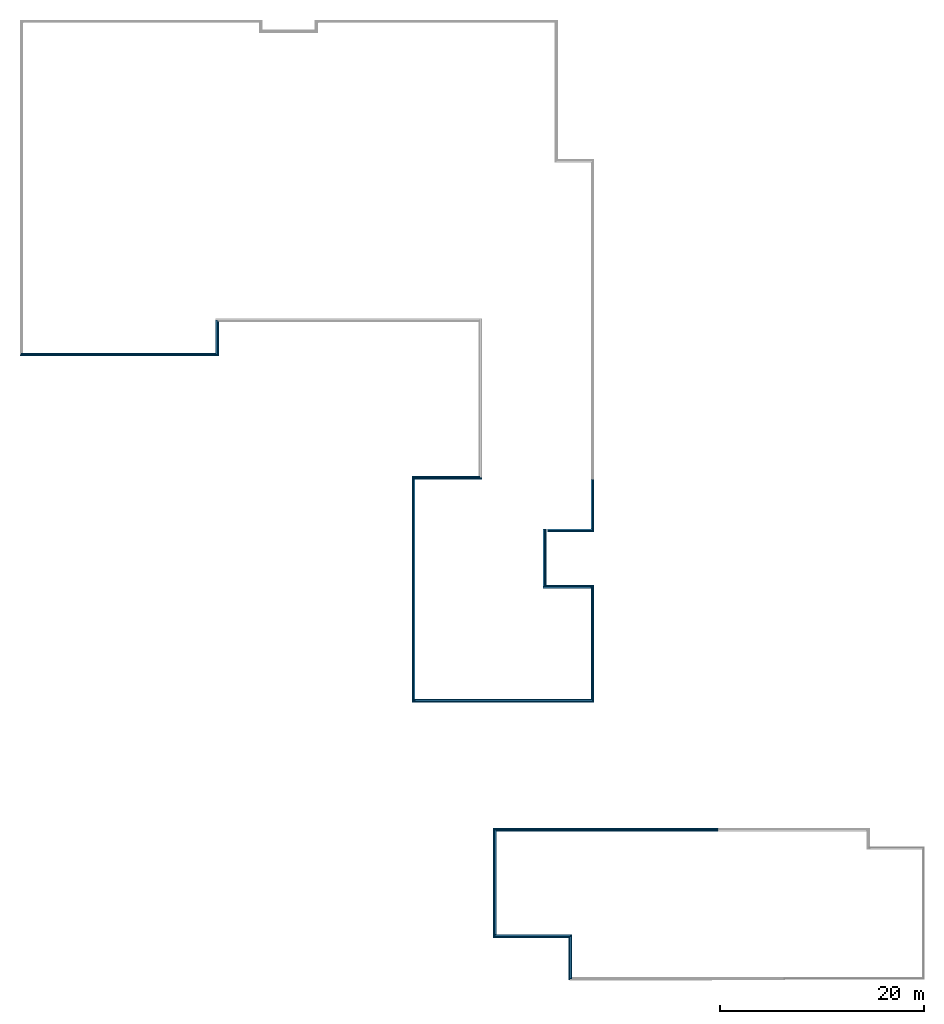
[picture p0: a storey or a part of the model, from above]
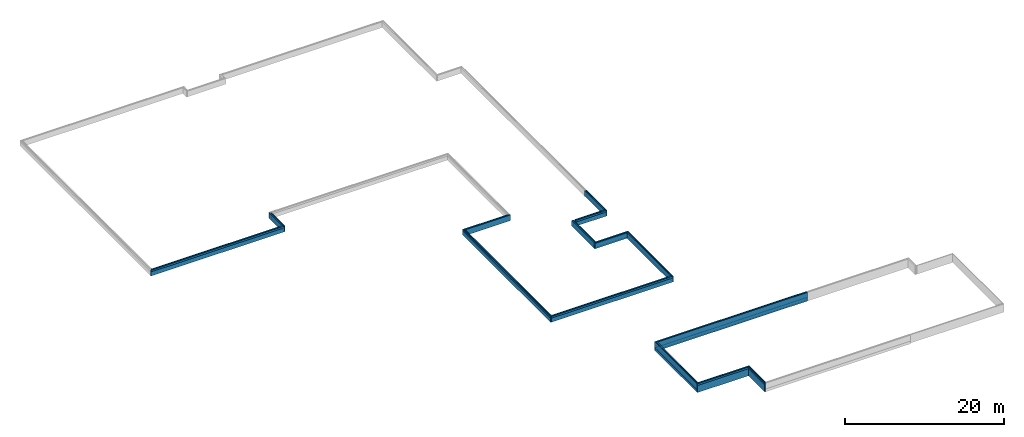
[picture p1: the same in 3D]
Properties of the parts of a building model (IFC2X3), part 1 of 19

# File
Description: ViewDefinition [1, SurfaceGeometryAddOnView, QuantityTakeOffAddOnView, SpaceBoundary2ndLevelAddOnView], Option [Elements to export: Visible elements (on all stories)], Option [Partial Structure Display: Entire Model], Option [IFC Domain: All], Option [Structural Function: All Elements], Option [Convert Grid elements: On], Option [Convert IFC Annotations and ARCHICAD 2D elements: Off], Option [Convert 2D symbols of Doors and Windows: Off], Option [Export geometries that Participates in Collision Detection only: On], Option [Split complex elements: Off], Option [Material Preservation: Explode all], Option [IFC Model position: Survey Point and Project Origin], Option [Curtain Wall export mode: Container Element], Option [Railing export mode: Container Element], Option [Stair export mode: Container Element], Option [Properties To Export: All properties], Option [Space containment: On], Option [IFC Domain For Space Containment: Custom], Option [Bounding Box: On], Option [Geometry to type objects: On], Option [Element Properties: Off], Option [Building Material Properties: On], Option [Element Parameters: Off], Option [Component Parameters: IFC Component Quantities Only], Option [IFC Base Quantities: On], Option [Door Window Parameters: On], Option [IFC Space boundaries: On], Option [ARCHICAD Zone Categories as IFC Space classification data: Off], Option [Element Classifications: On]
File name: N:\1569 unilocatie Grevenbicht Obbicht\Fases\06 Technisch Ontwerp\TO 240202\1569_IFC Bouwkunde coordinatiemodel.ifc
Time: 2024-02-02T13:21:15
Author: Architect
Organization: Naam bureau
Written by: The EXPRESS Data Manager Version 5.02.0100.09 : 26 Sep 2013
Made in: IFC file generated by GRAPHISOFT ARCHICAD 25.0.0 NED FULL Windows version (IFC add-on version: 7000 NED FULL).
Authorization: The authorising person

# IfcProject, Unilocatie Grevenbicht Obbicht
Phase: Technisch Ontwerp

# IfcSite, Site
RefLatitude: 51, 27, 0, 0; RefLongitude: 5, 29, 0, 0; RefElevation: 0 mm
BaseQuantities - GrossPerimeter: 0 mm; GrossArea: 0 m2

# IfcBuilding, Naam gebouw
BaseQuantities - GrossFloorArea: 2364.04 m2

# IfcBuildingStorey (4)
In: Naam gebouw
Name | Elevation (mm) | NetHeight (mm) = GrossHeight (mm) = Height (mm) | GrossFloorArea (m2)
Fundering | -1540 | 1540 | 0
Begane grond | 0 | 3950 | 2364.04 | LongName: Level 1
1e verdieping | 3950 | 1450 | 0
Dak | 5400 | 3750 | 0

# IfcSpace: FSA kleur 216 copy, GYM
In: Begane grond
LongName: gymzaal/ sportzaal (21x12m); InteriorOrExteriorSpace: INTERNAL
Pset_SpaceOccupancyRequirements - OccupancyNumber: 0
AC_Pset_RenovationAndPhasing - Renovation Status: Existing
BaseQuantities - Height: 10 mm; FinishCeilingHeight: 10 mm; FinishFloorHeight: 0 mm; ClearHeight: 10 mm; GrossFloorArea: 253.322 m2; NetFloorArea: 0 m2; SpaceNetFloorAreaBOMA: 0 m2; SpaceUsableFloorAreaBOMA: 0 m2; GrossCeilingArea: 253.322 m2; NetCeilingArea: 0 m2; GrossWallArea: 0.0938901 m2; NetWallArea: 0.0938901 m2; GrossPerimeter: 66160 mm; NetPerimeter: 66160 mm; GrossVolume: 2.53322 m3; NetVolume: 2.53322 m3

# IfcSpace: FSA kleur 216 copy 1 (4)
In: Begane grond
InteriorOrExteriorSpace: INTERNAL
Pset_SpaceOccupancyRequirements - OccupancyNumber: 0
AC_Pset_RenovationAndPhasing - Renovation Status: Existing
BaseQuantities - Height: 10 mm; FinishCeilingHeight: 10 mm; FinishFloorHeight: 0 mm; ClearHeight: 10 mm
Name | LongName | GrossFloorArea (m2) = GrossCeilingArea (m2) | NetFloorArea (m2) = SpaceNetFloorAreaBOMA (m2) = SpaceUsableFloorAreaBOMA (m2) = NetCeilingArea (m2) | GrossWallArea (m2) | NetWallArea (m2) | GrossPerimeter (mm) = NetPerimeter (mm) | GrossVolume (m3) | NetVolume (m3)
GYM | Opslag | 47.7841 | 0.00532919 | 50.2079 | 0.300813 | 30078 | 0.477841 | 0.477788
GYM | docentenruimte | 7.64856 | 0 | 2.5628 | 0.10498 | 11532 | 0.0764856 | 0.0764856
GYM | werkkast | 4.57527 | 0 | 2.5404 | 0.0825796 | 9291.96 | 0.0457527 | 0.0457527
GYM | mk | 1.1448 | 0 | 0.029 | 0.029 | 4872 | 0.011448 | 0.011448

# IfcSpace: FSA kleur 216 copy 2 (4)
In: Begane grond
InteriorOrExteriorSpace: INTERNAL
Pset_SpaceOccupancyRequirements - OccupancyNumber: 0
AC_Pset_RenovationAndPhasing - Renovation Status: Existing
BaseQuantities - Height: 10 mm; FinishCeilingHeight: 10 mm; FinishFloorHeight: 0 mm; ClearHeight: 10 mm
Name | LongName | GrossFloorArea (m2) = GrossCeilingArea (m2) | NetFloorArea (m2) = SpaceNetFloorAreaBOMA (m2) = SpaceUsableFloorAreaBOMA (m2) = NetCeilingArea (m2) | GrossWallArea (m2) | NetWallArea (m2) | GrossPerimeter (mm) = NetPerimeter (mm) | GrossVolume (m3) = NetVolume (m3)
GYM | wasruimte2 | 9.98851 | -1.06581e-14 | 3.3672 | 0.1203 | 14840 | 0.0998851
GYM | wasruimte1 | 9.98849 | -1.42109e-14 | 3.3672 | 0.1203 | 14840 | 0.0998849
GYM | kleedruimte1 | 27.94 | 3.55271e-15 | 7.1211 | 0.21078 | 24892 | 0.2794
GYM | kleedruimte2 | 27.9399 | 3.55271e-15 | 7.20206 | 0.291739 | 24892 | 0.279399

# IfcSpace: FSA kleur 240 copy (6)
In: Begane grond
InteriorOrExteriorSpace: INTERNAL
Pset_SpaceOccupancyRequirements - OccupancyNumber: 0
AC_Pset_RenovationAndPhasing - Renovation Status: Existing
BaseQuantities - Height: 10 mm; FinishCeilingHeight: 10 mm; FinishFloorHeight: 0 mm; ClearHeight: 10 mm
Name | LongName | GrossFloorArea (m2) = GrossCeilingArea (m2) | NetFloorArea (m2) = SpaceNetFloorAreaBOMA (m2) = SpaceUsableFloorAreaBOMA (m2) = NetCeilingArea (m2) | GrossWallArea (m2) | NetWallArea (m2) | GrossPerimeter (mm) = NetPerimeter (mm) | GrossVolume (m3) | NetVolume (m3)
BS | leerplein BB | 66.1092 | 1.37257e-07 | 25.3214 | 0.0347693 | 32793.9 | 0.661092 | 0.660986
BS | gr BB | 53.5495 | 7.10543e-15 | 46.1286 | 0.19932 | 29292 | 0.535495 | 0.535495
BS | gr BB / muzieklokaal | 52.1743 | 7.10543e-15 | 28.741 | 0.347427 | 28899.8 | 0.521743 | 0.521743
BS | berg. BB | 6.2334 | -2.66454e-15 | 2.55044 | 0.0926188 | 10295.9 | 0.062334 | 0.062334
BS | leerplein MB | 76.22 | 0 | 25.321 | 0.0344 | 34980 | 0.7622 | 0.762094
BS | gr BB | 54.112 | 0 | 51.0256 | 0.263 | 29440 | 0.54112 | 0.540933

# IfcSpace: FSA kleur 240 copy 3 (10)
In: Begane grond
InteriorOrExteriorSpace: INTERNAL
Pset_SpaceOccupancyRequirements - OccupancyNumber: 0
AC_Pset_RenovationAndPhasing - Renovation Status: Existing
BaseQuantities - Height: 10 mm; FinishCeilingHeight: 10 mm; FinishFloorHeight: 0 mm; ClearHeight: 10 mm
Name | LongName | GrossFloorArea (m2) = GrossCeilingArea (m2) | NetFloorArea (m2) = SpaceNetFloorAreaBOMA (m2) = SpaceUsableFloorAreaBOMA (m2) = NetCeilingArea (m2) | GrossWallArea (m2) | NetWallArea (m2) | GrossPerimeter (mm) = NetPerimeter (mm) | GrossVolume (m3) = NetVolume (m3)
KDV | KDV 0-4 j. | 62.8232 | -2.13163e-14 | 56.2146 | 0.312392 | 36013.9 | 0.628232
KDV | slpk. | 7.27601 | 7.27601 | 4.92543 | 0.106758 | 11659.8 | 0.0727601
KDV | slpk. | 7.26189 | 7.26189 | 2.46367 | 0.124702 | 11644.2 | 0.0726189
 | HOOFDENTREE | 9.46504 | 9.46504 | 11.4443 | 0.0218597 | 12572 | 0.0946504
GYM | entree sport | 23.552 | 0 | 27.3994 | 0.16091 | 27552 | 0.23552
BS | entree MB/BB | 8.88207 | 8.88207 | 5.89024 | 0.1195 | 12264.1 | 0.0888207
POV | gr. POV | 56.192 | 56.192 | 37.1537 | 0.321879 | 30084 | 0.56192
 | gard. KDV POV | 12.2037 | 12.2037 | 20.0998 | 0.105275 | 16203.7 | 0.122037
BS | entree natuurtuin | 5.90002 | 5.90002 | 11.5719 | 0.0611998 | 9720.01 | 0.0590002
KDV/POV | entree KDV/POV | 7.81956 | 7.81956 | 11.2726 | 0.0781996 | 11819.8 | 0.0781956

# IfcSpace: FSA kleur 240 copy 4 (2)
In: Begane grond
InteriorOrExteriorSpace: INTERNAL
Pset_SpaceOccupancyRequirements - OccupancyNumber: 0
AC_Pset_RenovationAndPhasing - Renovation Status: Existing
BaseQuantities - Height: 10 mm; FinishCeilingHeight: 10 mm; FinishFloorHeight: 0 mm; ClearHeight: 10 mm; NetFloorArea: 0 m2; SpaceNetFloorAreaBOMA: 0 m2; SpaceUsableFloorAreaBOMA: 0 m2; NetCeilingArea: 0 m2
Name | LongName | GrossFloorArea (m2) = GrossCeilingArea (m2) | GrossWallArea (m2) | NetWallArea (m2) | GrossPerimeter (mm) = NetPerimeter (mm) | GrossVolume (m3) = NetVolume (m3)
KDV/ POV | san. 0-4 j. POV | 9.64662 | 5.15866 | 0.24302 | 14240 | 0.0964662
KDV/ POV | Keuken | 6.68697 | 3.17908 | 0.0468596 | 11343.5 | 0.0668697

# IfcSpace: FSA kleur 240 copy copy 1 (8)
In: Begane grond
InteriorOrExteriorSpace: INTERNAL
Pset_SpaceOccupancyRequirements - OccupancyNumber: 0
AC_Pset_RenovationAndPhasing - Renovation Status: Existing
BaseQuantities - Height: 10 mm; FinishCeilingHeight: 10 mm; FinishFloorHeight: 0 mm; ClearHeight: 10 mm
Name | LongName | GrossFloorArea (m2) = GrossCeilingArea (m2) | NetFloorArea (m2) = SpaceNetFloorAreaBOMA (m2) = SpaceUsableFloorAreaBOMA (m2) = NetCeilingArea (m2) | GrossWallArea (m2) | NetWallArea (m2) | GrossPerimeter (mm) = NetPerimeter (mm) | GrossVolume (m3) | NetVolume (m3)
BS | gr MB | 54.3399 | 0 | 34.529 | 0.326739 | 29500 | 0.543399 | 0.543211
BS | gr MB | 53.8677 | 0 | 39.7121 | 0.24157 | 29374 | 0.538677 | 0.538677
BS | gr MB | 53.676 | 0 | 46.8443 | 0.21076 | 29320 | 0.53676 | 0.53676
BS | berg MB | 6.02453 | 3.55271e-15 | 2.54652 | 0.0917529 | 10208 | 0.0602453 | 0.0602453
BS | san .MB | 4.8796 | 1.77636e-15 | 9.84183 | 0.07236 | 11072 | 0.048796 | 0.048796
BS | san .OB | 9.40794 | 0 | 2.61349 | 0.15567 | 12320 | 0.0940794 | 0.0940794
BS | gr MB | 52.9304 | 0 | 50.7949 | 0.25835 | 29110 | 0.529304 | 0.529117
BS | san .BB | 3.64595 | 1.77636e-15 | 7.46385 | 0.090395 | 8829 | 0.0364595 | 0.0364595

# IfcSpace: FSA kleur 240 copy copy copy 1 (5)
In: Begane grond
InteriorOrExteriorSpace: INTERNAL
Pset_SpaceOccupancyRequirements - OccupancyNumber: 0
AC_Pset_RenovationAndPhasing - Renovation Status: Existing
BaseQuantities - Height: 10 mm; FinishCeilingHeight: 10 mm; FinishFloorHeight: 0 mm; ClearHeight: 10 mm
Name | LongName | GrossFloorArea (m2) = GrossCeilingArea (m2) | NetFloorArea (m2) = SpaceNetFloorAreaBOMA (m2) = SpaceUsableFloorAreaBOMA (m2) = NetCeilingArea (m2) | GrossWallArea (m2) | NetWallArea (m2) | GrossPerimeter (mm) = NetPerimeter (mm) | GrossVolume (m3) | NetVolume (m3)
BS | gr. OB | 53.676 | 1.42109e-14 | 46.8443 | 0.21076 | 29320 | 0.53676 | 0.53676
BS | leerplein OB | 59.6838 | 0 | 20.4697 | 0.14421 | 35657.7 | 0.596838 | 0.596838
KC | speellokaal | 82.4028 | 82.4028 | 46.829 | 0.23935 | 36352.7 | 0.824028 | 0.824028
BS | gr. OB | 53.7255 | 0.015 | 39.6021 | 0.159009 | 29333.9 | 0.537255 | 0.537105
BS | gr. OB | 54.0099 | 0.0213435 | 17.4038 | 0.16267 | 29414.1 | 0.540099 | 0.539912

# IfcSpace: FSA kleur 240 copy copy copy 2 (2)
In: Begane grond
InteriorOrExteriorSpace: INTERNAL
Pset_SpaceOccupancyRequirements - OccupancyNumber: 0
AC_Pset_RenovationAndPhasing - Renovation Status: Existing
BaseQuantities - Height: 10 mm; FinishCeilingHeight: 10 mm; FinishFloorHeight: 0 mm; ClearHeight: 10 mm
Name | LongName | GrossFloorArea (m2) = GrossCeilingArea (m2) | NetFloorArea (m2) = SpaceNetFloorAreaBOMA (m2) = SpaceUsableFloorAreaBOMA (m2) = NetCeilingArea (m2) | GrossWallArea (m2) | NetWallArea (m2) | GrossPerimeter (mm) = NetPerimeter (mm) | GrossVolume (m3) = NetVolume (m3)
BS | berg OB | 7.08185 | -8.88178e-16 | 0.0754999 | 0.0754999 | 11030 | 0.0708185
KC | berg. speellokaal | 6.44126 | 0 | 4.36741 | 0.0888086 | 10680.9 | 0.0644126

# IfcSpace: FSA kleur 241 1 (9)
In: Begane grond
InteriorOrExteriorSpace: INTERNAL
Pset_SpaceOccupancyRequirements - OccupancyNumber: 0
AC_Pset_RenovationAndPhasing - Renovation Status: Existing
BaseQuantities - Height: 10 mm; FinishCeilingHeight: 10 mm; FinishFloorHeight: 0 mm; ClearHeight: 10 mm
Name | LongName | GrossFloorArea (m2) = GrossCeilingArea (m2) | NetFloorArea (m2) = SpaceNetFloorAreaBOMA (m2) = SpaceUsableFloorAreaBOMA (m2) = NetCeilingArea (m2) | GrossWallArea (m2) | NetWallArea (m2) | GrossPerimeter (mm) = NetPerimeter (mm) | GrossVolume (m3) | NetVolume (m3)
BSO | bu. berg. BSO | 6.00501 | 6.00501 | 1.40073 | 0.0599914 | 10744.3 | 0.0600501 | 0.0599566
KC | gard. BB | 16.7919 | 0.019375 | 18.7048 | 0.0857401 | 18208.1 | 0.167919 | 0.167775
KC | werkkast | 5.99267 | -8.88178e-16 | 4.36168 | 0.0830807 | 10108.1 | 0.0599267 | 0.0599267
BS | berg alg./ kluis | 12.6841 | 1.35146e-08 | 2.55033 | 0.0925132 | 14389.4 | 0.126841 | 0.126841
BSO | berg. BSO | 12.7812 | 3.55271e-15 | 4.36393 | 0.0853263 | 14436.7 | 0.127812 | 0.127812
BS | bu. berg. OW | 11.352 | 11.352 | 4.91699 | 0.0647348 | 14308 | 0.11352 | 0.11352
KC | gard. OB | 11.266 | -1.77636e-15 | 19.9232 | 0.0700697 | 13840 | 0.11266 | 0.11266
POV | berg. POV KDV | 13.6076 | 13.6076 | 2.64332 | 0.185498 | 16083.7 | 0.136076 | 0.136076
KC | gard. MB | 16.6869 | 0 | 9.31184 | 0.124681 | 17978.1 | 0.166869 | 0.166869

# IfcSpace: FSA kleur 241 2 (7)
In: Begane grond
InteriorOrExteriorSpace: INTERNAL
Pset_SpaceOccupancyRequirements - OccupancyNumber: 0
AC_Pset_RenovationAndPhasing - Renovation Status: Existing
BaseQuantities - Height: 10 mm; FinishCeilingHeight: 10 mm; FinishFloorHeight: 0 mm; ClearHeight: 10 mm
Name | LongName | GrossFloorArea (m2) = GrossCeilingArea (m2) | NetFloorArea (m2) = SpaceNetFloorAreaBOMA (m2) = SpaceUsableFloorAreaBOMA (m2) = NetCeilingArea (m2) | GrossWallArea (m2) | NetWallArea (m2) | GrossPerimeter (mm) = NetPerimeter (mm) | GrossVolume (m3) = NetVolume (m3)
KC | keuken | 26.1607 | 26.1607 | 9.40792 | 0.0479151 | 20940.7 | 0.261607
KC | toilet pers. | 13.3664 | 0 | 7.49121 | 0.117761 | 14678.1 | 0.133664
KC | wasruimte | 5.41291 | 0 | 2.56182 | 0.104001 | 9680.03 | 0.0541291
KC | MIVA /douche | 4.9952 | -3.40931e-08 | 2.53688 | 0.07906 | 8940 | 0.049952
KC | techniek | 19.7063 | 0.251596 | 11.8197 | 0.271949 | 17760 | 0.197063
KC | techniek | 3.49895 | 4.44089e-16 | 2.52346 | 0.0656407 | 7598.07 | 0.0349895
KC | toilet pers.KDV | 9.04179 | 0 | 5.04732 | 0.131688 | 12031.9 | 0.0904179

# IfcSpace: FSA kleur 241 4 (8)
In: Begane grond
InteriorOrExteriorSpace: INTERNAL
Pset_SpaceOccupancyRequirements - OccupancyNumber: 0
AC_Pset_RenovationAndPhasing - Renovation Status: Existing
BaseQuantities - Height: 10 mm; FinishCeilingHeight: 10 mm; FinishFloorHeight: 0 mm; ClearHeight: 10 mm
Name | LongName | GrossFloorArea (m2) = GrossCeilingArea (m2) | NetFloorArea (m2) = SpaceNetFloorAreaBOMA (m2) = SpaceUsableFloorAreaBOMA (m2) = NetCeilingArea (m2) | GrossWallArea (m2) | NetWallArea (m2) | GrossPerimeter (mm) = NetPerimeter (mm) | GrossVolume (m3) | NetVolume (m3)
BS | admin. /conc. | 17.326 | 17.381 | 4.28157 | 0.13092 | 18140.7 | 0.17326 | 0.173041
KC | teamkamer flex / BSO-ruimte | 34.7074 | 34.7074 | 14.817 | 0 | 24381.7 | 0.347074 | 0.347074
BS | Cova ruimte | 13.1208 | 13.1208 | 6.77545 | 0.166981 | 14628.1 | 0.131208 | 0.131208
BS | flexwp/ spreekr. | 12.76 | 12.76 | 14.544 | 0.1588 | 14600 | 0.1276 | 0.1276
BS | flexwp/ spreekr. | 12.4705 | 3.55271e-15 | 14.7753 | 0.113263 | 14244.2 | 0.124705 | 0.124705
BS | flexwp/ spreekr. | 14.3519 | 0 | 10.5277 | 0.11558 | 15568 | 0.143519 | 0.143519
BS | Directie IB | 17.4156 | 0 | 9.42975 | 0.19232 | 16772 | 0.174156 | 0.174156
KC | teamkamer vast | 31.2026 | -3.55271e-15 | 9.50511 | 0.26768 | 24072.4 | 0.312026 | 0.312026

# IfcSpace: FSA kleur 246 copy (10)
In: Begane grond
InteriorOrExteriorSpace: INTERNAL
Pset_SpaceOccupancyRequirements - OccupancyNumber: 0
AC_Pset_RenovationAndPhasing - Renovation Status: Existing
BaseQuantities - Height: 10 mm; FinishCeilingHeight: 10 mm; FinishFloorHeight: 0 mm; ClearHeight: 10 mm
Name | LongName | GrossFloorArea (m2) = GrossCeilingArea (m2) | NetFloorArea (m2) = SpaceNetFloorAreaBOMA (m2) = SpaceUsableFloorAreaBOMA (m2) = NetCeilingArea (m2) | GrossWallArea (m2) | NetWallArea (m2) | GrossPerimeter (mm) = NetPerimeter (mm) | GrossVolume (m3) | NetVolume (m3)
SPORT | d. 4x. | 4.64063 | 0 | 0.09675 | 0.09675 | 8700 | 0.0464063 | 0.0464063
SPORT | kleedr. groot 1 | 27.6754 | -3.55271e-15 | 12.713 | 0.207997 | 21700.2 | 0.276754 | 0.276754
SPORT | d. 5x. | 8.21264 | 0 | 7.66509 | 0.131598 | 11589.9 | 0.0821264 | 0.0821264
SPORT | d. 5x. | 8.21274 | 0 | 0.0821996 | 0.0821996 | 11590 | 0.0821274 | 0.0821274
SPORT | opslag voetbal+ballenhok | 32.385 | 0 | 1.58579 | 0.0509817 | 22900 | 0.32385 | 0.32385
SPORT | kleedr. klein 1 | 19.695 | 0.0074095 | 2.69714 | 0.23932 | 17900 | 0.19695 | 0.196856
SPORT | d. 4x. | 4.64063 | 0 | 0.078 | 0.078 | 8700 | 0.0464063 | 0.0464063
SPORT | kleedr. klein 2 | 19.695 | 0 | 2.70698 | 0.24916 | 17900 | 0.19695 | 0.19695
SPORT | kleedr. groot 2 | 27.675 | -3.55271e-15 | 15.2321 | 0.26932 | 21700 | 0.27675 | 0.27675
SPORT | gangzone | 51.1795 | 0 | 18.4763 | 0.129363 | 57490 | 0.511795 | 0.511795

# IfcSpace: FSA kleur 246 copy 1 (3)
In: Begane grond
InteriorOrExteriorSpace: INTERNAL
Pset_SpaceOccupancyRequirements - OccupancyNumber: 0
AC_Pset_RenovationAndPhasing - Renovation Status: Existing
BaseQuantities - Height: 10 mm; FinishCeilingHeight: 10 mm; FinishFloorHeight: 0 mm; ClearHeight: 10 mm; NetFloorArea: 0 m2; SpaceNetFloorAreaBOMA: 0 m2; SpaceUsableFloorAreaBOMA: 0 m2; NetCeilingArea: 0 m2
Name | LongName | GrossFloorArea (m2) = GrossCeilingArea (m2) | GrossWallArea (m2) = NetWallArea (m2) | GrossPerimeter (mm) = NetPerimeter (mm) | GrossVolume (m3) = NetVolume (m3)
SPORT | kleedr. Tennis | 12.9677 | 0.078 | 14450.1 | 0.129677
SPORT | opslag tennis- | 17.63 | 0.0839985 | 16800 | 0.1763
SPORT | kleedr. Tennis | 12.9675 | 0.001 | 14450 | 0.129675

# IfcSpace: FSA kleur 246 copy 2 (8)
In: Begane grond
InteriorOrExteriorSpace: INTERNAL
Pset_SpaceOccupancyRequirements - OccupancyNumber: 0
AC_Pset_RenovationAndPhasing - Renovation Status: Existing
BaseQuantities - Height: 10 mm; FinishCeilingHeight: 10 mm; FinishFloorHeight: 0 mm; ClearHeight: 10 mm
Name | LongName | GrossFloorArea (m2) = GrossCeilingArea (m2) | NetFloorArea (m2) = SpaceNetFloorAreaBOMA (m2) = SpaceUsableFloorAreaBOMA (m2) = NetCeilingArea (m2) | GrossWallArea (m2) | NetWallArea (m2) | GrossPerimeter (mm) = NetPerimeter (mm) | GrossVolume (m3) | NetVolume (m3)
SPORT | t. | 1.99675 | 0 | 2.38698 | 0.0480099 | 5709.99 | 0.0199675 | 0.0199675
SPORT | t. | 1.99675 | 0.00851728 | 2.37068 | 0.03171 | 5709.99 | 0.0199675 | 0.019874
SPORT | massage /EHBO ruimte | 16.2684 | 0 | 2.48038 | 0.0225594 | 16579.7 | 0.162684 | 0.162684
KANT | san. heren | 4.845 | -4.44089e-15 | 0.071 | 0.071 | 8900.01 | 0.04845 | 0.04845
SPORT | wasruimte | 8.15977 | 0 | 4.97886 | 0.0989986 | 13399.9 | 0.0815977 | 0.0815977
SPORT | klr. scheids | 11.0672 | -2.66454e-14 | 0.0519995 | 0.0519995 | 14540.1 | 0.110672 | 0.110672
KANT | san. Dames | 4.845 | -1.42109e-14 | 0.071 | 0.071 | 8900 | 0.04845 | 0.04845
SPORT | klr. scheids | 11.067 | -1.95399e-14 | 0.101999 | 0.101999 | 14540 | 0.11067 | 0.11067

# IfcSpace: FSA kleur 248 copy (2)
In: Begane grond
InteriorOrExteriorSpace: INTERNAL
Pset_SpaceOccupancyRequirements - OccupancyNumber: 0
AC_Pset_RenovationAndPhasing - Renovation Status: Existing
BaseQuantities - Height: 10 mm; FinishCeilingHeight: 10 mm; FinishFloorHeight: 0 mm; ClearHeight: 10 mm
Name | LongName | GrossFloorArea (m2) = GrossCeilingArea (m2) | NetFloorArea (m2) = SpaceNetFloorAreaBOMA (m2) = SpaceUsableFloorAreaBOMA (m2) = NetCeilingArea (m2) | GrossWallArea (m2) | NetWallArea (m2) | GrossPerimeter (mm) = NetPerimeter (mm) | GrossVolume (m3) | NetVolume (m3)
KANT | kantine + bar 10m | 124.373 | 0.01434 | 6.23838 | 0.0534995 | 54300 | 1.24373 | 1.24357
SPORT | entree tennis | 11.8125 | 0 | 12.3806 | 0.0154795 | 17000 | 0.118125 | 0.118125

# IfcSpace: FSA kleur 248 copy 1 (4)
In: Begane grond
InteriorOrExteriorSpace: INTERNAL
Pset_SpaceOccupancyRequirements - OccupancyNumber: 0
AC_Pset_RenovationAndPhasing - Renovation Status: Existing
BaseQuantities - Height: 10 mm; FinishCeilingHeight: 10 mm; FinishFloorHeight: 0 mm; ClearHeight: 10 mm
Name | LongName | GrossFloorArea (m2) = GrossCeilingArea (m2) | NetFloorArea (m2) = SpaceNetFloorAreaBOMA (m2) = SpaceUsableFloorAreaBOMA (m2) = NetCeilingArea (m2) | GrossWallArea (m2) | NetWallArea (m2) | GrossPerimeter (mm) = NetPerimeter (mm) | GrossVolume (m3) = NetVolume (m3)
KANT | mag./ k + v | 9.49004 | 0 | 8.37748 | 0.10066 | 12500 | 0.0949004
KANT | werkkast | 4.68307 | -5.32907e-15 | 2.51308 | 0.0552589 | 8660.07 | 0.0468307
KANT | techniek | 13.5028 | 1.59872e-14 | 2.63501 | 0.177188 | 15459.9 | 0.135028
KANT | keuken | 14.7823 | 0 | 2.52448 | 0.0666593 | 15399.9 | 0.147823

# IfcSpace: FSA kleur 248 copy 2 (3)
In: Begane grond
InteriorOrExteriorSpace: INTERNAL
Pset_SpaceOccupancyRequirements - OccupancyNumber: 0
AC_Pset_RenovationAndPhasing - Renovation Status: Existing
BaseQuantities - Height: 10 mm; FinishCeilingHeight: 10 mm; FinishFloorHeight: 0 mm; ClearHeight: 10 mm
Name | LongName | GrossFloorArea (m2) = GrossCeilingArea (m2) | NetFloorArea (m2) = SpaceNetFloorAreaBOMA (m2) = SpaceUsableFloorAreaBOMA (m2) = NetCeilingArea (m2) | GrossWallArea (m2) | NetWallArea (m2) | GrossPerimeter (mm) = NetPerimeter (mm) | GrossVolume (m3) = NetVolume (m3)
KANT | MIVA | 5.35914 | 0 | 2.55274 | 0.094921 | 9260.12 | 0.0535914
SPORT | san.alg. | 12.24 | 0 | 7.473 | 0.153 | 15000 | 0.1224
SPORT | san.alg. | 11.0571 | 1.95399e-14 | 6.70885 | 0.0963606 | 14536.2 | 0.110571

# IfcBeam: 1000*250 (3)
In: Begane grond
Description: 1000*250; Classification: Balk (ARCHICAD Classification); Material: CONCRETE/C30/37
Default - Stortmethode: Insitu; NL-SfB_DESCRIPTION: Balkenfundering insitu; NL-SfB_NUMBERCODE: 16.12.41; IS_EXTERNAL: Nee; LOAD_BEARING: Ondersteuning; FIRE_RATING: R0; IFC_CLASS_REF_CODE: 16.12.41 ; Balkenfundering insitu; IFC_BUILDING_STOREY: Undefined; IFC_BUILDING: Undefined; MATERIAL: C30/37; NAME: FUNDERINGSBALK
Tekla Common - Phase: 1; Class: 3
Tekla Quantity - Weight: 600 kg; Volume: 0.25 m3; Gross footprint area: 1 m2; Area per tons: 5 m2; Net surface area: 3 m2; Height: 250 mm; Width: 1000 mm; Length: 1000 mm
Pset_BeamCommon - FireRating: R0; Reference: B0(?); Slope: 0 deg; LoadBearing: yes; IsExternal: no
CPset_Phasing - Renovation Phase: Bestaand
AC_Pset_RenovationAndPhasing - Renovation Status: Existing
Material Properties - CONCRETE/C30/37, ThermalConductivity: 2.3; CONCRETE/C30/37, SpecificHeatCapacity: 1000 J/kg/K; CONCRETE/C30/37, MassDensity: 2300 kg/m3; CONCRETE/C30/37, Embodied Energy: 1.92 (MJ/kg); CONCRETE/C30/37, Embodied Carbon: 0.198 (kgCO₂/kg); CONCRETE/C30/37, Name: CONCRETE/C30/37; CONCRETE/C30/37, Participates in Collision Detection: yes
BaseQuantities - NetSurfaceAreaExtrudedSides: 2.5 m2; Length: 1000 mm; Width: 1000 mm; Depth: 250 mm; CrossSectionArea: 0.25 m2; OuterSurfaceArea: 2.5 m2; TotalSurfaceArea: 3 m2; GrossSurfaceArea: 3 m2; GrossVolume: 0.25 m3; NetSurfaceArea: 3 m2; NetVolume: 0.25 m3
Component Quantities - CONCRETE/C30/37, Mass: 575 kg; CONCRETE/C30/37, Projected Component Area (Net): 0.25 m2; CONCRETE/C30/37, Projected Component Area (Gross): 0.25 m2; CONCRETE/C30/37, Component Thickness: 1000 mm; CONCRETE/C30/37, Rectangular Component Height: 250 mm; CONCRETE/C30/37, Rectangular Component Width: 1000 mm; CONCRETE/C30/37, Component Cross Section Area: 0.25 m2; CONCRETE/C30/37, Component Volume (Net): 0.25 m3; CONCRETE/C30/37, Component Volume (Gross): 0.25 m3
Name | Bottom elevation | Top elevation
2 x FUNDERINGSBALK | -0.900 | -0.650
FUNDERINGSBALK | -0.990 | -0.740

# IfcBeam: 1000*500 (3)
In: Begane grond
Description: 1000*500; Classification: Balk (ARCHICAD Classification); Material: CONCRETE/C30/37
Default - Stortmethode: Insitu; NL-SfB_DESCRIPTION: Balkenfundering insitu; NL-SfB_NUMBERCODE: 16.12.41; IS_EXTERNAL: Nee; LOAD_BEARING: Ondersteuning; FIRE_RATING: R0; IFC_CLASS_REF_CODE: 16.12.41 ; Balkenfundering insitu; IFC_BUILDING_STOREY: Undefined; IFC_BUILDING: Undefined; MATERIAL: C30/37; NAME: FUNDERINGSBALK
Pset_BeamCommon - FireRating: R0; Reference: B0(?); Slope: 0 deg; LoadBearing: yes; IsExternal: no
Tekla Common - Bottom elevation: -0.900; Top elevation: -0.400; Phase: 1; Class: 3
Tekla Quantity - Weight: 2400 kg; Volume: 1 m3; Gross footprint area: 2 m2; Area per tons: 2.917 m2; Net surface area: 7 m2; Height: 500 mm; Width: 1000 mm; Length: 2000 mm
CPset_Phasing - Renovation Phase: Bestaand
AC_Pset_RenovationAndPhasing - Renovation Status: Existing
Material Properties - CONCRETE/C30/37, ThermalConductivity: 2.3; CONCRETE/C30/37, SpecificHeatCapacity: 1000 J/kg/K; CONCRETE/C30/37, MassDensity: 2300 kg/m3; CONCRETE/C30/37, Embodied Energy: 1.92 (MJ/kg); CONCRETE/C30/37, Embodied Carbon: 0.198 (kgCO₂/kg); CONCRETE/C30/37, Name: CONCRETE/C30/37; CONCRETE/C30/37, Participates in Collision Detection: yes
BaseQuantities - NetSurfaceAreaExtrudedSides: 6 m2; Length: 2000 mm; Width: 1000 mm; Depth: 500 mm; CrossSectionArea: 0.5 m2; OuterSurfaceArea: 6 m2; TotalSurfaceArea: 7 m2; GrossSurfaceArea: 7 m2; GrossVolume: 1 m3; NetSurfaceArea: 7 m2; NetVolume: 1 m3
Component Quantities - CONCRETE/C30/37, Mass: 2300 kg; CONCRETE/C30/37, Projected Component Area (Net): 1 m2; CONCRETE/C30/37, Projected Component Area (Gross): 1 m2; CONCRETE/C30/37, Component Thickness: 1000 mm; CONCRETE/C30/37, Rectangular Component Height: 500 mm; CONCRETE/C30/37, Rectangular Component Width: 1000 mm; CONCRETE/C30/37, Component Cross Section Area: 0.5 m2; CONCRETE/C30/37, Component Volume (Net): 1 m3; CONCRETE/C30/37, Component Volume (Gross): 1 m3

# IfcBeam: 1200*160 (3)
In: Begane grond
Description: 1200*160; Classification: Balk (ARCHICAD Classification); Material: TIMBER/C24
Pset_BeamCommon - FireRating: R30; Reference: LIH0(?); Slope: 0 deg; LoadBearing: yes; IsExternal: no
Default - NL-SfB_DESCRIPTION: Kolom-/Liggerconstructie hout; NL-SfB_NUMBERCODE: 28.11.11; IS_EXTERNAL: Nee; LOAD_BEARING: Ondersteuning; FIRE_RATING: R30; IFC_CLASS_REF_CODE: 28.11.11 ; Kolom-/Liggerconstructie hout; IFC_BUILDING_STOREY: Undefined; IFC_BUILDING: Undefined; MATERIAL: C24; NAME: LIGGER
Tekla Common - Bottom elevation: +5.500; Top elevation: +6.700; Phase: 1; Class: 13
Tekla Quantity - Height: 160 mm; Width: 1200 mm
CPset_Phasing - Renovation Phase: Bestaand
AC_Pset_RenovationAndPhasing - Renovation Status: Existing
Material Properties - TIMBER/C24, ThermalConductivity: 2.3; TIMBER/C24, SpecificHeatCapacity: 1000 J/kg/K; TIMBER/C24, MassDensity: 2300 kg/m3; TIMBER/C24, Embodied Energy: 1.92 (MJ/kg); TIMBER/C24, Embodied Carbon: 0.198 (kgCO₂/kg); TIMBER/C24, Name: TIMBER/C24; TIMBER/C24, Participates in Collision Detection: yes
BaseQuantities - Width: 160 mm; Depth: 1200 mm; CrossSectionArea: 0.192 m2
Component Quantities - TIMBER/C24, Component Thickness: 160 mm; TIMBER/C24, Rectangular Component Height: 1200 mm; TIMBER/C24, Rectangular Component Width: 160 mm; TIMBER/C24, Component Cross Section Area: 0.192 m2
Name | Weight (kg) | Volume (m3) | Gross footprint area (m2) | Area per tons (m2) | Net surface area (m2) | Tekla Quantity, Length (mm) = BaseQuantities, Length (mm) | NetSurfaceAreaExtrudedSides (m2) = OuterSurfaceArea (m2) | TotalSurfaceArea (m2) = GrossSurfaceArea (m2) = NetSurfaceArea (m2) | GrossVolume (m3) | NetVolume (m3) = TIMBER/C24, Component Volume (Net) (m3) | TIMBER/C24, Mass (kg) | TIMBER/C24, Projected Component Area (Net) (m2) = TIMBER/C24, Projected Component Area (Gross) (m2) | TIMBER/C24, Component Volume (Gross) (m3)
LIGGER | 1039.61 | 2.31 | 1.925 | 32.63 | 33.922 | 12070 | 32.8184 | 33.2024 | 2.31744 | 2.31024 | 5313.56 | 14.484 | 2.31744
LIGGER | 1044.58 | 2.321 | 1.934 | 31.849 | 33.269 | 12090 | 32.8846 | 33.2686 | 2.32128 | 2.32128 | 5338.95 | 14.508 | 2.32128
LIGGER | 1044.58 | 2.321 | 1.934 | 31.849 | 33.269 | 12090 | 32.884 | 33.268 | 2.32128 | 2.32127 | 5338.92 | 14.508 | 2.32127

# IfcBeam: 1200*300 (33)
In: Begane grond
Description: 1200*300; Classification: Balk (ARCHICAD Classification); Material: CONCRETE/C30/37
Default - Stortmethode: Insitu; NL-SfB_DESCRIPTION: Balkenfundering insitu; NL-SfB_NUMBERCODE: 16.12.41; IS_EXTERNAL: Nee; LOAD_BEARING: Nee; FIRE_RATING: R0; IFC_CLASS_REF_CODE: 16.12.41 ; Balkenfundering insitu; IFC_BUILDING_STOREY: Undefined; IFC_BUILDING: Undefined; MATERIAL: C30/37; NAME: FUNDERINGSBALK
Tekla Common - Phase: 1; Class: 3
Pset_BeamCommon - FireRating: R0; Reference: B0(?); Slope: 0 deg; LoadBearing: no; IsExternal: no
Tekla Quantity - Height: 300 mm; Width: 1200 mm
CPset_Phasing - Renovation Phase: Bestaand
AC_Pset_RenovationAndPhasing - Renovation Status: Existing
Material Properties - CONCRETE/C30/37, ThermalConductivity: 2.3; CONCRETE/C30/37, SpecificHeatCapacity: 1000 J/kg/K; CONCRETE/C30/37, MassDensity: 2300 kg/m3; CONCRETE/C30/37, Embodied Energy: 1.92 (MJ/kg); CONCRETE/C30/37, Embodied Carbon: 0.198 (kgCO₂/kg); CONCRETE/C30/37, Name: CONCRETE/C30/37; CONCRETE/C30/37, Participates in Collision Detection: yes
BaseQuantities - Width: 1200 mm; Depth: 300 mm; CrossSectionArea: 0.36 m2
Component Quantities - CONCRETE/C30/37, Component Thickness: 1200 mm; CONCRETE/C30/37, Rectangular Component Height: 300 mm; CONCRETE/C30/37, Rectangular Component Width: 1200 mm; CONCRETE/C30/37, Component Cross Section Area: 0.36 m2
Name | Bottom elevation | Top elevation | Weight (kg) | Volume (m3) | Gross footprint area (m2) | Area per tons (m2) | Net surface area (m2) | Tekla Quantity, Length (mm) | NetSurfaceAreaExtrudedSides (m2) = OuterSurfaceArea (m2) | BaseQuantities, Length (mm) | TotalSurfaceArea (m2) = GrossSurfaceArea (m2) = NetSurfaceArea (m2) | GrossVolume (m3) | NetVolume (m3) = CONCRETE/C30/37, Component Volume (Net) (m3) = CONCRETE/C30/37, Component Volume (Gross) (m3) | CONCRETE/C30/37, Mass (kg) | CONCRETE/C30/37, Projected Component Area (Net) (m2) = CONCRETE/C30/37, Projected Component Area (Gross) (m2)
FUNDERINGSBALK | -1.240 | -0.940 | 6831.64 | 2.847 | 9.488 | 3.578 | 24.441 | 7907 | 23.721 | 7906.99 | 24.441 | 2.84652 | 2.84652 | 6546.99 | 2.3721
FUNDERINGSBALK | -0.800 | -0.500 | 29548.8 | 12.312 | 41.04 | 3.497 | 103.32 | 34200 | 102.6 | 34200 | 103.32 | 12.312 | 12.312 | 28317.6 | 10.26
FUNDERINGSBALK | -0.800 | -0.500 | 31147.2 | 12.978 | 43.26 | 3.495 | 108.87 | 36050 | 108.15 | 36050 | 108.87 | 12.978 | 12.978 | 29849.4 | 10.815
FUNDERINGSBALK | -0.800 | -0.500 | 4795.22 | 1.998 | 6.66 | 3.622 | 17.37 | 5550 | 16.65 | 5550 | 17.37 | 1.998 | 1.998 | 4595.4 | 1.665
FUNDERINGSBALK | -0.800 | -0.500 | 8661.6 | 3.609 | 12.03 | 3.555 | 30.795 | 10025 | 30.075 | 10025 | 30.795 | 3.609 | 3.609 | 8300.7 | 3.0075
FUNDERINGSBALK | -1.240 | -0.940 | 8255.52 | 3.44 | 11.466 | 3.559 | 29.385 | 9555 | 27.1218 | 9555 | 27.8418 | 3.4398 | 3.26232 | 7503.34 | 2.8665
FUNDERINGSBALK | -0.800 | -0.500 | 11707.2 | 4.878 | 16.26 | 3.534 | 41.37 | 13550 | 40.65 | 13550 | 41.37 | 4.878 | 4.878 | 11219.4 | 4.065
FUNDERINGSBALK | -0.800 | -0.500 | 6393.6 | 2.664 | 8.88 | 3.585 | 22.92 | 7400 | 22.2 | 7400 | 22.92 | 2.664 | 2.664 | 6127.2 | 2.22
FUNDERINGSBALK | -1.240 | -0.940 | 20997.8 | 8.749 | 29.164 | 3.507 | 73.629 | 24303 | 72.909 | 24303 | 73.629 | 8.74908 | 8.74908 | 20122.9 | 7.2909
FUNDERINGSBALK | -1.240 | -0.940 | 10601.3 | 4.417 | 14.724 | 3.54 | 37.53 | 12270 | 36.81 | 12270 | 37.53 | 4.4172 | 4.4172 | 10159.6 | 3.681
FUNDERINGSBALK | -1.240 | -0.940 | 4104 | 1.71 | 5.7 | 3.648 | 14.97 | 4750 | 14.25 | 4750 | 14.97 | 1.71 | 1.71 | 3933 | 1.425
2 x FUNDERINGSBALK | -1.240 | -0.940 | 18377.3 | 7.657 | 25.524 | 3.511 | 64.53 | 21270 | 63.81 | 21270 | 64.53 | 7.6572 | 7.6572 | 17611.6 | 6.381
FUNDERINGSBALK | -1.240 | -0.940 | 13668.5 | 5.695 | 18.984 | 3.525 | 48.18 | 15820 | 47.46 | 15820 | 48.18 | 5.6952 | 5.6952 | 13099 | 4.746
FUNDERINGSBALK | -1.240 | -0.940 | 1848.96 | 0.77 | 2.568 | 3.862 | 7.14 | 2140 | 6.42 | 2140 | 7.14 | 0.7704 | 0.7704 | 1771.92 | 0.642
FUNDERINGSBALK | -1.240 | -0.940 | 4048.72 | 1.687 | 5.623 | 3.65 | 14.778 | 4686 | 14.058 | 4686.02 | 14.778 | 1.68697 | 1.68697 | 3880.02 | 1.4058
FUNDERINGSBALK | -1.240 | -0.940 | 5698.09 | 2.374 | 7.914 | 3.599 | 20.505 | 6595 | 17.925 | 5975 | 18.645 | 2.3742 | 2.151 | 4947.3 | 1.7925
FUNDERINGSBALK | -1.240 | -0.940 | 18821.4 | 7.842 | 26.141 | 3.511 | 66.072 | 21784 | 65.3521 | 21784 | 66.0721 | 7.84223 | 7.84225 | 18037.2 | 6.5352
FUNDERINGSBALK | -1.240 | -0.940 | 28840.3 | 12.017 | 40.056 | 3.497 | 100.86 | 33380 | 97.0208 | 33380 | 97.7408 | 12.0168 | 11.6749 | 26852.3 | 10.014
FUNDERINGSBALK | -1.240 | -0.940 | 15082 | 6.284 | 20.947 | 3.519 | 53.088 | 17456 | 52.368 | 17456 | 53.088 | 6.28416 | 6.28416 | 14453.6 | 5.2368
2 x FUNDERINGSBALK | -1.240 | -0.940 | 3067.2 | 1.278 | 4.26 | 3.707 | 11.37 | 3550 | 10.65 | 3550 | 11.37 | 1.278 | 1.278 | 2939.4 | 1.065
FUNDERINGSBALK | -0.800 | -0.500 | 2527.2 | 1.053 | 3.51 | 3.758 | 9.495 | 2925 | 8.775 | 2925 | 9.495 | 1.053 | 1.053 | 2421.9 | 0.8775
FUNDERINGSBALK | -1.240 | -0.940 | 22081.2 | 9.201 | 30.668 | 3.505 | 77.391 | 25557 | 76.671 | 25557 | 77.391 | 9.20052 | 9.20052 | 21161.2 | 7.6671
FUNDERINGSBALK | -1.240 | -0.940 | 18079.2 | 7.533 | 25.11 | 3.511 | 63.495 | 20925 | 62.775 | 20925 | 63.495 | 7.533 | 7.533 | 17325.9 | 6.2775
FUNDERINGSBALK | -1.240 | -0.940 | 25898.4 | 10.791 | 35.97 | 3.5 | 90.645 | 29975 | 89.925 | 29975 | 90.645 | 10.791 | 10.791 | 24819.3 | 8.9925
FUNDERINGSBALK | -1.240 | -0.940 | 15526 | 6.469 | 21.564 | 3.519 | 54.63 | 17970 | 53.9099 | 17970 | 54.6299 | 6.46919 | 6.46919 | 14879.1 | 5.39099
FUNDERINGSBALK | -1.240 | -0.940 | 7195.36 | 2.998 | 9.994 | 3.572 | 25.704 | 8328 | 24.9839 | 8327.96 | 25.7039 | 2.99807 | 2.99807 | 6895.55 | 2.49839
FUNDERINGSBALK | -1.240 | -0.940 | 9249.15 | 3.854 | 12.846 | 3.55 | 32.835 | 10705 | 32.1151 | 10705 | 32.8351 | 3.85381 | 3.85381 | 8863.77 | 3.21151
FUNDERINGSBALK | -1.240 | -0.940 | 10798.3 | 4.499 | 14.998 | 3.54 | 38.214 | 12498.1 | 37.4941 | 12498 | 38.2141 | 4.4993 | 4.49929 | 10348.4 | 3.74941
FUNDERINGSBALK | -1.240 | -0.940 | 17087.3 | 7.12 | 23.732 | 3.514 | 60.051 | 19777 | 59.3309 | 19777 | 60.0509 | 7.11971 | 7.11971 | 16375.3 | 5.93309
FUNDERINGSBALK | -1.240 | -0.940 | 10778.4 | 4.491 | 14.97 | 3.54 | 38.145 | 12475 | 37.425 | 12475 | 38.145 | 4.491 | 4.491 | 10329.3 | 3.7425
FUNDERINGSBALK | -1.240 | -0.940 | 17340.5 | 7.225 | 24.084 | 3.514 | 60.93 | 20070 | 60.21 | 20070 | 60.93 | 7.2252 | 7.2252 | 16618 | 6.021

# IfcBeam: 1400*300 (9)
In: Begane grond
Description: 1400*300; Classification: Balk (ARCHICAD Classification); Material: CONCRETE/C30/37
Default - Stortmethode: Insitu; NL-SfB_DESCRIPTION: Balkenfundering insitu; NL-SfB_NUMBERCODE: 16.12.41; IS_EXTERNAL: Nee; LOAD_BEARING: Nee; FIRE_RATING: R0; IFC_CLASS_REF_CODE: 16.12.41 ; Balkenfundering insitu; IFC_BUILDING_STOREY: Undefined; IFC_BUILDING: Undefined; MATERIAL: C30/37; NAME: FUNDERINGSBALK
Pset_BeamCommon - FireRating: R0; Reference: B0(?); Slope: 0 deg; LoadBearing: no; IsExternal: no
Tekla Common - Phase: 1; Class: 3
Tekla Quantity - Height: 300 mm; Width: 1400 mm
CPset_Phasing - Renovation Phase: Bestaand
AC_Pset_RenovationAndPhasing - Renovation Status: Existing
Material Properties - CONCRETE/C30/37, ThermalConductivity: 2.3; CONCRETE/C30/37, SpecificHeatCapacity: 1000 J/kg/K; CONCRETE/C30/37, MassDensity: 2300 kg/m3; CONCRETE/C30/37, Embodied Energy: 1.92 (MJ/kg); CONCRETE/C30/37, Embodied Carbon: 0.198 (kgCO₂/kg); CONCRETE/C30/37, Name: CONCRETE/C30/37; CONCRETE/C30/37, Participates in Collision Detection: yes
BaseQuantities - Width: 1400 mm; Depth: 300 mm; CrossSectionArea: 0.42 m2
Component Quantities - CONCRETE/C30/37, Component Thickness: 1400 mm; CONCRETE/C30/37, Rectangular Component Height: 300 mm; CONCRETE/C30/37, Rectangular Component Width: 1400 mm; CONCRETE/C30/37, Component Cross Section Area: 0.42 m2
Name | Bottom elevation | Top elevation | Weight (kg) | Volume (m3) | Gross footprint area (m2) | Area per tons (m2) | Net surface area (m2) | Tekla Quantity, Length (mm) | NetSurfaceAreaExtrudedSides (m2) = OuterSurfaceArea (m2) | BaseQuantities, Length (mm) | TotalSurfaceArea (m2) = GrossSurfaceArea (m2) = NetSurfaceArea (m2) | GrossVolume (m3) = NetVolume (m3) = CONCRETE/C30/37, Component Volume (Net) (m3) = CONCRETE/C30/37, Component Volume (Gross) (m3) | CONCRETE/C30/37, Mass (kg) | CONCRETE/C30/37, Projected Component Area (Net) (m2) = CONCRETE/C30/37, Projected Component Area (Gross) (m2)
FUNDERINGSBALK | -0.800 | -0.500 | 8895.6 | 3.706 | 12.355 | 3.467 | 30.845 | 8825 | 30.005 | 8825.01 | 30.845 | 3.7065 | 8524.95 | 2.6475
FUNDERINGSBALK | -0.800 | -0.500 | 35380.8 | 14.742 | 49.14 | 3.397 | 120.18 | 35100 | 119.34 | 35100 | 120.18 | 14.742 | 33906.6 | 10.53
FUNDERINGSBALK | -0.800 | -0.500 | 3855.6 | 1.607 | 5.355 | 3.591 | 13.845 | 3825 | 13.005 | 3825 | 13.845 | 1.6065 | 3694.95 | 1.1475
FUNDERINGSBALK | -0.800 | -0.500 | 1814.4 | 0.756 | 2.52 | 3.836 | 6.96 | 1800 | 6.12001 | 1800 | 6.96001 | 0.756001 | 1738.8 | 0.540001
FUNDERINGSBALK | -0.800 | -0.500 | 5972.4 | 2.489 | 8.295 | 3.514 | 20.985 | 5925 | 20.145 | 5925 | 20.985 | 2.4885 | 5723.55 | 1.7775
FUNDERINGSBALK | -1.240 | -0.940 | 51179.2 | 21.325 | 71.082 | 3.389 | 173.468 | 50773 | 172.628 | 50773 | 173.468 | 21.3247 | 49046.7 | 15.2319
FUNDERINGSBALK | -1.240 | -0.940 | 26288.7 | 10.954 | 36.512 | 3.405 | 89.512 | 26080 | 88.672 | 26080 | 89.512 | 10.9536 | 25193.3 | 7.824
FUNDERINGSBALK | -1.240 | -0.940 | 18005.9 | 7.502 | 25.008 | 3.42 | 61.574 | 17863 | 60.7342 | 17863 | 61.5742 | 7.50246 | 17255.7 | 5.3589
FUNDERINGSBALK | -1.240 | -0.940 | 29404.4 | 12.252 | 40.839 | 3.402 | 100.022 | 29171 | 99.1815 | 29171 | 100.022 | 12.2518 | 28179.2 | 8.75131

# IfcBeam: 150*150 (2)
In: Begane grond
Description: 150*150; Classification: Balk (ARCHICAD Classification); Material: CONCRETE/C35/45
Pset_BeamCommon - FireRating: R30; Reference: B0(?); Slope: 0 deg; LoadBearing: yes; IsExternal: no
Default - Stortmethode: Prefab; NL-SfB_DESCRIPTION: Kolom-/Liggerconstructie insitu; NL-SfB_NUMBERCODE: 28.11.42; IS_EXTERNAL: Nee; LOAD_BEARING: Ondersteuning; FIRE_RATING: R30; IFC_CLASS_REF_CODE: 28.11.42 ; Kolom-/Liggerconstructie insitu; IFC_BUILDING_STOREY: Undefined; IFC_BUILDING: Undefined; MATERIAL: C35/45; NAME: PB
Tekla Common - Bottom elevation: +3.277; Top elevation: +3.427; Phase: 1; Class: 4
Tekla Quantity - Weight: 77.44 kg; Volume: 0.032 m3; Gross footprint area: 0.215 m2; Area per tons: 11.692 m2; Net surface area: 0.905 m2; Height: 150 mm; Width: 150 mm; Length: 1434 mm
CPset_Phasing - Renovation Phase: Bestaand
AC_Pset_RenovationAndPhasing - Renovation Status: Existing
Material Properties - CONCRETE/C35/45, ThermalConductivity: 2.3; CONCRETE/C35/45, SpecificHeatCapacity: 1000 J/kg/K; CONCRETE/C35/45, MassDensity: 2300 kg/m3; CONCRETE/C35/45, Embodied Energy: 1.92 (MJ/kg); CONCRETE/C35/45, Embodied Carbon: 0.198 (kgCO₂/kg); CONCRETE/C35/45, Name: CONCRETE/C35/45; CONCRETE/C35/45, Participates in Collision Detection: yes
BaseQuantities - NetSurfaceAreaExtrudedSides: 0.8604 m2; Length: 1434 mm; Width: 150 mm; Depth: 150 mm; CrossSectionArea: 0.0225 m2; OuterSurfaceArea: 0.8604 m2; TotalSurfaceArea: 0.9054 m2; GrossSurfaceArea: 0.9054 m2; GrossVolume: 0.032265 m3; NetSurfaceArea: 0.9054 m2; NetVolume: 0.032265 m3
Component Quantities - CONCRETE/C35/45, Mass: 74.2095 kg; CONCRETE/C35/45, Projected Component Area (Net): 0.2151 m2; CONCRETE/C35/45, Projected Component Area (Gross): 0.2151 m2; CONCRETE/C35/45, Component Thickness: 150 mm; CONCRETE/C35/45, Rectangular Component Height: 150 mm; CONCRETE/C35/45, Rectangular Component Width: 150 mm; CONCRETE/C35/45, Component Cross Section Area: 0.0225 m2; CONCRETE/C35/45, Component Volume (Net): 0.032265 m3; CONCRETE/C35/45, Component Volume (Gross): 0.032265 m3

# IfcBeam: 150*200 (30)
In: Begane grond
Description: 150*200; Classification: Balk (ARCHICAD Classification); Material: CONCRETE/C35/45
Pset_BeamCommon - Reference: B0(?); LoadBearing: yes; IsExternal: no
Default - Stortmethode: Prefab; NL-SfB_DESCRIPTION: Kolom-/Liggerconstructie insitu; NL-SfB_NUMBERCODE: 28.11.42; IS_EXTERNAL: Nee; LOAD_BEARING: Ondersteuning; IFC_CLASS_REF_CODE: 28.11.42 ; Kolom-/Liggerconstructie insitu; IFC_BUILDING_STOREY: Undefined; IFC_BUILDING: Undefined; MATERIAL: C35/45; NAME: PB
Tekla Common - Phase: 1; Class: 4
Tekla Quantity - Height: 200 mm; Width: 150 mm
CPset_Phasing - Renovation Phase: Bestaand
AC_Pset_RenovationAndPhasing - Renovation Status: Existing
Material Properties - CONCRETE/C35/45, ThermalConductivity: 2.3; CONCRETE/C35/45, SpecificHeatCapacity: 1000 J/kg/K; CONCRETE/C35/45, MassDensity: 2300 kg/m3; CONCRETE/C35/45, Embodied Energy: 1.92 (MJ/kg); CONCRETE/C35/45, Embodied Carbon: 0.198 (kgCO₂/kg); CONCRETE/C35/45, Name: CONCRETE/C35/45; CONCRETE/C35/45, Participates in Collision Detection: yes
BaseQuantities - Width: 150 mm; Depth: 200 mm; CrossSectionArea: 0.03 m2
Component Quantities - CONCRETE/C35/45, Component Thickness: 150 mm; CONCRETE/C35/45, Rectangular Component Height: 200 mm; CONCRETE/C35/45, Rectangular Component Width: 150 mm; CONCRETE/C35/45, Component Cross Section Area: 0.03 m2
Name | FireRating = FIRE_RATING | Slope (deg) | Bottom elevation | Top elevation | Weight (kg) | Volume (m3) | Gross footprint area (m2) | Area per tons (m2) | Net surface area (m2) | Tekla Quantity, Length (mm) | NetSurfaceAreaExtrudedSides (m2) = OuterSurfaceArea (m2) | BaseQuantities, Length (mm) | TotalSurfaceArea (m2) = GrossSurfaceArea (m2) = NetSurfaceArea (m2) | GrossVolume (m3) = NetVolume (m3) = CONCRETE/C35/45, Component Volume (Net) (m3) = CONCRETE/C35/45, Component Volume (Gross) (m3) | CONCRETE/C35/45, Mass (kg) | CONCRETE/C35/45, Projected Component Area (Net) (m2) = CONCRETE/C35/45, Projected Component Area (Gross) (m2)
22 x PB | R30 | 0 | +2.800 | +3.000 | 173.52 | 0.072 | 0.361 | 10.068 | 1.747 | 2410 | 1.687 | 2410 | 1.747 | 0.0723 | 166.29 | 0.482
PB | R30 | -0.00291171 | +2.600 | +2.800 | 158.4 | 0.066 | 0.33 | 10.101 | 1.6 | 2200 | 1.54001 | 2200.01 | 1.60001 | 0.0660003 | 151.801 | 0.440002
PB | R30 | 0 | +2.800 | +3.000 | 172.8 | 0.072 | 0.36 | 10.069 | 1.74 | 2400 | 1.68 | 2400 | 1.74 | 0.072 | 165.6 | 0.48
PB | R30 | 0 | +2.800 | +3.000 | 173.52 | 0.072 | 0.362 | 10.068 | 1.747 | 2410 | 1.68701 | 2410.01 | 1.74701 | 0.0723003 | 166.291 | 0.482002
PB | R60 | 0 | +3.300 | +3.500 | 100.8 | 0.042 | 0.21 | 10.317 | 1.04 | 1400 | 0.98 | 1400 | 1.04 | 0.042 | 96.6 | 0.28
PB | R30 | 0 | +3.520 | +3.720 | 154.8 | 0.064 | 0.322 | 10.11 | 1.565 | 2150 | 1.505 | 2150 | 1.565 | 0.0645 | 148.35 | 0.43
2 x PB | R30 | 0 | +3.530 | +3.730 | 187.2 | 0.078 | 0.39 | 10.043 | 1.88 | 2600 | 1.82 | 2600 | 1.88 | 0.078 | 179.4 | 0.52
PB | R30 | 0 | +3.530 | +3.730 | 154.8 | 0.064 | 0.322 | 10.11 | 1.565 | 2150 | 1.50499 | 2149.98 | 1.56499 | 0.0644994 | 148.349 | 0.429996

# IfcBeam: 200*200 (7)
In: Begane grond
Description: 200*200; Classification: Balk (ARCHICAD Classification); Material: CONCRETE/C35/45
Pset_BeamCommon - FireRating: R30; Reference: B0(?); Slope: 0 deg; LoadBearing: yes; IsExternal: no
Default - Stortmethode: Prefab; NL-SfB_DESCRIPTION: Kolom-/Liggerconstructie insitu; NL-SfB_NUMBERCODE: 28.11.42; IS_EXTERNAL: Nee; LOAD_BEARING: Ondersteuning; FIRE_RATING: R30; IFC_CLASS_REF_CODE: 28.11.42 ; Kolom-/Liggerconstructie insitu; IFC_BUILDING_STOREY: Undefined; IFC_BUILDING: Undefined; MATERIAL: C35/45; NAME: PB
Tekla Common - Phase: 1; Class: 4
Tekla Quantity - Weight: 137.66 kg; Volume: 0.057 m3; Gross footprint area: 0.287 m2; Area per tons: 8.914 m2; Net surface area: 1.227 m2; Height: 200 mm; Width: 200 mm; Length: 1434 mm
CPset_Phasing - Renovation Phase: Bestaand
AC_Pset_RenovationAndPhasing - Renovation Status: Existing
Material Properties - CONCRETE/C35/45, ThermalConductivity: 2.3; CONCRETE/C35/45, SpecificHeatCapacity: 1000 J/kg/K; CONCRETE/C35/45, MassDensity: 2300 kg/m3; CONCRETE/C35/45, Embodied Energy: 1.92 (MJ/kg); CONCRETE/C35/45, Embodied Carbon: 0.198 (kgCO₂/kg); CONCRETE/C35/45, Name: CONCRETE/C35/45; CONCRETE/C35/45, Participates in Collision Detection: yes
BaseQuantities - NetSurfaceAreaExtrudedSides: 1.1472 m2; Length: 1434 mm; Width: 200 mm; Depth: 200 mm; CrossSectionArea: 0.04 m2; OuterSurfaceArea: 1.1472 m2; TotalSurfaceArea: 1.2272 m2; GrossSurfaceArea: 1.2272 m2; GrossVolume: 0.05736 m3; NetSurfaceArea: 1.2272 m2; NetVolume: 0.05736 m3
Component Quantities - CONCRETE/C35/45, Mass: 131.928 kg; CONCRETE/C35/45, Projected Component Area (Net): 0.2868 m2; CONCRETE/C35/45, Projected Component Area (Gross): 0.2868 m2; CONCRETE/C35/45, Component Thickness: 200 mm; CONCRETE/C35/45, Rectangular Component Height: 200 mm; CONCRETE/C35/45, Rectangular Component Width: 200 mm; CONCRETE/C35/45, Component Cross Section Area: 0.04 m2; CONCRETE/C35/45, Component Volume (Net): 0.05736 m3; CONCRETE/C35/45, Component Volume (Gross): 0.05736 m3
Name | Bottom elevation | Top elevation
2 x PB | +2.377 | +2.577
5 x PB | +3.277 | +3.477

# IfcBeam: 200*300, PB
In: Begane grond
Description: 200*300; Classification: Balk (ARCHICAD Classification); Material: CONCRETE/C35/45
Pset_BeamCommon - FireRating: R30; Reference: B0(?); Slope: 0 deg; LoadBearing: yes; IsExternal: no
Default - Stortmethode: Prefab; NL-SfB_DESCRIPTION: Kolom-/Liggerconstructie insitu; NL-SfB_NUMBERCODE: 28.11.42; IS_EXTERNAL: Nee; LOAD_BEARING: Ondersteuning; FIRE_RATING: R30; IFC_CLASS_REF_CODE: 28.11.42 ; Kolom-/Liggerconstructie insitu; IFC_BUILDING_STOREY: Undefined; IFC_BUILDING: Undefined; MATERIAL: C35/45; NAME: PB
Tekla Common - Bottom elevation: +3.277; Top elevation: +3.577; Phase: 1; Class: 4
Tekla Quantity - Weight: 369.22 kg; Volume: 0.154 m3; Gross footprint area: 0.513 m2; Area per tons: 7.269 m2; Net surface area: 2.684 m2; Height: 300 mm; Width: 200 mm; Length: 2564 mm
CPset_Phasing - Renovation Phase: Bestaand
AC_Pset_RenovationAndPhasing - Renovation Status: Existing
Material Properties - CONCRETE/C35/45, ThermalConductivity: 2.3; CONCRETE/C35/45, SpecificHeatCapacity: 1000 J/kg/K; CONCRETE/C35/45, MassDensity: 2300 kg/m3; CONCRETE/C35/45, Embodied Energy: 1.92 (MJ/kg); CONCRETE/C35/45, Embodied Carbon: 0.198 (kgCO₂/kg); CONCRETE/C35/45, Name: CONCRETE/C35/45; CONCRETE/C35/45, Participates in Collision Detection: yes
BaseQuantities - NetSurfaceAreaExtrudedSides: 2.564 m2; Length: 2564 mm; Width: 200 mm; Depth: 300 mm; CrossSectionArea: 0.06 m2; OuterSurfaceArea: 2.564 m2; TotalSurfaceArea: 2.684 m2; GrossSurfaceArea: 2.684 m2; GrossVolume: 0.15384 m3; NetSurfaceArea: 2.684 m2; NetVolume: 0.15384 m3
Component Quantities - CONCRETE/C35/45, Mass: 353.832 kg; CONCRETE/C35/45, Projected Component Area (Net): 0.7692 m2; CONCRETE/C35/45, Projected Component Area (Gross): 0.7692 m2; CONCRETE/C35/45, Component Thickness: 200 mm; CONCRETE/C35/45, Rectangular Component Height: 300 mm; CONCRETE/C35/45, Rectangular Component Width: 200 mm; CONCRETE/C35/45, Component Cross Section Area: 0.06 m2; CONCRETE/C35/45, Component Volume (Net): 0.15384 m3; CONCRETE/C35/45, Component Volume (Gross): 0.15384 m3

# IfcBeam: 214*200 (20)
In: Begane grond
Description: 214*200; Classification: Balk (ARCHICAD Classification); Material: CONCRETE/C35/45
Pset_BeamCommon - FireRating: R30; Reference: B0(?); LoadBearing: yes; IsExternal: no
Default - Stortmethode: Prefab; NL-SfB_DESCRIPTION: Kolom-/Liggerconstructie insitu; NL-SfB_NUMBERCODE: 28.11.42; IS_EXTERNAL: Nee; LOAD_BEARING: Ondersteuning; FIRE_RATING: R30; IFC_CLASS_REF_CODE: 28.11.42 ; Kolom-/Liggerconstructie insitu; IFC_BUILDING_STOREY: Undefined; IFC_BUILDING: Undefined; MATERIAL: C35/45; NAME: PB
Tekla Common - Phase: 1; Class: 4
Tekla Quantity - Height: 200 mm; Width: 214 mm
CPset_Phasing - Renovation Phase: Bestaand
AC_Pset_RenovationAndPhasing - Renovation Status: Existing
Material Properties - CONCRETE/C35/45, ThermalConductivity: 2.3; CONCRETE/C35/45, SpecificHeatCapacity: 1000 J/kg/K; CONCRETE/C35/45, MassDensity: 2300 kg/m3; CONCRETE/C35/45, Embodied Energy: 1.92 (MJ/kg); CONCRETE/C35/45, Embodied Carbon: 0.198 (kgCO₂/kg); CONCRETE/C35/45, Name: CONCRETE/C35/45; CONCRETE/C35/45, Participates in Collision Detection: yes
BaseQuantities - Width: 214 mm; Depth: 200 mm; CrossSectionArea: 0.0428 m2
Component Quantities - CONCRETE/C35/45, Component Thickness: 214 mm; CONCRETE/C35/45, Rectangular Component Height: 200 mm; CONCRETE/C35/45, Rectangular Component Width: 214 mm; CONCRETE/C35/45, Component Cross Section Area: 0.0428 m2
Name | Slope (deg) | Bottom elevation | Top elevation | Weight (kg) | Volume (m3) | Gross footprint area (m2) | Area per tons (m2) | Net surface area (m2) | Tekla Quantity, Length (mm) | NetSurfaceAreaExtrudedSides (m2) = OuterSurfaceArea (m2) | BaseQuantities, Length (mm) | TotalSurfaceArea (m2) = GrossSurfaceArea (m2) = NetSurfaceArea (m2) | GrossVolume (m3) = NetVolume (m3) = CONCRETE/C35/45, Component Volume (Net) (m3) = CONCRETE/C35/45, Component Volume (Gross) (m3) | CONCRETE/C35/45, Mass (kg) | CONCRETE/C35/45, Projected Component Area (Net) (m2) = CONCRETE/C35/45, Projected Component Area (Gross) (m2)
7 x PB | 0 | +2.800 | +3.000 | 247.56 | 0.103 | 0.516 | 8.407 | 2.081 | 2410 | 1.99548 | 2410 | 2.08108 | 0.103148 | 237.24 | 0.482
2 x PB | 0 | +2.800 | +3.000 | 247.56 | 0.103 | 0.516 | 8.407 | 2.081 | 2410 | 1.99549 | 2410.01 | 2.08109 | 0.103148 | 237.241 | 0.482002
PB | -0.00318696 | +2.800 | +3.000 | 247.56 | 0.103 | 0.516 | 8.407 | 2.081 | 2410 | 1.99547 | 2409.99 | 2.08107 | 0.103148 | 237.239 | 0.481998
2 x PB | -0.00291171 | +2.800 | +3.000 | 267.07 | 0.111 | 0.556 | 8.38 | 2.238 | 2600 | 2.1528 | 2600 | 2.2384 | 0.11128 | 255.944 | 0.52
PB | -0.0031248 | +2.800 | +3.000 | 251.66 | 0.105 | 0.524 | 8.401 | 2.114 | 2450 | 2.0286 | 2450 | 2.1142 | 0.10486 | 241.178 | 0.49
PB | 0 | +2.800 | +3.000 | 164.35 | 0.068 | 0.342 | 8.582 | 1.41 | 1600 | 1.3248 | 1600 | 1.4104 | 0.06848 | 157.504 | 0.32
PB | 0 | +2.800 | +3.000 | 268.1 | 0.112 | 0.559 | 8.38 | 2.247 | 2610 | 2.16108 | 2610 | 2.24668 | 0.111708 | 256.928 | 0.522
PB | 0 | +1.665 | +1.865 | 121.21 | 0.051 | 0.253 | 8.767 | 1.063 | 1180 | 0.97704 | 1180 | 1.06264 | 0.050504 | 116.159 | 0.236
2 x PB | 0 | +2.377 | +2.577 | 297.89 | 0.124 | 0.621 | 8.348 | 2.487 | 2900 | 2.4012 | 2900 | 2.4868 | 0.12412 | 285.476 | 0.58
2 x PB | 0 | +2.377 | +2.577 | 215.71 | 0.09 | 0.449 | 8.458 | 1.824 | 2100 | 1.7388 | 2100 | 1.8244 | 0.08988 | 206.724 | 0.42

# IfcBeam: 214*350, PB
In: Begane grond
Description: 214*350; Classification: Balk (ARCHICAD Classification); Material: CONCRETE/C35/45
Pset_BeamCommon - FireRating: R30; Reference: B0(?); Slope: 0 deg; LoadBearing: yes; IsExternal: no
Default - Stortmethode: Prefab; NL-SfB_DESCRIPTION: Kolom-/Liggerconstructie insitu; NL-SfB_NUMBERCODE: 28.11.42; IS_EXTERNAL: Nee; LOAD_BEARING: Ondersteuning; FIRE_RATING: R30; IFC_CLASS_REF_CODE: 28.11.42 ; Kolom-/Liggerconstructie insitu; IFC_BUILDING_STOREY: Undefined; IFC_BUILDING: Undefined; MATERIAL: C35/45; NAME: PB
Tekla Common - Bottom elevation: +2.377; Top elevation: +2.727; Phase: 1; Class: 4
Tekla Quantity - Weight: 595.72 kg; Volume: 0.248 m3; Gross footprint area: 0.709 m2; Area per tons: 6.526 m2; Net surface area: 3.888 m2; Height: 350 mm; Width: 214 mm; Length: 3314 mm
CPset_Phasing - Renovation Phase: Bestaand
AC_Pset_RenovationAndPhasing - Renovation Status: Existing
Material Properties - CONCRETE/C35/45, ThermalConductivity: 2.3; CONCRETE/C35/45, SpecificHeatCapacity: 1000 J/kg/K; CONCRETE/C35/45, MassDensity: 2300 kg/m3; CONCRETE/C35/45, Embodied Energy: 1.92 (MJ/kg); CONCRETE/C35/45, Embodied Carbon: 0.198 (kgCO₂/kg); CONCRETE/C35/45, Name: CONCRETE/C35/45; CONCRETE/C35/45, Participates in Collision Detection: yes
BaseQuantities - NetSurfaceAreaExtrudedSides: 3.73819 m2; Length: 3314 mm; Width: 214 mm; Depth: 350 mm; CrossSectionArea: 0.0749 m2; OuterSurfaceArea: 3.73819 m2; TotalSurfaceArea: 3.88799 m2; GrossSurfaceArea: 3.88799 m2; GrossVolume: 0.248219 m3; NetSurfaceArea: 3.88799 m2; NetVolume: 0.248219 m3
Component Quantities - CONCRETE/C35/45, Mass: 570.903 kg; CONCRETE/C35/45, Projected Component Area (Net): 1.1599 m2; CONCRETE/C35/45, Projected Component Area (Gross): 1.1599 m2; CONCRETE/C35/45, Component Thickness: 214 mm; CONCRETE/C35/45, Rectangular Component Height: 350 mm; CONCRETE/C35/45, Rectangular Component Width: 214 mm; CONCRETE/C35/45, Component Cross Section Area: 0.0749 m2; CONCRETE/C35/45, Component Volume (Net): 0.248219 m3; CONCRETE/C35/45, Component Volume (Gross): 0.248219 m3

# IfcBeam: 214*495, PB (ZELFDRAGEND)
In: Begane grond
Description: 214*495; Classification: Balk (ARCHICAD Classification); Material: CONCRETE/C35/45
Pset_BeamCommon - FireRating: R30; Reference: B0(?); Slope: 0 deg; LoadBearing: yes; IsExternal: no
Default - Stortmethode: Prefab; NL-SfB_DESCRIPTION: Kolom-/Liggerconstructie insitu; NL-SfB_NUMBERCODE: 28.11.42; IS_EXTERNAL: Nee; LOAD_BEARING: Ondersteuning; FIRE_RATING: R30; IFC_CLASS_REF_CODE: 28.11.42 ; Kolom-/Liggerconstructie insitu; IFC_BUILDING_STOREY: Undefined; IFC_BUILDING: Undefined; MATERIAL: C35/45; NAME: PB (ZELFDRAGEND)
Tekla Common - Bottom elevation: +2.800; Top elevation: +3.295; Phase: 1; Class: 4
Tekla Quantity - Weight: 663.55 kg; Volume: 0.276 m3; Gross footprint area: 0.559 m2; Area per tons: 5.897 m2; Net surface area: 3.913 m2; Height: 495 mm; Width: 214 mm; Length: 2610 mm
CPset_Phasing - Renovation Phase: Bestaand
AC_Pset_RenovationAndPhasing - Renovation Status: Existing
Material Properties - CONCRETE/C35/45, ThermalConductivity: 2.3; CONCRETE/C35/45, SpecificHeatCapacity: 1000 J/kg/K; CONCRETE/C35/45, MassDensity: 2300 kg/m3; CONCRETE/C35/45, Embodied Energy: 1.92 (MJ/kg); CONCRETE/C35/45, Embodied Carbon: 0.198 (kgCO₂/kg); CONCRETE/C35/45, Name: CONCRETE/C35/45; CONCRETE/C35/45, Participates in Collision Detection: yes
BaseQuantities - NetSurfaceAreaExtrudedSides: 3.70098 m2; Length: 2610 mm; Width: 214 mm; Depth: 495 mm; CrossSectionArea: 0.10593 m2; OuterSurfaceArea: 3.70098 m2; TotalSurfaceArea: 3.91284 m2; GrossSurfaceArea: 3.91284 m2; GrossVolume: 0.276477 m3; NetSurfaceArea: 3.91284 m2; NetVolume: 0.276477 m3
Component Quantities - CONCRETE/C35/45, Mass: 635.898 kg; CONCRETE/C35/45, Projected Component Area (Net): 1.29195 m2; CONCRETE/C35/45, Projected Component Area (Gross): 1.29195 m2; CONCRETE/C35/45, Component Thickness: 214 mm; CONCRETE/C35/45, Rectangular Component Height: 495 mm; CONCRETE/C35/45, Rectangular Component Width: 214 mm; CONCRETE/C35/45, Component Cross Section Area: 0.10593 m2; CONCRETE/C35/45, Component Volume (Net): 0.276477 m3; CONCRETE/C35/45, Component Volume (Gross): 0.276477 m3

# IfcBeam: 450*1200, BETONOPSTORT
In: Begane grond
Description: 450*1200; Classification: Balk (ARCHICAD Classification); Material: CONCRETE/C20/25
Pset_BeamCommon - FireRating: R30; Reference: W0(?); LoadBearing: yes; IsExternal: no
Default - Stortmethode: Insitu; NL-SfB_DESCRIPTION: Funderingsmuur insitu; NL-SfB_NUMBERCODE: 16.14.41; IS_EXTERNAL: Nee; LOAD_BEARING: Ondersteuning; FIRE_RATING: R30; IFC_CLASS_REF_CODE: 16.14.41 ; Funderingsmuur insitu; IFC_BUILDING_STOREY: Undefined; IFC_BUILDING: XXXX Gebouw; MATERIAL: C20/25; NAME: BETONOPSTORT
Tekla Common - Bottom elevation: -0.740; Top elevation: +0.460; Phase: 1; Class: 3
Tekla Quantity - Weight: 583.2 kg; Volume: 0.243 m3; Gross footprint area: 0.203 m2; Area per tons: 4.398 m2; Net surface area: 2.565 m2; Height: 1200 mm; Width: 450 mm; Length: 450 mm
CPset_Phasing - Renovation Phase: Bestaand
AC_Pset_RenovationAndPhasing - Renovation Status: Existing
Material Properties - CONCRETE/C20/25, ThermalConductivity: 2.3; CONCRETE/C20/25, SpecificHeatCapacity: 1000 J/kg/K; CONCRETE/C20/25, MassDensity: 2300 kg/m3; CONCRETE/C20/25, Embodied Energy: 1.92 (MJ/kg); CONCRETE/C20/25, Embodied Carbon: 0.198 (kgCO₂/kg); CONCRETE/C20/25, Name: CONCRETE/C20/25; CONCRETE/C20/25, Participates in Collision Detection: yes
BaseQuantities - NetSurfaceAreaExtrudedSides: 2.16 m2; Length: 1200 mm; Width: 450 mm; Depth: 450 mm; CrossSectionArea: 0.2025 m2; OuterSurfaceArea: 2.16 m2; TotalSurfaceArea: 2.565 m2; GrossSurfaceArea: 2.565 m2; GrossVolume: 0.243 m3; NetSurfaceArea: 0 m2; NetVolume: 0.243 m3
Component Quantities - CONCRETE/C20/25, Mass: 558.9 kg; CONCRETE/C20/25, Component Thickness: 450 mm; CONCRETE/C20/25, Rectangular Component Height: 450 mm; CONCRETE/C20/25, Rectangular Component Width: 450 mm; CONCRETE/C20/25, Component Cross Section Area: 0.2025 m2; CONCRETE/C20/25, Component Volume (Net): 0.243 m3; CONCRETE/C20/25, Component Volume (Gross): 0.243 m3

# IfcBeam: 450*300 (3)
In: Begane grond
Description: 450*300; Classification: Balk (ARCHICAD Classification); Material: CONCRETE/C30/37
Default - Stortmethode: Insitu; NL-SfB_DESCRIPTION: Binnenwand insitu; NL-SfB_NUMBERCODE: 22.11.41; IS_EXTERNAL: Nee; LOAD_BEARING: Ondersteuning; FIRE_RATING: R30; IFC_CLASS_REF_CODE: 22.11.41 ; Binnenwand insitu; IFC_BUILDING_STOREY: Undefined; IFC_BUILDING: XXXX Gebouw; MATERIAL: C30/37; NAME: BETONOPSTORT
Pset_BeamCommon - FireRating: R30; Reference: W0(?); LoadBearing: yes; IsExternal: no
Tekla Common - Bottom elevation: -0.400; Top elevation: -0.100; Phase: 1; Class: 3
Tekla Quantity - Weight: 145.8 kg; Volume: 0.061 m3; Gross footprint area: 0.203 m2; Area per tons: 6.481 m2; Net surface area: 0.945 m2; Height: 300 mm; Width: 450 mm; Length: 450 mm
CPset_Phasing - Renovation Phase: Bestaand
AC_Pset_RenovationAndPhasing - Renovation Status: Existing
Material Properties - CONCRETE/C30/37, ThermalConductivity: 2.3; CONCRETE/C30/37, SpecificHeatCapacity: 1000 J/kg/K; CONCRETE/C30/37, MassDensity: 2300 kg/m3; CONCRETE/C30/37, Embodied Energy: 1.92 (MJ/kg); CONCRETE/C30/37, Embodied Carbon: 0.198 (kgCO₂/kg); CONCRETE/C30/37, Name: CONCRETE/C30/37; CONCRETE/C30/37, Participates in Collision Detection: yes
BaseQuantities - NetSurfaceAreaExtrudedSides: 0.54 m2; Length: 300 mm; Width: 450 mm; Depth: 450 mm; CrossSectionArea: 0.2025 m2; OuterSurfaceArea: 0.54 m2; TotalSurfaceArea: 0.945 m2; GrossSurfaceArea: 0.945 m2; GrossVolume: 0.06075 m3; NetSurfaceArea: 0 m2; NetVolume: 0.06075 m3
Component Quantities - CONCRETE/C30/37, Mass: 139.725 kg; CONCRETE/C30/37, Component Thickness: 450 mm; CONCRETE/C30/37, Rectangular Component Height: 450 mm; CONCRETE/C30/37, Rectangular Component Width: 450 mm; CONCRETE/C30/37, Component Cross Section Area: 0.2025 m2; CONCRETE/C30/37, Component Volume (Net): 0.06075 m3; CONCRETE/C30/37, Component Volume (Gross): 0.06075 m3

# IfcBeam: 450*550 (2)
In: Begane grond
Description: 450*550; Classification: Balk (ARCHICAD Classification); Material: CONCRETE/C30/37
Default - Stortmethode: Insitu; NL-SfB_DESCRIPTION: Binnenwand insitu; NL-SfB_NUMBERCODE: 22.11.41; IS_EXTERNAL: Nee; LOAD_BEARING: Ondersteuning; FIRE_RATING: R30; IFC_CLASS_REF_CODE: 22.11.41 ; Binnenwand insitu; IFC_BUILDING_STOREY: Undefined; IFC_BUILDING: XXXX Gebouw; MATERIAL: C30/37; NAME: BETONOPSTORT
Tekla Common - Bottom elevation: -0.650; Top elevation: -0.100; Phase: 1; Class: 3
Tekla Quantity - Weight: 267.3 kg; Volume: 0.111 m3; Gross footprint area: 0.203 m2; Area per tons: 5.219 m2; Net surface area: 1.395 m2; Height: 550 mm; Width: 450 mm; Length: 450 mm
Pset_BeamCommon - FireRating: R30; Reference: W0(?); LoadBearing: yes; IsExternal: no
CPset_Phasing - Renovation Phase: Bestaand
AC_Pset_RenovationAndPhasing - Renovation Status: Existing
Material Properties - CONCRETE/C30/37, ThermalConductivity: 2.3; CONCRETE/C30/37, SpecificHeatCapacity: 1000 J/kg/K; CONCRETE/C30/37, MassDensity: 2300 kg/m3; CONCRETE/C30/37, Embodied Energy: 1.92 (MJ/kg); CONCRETE/C30/37, Embodied Carbon: 0.198 (kgCO₂/kg); CONCRETE/C30/37, Name: CONCRETE/C30/37; CONCRETE/C30/37, Participates in Collision Detection: yes
BaseQuantities - NetSurfaceAreaExtrudedSides: 0.99 m2; Length: 550 mm; Width: 450 mm; Depth: 450 mm; CrossSectionArea: 0.2025 m2; OuterSurfaceArea: 0.99 m2; TotalSurfaceArea: 1.395 m2; GrossSurfaceArea: 1.395 m2; GrossVolume: 0.111375 m3; NetSurfaceArea: 0 m2; NetVolume: 0.111375 m3
Component Quantities - CONCRETE/C30/37, Mass: 256.163 kg; CONCRETE/C30/37, Component Thickness: 450 mm; CONCRETE/C30/37, Rectangular Component Height: 450 mm; CONCRETE/C30/37, Rectangular Component Width: 450 mm; CONCRETE/C30/37, Component Cross Section Area: 0.2025 m2; CONCRETE/C30/37, Component Volume (Net): 0.111375 m3; CONCRETE/C30/37, Component Volume (Gross): 0.111375 m3

# IfcBeam: 600*110 (2)
In: Begane grond
Description: 600*110; Classification: Balk (ARCHICAD Classification); Material: TIMBER/C24
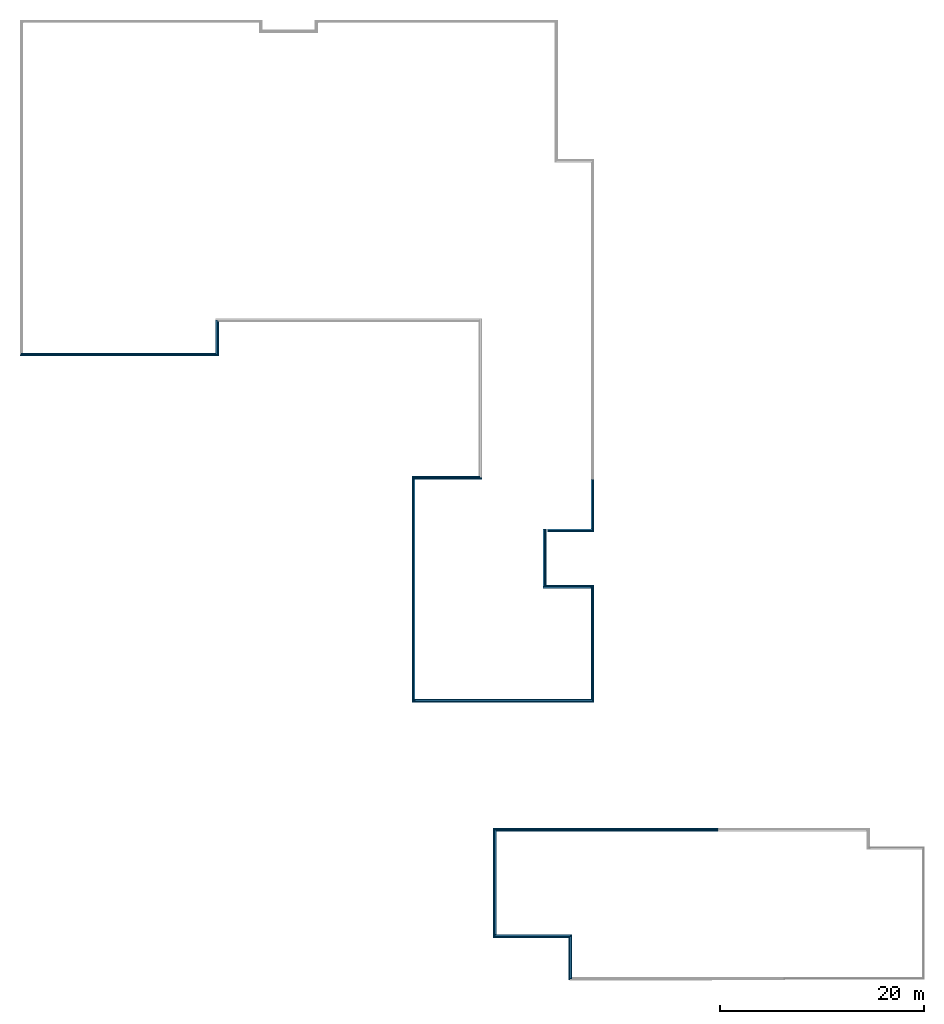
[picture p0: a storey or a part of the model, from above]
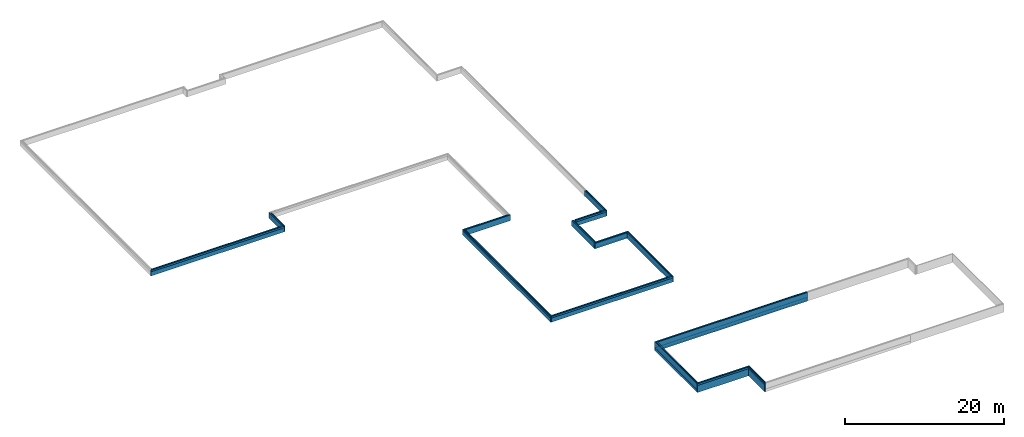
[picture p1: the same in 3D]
Properties of the parts of a building model (IFC2X3), part 2 of 19

# IfcBeam: 600*110 (2)
Pset_BeamCommon - FireRating: R30; Reference: LIH0(?); Slope: 0 deg; LoadBearing: yes; IsExternal: no
Default - NL-SfB_DESCRIPTION: Kolom-/Liggerconstructie hout; NL-SfB_NUMBERCODE: 28.11.11; IS_EXTERNAL: Nee; LOAD_BEARING: Ondersteuning; FIRE_RATING: R30; IFC_CLASS_REF_CODE: 28.11.11 ; Kolom-/Liggerconstructie hout; IFC_BUILDING_STOREY: Undefined; IFC_BUILDING: Undefined; MATERIAL: C24; NAME: LIGGER
Tekla Common - Bottom elevation: +4.100; Top elevation: +4.700; Phase: 1; Class: 13
Tekla Quantity - Weight: 297.75 kg; Volume: 0.662 m3; Gross footprint area: 1.111 m2; Area per tons: 48.31 m2; Net surface area: 14.384 m2; Height: 110 mm; Width: 600 mm; Length: 10099.9 mm
CPset_Phasing - Renovation Phase: Bestaand
AC_Pset_RenovationAndPhasing - Renovation Status: Existing
Material Properties - TIMBER/C24, ThermalConductivity: 2.3; TIMBER/C24, SpecificHeatCapacity: 1000 J/kg/K; TIMBER/C24, MassDensity: 2300 kg/m3; TIMBER/C24, Embodied Energy: 1.92 (MJ/kg); TIMBER/C24, Embodied Carbon: 0.198 (kgCO₂/kg); TIMBER/C24, Name: TIMBER/C24; TIMBER/C24, Participates in Collision Detection: yes
BaseQuantities - NetSurfaceAreaExtrudedSides: 14.2171 m2; Length: 10099.9 mm; Width: 110 mm; Depth: 600 mm; CrossSectionArea: 0.066 m2; OuterSurfaceArea: 14.2171 m2; TotalSurfaceArea: 14.3491 m2; GrossSurfaceArea: 14.3491 m2; GrossVolume: 0.666595 m3; NetSurfaceArea: 14.3491 m2; NetVolume: 0.661667 m3
Component Quantities - TIMBER/C24, Mass: 1521.83 kg; TIMBER/C24, Projected Component Area (Net): 6.01515 m2; TIMBER/C24, Projected Component Area (Gross): 6.05995 m2; TIMBER/C24, Component Thickness: 110 mm; TIMBER/C24, Rectangular Component Height: 600 mm; TIMBER/C24, Rectangular Component Width: 110 mm; TIMBER/C24, Component Cross Section Area: 0.066 m2; TIMBER/C24, Component Volume (Net): 0.661667 m3; TIMBER/C24, Component Volume (Gross): 0.666595 m3

# IfcBeam: 75*200 (72)
In: Begane grond
Description: 75*200; Classification: Balk (ARCHICAD Classification); Material: TIMBER/C18
Pset_BeamCommon - FireRating: R30; Reference: 0(?); Slope: 0 deg; LoadBearing: yes; IsExternal: no
Default - NL-SfB_DESCRIPTION: Vloer balklaag; NL-SfB_NUMBERCODE: 23.21.10; IS_EXTERNAL: Nee; LOAD_BEARING: Ondersteuning; FIRE_RATING: R30; IFC_CLASS_REF_CODE: 23.21.10 ; Vloer balklaag; IFC_BUILDING_STOREY: Undefined; IFC_BUILDING: Undefined; MATERIAL: C18; NAME: BALKLAAG
Tekla Common - Phase: 1; Class: 13
Tekla Quantity - Height: 200 mm; Width: 75 mm
CPset_Phasing - Renovation Phase: Bestaand
AC_Pset_RenovationAndPhasing - Renovation Status: Existing
Material Properties - TIMBER/C18, ThermalConductivity: 2.3; TIMBER/C18, SpecificHeatCapacity: 1000 J/kg/K; TIMBER/C18, MassDensity: 2300 kg/m3; TIMBER/C18, Embodied Energy: 1.92 (MJ/kg); TIMBER/C18, Embodied Carbon: 0.198 (kgCO₂/kg); TIMBER/C18, Name: TIMBER/C18; TIMBER/C18, Participates in Collision Detection: yes
BaseQuantities - Width: 75 mm; Depth: 200 mm; CrossSectionArea: 0.015 m2
Component Quantities - TIMBER/C18, Component Thickness: 75 mm; TIMBER/C18, Rectangular Component Height: 200 mm; TIMBER/C18, Rectangular Component Width: 75 mm; TIMBER/C18, Component Cross Section Area: 0.015 m2
Name | comment | Bottom elevation | Top elevation | Weight (kg) | Volume (m3) | Gross footprint area (m2) | Area per tons (m2) | Net surface area (m2) | Tekla Quantity, Length (mm) | NetSurfaceAreaExtrudedSides (m2) = OuterSurfaceArea (m2) | BaseQuantities, Length (mm) | TotalSurfaceArea (m2) = GrossSurfaceArea (m2) = NetSurfaceArea (m2) | GrossVolume (m3) | NetVolume (m3) = TIMBER/C18, Component Volume (Net) (m3) = TIMBER/C18, Component Volume (Gross) (m3) | TIMBER/C18, Mass (kg) | TIMBER/C18, Projected Component Area (Net) (m2) = TIMBER/C18, Projected Component Area (Gross) (m2)
8 x BALKLAAG | 610 | +3.591 | +3.791 | 31.82 | 0.071 | 0.354 | 82.424 | 2.623 | 4714 | 2.55753 | 4714 | 2.58753 | 0.07071 | 0.0704549 | 162.046 | 0.939399
4 x BALKLAAG | 400 | +4.480 | +4.680 | 18.54 | 0.041 | 0.206 | 83.099 | 1.541 | 2746.9 | 1.48122 | 2693.12 | 1.51122 | 0.0412038 | 0.0403968 | 92.9126 | 0.538624
4 x BALKLAAG | 400 | +4.480 | +4.680 | 18.52 | 0.041 | 0.206 | 83.101 | 1.539 | 2743.8 | 1.5091 | 2743.82 | 1.5391 | 0.0411573 | 0.0411573 | 94.6618 | 0.548764
8 x BALKLAAG | 400 | +4.480 | +4.680 | 18.12 | 0.04 | 0.201 | 83.137 | 1.506 | 2683.8 | 1.4761 | 2683.82 | 1.5061 | 0.0402573 | 0.0402573 | 92.5918 | 0.536764
10 x BALKLAAG | 400 | +4.480 | +4.680 | 26.73 | 0.059 | 0.297 | 82.604 | 2.208 | 3960 | 2.178 | 3960 | 2.208 | 0.0594 | 0.0594 | 136.62 | 0.792
4 x BALKLAAG | 400 | +4.480 | +4.680 | 18.48 | 0.041 | 0.205 | 83.105 | 1.535 | 2737.2 | 1.49692 | 2727.76 | 1.52692 | 0.0410574 | 0.040901 | 94.0724 | 0.545347
7 x BALKLAAG | 400 | +4.480 | +4.680 | 36.45 | 0.081 | 0.405 | 82.304 | 3 | 5400.6 | 2.97033 | 5400.6 | 3.00033 | 0.081009 | 0.081009 | 186.321 | 1.08012
5 x BALKLAAG | 400 | +4.480 | +4.680 | 30.31 | 0.067 | 0.337 | 82.471 | 2.5 | 4490.1 | 2.46953 | 4490.06 | 2.49953 | 0.0673509 | 0.0673509 | 154.907 | 0.898012
5 x BALKLAAG | 400 | +4.480 | +4.680 | 29.7 | 0.066 | 0.33 | 82.492 | 2.45 | 4400 | 2.42 | 4400 | 2.45 | 0.066 | 0.066 | 151.8 | 0.88
5 x BALKLAAG | 400 | +4.480 | +4.680 | 18.16 | 0.04 | 0.202 | 83.134 | 1.509 | 2689.9 | 1.47946 | 2689.92 | 1.50946 | 0.0403488 | 0.0403488 | 92.8022 | 0.537984
4 x BALKLAAG | 400 | +4.480 | +4.680 | 36.72 | 0.082 | 0.408 | 82.298 | 3.022 | 5440.6 | 2.94266 | 5350.3 | 2.97266 | 0.081609 | 0.0802544 | 184.585 | 1.07006
4 x BALKLAAG | 400 | +4.480 | +4.680 | 17.86 | 0.04 | 0.198 | 83.161 | 1.485 | 2645.6 | 1.35575 | 2465 | 1.38575 | 0.039684 | 0.036975 | 85.0425 | 0.493
4 x BALKLAAG | 400 | +4.480 | +4.680 | 37.3 | 0.083 | 0.414 | 82.286 | 3.068 | 5525.6 | 2.98943 | 5435.32 | 3.01943 | 0.0828843 | 0.0815298 | 187.519 | 1.08706

# IfcBeam: BENDED_L250*200*10 (48)
In: Begane grond
Description: BENDED_L250*200*10; Classification: Balk (ARCHICAD Classification); Material: STEEL/S275
Pset_BeamCommon - FireRating: R30; Reference: LIL0(?); Slope: 0 deg; LoadBearing: yes; IsExternal: no
Default - NL-SfB_DESCRIPTION: Kolom-/Liggerconstructie staal; NL-SfB_NUMBERCODE: 28.11.21; IS_EXTERNAL: Nee; LOAD_BEARING: Ondersteuning; FIRE_RATING: R30; IFC_CLASS_REF_CODE: 28.11.21 ; Kolom-/Liggerconstructie staal; IFC_BUILDING_STOREY: Undefined; IFC_BUILDING: Undefined; MATERIAL: S275; NAME: LIGGER
Tekla Common - Bottom elevation: +3.390; Top elevation: +3.640; Phase: 1; Class: 5
Tekla Quantity - Weight: 8.8 kg; Volume: 0.001 m3; Gross footprint area: 0.05 m2; Area per tons: 26.568 m2; Net surface area: 0.234 m2; Height: 250 mm; Width: 200 mm; Length: 250 mm
CPset_Phasing - Renovation Phase: Bestaand
AC_Pset_RenovationAndPhasing - Renovation Status: Existing
Material Properties - STEEL/S275, ThermalConductivity: 2.3; STEEL/S275, SpecificHeatCapacity: 1000 J/kg/K; STEEL/S275, MassDensity: 2300 kg/m3; STEEL/S275, Embodied Energy: 1.92 (MJ/kg); STEEL/S275, Embodied Carbon: 0.198 (kgCO₂/kg); STEEL/S275, Name: STEEL/S275; STEEL/S275, Participates in Collision Detection: yes
BaseQuantities - NetSurfaceAreaExtrudedSides: 0.223323 m2; Length: 250 mm; CrossSectionArea: 0.00444829 m2; OuterSurfaceArea: 0.223323 m2; TotalSurfaceArea: 0.23222 m2; GrossSurfaceArea: 0.23222 m2; GrossVolume: 0.00111406 m3; NetSurfaceArea: 0.23222 m2; NetVolume: 0.00111406 m3
Component Quantities - STEEL/S275, Mass: 2.56234 kg; STEEL/S275, Component Cross Section Area: 0.00444829 m2; STEEL/S275, Component Volume (Net): 0.00111406 m3; STEEL/S275, Component Volume (Gross): 0.00111406 m3

# IfcBeam: BENDED_L350*250*16 (2)
In: Begane grond
Description: BENDED_L350*250*16; Classification: Balk (ARCHICAD Classification); Material: STEEL/S275
Default - NL-SfB_DESCRIPTION: Kolom-/Liggerconstructie staal; NL-SfB_NUMBERCODE: 28.11.21; IS_EXTERNAL: Nee; LOAD_BEARING: Ondersteuning; FIRE_RATING: R0; IFC_CLASS_REF_CODE: 28.11.21 ; Kolom-/Liggerconstructie staal; IFC_BUILDING_STOREY: Undefined; IFC_BUILDING: Undefined; MATERIAL: S275; NAME: LIGGER
Tekla Common - Phase: 1; Class: 5
Tekla Quantity - Weight: 22.43 kg; Volume: 0.003 m3; Area per tons: 16.886 m2; Net surface area: 0.379 m2; Height: 350 mm; Width: 250 mm; Length: 300 mm
Pset_BeamCommon - FireRating: R0; Reference: LIL0(?); Slope: 0 deg; LoadBearing: yes; IsExternal: no
CPset_Phasing - Renovation Phase: Bestaand
AC_Pset_RenovationAndPhasing - Renovation Status: Existing
Material Properties - STEEL/S275, ThermalConductivity: 2.3; STEEL/S275, SpecificHeatCapacity: 1000 J/kg/K; STEEL/S275, MassDensity: 2300 kg/m3; STEEL/S275, Embodied Energy: 1.92 (MJ/kg); STEEL/S275, Embodied Carbon: 0.198 (kgCO₂/kg); STEEL/S275, Name: STEEL/S275; STEEL/S275, Participates in Collision Detection: yes
BaseQuantities - NetSurfaceAreaExtrudedSides: 0.356769 m2; Length: 299.99 mm; CrossSectionArea: 0.00946761 m2; OuterSurfaceArea: 0.356769 m2; TotalSurfaceArea: 0.375704 m2; GrossSurfaceArea: 0.375704 m2; GrossVolume: 0.00284631 m3; NetSurfaceArea: 0.375704 m2; NetVolume: 0.00284631 m3
Component Quantities - STEEL/S275, Mass: 6.5465 kg; STEEL/S275, Component Cross Section Area: 0.00946761 m2; STEEL/S275, Component Volume (Net): 0.00284631 m3; STEEL/S275, Component Volume (Gross): 0.00284631 m3
Name | Bottom elevation | Top elevation | Gross footprint area (m2)
LIGGER | +3.260 | +3.610 | 0.005
LIGGER | +3.320 | +3.670 | 0.075

# IfcBeam: HEA160 (12)
In: Begane grond
Description: HEA160; Classification: Balk (ARCHICAD Classification); Material: STEEL/S235
Default - NL-SfB_DESCRIPTION: Kolom-/Liggerconstructie staal; NL-SfB_NUMBERCODE: 28.11.21; IS_EXTERNAL: Nee; LOAD_BEARING: Ondersteuning; FIRE_RATING: R30; IFC_CLASS_REF_CODE: 28.11.21 ; Kolom-/Liggerconstructie staal; IFC_BUILDING_STOREY: Undefined; IFC_BUILDING: Undefined; MATERIAL: S235; NAME: LIGGER
Pset_BeamCommon - FireRating: R30; Slope: 0 deg; LoadBearing: yes; IsExternal: no
Tekla Common - Bottom elevation: +6.548; Top elevation: +6.700; Phase: 1; Class: 5
Tekla Quantity - Area per tons: 29.212 m2; Height: 152 mm; Width: 160 mm
CPset_Phasing - Renovation Phase: Bestaand
AC_Pset_RenovationAndPhasing - Renovation Status: Existing
Material Properties - STEEL/S235, ThermalConductivity: 2.3; STEEL/S235, SpecificHeatCapacity: 1000 J/kg/K; STEEL/S235, MassDensity: 2300 kg/m3; STEEL/S235, Embodied Energy: 1.92 (MJ/kg); STEEL/S235, Embodied Carbon: 0.198 (kgCO₂/kg); STEEL/S235, Name: STEEL/S235; STEEL/S235, Participates in Collision Detection: yes
BaseQuantities - CrossSectionArea: 0.00387714 m2
Component Quantities - STEEL/S235, Component Cross Section Area: 0.00387714 m2
Name | Reference | Weight (kg) | Volume (m3) | Gross footprint area (m2) | Net surface area (m2) | Tekla Quantity, Length (mm) | NetSurfaceAreaExtrudedSides (m2) = OuterSurfaceArea (m2) | BaseQuantities, Length (mm) | TotalSurfaceArea (m2) = GrossSurfaceArea (m2) = NetSurfaceArea (m2) | GrossVolume (m3) | NetVolume (m3) = STEEL/S235, Component Volume (Net) (m3) = STEEL/S235, Component Volume (Gross) (m3) | STEEL/S235, Mass (kg)
LIGGER | LIH0(?) | 165.47 | 0.021 | 0.854 | 4.98 | 5335 | 4.82911 | 5415 | 4.83686 | 0.0208545 | 0.0208545 | 47.9654
LIGGER | LIH0(?) | 87.78 | 0.011 | 0.453 | 2.645 | 2830 | 2.5612 | 2830 | 2.56895 | 0.0110625 | 0.0110611 | 25.4406
LIGGER | liH0(?) | 77.85 | 0.009 | 0.402 | 2.347 | 2510 | 2.27051 | 2510 | 2.27827 | 0.00981159 | 0.00980683 | 22.5557
LIGGER | liH0(?) | 164.38 | 0.021 | 0.848 | 4.947 | 5300 | 4.79539 | 5300 | 4.80314 | 0.0207177 | 0.0207112 | 47.6359
LIGGER | liH0(?) | 164.39 | 0.021 | 0.848 | 4.947 | 5300 | 4.79541 | 5300.03 | 4.80317 | 0.0207178 | 0.0207114 | 47.6361
LIGGER | LIH0(?) | 77.85 | 0.009 | 0.402 | 2.347 | 2510 | 2.27144 | 2510 | 2.27919 | 0.00981159 | 0.00980994 | 22.5629
LIGGER | LIH0(?) | 87.62 | 0.011 | 0.452 | 2.64 | 2825 | 2.55571 | 2904.97 | 2.56346 | 0.0110428 | 0.0110383 | 25.3881
LIGGER | LIH0(?) | 380.57 | 0.048 | 1.963 | 11.443 | 12270 | 11.1065 | 12430 | 11.1143 | 0.0479635 | 0.0479635 | 110.316
LIGGER | liH0(?) | 164.38 | 0.021 | 0.848 | 4.947 | 5300 | 4.79537 | 5299.99 | 4.80312 | 0.0207177 | 0.0207112 | 47.6357
LIGGER | LIH0(?) | 164.39 | 0.021 | 0.848 | 4.947 | 5300 | 4.79744 | 5300.01 | 4.80519 | 0.0207177 | 0.0207177 | 47.6508
LIGGER | LIH0(?) | 165.63 | 0.021 | 0.854 | 4.984 | 5340 | 4.83363 | 5340 | 4.84139 | 0.0208741 | 0.0208741 | 48.0103
LIGGER | LIH0(?) | 380.57 | 0.048 | 1.963 | 11.443 | 12270 | 11.1019 | 12430 | 11.1097 | 0.0484351 | 0.0479254 | 110.228

# IfcBeam: IPE240 (27)
In: Begane grond
Description: IPE240; Classification: Balk (ARCHICAD Classification); Material: STEEL/S235
Default - NL-SfB_DESCRIPTION: Kolom-/Liggerconstructie staal; NL-SfB_NUMBERCODE: 28.11.21; IS_EXTERNAL: Nee; LOAD_BEARING: Ondersteuning; FIRE_RATING: R0; IFC_CLASS_REF_CODE: 28.11.21 ; Kolom-/Liggerconstructie staal; IFC_BUILDING_STOREY: Undefined; IFC_BUILDING: Undefined; MATERIAL: S235; NAME: LIGGER
Pset_BeamCommon - FireRating: R0; Slope: 0 deg; LoadBearing: yes; IsExternal: no
Tekla Common - Phase: 1; Class: 5
Tekla Quantity - Area per tons: 29.404 m2; Height: 240 mm; Width: 120 mm
CPset_Phasing - Renovation Phase: Bestaand
AC_Pset_RenovationAndPhasing - Renovation Status: Existing
Material Properties - STEEL/S235, ThermalConductivity: 2.3; STEEL/S235, SpecificHeatCapacity: 1000 J/kg/K; STEEL/S235, MassDensity: 2300 kg/m3; STEEL/S235, Embodied Energy: 1.92 (MJ/kg); STEEL/S235, Embodied Carbon: 0.198 (kgCO₂/kg); STEEL/S235, Name: STEEL/S235; STEEL/S235, Participates in Collision Detection: yes
BaseQuantities - CrossSectionArea: 0.00391162 m2
Component Quantities - STEEL/S235, Component Cross Section Area: 0.00391162 m2
Name | Reference | Bottom elevation | Top elevation | Weight (kg) | Volume (m3) | Gross footprint area (m2) | Net surface area (m2) | Tekla Quantity, Length (mm) | NetSurfaceAreaExtrudedSides (m2) = OuterSurfaceArea (m2) | BaseQuantities, Length (mm) | TotalSurfaceArea (m2) = GrossSurfaceArea (m2) = NetSurfaceArea (m2) | GrossVolume (m3) | NetVolume (m3) = STEEL/S235, Component Volume (Net) (m3) = STEEL/S235, Component Volume (Gross) (m3) | STEEL/S235, Mass (kg)
LIGGER | liH0(?) | +4.215 | +4.455 | 610.11 | 0.076 | 2.34 | 18.486 | 19499.9 | 17.8882 | 19499.9 | 17.896 | 0.0768975 | 0.0766309 | 176.251
5 x LIGGER | LII0(?) | +4.240 | +4.480 | 164.26 | 0.021 | 0.63 | 4.982 | 5250.1 | 4.83411 | 5250.05 | 4.84194 | 0.0207035 | 0.0207035 | 47.618
LIGGER | liH0(?) | +3.680 | +3.920 | 32.3 | 0.004 | 0.124 | 0.986 | 1032.5 | 0.879949 | 1032.5 | 0.887773 | 0.00407164 | 0.00369869 | 8.50699
LIGGER | liH0(?) | +3.680 | +3.920 | 32.6 | 0.004 | 0.125 | 0.995 | 1042 | 0.879948 | 1032.5 | 0.887771 | 0.00410911 | 0.00369869 | 8.50698
LIGGER | liH0(?) | +3.680 | +3.920 | 138.06 | 0.017 | 0.53 | 4.189 | 4412.7 | 4.0631 | 4412.7 | 4.07093 | 0.0174014 | 0.0174014 | 40.0232
LIGGER | LIH0(?) | +3.680 | +3.920 | 93.61 | 0.012 | 0.359 | 2.843 | 2992 | 2.75496 | 2992 | 2.76278 | 0.0117989 | 0.0117989 | 27.1375
7 x LIGGER | liH0(?) | +3.680 | +3.920 | 116.89 | 0.015 | 0.448 | 3.548 | 3736 | 3.44003 | 3736.02 | 3.44786 | 0.0147329 | 0.0147329 | 33.8857
LIGGER | LII0(?) | +3.660 | +3.900 | 132.97 | 0.017 | 0.51 | 4.035 | 4250 | 3.91329 | 4250 | 3.92112 | 0.0167598 | 0.0167598 | 38.5475
2 x LIGGER | LIH0(?) | +3.680 | +3.920 | 55.71 | 0.007 | 0.214 | 1.695 | 1780.5 | 1.6394 | 1780.46 | 1.64723 | 0.00702121 | 0.00702121 | 16.1488
LIGGER | liH0(?) | +3.680 | +3.920 | 115.33 | 0.013 | 0.442 | 3.5 | 3686 | 3.39399 | 3728.52 | 3.40182 | 0.0145357 | 0.0145357 | 33.4322
LIGGER | liH0(?) | +3.680 | +3.920 | 62.58 | 0.008 | 0.24 | 1.903 | 2000 | 1.79745 | 1990.5 | 1.80527 | 0.00788696 | 0.00766314 | 17.6252
LIGGER | liH0(?) | +3.680 | +3.920 | 32.84 | 0.004 | 0.126 | 1.002 | 1049.5 | 0.966353 | 1049.5 | 0.974176 | 0.00413868 | 0.00413868 | 9.51897
4 x LIGGER | liI0(?) | +4.215 | +4.455 | 73.59 | 0.009 | 0.282 | 2.236 | 2352 | 2.16564 | 2351.98 | 2.17347 | 0.00927499 | 0.00927499 | 21.3325

# IfcBeam: IPE450 (3)
In: Begane grond
Description: IPE450; Classification: Balk (ARCHICAD Classification); Material: STEEL/S235
Default - NL-SfB_DESCRIPTION: Kolom-/Liggerconstructie staal; NL-SfB_NUMBERCODE: 28.11.21; IS_EXTERNAL: Nee; LOAD_BEARING: Ondersteuning; FIRE_RATING: R30; IFC_CLASS_REF_CODE: 28.11.21 ; Kolom-/Liggerconstructie staal; IFC_BUILDING_STOREY: Undefined; IFC_BUILDING: Undefined; MATERIAL: S235; NAME: LIGGER
Tekla Common - Bottom elevation: +4.245; Top elevation: +4.695; Phase: 1; Class: 5
Tekla Quantity - Area per tons: 20.302 m2; Height: 450 mm; Width: 190 mm
Pset_BeamCommon - FireRating: R30; Slope: 0 deg; LoadBearing: yes; IsExternal: no
CPset_Phasing - Renovation Phase: Bestaand
AC_Pset_RenovationAndPhasing - Renovation Status: Existing
Material Properties - STEEL/S235, ThermalConductivity: 2.3; STEEL/S235, SpecificHeatCapacity: 1000 J/kg/K; STEEL/S235, MassDensity: 2300 kg/m3; STEEL/S235, Embodied Energy: 1.92 (MJ/kg); STEEL/S235, Embodied Carbon: 0.198 (kgCO₂/kg); STEEL/S235, Name: STEEL/S235; STEEL/S235, Participates in Collision Detection: yes
BaseQuantities - CrossSectionArea: 0.00988208 m2
Component Quantities - STEEL/S235, Component Cross Section Area: 0.00988208 m2
Name | Weight (kg) | Volume (m3) | Gross footprint area (m2) | Net surface area (m2) | Tekla Quantity, Length (mm) | Reference | NetSurfaceAreaExtrudedSides (m2) = OuterSurfaceArea (m2) | BaseQuantities, Length (mm) | TotalSurfaceArea (m2) = GrossSurfaceArea (m2) = NetSurfaceArea (m2) | GrossVolume (m3) | NetVolume (m3) = STEEL/S235, Component Volume (Net) (m3) = STEEL/S235, Component Volume (Gross) (m3) | STEEL/S235, Mass (kg)
LIGGER | 740.75 | 0.093 | 1.78 | 15.396 | 9370 | liI0(?) | 15.0029 | 9370 | 15.0226 | 0.0931802 | 0.0930286 | 213.966
LIGGER | 790.16 | 0.099 | 1.899 | 16.423 | 9994.9 | liI0(?) | 16.0283 | 9994.92 | 16.0481 | 0.0993947 | 0.0993947 | 228.608
LIGGER | 1541.59 | 0.193 | 3.705 | 32.022 | 19499.9 | liH0(?) | 31.2616 | 19499.9 | 31.2814 | 0.193917 | 0.193862 | 445.883

# IfcBeam: KW140/6.3 (4)
In: Begane grond
Description: KW140/6.3; Classification: Balk (ARCHICAD Classification); Material: STEEL/S235
Default - NL-SfB_DESCRIPTION: Kolom-/Liggerconstructie staal; NL-SfB_NUMBERCODE: 28.11.21; IS_EXTERNAL: Nee; LOAD_BEARING: Ondersteuning; FIRE_RATING: R30; IFC_CLASS_REF_CODE: 28.11.21 ; Kolom-/Liggerconstructie staal; IFC_BUILDING_STOREY: Undefined; IFC_BUILDING: Undefined; MATERIAL: S235; NAME: LIGGER
Tekla Common - Bottom elevation: +4.555; Top elevation: +4.695; Phase: 1; Class: 5
Tekla Quantity - Area per tons: 20.42 m2; Height: 140 mm; Width: 140 mm
Pset_BeamCommon - FireRating: R30; Slope: 0 deg; LoadBearing: yes; IsExternal: no
CPset_Phasing - Renovation Phase: Bestaand
AC_Pset_RenovationAndPhasing - Renovation Status: Existing
Material Properties - STEEL/S235, ThermalConductivity: 2.3; STEEL/S235, SpecificHeatCapacity: 1000 J/kg/K; STEEL/S235, MassDensity: 2300 kg/m3; STEEL/S235, Embodied Energy: 1.92 (MJ/kg); STEEL/S235, Embodied Carbon: 0.198 (kgCO₂/kg); STEEL/S235, Name: STEEL/S235; STEEL/S235, Participates in Collision Detection: yes
BaseQuantities - CrossSectionArea: 0.0033011 m2
Component Quantities - STEEL/S235, Component Cross Section Area: 0.0033011 m2
Name | Weight (kg) | Volume (m3) | Gross footprint area (m2) | Net surface area (m2) | Tekla Quantity, Length (mm) | Reference | NetSurfaceAreaExtrudedSides (m2) = OuterSurfaceArea (m2) | BaseQuantities, Length (mm) | TotalSurfaceArea (m2) = GrossSurfaceArea (m2) = NetSurfaceArea (m2) | GrossVolume (m3) | NetVolume (m3) = STEEL/S235, Component Volume (Net) (m3) = STEEL/S235, Component Volume (Gross) (m3) | STEEL/S235, Mass (kg)
LIGGER | 139.54 | 0.017 | 0.733 | 2.937 | 5238 | liH0(?) | 5.47642 | 5238 | 5.48303 | 0.0171609 | 0.0171538 | 39.4538
LIGGER | 140.23 | 0.019 | 0.737 | 2.951 | 5264 | liH0(?) | 5.50312 | 5264 | 5.50972 | 0.0172461 | 0.0172375 | 39.6461
LIGGER | 65.67 | 0.008 | 0.345 | 1.384 | 2465 | LIH0(?) | 2.57633 | 2465 | 2.58293 | 0.00807593 | 0.00806984 | 18.5606
LIGGER | 142.9 | 0.019 | 0.751 | 3.007 | 5364 | liH0(?) | 5.6077 | 5364.02 | 5.61431 | 0.0175738 | 0.017565 | 40.3996

# IfcBeam: KW200*100*6.3, LIGGER
In: Begane grond
Description: KW200*100*6.3; Classification: Balk (ARCHICAD Classification); Material: STEEL/S275
Pset_BeamCommon - FireRating: R0; Reference: LIK0(?); Slope: 0 deg; LoadBearing: yes; IsExternal: no
Default - NL-SfB_DESCRIPTION: Kolom-/Liggerconstructie staal; NL-SfB_NUMBERCODE: 28.11.21; IS_EXTERNAL: Nee; LOAD_BEARING: Ondersteuning; FIRE_RATING: R0; IFC_CLASS_REF_CODE: 28.11.21 ; Kolom-/Liggerconstructie staal; IFC_BUILDING_STOREY: Undefined; IFC_BUILDING: Undefined; MATERIAL: S275; NAME: LIGGER
Tekla Common - Bottom elevation: +3.340; Top elevation: +3.540; Phase: 1; Class: 5
Tekla Quantity - Weight: 190.04 kg; Volume: 0.024 m3; Gross footprint area: 0.656 m2; Area per tons: 20.506 m2; Net surface area: 3.897 m2; Height: 200 mm; Width: 100 mm; Length: 6560 mm
CPset_Phasing - Renovation Phase: Bestaand
AC_Pset_RenovationAndPhasing - Renovation Status: Existing
Material Properties - STEEL/S275, ThermalConductivity: 2.3; STEEL/S275, SpecificHeatCapacity: 1000 J/kg/K; STEEL/S275, MassDensity: 2300 kg/m3; STEEL/S275, Embodied Energy: 1.92 (MJ/kg); STEEL/S275, Embodied Carbon: 0.198 (kgCO₂/kg); STEEL/S275, Name: STEEL/S275; STEEL/S275, Participates in Collision Detection: yes
BaseQuantities - NetSurfaceAreaExtrudedSides: 7.30866 m2; Length: 6560.01 mm; CrossSectionArea: 0.00351903 m2; OuterSurfaceArea: 7.30866 m2; TotalSurfaceArea: 7.3157 m2; GrossSurfaceArea: 7.3157 m2; GrossVolume: 0.0228403 m3; NetSurfaceArea: 7.3157 m2; NetVolume: 0.0228403 m3
Component Quantities - STEEL/S275, Mass: 52.5326 kg; STEEL/S275, Component Cross Section Area: 0.00351903 m2; STEEL/S275, Component Volume (Net): 0.0228403 m3; STEEL/S275, Component Volume (Gross): 0.0228403 m3

# IfcBeam: KW80/6.3 (14)
In: Begane grond
Description: KW80/6.3; Classification: Balk (ARCHICAD Classification)
Default - IS_EXTERNAL: Nee; FIRE_RATING: R30; IFC_BUILDING_STOREY: Undefined; IFC_BUILDING: Undefined
Tekla Common - Phase: 1
Tekla Quantity - Area per tons: 20.994 m2; Height: 80 mm; Width: 80 mm
Pset_BeamCommon - FireRating: R30; Slope: 0 deg; IsExternal: no
CPset_Phasing - Renovation Phase: Bestaand
AC_Pset_RenovationAndPhasing - Renovation Status: Existing
BaseQuantities - CrossSectionArea: 0.0017891 m2
Name | Material | LOAD_BEARING | MATERIAL | NAME | Bottom elevation | Top elevation | Class | Weight (kg) | Volume (m3) | Gross footprint area (m2) | Net surface area (m2) | Tekla Quantity, Length (mm) | Reference | LoadBearing | NetSurfaceAreaExtrudedSides (m2) = OuterSurfaceArea (m2) | BaseQuantities, Length (mm) | TotalSurfaceArea (m2) = GrossSurfaceArea (m2) = NetSurfaceArea (m2) | GrossVolume (m3) | NetVolume (m3) | NL-SfB_DESCRIPTION | NL-SfB_NUMBERCODE | IFC_CLASS_REF_CODE | STEEL/S275, ThermalConductivity | STEEL/S275, SpecificHeatCapacity (J/kg/K) | STEEL/S275, MassDensity (kg/m3) | STEEL/S275, Embodied Energy | STEEL/S275, Embodied Carbon | STEEL/S275, Name | STEEL/S275, Participates in Collision Detection | STEEL/S275, Mass (kg) | STEEL/S275, Component Cross Section Area (m2) | STEEL/S275, Component Volume (Net) (m3) = STEEL/S275, Component Volume (Gross) (m3)
DRUKKER | STEEL/S235JR | Nee | S235JR | DRUKKER | +2.710 | +2.790 | 10 | 73.82 | 0.009 | 0.408 | 1.633 | 5098 | P0(?) | no | 2.8852 | 5097.99 | 2.88878 | 0.00899408 | 0.00899408 | Material Properties - STEEL/S235JR, ThermalConductivity: 2.3; STEEL/S235JR, SpecificHeatCapacity: 1000 J/kg/K; STEEL/S235JR, MassDensity: 2300 kg/m3; STEEL/S235JR, Embodied Energy: 1.92 (MJ/kg); STEEL/S235JR, Embodied Carbon: 0.198 (kgCO₂/kg); STEEL/S235JR, Name: STEEL/S235JR; STEEL/S235JR, Participates in Collision Detection: yes; Component Quantities - STEEL/S235JR, Mass: 20.6864 kg; STEEL/S235JR, Component Cross Section Area: 0.0017891 m2; STEEL/S235JR, Component Volume (Net): 0.00899408 m3; STEEL/S235JR, Component Volume (Gross): 0.00899408 m3
DRUKKER | STEEL/S235JR | Nee | S235JR | DRUKKER | +2.710 | +2.790 | 10 | 85.91 | 0.011 | 0.475 | 1.901 | 5933 | P0(?) | no | 3.35777 | 5932.98 | 3.36134 | 0.0104672 | 0.0104672 | Material Properties - STEEL/S235JR, ThermalConductivity: 2.3; STEEL/S235JR, SpecificHeatCapacity: 1000 J/kg/K; STEEL/S235JR, MassDensity: 2300 kg/m3; STEEL/S235JR, Embodied Energy: 1.92 (MJ/kg); STEEL/S235JR, Embodied Carbon: 0.198 (kgCO₂/kg); STEEL/S235JR, Name: STEEL/S235JR; STEEL/S235JR, Participates in Collision Detection: yes; Component Quantities - STEEL/S235JR, Mass: 24.0746 kg; STEEL/S235JR, Component Cross Section Area: 0.0017891 m2; STEEL/S235JR, Component Volume (Net): 0.0104672 m3; STEEL/S235JR, Component Volume (Gross): 0.0104672 m3
DRUKKER | STEEL/S235JR | Nee | S235JR | DRUKKER | +2.710 | +2.790 | 10 | 73.82 | 0.009 | 0.408 | 1.633 | 5098 | P0(?) | no | 2.88522 | 5098.03 | 2.8888 | 0.00899415 | 0.00899415 | Material Properties - STEEL/S235JR, ThermalConductivity: 2.3; STEEL/S235JR, SpecificHeatCapacity: 1000 J/kg/K; STEEL/S235JR, MassDensity: 2300 kg/m3; STEEL/S235JR, Embodied Energy: 1.92 (MJ/kg); STEEL/S235JR, Embodied Carbon: 0.198 (kgCO₂/kg); STEEL/S235JR, Name: STEEL/S235JR; STEEL/S235JR, Participates in Collision Detection: yes; Component Quantities - STEEL/S235JR, Mass: 20.6865 kg; STEEL/S235JR, Component Cross Section Area: 0.0017891 m2; STEEL/S235JR, Component Volume (Net): 0.00899415 m3; STEEL/S235JR, Component Volume (Gross): 0.00899415 m3
DRUKKER | STEEL/S235JR | Nee | S235JR | DRUKKER | +2.710 | +2.790 | 10 | 85.94 | 0.011 | 0.475 | 1.901 | 5935 | P0(?) | no | 3.35891 | 5935.01 | 3.36249 | 0.0104708 | 0.0104708 | Material Properties - STEEL/S235JR, ThermalConductivity: 2.3; STEEL/S235JR, SpecificHeatCapacity: 1000 J/kg/K; STEEL/S235JR, MassDensity: 2300 kg/m3; STEEL/S235JR, Embodied Energy: 1.92 (MJ/kg); STEEL/S235JR, Embodied Carbon: 0.198 (kgCO₂/kg); STEEL/S235JR, Name: STEEL/S235JR; STEEL/S235JR, Participates in Collision Detection: yes; Component Quantities - STEEL/S235JR, Mass: 24.0828 kg; STEEL/S235JR, Component Cross Section Area: 0.0017891 m2; STEEL/S235JR, Component Volume (Net): 0.0104708 m3; STEEL/S235JR, Component Volume (Gross): 0.0104708 m3
LIGGER | STEEL/S275 | Ondersteuning | S235 | LIGGER | +4.615 | +4.695 | 5 | 76.22 | 0.009 | 0.421 | 1.686 | 5264 | liH0(?) | yes | 2.9714 | 5264 | 2.97498 | 0.00928696 | 0.00926254 | Kolom-/Liggerconstructie staal | 28.11.21 | 28.11.21 ; Kolom-/Liggerconstructie staal | 2.3 | 1000 | 2300 | 1.92 (MJ/kg) | 0.198 (kgCO₂/kg) | STEEL/S275 | yes | 21.3038 | 0.0017891 | 0.00926254
LIGGER | STEEL/S275 | Ondersteuning | S235 | LIGGER | +4.615 | +4.695 | 5 | 76.22 | 0.009 | 0.421 | 1.686 | 5264 | liH0(?) | yes | 2.97091 | 5264 | 2.97449 | 0.00928696 | 0.00926098 | Kolom-/Liggerconstructie staal | 28.11.21 | 28.11.21 ; Kolom-/Liggerconstructie staal | 2.3 | 1000 | 2300 | 1.92 (MJ/kg) | 0.198 (kgCO₂/kg) | STEEL/S275 | yes | 21.3003 | 0.0017891 | 0.00926098
LIGGER | STEEL/S275 | Ondersteuning | S235 | LIGGER | +4.615 | +4.695 | 5 | 35.69 | 0.004 | 0.197 | 0.791 | 2465 | LIH0(?) | yes | 1.39313 | 2465 | 1.39671 | 0.00434885 | 0.00434276 | Kolom-/Liggerconstructie staal | 28.11.21 | 28.11.21 ; Kolom-/Liggerconstructie staal | 2.3 | 1000 | 2300 | 1.92 (MJ/kg) | 0.198 (kgCO₂/kg) | STEEL/S275 | yes | 9.98835 | 0.0017891 | 0.00434276
LIGGER | STEEL/S275 | Ondersteuning | S235 | LIGGER | +4.615 | +4.695 | 5 | 77.67 | 0.009 | 0.429 | 1.719 | 5364 | liH0(?) | yes | 3.03297 | 5364.02 | 3.03655 | 0.00946342 | 0.00945464 | Kolom-/Liggerconstructie staal | 28.11.21 | 28.11.21 ; Kolom-/Liggerconstructie staal | 2.3 | 1000 | 2300 | 1.92 (MJ/kg) | 0.198 (kgCO₂/kg) | STEEL/S275 | yes | 21.7457 | 0.0017891 | 0.00945464
LIGGER | STEEL/S275 | Ondersteuning | S235 | LIGGER | +4.620 | +4.700 | 5 | 77.67 | 0.009 | 0.429 | 1.719 | 5364 | liI0(?) | yes | 3.03576 | 5364.02 | 3.03934 | 0.00946342 | 0.00946342 | Kolom-/Liggerconstructie staal | 28.11.21 | 28.11.21 ; Kolom-/Liggerconstructie staal | 2.3 | 1000 | 2300 | 1.92 (MJ/kg) | 0.198 (kgCO₂/kg) | STEEL/S275 | yes | 21.7659 | 0.0017891 | 0.00946342
LIGGER | STEEL/S275 | Ondersteuning | S235 | LIGGER | +4.620 | +4.700 | 5 | 35.69 | 0.004 | 0.197 | 0.791 | 2465 | LII0(?) | yes | 1.39506 | 2465 | 1.39864 | 0.00434885 | 0.00434885 | Kolom-/Liggerconstructie staal | 28.11.21 | 28.11.21 ; Kolom-/Liggerconstructie staal | 2.3 | 1000 | 2300 | 1.92 (MJ/kg) | 0.198 (kgCO₂/kg) | STEEL/S275 | yes | 10.0024 | 0.0017891 | 0.00434885
LIGGER | STEEL/S275 | Ondersteuning | S275 | LIGGER | +6.620 | +6.700 | 5 | 74.79 | 0.009 | 0.413 | 1.655 | 5165 | LIK0(?) | yes | 2.92014 | 5164.99 | 2.92372 | 0.00911232 | 0.00910297 | Kolom-/Liggerconstructie staal | 28.11.21 | 28.11.21 ; Kolom-/Liggerconstructie staal | 2.3 | 1000 | 2300 | 1.92 (MJ/kg) | 0.198 (kgCO₂/kg) | STEEL/S275 | yes | 20.9368 | 0.0017891 | 0.00910297
LIGGER | STEEL/S275 | Ondersteuning | S275 | LIGGER | +6.620 | +6.700 | 5 | 74.43 | 0.009 | 0.411 | 1.646 | 5140 | liK0(?) | yes | 2.9015 | 5140 | 2.90508 | 0.0090682 | 0.00904479 | Kolom-/Liggerconstructie staal | 28.11.21 | 28.11.21 ; Kolom-/Liggerconstructie staal | 2.3 | 1000 | 2300 | 1.92 (MJ/kg) | 0.198 (kgCO₂/kg) | STEEL/S275 | yes | 20.803 | 0.0017891 | 0.00904479
LIGGER | STEEL/S275 | Ondersteuning | S275 | LIGGER | +6.620 | +6.700 | 5 | 74.43 | 0.009 | 0.411 | 1.646 | 5140 | liK0(?) | yes | 2.90522 | 5139.99 | 2.9088 | 0.0090682 | 0.00905642 | Kolom-/Liggerconstructie staal | 28.11.21 | 28.11.21 ; Kolom-/Liggerconstructie staal | 2.3 | 1000 | 2300 | 1.92 (MJ/kg) | 0.198 (kgCO₂/kg) | STEEL/S275 | yes | 20.8298 | 0.0017891 | 0.00905642
LIGGER | STEEL/S275 | Ondersteuning | S275 | LIGGER | +6.620 | +6.700 | 5 | 74.86 | 0.009 | 0.414 | 1.656 | 5170 | liK0(?) | yes | 2.92221 | 5170 | 2.92578 | 0.00912112 | 0.00910938 | Kolom-/Liggerconstructie staal | 28.11.21 | 28.11.21 ; Kolom-/Liggerconstructie staal | 2.3 | 1000 | 2300 | 1.92 (MJ/kg) | 0.198 (kgCO₂/kg) | STEEL/S275 | yes | 20.9516 | 0.0017891 | 0.00910938

# IfcBeam: L100/65/10 (10)
In: Begane grond
Description: L100/65/10; Classification: Balk (ARCHICAD Classification); Material: STEEL/S275
Pset_BeamCommon - FireRating: R30; Reference: LIL0(?); Slope: 0 deg; LoadBearing: yes; IsExternal: no
Default - NL-SfB_DESCRIPTION: Kolom-/Liggerconstructie staal; NL-SfB_NUMBERCODE: 28.11.21; IS_EXTERNAL: Nee; LOAD_BEARING: Ondersteuning; FIRE_RATING: R30; IFC_CLASS_REF_CODE: 28.11.21 ; Kolom-/Liggerconstructie staal; IFC_BUILDING_STOREY: Undefined; IFC_BUILDING: Undefined; MATERIAL: S275; NAME: LIGGER
Tekla Common - Bottom elevation: +3.335; Top elevation: +3.400; Phase: 1; Class: 5
Tekla Quantity - Area per tons: 26.613 m2; Height: 100 mm; Width: 65 mm
CPset_Phasing - Renovation Phase: Bestaand
AC_Pset_RenovationAndPhasing - Renovation Status: Existing
Material Properties - STEEL/S275, ThermalConductivity: 2.3; STEEL/S275, SpecificHeatCapacity: 1000 J/kg/K; STEEL/S275, MassDensity: 2300 kg/m3; STEEL/S275, Embodied Energy: 1.92 (MJ/kg); STEEL/S275, Embodied Carbon: 0.198 (kgCO₂/kg); STEEL/S275, Name: STEEL/S275; STEEL/S275, Participates in Collision Detection: yes
BaseQuantities - CrossSectionArea: 0.00156073 m2
Component Quantities - STEEL/S275, Component Cross Section Area: 0.00156073 m2
Name | Weight (kg) | Volume (m3) | Gross footprint area (m2) | Net surface area (m2) | Tekla Quantity, Length (mm) = BaseQuantities, Length (mm) | NetSurfaceAreaExtrudedSides (m2) = OuterSurfaceArea (m2) | TotalSurfaceArea (m2) = GrossSurfaceArea (m2) = NetSurfaceArea (m2) | GrossVolume (m3) = NetVolume (m3) = STEEL/S275, Component Volume (Net) (m3) = STEEL/S275, Component Volume (Gross) (m3) | STEEL/S275, Mass (kg)
2 x LIGGER | 645.67 | 0.081 | 5.207 | 17.186 | 52070 | 16.6944 | 16.6975 | 0.0814711 | 187.383
2 x LIGGER | 321.16 | 0.04 | 2.59 | 8.55 | 25900 | 8.30392 | 8.30704 | 0.0405243 | 93.2059
2 x LIGGER | 271.24 | 0.034 | 2.187 | 7.222 | 21874 | 7.01314 | 7.01626 | 0.0342251 | 78.7177
2 x LIGGER | 364.54 | 0.046 | 2.94 | 9.704 | 29398 | 9.42544 | 9.42856 | 0.0459975 | 105.794
2 x LIGGER | 233.99 | 0.03 | 1.887 | 6.23 | 18870 | 6.05 | 6.05312 | 0.0295248 | 67.9071

# IfcBeam: L150/100/10 (7)
In: Begane grond
Description: L150/100/10; Classification: Balk (ARCHICAD Classification); Material: STEEL/S275
Default - IS_EXTERNAL: Nee; LOAD_BEARING: Ondersteuning; FIRE_RATING: R30; IFC_BUILDING_STOREY: Undefined; IFC_BUILDING: Undefined; MATERIAL: S275; NAME: LIGGER
Pset_BeamCommon - FireRating: R30; Reference: LIL0(?); LoadBearing: yes; IsExternal: no
Tekla Common - Bottom elevation: +0.460; Phase: 1; Class: 5
Tekla Quantity - Weight: 24.96 kg; Volume: 0.003 m3; Area per tons: 26.042 m2; Net surface area: 0.655 m2; Height: 150 mm; Width: 100 mm; Length: 1300 mm
CPset_Phasing - Renovation Phase: Bestaand
AC_Pset_RenovationAndPhasing - Renovation Status: Existing
Material Properties - STEEL/S275, ThermalConductivity: 2.3; STEEL/S275, SpecificHeatCapacity: 1000 J/kg/K; STEEL/S275, MassDensity: 2300 kg/m3; STEEL/S275, Embodied Energy: 1.92 (MJ/kg); STEEL/S275, Embodied Carbon: 0.198 (kgCO₂/kg); STEEL/S275, Name: STEEL/S275; STEEL/S275, Participates in Collision Detection: yes
BaseQuantities - CrossSectionArea: 0.00241813 m2
Component Quantities - STEEL/S275, Component Cross Section Area: 0.00241813 m2
Name | Slope (deg) | Top elevation | Gross footprint area (m2) | NetSurfaceAreaExtrudedSides (m2) = OuterSurfaceArea (m2) | Length (mm) | TotalSurfaceArea (m2) = GrossSurfaceArea (m2) = NetSurfaceArea (m2) | GrossVolume (m3) = NetVolume (m3) = STEEL/S275, Component Volume (Net) (m3) = STEEL/S275, Component Volume (Gross) (m3) | STEEL/S275, Mass (kg)
3 x LIGGER | 0.143239 | +0.613 | 0 | 0.634519 | 1300.01 | 0.639355 | 0.00314277 | 7.22838
3 x LIGGER | -0.143239 | +0.613 | 0 | 0.634519 | 1300.01 | 0.639355 | 0.00314277 | 7.22838
LIGGER | 0 | +0.610 | 0.013 | 0.634514 | 1300 | 0.63935 | 0.00314275 | 7.22833

# IfcBeam: L200/100/10 (24)
In: Begane grond
Description: L200/100/10; Classification: Balk (ARCHICAD Classification); Material: STEEL/S275
Pset_BeamCommon - FireRating: R30; Reference: LIL0(?); Slope: 0 deg; LoadBearing: yes; IsExternal: no
Default - NL-SfB_DESCRIPTION: Kolom-/Liggerconstructie staal; NL-SfB_NUMBERCODE: 28.11.21; IS_EXTERNAL: Nee; LOAD_BEARING: Ondersteuning; FIRE_RATING: R30; IFC_CLASS_REF_CODE: 28.11.21 ; Kolom-/Liggerconstructie staal; IFC_BUILDING_STOREY: Undefined; IFC_BUILDING: Undefined; MATERIAL: S275; NAME: LIGGER
Tekla Common - Bottom elevation: +3.390; Top elevation: +3.590; Phase: 1; Class: 5
Tekla Quantity - Weight: 26.45 kg; Volume: 0.003 m3; Gross footprint area: 0.011 m2; Area per tons: 25.862 m2; Net surface area: 0.69 m2; Height: 200 mm; Width: 100 mm; Length: 1140 mm
CPset_Phasing - Renovation Phase: Bestaand
AC_Pset_RenovationAndPhasing - Renovation Status: Existing
Material Properties - STEEL/S275, ThermalConductivity: 2.3; STEEL/S275, SpecificHeatCapacity: 1000 J/kg/K; STEEL/S275, MassDensity: 2300 kg/m3; STEEL/S275, Embodied Energy: 1.92 (MJ/kg); STEEL/S275, Embodied Carbon: 0.198 (kgCO₂/kg); STEEL/S275, Name: STEEL/S275; STEEL/S275, Participates in Collision Detection: yes
BaseQuantities - NetSurfaceAreaExtrudedSides: 0.66833 m2; Length: 1140 mm; CrossSectionArea: 0.00292414 m2; OuterSurfaceArea: 0.66833 m2; TotalSurfaceArea: 0.674179 m2; GrossSurfaceArea: 0.674179 m2; GrossVolume: 0.00333256 m3; NetSurfaceArea: 0.674179 m2; NetVolume: 0.00333256 m3
Component Quantities - STEEL/S275, Mass: 7.66489 kg; STEEL/S275, Component Cross Section Area: 0.00292414 m2; STEEL/S275, Component Volume (Net): 0.00333256 m3; STEEL/S275, Component Volume (Gross): 0.00333256 m3

# IfcBeam: L60/6 (10)
In: Begane grond
Description: L60/6; Classification: Balk (ARCHICAD Classification); Material: STEEL/S235
Default - NL-SfB_DESCRIPTION: Kolom-/Liggerconstructie staal; NL-SfB_NUMBERCODE: 28.11.21; IS_EXTERNAL: Nee; LOAD_BEARING: Ondersteuning; FIRE_RATING: R30; IFC_CLASS_REF_CODE: 28.11.21 ; Kolom-/Liggerconstructie staal; IFC_BUILDING_STOREY: Undefined; IFC_BUILDING: Undefined; MATERIAL: S235; NAME: WINDVERBAND
Pset_BeamCommon - FireRating: R30; LoadBearing: yes; IsExternal: no
Tekla Common - Phase: 1; Class: 13
Tekla Quantity - Volume: 0.005 m3; Gross footprint area: 0 m2; Area per tons: 43.428 m2; Height: 60 mm; Width: 60 mm
CPset_Phasing - Renovation Phase: Bestaand
AC_Pset_RenovationAndPhasing - Renovation Status: Existing
Material Properties - STEEL/S235, ThermalConductivity: 2.3; STEEL/S235, SpecificHeatCapacity: 1000 J/kg/K; STEEL/S235, MassDensity: 2300 kg/m3; STEEL/S235, Embodied Energy: 1.92 (MJ/kg); STEEL/S235, Embodied Carbon: 0.198 (kgCO₂/kg); STEEL/S235, Name: STEEL/S235; STEEL/S235, Participates in Collision Detection: yes
BaseQuantities - CrossSectionArea: 0.000690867 m2
Component Quantities - STEEL/S235, Component Cross Section Area: 0.000690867 m2
Name | Reference | Slope (deg) | Bottom elevation | Top elevation | Weight (kg) | Net surface area (m2) | Tekla Quantity, Length (mm) | NetSurfaceAreaExtrudedSides (m2) = OuterSurfaceArea (m2) | BaseQuantities, Length (mm) | TotalSurfaceArea (m2) = GrossSurfaceArea (m2) = NetSurfaceArea (m2) | GrossVolume (m3) = NetVolume (m3) = STEEL/S235, Component Volume (Net) (m3) = STEEL/S235, Component Volume (Gross) (m3) | STEEL/S235, Mass (kg)
WINDVERBAND | MLO0(?) | -0.262701 | +6.559 | +6.655 | 42.54 | 1.849 | 7697.6 | 1.78962 | 7697.56 | 1.791 | 0.00533728 | 12.2757
WINDVERBAND | MLO0(?) | 0.258542 | +6.629 | +6.725 | 43.79 | 1.903 | 7923.2 | 1.84209 | 7923.24 | 1.84347 | 0.00549376 | 12.6356
WINDVERBAND | MLO0(?) | -0.2627 | +6.629 | +6.724 | 42.54 | 1.849 | 7697.6 | 1.78963 | 7697.6 | 1.79101 | 0.0053373 | 12.2758
WINDVERBAND | MLO0(?) | 0.2627 | +6.559 | +6.655 | 42.54 | 1.849 | 7697.6 | 1.78963 | 7697.6 | 1.79101 | 0.0053373 | 12.2758
WINDVERBAND | MLO0(?) | -0.258541 | +6.559 | +6.655 | 43.52 | 1.891 | 7875.1 | 1.8309 | 7875.12 | 1.83228 | 0.0054604 | 12.5589
WINDVERBAND | MLO0(?) | 0.262701 | +6.629 | +6.725 | 42.54 | 1.849 | 7697.6 | 1.78962 | 7697.56 | 1.791 | 0.00533728 | 12.2757
WINDVERBAND | 7(?) | 0.262701 | +6.629 | +6.725 | 42.54 | 1.849 | 7697.6 | 1.78962 | 7697.56 | 1.791 | 0.00533728 | 12.2757
2 x WINDVERBAND | 7(?) | -0.262701 | +6.559 | +6.655 | 42.54 | 1.849 | 7697.6 | 1.78962 | 7697.56 | 1.791 | 0.00533728 | 12.2757
WINDVERBAND | 7(?) | 0.262701 | +6.629 | +6.725 | 42.41 | 1.843 | 7673.6 | 1.78405 | 7673.6 | 1.78543 | 0.00532066 | 12.2375

# IfcBeam: ROND24 (10)
In: Begane grond
Description: ROND24; Classification: Balk (ARCHICAD Classification); Material: STEEL/S235
Default - NL-SfB_DESCRIPTION: Kolom-/Liggerconstructie staal; NL-SfB_NUMBERCODE: 28.11.21; IS_EXTERNAL: Nee; LOAD_BEARING: Ondersteuning; FIRE_RATING: R30; IFC_CLASS_REF_CODE: 28.11.21 ; Kolom-/Liggerconstructie staal; IFC_BUILDING_STOREY: Undefined; IFC_BUILDING: Undefined; MATERIAL: S235; NAME: WINDVERBAND
Pset_BeamCommon - FireRating: R30; Reference: MLO0(?); LoadBearing: yes; IsExternal: no
Tekla Common - Phase: 1; Class: 13
Tekla Quantity - Gross footprint area: 0 m2; Height: 24 mm; Width: 24 mm
CPset_Phasing - Renovation Phase: Bestaand
AC_Pset_RenovationAndPhasing - Renovation Status: Existing
Material Properties - STEEL/S235, ThermalConductivity: 2.3; STEEL/S235, SpecificHeatCapacity: 1000 J/kg/K; STEEL/S235, MassDensity: 2300 kg/m3; STEEL/S235, Embodied Energy: 1.92 (MJ/kg); STEEL/S235, Embodied Carbon: 0.198 (kgCO₂/kg); STEEL/S235, Name: STEEL/S235; STEEL/S235, Participates in Collision Detection: yes
BaseQuantities - CrossSectionArea: 0.000452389 m2
Component Quantities - STEEL/S235, Component Cross Section Area: 0.000452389 m2
Name | Slope (deg) | Bottom elevation | Top elevation | Weight (kg) | Volume (m3) | Area per tons (m2) | Net surface area (m2) | Tekla Quantity, Length (mm) | NetSurfaceAreaExtrudedSides (m2) = OuterSurfaceArea (m2) | BaseQuantities, Length (mm) | TotalSurfaceArea (m2) = GrossSurfaceArea (m2) = NetSurfaceArea (m2) | GrossVolume (m3) = NetVolume (m3) = STEEL/S235, Component Volume (Net) (m3) = STEEL/S235, Component Volume (Gross) (m3) | STEEL/S235, Mass (kg)
WINDVERBAND | -0.402352 | +4.596 | +4.650 | 14.76 | 0.002 | 21.627 | 0.319 | 4272.1 | 0.313894 | 4272.11 | 0.314799 | 0.00174 | 4.00201
WINDVERBAND | 0 | +4.626 | +4.650 | 21.03 | 0.003 | 21.609 | 0.455 | 6086.2 | 0.457096 | 6253.67 | 0.458001 | 0.00253381 | 5.82777
WINDVERBAND | 0.402351 | +4.630 | +4.684 | 14.76 | 0.002 | 21.627 | 0.319 | 4272.1 | 0.313894 | 4272.11 | 0.314799 | 0.00174 | 4.00201
WINDVERBAND | -0.282693 | +4.596 | +4.650 | 21.01 | 0.003 | 21.609 | 0.454 | 6080.4 | 0.446757 | 6080.37 | 0.447661 | 0.0024765 | 5.69594
WINDVERBAND | 0.282693 | +4.630 | +4.684 | 21.01 | 0.003 | 21.609 | 0.454 | 6080.4 | 0.446757 | 6080.37 | 0.447661 | 0.0024765 | 5.69594
WINDVERBAND | 0.242788 | +4.596 | +4.650 | 24.47 | 0.003 | 21.604 | 0.529 | 7079.8 | 0.520187 | 7079.76 | 0.521092 | 0.00288354 | 6.63214
WINDVERBAND | -0.242788 | +4.630 | +4.684 | 24.47 | 0.003 | 21.604 | 0.529 | 7079.8 | 0.520187 | 7079.76 | 0.521092 | 0.00288354 | 6.63214
WINDVERBAND | 0 | +4.660 | +4.684 | 21.03 | 0.003 | 21.609 | 0.455 | 6086.2 | 0.457096 | 6253.67 | 0.458001 | 0.00253381 | 5.82777
WINDVERBAND | -0.278983 | +4.596 | +4.650 | 21.29 | 0.003 | 21.609 | 0.46 | 6161.2 | 0.452698 | 6161.24 | 0.453603 | 0.00250943 | 5.7717
WINDVERBAND | 0.278982 | +4.630 | +4.684 | 21.29 | 0.003 | 21.609 | 0.46 | 6161.2 | 0.452698 | 6161.24 | 0.453603 | 0.00250943 | 5.7717

# IfcBeam: STRIP50*150 (109)
In: Begane grond
Description: STRIP50*150; Classification: Balk (ARCHICAD Classification); Material: TIMBER/C18
Default - IS_EXTERNAL: Nee; LOAD_BEARING: Nee; FIRE_RATING: R30; IFC_BUILDING_STOREY: Undefined; IFC_BUILDING: Undefined; MATERIAL: C18; comment: 400; NAME: BALKLAAG
Pset_BeamCommon - FireRating: R30; Reference: 0(?); Slope: 0 deg; LoadBearing: no; IsExternal: no
Tekla Common - Phase: 1; Class: 13
Tekla Quantity - Height: 150 mm; Width: 50 mm
CPset_Phasing - Renovation Phase: Bestaand
AC_Pset_RenovationAndPhasing - Renovation Status: Existing
Material Properties - TIMBER/C18, ThermalConductivity: 2.3; TIMBER/C18, SpecificHeatCapacity: 1000 J/kg/K; TIMBER/C18, MassDensity: 2300 kg/m3; TIMBER/C18, Embodied Energy: 1.92 (MJ/kg); TIMBER/C18, Embodied Carbon: 0.198 (kgCO₂/kg); TIMBER/C18, Name: TIMBER/C18; TIMBER/C18, Participates in Collision Detection: yes
BaseQuantities - Width: 50 mm; Depth: 150 mm; CrossSectionArea: 0.0075 m2
Component Quantities - TIMBER/C18, Component Thickness: 50 mm; TIMBER/C18, Rectangular Component Height: 150 mm; TIMBER/C18, Rectangular Component Width: 50 mm; TIMBER/C18, Component Cross Section Area: 0.0075 m2
Name | Bottom elevation | Top elevation | Weight (kg) | Volume (m3) | Gross footprint area (m2) | Area per tons (m2) | Net surface area (m2) | Tekla Quantity, Length (mm) | NetSurfaceAreaExtrudedSides (m2) = OuterSurfaceArea (m2) | BaseQuantities, Length (mm) | TotalSurfaceArea (m2) = GrossSurfaceArea (m2) = NetSurfaceArea (m2) | GrossVolume (m3) | NetVolume (m3) = TIMBER/C18, Component Volume (Net) (m3) = TIMBER/C18, Component Volume (Gross) (m3) | TIMBER/C18, Mass (kg) | TIMBER/C18, Projected Component Area (Net) (m2) = TIMBER/C18, Projected Component Area (Gross) (m2)
12 x BALKLAAG | +3.752 | +3.902 | 3.55 | 0.008 | 0.053 | 122.745 | 0.436 | 1051.5 | 0.412387 | 1032.58 | 0.427387 | 0.00788625 | 0.00774237 | 17.8074 | 0.154847
10 x BALKLAAG | +3.752 | +3.902 | 3.55 | 0.008 | 0.053 | 122.745 | 0.436 | 1051.5 | 0.412354 | 1032.5 | 0.427354 | 0.00788625 | 0.00774173 | 17.806 | 0.154835
24 x BALKLAAG | +3.770 | +3.920 | 9.08 | 0.02 | 0.135 | 120.17 | 1.092 | 2691.3 | 1.0659 | 2685.11 | 1.0809 | 0.0202927 | 0.0200769 | 46.1769 | 0.401539
3 x BALKLAAG | +3.770 | +3.920 | 9.46 | 0.021 | 0.14 | 120.105 | 1.136 | 2802.1 | 1.11023 | 2795.95 | 1.12523 | 0.021124 | 0.0209082 | 48.0889 | 0.418164
14 x BALKLAAG | +3.752 | +3.902 | 3.55 | 0.008 | 0.053 | 122.745 | 0.436 | 1051.5 | 0.412353 | 1032.5 | 0.427353 | 0.00788625 | 0.00774173 | 17.806 | 0.154835
BALKLAAG | +3.770 | +3.920 | 9.46 | 0.021 | 0.14 | 120.105 | 1.136 | 2802.1 | 1.11069 | 2813.59 | 1.12569 | 0.021124 | 0.0209088 | 48.0903 | 0.418636
12 x BALKLAAG | +3.770 | +3.920 | 6.58 | 0.015 | 0.098 | 120.797 | 0.795 | 1950.5 | 0.761097 | 1931.46 | 0.776097 | 0.0146284 | 0.0143875 | 33.0913 | 0.287751
14 x BALKLAAG | +3.740 | +3.890 | 6.58 | 0.015 | 0.098 | 120.797 | 0.795 | 1950.5 | 0.772583 | 1931.46 | 0.787583 | 0.0146284 | 0.0144859 | 33.3176 | 0.289719
6 x BALKLAAG | +3.740 | +3.890 | 9.63 | 0.021 | 0.143 | 120.077 | 1.156 | 2852 | 1.13874 | 2848.9 | 1.15374 | 0.0214159 | 0.0213641 | 49.1374 | 0.427282
8 x BALKLAAG | +3.752 | +3.902 | 3.55 | 0.008 | 0.053 | 122.745 | 0.436 | 1051.5 | 0.412369 | 1032.54 | 0.427369 | 0.00788625 | 0.00774201 | 17.8066 | 0.15484
5 x BALKLAAG | +3.752 | +3.902 | 3.55 | 0.008 | 0.053 | 122.745 | 0.436 | 1051.5 | 0.412369 | 1032.54 | 0.427369 | 0.00788625 | 0.00774202 | 17.8066 | 0.15484

# IfcBeam: STRIP6*60 (4)
In: Begane grond
Description: STRIP6*60; Classification: Balk (ARCHICAD Classification); Material: STEEL/S235
Default - NL-SfB_DESCRIPTION: Kolom-/Liggerconstructie staal; NL-SfB_NUMBERCODE: 28.11.21; IS_EXTERNAL: Nee; LOAD_BEARING: Ondersteuning; FIRE_RATING: R30; IFC_CLASS_REF_CODE: 28.11.21 ; Kolom-/Liggerconstructie staal; IFC_BUILDING_STOREY: Undefined; IFC_BUILDING: Undefined; MATERIAL: S235; NAME: LIGGER
Pset_BeamCommon - FireRating: R30; Reference: M0(?); LoadBearing: yes; IsExternal: no
Tekla Common - Top elevation: +4.851; Phase: 1; Class: 5
Tekla Quantity - Volume: 0.001 m3; Gross footprint area: 0 m2; Height: 60 mm; Width: 6 mm
CPset_Phasing - Renovation Phase: Bestaand
AC_Pset_RenovationAndPhasing - Renovation Status: Existing
Material Properties - STEEL/S235, ThermalConductivity: 2.3; STEEL/S235, SpecificHeatCapacity: 1000 J/kg/K; STEEL/S235, MassDensity: 2300 kg/m3; STEEL/S235, Embodied Energy: 1.92 (MJ/kg); STEEL/S235, Embodied Carbon: 0.198 (kgCO₂/kg); STEEL/S235, Name: STEEL/S235; STEEL/S235, Participates in Collision Detection: yes
BaseQuantities - Width: 6 mm; Depth: 60 mm; CrossSectionArea: 0.00036 m2
Component Quantities - STEEL/S235, Component Thickness: 6 mm; STEEL/S235, Rectangular Component Height: 60 mm; STEEL/S235, Rectangular Component Width: 6 mm; STEEL/S235, Component Cross Section Area: 0.00036 m2
Name | Slope (deg) | Bottom elevation | Weight (kg) | Area per tons (m2) | Net surface area (m2) | Tekla Quantity, Length (mm) | NetSurfaceAreaExtrudedSides (m2) = OuterSurfaceArea (m2) | BaseQuantities, Length (mm) | TotalSurfaceArea (m2) = GrossSurfaceArea (m2) = NetSurfaceArea (m2) | GrossVolume (m3) | NetVolume (m3) = STEEL/S235, Component Volume (Net) (m3) = STEEL/S235, Component Volume (Gross) (m3) | STEEL/S235, Mass (kg) | STEEL/S235, Projected Component Area (Net) (m2) = STEEL/S235, Projected Component Area (Gross) (m2)
LIGGER | 27.7052 | +3.527 | 7.87 | 45.925 | 0.362 | 2733.4 | 0.35606 | 2736.84 | 0.35678 | 0.000978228 | 0.000971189 | 2.23373 | 0.162054
LIGGER | -27.3203 | +3.527 | 7.97 | 45.924 | 0.366 | 2768.9 | 0.362839 | 2768.85 | 0.363559 | 0.000996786 | 0.000989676 | 2.27626 | 0.164946
LIGGER | -33.8113 | +3.530 | 6.58 | 45.943 | 0.302 | 2283.7 | 0.301626 | 2321.37 | 0.302346 | 0.00082892 | 0.000822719 | 1.89225 | 0.13712
LIGGER | 30.3831 | +3.528 | 7.24 | 45.933 | 0.332 | 2512.6 | 0.329652 | 2553.6 | 0.330372 | 0.000905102 | 0.000899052 | 2.06782 | 0.150066

# IfcBeam: THQ_150*5-190*25-400*15, LIGGER
In: Begane grond
Description: THQ_150*5-190*25-400*15; Classification: Balk (ARCHICAD Classification); Material: STEEL/S355
Pset_BeamCommon - FireRating: R30; Reference: LIH0(?); Slope: 0 deg; LoadBearing: yes; IsExternal: no
Default - NL-SfB_DESCRIPTION: Kolom-/Liggerconstructie staal; NL-SfB_NUMBERCODE: 28.11.21; IS_EXTERNAL: Nee; LOAD_BEARING: Ondersteuning; FIRE_RATING: R30; IFC_CLASS_REF_CODE: 28.11.21 ; Kolom-/Liggerconstructie staal; IFC_BUILDING_STOREY: Undefined; IFC_BUILDING: Undefined; MATERIAL: S355; NAME: LIGGER
Tekla Common - Bottom elevation: +4.005; Top elevation: +4.170; Phase: 1; Class: 5
Tekla Quantity - Weight: 240.1 kg; Volume: 0.03 m3; Gross footprint area: 0.49 m2; Area per tons: 11.531 m2; Net surface area: 4.336 m2; Height: 165 mm; Width: 400 mm; Length: 2450 mm
CPset_Phasing - Renovation Phase: Bestaand
AC_Pset_RenovationAndPhasing - Renovation Status: Existing
Material Properties - STEEL/S355, ThermalConductivity: 2.3; STEEL/S355, SpecificHeatCapacity: 1000 J/kg/K; STEEL/S355, MassDensity: 2300 kg/m3; STEEL/S355, Embodied Energy: 1.92 (MJ/kg); STEEL/S355, Embodied Carbon: 0.198 (kgCO₂/kg); STEEL/S355, Name: STEEL/S355; STEEL/S355, Participates in Collision Detection: yes
BaseQuantities - NetSurfaceAreaExtrudedSides: 4.312 m2; Length: 2450 mm; CrossSectionArea: 0.01225 m2; OuterSurfaceArea: 4.312 m2; TotalSurfaceArea: 4.3365 m2; GrossSurfaceArea: 4.3365 m2; GrossVolume: 0.0300125 m3; NetSurfaceArea: 4.3365 m2; NetVolume: 0.0300125 m3
Component Quantities - STEEL/S355, Mass: 69.0288 kg; STEEL/S355, Component Cross Section Area: 0.01225 m2; STEEL/S355, Component Volume (Net): 0.0300125 m3; STEEL/S355, Component Volume (Gross): 0.0300125 m3

# IfcBeam: THQ_150*5-190*35-400*15, LIGGER
In: Begane grond
Description: THQ_150*5-190*35-400*15; Classification: Balk (ARCHICAD Classification); Material: STEEL/S355
Default - NL-SfB_DESCRIPTION: Kolom-/Liggerconstructie staal; NL-SfB_NUMBERCODE: 28.11.21; IS_EXTERNAL: Nee; LOAD_BEARING: Ondersteuning; FIRE_RATING: R0; IFC_CLASS_REF_CODE: 28.11.21 ; Kolom-/Liggerconstructie staal; IFC_BUILDING_STOREY: Undefined; IFC_BUILDING: Undefined; MATERIAL: S355; NAME: LIGGER
Tekla Common - Bottom elevation: +3.025; Top elevation: +3.190; Phase: 1; Class: 5
Tekla Quantity - Weight: 536 kg; Volume: 0.067 m3; Gross footprint area: 0.947 m2; Area per tons: 9.982 m2; Net surface area: 8.267 m2; Height: 165 mm; Width: 400 mm; Length: 4735 mm
Pset_BeamCommon - FireRating: R0; Reference: LIH0(?); Slope: 0 deg; LoadBearing: yes; IsExternal: no
CPset_Phasing - Renovation Phase: Bestaand
AC_Pset_RenovationAndPhasing - Renovation Status: Existing
Material Properties - STEEL/S355, ThermalConductivity: 2.3; STEEL/S355, SpecificHeatCapacity: 1000 J/kg/K; STEEL/S355, MassDensity: 2300 kg/m3; STEEL/S355, Embodied Energy: 1.92 (MJ/kg); STEEL/S355, Embodied Carbon: 0.198 (kgCO₂/kg); STEEL/S355, Name: STEEL/S355; STEEL/S355, Participates in Collision Detection: yes
BaseQuantities - NetSurfaceAreaExtrudedSides: 8.23885 m2; Length: 4734.97 mm; CrossSectionArea: 0.01415 m2; OuterSurfaceArea: 8.23885 m2; TotalSurfaceArea: 8.26715 m2; GrossSurfaceArea: 8.26715 m2; GrossVolume: 0.0669998 m3; NetSurfaceArea: 8.26715 m2; NetVolume: 0.0669998 m3
Component Quantities - STEEL/S355, Mass: 154.1 kg; STEEL/S355, Component Cross Section Area: 0.01415 m2; STEEL/S355, Component Volume (Net): 0.0669998 m3; STEEL/S355, Component Volume (Gross): 0.0669998 m3

# IfcBeam: THQ_265*6-190*25-400*15, LIGGER
In: Begane grond
Description: THQ_265*6-190*25-400*15; Classification: Balk (ARCHICAD Classification); Material: STEEL/S355
Pset_BeamCommon - FireRating: R30; Reference: LIH0(?); Slope: 0 deg; LoadBearing: yes; IsExternal: no
Default - NL-SfB_DESCRIPTION: Kolom-/Liggerconstructie staal; NL-SfB_NUMBERCODE: 28.11.21; IS_EXTERNAL: Nee; LOAD_BEARING: Ondersteuning; FIRE_RATING: R30; IFC_CLASS_REF_CODE: 28.11.21 ; Kolom-/Liggerconstructie staal; IFC_BUILDING_STOREY: Undefined; IFC_BUILDING: Undefined; MATERIAL: S355; NAME: LIGGER
Tekla Common - Bottom elevation: +3.320; Top elevation: +3.600; Phase: 1; Class: 5
Tekla Quantity - Weight: 2437.64 kg; Volume: 0.305 m3; Gross footprint area: 4.419 m2; Area per tons: 12.204 m2; Net surface area: 48.588 m2; Height: 280 mm; Width: 400 mm; Length: 21874 mm
CPset_Phasing - Renovation Phase: Bestaand
AC_Pset_RenovationAndPhasing - Renovation Status: Existing
Material Properties - STEEL/S355, ThermalConductivity: 2.3; STEEL/S355, SpecificHeatCapacity: 1000 J/kg/K; STEEL/S355, MassDensity: 2300 kg/m3; STEEL/S355, Embodied Energy: 1.92 (MJ/kg); STEEL/S355, Embodied Carbon: 0.198 (kgCO₂/kg); STEEL/S355, Name: STEEL/S355; STEEL/S355, Participates in Collision Detection: yes
BaseQuantities - NetSurfaceAreaExtrudedSides: 48.5203 m2; Length: 21874 mm; CrossSectionArea: 0.01393 m2; OuterSurfaceArea: 48.5203 m2; TotalSurfaceArea: 48.5482 m2; GrossSurfaceArea: 48.5482 m2; GrossVolume: 0.304705 m3; NetSurfaceArea: 48.5482 m2; NetVolume: 0.304405 m3
Component Quantities - STEEL/S355, Mass: 700.131 kg; STEEL/S355, Component Cross Section Area: 0.01393 m2; STEEL/S355, Component Volume (Net): 0.304405 m3; STEEL/S355, Component Volume (Gross): 0.304405 m3

# IfcBeam: THQ_265*6-190*30-400*20 (3)
In: Begane grond
Description: THQ_265*6-190*30-400*20; Classification: Balk (ARCHICAD Classification); Material: STEEL/S355
Pset_BeamCommon - FireRating: R30; Reference: LIH0(?); Slope: 0 deg; LoadBearing: yes; IsExternal: no
Default - NL-SfB_DESCRIPTION: Kolom-/Liggerconstructie staal; NL-SfB_NUMBERCODE: 28.11.21; IS_EXTERNAL: Nee; LOAD_BEARING: Ondersteuning; FIRE_RATING: R30; IFC_CLASS_REF_CODE: 28.11.21 ; Kolom-/Liggerconstructie staal; IFC_BUILDING_STOREY: Undefined; IFC_BUILDING: Undefined; MATERIAL: S355; NAME: LIGGER
Tekla Common - Bottom elevation: +3.315; Top elevation: +3.600; Phase: 1; Class: 5
Tekla Quantity - Area per tons: 10.145 m2; Height: 285 mm; Width: 400 mm
CPset_Phasing - Renovation Phase: Bestaand
AC_Pset_RenovationAndPhasing - Renovation Status: Existing
Material Properties - STEEL/S355, ThermalConductivity: 2.3; STEEL/S355, SpecificHeatCapacity: 1000 J/kg/K; STEEL/S355, MassDensity: 2300 kg/m3; STEEL/S355, Embodied Energy: 1.92 (MJ/kg); STEEL/S355, Embodied Carbon: 0.198 (kgCO₂/kg); STEEL/S355, Name: STEEL/S355; STEEL/S355, Participates in Collision Detection: yes
BaseQuantities - CrossSectionArea: 0.01688 m2
Component Quantities - STEEL/S355, Component Cross Section Area: 0.01688 m2
Name | Weight (kg) | Volume (m3) | Gross footprint area (m2) | Net surface area (m2) | Tekla Quantity, Length (mm) = BaseQuantities, Length (mm) | NetSurfaceAreaExtrudedSides (m2) = OuterSurfaceArea (m2) | TotalSurfaceArea (m2) = GrossSurfaceArea (m2) = NetSurfaceArea (m2) | GrossVolume (m3) | NetVolume (m3) = STEEL/S355, Component Volume (Net) (m3) = STEEL/S355, Component Volume (Gross) (m3) | STEEL/S355, Mass (kg)
LIGGER | 7031.53 | 0.879 | 10.518 | 115.629 | 52070 | 115.525 | 115.559 | 0.878942 | 0.878241 | 2019.95
LIGGER | 3969.91 | 0.496 | 5.938 | 65.297 | 29398 | 65.2084 | 65.2422 | 0.496239 | 0.495687 | 1140.08
LIGGER | 2548.2 | 0.319 | 3.812 | 41.925 | 18870 | 41.8714 | 41.9051 | 0.318526 | 0.318325 | 732.148

# IfcBeam: THQ_265*6-190*40-400*20, LIGGER
In: Begane grond
Description: THQ_265*6-190*40-400*20; Classification: Balk (ARCHICAD Classification); Material: STEEL/S355
Pset_BeamCommon - FireRating: R30; Reference: LIH0(?); Slope: 0 deg; LoadBearing: yes; IsExternal: no
Default - NL-SfB_DESCRIPTION: Kolom-/Liggerconstructie staal; NL-SfB_NUMBERCODE: 28.11.21; IS_EXTERNAL: Nee; LOAD_BEARING: Ondersteuning; FIRE_RATING: R30; IFC_CLASS_REF_CODE: 28.11.21 ; Kolom-/Liggerconstructie staal; IFC_BUILDING_STOREY: Undefined; IFC_BUILDING: Undefined; MATERIAL: S355; NAME: LIGGER
Tekla Common - Bottom elevation: +3.315; Top elevation: +3.600; Phase: 1; Class: 5
Tekla Quantity - Weight: 3891.22 kg; Volume: 0.486 m3; Gross footprint area: 5.232 m2; Area per tons: 9.119 m2; Net surface area: 57.018 m2; Height: 285 mm; Width: 400 mm; Length: 25900 mm
CPset_Phasing - Renovation Phase: Bestaand
AC_Pset_RenovationAndPhasing - Renovation Status: Existing
Material Properties - STEEL/S355, ThermalConductivity: 2.3; STEEL/S355, SpecificHeatCapacity: 1000 J/kg/K; STEEL/S355, MassDensity: 2300 kg/m3; STEEL/S355, Embodied Energy: 1.92 (MJ/kg); STEEL/S355, Embodied Carbon: 0.198 (kgCO₂/kg); STEEL/S355, Name: STEEL/S355; STEEL/S355, Participates in Collision Detection: yes
BaseQuantities - NetSurfaceAreaExtrudedSides: 56.95 m2; Length: 25900 mm; CrossSectionArea: 0.01878 m2; OuterSurfaceArea: 56.95 m2; TotalSurfaceArea: 56.9876 m2; GrossSurfaceArea: 56.9876 m2; GrossVolume: 0.486402 m3; NetSurfaceArea: 56.9876 m2; NetVolume: 0.486102 m3
Component Quantities - STEEL/S355, Mass: 1118.03 kg; STEEL/S355, Component Cross Section Area: 0.01878 m2; STEEL/S355, Component Volume (Net): 0.486102 m3; STEEL/S355, Component Volume (Gross): 0.486102 m3

# IfcBeam: UNP200 (4)
In: Begane grond
Description: UNP200; Classification: Balk (ARCHICAD Classification); Material: STEEL/S235
Default - NL-SfB_DESCRIPTION: Kolom-/Liggerconstructie staal; NL-SfB_NUMBERCODE: 28.11.21; IS_EXTERNAL: Nee; LOAD_BEARING: Ondersteuning; FIRE_RATING: R0; IFC_CLASS_REF_CODE: 28.11.21 ; Kolom-/Liggerconstructie staal; IFC_BUILDING_STOREY: Undefined; IFC_BUILDING: Undefined; MATERIAL: S235; NAME: LIGGER
Pset_BeamCommon - FireRating: R0; Reference: LIK0(?); Slope: 0 deg; LoadBearing: yes; IsExternal: no
Tekla Common - Phase: 1; Class: 5
Tekla Quantity - Area per tons: 25.637 m2; Height: 200 mm; Width: 75 mm
CPset_Phasing - Renovation Phase: Bestaand
AC_Pset_RenovationAndPhasing - Renovation Status: Existing
Material Properties - STEEL/S235, ThermalConductivity: 2.3; STEEL/S235, SpecificHeatCapacity: 1000 J/kg/K; STEEL/S235, MassDensity: 2300 kg/m3; STEEL/S235, Embodied Energy: 1.92 (MJ/kg); STEEL/S235, Embodied Carbon: 0.198 (kgCO₂/kg); STEEL/S235, Name: STEEL/S235; STEEL/S235, Participates in Collision Detection: yes
BaseQuantities - CrossSectionArea: 0.00321849 m2
Component Quantities - STEEL/S235, Component Cross Section Area: 0.00321849 m2
Name | Bottom elevation | Top elevation | Weight (kg) | Volume (m3) | Gross footprint area (m2) | Net surface area (m2) | Tekla Quantity, Length (mm) = BaseQuantities, Length (mm) | NetSurfaceAreaExtrudedSides (m2) = OuterSurfaceArea (m2) | TotalSurfaceArea (m2) = GrossSurfaceArea (m2) = NetSurfaceArea (m2) | GrossVolume (m3) | NetVolume (m3) = STEEL/S235, Component Volume (Net) (m3) = STEEL/S235, Component Volume (Gross) (m3) | STEEL/S235, Mass (kg)
LIGGER | +4.776 | +4.851 | 185.87 | 0.023 | 1.444 | 4.864 | 7220 | 4.7294 | 4.73584 | 0.0233308 | 0.023219 | 53.4036
LIGGER | +3.580 | +3.655 | 101.56 | 0.013 | 0.067 | 2.661 | 3945 | 2.58373 | 2.59017 | 0.0127479 | 0.0126809 | 29.1662
LIGGER | +4.776 | +4.851 | 101.56 | 0.013 | 0.789 | 2.661 | 3945 | 2.58762 | 2.59405 | 0.0127479 | 0.0127031 | 29.217
LIGGER | +3.580 | +3.655 | 185.87 | 0.023 | 0.123 | 4.864 | 7220 | 4.7336 | 4.74004 | 0.0233308 | 0.0232411 | 53.4545

# IfcBeam: UNP240 (13)
In: Begane grond
Description: UNP240; Classification: Balk (ARCHICAD Classification); Material: STEEL/S235
Default - NL-SfB_DESCRIPTION: Kolom-/Liggerconstructie staal; NL-SfB_NUMBERCODE: 28.11.21; IS_EXTERNAL: Nee; LOAD_BEARING: Ondersteuning; FIRE_RATING: R0; IFC_CLASS_REF_CODE: 28.11.21 ; Kolom-/Liggerconstructie staal; IFC_BUILDING_STOREY: Undefined; IFC_BUILDING: Undefined; MATERIAL: S235; NAME: LIGGER
Tekla Common - Phase: 1; Class: 5
Pset_BeamCommon - FireRating: R0; Slope: 0 deg; LoadBearing: yes; IsExternal: no
Tekla Quantity - Area per tons: 22.754 m2; Height: 240 mm; Width: 85 mm
CPset_Phasing - Renovation Phase: Bestaand
AC_Pset_RenovationAndPhasing - Renovation Status: Existing
Material Properties - STEEL/S235, ThermalConductivity: 2.3; STEEL/S235, SpecificHeatCapacity: 1000 J/kg/K; STEEL/S235, MassDensity: 2300 kg/m3; STEEL/S235, Embodied Energy: 1.92 (MJ/kg); STEEL/S235, Embodied Carbon: 0.198 (kgCO₂/kg); STEEL/S235, Name: STEEL/S235; STEEL/S235, Participates in Collision Detection: yes
BaseQuantities - CrossSectionArea: 0.00423067 m2
Component Quantities - STEEL/S235, Component Cross Section Area: 0.00423067 m2
Name | Bottom elevation | Top elevation | Reference | Weight (kg) | Volume (m3) | Gross footprint area (m2) | Net surface area (m2) | Tekla Quantity, Length (mm) | NetSurfaceAreaExtrudedSides (m2) = OuterSurfaceArea (m2) | BaseQuantities, Length (mm) | TotalSurfaceArea (m2) = GrossSurfaceArea (m2) = NetSurfaceArea (m2) | GrossVolume (m3) | NetVolume (m3) = STEEL/S235, Component Volume (Net) (m3) = STEEL/S235, Component Volume (Gross) (m3) | STEEL/S235, Mass (kg)
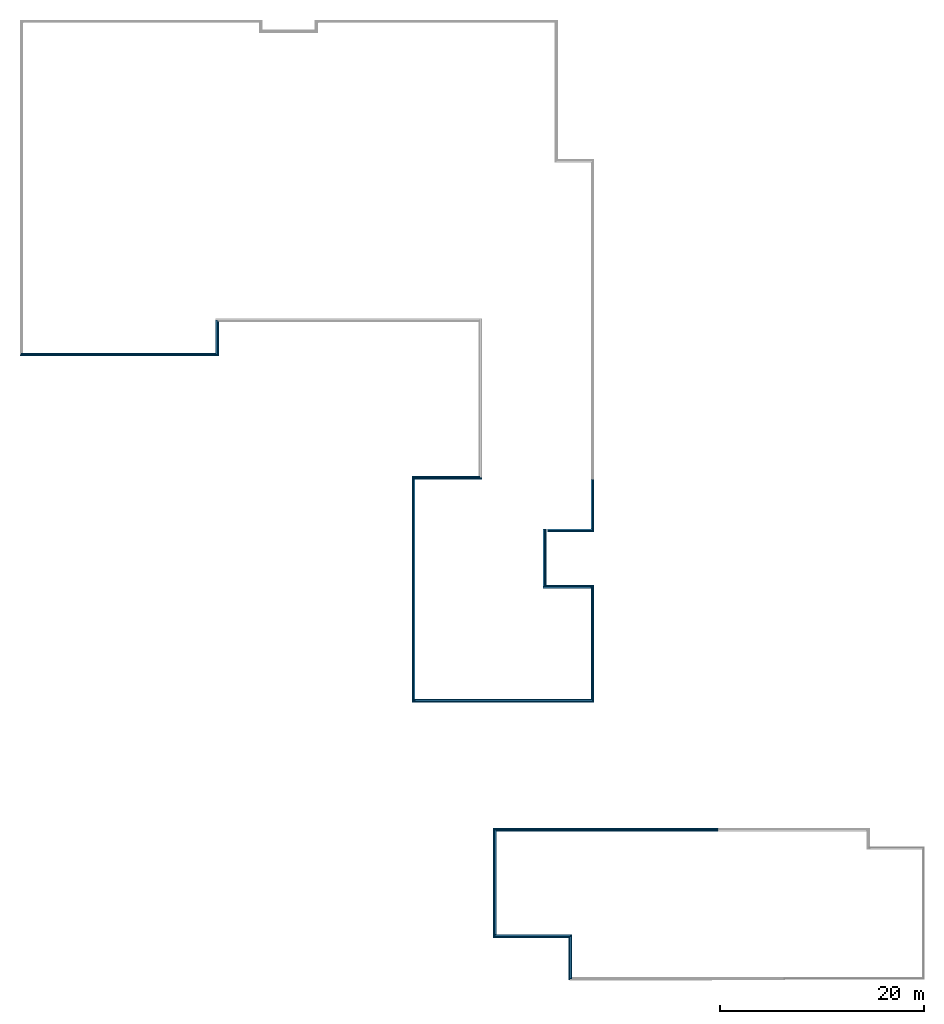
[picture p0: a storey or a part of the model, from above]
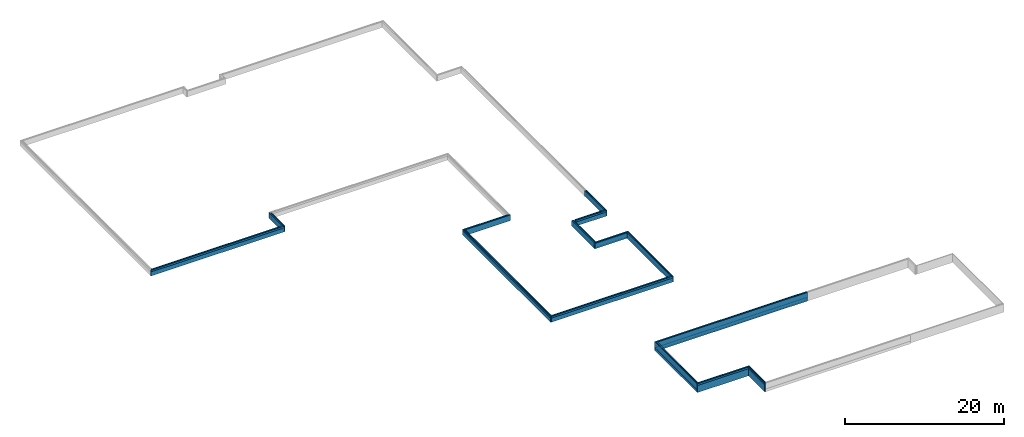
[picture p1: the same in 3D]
Properties of the parts of a building model (IFC2X3), part 3 of 19

# IfcBeam: UNP240 (13)
Name | Bottom elevation | Top elevation | Reference | Weight (kg) | Volume (m3) | Gross footprint area (m2) | Net surface area (m2) | Tekla Quantity, Length (mm) | NetSurfaceAreaExtrudedSides (m2) = OuterSurfaceArea (m2) | BaseQuantities, Length (mm) | TotalSurfaceArea (m2) = GrossSurfaceArea (m2) = NetSurfaceArea (m2) | GrossVolume (m3) | NetVolume (m3) = STEEL/S235, Component Volume (Net) (m3) = STEEL/S235, Component Volume (Gross) (m3) | STEEL/S235, Mass (kg)
LIGGER | +3.680 | +3.920 | liH0(?) | 219.19 | 0.027 | 0.551 | 5.122 | 6477.3 | 4.98333 | 6471.07 | 4.99179 | 0.0275135 | 0.0272896 | 62.766
LIGGER | +3.680 | +3.920 | liH0(?) | 232.25 | 0.03 | 0.583 | 5.426 | 6863.1 | 5.0713 | 6550.35 | 5.07977 | 0.0291524 | 0.0278239 | 63.9949
LIGGER | +3.680 | +3.920 | liH0(?) | 232.25 | 0.03 | 0.583 | 5.426 | 6862.7 | 4.7974 | 6196.56 | 4.80586 | 0.0291508 | 0.0263211 | 60.5385
LIGGER | +3.680 | +3.920 | liH0(?) | 201.15 | 0.025 | 0.505 | 4.7 | 5943.9 | 4.60177 | 5943.9 | 4.61023 | 0.0252478 | 0.0252478 | 58.0699
LIGGER | +3.680 | +3.920 | LIH0(?) | 186.24 | 0.023 | 0.468 | 4.353 | 5503.4 | 4.24506 | 5503.42 | 4.25352 | 0.0233768 | 0.0232843 | 53.5539
LIGGER | +3.680 | +3.920 | LIH0(?) | 475.32 | 0.059 | 1.194 | 11.096 | 14046.2 | 10.8589 | 14043.1 | 10.8673 | 0.0597757 | 0.0595518 | 136.969
LIGGER | +3.680 | +3.920 | LIH0(?) | 473.63 | 0.059 | 1.19 | 11.057 | 13996.2 | 10.8576 | 14056.2 | 10.8661 | 0.0595729 | 0.0595729 | 137.018
LIGGER | +3.680 | +3.920 | liH0(?) | 219.19 | 0.027 | 0.551 | 5.122 | 6477.3 | 5.01473 | 6477.28 | 5.0232 | 0.0275135 | 0.0275135 | 63.2811
LIGGER | +3.680 | +3.920 | liH0(?) | 232.25 | 0.03 | 0.583 | 5.426 | 6863.1 | 5.0713 | 6550.34 | 5.07977 | 0.0291524 | 0.0278224 | 63.9914
LIGGER | +3.680 | +3.920 | liH0(?) | 232.25 | 0.03 | 0.583 | 5.426 | 6862.7 | 4.79739 | 6196.55 | 4.80586 | 0.0291508 | 0.0263211 | 60.5384
LIGGER | +3.680 | +3.920 | liH0(?) | 201.15 | 0.025 | 0.505 | 4.701 | 5944.2 | 4.60199 | 5944.16 | 4.61045 | 0.0252489 | 0.0252489 | 58.0726
LIGGER | +4.215 | +4.455 | liI0(?) | 79.59 | 0.009 | 0.2 | 1.865 | 2352 | 1.82091 | 2351.98 | 1.82937 | 0.00999049 | 0.00999049 | 22.9781
LIGGER | +4.215 | +4.455 | liI0(?) | 87.58 | 0.011 | 0.22 | 2.051 | 2588 | 2.00362 | 2587.98 | 2.01209 | 0.0109929 | 0.0109929 | 25.2838

# IfcBuildingElementPart (2070)
Name | In | Material | Mass (kg) | Rectangular Component Height (mm) | Rectangular Component Width (mm) | Component Cross Section Area (m2) | Component Volume (Net) (m3) | Component Volume (Gross) (m3)
Isolatie - Kunststof hard | Fundering | Isolatie - Kunststof hard | 230.276 | 1320 | 140 | 0.1848 | 2.30276 | 2.33587 | Component Quantities - Projected Component Area (Net): 16.6821 m2; Projected Component Area (Gross): 16.6848 m2; Component Thickness: 140 mm; Material Properties - Isolatie - Kunststof hard, ThermalConductivity: 0.029; Isolatie - Kunststof hard, SpecificHeatCapacity: 1470 J/kg/K; Isolatie - Kunststof hard, MassDensity: 100 kg/m3; Isolatie - Kunststof hard, Embodied Energy: 101.5 (MJ/kg); Isolatie - Kunststof hard, Embodied Carbon: 3.48 (kgCO₂/kg); Isolatie - Kunststof hard, Name: Isolatie - Kunststof hard; Isolatie - Kunststof hard, Participates in Collision Detection: yes
Membraan - waterdicht | Fundering | Membraan - waterdicht | 85.244 | 1320 | 5 | 0.0066 | 0.0811848 | 0.084381 | Component Quantities - Projected Component Area (Net): 16.237 m2; Projected Component Area (Gross): 16.8762 m2; Component Thickness: 5 mm; Material Properties - Membraan - waterdicht, ThermalConductivity: 0.2; Membraan - waterdicht, SpecificHeatCapacity: 1840 J/kg/K; Membraan - waterdicht, MassDensity: 1050 kg/m3; Membraan - waterdicht, Embodied Energy: 51 (MJ/kg); Membraan - waterdicht, Embodied Carbon: 0.38 (kgCO₂/kg); Membraan - waterdicht, Name: Membraan - waterdicht; Membraan - waterdicht, Participates in Collision Detection: yes
Membraan - waterdicht | Fundering | Membraan - waterdicht | 36.7567 | 1320 | 5 | 0.0066 | 0.0350064 | 0.0350064 | Component Quantities - Projected Component Area (Net): 7.00128 m2; Projected Component Area (Gross): 7.00128 m2; Component Thickness: 5 mm; Material Properties - Membraan - waterdicht, ThermalConductivity: 0.2; Membraan - waterdicht, SpecificHeatCapacity: 1840 J/kg/K; Membraan - waterdicht, MassDensity: 1050 kg/m3; Membraan - waterdicht, Embodied Energy: 51 (MJ/kg); Membraan - waterdicht, Embodied Carbon: 0.38 (kgCO₂/kg); Membraan - waterdicht, Name: Membraan - waterdicht; Membraan - waterdicht, Participates in Collision Detection: yes
Isolatie - Kunststof hard | Fundering | Isolatie - Kunststof hard | 95.4307 | 1320 | 140 | 0.1848 | 0.954307 | 0.954307 | Component Quantities - Projected Component Area (Net): 6.81648 m2; Projected Component Area (Gross): 6.81648 m2; Component Thickness: 140 mm; Material Properties - Isolatie - Kunststof hard, ThermalConductivity: 0.029; Isolatie - Kunststof hard, SpecificHeatCapacity: 1470 J/kg/K; Isolatie - Kunststof hard, MassDensity: 100 kg/m3; Isolatie - Kunststof hard, Embodied Energy: 101.5 (MJ/kg); Isolatie - Kunststof hard, Embodied Carbon: 3.48 (kgCO₂/kg); Isolatie - Kunststof hard, Name: Isolatie - Kunststof hard; Isolatie - Kunststof hard, Participates in Collision Detection: yes
Steen - Betonblok vuilwerk | Fundering | Steen - Betonblok vuilwerk | 1756.93 | 620 | 100 | 0.062 | 1.09808 | 1.09808 | Material Properties - Steen - Betonblok vuilwerk, ThermalConductivity: 0.75; Steen - Betonblok vuilwerk, SpecificHeatCapacity: 840 J/kg/K; Steen - Betonblok vuilwerk, MassDensity: 1600 kg/m3; Steen - Betonblok vuilwerk, Embodied Energy: 0.83 (MJ/kg); Steen - Betonblok vuilwerk, Embodied Carbon: 0.1 (kgCO₂/kg); Steen - Betonblok vuilwerk, Name: Steen - Betonblok vuilwerk; Steen - Betonblok vuilwerk, Participates in Collision Detection: yes
Steen - Baksteen AFW | Fundering | Steen - Baksteen AFW | 708.44 | 250 | 100 | 0.025 | 0.442775 | 0.442775 | Material Properties - Steen - Baksteen AFW, ThermalConductivity: 0.9; Steen - Baksteen AFW, SpecificHeatCapacity: 840 J/kg/K; Steen - Baksteen AFW, MassDensity: 1600 kg/m3; Steen - Baksteen AFW, Embodied Energy: 3 (MJ/kg); Steen - Baksteen AFW, Embodied Carbon: 0.23 (kgCO₂/kg); Steen - Baksteen AFW, Name: Steen - Baksteen AFW; Steen - Baksteen AFW, Participates in Collision Detection: yes
Isolatie - Kunststof hard | Fundering | Isolatie - Kunststof hard | 211.676 | 870 | 140 | 0.1218 | 2.11676 | 2.11676 | Material Properties - Isolatie - Kunststof hard, ThermalConductivity: 0.029; Isolatie - Kunststof hard, SpecificHeatCapacity: 1470 J/kg/K; Isolatie - Kunststof hard, MassDensity: 100 kg/m3; Isolatie - Kunststof hard, Embodied Energy: 101.5 (MJ/kg); Isolatie - Kunststof hard, Embodied Carbon: 3.48 (kgCO₂/kg); Isolatie - Kunststof hard, Name: Isolatie - Kunststof hard; Isolatie - Kunststof hard, Participates in Collision Detection: yes
Steen - Betonblok vuilwerk | Fundering | Steen - Betonblok vuilwerk | 732.514 | 430 | 100 | 0.043 | 0.457821 | 0.457821 | Material Properties - Steen - Betonblok vuilwerk, ThermalConductivity: 0.75; Steen - Betonblok vuilwerk, SpecificHeatCapacity: 840 J/kg/K; Steen - Betonblok vuilwerk, MassDensity: 1600 kg/m3; Steen - Betonblok vuilwerk, Embodied Energy: 0.83 (MJ/kg); Steen - Betonblok vuilwerk, Embodied Carbon: 0.1 (kgCO₂/kg); Steen - Betonblok vuilwerk, Name: Steen - Betonblok vuilwerk; Steen - Betonblok vuilwerk, Participates in Collision Detection: yes
Steen - Baksteen AFW | Fundering | Steen - Baksteen AFW | 1533.17 | 900 | 100 | 0.09 | 0.95823 | 0.95823 | Material Properties - Steen - Baksteen AFW, ThermalConductivity: 0.9; Steen - Baksteen AFW, SpecificHeatCapacity: 840 J/kg/K; Steen - Baksteen AFW, MassDensity: 1600 kg/m3; Steen - Baksteen AFW, Embodied Energy: 3 (MJ/kg); Steen - Baksteen AFW, Embodied Carbon: 0.23 (kgCO₂/kg); Steen - Baksteen AFW, Name: Steen - Baksteen AFW; Steen - Baksteen AFW, Participates in Collision Detection: yes
Isolatie - Kunststof hard | Fundering | Isolatie - Kunststof hard | 192.065 | 1330 | 140 | 0.1862 | 1.92065 | 1.92065 | Material Properties - Isolatie - Kunststof hard, ThermalConductivity: 0.029; Isolatie - Kunststof hard, SpecificHeatCapacity: 1470 J/kg/K; Isolatie - Kunststof hard, MassDensity: 100 kg/m3; Isolatie - Kunststof hard, Embodied Energy: 101.5 (MJ/kg); Isolatie - Kunststof hard, Embodied Carbon: 3.48 (kgCO₂/kg); Isolatie - Kunststof hard, Name: Isolatie - Kunststof hard; Isolatie - Kunststof hard, Participates in Collision Detection: yes
Steen - Baksteen AFW | Fundering | Steen - Baksteen AFW | 3161.66 | 900 | 100 | 0.09 | 1.97604 | 1.97604 | Material Properties - Steen - Baksteen AFW, ThermalConductivity: 0.9; Steen - Baksteen AFW, SpecificHeatCapacity: 840 J/kg/K; Steen - Baksteen AFW, MassDensity: 1600 kg/m3; Steen - Baksteen AFW, Embodied Energy: 3 (MJ/kg); Steen - Baksteen AFW, Embodied Carbon: 0.23 (kgCO₂/kg); Steen - Baksteen AFW, Name: Steen - Baksteen AFW; Steen - Baksteen AFW, Participates in Collision Detection: yes
Steen - Betonblok vuilwerk | Fundering | Steen - Betonblok vuilwerk | 1510.57 | 430 | 100 | 0.043 | 0.944108 | 0.944108 | Material Properties - Steen - Betonblok vuilwerk, ThermalConductivity: 0.75; Steen - Betonblok vuilwerk, SpecificHeatCapacity: 840 J/kg/K; Steen - Betonblok vuilwerk, MassDensity: 1600 kg/m3; Steen - Betonblok vuilwerk, Embodied Energy: 0.83 (MJ/kg); Steen - Betonblok vuilwerk, Embodied Carbon: 0.1 (kgCO₂/kg); Steen - Betonblok vuilwerk, Name: Steen - Betonblok vuilwerk; Steen - Betonblok vuilwerk, Participates in Collision Detection: yes
Isolatie - Kunststof hard | Fundering | Isolatie - Kunststof hard | 405.357 | 1330 | 140 | 0.1862 | 4.05357 | 4.05357 | Material Properties - Isolatie - Kunststof hard, ThermalConductivity: 0.029; Isolatie - Kunststof hard, SpecificHeatCapacity: 1470 J/kg/K; Isolatie - Kunststof hard, MassDensity: 100 kg/m3; Isolatie - Kunststof hard, Embodied Energy: 101.5 (MJ/kg); Isolatie - Kunststof hard, Embodied Carbon: 3.48 (kgCO₂/kg); Isolatie - Kunststof hard, Name: Isolatie - Kunststof hard; Isolatie - Kunststof hard, Participates in Collision Detection: yes
Steen - Betonblok vuilwerk | Fundering | Steen - Betonblok vuilwerk | 712.8 | 1080 | 100 | 0.108 | 0.4455 | 0.4455 | Material Properties - Steen - Betonblok vuilwerk, ThermalConductivity: 0.75; Steen - Betonblok vuilwerk, SpecificHeatCapacity: 840 J/kg/K; Steen - Betonblok vuilwerk, MassDensity: 1600 kg/m3; Steen - Betonblok vuilwerk, Embodied Energy: 0.83 (MJ/kg); Steen - Betonblok vuilwerk, Embodied Carbon: 0.1 (kgCO₂/kg); Steen - Betonblok vuilwerk, Name: Steen - Betonblok vuilwerk; Steen - Betonblok vuilwerk, Participates in Collision Detection: yes
Steen - Baksteen AFW | Fundering | Steen - Baksteen AFW | 165 | 250 | 100 | 0.025 | 0.103125 | 0.103125 | Material Properties - Steen - Baksteen AFW, ThermalConductivity: 0.9; Steen - Baksteen AFW, SpecificHeatCapacity: 840 J/kg/K; Steen - Baksteen AFW, MassDensity: 1600 kg/m3; Steen - Baksteen AFW, Embodied Energy: 3 (MJ/kg); Steen - Baksteen AFW, Embodied Carbon: 0.23 (kgCO₂/kg); Steen - Baksteen AFW, Name: Steen - Baksteen AFW; Steen - Baksteen AFW, Participates in Collision Detection: yes
Isolatie - Kunststof hard | Fundering | Isolatie - Kunststof hard | 76.8075 | 1330 | 140 | 0.1862 | 0.768075 | 0.768075 | Material Properties - Isolatie - Kunststof hard, ThermalConductivity: 0.029; Isolatie - Kunststof hard, SpecificHeatCapacity: 1470 J/kg/K; Isolatie - Kunststof hard, MassDensity: 100 kg/m3; Isolatie - Kunststof hard, Embodied Energy: 101.5 (MJ/kg); Isolatie - Kunststof hard, Embodied Carbon: 3.48 (kgCO₂/kg); Isolatie - Kunststof hard, Name: Isolatie - Kunststof hard; Isolatie - Kunststof hard, Participates in Collision Detection: yes
Steen - Betonblok vuilwerk | Fundering | Steen - Betonblok vuilwerk | 1296 | 1080 | 100 | 0.108 | 0.81 | 0.81 | Material Properties - Steen - Betonblok vuilwerk, ThermalConductivity: 0.75; Steen - Betonblok vuilwerk, SpecificHeatCapacity: 840 J/kg/K; Steen - Betonblok vuilwerk, MassDensity: 1600 kg/m3; Steen - Betonblok vuilwerk, Embodied Energy: 0.83 (MJ/kg); Steen - Betonblok vuilwerk, Embodied Carbon: 0.1 (kgCO₂/kg); Steen - Betonblok vuilwerk, Name: Steen - Betonblok vuilwerk; Steen - Betonblok vuilwerk, Participates in Collision Detection: yes
Steen - Baksteen AFW | Fundering | Steen - Baksteen AFW | 300 | 250 | 100 | 0.025 | 0.1875 | 0.1875 | Material Properties - Steen - Baksteen AFW, ThermalConductivity: 0.9; Steen - Baksteen AFW, SpecificHeatCapacity: 840 J/kg/K; Steen - Baksteen AFW, MassDensity: 1600 kg/m3; Steen - Baksteen AFW, Embodied Energy: 3 (MJ/kg); Steen - Baksteen AFW, Embodied Carbon: 0.23 (kgCO₂/kg); Steen - Baksteen AFW, Name: Steen - Baksteen AFW; Steen - Baksteen AFW, Participates in Collision Detection: yes
Isolatie - Kunststof hard | Fundering | Isolatie - Kunststof hard | 140.395 | 1330 | 140 | 0.1862 | 1.40395 | 1.40395 | Material Properties - Isolatie - Kunststof hard, ThermalConductivity: 0.029; Isolatie - Kunststof hard, SpecificHeatCapacity: 1470 J/kg/K; Isolatie - Kunststof hard, MassDensity: 100 kg/m3; Isolatie - Kunststof hard, Embodied Energy: 101.5 (MJ/kg); Isolatie - Kunststof hard, Embodied Carbon: 3.48 (kgCO₂/kg); Isolatie - Kunststof hard, Name: Isolatie - Kunststof hard; Isolatie - Kunststof hard, Participates in Collision Detection: yes
Isolatie - Kunststof hard | Fundering | Isolatie - Kunststof hard | 134.212 | 870 | 140 | 0.1218 | 1.34212 | 1.34212 | Material Properties - Isolatie - Kunststof hard, ThermalConductivity: 0.029; Isolatie - Kunststof hard, SpecificHeatCapacity: 1470 J/kg/K; Isolatie - Kunststof hard, MassDensity: 100 kg/m3; Isolatie - Kunststof hard, Embodied Energy: 101.5 (MJ/kg); Isolatie - Kunststof hard, Embodied Carbon: 3.48 (kgCO₂/kg); Isolatie - Kunststof hard, Name: Isolatie - Kunststof hard; Isolatie - Kunststof hard, Participates in Collision Detection: yes
Steen - Baksteen AFW | Fundering | Steen - Baksteen AFW | 454.04 | 250 | 100 | 0.025 | 0.283775 | 0.283775 | Material Properties - Steen - Baksteen AFW, ThermalConductivity: 0.9; Steen - Baksteen AFW, SpecificHeatCapacity: 840 J/kg/K; Steen - Baksteen AFW, MassDensity: 1600 kg/m3; Steen - Baksteen AFW, Embodied Energy: 3 (MJ/kg); Steen - Baksteen AFW, Embodied Carbon: 0.23 (kgCO₂/kg); Steen - Baksteen AFW, Name: Steen - Baksteen AFW; Steen - Baksteen AFW, Participates in Collision Detection: yes
Steen - Betonblok vuilwerk | Fundering | Steen - Betonblok vuilwerk | 1126.02 | 620 | 100 | 0.062 | 0.703763 | 0.703763 | Material Properties - Steen - Betonblok vuilwerk, ThermalConductivity: 0.75; Steen - Betonblok vuilwerk, SpecificHeatCapacity: 840 J/kg/K; Steen - Betonblok vuilwerk, MassDensity: 1600 kg/m3; Steen - Betonblok vuilwerk, Embodied Energy: 0.83 (MJ/kg); Steen - Betonblok vuilwerk, Embodied Carbon: 0.1 (kgCO₂/kg); Steen - Betonblok vuilwerk, Name: Steen - Betonblok vuilwerk; Steen - Betonblok vuilwerk, Participates in Collision Detection: yes
Isolatie - Kunststof hard | Fundering | Isolatie - Kunststof hard | 36.1228 | 1330 | 140 | 0.1862 | 0.361228 | 0.361228 | Material Properties - Isolatie - Kunststof hard, ThermalConductivity: 0.029; Isolatie - Kunststof hard, SpecificHeatCapacity: 1470 J/kg/K; Isolatie - Kunststof hard, MassDensity: 100 kg/m3; Isolatie - Kunststof hard, Embodied Energy: 101.5 (MJ/kg); Isolatie - Kunststof hard, Embodied Carbon: 3.48 (kgCO₂/kg); Isolatie - Kunststof hard, Name: Isolatie - Kunststof hard; Isolatie - Kunststof hard, Participates in Collision Detection: yes
Steen - Baksteen AFW | Fundering | Steen - Baksteen AFW | 83.4402 | 250 | 100 | 0.025 | 0.0521501 | 0.05215 | Material Properties - Steen - Baksteen AFW, ThermalConductivity: 0.9; Steen - Baksteen AFW, SpecificHeatCapacity: 840 J/kg/K; Steen - Baksteen AFW, MassDensity: 1600 kg/m3; Steen - Baksteen AFW, Embodied Energy: 3 (MJ/kg); Steen - Baksteen AFW, Embodied Carbon: 0.23 (kgCO₂/kg); Steen - Baksteen AFW, Name: Steen - Baksteen AFW; Steen - Baksteen AFW, Participates in Collision Detection: yes
Steen - Betonblok vuilwerk | Fundering | Steen - Betonblok vuilwerk | 360.461 | 1080 | 100 | 0.108 | 0.225288 | 0.225288 | Material Properties - Steen - Betonblok vuilwerk, ThermalConductivity: 0.75; Steen - Betonblok vuilwerk, SpecificHeatCapacity: 840 J/kg/K; Steen - Betonblok vuilwerk, MassDensity: 1600 kg/m3; Steen - Betonblok vuilwerk, Embodied Energy: 0.83 (MJ/kg); Steen - Betonblok vuilwerk, Embodied Carbon: 0.1 (kgCO₂/kg); Steen - Betonblok vuilwerk, Name: Steen - Betonblok vuilwerk; Steen - Betonblok vuilwerk, Participates in Collision Detection: yes
Isolatie - Kunststof hard | Fundering | Isolatie - Kunststof hard | 57.0146 | 870 | 140 | 0.1218 | 0.570146 | 0.570146 | Material Properties - Isolatie - Kunststof hard, ThermalConductivity: 0.029; Isolatie - Kunststof hard, SpecificHeatCapacity: 1470 J/kg/K; Isolatie - Kunststof hard, MassDensity: 100 kg/m3; Isolatie - Kunststof hard, Embodied Energy: 101.5 (MJ/kg); Isolatie - Kunststof hard, Embodied Carbon: 3.48 (kgCO₂/kg); Isolatie - Kunststof hard, Name: Isolatie - Kunststof hard; Isolatie - Kunststof hard, Participates in Collision Detection: yes
Steen - Baksteen AFW | Fundering | Steen - Baksteen AFW | 187.24 | 250 | 100 | 0.025 | 0.117025 | 0.117025 | Material Properties - Steen - Baksteen AFW, ThermalConductivity: 0.9; Steen - Baksteen AFW, SpecificHeatCapacity: 840 J/kg/K; Steen - Baksteen AFW, MassDensity: 1600 kg/m3; Steen - Baksteen AFW, Embodied Energy: 3 (MJ/kg); Steen - Baksteen AFW, Embodied Carbon: 0.23 (kgCO₂/kg); Steen - Baksteen AFW, Name: Steen - Baksteen AFW; Steen - Baksteen AFW, Participates in Collision Detection: yes
Steen - Betonblok vuilwerk | Fundering | Steen - Betonblok vuilwerk | 464.355 | 620 | 100 | 0.062 | 0.290222 | 0.290222 | Material Properties - Steen - Betonblok vuilwerk, ThermalConductivity: 0.75; Steen - Betonblok vuilwerk, SpecificHeatCapacity: 840 J/kg/K; Steen - Betonblok vuilwerk, MassDensity: 1600 kg/m3; Steen - Betonblok vuilwerk, Embodied Energy: 0.83 (MJ/kg); Steen - Betonblok vuilwerk, Embodied Carbon: 0.1 (kgCO₂/kg); Steen - Betonblok vuilwerk, Name: Steen - Betonblok vuilwerk; Steen - Betonblok vuilwerk, Participates in Collision Detection: yes
Steen - Baksteen AFW | Fundering | Steen - Baksteen AFW | 3029.18 | 900 | 100 | 0.09 | 1.89324 | 1.89324 | Material Properties - Steen - Baksteen AFW, ThermalConductivity: 0.9; Steen - Baksteen AFW, SpecificHeatCapacity: 840 J/kg/K; Steen - Baksteen AFW, MassDensity: 1600 kg/m3; Steen - Baksteen AFW, Embodied Energy: 3 (MJ/kg); Steen - Baksteen AFW, Embodied Carbon: 0.23 (kgCO₂/kg); Steen - Baksteen AFW, Name: Steen - Baksteen AFW; Steen - Baksteen AFW, Participates in Collision Detection: yes
Steen - Betonblok vuilwerk | Fundering | Steen - Betonblok vuilwerk | 1447.28 | 430 | 100 | 0.043 | 0.904548 | 0.904548 | Material Properties - Steen - Betonblok vuilwerk, ThermalConductivity: 0.75; Steen - Betonblok vuilwerk, SpecificHeatCapacity: 840 J/kg/K; Steen - Betonblok vuilwerk, MassDensity: 1600 kg/m3; Steen - Betonblok vuilwerk, Embodied Energy: 0.83 (MJ/kg); Steen - Betonblok vuilwerk, Embodied Carbon: 0.1 (kgCO₂/kg); Steen - Betonblok vuilwerk, Name: Steen - Betonblok vuilwerk; Steen - Betonblok vuilwerk, Participates in Collision Detection: yes
Isolatie - Kunststof hard | Fundering | Isolatie - Kunststof hard | 388.227 | 1330 | 140 | 0.1862 | 3.88227 | 3.88227 | Material Properties - Isolatie - Kunststof hard, ThermalConductivity: 0.029; Isolatie - Kunststof hard, SpecificHeatCapacity: 1470 J/kg/K; Isolatie - Kunststof hard, MassDensity: 100 kg/m3; Isolatie - Kunststof hard, Embodied Energy: 101.5 (MJ/kg); Isolatie - Kunststof hard, Embodied Carbon: 3.48 (kgCO₂/kg); Isolatie - Kunststof hard, Name: Isolatie - Kunststof hard; Isolatie - Kunststof hard, Participates in Collision Detection: yes
Membraan - waterdicht | Fundering | Membraan - waterdicht | 90.978 | 1320 | 5 | 0.0066 | 0.0866458 | 0.090057 | Component Quantities - Projected Component Area (Net): 17.3292 m2; Projected Component Area (Gross): 18.0114 m2; Component Thickness: 5 mm; Material Properties - Membraan - waterdicht, ThermalConductivity: 0.2; Membraan - waterdicht, SpecificHeatCapacity: 1840 J/kg/K; Membraan - waterdicht, MassDensity: 1050 kg/m3; Membraan - waterdicht, Embodied Energy: 51 (MJ/kg); Membraan - waterdicht, Embodied Carbon: 0.38 (kgCO₂/kg); Membraan - waterdicht, Name: Membraan - waterdicht; Membraan - waterdicht, Participates in Collision Detection: yes
Isolatie - Kunststof hard | Fundering | Isolatie - Kunststof hard | 248.362 | 1320 | 140 | 0.1848 | 2.48362 | 2.52067 | Component Quantities - Projected Component Area (Net): 18.0022 m2; Projected Component Area (Gross): 18.0048 m2; Component Thickness: 140 mm; Material Properties - Isolatie - Kunststof hard, ThermalConductivity: 0.029; Isolatie - Kunststof hard, SpecificHeatCapacity: 1470 J/kg/K; Isolatie - Kunststof hard, MassDensity: 100 kg/m3; Isolatie - Kunststof hard, Embodied Energy: 101.5 (MJ/kg); Isolatie - Kunststof hard, Embodied Carbon: 3.48 (kgCO₂/kg); Isolatie - Kunststof hard, Name: Isolatie - Kunststof hard; Isolatie - Kunststof hard, Participates in Collision Detection: yes
Steen - Betonblok vuilwerk | Fundering | Steen - Betonblok vuilwerk | 2195.3 | 620 | 100 | 0.062 | 1.37206 | 1.37206 | Material Properties - Steen - Betonblok vuilwerk, ThermalConductivity: 0.75; Steen - Betonblok vuilwerk, SpecificHeatCapacity: 840 J/kg/K; Steen - Betonblok vuilwerk, MassDensity: 1600 kg/m3; Steen - Betonblok vuilwerk, Embodied Energy: 0.83 (MJ/kg); Steen - Betonblok vuilwerk, Embodied Carbon: 0.1 (kgCO₂/kg); Steen - Betonblok vuilwerk, Name: Steen - Betonblok vuilwerk; Steen - Betonblok vuilwerk, Participates in Collision Detection: yes
Steen - Baksteen AFW | Fundering | Steen - Baksteen AFW | 885.201 | 250 | 100 | 0.025 | 0.553251 | 0.553251 | Material Properties - Steen - Baksteen AFW, ThermalConductivity: 0.9; Steen - Baksteen AFW, SpecificHeatCapacity: 840 J/kg/K; Steen - Baksteen AFW, MassDensity: 1600 kg/m3; Steen - Baksteen AFW, Embodied Energy: 3 (MJ/kg); Steen - Baksteen AFW, Embodied Carbon: 0.23 (kgCO₂/kg); Steen - Baksteen AFW, Name: Steen - Baksteen AFW; Steen - Baksteen AFW, Participates in Collision Detection: yes
Isolatie - Kunststof hard | Fundering | Isolatie - Kunststof hard | 265.987 | 870 | 140 | 0.1218 | 2.65987 | 2.65987 | Material Properties - Isolatie - Kunststof hard, ThermalConductivity: 0.029; Isolatie - Kunststof hard, SpecificHeatCapacity: 1470 J/kg/K; Isolatie - Kunststof hard, MassDensity: 100 kg/m3; Isolatie - Kunststof hard, Embodied Energy: 101.5 (MJ/kg); Isolatie - Kunststof hard, Embodied Carbon: 3.48 (kgCO₂/kg); Isolatie - Kunststof hard, Name: Isolatie - Kunststof hard; Isolatie - Kunststof hard, Participates in Collision Detection: yes
Isolatie - Kunststof hard | Fundering | Isolatie - Kunststof hard | 79.5235 | 870 | 140 | 0.1218 | 0.795235 | 0.795235 | Material Properties - Isolatie - Kunststof hard, ThermalConductivity: 0.029; Isolatie - Kunststof hard, SpecificHeatCapacity: 1470 J/kg/K; Isolatie - Kunststof hard, MassDensity: 100 kg/m3; Isolatie - Kunststof hard, Embodied Energy: 101.5 (MJ/kg); Isolatie - Kunststof hard, Embodied Carbon: 3.48 (kgCO₂/kg); Isolatie - Kunststof hard, Name: Isolatie - Kunststof hard; Isolatie - Kunststof hard, Participates in Collision Detection: yes
Steen - Baksteen AFW | Fundering | Steen - Baksteen AFW | 261.161 | 250 | 100 | 0.025 | 0.163226 | 0.163226 | Material Properties - Steen - Baksteen AFW, ThermalConductivity: 0.9; Steen - Baksteen AFW, SpecificHeatCapacity: 840 J/kg/K; Steen - Baksteen AFW, MassDensity: 1600 kg/m3; Steen - Baksteen AFW, Embodied Energy: 3 (MJ/kg); Steen - Baksteen AFW, Embodied Carbon: 0.23 (kgCO₂/kg); Steen - Baksteen AFW, Name: Steen - Baksteen AFW; Steen - Baksteen AFW, Participates in Collision Detection: yes
Steen - Betonblok vuilwerk | Fundering | Steen - Betonblok vuilwerk | 647.679 | 620 | 100 | 0.062 | 0.404799 | 0.404799 | Material Properties - Steen - Betonblok vuilwerk, ThermalConductivity: 0.75; Steen - Betonblok vuilwerk, SpecificHeatCapacity: 840 J/kg/K; Steen - Betonblok vuilwerk, MassDensity: 1600 kg/m3; Steen - Betonblok vuilwerk, Embodied Energy: 0.83 (MJ/kg); Steen - Betonblok vuilwerk, Embodied Carbon: 0.1 (kgCO₂/kg); Steen - Betonblok vuilwerk, Name: Steen - Betonblok vuilwerk; Steen - Betonblok vuilwerk, Participates in Collision Detection: yes
Isolatie - Kunststof hard | Fundering | Isolatie - Kunststof hard | 68.9389 | 870 | 140 | 0.1218 | 0.689389 | 0.689389 | Material Properties - Isolatie - Kunststof hard, ThermalConductivity: 0.029; Isolatie - Kunststof hard, SpecificHeatCapacity: 1470 J/kg/K; Isolatie - Kunststof hard, MassDensity: 100 kg/m3; Isolatie - Kunststof hard, Embodied Energy: 101.5 (MJ/kg); Isolatie - Kunststof hard, Embodied Carbon: 3.48 (kgCO₂/kg); Isolatie - Kunststof hard, Name: Isolatie - Kunststof hard; Isolatie - Kunststof hard, Participates in Collision Detection: yes
Steen - Baksteen AFW | Fundering | Steen - Baksteen AFW | 220.56 | 250 | 100 | 0.025 | 0.13785 | 0.13785 | Material Properties - Steen - Baksteen AFW, ThermalConductivity: 0.9; Steen - Baksteen AFW, SpecificHeatCapacity: 840 J/kg/K; Steen - Baksteen AFW, MassDensity: 1600 kg/m3; Steen - Baksteen AFW, Embodied Energy: 3 (MJ/kg); Steen - Baksteen AFW, Embodied Carbon: 0.23 (kgCO₂/kg); Steen - Baksteen AFW, Name: Steen - Baksteen AFW; Steen - Baksteen AFW, Participates in Collision Detection: yes
Steen - Betonblok vuilwerk | Fundering | Steen - Betonblok vuilwerk | 546.99 | 620 | 100 | 0.062 | 0.341869 | 0.341869 | Material Properties - Steen - Betonblok vuilwerk, ThermalConductivity: 0.75; Steen - Betonblok vuilwerk, SpecificHeatCapacity: 840 J/kg/K; Steen - Betonblok vuilwerk, MassDensity: 1600 kg/m3; Steen - Betonblok vuilwerk, Embodied Energy: 0.83 (MJ/kg); Steen - Betonblok vuilwerk, Embodied Carbon: 0.1 (kgCO₂/kg); Steen - Betonblok vuilwerk, Name: Steen - Betonblok vuilwerk; Steen - Betonblok vuilwerk, Participates in Collision Detection: yes
Steen - Betonblok vuilwerk | Fundering | Steen - Betonblok vuilwerk | 1512.7 | 620 | 100 | 0.062 | 0.945438 | 0.945438 | Material Properties - Steen - Betonblok vuilwerk, ThermalConductivity: 0.75; Steen - Betonblok vuilwerk, SpecificHeatCapacity: 840 J/kg/K; Steen - Betonblok vuilwerk, MassDensity: 1600 kg/m3; Steen - Betonblok vuilwerk, Embodied Energy: 0.83 (MJ/kg); Steen - Betonblok vuilwerk, Embodied Carbon: 0.1 (kgCO₂/kg); Steen - Betonblok vuilwerk, Name: Steen - Betonblok vuilwerk; Steen - Betonblok vuilwerk, Participates in Collision Detection: yes
Steen - Baksteen AFW | Fundering | Steen - Baksteen AFW | 609.96 | 250 | 100 | 0.025 | 0.381225 | 0.381225 | Material Properties - Steen - Baksteen AFW, ThermalConductivity: 0.9; Steen - Baksteen AFW, SpecificHeatCapacity: 840 J/kg/K; Steen - Baksteen AFW, MassDensity: 1600 kg/m3; Steen - Baksteen AFW, Embodied Energy: 3 (MJ/kg); Steen - Baksteen AFW, Embodied Carbon: 0.23 (kgCO₂/kg); Steen - Baksteen AFW, Name: Steen - Baksteen AFW; Steen - Baksteen AFW, Participates in Collision Detection: yes
Isolatie - Kunststof hard | Fundering | Isolatie - Kunststof hard | 189.777 | 870 | 140 | 0.1218 | 1.89777 | 1.89777 | Material Properties - Isolatie - Kunststof hard, ThermalConductivity: 0.029; Isolatie - Kunststof hard, SpecificHeatCapacity: 1470 J/kg/K; Isolatie - Kunststof hard, MassDensity: 100 kg/m3; Isolatie - Kunststof hard, Embodied Energy: 101.5 (MJ/kg); Isolatie - Kunststof hard, Embodied Carbon: 3.48 (kgCO₂/kg); Isolatie - Kunststof hard, Name: Isolatie - Kunststof hard; Isolatie - Kunststof hard, Participates in Collision Detection: yes
Steen - Betonblok vuilwerk | Fundering | Steen - Betonblok vuilwerk | 2537.34 | 620 | 100 | 0.062 | 1.58584 | 1.58584 | Material Properties - Steen - Betonblok vuilwerk, ThermalConductivity: 0.75; Steen - Betonblok vuilwerk, SpecificHeatCapacity: 840 J/kg/K; Steen - Betonblok vuilwerk, MassDensity: 1600 kg/m3; Steen - Betonblok vuilwerk, Embodied Energy: 0.83 (MJ/kg); Steen - Betonblok vuilwerk, Embodied Carbon: 0.1 (kgCO₂/kg); Steen - Betonblok vuilwerk, Name: Steen - Betonblok vuilwerk; Steen - Betonblok vuilwerk, Participates in Collision Detection: yes
Steen - Baksteen AFW | Fundering | Steen - Baksteen AFW | 1023.12 | 250 | 100 | 0.025 | 0.639451 | 0.639451 | Material Properties - Steen - Baksteen AFW, ThermalConductivity: 0.9; Steen - Baksteen AFW, SpecificHeatCapacity: 840 J/kg/K; Steen - Baksteen AFW, MassDensity: 1600 kg/m3; Steen - Baksteen AFW, Embodied Energy: 3 (MJ/kg); Steen - Baksteen AFW, Embodied Carbon: 0.23 (kgCO₂/kg); Steen - Baksteen AFW, Name: Steen - Baksteen AFW; Steen - Baksteen AFW, Participates in Collision Detection: yes
Isolatie - Kunststof hard | Fundering | Isolatie - Kunststof hard | 315.584 | 870 | 140 | 0.1218 | 3.15584 | 3.15584 | Material Properties - Isolatie - Kunststof hard, ThermalConductivity: 0.029; Isolatie - Kunststof hard, SpecificHeatCapacity: 1470 J/kg/K; Isolatie - Kunststof hard, MassDensity: 100 kg/m3; Isolatie - Kunststof hard, Embodied Energy: 101.5 (MJ/kg); Isolatie - Kunststof hard, Embodied Carbon: 3.48 (kgCO₂/kg); Isolatie - Kunststof hard, Name: Isolatie - Kunststof hard; Isolatie - Kunststof hard, Participates in Collision Detection: yes
Steen - Betonblok vuilwerk | Fundering | Steen - Betonblok vuilwerk | 334.304 | 620 | 100 | 0.062 | 0.20894 | 0.20894 | Material Properties - Steen - Betonblok vuilwerk, ThermalConductivity: 0.75; Steen - Betonblok vuilwerk, SpecificHeatCapacity: 840 J/kg/K; Steen - Betonblok vuilwerk, MassDensity: 1600 kg/m3; Steen - Betonblok vuilwerk, Embodied Energy: 0.83 (MJ/kg); Steen - Betonblok vuilwerk, Embodied Carbon: 0.1 (kgCO₂/kg); Steen - Betonblok vuilwerk, Name: Steen - Betonblok vuilwerk; Steen - Betonblok vuilwerk, Participates in Collision Detection: yes
Steen - Baksteen AFW | Fundering | Steen - Baksteen AFW | 134.8 | 250 | 100 | 0.025 | 0.0842499 | 0.0842499 | Material Properties - Steen - Baksteen AFW, ThermalConductivity: 0.9; Steen - Baksteen AFW, SpecificHeatCapacity: 840 J/kg/K; Steen - Baksteen AFW, MassDensity: 1600 kg/m3; Steen - Baksteen AFW, Embodied Energy: 3 (MJ/kg); Steen - Baksteen AFW, Embodied Carbon: 0.23 (kgCO₂/kg); Steen - Baksteen AFW, Name: Steen - Baksteen AFW; Steen - Baksteen AFW, Participates in Collision Detection: yes
Isolatie - Kunststof hard | Fundering | Isolatie - Kunststof hard | 41.0466 | 870 | 140 | 0.1218 | 0.410466 | 0.410466 | Material Properties - Isolatie - Kunststof hard, ThermalConductivity: 0.029; Isolatie - Kunststof hard, SpecificHeatCapacity: 1470 J/kg/K; Isolatie - Kunststof hard, MassDensity: 100 kg/m3; Isolatie - Kunststof hard, Embodied Energy: 101.5 (MJ/kg); Isolatie - Kunststof hard, Embodied Carbon: 3.48 (kgCO₂/kg); Isolatie - Kunststof hard, Name: Isolatie - Kunststof hard; Isolatie - Kunststof hard, Participates in Collision Detection: yes
Steen - Betonblok vuilwerk | Fundering | Steen - Betonblok vuilwerk | 1918.73 | 620 | 100 | 0.062 | 1.1992 | 1.1992 | Material Properties - Steen - Betonblok vuilwerk, ThermalConductivity: 0.75; Steen - Betonblok vuilwerk, SpecificHeatCapacity: 840 J/kg/K; Steen - Betonblok vuilwerk, MassDensity: 1600 kg/m3; Steen - Betonblok vuilwerk, Embodied Energy: 0.83 (MJ/kg); Steen - Betonblok vuilwerk, Embodied Carbon: 0.1 (kgCO₂/kg); Steen - Betonblok vuilwerk, Name: Steen - Betonblok vuilwerk; Steen - Betonblok vuilwerk, Participates in Collision Detection: yes
Steen - Baksteen AFW | Fundering | Steen - Baksteen AFW | 773.68 | 250 | 100 | 0.025 | 0.48355 | 0.48355 | Material Properties - Steen - Baksteen AFW, ThermalConductivity: 0.9; Steen - Baksteen AFW, SpecificHeatCapacity: 840 J/kg/K; Steen - Baksteen AFW, MassDensity: 1600 kg/m3; Steen - Baksteen AFW, Embodied Energy: 3 (MJ/kg); Steen - Baksteen AFW, Embodied Carbon: 0.23 (kgCO₂/kg); Steen - Baksteen AFW, Name: Steen - Baksteen AFW; Steen - Baksteen AFW, Participates in Collision Detection: yes
Isolatie - Kunststof hard | Fundering | Isolatie - Kunststof hard | 231.542 | 870 | 140 | 0.1218 | 2.31542 | 2.31542 | Material Properties - Isolatie - Kunststof hard, ThermalConductivity: 0.029; Isolatie - Kunststof hard, SpecificHeatCapacity: 1470 J/kg/K; Isolatie - Kunststof hard, MassDensity: 100 kg/m3; Isolatie - Kunststof hard, Embodied Energy: 101.5 (MJ/kg); Isolatie - Kunststof hard, Embodied Carbon: 3.48 (kgCO₂/kg); Isolatie - Kunststof hard, Name: Isolatie - Kunststof hard; Isolatie - Kunststof hard, Participates in Collision Detection: yes
Steen - Betonblok vuilwerk | Fundering | Steen - Betonblok vuilwerk | 3253.96 | 620 | 100 | 0.062 | 2.03372 | 2.03372 | Material Properties - Steen - Betonblok vuilwerk, ThermalConductivity: 0.75; Steen - Betonblok vuilwerk, SpecificHeatCapacity: 840 J/kg/K; Steen - Betonblok vuilwerk, MassDensity: 1600 kg/m3; Steen - Betonblok vuilwerk, Embodied Energy: 0.83 (MJ/kg); Steen - Betonblok vuilwerk, Embodied Carbon: 0.1 (kgCO₂/kg); Steen - Betonblok vuilwerk, Name: Steen - Betonblok vuilwerk; Steen - Betonblok vuilwerk, Participates in Collision Detection: yes
Steen - Baksteen AFW | Fundering | Steen - Baksteen AFW | 1312.08 | 250 | 100 | 0.025 | 0.82005 | 0.82005 | Material Properties - Steen - Baksteen AFW, ThermalConductivity: 0.9; Steen - Baksteen AFW, SpecificHeatCapacity: 840 J/kg/K; Steen - Baksteen AFW, MassDensity: 1600 kg/m3; Steen - Baksteen AFW, Embodied Energy: 3 (MJ/kg); Steen - Baksteen AFW, Embodied Carbon: 0.23 (kgCO₂/kg); Steen - Baksteen AFW, Name: Steen - Baksteen AFW; Steen - Baksteen AFW, Participates in Collision Detection: yes
Isolatie - Kunststof hard | Fundering | Isolatie - Kunststof hard | 395.485 | 870 | 140 | 0.1218 | 3.95485 | 3.95485 | Material Properties - Isolatie - Kunststof hard, ThermalConductivity: 0.029; Isolatie - Kunststof hard, SpecificHeatCapacity: 1470 J/kg/K; Isolatie - Kunststof hard, MassDensity: 100 kg/m3; Isolatie - Kunststof hard, Embodied Energy: 101.5 (MJ/kg); Isolatie - Kunststof hard, Embodied Carbon: 3.48 (kgCO₂/kg); Isolatie - Kunststof hard, Name: Isolatie - Kunststof hard; Isolatie - Kunststof hard, Participates in Collision Detection: yes
Steen - Betonblok vuilwerk | Fundering | Steen - Betonblok vuilwerk | 2344.89 | 620 | 100 | 0.062 | 1.46555 | 1.46555 | Material Properties - Steen - Betonblok vuilwerk, ThermalConductivity: 0.75; Steen - Betonblok vuilwerk, SpecificHeatCapacity: 840 J/kg/K; Steen - Betonblok vuilwerk, MassDensity: 1600 kg/m3; Steen - Betonblok vuilwerk, Embodied Energy: 0.83 (MJ/kg); Steen - Betonblok vuilwerk, Embodied Carbon: 0.1 (kgCO₂/kg); Steen - Betonblok vuilwerk, Name: Steen - Betonblok vuilwerk; Steen - Betonblok vuilwerk, Participates in Collision Detection: yes
Steen - Baksteen AFW | Fundering | Steen - Baksteen AFW | 945.519 | 250 | 100 | 0.025 | 0.59095 | 0.59095 | Material Properties - Steen - Baksteen AFW, ThermalConductivity: 0.9; Steen - Baksteen AFW, SpecificHeatCapacity: 840 J/kg/K; Steen - Baksteen AFW, MassDensity: 1600 kg/m3; Steen - Baksteen AFW, Embodied Energy: 3 (MJ/kg); Steen - Baksteen AFW, Embodied Carbon: 0.23 (kgCO₂/kg); Steen - Baksteen AFW, Name: Steen - Baksteen AFW; Steen - Baksteen AFW, Participates in Collision Detection: yes
Isolatie - Kunststof hard | Fundering | Isolatie - Kunststof hard | 283.867 | 870 | 140 | 0.1218 | 2.83867 | 2.83867 | Material Properties - Isolatie - Kunststof hard, ThermalConductivity: 0.029; Isolatie - Kunststof hard, SpecificHeatCapacity: 1470 J/kg/K; Isolatie - Kunststof hard, MassDensity: 100 kg/m3; Isolatie - Kunststof hard, Embodied Energy: 101.5 (MJ/kg); Isolatie - Kunststof hard, Embodied Carbon: 3.48 (kgCO₂/kg); Isolatie - Kunststof hard, Name: Isolatie - Kunststof hard; Isolatie - Kunststof hard, Participates in Collision Detection: yes
Steen - Betonblok vuilwerk | Fundering | Steen - Betonblok vuilwerk | 93.2479 | 620 | 100 | 0.062 | 0.0582799 | 0.0582799 | Material Properties - Steen - Betonblok vuilwerk, ThermalConductivity: 0.75; Steen - Betonblok vuilwerk, SpecificHeatCapacity: 840 J/kg/K; Steen - Betonblok vuilwerk, MassDensity: 1600 kg/m3; Steen - Betonblok vuilwerk, Embodied Energy: 0.83 (MJ/kg); Steen - Betonblok vuilwerk, Embodied Carbon: 0.1 (kgCO₂/kg); Steen - Betonblok vuilwerk, Name: Steen - Betonblok vuilwerk; Steen - Betonblok vuilwerk, Participates in Collision Detection: yes
Steen - Baksteen AFW | Fundering | Steen - Baksteen AFW | 37.5999 | 250 | 100 | 0.025 | 0.0235 | 0.0235 | Material Properties - Steen - Baksteen AFW, ThermalConductivity: 0.9; Steen - Baksteen AFW, SpecificHeatCapacity: 840 J/kg/K; Steen - Baksteen AFW, MassDensity: 1600 kg/m3; Steen - Baksteen AFW, Embodied Energy: 3 (MJ/kg); Steen - Baksteen AFW, Embodied Carbon: 0.23 (kgCO₂/kg); Steen - Baksteen AFW, Name: Steen - Baksteen AFW; Steen - Baksteen AFW, Participates in Collision Detection: yes
2 x Isolatie - Kunststof hard | Fundering | Isolatie - Kunststof hard | 11.4492 | 870 | 140 | 0.1218 | 0.114492 | 0.114492 | Material Properties - Isolatie - Kunststof hard, ThermalConductivity: 0.029; Isolatie - Kunststof hard, SpecificHeatCapacity: 1470 J/kg/K; Isolatie - Kunststof hard, MassDensity: 100 kg/m3; Isolatie - Kunststof hard, Embodied Energy: 101.5 (MJ/kg); Isolatie - Kunststof hard, Embodied Carbon: 3.48 (kgCO₂/kg); Isolatie - Kunststof hard, Name: Isolatie - Kunststof hard; Isolatie - Kunststof hard, Participates in Collision Detection: yes
Steen - Betonblok vuilwerk | Fundering | Steen - Betonblok vuilwerk | 519.018 | 620 | 100 | 0.062 | 0.324386 | 0.324386 | Material Properties - Steen - Betonblok vuilwerk, ThermalConductivity: 0.75; Steen - Betonblok vuilwerk, SpecificHeatCapacity: 840 J/kg/K; Steen - Betonblok vuilwerk, MassDensity: 1600 kg/m3; Steen - Betonblok vuilwerk, Embodied Energy: 0.83 (MJ/kg); Steen - Betonblok vuilwerk, Embodied Carbon: 0.1 (kgCO₂/kg); Steen - Betonblok vuilwerk, Name: Steen - Betonblok vuilwerk; Steen - Betonblok vuilwerk, Participates in Collision Detection: yes
Steen - Baksteen AFW | Fundering | Steen - Baksteen AFW | 209.281 | 250 | 100 | 0.025 | 0.130801 | 0.130801 | Material Properties - Steen - Baksteen AFW, ThermalConductivity: 0.9; Steen - Baksteen AFW, SpecificHeatCapacity: 840 J/kg/K; Steen - Baksteen AFW, MassDensity: 1600 kg/m3; Steen - Baksteen AFW, Embodied Energy: 3 (MJ/kg); Steen - Baksteen AFW, Embodied Carbon: 0.23 (kgCO₂/kg); Steen - Baksteen AFW, Name: Steen - Baksteen AFW; Steen - Baksteen AFW, Participates in Collision Detection: yes
Isolatie - Kunststof hard | Fundering | Isolatie - Kunststof hard | 67.7699 | 870 | 140 | 0.1218 | 0.677699 | 0.677699 | Material Properties - Isolatie - Kunststof hard, ThermalConductivity: 0.029; Isolatie - Kunststof hard, SpecificHeatCapacity: 1470 J/kg/K; Isolatie - Kunststof hard, MassDensity: 100 kg/m3; Isolatie - Kunststof hard, Embodied Energy: 101.5 (MJ/kg); Isolatie - Kunststof hard, Embodied Carbon: 3.48 (kgCO₂/kg); Isolatie - Kunststof hard, Name: Isolatie - Kunststof hard; Isolatie - Kunststof hard, Participates in Collision Detection: yes
Steen - Betonblok vuilwerk | Fundering | Steen - Betonblok vuilwerk | 93.248 | 620 | 100 | 0.062 | 0.05828 | 0.05828 | Material Properties - Steen - Betonblok vuilwerk, ThermalConductivity: 0.75; Steen - Betonblok vuilwerk, SpecificHeatCapacity: 840 J/kg/K; Steen - Betonblok vuilwerk, MassDensity: 1600 kg/m3; Steen - Betonblok vuilwerk, Embodied Energy: 0.83 (MJ/kg); Steen - Betonblok vuilwerk, Embodied Carbon: 0.1 (kgCO₂/kg); Steen - Betonblok vuilwerk, Name: Steen - Betonblok vuilwerk; Steen - Betonblok vuilwerk, Participates in Collision Detection: yes
Steen - Baksteen AFW | Fundering | Steen - Baksteen AFW | 37.6 | 250 | 100 | 0.025 | 0.0235 | 0.0235 | Material Properties - Steen - Baksteen AFW, ThermalConductivity: 0.9; Steen - Baksteen AFW, SpecificHeatCapacity: 840 J/kg/K; Steen - Baksteen AFW, MassDensity: 1600 kg/m3; Steen - Baksteen AFW, Embodied Energy: 3 (MJ/kg); Steen - Baksteen AFW, Embodied Carbon: 0.23 (kgCO₂/kg); Steen - Baksteen AFW, Name: Steen - Baksteen AFW; Steen - Baksteen AFW, Participates in Collision Detection: yes
Steen - Betonblok vuilwerk | Fundering | Steen - Betonblok vuilwerk | 2349.25 | 620 | 100 | 0.062 | 1.46828 | 1.46828 | Material Properties - Steen - Betonblok vuilwerk, ThermalConductivity: 0.75; Steen - Betonblok vuilwerk, SpecificHeatCapacity: 840 J/kg/K; Steen - Betonblok vuilwerk, MassDensity: 1600 kg/m3; Steen - Betonblok vuilwerk, Embodied Energy: 0.83 (MJ/kg); Steen - Betonblok vuilwerk, Embodied Carbon: 0.1 (kgCO₂/kg); Steen - Betonblok vuilwerk, Name: Steen - Betonblok vuilwerk; Steen - Betonblok vuilwerk, Participates in Collision Detection: yes
Steen - Baksteen AFW | Fundering | Steen - Baksteen AFW | 947.28 | 250 | 100 | 0.025 | 0.59205 | 0.59205 | Material Properties - Steen - Baksteen AFW, ThermalConductivity: 0.9; Steen - Baksteen AFW, SpecificHeatCapacity: 840 J/kg/K; Steen - Baksteen AFW, MassDensity: 1600 kg/m3; Steen - Baksteen AFW, Embodied Energy: 3 (MJ/kg); Steen - Baksteen AFW, Embodied Carbon: 0.23 (kgCO₂/kg); Steen - Baksteen AFW, Name: Steen - Baksteen AFW; Steen - Baksteen AFW, Participates in Collision Detection: yes
Isolatie - Kunststof hard | Fundering | Isolatie - Kunststof hard | 284.403 | 870 | 140 | 0.1218 | 2.84403 | 2.84403 | Material Properties - Isolatie - Kunststof hard, ThermalConductivity: 0.029; Isolatie - Kunststof hard, SpecificHeatCapacity: 1470 J/kg/K; Isolatie - Kunststof hard, MassDensity: 100 kg/m3; Isolatie - Kunststof hard, Embodied Energy: 101.5 (MJ/kg); Isolatie - Kunststof hard, Embodied Carbon: 3.48 (kgCO₂/kg); Isolatie - Kunststof hard, Name: Isolatie - Kunststof hard; Isolatie - Kunststof hard, Participates in Collision Detection: yes
Steen - Betonblok vuilwerk | Fundering | Steen - Betonblok vuilwerk | 1352.69 | 620 | 100 | 0.062 | 0.845431 | 0.845431 | Material Properties - Steen - Betonblok vuilwerk, ThermalConductivity: 0.75; Steen - Betonblok vuilwerk, SpecificHeatCapacity: 840 J/kg/K; Steen - Betonblok vuilwerk, MassDensity: 1600 kg/m3; Steen - Betonblok vuilwerk, Embodied Energy: 0.83 (MJ/kg); Steen - Betonblok vuilwerk, Embodied Carbon: 0.1 (kgCO₂/kg); Steen - Betonblok vuilwerk, Name: Steen - Betonblok vuilwerk; Steen - Betonblok vuilwerk, Participates in Collision Detection: yes
Steen - Baksteen AFW | Fundering | Steen - Baksteen AFW | 545.44 | 250 | 100 | 0.025 | 0.3409 | 0.3409 | Material Properties - Steen - Baksteen AFW, ThermalConductivity: 0.9; Steen - Baksteen AFW, SpecificHeatCapacity: 840 J/kg/K; Steen - Baksteen AFW, MassDensity: 1600 kg/m3; Steen - Baksteen AFW, Embodied Energy: 3 (MJ/kg); Steen - Baksteen AFW, Embodied Carbon: 0.23 (kgCO₂/kg); Steen - Baksteen AFW, Name: Steen - Baksteen AFW; Steen - Baksteen AFW, Participates in Collision Detection: yes
Isolatie - Kunststof hard | Fundering | Isolatie - Kunststof hard | 166.086 | 870 | 140 | 0.1218 | 1.66086 | 1.66086 | Material Properties - Isolatie - Kunststof hard, ThermalConductivity: 0.029; Isolatie - Kunststof hard, SpecificHeatCapacity: 1470 J/kg/K; Isolatie - Kunststof hard, MassDensity: 100 kg/m3; Isolatie - Kunststof hard, Embodied Energy: 101.5 (MJ/kg); Isolatie - Kunststof hard, Embodied Carbon: 3.48 (kgCO₂/kg); Isolatie - Kunststof hard, Name: Isolatie - Kunststof hard; Isolatie - Kunststof hard, Participates in Collision Detection: yes
Steen - Betonblok vuilwerk | Fundering | Steen - Betonblok vuilwerk | 352.16 | 620 | 100 | 0.062 | 0.2201 | 0.2201 | Material Properties - Steen - Betonblok vuilwerk, ThermalConductivity: 0.75; Steen - Betonblok vuilwerk, SpecificHeatCapacity: 840 J/kg/K; Steen - Betonblok vuilwerk, MassDensity: 1600 kg/m3; Steen - Betonblok vuilwerk, Embodied Energy: 0.83 (MJ/kg); Steen - Betonblok vuilwerk, Embodied Carbon: 0.1 (kgCO₂/kg); Steen - Betonblok vuilwerk, Name: Steen - Betonblok vuilwerk; Steen - Betonblok vuilwerk, Participates in Collision Detection: yes
Steen - Baksteen AFW | Fundering | Steen - Baksteen AFW | 142 | 250 | 100 | 0.025 | 0.08875 | 0.08875 | Material Properties - Steen - Baksteen AFW, ThermalConductivity: 0.9; Steen - Baksteen AFW, SpecificHeatCapacity: 840 J/kg/K; Steen - Baksteen AFW, MassDensity: 1600 kg/m3; Steen - Baksteen AFW, Embodied Energy: 3 (MJ/kg); Steen - Baksteen AFW, Embodied Carbon: 0.23 (kgCO₂/kg); Steen - Baksteen AFW, Name: Steen - Baksteen AFW; Steen - Baksteen AFW, Participates in Collision Detection: yes
Isolatie - Kunststof hard | Fundering | Isolatie - Kunststof hard | 43.239 | 870 | 140 | 0.1218 | 0.43239 | 0.43239 | Material Properties - Isolatie - Kunststof hard, ThermalConductivity: 0.029; Isolatie - Kunststof hard, SpecificHeatCapacity: 1470 J/kg/K; Isolatie - Kunststof hard, MassDensity: 100 kg/m3; Isolatie - Kunststof hard, Embodied Energy: 101.5 (MJ/kg); Isolatie - Kunststof hard, Embodied Carbon: 3.48 (kgCO₂/kg); Isolatie - Kunststof hard, Name: Isolatie - Kunststof hard; Isolatie - Kunststof hard, Participates in Collision Detection: yes
Steen - Betonblok vuilwerk | Fundering | Steen - Betonblok vuilwerk | 2542.93 | 1080 | 100 | 0.108 | 1.58933 | 1.58933 | Material Properties - Steen - Betonblok vuilwerk, ThermalConductivity: 0.75; Steen - Betonblok vuilwerk, SpecificHeatCapacity: 840 J/kg/K; Steen - Betonblok vuilwerk, MassDensity: 1600 kg/m3; Steen - Betonblok vuilwerk, Embodied Energy: 0.83 (MJ/kg); Steen - Betonblok vuilwerk, Embodied Carbon: 0.1 (kgCO₂/kg); Steen - Betonblok vuilwerk, Name: Steen - Betonblok vuilwerk; Steen - Betonblok vuilwerk, Participates in Collision Detection: yes
Steen - Baksteen AFW | Fundering | Steen - Baksteen AFW | 588.641 | 250 | 100 | 0.025 | 0.3679 | 0.3679 | Material Properties - Steen - Baksteen AFW, ThermalConductivity: 0.9; Steen - Baksteen AFW, SpecificHeatCapacity: 840 J/kg/K; Steen - Baksteen AFW, MassDensity: 1600 kg/m3; Steen - Baksteen AFW, Embodied Energy: 3 (MJ/kg); Steen - Baksteen AFW, Embodied Carbon: 0.23 (kgCO₂/kg); Steen - Baksteen AFW, Name: Steen - Baksteen AFW; Steen - Baksteen AFW, Participates in Collision Detection: yes
Isolatie - Kunststof hard | Fundering | Isolatie - Kunststof hard | 270.549 | 1330 | 140 | 0.1862 | 2.70549 | 2.70549 | Material Properties - Isolatie - Kunststof hard, ThermalConductivity: 0.029; Isolatie - Kunststof hard, SpecificHeatCapacity: 1470 J/kg/K; Isolatie - Kunststof hard, MassDensity: 100 kg/m3; Isolatie - Kunststof hard, Embodied Energy: 101.5 (MJ/kg); Isolatie - Kunststof hard, Embodied Carbon: 3.48 (kgCO₂/kg); Isolatie - Kunststof hard, Name: Isolatie - Kunststof hard; Isolatie - Kunststof hard, Participates in Collision Detection: yes
Isolatie - Kunststof hard | Fundering | Isolatie - Kunststof hard | 378.481 | 870 | 140 | 0.1218 | 3.78481 | 3.78481 | Material Properties - Isolatie - Kunststof hard, ThermalConductivity: 0.029; Isolatie - Kunststof hard, SpecificHeatCapacity: 1470 J/kg/K; Isolatie - Kunststof hard, MassDensity: 100 kg/m3; Isolatie - Kunststof hard, Embodied Energy: 101.5 (MJ/kg); Isolatie - Kunststof hard, Embodied Carbon: 3.48 (kgCO₂/kg); Isolatie - Kunststof hard, Name: Isolatie - Kunststof hard; Isolatie - Kunststof hard, Participates in Collision Detection: yes
Steen - Baksteen AFW | Fundering | Steen - Baksteen AFW | 1250.4 | 250 | 100 | 0.025 | 0.7815 | 0.7815 | Material Properties - Steen - Baksteen AFW, ThermalConductivity: 0.9; Steen - Baksteen AFW, SpecificHeatCapacity: 840 J/kg/K; Steen - Baksteen AFW, MassDensity: 1600 kg/m3; Steen - Baksteen AFW, Embodied Energy: 3 (MJ/kg); Steen - Baksteen AFW, Embodied Carbon: 0.23 (kgCO₂/kg); Steen - Baksteen AFW, Name: Steen - Baksteen AFW; Steen - Baksteen AFW, Participates in Collision Detection: yes
Steen - Betonblok vuilwerk | Fundering | Steen - Betonblok vuilwerk | 3100.99 | 620 | 100 | 0.062 | 1.93812 | 1.93812 | Material Properties - Steen - Betonblok vuilwerk, ThermalConductivity: 0.75; Steen - Betonblok vuilwerk, SpecificHeatCapacity: 840 J/kg/K; Steen - Betonblok vuilwerk, MassDensity: 1600 kg/m3; Steen - Betonblok vuilwerk, Embodied Energy: 0.83 (MJ/kg); Steen - Betonblok vuilwerk, Embodied Carbon: 0.1 (kgCO₂/kg); Steen - Betonblok vuilwerk, Name: Steen - Betonblok vuilwerk; Steen - Betonblok vuilwerk, Participates in Collision Detection: yes
Isolatie - Kunststof hard | Fundering | Isolatie - Kunststof hard | 53.5304 | 870 | 140 | 0.1218 | 0.535304 | 0.535304 | Material Properties - Isolatie - Kunststof hard, ThermalConductivity: 0.029; Isolatie - Kunststof hard, SpecificHeatCapacity: 1470 J/kg/K; Isolatie - Kunststof hard, MassDensity: 100 kg/m3; Isolatie - Kunststof hard, Embodied Energy: 101.5 (MJ/kg); Isolatie - Kunststof hard, Embodied Carbon: 3.48 (kgCO₂/kg); Isolatie - Kunststof hard, Name: Isolatie - Kunststof hard; Isolatie - Kunststof hard, Participates in Collision Detection: yes
Steen - Baksteen AFW | Fundering | Steen - Baksteen AFW | 181.638 | 250 | 100 | 0.025 | 0.113524 | 0.113524 | Material Properties - Steen - Baksteen AFW, ThermalConductivity: 0.9; Steen - Baksteen AFW, SpecificHeatCapacity: 840 J/kg/K; Steen - Baksteen AFW, MassDensity: 1600 kg/m3; Steen - Baksteen AFW, Embodied Energy: 3 (MJ/kg); Steen - Baksteen AFW, Embodied Carbon: 0.23 (kgCO₂/kg); Steen - Baksteen AFW, Name: Steen - Baksteen AFW; Steen - Baksteen AFW, Participates in Collision Detection: yes
Steen - Betonblok vuilwerk | Fundering | Steen - Betonblok vuilwerk | 450.462 | 620 | 100 | 0.062 | 0.281539 | 0.281539 | Material Properties - Steen - Betonblok vuilwerk, ThermalConductivity: 0.75; Steen - Betonblok vuilwerk, SpecificHeatCapacity: 840 J/kg/K; Steen - Betonblok vuilwerk, MassDensity: 1600 kg/m3; Steen - Betonblok vuilwerk, Embodied Energy: 0.83 (MJ/kg); Steen - Betonblok vuilwerk, Embodied Carbon: 0.1 (kgCO₂/kg); Steen - Betonblok vuilwerk, Name: Steen - Betonblok vuilwerk; Steen - Betonblok vuilwerk, Participates in Collision Detection: yes
Isolatie - Kunststof hard | Fundering | Isolatie - Kunststof hard | 59.0731 | 870 | 140 | 0.1218 | 0.590731 | 0.590731 | Material Properties - Isolatie - Kunststof hard, ThermalConductivity: 0.029; Isolatie - Kunststof hard, SpecificHeatCapacity: 1470 J/kg/K; Isolatie - Kunststof hard, MassDensity: 100 kg/m3; Isolatie - Kunststof hard, Embodied Energy: 101.5 (MJ/kg); Isolatie - Kunststof hard, Embodied Carbon: 3.48 (kgCO₂/kg); Isolatie - Kunststof hard, Name: Isolatie - Kunststof hard; Isolatie - Kunststof hard, Participates in Collision Detection: yes
Steen - Baksteen AFW | Fundering | Steen - Baksteen AFW | 201.44 | 250 | 100 | 0.025 | 0.1259 | 0.1259 | Material Properties - Steen - Baksteen AFW, ThermalConductivity: 0.9; Steen - Baksteen AFW, SpecificHeatCapacity: 840 J/kg/K; Steen - Baksteen AFW, MassDensity: 1600 kg/m3; Steen - Baksteen AFW, Embodied Energy: 3 (MJ/kg); Steen - Baksteen AFW, Embodied Carbon: 0.23 (kgCO₂/kg); Steen - Baksteen AFW, Name: Steen - Baksteen AFW; Steen - Baksteen AFW, Participates in Collision Detection: yes
Steen - Betonblok vuilwerk | Fundering | Steen - Betonblok vuilwerk | 499.572 | 620 | 100 | 0.062 | 0.312233 | 0.312233 | Material Properties - Steen - Betonblok vuilwerk, ThermalConductivity: 0.75; Steen - Betonblok vuilwerk, SpecificHeatCapacity: 840 J/kg/K; Steen - Betonblok vuilwerk, MassDensity: 1600 kg/m3; Steen - Betonblok vuilwerk, Embodied Energy: 0.83 (MJ/kg); Steen - Betonblok vuilwerk, Embodied Carbon: 0.1 (kgCO₂/kg); Steen - Betonblok vuilwerk, Name: Steen - Betonblok vuilwerk; Steen - Betonblok vuilwerk, Participates in Collision Detection: yes
2 x Gipsplaat | Begane grond | Gipsplaat | 11.2919 | 3400 | 12.5 | 0.0425 | 0.0141148 | 0.0448376 | Component Quantities - Projected Component Area (Net): 1.12919 m2; Projected Component Area (Gross): 3.587 m2; Component Thickness: 12.5 mm; Material Properties - Gipsplaat, ThermalConductivity: 0.23; Gipsplaat, SpecificHeatCapacity: 840 J/kg/K; Gipsplaat, MassDensity: 800 kg/m3; Gipsplaat, Embodied Energy: 6.75 (MJ/kg); Gipsplaat, Embodied Carbon: 0.38 (kgCO₂/kg); Gipsplaat, Name: Gipsplaat; Gipsplaat, Participates in Collision Detection: yes
2 x Gipsplaat | Begane grond | Gipsplaat | 12.1419 | 3400 | 12.5 | 0.0425 | 0.0151773 | 0.0459001 | Component Quantities - Projected Component Area (Net): 1.21419 m2; Projected Component Area (Gross): 3.672 m2; Component Thickness: 12.5 mm; Material Properties - Gipsplaat, ThermalConductivity: 0.23; Gipsplaat, SpecificHeatCapacity: 840 J/kg/K; Gipsplaat, MassDensity: 800 kg/m3; Gipsplaat, Embodied Energy: 6.75 (MJ/kg); Gipsplaat, Embodied Carbon: 0.38 (kgCO₂/kg); Gipsplaat, Name: Gipsplaat; Gipsplaat, Participates in Collision Detection: yes
Isolatie - Steenwol LSW | Begane grond | Isolatie - Steenwol LSW | 3.57276 | 3400 | 50 | 0.17 | 0.0649593 | 0.18785 | Component Quantities - Projected Component Area (Net): 1.29919 m2; Projected Component Area (Gross): 3.757 m2; Component Thickness: 50 mm; Material Properties - Isolatie - Steenwol LSW, ThermalConductivity: 0.039; Isolatie - Steenwol LSW, SpecificHeatCapacity: 840 J/kg/K; Isolatie - Steenwol LSW, MassDensity: 55 kg/m3; Isolatie - Steenwol LSW, Embodied Energy: 16.8 (MJ/kg); Isolatie - Steenwol LSW, Embodied Carbon: 1.05 (kgCO₂/kg); Isolatie - Steenwol LSW, Name: Isolatie - Steenwol LSW; Isolatie - Steenwol LSW, Participates in Collision Detection: yes
Gipsplaat | Begane grond | Gipsplaat | 231.42 | 3470 | 12.5 | 0.043375 | 0.289275 | 0.349472 | Component Quantities - Projected Component Area (Net): 23.142 m2; Projected Component Area (Gross): 27.9577 m2; Component Thickness: 12.5 mm; Material Properties - Gipsplaat, ThermalConductivity: 0.23; Gipsplaat, SpecificHeatCapacity: 840 J/kg/K; Gipsplaat, MassDensity: 800 kg/m3; Gipsplaat, Embodied Energy: 6.75 (MJ/kg); Gipsplaat, Embodied Carbon: 0.38 (kgCO₂/kg); Gipsplaat, Name: Gipsplaat; Gipsplaat, Participates in Collision Detection: yes
Gipsplaat | Begane grond | Gipsplaat | 232.288 | 3470 | 12.5 | 0.043375 | 0.29036 | 0.350556 | Component Quantities - Projected Component Area (Net): 23.2288 m2; Projected Component Area (Gross): 28.0445 m2; Component Thickness: 12.5 mm; Material Properties - Gipsplaat, ThermalConductivity: 0.23; Gipsplaat, SpecificHeatCapacity: 840 J/kg/K; Gipsplaat, MassDensity: 800 kg/m3; Gipsplaat, Embodied Energy: 6.75 (MJ/kg); Gipsplaat, Embodied Carbon: 0.38 (kgCO₂/kg); Gipsplaat, Name: Gipsplaat; Gipsplaat, Participates in Collision Detection: yes
Isolatie - Steenwol LSW | Begane grond | Isolatie - Steenwol LSW | 64.3563 | 3470 | 50 | 0.1735 | 1.17011 | 1.4109 | Component Quantities - Projected Component Area (Net): 23.4023 m2; Projected Component Area (Gross): 28.218 m2; Component Thickness: 50 mm; Material Properties - Isolatie - Steenwol LSW, ThermalConductivity: 0.039; Isolatie - Steenwol LSW, SpecificHeatCapacity: 840 J/kg/K; Isolatie - Steenwol LSW, MassDensity: 55 kg/m3; Isolatie - Steenwol LSW, Embodied Energy: 16.8 (MJ/kg); Isolatie - Steenwol LSW, Embodied Carbon: 1.05 (kgCO₂/kg); Isolatie - Steenwol LSW, Name: Isolatie - Steenwol LSW; Isolatie - Steenwol LSW, Participates in Collision Detection: yes
2 x Gipsplaat | Begane grond | Gipsplaat | 234.023 | 3470 | 12.5 | 0.043375 | 0.292528 | 0.352725 | Component Quantities - Projected Component Area (Net): 23.4023 m2; Projected Component Area (Gross): 28.218 m2; Component Thickness: 12.5 mm; Material Properties - Gipsplaat, ThermalConductivity: 0.23; Gipsplaat, SpecificHeatCapacity: 840 J/kg/K; Gipsplaat, MassDensity: 800 kg/m3; Gipsplaat, Embodied Energy: 6.75 (MJ/kg); Gipsplaat, Embodied Carbon: 0.38 (kgCO₂/kg); Gipsplaat, Name: Gipsplaat; Gipsplaat, Participates in Collision Detection: yes
2 x Gipsplaat | Begane grond | Gipsplaat | 189.62 | 3470 | 12.5 | 0.043375 | 0.237025 | 0.32965 | Component Quantities - Projected Component Area (Net): 18.962 m2; Projected Component Area (Gross): 26.372 m2; Component Thickness: 12.5 mm; Material Properties - Gipsplaat, ThermalConductivity: 0.23; Gipsplaat, SpecificHeatCapacity: 840 J/kg/K; Gipsplaat, MassDensity: 800 kg/m3; Gipsplaat, Embodied Energy: 6.75 (MJ/kg); Gipsplaat, Embodied Carbon: 0.38 (kgCO₂/kg); Gipsplaat, Name: Gipsplaat; Gipsplaat, Participates in Collision Detection: yes
2 x Gipsplaat | Begane grond | Gipsplaat | 190.053 | 3470 | 12.5 | 0.043375 | 0.237567 | 0.330192 | Component Quantities - Projected Component Area (Net): 19.0053 m2; Projected Component Area (Gross): 26.4153 m2; Component Thickness: 12.5 mm; Material Properties - Gipsplaat, ThermalConductivity: 0.23; Gipsplaat, SpecificHeatCapacity: 840 J/kg/K; Gipsplaat, MassDensity: 800 kg/m3; Gipsplaat, Embodied Energy: 6.75 (MJ/kg); Gipsplaat, Embodied Carbon: 0.38 (kgCO₂/kg); Gipsplaat, Name: Gipsplaat; Gipsplaat, Participates in Collision Detection: yes
Isolatie - Steenwol LSW | Begane grond | Isolatie - Steenwol LSW | 52.384 | 3470 | 50 | 0.1735 | 0.952436 | 1.32294 | Component Quantities - Projected Component Area (Net): 19.0487 m2; Projected Component Area (Gross): 26.4587 m2; Component Thickness: 50 mm; Material Properties - Isolatie - Steenwol LSW, ThermalConductivity: 0.039; Isolatie - Steenwol LSW, SpecificHeatCapacity: 840 J/kg/K; Isolatie - Steenwol LSW, MassDensity: 55 kg/m3; Isolatie - Steenwol LSW, Embodied Energy: 16.8 (MJ/kg); Isolatie - Steenwol LSW, Embodied Carbon: 1.05 (kgCO₂/kg); Isolatie - Steenwol LSW, Name: Isolatie - Steenwol LSW; Isolatie - Steenwol LSW, Participates in Collision Detection: yes
3 x Gipsplaat | Begane grond | Gipsplaat | 35.7 | 3400 | 12.5 | 0.0425 | 0.044625 | 0.044625 | Component Quantities - Projected Component Area (Net): 3.57 m2; Projected Component Area (Gross): 3.57 m2; Component Thickness: 12.5 mm; Material Properties - Gipsplaat, ThermalConductivity: 0.23; Gipsplaat, SpecificHeatCapacity: 840 J/kg/K; Gipsplaat, MassDensity: 800 kg/m3; Gipsplaat, Embodied Energy: 6.75 (MJ/kg); Gipsplaat, Embodied Carbon: 0.38 (kgCO₂/kg); Gipsplaat, Name: Gipsplaat; Gipsplaat, Participates in Collision Detection: yes
3 x Gipsplaat | Begane grond | Gipsplaat | 36.55 | 3400 | 12.5 | 0.0425 | 0.0456875 | 0.0456875 | Component Quantities - Projected Component Area (Net): 3.655 m2; Projected Component Area (Gross): 3.655 m2; Component Thickness: 12.5 mm; Material Properties - Gipsplaat, ThermalConductivity: 0.23; Gipsplaat, SpecificHeatCapacity: 840 J/kg/K; Gipsplaat, MassDensity: 800 kg/m3; Gipsplaat, Embodied Energy: 6.75 (MJ/kg); Gipsplaat, Embodied Carbon: 0.38 (kgCO₂/kg); Gipsplaat, Name: Gipsplaat; Gipsplaat, Participates in Collision Detection: yes
3 x Isolatie - Steenwol LSW | Begane grond | Isolatie - Steenwol LSW | 10.285 | 3400 | 50 | 0.17 | 0.187 | 0.187 | Component Quantities - Projected Component Area (Net): 3.74 m2; Projected Component Area (Gross): 3.74 m2; Component Thickness: 50 mm; Material Properties - Isolatie - Steenwol LSW, ThermalConductivity: 0.039; Isolatie - Steenwol LSW, SpecificHeatCapacity: 840 J/kg/K; Isolatie - Steenwol LSW, MassDensity: 55 kg/m3; Isolatie - Steenwol LSW, Embodied Energy: 16.8 (MJ/kg); Isolatie - Steenwol LSW, Embodied Carbon: 1.05 (kgCO₂/kg); Isolatie - Steenwol LSW, Name: Isolatie - Steenwol LSW; Isolatie - Steenwol LSW, Participates in Collision Detection: yes
4 x Gipsplaat | Begane grond | Gipsplaat | 11.1218 | 3400 | 12.5 | 0.0425 | 0.0139023 | 0.044625 | Component Quantities - Projected Component Area (Net): 1.11218 m2; Projected Component Area (Gross): 3.57 m2; Component Thickness: 12.5 mm; Material Properties - Gipsplaat, ThermalConductivity: 0.23; Gipsplaat, SpecificHeatCapacity: 840 J/kg/K; Gipsplaat, MassDensity: 800 kg/m3; Gipsplaat, Embodied Energy: 6.75 (MJ/kg); Gipsplaat, Embodied Carbon: 0.38 (kgCO₂/kg); Gipsplaat, Name: Gipsplaat; Gipsplaat, Participates in Collision Detection: yes
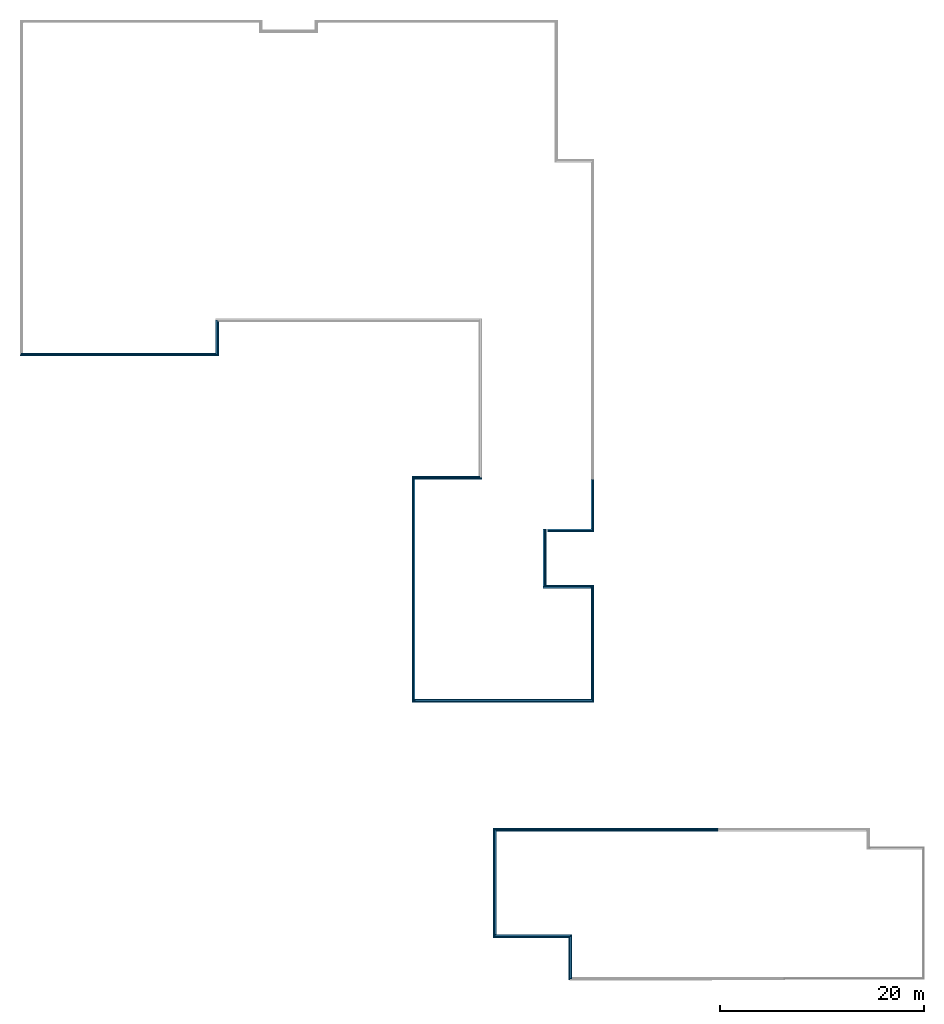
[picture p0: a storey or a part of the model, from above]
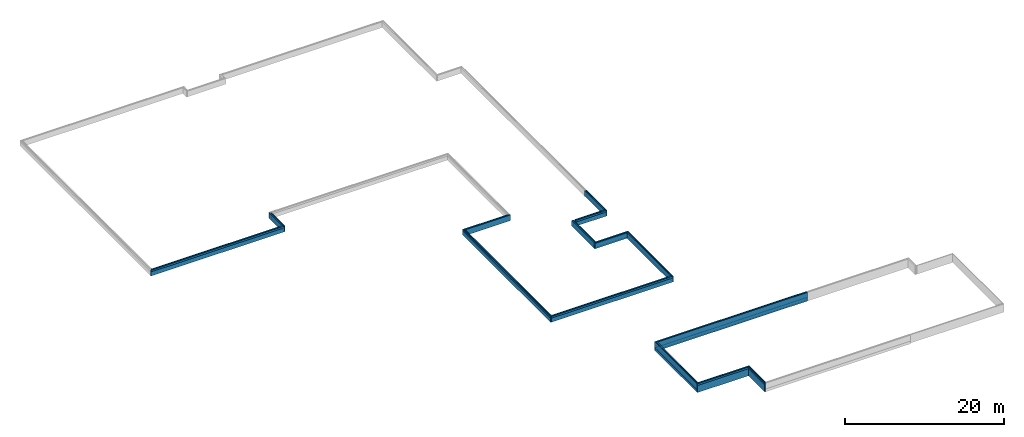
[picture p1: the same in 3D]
Properties of the parts of a building model (IFC2X3), part 4 of 19

# IfcBuildingElementPart (2070)
Name | In | Material | Mass (kg) | Rectangular Component Height (mm) | Rectangular Component Width (mm) | Component Cross Section Area (m2) | Component Volume (Net) (m3) | Component Volume (Gross) (m3)
4 x Gipsplaat | Begane grond | Gipsplaat | 11.9718 | 3400 | 12.5 | 0.0425 | 0.0149648 | 0.0456875 | Component Quantities - Projected Component Area (Net): 1.19718 m2; Projected Component Area (Gross): 3.655 m2; Component Thickness: 12.5 mm; Material Properties - Gipsplaat, ThermalConductivity: 0.23; Gipsplaat, SpecificHeatCapacity: 840 J/kg/K; Gipsplaat, MassDensity: 800 kg/m3; Gipsplaat, Embodied Energy: 6.75 (MJ/kg); Gipsplaat, Embodied Carbon: 0.38 (kgCO₂/kg); Gipsplaat, Name: Gipsplaat; Gipsplaat, Participates in Collision Detection: yes
2 x Isolatie - Steenwol LSW | Begane grond | Isolatie - Steenwol LSW | 3.526 | 3400 | 50 | 0.17 | 0.0641091 | 0.187 | Component Quantities - Projected Component Area (Net): 1.28218 m2; Projected Component Area (Gross): 3.74 m2; Component Thickness: 50 mm; Material Properties - Isolatie - Steenwol LSW, ThermalConductivity: 0.039; Isolatie - Steenwol LSW, SpecificHeatCapacity: 840 J/kg/K; Isolatie - Steenwol LSW, MassDensity: 55 kg/m3; Isolatie - Steenwol LSW, Embodied Energy: 16.8 (MJ/kg); Isolatie - Steenwol LSW, Embodied Carbon: 1.05 (kgCO₂/kg); Isolatie - Steenwol LSW, Name: Isolatie - Steenwol LSW; Isolatie - Steenwol LSW, Participates in Collision Detection: yes
Membraan - waterdicht | Begane grond | Membraan - waterdicht | 65.5108 | 1385 | 5 | 0.006925 | 0.0623913 | 0.0729196 | Component Quantities - Projected Component Area (Net): 12.4789 m2; Projected Component Area (Gross): 14.5847 m2; Component Thickness: 5 mm; Material Properties - Membraan - waterdicht, ThermalConductivity: 0.2; Membraan - waterdicht, SpecificHeatCapacity: 1840 J/kg/K; Membraan - waterdicht, MassDensity: 1050 kg/m3; Membraan - waterdicht, Embodied Energy: 51 (MJ/kg); Membraan - waterdicht, Embodied Carbon: 0.38 (kgCO₂/kg); Membraan - waterdicht, Name: Membraan - waterdicht; Membraan - waterdicht, Participates in Collision Detection: yes
Isolatie - Steenwol hard | Begane grond | Isolatie - Steenwol hard | 437.163 | 1385 | 196 | 0.27146 | 2.73227 | 2.8586 | Component Quantities - Projected Component Area (Net): 14.5847 m2; Projected Component Area (Gross): 14.5847 m2; Component Thickness: 196 mm; Material Properties - Isolatie - Steenwol hard, ThermalConductivity: 0.043; Isolatie - Steenwol hard, SpecificHeatCapacity: 840 J/kg/K; Isolatie - Steenwol hard, MassDensity: 160 kg/m3; Isolatie - Steenwol hard, Embodied Energy: 16.8 (MJ/kg); Isolatie - Steenwol hard, Embodied Carbon: 1.05 (kgCO₂/kg); Isolatie - Steenwol hard, Name: Isolatie - Steenwol hard; Isolatie - Steenwol hard, Participates in Collision Detection: yes
Metaal - Staal AFW | Begane grond | Metaal - Staal AFW | 463.768 | 1385 | 4 | 0.00554 | 0.0583356 | 0.0583356 | Component Quantities - Projected Component Area (Net): 14.5847 m2; Projected Component Area (Gross): 14.5847 m2; Component Thickness: 4 mm; Material Properties - Metaal - Staal AFW, ThermalConductivity: 52; Metaal - Staal AFW, SpecificHeatCapacity: 530 J/kg/K; Metaal - Staal AFW, MassDensity: 7950 kg/m3; Metaal - Staal AFW, Embodied Energy: 25 (MJ/kg); Metaal - Staal AFW, Embodied Carbon: 1.91 (kgCO₂/kg); Metaal - Staal AFW, Name: Metaal - Staal AFW; Metaal - Staal AFW, Participates in Collision Detection: yes
Cement | Begane grond | Cement | 71015.9 |  |  |  | 37.3768 | 37.1198 | Component Quantities - Projected Component Area (Net): 533.954 m2; Projected Component Area (Gross): 530.283 m2; Component Thickness: 70 mm; Material Properties - Cement, ThermalConductivity: 0.93; Cement, SpecificHeatCapacity: 840 J/kg/K; Cement, MassDensity: 1900 kg/m3; Cement, Embodied Energy: 0.97 (MJ/kg); Cement, Embodied Carbon: 0.146 (kgCO₂/kg); Cement, Name: Cement; Cement, Participates in Collision Detection: yes
Beton gewapend C vloer | Begane grond | Beton gewapend C vloer | 66687.6 |  |  |  | 27.7865 | 27.8345 | Component Quantities - Projected Component Area (Net): 555.73 m2; Projected Component Area (Gross): 556.69 m2; Component Thickness: 50 mm; Material Properties - Beton gewapend C vloer, ThermalConductivity: 2.5; Beton gewapend C vloer, SpecificHeatCapacity: 1000 J/kg/K; Beton gewapend C vloer, MassDensity: 2400 kg/m3; Beton gewapend C vloer, Embodied Energy: 2.33 (MJ/kg); Beton gewapend C vloer, Embodied Carbon: 0.242 (kgCO₂/kg); Beton gewapend C vloer, Name: Beton gewapend C vloer; Beton gewapend C vloer, Participates in Collision Detection: yes
Beton gewapend prefab vloer | Begane grond | Beton gewapend prefab vloer | 266750 |  |  |  | 111.146 | 111.338 | Component Quantities - Projected Component Area (Net): 555.73 m2; Projected Component Area (Gross): 556.69 m2; Component Thickness: 200 mm; Material Properties - Beton gewapend prefab vloer, ThermalConductivity: 2.5; Beton gewapend prefab vloer, SpecificHeatCapacity: 1000 J/kg/K; Beton gewapend prefab vloer, MassDensity: 2400 kg/m3; Beton gewapend prefab vloer, Embodied Energy: 2.33 (MJ/kg); Beton gewapend prefab vloer, Embodied Carbon: 0.242 (kgCO₂/kg); Beton gewapend prefab vloer, Name: Beton gewapend prefab vloer; Beton gewapend prefab vloer, Participates in Collision Detection: yes
ALG - ISOLATIE | Begane grond | ALG - ISOLATIE | 3301.04 |  |  |  | 73.3564 | 73.4831 | Component Quantities - Projected Component Area (Net): 555.73 m2; Projected Component Area (Gross): 556.69 m2; Component Thickness: 132 mm; Material Properties - ALG - ISOLATIE, ThermalConductivity: 0.035; ALG - ISOLATIE, SpecificHeatCapacity: 840 J/kg/K; ALG - ISOLATIE, MassDensity: 45 kg/m3; ALG - ISOLATIE, Embodied Energy: 16.8 (MJ/kg); ALG - ISOLATIE, Embodied Carbon: 1.05 (kgCO₂/kg); ALG - ISOLATIE, Name: ALG - ISOLATIE; ALG - ISOLATIE, Participates in Collision Detection: yes
Gipsplaat | Begane grond | Gipsplaat | 252.162 | 3400 | 12.5 | 0.0425 | 0.315203 | 0.315203 | Component Quantities - Projected Component Area (Net): 25.2162 m2; Projected Component Area (Gross): 25.2162 m2; Component Thickness: 12.5 mm; Material Properties - Gipsplaat, ThermalConductivity: 0.23; Gipsplaat, SpecificHeatCapacity: 840 J/kg/K; Gipsplaat, MassDensity: 800 kg/m3; Gipsplaat, Embodied Energy: 6.75 (MJ/kg); Gipsplaat, Embodied Carbon: 0.38 (kgCO₂/kg); Gipsplaat, Name: Gipsplaat; Gipsplaat, Participates in Collision Detection: yes
Gipsplaat | Begane grond | Gipsplaat | 253.012 | 3400 | 12.5 | 0.0425 | 0.316265 | 0.316265 | Component Quantities - Projected Component Area (Net): 25.3012 m2; Projected Component Area (Gross): 25.3012 m2; Component Thickness: 12.5 mm; Material Properties - Gipsplaat, ThermalConductivity: 0.23; Gipsplaat, SpecificHeatCapacity: 840 J/kg/K; Gipsplaat, MassDensity: 800 kg/m3; Gipsplaat, Embodied Energy: 6.75 (MJ/kg); Gipsplaat, Embodied Carbon: 0.38 (kgCO₂/kg); Gipsplaat, Name: Gipsplaat; Gipsplaat, Participates in Collision Detection: yes
2 x Isolatie - Steenwol LSW | Begane grond | Isolatie - Steenwol LSW | 71.0977 | 3400 | 50 | 0.17 | 1.29269 | 1.29269 | Component Quantities - Projected Component Area (Net): 25.8537 m2; Projected Component Area (Gross): 25.8537 m2; Component Thickness: 50 mm; Material Properties - Isolatie - Steenwol LSW, ThermalConductivity: 0.039; Isolatie - Steenwol LSW, SpecificHeatCapacity: 840 J/kg/K; Isolatie - Steenwol LSW, MassDensity: 55 kg/m3; Isolatie - Steenwol LSW, Embodied Energy: 16.8 (MJ/kg); Isolatie - Steenwol LSW, Embodied Carbon: 1.05 (kgCO₂/kg); Isolatie - Steenwol LSW, Name: Isolatie - Steenwol LSW; Isolatie - Steenwol LSW, Participates in Collision Detection: yes
Gipsplaat | Begane grond | Gipsplaat | 253.437 | 3400 | 12.5 | 0.0425 | 0.316797 | 0.316797 | Component Quantities - Projected Component Area (Net): 25.3437 m2; Projected Component Area (Gross): 25.3437 m2; Component Thickness: 12.5 mm; Material Properties - Gipsplaat, ThermalConductivity: 0.23; Gipsplaat, SpecificHeatCapacity: 840 J/kg/K; Gipsplaat, MassDensity: 800 kg/m3; Gipsplaat, Embodied Energy: 6.75 (MJ/kg); Gipsplaat, Embodied Carbon: 0.38 (kgCO₂/kg); Gipsplaat, Name: Gipsplaat; Gipsplaat, Participates in Collision Detection: yes
Gipsplaat | Begane grond | Gipsplaat | 252.587 | 3400 | 12.5 | 0.0425 | 0.315734 | 0.315734 | Component Quantities - Projected Component Area (Net): 25.2587 m2; Projected Component Area (Gross): 25.2587 m2; Component Thickness: 12.5 mm; Material Properties - Gipsplaat, ThermalConductivity: 0.23; Gipsplaat, SpecificHeatCapacity: 840 J/kg/K; Gipsplaat, MassDensity: 800 kg/m3; Gipsplaat, Embodied Energy: 6.75 (MJ/kg); Gipsplaat, Embodied Carbon: 0.38 (kgCO₂/kg); Gipsplaat, Name: Gipsplaat; Gipsplaat, Participates in Collision Detection: yes
Gipsplaat | Begane grond | Gipsplaat | 131.566 | 3470 | 12.5 | 0.043375 | 0.164458 | 0.510463 | Component Quantities - Projected Component Area (Net): 13.1566 m2; Projected Component Area (Gross): 40.837 m2; Component Thickness: 12.5 mm; Material Properties - Gipsplaat, ThermalConductivity: 0.23; Gipsplaat, SpecificHeatCapacity: 840 J/kg/K; Gipsplaat, MassDensity: 800 kg/m3; Gipsplaat, Embodied Energy: 6.75 (MJ/kg); Gipsplaat, Embodied Carbon: 0.38 (kgCO₂/kg); Gipsplaat, Name: Gipsplaat; Gipsplaat, Participates in Collision Detection: yes
Gipsplaat | Begane grond | Gipsplaat | 132.405 | 3470 | 12.5 | 0.043375 | 0.165506 | 0.511511 | Component Quantities - Projected Component Area (Net): 13.2405 m2; Projected Component Area (Gross): 40.9209 m2; Component Thickness: 12.5 mm; Material Properties - Gipsplaat, ThermalConductivity: 0.23; Gipsplaat, SpecificHeatCapacity: 840 J/kg/K; Gipsplaat, MassDensity: 800 kg/m3; Gipsplaat, Embodied Energy: 6.75 (MJ/kg); Gipsplaat, Embodied Carbon: 0.38 (kgCO₂/kg); Gipsplaat, Name: Gipsplaat; Gipsplaat, Participates in Collision Detection: yes
Isolatie - Steenwol LSW | Begane grond | Isolatie - Steenwol LSW | 36.5278 | 3470 | 50 | 0.1735 | 0.664143 | 2.04816 | Component Quantities - Projected Component Area (Net): 13.2829 m2; Projected Component Area (Gross): 40.9633 m2; Component Thickness: 50 mm; Material Properties - Isolatie - Steenwol LSW, ThermalConductivity: 0.039; Isolatie - Steenwol LSW, SpecificHeatCapacity: 840 J/kg/K; Isolatie - Steenwol LSW, MassDensity: 55 kg/m3; Isolatie - Steenwol LSW, Embodied Energy: 16.8 (MJ/kg); Isolatie - Steenwol LSW, Embodied Carbon: 1.05 (kgCO₂/kg); Isolatie - Steenwol LSW, Name: Isolatie - Steenwol LSW; Isolatie - Steenwol LSW, Participates in Collision Detection: yes
Gipsplaat | Begane grond | Gipsplaat | 131.99 | 3470 | 12.5 | 0.043375 | 0.164987 | 0.510992 | Component Quantities - Projected Component Area (Net): 13.199 m2; Projected Component Area (Gross): 40.8794 m2; Component Thickness: 12.5 mm; Material Properties - Gipsplaat, ThermalConductivity: 0.23; Gipsplaat, SpecificHeatCapacity: 840 J/kg/K; Gipsplaat, MassDensity: 800 kg/m3; Gipsplaat, Embodied Energy: 6.75 (MJ/kg); Gipsplaat, Embodied Carbon: 0.38 (kgCO₂/kg); Gipsplaat, Name: Gipsplaat; Gipsplaat, Participates in Collision Detection: yes
Gipsplaat | Begane grond | Gipsplaat | 131.151 | 3470 | 12.5 | 0.043375 | 0.163939 | 0.509944 | Component Quantities - Projected Component Area (Net): 13.1151 m2; Projected Component Area (Gross): 40.7955 m2; Component Thickness: 12.5 mm; Material Properties - Gipsplaat, ThermalConductivity: 0.23; Gipsplaat, SpecificHeatCapacity: 840 J/kg/K; Gipsplaat, MassDensity: 800 kg/m3; Gipsplaat, Embodied Energy: 6.75 (MJ/kg); Gipsplaat, Embodied Carbon: 0.38 (kgCO₂/kg); Gipsplaat, Name: Gipsplaat; Gipsplaat, Participates in Collision Detection: yes
4 x Gipsplaat | Begane grond | Gipsplaat | 138.262 | 3400 | 12.5 | 0.0425 | 0.172828 | 0.172828 | Component Quantities - Projected Component Area (Net): 13.8262 m2; Projected Component Area (Gross): 13.8262 m2; Component Thickness: 12.5 mm; Material Properties - Gipsplaat, ThermalConductivity: 0.23; Gipsplaat, SpecificHeatCapacity: 840 J/kg/K; Gipsplaat, MassDensity: 800 kg/m3; Gipsplaat, Embodied Energy: 6.75 (MJ/kg); Gipsplaat, Embodied Carbon: 0.38 (kgCO₂/kg); Gipsplaat, Name: Gipsplaat; Gipsplaat, Participates in Collision Detection: yes
4 x Gipsplaat | Begane grond | Gipsplaat | 139.962 | 3400 | 12.5 | 0.0425 | 0.174953 | 0.174953 | Component Quantities - Projected Component Area (Net): 13.9962 m2; Projected Component Area (Gross): 13.9962 m2; Component Thickness: 12.5 mm; Material Properties - Gipsplaat, ThermalConductivity: 0.23; Gipsplaat, SpecificHeatCapacity: 840 J/kg/K; Gipsplaat, MassDensity: 800 kg/m3; Gipsplaat, Embodied Energy: 6.75 (MJ/kg); Gipsplaat, Embodied Carbon: 0.38 (kgCO₂/kg); Gipsplaat, Name: Gipsplaat; Gipsplaat, Participates in Collision Detection: yes
2 x Isolatie - Steenwol LSW | Begane grond | Isolatie - Steenwol LSW | 39.5415 | 3400 | 50 | 0.17 | 0.718936 | 0.718936 | Component Quantities - Projected Component Area (Net): 14.3787 m2; Projected Component Area (Gross): 14.3787 m2; Component Thickness: 50 mm; Material Properties - Isolatie - Steenwol LSW, ThermalConductivity: 0.039; Isolatie - Steenwol LSW, SpecificHeatCapacity: 840 J/kg/K; Isolatie - Steenwol LSW, MassDensity: 55 kg/m3; Isolatie - Steenwol LSW, Embodied Energy: 16.8 (MJ/kg); Isolatie - Steenwol LSW, Embodied Carbon: 1.05 (kgCO₂/kg); Isolatie - Steenwol LSW, Name: Isolatie - Steenwol LSW; Isolatie - Steenwol LSW, Participates in Collision Detection: yes
6 x Gipsplaat | Begane grond | Gipsplaat | 172.2 | 3470 | 12.5 | 0.043375 | 0.215251 | 0.307876 | Component Quantities - Projected Component Area (Net): 17.22 m2; Projected Component Area (Gross): 24.63 m2; Component Thickness: 12.5 mm; Material Properties - Gipsplaat, ThermalConductivity: 0.23; Gipsplaat, SpecificHeatCapacity: 840 J/kg/K; Gipsplaat, MassDensity: 800 kg/m3; Gipsplaat, Embodied Energy: 6.75 (MJ/kg); Gipsplaat, Embodied Carbon: 0.38 (kgCO₂/kg); Gipsplaat, Name: Gipsplaat; Gipsplaat, Participates in Collision Detection: yes
6 x Gipsplaat | Begane grond | Gipsplaat | 172.624 | 3470 | 12.5 | 0.043375 | 0.21578 | 0.308405 | Component Quantities - Projected Component Area (Net): 17.2624 m2; Projected Component Area (Gross): 24.6724 m2; Component Thickness: 12.5 mm; Material Properties - Gipsplaat, ThermalConductivity: 0.23; Gipsplaat, SpecificHeatCapacity: 840 J/kg/K; Gipsplaat, MassDensity: 800 kg/m3; Gipsplaat, Embodied Energy: 6.75 (MJ/kg); Gipsplaat, Embodied Carbon: 0.38 (kgCO₂/kg); Gipsplaat, Name: Gipsplaat; Gipsplaat, Participates in Collision Detection: yes
3 x Isolatie - Steenwol LSW | Begane grond | Isolatie - Steenwol LSW | 47.5882 | 3470 | 50 | 0.1735 | 0.86524 | 1.23574 | Component Quantities - Projected Component Area (Net): 17.3048 m2; Projected Component Area (Gross): 24.7148 m2; Component Thickness: 50 mm; Material Properties - Isolatie - Steenwol LSW, ThermalConductivity: 0.039; Isolatie - Steenwol LSW, SpecificHeatCapacity: 840 J/kg/K; Isolatie - Steenwol LSW, MassDensity: 55 kg/m3; Isolatie - Steenwol LSW, Embodied Energy: 16.8 (MJ/kg); Isolatie - Steenwol LSW, Embodied Carbon: 1.05 (kgCO₂/kg); Isolatie - Steenwol LSW, Name: Isolatie - Steenwol LSW; Isolatie - Steenwol LSW, Participates in Collision Detection: yes
Gipsplaat | Begane grond | Gipsplaat | 139.472 | 3400 | 12.5 | 0.0425 | 0.17434 | 0.205062 | Component Quantities - Projected Component Area (Net): 13.9472 m2; Projected Component Area (Gross): 16.405 m2; Component Thickness: 12.5 mm; Material Properties - Gipsplaat, ThermalConductivity: 0.23; Gipsplaat, SpecificHeatCapacity: 840 J/kg/K; Gipsplaat, MassDensity: 800 kg/m3; Gipsplaat, Embodied Energy: 6.75 (MJ/kg); Gipsplaat, Embodied Carbon: 0.38 (kgCO₂/kg); Gipsplaat, Name: Gipsplaat; Gipsplaat, Participates in Collision Detection: yes
Gipsplaat | Begane grond | Gipsplaat | 140.322 | 3400 | 12.5 | 0.0425 | 0.175402 | 0.206125 | Component Quantities - Projected Component Area (Net): 14.0322 m2; Projected Component Area (Gross): 16.49 m2; Component Thickness: 12.5 mm; Material Properties - Gipsplaat, ThermalConductivity: 0.23; Gipsplaat, SpecificHeatCapacity: 840 J/kg/K; Gipsplaat, MassDensity: 800 kg/m3; Gipsplaat, Embodied Energy: 6.75 (MJ/kg); Gipsplaat, Embodied Carbon: 0.38 (kgCO₂/kg); Gipsplaat, Name: Gipsplaat; Gipsplaat, Participates in Collision Detection: yes
Isolatie - Steenwol LSW | Begane grond | Isolatie - Steenwol LSW | 39.056 | 3400 | 50 | 0.17 | 0.710109 | 0.833 | Component Quantities - Projected Component Area (Net): 14.2022 m2; Projected Component Area (Gross): 16.66 m2; Component Thickness: 50 mm; Material Properties - Isolatie - Steenwol LSW, ThermalConductivity: 0.039; Isolatie - Steenwol LSW, SpecificHeatCapacity: 840 J/kg/K; Isolatie - Steenwol LSW, MassDensity: 55 kg/m3; Isolatie - Steenwol LSW, Embodied Energy: 16.8 (MJ/kg); Isolatie - Steenwol LSW, Embodied Carbon: 1.05 (kgCO₂/kg); Isolatie - Steenwol LSW, Name: Isolatie - Steenwol LSW; Isolatie - Steenwol LSW, Participates in Collision Detection: yes
Gipsplaat | Begane grond | Gipsplaat | 138.197 | 3400 | 12.5 | 0.0425 | 0.172746 | 0.203469 | Component Quantities - Projected Component Area (Net): 13.8197 m2; Projected Component Area (Gross): 16.2775 m2; Component Thickness: 12.5 mm; Material Properties - Gipsplaat, ThermalConductivity: 0.23; Gipsplaat, SpecificHeatCapacity: 840 J/kg/K; Gipsplaat, MassDensity: 800 kg/m3; Gipsplaat, Embodied Energy: 6.75 (MJ/kg); Gipsplaat, Embodied Carbon: 0.38 (kgCO₂/kg); Gipsplaat, Name: Gipsplaat; Gipsplaat, Participates in Collision Detection: yes
Gipsplaat | Begane grond | Gipsplaat | 136.497 | 3400 | 12.5 | 0.0425 | 0.170621 | 0.201344 | Component Quantities - Projected Component Area (Net): 13.6497 m2; Projected Component Area (Gross): 16.1075 m2; Component Thickness: 12.5 mm; Material Properties - Gipsplaat, ThermalConductivity: 0.23; Gipsplaat, SpecificHeatCapacity: 840 J/kg/K; Gipsplaat, MassDensity: 800 kg/m3; Gipsplaat, Embodied Energy: 6.75 (MJ/kg); Gipsplaat, Embodied Carbon: 0.38 (kgCO₂/kg); Gipsplaat, Name: Gipsplaat; Gipsplaat, Participates in Collision Detection: yes
Steen - Baksteen AFW | Begane grond | Steen - Baksteen AFW | 3212.69 | 4235 | 100 | 0.4235 | 2.00793 | 2.02475 | Component Quantities - Projected Component Area (Net): 20.2475 m2; Projected Component Area (Gross): 20.2475 m2; Component Thickness: 100 mm; Material Properties - Steen - Baksteen AFW, ThermalConductivity: 0.9; Steen - Baksteen AFW, SpecificHeatCapacity: 840 J/kg/K; Steen - Baksteen AFW, MassDensity: 1600 kg/m3; Steen - Baksteen AFW, Embodied Energy: 3 (MJ/kg); Steen - Baksteen AFW, Embodied Carbon: 0.23 (kgCO₂/kg); Steen - Baksteen AFW, Name: Steen - Baksteen AFW; Steen - Baksteen AFW, Participates in Collision Detection: yes
ALG - ISOLATIE | Begane grond | ALG - ISOLATIE | 139.644 | 4235 | 150 | 0.63525 | 3.1032 | 3.1032 | Component Quantities - Projected Component Area (Net): 20.688 m2; Projected Component Area (Gross): 20.688 m2; Component Thickness: 150 mm; Material Properties - ALG - ISOLATIE, ThermalConductivity: 0.035; ALG - ISOLATIE, SpecificHeatCapacity: 840 J/kg/K; ALG - ISOLATIE, MassDensity: 45 kg/m3; ALG - ISOLATIE, Embodied Energy: 16.8 (MJ/kg); ALG - ISOLATIE, Embodied Carbon: 1.05 (kgCO₂/kg); ALG - ISOLATIE, Name: ALG - ISOLATIE; ALG - ISOLATIE, Participates in Collision Detection: yes
Steen - Betonblok C | Begane grond | Steen - Betonblok C | 4762.66 | 4235 | 200 | 0.847 | 2.97666 | 4.01054 | Component Quantities - Projected Component Area (Net): 14.8834 m2; Projected Component Area (Gross): 20.0527 m2; Component Thickness: 200 mm; Material Properties - Steen - Betonblok C, ThermalConductivity: 0.75; Steen - Betonblok C, SpecificHeatCapacity: 840 J/kg/K; Steen - Betonblok C, MassDensity: 1600 kg/m3; Steen - Betonblok C, Embodied Energy: 0.83 (MJ/kg); Steen - Betonblok C, Embodied Carbon: 0.1 (kgCO₂/kg); Steen - Betonblok C, Name: Steen - Betonblok C; Steen - Betonblok C, Participates in Collision Detection: yes
Gipsplaat | Begane grond | Gipsplaat | 85.5612 | 3400 | 12.5 | 0.0425 | 0.106952 | 0.106952 | Component Quantities - Projected Component Area (Net): 8.55612 m2; Projected Component Area (Gross): 8.55612 m2; Component Thickness: 12.5 mm; Material Properties - Gipsplaat, ThermalConductivity: 0.23; Gipsplaat, SpecificHeatCapacity: 840 J/kg/K; Gipsplaat, MassDensity: 800 kg/m3; Gipsplaat, Embodied Energy: 6.75 (MJ/kg); Gipsplaat, Embodied Carbon: 0.38 (kgCO₂/kg); Gipsplaat, Name: Gipsplaat; Gipsplaat, Participates in Collision Detection: yes
Gipsplaat | Begane grond | Gipsplaat | 87.2612 | 3400 | 12.5 | 0.0425 | 0.109077 | 0.109077 | Component Quantities - Projected Component Area (Net): 8.72612 m2; Projected Component Area (Gross): 8.72612 m2; Component Thickness: 12.5 mm; Material Properties - Gipsplaat, ThermalConductivity: 0.23; Gipsplaat, SpecificHeatCapacity: 840 J/kg/K; Gipsplaat, MassDensity: 800 kg/m3; Gipsplaat, Embodied Energy: 6.75 (MJ/kg); Gipsplaat, Embodied Carbon: 0.38 (kgCO₂/kg); Gipsplaat, Name: Gipsplaat; Gipsplaat, Participates in Collision Detection: yes
Isolatie - Steenwol LSW | Begane grond | Isolatie - Steenwol LSW | 24.5812 | 3400 | 50 | 0.17 | 0.446931 | 0.446931 | Component Quantities - Projected Component Area (Net): 8.93862 m2; Projected Component Area (Gross): 8.93862 m2; Component Thickness: 50 mm; Material Properties - Isolatie - Steenwol LSW, ThermalConductivity: 0.039; Isolatie - Steenwol LSW, SpecificHeatCapacity: 840 J/kg/K; Isolatie - Steenwol LSW, MassDensity: 55 kg/m3; Isolatie - Steenwol LSW, Embodied Energy: 16.8 (MJ/kg); Isolatie - Steenwol LSW, Embodied Carbon: 1.05 (kgCO₂/kg); Isolatie - Steenwol LSW, Name: Isolatie - Steenwol LSW; Isolatie - Steenwol LSW, Participates in Collision Detection: yes
Gipsplaat | Begane grond | Gipsplaat | 91.0862 | 3400 | 12.5 | 0.0425 | 0.113858 | 0.113858 | Component Quantities - Projected Component Area (Net): 9.10862 m2; Projected Component Area (Gross): 9.10862 m2; Component Thickness: 12.5 mm; Material Properties - Gipsplaat, ThermalConductivity: 0.23; Gipsplaat, SpecificHeatCapacity: 840 J/kg/K; Gipsplaat, MassDensity: 800 kg/m3; Gipsplaat, Embodied Energy: 6.75 (MJ/kg); Gipsplaat, Embodied Carbon: 0.38 (kgCO₂/kg); Gipsplaat, Name: Gipsplaat; Gipsplaat, Participates in Collision Detection: yes
Gipsplaat | Begane grond | Gipsplaat | 91.5112 | 3400 | 12.5 | 0.0425 | 0.114389 | 0.114389 | Component Quantities - Projected Component Area (Net): 9.15112 m2; Projected Component Area (Gross): 9.15112 m2; Component Thickness: 12.5 mm; Material Properties - Gipsplaat, ThermalConductivity: 0.23; Gipsplaat, SpecificHeatCapacity: 840 J/kg/K; Gipsplaat, MassDensity: 800 kg/m3; Gipsplaat, Embodied Energy: 6.75 (MJ/kg); Gipsplaat, Embodied Carbon: 0.38 (kgCO₂/kg); Gipsplaat, Name: Gipsplaat; Gipsplaat, Participates in Collision Detection: yes
4 x Gipsplaat | Begane grond | Gipsplaat | 84.0491 | 3470 | 12.5 | 0.043375 | 0.105061 | 0.163178 | Component Quantities - Projected Component Area (Net): 8.40491 m2; Projected Component Area (Gross): 13.0542 m2; Component Thickness: 12.5 mm; Material Properties - Gipsplaat, ThermalConductivity: 0.23; Gipsplaat, SpecificHeatCapacity: 840 J/kg/K; Gipsplaat, MassDensity: 800 kg/m3; Gipsplaat, Embodied Energy: 6.75 (MJ/kg); Gipsplaat, Embodied Carbon: 0.38 (kgCO₂/kg); Gipsplaat, Name: Gipsplaat; Gipsplaat, Participates in Collision Detection: yes
Isolatie - Steenwol LSW | Begane grond | Isolatie - Steenwol LSW | 23.0374 | 3470 | 50 | 0.1735 | 0.418863 | 0.651328 | Component Quantities - Projected Component Area (Net): 8.40491 m2; Projected Component Area (Gross): 13.0542 m2; Component Thickness: 50 mm; Material Properties - Isolatie - Steenwol LSW, ThermalConductivity: 0.039; Isolatie - Steenwol LSW, SpecificHeatCapacity: 840 J/kg/K; Isolatie - Steenwol LSW, MassDensity: 55 kg/m3; Isolatie - Steenwol LSW, Embodied Energy: 16.8 (MJ/kg); Isolatie - Steenwol LSW, Embodied Carbon: 1.05 (kgCO₂/kg); Isolatie - Steenwol LSW, Name: Isolatie - Steenwol LSW; Isolatie - Steenwol LSW, Participates in Collision Detection: yes
Metaal - Staal AFW | Begane grond | Metaal - Staal AFW | 835.061 | 4630 | 4 | 0.01852 | 0.105039 | 0.231574 | Component Quantities - Projected Component Area (Net): 26.2598 m2; Projected Component Area (Gross): 57.8935 m2; Component Thickness: 4 mm; Material Properties - Metaal - Staal AFW, ThermalConductivity: 52; Metaal - Staal AFW, SpecificHeatCapacity: 530 J/kg/K; Metaal - Staal AFW, MassDensity: 7950 kg/m3; Metaal - Staal AFW, Embodied Energy: 25 (MJ/kg); Metaal - Staal AFW, Embodied Carbon: 1.91 (kgCO₂/kg); Metaal - Staal AFW, Name: Metaal - Staal AFW; Metaal - Staal AFW, Participates in Collision Detection: yes
Isolatie - Steenwol hard | Begane grond | Isolatie - Steenwol hard | 789.437 | 4630 | 196 | 0.90748 | 4.93398 | 11.5286 | Component Quantities - Projected Component Area (Net): 26.8751 m2; Projected Component Area (Gross): 58.8195 m2; Component Thickness: 196 mm; Material Properties - Isolatie - Steenwol hard, ThermalConductivity: 0.043; Isolatie - Steenwol hard, SpecificHeatCapacity: 840 J/kg/K; Isolatie - Steenwol hard, MassDensity: 160 kg/m3; Isolatie - Steenwol hard, Embodied Energy: 16.8 (MJ/kg); Isolatie - Steenwol hard, Embodied Carbon: 1.05 (kgCO₂/kg); Isolatie - Steenwol hard, Name: Isolatie - Steenwol hard; Isolatie - Steenwol hard, Participates in Collision Detection: yes
Membraan - waterdicht | Begane grond | Membraan - waterdicht | 127.724 | 4630 | 5 | 0.02315 | 0.121642 | 0.298751 | Component Quantities - Projected Component Area (Net): 24.3283 m2; Projected Component Area (Gross): 59.7502 m2; Component Thickness: 5 mm; Material Properties - Membraan - waterdicht, ThermalConductivity: 0.2; Membraan - waterdicht, SpecificHeatCapacity: 1840 J/kg/K; Membraan - waterdicht, MassDensity: 1050 kg/m3; Membraan - waterdicht, Embodied Energy: 51 (MJ/kg); Membraan - waterdicht, Embodied Carbon: 0.38 (kgCO₂/kg); Membraan - waterdicht, Name: Membraan - waterdicht; Membraan - waterdicht, Participates in Collision Detection: yes
2 x Gipsplaat | Begane grond | Gipsplaat | 51.5996 | 3470 | 12.5 | 0.043375 | 0.0644995 | 0.125674 | Component Quantities - Projected Component Area (Net): 5.15996 m2; Projected Component Area (Gross): 10.054 m2; Component Thickness: 12.5 mm; Material Properties - Gipsplaat, ThermalConductivity: 0.23; Gipsplaat, SpecificHeatCapacity: 840 J/kg/K; Gipsplaat, MassDensity: 800 kg/m3; Gipsplaat, Embodied Energy: 6.75 (MJ/kg); Gipsplaat, Embodied Carbon: 0.38 (kgCO₂/kg); Gipsplaat, Name: Gipsplaat; Gipsplaat, Participates in Collision Detection: yes
2 x Gipsplaat | Begane grond | Gipsplaat | 52.0234 | 3470 | 12.5 | 0.043375 | 0.0650292 | 0.126204 | Component Quantities - Projected Component Area (Net): 5.20233 m2; Projected Component Area (Gross): 10.0963 m2; Component Thickness: 12.5 mm; Material Properties - Gipsplaat, ThermalConductivity: 0.23; Gipsplaat, SpecificHeatCapacity: 840 J/kg/K; Gipsplaat, MassDensity: 800 kg/m3; Gipsplaat, Embodied Energy: 6.75 (MJ/kg); Gipsplaat, Embodied Carbon: 0.38 (kgCO₂/kg); Gipsplaat, Name: Gipsplaat; Gipsplaat, Participates in Collision Detection: yes
Isolatie - Steenwol LSW | Begane grond | Isolatie - Steenwol LSW | 15.3552 | 3470 | 50 | 0.1735 | 0.279185 | 0.523886 | Component Quantities - Projected Component Area (Net): 5.58371 m2; Projected Component Area (Gross): 10.4777 m2; Component Thickness: 50 mm; Material Properties - Isolatie - Steenwol LSW, ThermalConductivity: 0.039; Isolatie - Steenwol LSW, SpecificHeatCapacity: 840 J/kg/K; Isolatie - Steenwol LSW, MassDensity: 55 kg/m3; Isolatie - Steenwol LSW, Embodied Energy: 16.8 (MJ/kg); Isolatie - Steenwol LSW, Embodied Carbon: 1.05 (kgCO₂/kg); Isolatie - Steenwol LSW, Name: Isolatie - Steenwol LSW; Isolatie - Steenwol LSW, Participates in Collision Detection: yes
4 x Gipsplaat | Begane grond | Gipsplaat | 12 | 3470 | 12.5 | 0.043375 | 0.015 | 0.08675 | Component Quantities - Projected Component Area (Net): 1.2 m2; Projected Component Area (Gross): 6.94 m2; Component Thickness: 12.5 mm; Material Properties - Gipsplaat, ThermalConductivity: 0.23; Gipsplaat, SpecificHeatCapacity: 840 J/kg/K; Gipsplaat, MassDensity: 800 kg/m3; Gipsplaat, Embodied Energy: 6.75 (MJ/kg); Gipsplaat, Embodied Carbon: 0.38 (kgCO₂/kg); Gipsplaat, Name: Gipsplaat; Gipsplaat, Participates in Collision Detection: yes
Isolatie - Steenwol LSW | Begane grond | Isolatie - Steenwol LSW | 3.3 | 3470 | 50 | 0.1735 | 0.06 | 0.347 | Component Quantities - Projected Component Area (Net): 1.2 m2; Projected Component Area (Gross): 6.94 m2; Component Thickness: 50 mm; Material Properties - Isolatie - Steenwol LSW, ThermalConductivity: 0.039; Isolatie - Steenwol LSW, SpecificHeatCapacity: 840 J/kg/K; Isolatie - Steenwol LSW, MassDensity: 55 kg/m3; Isolatie - Steenwol LSW, Embodied Energy: 16.8 (MJ/kg); Isolatie - Steenwol LSW, Embodied Carbon: 1.05 (kgCO₂/kg); Isolatie - Steenwol LSW, Name: Isolatie - Steenwol LSW; Isolatie - Steenwol LSW, Participates in Collision Detection: yes
2 x Gipsplaat | Begane grond | Gipsplaat | 55.3274 | 585 | 12.5 | 0.0073125 | 0.0691593 | 0.0691593 | Component Quantities - Projected Component Area (Net): 5.53274 m2; Projected Component Area (Gross): 5.53274 m2; Component Thickness: 12.5 mm; Material Properties - Gipsplaat, ThermalConductivity: 0.23; Gipsplaat, SpecificHeatCapacity: 840 J/kg/K; Gipsplaat, MassDensity: 800 kg/m3; Gipsplaat, Embodied Energy: 6.75 (MJ/kg); Gipsplaat, Embodied Carbon: 0.38 (kgCO₂/kg); Gipsplaat, Name: Gipsplaat; Gipsplaat, Participates in Collision Detection: yes
Gipsplaat | Begane grond | Gipsplaat | 148.088 | 3470 | 12.5 | 0.043375 | 0.18511 | 0.271795 | Component Quantities - Projected Component Area (Net): 14.8088 m2; Projected Component Area (Gross): 21.7436 m2; Component Thickness: 12.5 mm; Material Properties - Gipsplaat, ThermalConductivity: 0.23; Gipsplaat, SpecificHeatCapacity: 840 J/kg/K; Gipsplaat, MassDensity: 800 kg/m3; Gipsplaat, Embodied Energy: 6.75 (MJ/kg); Gipsplaat, Embodied Carbon: 0.38 (kgCO₂/kg); Gipsplaat, Name: Gipsplaat; Gipsplaat, Participates in Collision Detection: yes
Gipsplaat | Begane grond | Gipsplaat | 148.532 | 3470 | 12.5 | 0.043375 | 0.185665 | 0.27235 | Component Quantities - Projected Component Area (Net): 14.8532 m2; Projected Component Area (Gross): 21.788 m2; Component Thickness: 12.5 mm; Material Properties - Gipsplaat, ThermalConductivity: 0.23; Gipsplaat, SpecificHeatCapacity: 840 J/kg/K; Gipsplaat, MassDensity: 800 kg/m3; Gipsplaat, Embodied Energy: 6.75 (MJ/kg); Gipsplaat, Embodied Carbon: 0.38 (kgCO₂/kg); Gipsplaat, Name: Gipsplaat; Gipsplaat, Participates in Collision Detection: yes
Isolatie - Steenwol LSW | Begane grond | Isolatie - Steenwol LSW | 39.9251 | 3470 | 50 | 0.1735 | 0.72591 | 1.07265 | Component Quantities - Projected Component Area (Net): 14.5182 m2; Projected Component Area (Gross): 21.453 m2; Component Thickness: 50 mm; Material Properties - Isolatie - Steenwol LSW, ThermalConductivity: 0.039; Isolatie - Steenwol LSW, SpecificHeatCapacity: 840 J/kg/K; Isolatie - Steenwol LSW, MassDensity: 55 kg/m3; Isolatie - Steenwol LSW, Embodied Energy: 16.8 (MJ/kg); Isolatie - Steenwol LSW, Embodied Carbon: 1.05 (kgCO₂/kg); Isolatie - Steenwol LSW, Name: Isolatie - Steenwol LSW; Isolatie - Steenwol LSW, Participates in Collision Detection: yes
Gipsplaat | Begane grond | Gipsplaat | 143.023 | 3470 | 12.5 | 0.043375 | 0.178779 | 0.265464 | Component Quantities - Projected Component Area (Net): 14.3023 m2; Projected Component Area (Gross): 21.2371 m2; Component Thickness: 12.5 mm; Material Properties - Gipsplaat, ThermalConductivity: 0.23; Gipsplaat, SpecificHeatCapacity: 840 J/kg/K; Gipsplaat, MassDensity: 800 kg/m3; Gipsplaat, Embodied Energy: 6.75 (MJ/kg); Gipsplaat, Embodied Carbon: 0.38 (kgCO₂/kg); Gipsplaat, Name: Gipsplaat; Gipsplaat, Participates in Collision Detection: yes
Gipsplaat | Begane grond | Gipsplaat | 141.732 | 3470 | 12.5 | 0.043375 | 0.177165 | 0.26385 | Component Quantities - Projected Component Area (Net): 14.1732 m2; Projected Component Area (Gross): 21.108 m2; Component Thickness: 12.5 mm; Material Properties - Gipsplaat, ThermalConductivity: 0.23; Gipsplaat, SpecificHeatCapacity: 840 J/kg/K; Gipsplaat, MassDensity: 800 kg/m3; Gipsplaat, Embodied Energy: 6.75 (MJ/kg); Gipsplaat, Embodied Carbon: 0.38 (kgCO₂/kg); Gipsplaat, Name: Gipsplaat; Gipsplaat, Participates in Collision Detection: yes
3 x Gipsplaat | Begane grond | Gipsplaat | 4.165 | 3400 | 12.5 | 0.0425 | 0.00520625 | 0.00520625 | Component Quantities - Projected Component Area (Net): 0.4165 m2; Projected Component Area (Gross): 0.4165 m2; Component Thickness: 12.5 mm; Material Properties - Gipsplaat, ThermalConductivity: 0.23; Gipsplaat, SpecificHeatCapacity: 840 J/kg/K; Gipsplaat, MassDensity: 800 kg/m3; Gipsplaat, Embodied Energy: 6.75 (MJ/kg); Gipsplaat, Embodied Carbon: 0.38 (kgCO₂/kg); Gipsplaat, Name: Gipsplaat; Gipsplaat, Participates in Collision Detection: yes
3 x Gipsplaat | Begane grond | Gipsplaat | 4.59 | 3400 | 12.5 | 0.0425 | 0.0057375 | 0.0057375 | Component Quantities - Projected Component Area (Net): 0.459 m2; Projected Component Area (Gross): 0.459 m2; Component Thickness: 12.5 mm; Material Properties - Gipsplaat, ThermalConductivity: 0.23; Gipsplaat, SpecificHeatCapacity: 840 J/kg/K; Gipsplaat, MassDensity: 800 kg/m3; Gipsplaat, Embodied Energy: 6.75 (MJ/kg); Gipsplaat, Embodied Carbon: 0.38 (kgCO₂/kg); Gipsplaat, Name: Gipsplaat; Gipsplaat, Participates in Collision Detection: yes
Gipsplaat | Begane grond | Gipsplaat | 213.683 | 3470 | 12.5 | 0.043375 | 0.267103 | 0.267103 | Component Quantities - Projected Component Area (Net): 21.3683 m2; Projected Component Area (Gross): 21.3683 m2; Component Thickness: 12.5 mm; Material Properties - Gipsplaat, ThermalConductivity: 0.23; Gipsplaat, SpecificHeatCapacity: 840 J/kg/K; Gipsplaat, MassDensity: 800 kg/m3; Gipsplaat, Embodied Energy: 6.75 (MJ/kg); Gipsplaat, Embodied Carbon: 0.38 (kgCO₂/kg); Gipsplaat, Name: Gipsplaat; Gipsplaat, Participates in Collision Detection: yes
Gipsplaat | Begane grond | Gipsplaat | 214.106 | 3470 | 12.5 | 0.043375 | 0.267633 | 0.267633 | Component Quantities - Projected Component Area (Net): 21.4106 m2; Projected Component Area (Gross): 21.4106 m2; Component Thickness: 12.5 mm; Material Properties - Gipsplaat, ThermalConductivity: 0.23; Gipsplaat, SpecificHeatCapacity: 840 J/kg/K; Gipsplaat, MassDensity: 800 kg/m3; Gipsplaat, Embodied Energy: 6.75 (MJ/kg); Gipsplaat, Embodied Carbon: 0.38 (kgCO₂/kg); Gipsplaat, Name: Gipsplaat; Gipsplaat, Participates in Collision Detection: yes
Isolatie - Steenwol LSW | Begane grond | Isolatie - Steenwol LSW | 58.9958 | 3470 | 50 | 0.1735 | 1.07265 | 1.07265 | Component Quantities - Projected Component Area (Net): 21.453 m2; Projected Component Area (Gross): 21.453 m2; Component Thickness: 50 mm; Material Properties - Isolatie - Steenwol LSW, ThermalConductivity: 0.039; Isolatie - Steenwol LSW, SpecificHeatCapacity: 840 J/kg/K; Isolatie - Steenwol LSW, MassDensity: 55 kg/m3; Isolatie - Steenwol LSW, Embodied Energy: 16.8 (MJ/kg); Isolatie - Steenwol LSW, Embodied Carbon: 1.05 (kgCO₂/kg); Isolatie - Steenwol LSW, Name: Isolatie - Steenwol LSW; Isolatie - Steenwol LSW, Participates in Collision Detection: yes
Gipsplaat | Begane grond | Gipsplaat | 212.371 | 3470 | 12.5 | 0.043375 | 0.265464 | 0.265464 | Component Quantities - Projected Component Area (Net): 21.2371 m2; Projected Component Area (Gross): 21.2371 m2; Component Thickness: 12.5 mm; Material Properties - Gipsplaat, ThermalConductivity: 0.23; Gipsplaat, SpecificHeatCapacity: 840 J/kg/K; Gipsplaat, MassDensity: 800 kg/m3; Gipsplaat, Embodied Energy: 6.75 (MJ/kg); Gipsplaat, Embodied Carbon: 0.38 (kgCO₂/kg); Gipsplaat, Name: Gipsplaat; Gipsplaat, Participates in Collision Detection: yes
Gipsplaat | Begane grond | Gipsplaat | 211.08 | 3470 | 12.5 | 0.043375 | 0.26385 | 0.26385 | Component Quantities - Projected Component Area (Net): 21.108 m2; Projected Component Area (Gross): 21.108 m2; Component Thickness: 12.5 mm; Material Properties - Gipsplaat, ThermalConductivity: 0.23; Gipsplaat, SpecificHeatCapacity: 840 J/kg/K; Gipsplaat, MassDensity: 800 kg/m3; Gipsplaat, Embodied Energy: 6.75 (MJ/kg); Gipsplaat, Embodied Carbon: 0.38 (kgCO₂/kg); Gipsplaat, Name: Gipsplaat; Gipsplaat, Participates in Collision Detection: yes
Steen - Baksteen AFW | Begane grond | Steen - Baksteen AFW | 5459.89 | 4235 | 100 | 0.4235 | 3.41243 | 5.03542 | Component Quantities - Projected Component Area (Net): 34.1243 m2; Projected Component Area (Gross): 50.3542 m2; Component Thickness: 100 mm; Material Properties - Steen - Baksteen AFW, ThermalConductivity: 0.9; Steen - Baksteen AFW, SpecificHeatCapacity: 840 J/kg/K; Steen - Baksteen AFW, MassDensity: 1600 kg/m3; Steen - Baksteen AFW, Embodied Energy: 3 (MJ/kg); Steen - Baksteen AFW, Embodied Carbon: 0.23 (kgCO₂/kg); Steen - Baksteen AFW, Name: Steen - Baksteen AFW; Steen - Baksteen AFW, Participates in Collision Detection: yes
ALG - ISOLATIE | Begane grond | ALG - ISOLATIE | 339.891 | 4235 | 150 | 0.63525 | 7.55312 | 7.55312 | Component Quantities - Projected Component Area (Net): 50.3542 m2; Projected Component Area (Gross): 50.3542 m2; Component Thickness: 150 mm; Material Properties - ALG - ISOLATIE, ThermalConductivity: 0.035; ALG - ISOLATIE, SpecificHeatCapacity: 840 J/kg/K; ALG - ISOLATIE, MassDensity: 45 kg/m3; ALG - ISOLATIE, Embodied Energy: 16.8 (MJ/kg); ALG - ISOLATIE, Embodied Carbon: 1.05 (kgCO₂/kg); ALG - ISOLATIE, Name: ALG - ISOLATIE; ALG - ISOLATIE, Participates in Collision Detection: yes
Steen - Betonblok C | Begane grond | Steen - Betonblok C | 13202.4 | 4235 | 200 | 0.847 | 8.25151 | 10.0708 | Component Quantities - Projected Component Area (Net): 41.2583 m2; Projected Component Area (Gross): 50.3542 m2; Component Thickness: 200 mm; Material Properties - Steen - Betonblok C, ThermalConductivity: 0.75; Steen - Betonblok C, SpecificHeatCapacity: 840 J/kg/K; Steen - Betonblok C, MassDensity: 1600 kg/m3; Steen - Betonblok C, Embodied Energy: 0.83 (MJ/kg); Steen - Betonblok C, Embodied Carbon: 0.1 (kgCO₂/kg); Steen - Betonblok C, Name: Steen - Betonblok C; Steen - Betonblok C, Participates in Collision Detection: yes
Gipsplaat | Begane grond | Gipsplaat | 591.535 | 3470 | 12.5 | 0.043375 | 0.739419 | 1.09326 | Component Quantities - Projected Component Area (Net): 59.1535 m2; Projected Component Area (Gross): 87.4611 m2; Component Thickness: 12.5 mm; Material Properties - Gipsplaat, ThermalConductivity: 0.23; Gipsplaat, SpecificHeatCapacity: 840 J/kg/K; Gipsplaat, MassDensity: 800 kg/m3; Gipsplaat, Embodied Energy: 6.75 (MJ/kg); Gipsplaat, Embodied Carbon: 0.38 (kgCO₂/kg); Gipsplaat, Name: Gipsplaat; Gipsplaat, Participates in Collision Detection: yes
Gipsplaat | Begane grond | Gipsplaat | 594.502 | 3470 | 12.5 | 0.043375 | 0.743127 | 1.09697 | Component Quantities - Projected Component Area (Net): 59.4502 m2; Projected Component Area (Gross): 87.7578 m2; Component Thickness: 12.5 mm; Material Properties - Gipsplaat, ThermalConductivity: 0.23; Gipsplaat, SpecificHeatCapacity: 840 J/kg/K; Gipsplaat, MassDensity: 800 kg/m3; Gipsplaat, Embodied Energy: 6.75 (MJ/kg); Gipsplaat, Embodied Carbon: 0.38 (kgCO₂/kg); Gipsplaat, Name: Gipsplaat; Gipsplaat, Participates in Collision Detection: yes
Isolatie - Steenwol LSW | Begane grond | Isolatie - Steenwol LSW | 165.204 | 3470 | 50 | 0.1735 | 3.0037 | 4.41908 | Component Quantities - Projected Component Area (Net): 60.1282 m2; Projected Component Area (Gross): 88.4358 m2; Component Thickness: 50 mm; Material Properties - Isolatie - Steenwol LSW, ThermalConductivity: 0.039; Isolatie - Steenwol LSW, SpecificHeatCapacity: 840 J/kg/K; Isolatie - Steenwol LSW, MassDensity: 55 kg/m3; Isolatie - Steenwol LSW, Embodied Energy: 16.8 (MJ/kg); Isolatie - Steenwol LSW, Embodied Carbon: 1.05 (kgCO₂/kg); Isolatie - Steenwol LSW, Name: Isolatie - Steenwol LSW; Isolatie - Steenwol LSW, Participates in Collision Detection: yes
Gipsplaat | Begane grond | Gipsplaat | 598.35 | 3470 | 12.5 | 0.043375 | 0.747938 | 1.10178 | Component Quantities - Projected Component Area (Net): 59.835 m2; Projected Component Area (Gross): 88.1426 m2; Component Thickness: 12.5 mm; Material Properties - Gipsplaat, ThermalConductivity: 0.23; Gipsplaat, SpecificHeatCapacity: 840 J/kg/K; Gipsplaat, MassDensity: 800 kg/m3; Gipsplaat, Embodied Energy: 6.75 (MJ/kg); Gipsplaat, Embodied Carbon: 0.38 (kgCO₂/kg); Gipsplaat, Name: Gipsplaat; Gipsplaat, Participates in Collision Detection: yes
Gipsplaat | Begane grond | Gipsplaat | 597.097 | 3470 | 12.5 | 0.043375 | 0.746371 | 1.10022 | Component Quantities - Projected Component Area (Net): 59.7097 m2; Projected Component Area (Gross): 88.0173 m2; Component Thickness: 12.5 mm; Material Properties - Gipsplaat, ThermalConductivity: 0.23; Gipsplaat, SpecificHeatCapacity: 840 J/kg/K; Gipsplaat, MassDensity: 800 kg/m3; Gipsplaat, Embodied Energy: 6.75 (MJ/kg); Gipsplaat, Embodied Carbon: 0.38 (kgCO₂/kg); Gipsplaat, Name: Gipsplaat; Gipsplaat, Participates in Collision Detection: yes
Gipsplaat | Begane grond | Gipsplaat | 131.368 | 3470 | 12.5 | 0.043375 | 0.16421 | 0.16421 | Component Quantities - Projected Component Area (Net): 13.1374 m2; Projected Component Area (Gross): 13.1374 m2; Component Thickness: 12.5 mm; Material Properties - Gipsplaat, ThermalConductivity: 0.23; Gipsplaat, SpecificHeatCapacity: 840 J/kg/K; Gipsplaat, MassDensity: 800 kg/m3; Gipsplaat, Embodied Energy: 6.75 (MJ/kg); Gipsplaat, Embodied Carbon: 0.38 (kgCO₂/kg); Gipsplaat, Name: Gipsplaat; Gipsplaat, Participates in Collision Detection: yes
2 x Gipsplaat | Begane grond | Gipsplaat | 131.376 | 3470 | 12.5 | 0.043375 | 0.16422 | 0.16422 | Component Quantities - Projected Component Area (Net): 13.1376 m2; Projected Component Area (Gross): 13.1376 m2; Component Thickness: 12.5 mm; Material Properties - Gipsplaat, ThermalConductivity: 0.23; Gipsplaat, SpecificHeatCapacity: 840 J/kg/K; Gipsplaat, MassDensity: 800 kg/m3; Gipsplaat, Embodied Energy: 6.75 (MJ/kg); Gipsplaat, Embodied Carbon: 0.38 (kgCO₂/kg); Gipsplaat, Name: Gipsplaat; Gipsplaat, Participates in Collision Detection: yes
Isolatie - Steenwol LSW | Begane grond | Isolatie - Steenwol LSW | 36.1284 | 3470 | 50 | 0.1735 | 0.656881 | 0.656881 | Component Quantities - Projected Component Area (Net): 13.1376 m2; Projected Component Area (Gross): 13.1376 m2; Component Thickness: 50 mm; Material Properties - Isolatie - Steenwol LSW, ThermalConductivity: 0.039; Isolatie - Steenwol LSW, SpecificHeatCapacity: 840 J/kg/K; Isolatie - Steenwol LSW, MassDensity: 55 kg/m3; Isolatie - Steenwol LSW, Embodied Energy: 16.8 (MJ/kg); Isolatie - Steenwol LSW, Embodied Carbon: 1.05 (kgCO₂/kg); Isolatie - Steenwol LSW, Name: Isolatie - Steenwol LSW; Isolatie - Steenwol LSW, Participates in Collision Detection: yes
6 x Gipsplaat | Begane grond | Gipsplaat | 131.374 | 3470 | 12.5 | 0.043375 | 0.164218 | 0.164218 | Component Quantities - Projected Component Area (Net): 13.1374 m2; Projected Component Area (Gross): 13.1374 m2; Component Thickness: 12.5 mm; Material Properties - Gipsplaat, ThermalConductivity: 0.23; Gipsplaat, SpecificHeatCapacity: 840 J/kg/K; Gipsplaat, MassDensity: 800 kg/m3; Gipsplaat, Embodied Energy: 6.75 (MJ/kg); Gipsplaat, Embodied Carbon: 0.38 (kgCO₂/kg); Gipsplaat, Name: Gipsplaat; Gipsplaat, Participates in Collision Detection: yes
Cement | Begane grond | Cement | 42736 |  |  |  | 22.4926 | 22.4926 | Component Quantities - Projected Component Area (Net): 321.323 m2; Projected Component Area (Gross): 321.323 m2; Component Thickness: 70 mm; Material Properties - Cement, ThermalConductivity: 0.93; Cement, SpecificHeatCapacity: 840 J/kg/K; Cement, MassDensity: 1900 kg/m3; Cement, Embodied Energy: 0.97 (MJ/kg); Cement, Embodied Carbon: 0.146 (kgCO₂/kg); Cement, Name: Cement; Cement, Participates in Collision Detection: yes
Beton gewapend C vloer | Begane grond | Beton gewapend C vloer | 154235 |  |  |  | 64.2647 | 64.2647 | Component Quantities - Projected Component Area (Net): 321.323 m2; Projected Component Area (Gross): 321.323 m2; Component Thickness: 200 mm; Material Properties - Beton gewapend C vloer, ThermalConductivity: 2.5; Beton gewapend C vloer, SpecificHeatCapacity: 1000 J/kg/K; Beton gewapend C vloer, MassDensity: 2400 kg/m3; Beton gewapend C vloer, Embodied Energy: 2.33 (MJ/kg); Beton gewapend C vloer, Embodied Carbon: 0.242 (kgCO₂/kg); Beton gewapend C vloer, Name: Beton gewapend C vloer; Beton gewapend C vloer, Participates in Collision Detection: yes
ALG - ISOLATIE | Begane grond | ALG - ISOLATIE | 2313.53 |  |  |  | 51.4117 | 51.4117 | Component Quantities - Projected Component Area (Net): 321.323 m2; Projected Component Area (Gross): 321.323 m2; Component Thickness: 160 mm; Material Properties - ALG - ISOLATIE, ThermalConductivity: 0.035; ALG - ISOLATIE, SpecificHeatCapacity: 840 J/kg/K; ALG - ISOLATIE, MassDensity: 45 kg/m3; ALG - ISOLATIE, Embodied Energy: 16.8 (MJ/kg); ALG - ISOLATIE, Embodied Carbon: 1.05 (kgCO₂/kg); ALG - ISOLATIE, Name: ALG - ISOLATIE; ALG - ISOLATIE, Participates in Collision Detection: yes
Grondverbetering | Begane grond | Grondverbetering | 170676 |  |  |  | 94.8199 | 94.8199 | Component Quantities - Projected Component Area (Net): 316.066 m2; Projected Component Area (Gross): 316.066 m2; Component Thickness: 300 mm; Material Properties - Grondverbetering, ThermalConductivity: 1.4; Grondverbetering, SpecificHeatCapacity: 1000 J/kg/K; Grondverbetering, MassDensity: 1800 kg/m3; Grondverbetering, Embodied Energy: 0.083 (MJ/kg); Grondverbetering, Embodied Carbon: 0.0048 (kgCO₂/kg); Grondverbetering, Name: Grondverbetering; Grondverbetering, Participates in Collision Detection: yes
2 x Gipsplaat | Begane grond | Gipsplaat | 75.82 | 3400 | 12.5 | 0.0425 | 0.094775 | 0.094775 | Component Quantities - Projected Component Area (Net): 7.582 m2; Projected Component Area (Gross): 7.582 m2; Component Thickness: 12.5 mm; Material Properties - Gipsplaat, ThermalConductivity: 0.23; Gipsplaat, SpecificHeatCapacity: 840 J/kg/K; Gipsplaat, MassDensity: 800 kg/m3; Gipsplaat, Embodied Energy: 6.75 (MJ/kg); Gipsplaat, Embodied Carbon: 0.38 (kgCO₂/kg); Gipsplaat, Name: Gipsplaat; Gipsplaat, Participates in Collision Detection: yes
2 x Gipsplaat | Begane grond | Gipsplaat | 76.67 | 3400 | 12.5 | 0.0425 | 0.0958375 | 0.0958375 | Component Quantities - Projected Component Area (Net): 7.667 m2; Projected Component Area (Gross): 7.667 m2; Component Thickness: 12.5 mm; Material Properties - Gipsplaat, ThermalConductivity: 0.23; Gipsplaat, SpecificHeatCapacity: 840 J/kg/K; Gipsplaat, MassDensity: 800 kg/m3; Gipsplaat, Embodied Energy: 6.75 (MJ/kg); Gipsplaat, Embodied Carbon: 0.38 (kgCO₂/kg); Gipsplaat, Name: Gipsplaat; Gipsplaat, Participates in Collision Detection: yes
2 x Isolatie - Steenwol LSW | Begane grond | Isolatie - Steenwol LSW | 21.318 | 3400 | 50 | 0.17 | 0.3876 | 0.3876 | Component Quantities - Projected Component Area (Net): 7.752 m2; Projected Component Area (Gross): 7.752 m2; Component Thickness: 50 mm; Material Properties - Isolatie - Steenwol LSW, ThermalConductivity: 0.039; Isolatie - Steenwol LSW, SpecificHeatCapacity: 840 J/kg/K; Isolatie - Steenwol LSW, MassDensity: 55 kg/m3; Isolatie - Steenwol LSW, Embodied Energy: 16.8 (MJ/kg); Isolatie - Steenwol LSW, Embodied Carbon: 1.05 (kgCO₂/kg); Isolatie - Steenwol LSW, Name: Isolatie - Steenwol LSW; Isolatie - Steenwol LSW, Participates in Collision Detection: yes
10 x Gipsplaat | Begane grond | Gipsplaat | 42.755 | 3400 | 12.5 | 0.0425 | 0.0534438 | 0.0534438 | Component Quantities - Projected Component Area (Net): 4.2755 m2; Projected Component Area (Gross): 4.2755 m2; Component Thickness: 12.5 mm; Material Properties - Gipsplaat, ThermalConductivity: 0.23; Gipsplaat, SpecificHeatCapacity: 840 J/kg/K; Gipsplaat, MassDensity: 800 kg/m3; Gipsplaat, Embodied Energy: 6.75 (MJ/kg); Gipsplaat, Embodied Carbon: 0.38 (kgCO₂/kg); Gipsplaat, Name: Gipsplaat; Gipsplaat, Participates in Collision Detection: yes
10 x Gipsplaat | Begane grond | Gipsplaat | 44.03 | 3400 | 12.5 | 0.0425 | 0.0550375 | 0.0550375 | Component Quantities - Projected Component Area (Net): 4.403 m2; Projected Component Area (Gross): 4.403 m2; Component Thickness: 12.5 mm; Material Properties - Gipsplaat, ThermalConductivity: 0.23; Gipsplaat, SpecificHeatCapacity: 840 J/kg/K; Gipsplaat, MassDensity: 800 kg/m3; Gipsplaat, Embodied Energy: 6.75 (MJ/kg); Gipsplaat, Embodied Carbon: 0.38 (kgCO₂/kg); Gipsplaat, Name: Gipsplaat; Gipsplaat, Participates in Collision Detection: yes
5 x Isolatie - Steenwol LSW | Begane grond | Isolatie - Steenwol LSW | 12.8095 | 3400 | 50 | 0.17 | 0.2329 | 0.2329 | Component Quantities - Projected Component Area (Net): 4.658 m2; Projected Component Area (Gross): 4.658 m2; Component Thickness: 50 mm; Material Properties - Isolatie - Steenwol LSW, ThermalConductivity: 0.039; Isolatie - Steenwol LSW, SpecificHeatCapacity: 840 J/kg/K; Isolatie - Steenwol LSW, MassDensity: 55 kg/m3; Isolatie - Steenwol LSW, Embodied Energy: 16.8 (MJ/kg); Isolatie - Steenwol LSW, Embodied Carbon: 1.05 (kgCO₂/kg); Isolatie - Steenwol LSW, Name: Isolatie - Steenwol LSW; Isolatie - Steenwol LSW, Participates in Collision Detection: yes
Gipsplaat | Begane grond | Gipsplaat | 247.487 | 3400 | 12.5 | 0.0425 | 0.309359 | 0.309359 | Component Quantities - Projected Component Area (Net): 24.7487 m2; Projected Component Area (Gross): 24.7487 m2; Component Thickness: 12.5 mm; Material Properties - Gipsplaat, ThermalConductivity: 0.23; Gipsplaat, SpecificHeatCapacity: 840 J/kg/K; Gipsplaat, MassDensity: 800 kg/m3; Gipsplaat, Embodied Energy: 6.75 (MJ/kg); Gipsplaat, Embodied Carbon: 0.38 (kgCO₂/kg); Gipsplaat, Name: Gipsplaat; Gipsplaat, Participates in Collision Detection: yes
Gipsplaat | Begane grond | Gipsplaat | 251.312 | 3400 | 12.5 | 0.0425 | 0.31414 | 0.31414 | Component Quantities - Projected Component Area (Net): 25.1312 m2; Projected Component Area (Gross): 25.1312 m2; Component Thickness: 12.5 mm; Material Properties - Gipsplaat, ThermalConductivity: 0.23; Gipsplaat, SpecificHeatCapacity: 840 J/kg/K; Gipsplaat, MassDensity: 800 kg/m3; Gipsplaat, Embodied Energy: 6.75 (MJ/kg); Gipsplaat, Embodied Carbon: 0.38 (kgCO₂/kg); Gipsplaat, Name: Gipsplaat; Gipsplaat, Participates in Collision Detection: yes
Gipsplaat | Begane grond | Gipsplaat | 258.537 | 3400 | 12.5 | 0.0425 | 0.323172 | 0.323172 | Component Quantities - Projected Component Area (Net): 25.8537 m2; Projected Component Area (Gross): 25.8537 m2; Component Thickness: 12.5 mm; Material Properties - Gipsplaat, ThermalConductivity: 0.23; Gipsplaat, SpecificHeatCapacity: 840 J/kg/K; Gipsplaat, MassDensity: 800 kg/m3; Gipsplaat, Embodied Energy: 6.75 (MJ/kg); Gipsplaat, Embodied Carbon: 0.38 (kgCO₂/kg); Gipsplaat, Name: Gipsplaat; Gipsplaat, Participates in Collision Detection: yes
Gipsplaat | Begane grond | Gipsplaat | 257.687 | 3400 | 12.5 | 0.0425 | 0.322109 | 0.322109 | Component Quantities - Projected Component Area (Net): 25.7687 m2; Projected Component Area (Gross): 25.7687 m2; Component Thickness: 12.5 mm; Material Properties - Gipsplaat, ThermalConductivity: 0.23; Gipsplaat, SpecificHeatCapacity: 840 J/kg/K; Gipsplaat, MassDensity: 800 kg/m3; Gipsplaat, Embodied Energy: 6.75 (MJ/kg); Gipsplaat, Embodied Carbon: 0.38 (kgCO₂/kg); Gipsplaat, Name: Gipsplaat; Gipsplaat, Participates in Collision Detection: yes
2 x Isolatie - Steenwol LSW | Begane grond | Isolatie - Steenwol LSW | 10.4313 | 3480 | 50 | 0.174 | 0.18966 | 0.18966 | Component Quantities - Projected Component Area (Net): 3.7932 m2; Projected Component Area (Gross): 3.7932 m2; Component Thickness: 50 mm; Material Properties - Isolatie - Steenwol LSW, ThermalConductivity: 0.039; Isolatie - Steenwol LSW, SpecificHeatCapacity: 840 J/kg/K; Isolatie - Steenwol LSW, MassDensity: 55 kg/m3; Isolatie - Steenwol LSW, Embodied Energy: 16.8 (MJ/kg); Isolatie - Steenwol LSW, Embodied Carbon: 1.05 (kgCO₂/kg); Isolatie - Steenwol LSW, Name: Isolatie - Steenwol LSW; Isolatie - Steenwol LSW, Participates in Collision Detection: yes
4 x Gipsplaat | Begane grond | Gipsplaat | 37.932 | 3480 | 12.5 | 0.0435 | 0.047415 | 0.047415 | Component Quantities - Projected Component Area (Net): 3.7932 m2; Projected Component Area (Gross): 3.7932 m2; Component Thickness: 12.5 mm; Material Properties - Gipsplaat, ThermalConductivity: 0.23; Gipsplaat, SpecificHeatCapacity: 840 J/kg/K; Gipsplaat, MassDensity: 800 kg/m3; Gipsplaat, Embodied Energy: 6.75 (MJ/kg); Gipsplaat, Embodied Carbon: 0.38 (kgCO₂/kg); Gipsplaat, Name: Gipsplaat; Gipsplaat, Participates in Collision Detection: yes
2 x Gipsplaat | Begane grond | Gipsplaat | 15.1292 | 3470 | 12.5 | 0.043375 | 0.0189116 | 0.0189116 | Component Quantities - Projected Component Area (Net): 1.51292 m2; Projected Component Area (Gross): 1.51292 m2; Component Thickness: 12.5 mm; Material Properties - Gipsplaat, ThermalConductivity: 0.23; Gipsplaat, SpecificHeatCapacity: 840 J/kg/K; Gipsplaat, MassDensity: 800 kg/m3; Gipsplaat, Embodied Energy: 6.75 (MJ/kg); Gipsplaat, Embodied Carbon: 0.38 (kgCO₂/kg); Gipsplaat, Name: Gipsplaat; Gipsplaat, Participates in Collision Detection: yes
2 x Gipsplaat | Begane grond | Gipsplaat | 14.6955 | 3470 | 12.5 | 0.043375 | 0.0183694 | 0.0183694 | Component Quantities - Projected Component Area (Net): 1.46955 m2; Projected Component Area (Gross): 1.46955 m2; Component Thickness: 12.5 mm; Material Properties - Gipsplaat, ThermalConductivity: 0.23; Gipsplaat, SpecificHeatCapacity: 840 J/kg/K; Gipsplaat, MassDensity: 800 kg/m3; Gipsplaat, Embodied Energy: 6.75 (MJ/kg); Gipsplaat, Embodied Carbon: 0.38 (kgCO₂/kg); Gipsplaat, Name: Gipsplaat; Gipsplaat, Participates in Collision Detection: yes
2 x Isolatie - Steenwol LSW | Begane grond | Isolatie - Steenwol LSW | 3.92198 | 3470 | 50 | 0.1735 | 0.0713087 | 0.0713087 | Component Quantities - Projected Component Area (Net): 1.42617 m2; Projected Component Area (Gross): 1.42617 m2; Component Thickness: 50 mm; Material Properties - Isolatie - Steenwol LSW, ThermalConductivity: 0.039; Isolatie - Steenwol LSW, SpecificHeatCapacity: 840 J/kg/K; Isolatie - Steenwol LSW, MassDensity: 55 kg/m3; Isolatie - Steenwol LSW, Embodied Energy: 16.8 (MJ/kg); Isolatie - Steenwol LSW, Embodied Carbon: 1.05 (kgCO₂/kg); Isolatie - Steenwol LSW, Name: Isolatie - Steenwol LSW; Isolatie - Steenwol LSW, Participates in Collision Detection: yes
2 x Gipsplaat | Begane grond | Gipsplaat | 12.5267 | 3470 | 12.5 | 0.043375 | 0.0156584 | 0.0156584 | Component Quantities - Projected Component Area (Net): 1.25267 m2; Projected Component Area (Gross): 1.25267 m2; Component Thickness: 12.5 mm; Material Properties - Gipsplaat, ThermalConductivity: 0.23; Gipsplaat, SpecificHeatCapacity: 840 J/kg/K; Gipsplaat, MassDensity: 800 kg/m3; Gipsplaat, Embodied Energy: 6.75 (MJ/kg); Gipsplaat, Embodied Carbon: 0.38 (kgCO₂/kg); Gipsplaat, Name: Gipsplaat; Gipsplaat, Participates in Collision Detection: yes
2 x Gipsplaat | Begane grond | Gipsplaat | 12.093 | 3470 | 12.5 | 0.043375 | 0.0151162 | 0.0151162 | Component Quantities - Projected Component Area (Net): 1.2093 m2; Projected Component Area (Gross): 1.2093 m2; Component Thickness: 12.5 mm; Material Properties - Gipsplaat, ThermalConductivity: 0.23; Gipsplaat, SpecificHeatCapacity: 840 J/kg/K; Gipsplaat, MassDensity: 800 kg/m3; Gipsplaat, Embodied Energy: 6.75 (MJ/kg); Gipsplaat, Embodied Carbon: 0.38 (kgCO₂/kg); Gipsplaat, Name: Gipsplaat; Gipsplaat, Participates in Collision Detection: yes
Gipsplaat | Begane grond | Gipsplaat | 43.18 | 3400 | 12.5 | 0.0425 | 0.053975 | 0.053975 | Component Quantities - Projected Component Area (Net): 4.318 m2; Projected Component Area (Gross): 4.318 m2; Component Thickness: 12.5 mm; Material Properties - Gipsplaat, ThermalConductivity: 0.23; Gipsplaat, SpecificHeatCapacity: 840 J/kg/K; Gipsplaat, MassDensity: 800 kg/m3; Gipsplaat, Embodied Energy: 6.75 (MJ/kg); Gipsplaat, Embodied Carbon: 0.38 (kgCO₂/kg); Gipsplaat, Name: Gipsplaat; Gipsplaat, Participates in Collision Detection: yes
Gipsplaat | Begane grond | Gipsplaat | 44.455 | 3400 | 12.5 | 0.0425 | 0.0555688 | 0.0555688 | Component Quantities - Projected Component Area (Net): 4.4455 m2; Projected Component Area (Gross): 4.4455 m2; Component Thickness: 12.5 mm; Material Properties - Gipsplaat, ThermalConductivity: 0.23; Gipsplaat, SpecificHeatCapacity: 840 J/kg/K; Gipsplaat, MassDensity: 800 kg/m3; Gipsplaat, Embodied Energy: 6.75 (MJ/kg); Gipsplaat, Embodied Carbon: 0.38 (kgCO₂/kg); Gipsplaat, Name: Gipsplaat; Gipsplaat, Participates in Collision Detection: yes
Isolatie - Steenwol LSW | Begane grond | Isolatie - Steenwol LSW | 13.277 | 3400 | 50 | 0.17 | 0.2414 | 0.2414 | Component Quantities - Projected Component Area (Net): 4.828 m2; Projected Component Area (Gross): 4.828 m2; Component Thickness: 50 mm; Material Properties - Isolatie - Steenwol LSW, ThermalConductivity: 0.039; Isolatie - Steenwol LSW, SpecificHeatCapacity: 840 J/kg/K; Isolatie - Steenwol LSW, MassDensity: 55 kg/m3; Isolatie - Steenwol LSW, Embodied Energy: 16.8 (MJ/kg); Isolatie - Steenwol LSW, Embodied Carbon: 1.05 (kgCO₂/kg); Isolatie - Steenwol LSW, Name: Isolatie - Steenwol LSW; Isolatie - Steenwol LSW, Participates in Collision Detection: yes
2 x Gipsplaat | Begane grond | Gipsplaat | 48.28 | 3400 | 12.5 | 0.0425 | 0.06035 | 0.06035 | Component Quantities - Projected Component Area (Net): 4.828 m2; Projected Component Area (Gross): 4.828 m2; Component Thickness: 12.5 mm; Material Properties - Gipsplaat, ThermalConductivity: 0.23; Gipsplaat, SpecificHeatCapacity: 840 J/kg/K; Gipsplaat, MassDensity: 800 kg/m3; Gipsplaat, Embodied Energy: 6.75 (MJ/kg); Gipsplaat, Embodied Carbon: 0.38 (kgCO₂/kg); Gipsplaat, Name: Gipsplaat; Gipsplaat, Participates in Collision Detection: yes
Gipsplaat | Begane grond | Gipsplaat | 93.8909 | 3470 | 12.5 | 0.043375 | 0.117364 | 0.189005 | Component Quantities - Projected Component Area (Net): 9.38909 m2; Projected Component Area (Gross): 15.1204 m2; Component Thickness: 12.5 mm; Material Properties - Gipsplaat, ThermalConductivity: 0.23; Gipsplaat, SpecificHeatCapacity: 840 J/kg/K; Gipsplaat, MassDensity: 800 kg/m3; Gipsplaat, Embodied Energy: 6.75 (MJ/kg); Gipsplaat, Embodied Carbon: 0.38 (kgCO₂/kg); Gipsplaat, Name: Gipsplaat; Gipsplaat, Participates in Collision Detection: yes
Gipsplaat | Begane grond | Gipsplaat | 93.4571 | 3470 | 12.5 | 0.043375 | 0.116821 | 0.188463 | Component Quantities - Projected Component Area (Net): 9.34571 m2; Projected Component Area (Gross): 15.077 m2; Component Thickness: 12.5 mm; Material Properties - Gipsplaat, ThermalConductivity: 0.23; Gipsplaat, SpecificHeatCapacity: 840 J/kg/K; Gipsplaat, MassDensity: 800 kg/m3; Gipsplaat, Embodied Energy: 6.75 (MJ/kg); Gipsplaat, Embodied Carbon: 0.38 (kgCO₂/kg); Gipsplaat, Name: Gipsplaat; Gipsplaat, Participates in Collision Detection: yes
Isolatie - Steenwol LSW | Begane grond | Isolatie - Steenwol LSW | 25.2236 | 3470 | 50 | 0.1735 | 0.458611 | 0.745176 | Component Quantities - Projected Component Area (Net): 9.17221 m2; Projected Component Area (Gross): 14.9035 m2; Component Thickness: 50 mm; Material Properties - Isolatie - Steenwol LSW, ThermalConductivity: 0.039; Isolatie - Steenwol LSW, SpecificHeatCapacity: 840 J/kg/K; Isolatie - Steenwol LSW, MassDensity: 55 kg/m3; Isolatie - Steenwol LSW, Embodied Energy: 16.8 (MJ/kg); Isolatie - Steenwol LSW, Embodied Carbon: 1.05 (kgCO₂/kg); Isolatie - Steenwol LSW, Name: Isolatie - Steenwol LSW; Isolatie - Steenwol LSW, Participates in Collision Detection: yes
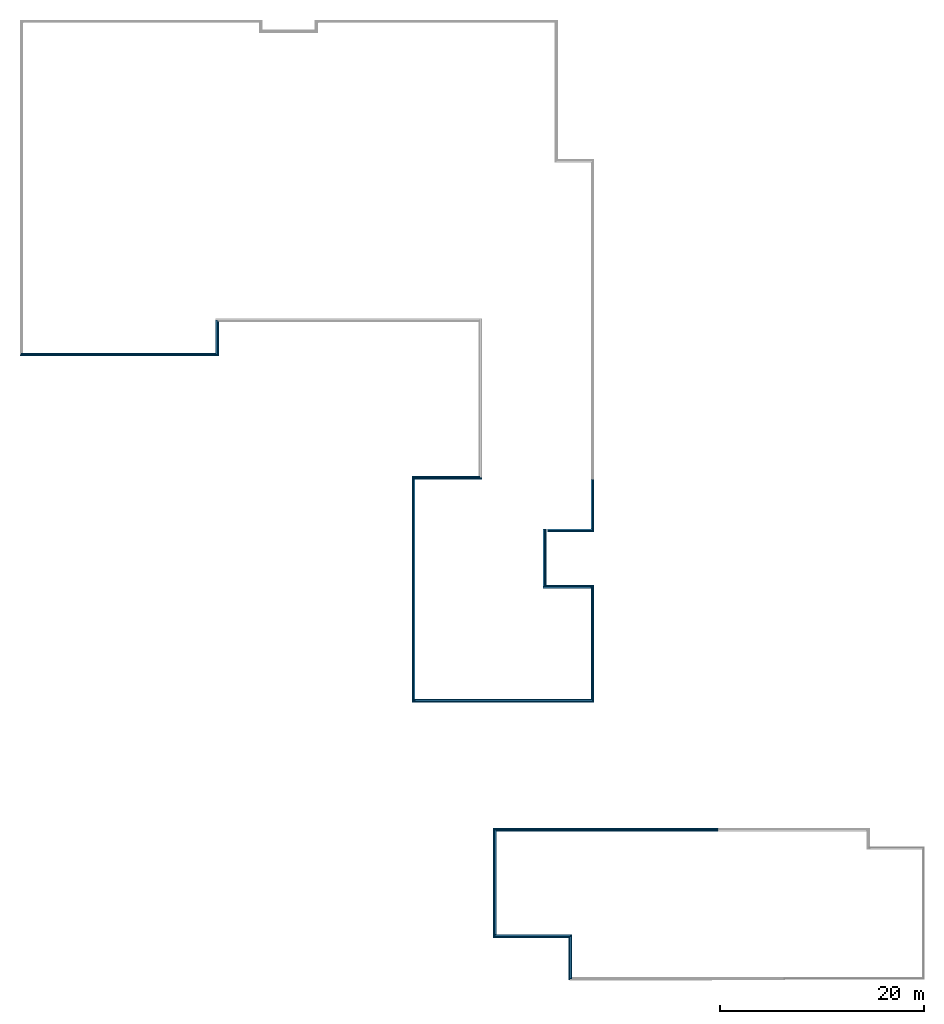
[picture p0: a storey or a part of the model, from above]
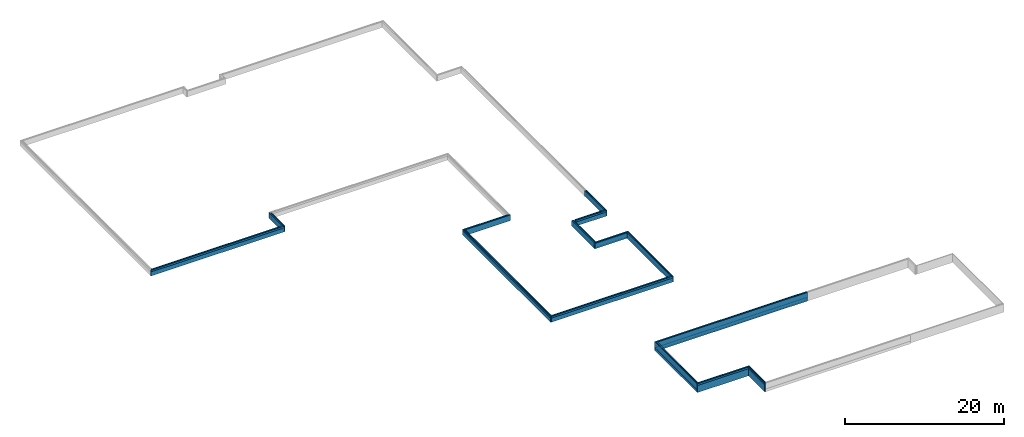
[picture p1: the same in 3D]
Properties of the parts of a building model (IFC2X3), part 5 of 19

# IfcBuildingElementPart (2070)
Name | In | Material | Mass (kg) | Rectangular Component Height (mm) | Rectangular Component Width (mm) | Component Cross Section Area (m2) | Component Volume (Net) (m3) | Component Volume (Gross) (m3)
Gipsplaat | Begane grond | Gipsplaat | 89.5534 | 3470 | 12.5 | 0.043375 | 0.111942 | 0.183583 | Component Quantities - Projected Component Area (Net): 8.95534 m2; Projected Component Area (Gross): 14.6866 m2; Component Thickness: 12.5 mm; Material Properties - Gipsplaat, ThermalConductivity: 0.23; Gipsplaat, SpecificHeatCapacity: 840 J/kg/K; Gipsplaat, MassDensity: 800 kg/m3; Gipsplaat, Embodied Energy: 6.75 (MJ/kg); Gipsplaat, Embodied Carbon: 0.38 (kgCO₂/kg); Gipsplaat, Name: Gipsplaat; Gipsplaat, Participates in Collision Detection: yes
Gipsplaat | Begane grond | Gipsplaat | 88.2521 | 3470 | 12.5 | 0.043375 | 0.110315 | 0.181956 | Component Quantities - Projected Component Area (Net): 8.82521 m2; Projected Component Area (Gross): 14.5565 m2; Component Thickness: 12.5 mm; Material Properties - Gipsplaat, ThermalConductivity: 0.23; Gipsplaat, SpecificHeatCapacity: 840 J/kg/K; Gipsplaat, MassDensity: 800 kg/m3; Gipsplaat, Embodied Energy: 6.75 (MJ/kg); Gipsplaat, Embodied Carbon: 0.38 (kgCO₂/kg); Gipsplaat, Name: Gipsplaat; Gipsplaat, Participates in Collision Detection: yes
Steen - Betonblok C | Begane grond | Steen - Betonblok C | 7317.62 | 4065 | 150 | 0.60975 | 4.57351 | 6.20421 | Component Quantities - Projected Component Area (Net): 32.4583 m2; Projected Component Area (Gross): 41.3614 m2; Component Thickness: 150 mm; Material Properties - Steen - Betonblok C, ThermalConductivity: 0.75; Steen - Betonblok C, SpecificHeatCapacity: 840 J/kg/K; Steen - Betonblok C, MassDensity: 1600 kg/m3; Steen - Betonblok C, Embodied Energy: 0.83 (MJ/kg); Steen - Betonblok C, Embodied Carbon: 0.1 (kgCO₂/kg); Steen - Betonblok C, Name: Steen - Betonblok C; Steen - Betonblok C, Participates in Collision Detection: yes
ALG - ISOLATIE | Begane grond | ALG - ISOLATIE | 287.166 | 4065 | 150 | 0.60975 | 6.38146 | 6.38713 | Component Quantities - Projected Component Area (Net): 42.5437 m2; Projected Component Area (Gross): 42.5809 m2; Component Thickness: 150 mm; Material Properties - ALG - ISOLATIE, ThermalConductivity: 0.035; ALG - ISOLATIE, SpecificHeatCapacity: 840 J/kg/K; ALG - ISOLATIE, MassDensity: 45 kg/m3; ALG - ISOLATIE, Embodied Energy: 16.8 (MJ/kg); ALG - ISOLATIE, Embodied Carbon: 1.05 (kgCO₂/kg); ALG - ISOLATIE, Name: ALG - ISOLATIE; ALG - ISOLATIE, Participates in Collision Detection: yes
Steen - Baksteen AFW | Begane grond | Steen - Baksteen AFW | 4599.51 | 4065 | 100 | 0.4065 | 2.87469 | 4.3524 | Component Quantities - Projected Component Area (Net): 28.7469 m2; Projected Component Area (Gross): 43.524 m2; Component Thickness: 100 mm; Material Properties - Steen - Baksteen AFW, ThermalConductivity: 0.9; Steen - Baksteen AFW, SpecificHeatCapacity: 840 J/kg/K; Steen - Baksteen AFW, MassDensity: 1600 kg/m3; Steen - Baksteen AFW, Embodied Energy: 3 (MJ/kg); Steen - Baksteen AFW, Embodied Carbon: 0.23 (kgCO₂/kg); Steen - Baksteen AFW, Name: Steen - Baksteen AFW; Steen - Baksteen AFW, Participates in Collision Detection: yes
Membraan - waterdicht | Begane grond | Membraan - waterdicht | 55.6513 | 4630 | 5 | 0.02315 | 0.0530012 | 0.126693 | Component Quantities - Projected Component Area (Net): 10.6002 m2; Projected Component Area (Gross): 25.3385 m2; Component Thickness: 5 mm; Material Properties - Membraan - waterdicht, ThermalConductivity: 0.2; Membraan - waterdicht, SpecificHeatCapacity: 1840 J/kg/K; Membraan - waterdicht, MassDensity: 1050 kg/m3; Membraan - waterdicht, Embodied Energy: 51 (MJ/kg); Membraan - waterdicht, Embodied Carbon: 0.38 (kgCO₂/kg); Membraan - waterdicht, Name: Membraan - waterdicht; Membraan - waterdicht, Participates in Collision Detection: yes
Isolatie - Steenwol hard | Begane grond | Isolatie - Steenwol hard | 357.791 | 4630 | 196 | 0.90748 | 2.23619 | 5.03293 | Component Quantities - Projected Component Area (Net): 12.0589 m2; Projected Component Area (Gross): 25.6945 m2; Component Thickness: 196 mm; Material Properties - Isolatie - Steenwol hard, ThermalConductivity: 0.043; Isolatie - Steenwol hard, SpecificHeatCapacity: 840 J/kg/K; Isolatie - Steenwol hard, MassDensity: 160 kg/m3; Isolatie - Steenwol hard, Embodied Energy: 16.8 (MJ/kg); Isolatie - Steenwol hard, Embodied Carbon: 1.05 (kgCO₂/kg); Isolatie - Steenwol hard, Name: Isolatie - Steenwol hard; Isolatie - Steenwol hard, Participates in Collision Detection: yes
Metaal - Staal AFW | Begane grond | Metaal - Staal AFW | 361.316 | 4630 | 4 | 0.01852 | 0.0454486 | 0.0987486 | Component Quantities - Projected Component Area (Net): 11.3621 m2; Projected Component Area (Gross): 24.6871 m2; Component Thickness: 4 mm; Material Properties - Metaal - Staal AFW, ThermalConductivity: 52; Metaal - Staal AFW, SpecificHeatCapacity: 530 J/kg/K; Metaal - Staal AFW, MassDensity: 7950 kg/m3; Metaal - Staal AFW, Embodied Energy: 25 (MJ/kg); Metaal - Staal AFW, Embodied Carbon: 1.91 (kgCO₂/kg); Metaal - Staal AFW, Name: Metaal - Staal AFW; Metaal - Staal AFW, Participates in Collision Detection: yes
Metaal - Staal AFW | Begane grond | Metaal - Staal AFW | 738.468 | 4255 | 4 | 0.01702 | 0.0928891 | 0.0928891 | Component Quantities - Projected Component Area (Net): 23.2249 m2; Projected Component Area (Gross): 23.2249 m2; Component Thickness: 4 mm; Material Properties - Metaal - Staal AFW, ThermalConductivity: 52; Metaal - Staal AFW, SpecificHeatCapacity: 530 J/kg/K; Metaal - Staal AFW, MassDensity: 7950 kg/m3; Metaal - Staal AFW, Embodied Energy: 25 (MJ/kg); Metaal - Staal AFW, Embodied Carbon: 1.91 (kgCO₂/kg); Metaal - Staal AFW, Name: Metaal - Staal AFW; Metaal - Staal AFW, Participates in Collision Detection: yes
Isolatie - Glaswol hard | Begane grond | Isolatie - Glaswol hard | 291.333 | 4255 | 196 | 0.83398 | 4.55208 | 4.55208 | Component Quantities - Projected Component Area (Net): 23.2249 m2; Projected Component Area (Gross): 23.2249 m2; Component Thickness: 196 mm; Material Properties - Isolatie - Glaswol hard, ThermalConductivity: 0.033; Isolatie - Glaswol hard, SpecificHeatCapacity: 1030 J/kg/K; Isolatie - Glaswol hard, MassDensity: 64 kg/m3; Isolatie - Glaswol hard, Embodied Energy: 37 (MJ/kg); Isolatie - Glaswol hard, Embodied Carbon: 1.48 (kgCO₂/kg); Isolatie - Glaswol hard, Name: Isolatie - Glaswol hard; Isolatie - Glaswol hard, Participates in Collision Detection: yes
Steen - Baksteen AFW | Begane grond | Steen - Baksteen AFW | 3561.38 | 4255 | 100 | 0.4255 | 2.22586 | 2.22586 | Component Quantities - Projected Component Area (Net): 22.2586 m2; Projected Component Area (Gross): 22.2586 m2; Component Thickness: 100 mm; Material Properties - Steen - Baksteen AFW, ThermalConductivity: 0.9; Steen - Baksteen AFW, SpecificHeatCapacity: 840 J/kg/K; Steen - Baksteen AFW, MassDensity: 1600 kg/m3; Steen - Baksteen AFW, Embodied Energy: 3 (MJ/kg); Steen - Baksteen AFW, Embodied Carbon: 0.23 (kgCO₂/kg); Steen - Baksteen AFW, Name: Steen - Baksteen AFW; Steen - Baksteen AFW, Participates in Collision Detection: yes
Steen - Betonblok C | Begane grond | Steen - Betonblok C | 4444.92 | 4065 | 150 | 0.60975 | 2.77808 | 4.51215 | Component Quantities - Projected Component Area (Net): 18.5205 m2; Projected Component Area (Gross): 30.081 m2; Component Thickness: 150 mm; Material Properties - Steen - Betonblok C, ThermalConductivity: 0.75; Steen - Betonblok C, SpecificHeatCapacity: 840 J/kg/K; Steen - Betonblok C, MassDensity: 1600 kg/m3; Steen - Betonblok C, Embodied Energy: 0.83 (MJ/kg); Steen - Betonblok C, Embodied Carbon: 0.1 (kgCO₂/kg); Steen - Betonblok C, Name: Steen - Betonblok C; Steen - Betonblok C, Participates in Collision Detection: yes
ALG - ISOLATIE | Begane grond | ALG - ISOLATIE | 169.135 | 4065 | 150 | 0.60975 | 3.75855 | 4.51215 | Component Quantities - Projected Component Area (Net): 25.5135 m2; Projected Component Area (Gross): 30.081 m2; Component Thickness: 150 mm; Material Properties - ALG - ISOLATIE, ThermalConductivity: 0.035; ALG - ISOLATIE, SpecificHeatCapacity: 840 J/kg/K; ALG - ISOLATIE, MassDensity: 45 kg/m3; ALG - ISOLATIE, Embodied Energy: 16.8 (MJ/kg); ALG - ISOLATIE, Embodied Carbon: 1.05 (kgCO₂/kg); ALG - ISOLATIE, Name: ALG - ISOLATIE; ALG - ISOLATIE, Participates in Collision Detection: yes
Isolatie - Steenwol hard | Begane grond | Isolatie - Steenwol hard | 113.086 | 4065 | 30 | 0.12195 | 0.706788 | 0.90682 | Component Quantities - Projected Component Area (Net): 23.5666 m2; Projected Component Area (Gross): 30.2273 m2; Component Thickness: 30 mm; Material Properties - Isolatie - Steenwol hard, ThermalConductivity: 0.043; Isolatie - Steenwol hard, SpecificHeatCapacity: 840 J/kg/K; Isolatie - Steenwol hard, MassDensity: 160 kg/m3; Isolatie - Steenwol hard, Embodied Energy: 16.8 (MJ/kg); Isolatie - Steenwol hard, Embodied Carbon: 1.05 (kgCO₂/kg); Isolatie - Steenwol hard, Name: Isolatie - Steenwol hard; Isolatie - Steenwol hard, Participates in Collision Detection: yes
Membraan - dampopen | Begane grond | Membraan - dampopen | 42.6553 | 4065 | 2 | 0.00813 | 0.046874 | 0.0602108 | Component Quantities - Projected Component Area (Net): 23.437 m2; Projected Component Area (Gross): 30.1054 m2; Component Thickness: 2 mm; Material Properties - Membraan - dampopen, ThermalConductivity: 0.22; Membraan - dampopen, SpecificHeatCapacity: 1800 J/kg/K; Membraan - dampopen, MassDensity: 910 kg/m3; Membraan - dampopen, Embodied Energy: 99.2 (MJ/kg); Membraan - dampopen, Embodied Carbon: 3.43 (kgCO₂/kg); Membraan - dampopen, Name: Membraan - dampopen; Membraan - dampopen, Participates in Collision Detection: yes
Gipsplaat | Begane grond | Gipsplaat | 278.771 | 3470 | 12.5 | 0.043375 | 0.348464 | 0.348464 | Component Quantities - Projected Component Area (Net): 27.8771 m2; Projected Component Area (Gross): 27.8771 m2; Component Thickness: 12.5 mm; Material Properties - Gipsplaat, ThermalConductivity: 0.23; Gipsplaat, SpecificHeatCapacity: 840 J/kg/K; Gipsplaat, MassDensity: 800 kg/m3; Gipsplaat, Embodied Energy: 6.75 (MJ/kg); Gipsplaat, Embodied Carbon: 0.38 (kgCO₂/kg); Gipsplaat, Name: Gipsplaat; Gipsplaat, Participates in Collision Detection: yes
Gipsplaat | Begane grond | Gipsplaat | 279.639 | 3470 | 12.5 | 0.043375 | 0.349549 | 0.349549 | Component Quantities - Projected Component Area (Net): 27.9639 m2; Projected Component Area (Gross): 27.9639 m2; Component Thickness: 12.5 mm; Material Properties - Gipsplaat, ThermalConductivity: 0.23; Gipsplaat, SpecificHeatCapacity: 840 J/kg/K; Gipsplaat, MassDensity: 800 kg/m3; Gipsplaat, Embodied Energy: 6.75 (MJ/kg); Gipsplaat, Embodied Carbon: 0.38 (kgCO₂/kg); Gipsplaat, Name: Gipsplaat; Gipsplaat, Participates in Collision Detection: yes
Isolatie - Steenwol LSW | Begane grond | Isolatie - Steenwol LSW | 77.1393 | 3470 | 50 | 0.1735 | 1.40253 | 1.40253 | Component Quantities - Projected Component Area (Net): 28.0506 m2; Projected Component Area (Gross): 28.0506 m2; Component Thickness: 50 mm; Material Properties - Isolatie - Steenwol LSW, ThermalConductivity: 0.039; Isolatie - Steenwol LSW, SpecificHeatCapacity: 840 J/kg/K; Isolatie - Steenwol LSW, MassDensity: 55 kg/m3; Isolatie - Steenwol LSW, Embodied Energy: 16.8 (MJ/kg); Isolatie - Steenwol LSW, Embodied Carbon: 1.05 (kgCO₂/kg); Isolatie - Steenwol LSW, Name: Isolatie - Steenwol LSW; Isolatie - Steenwol LSW, Participates in Collision Detection: yes
Gipsplaat | Begane grond | Gipsplaat | 503.366 | 3470 | 12.5 | 0.043375 | 0.629208 | 0.922511 | Component Quantities - Projected Component Area (Net): 50.3366 m2; Projected Component Area (Gross): 73.8008 m2; Component Thickness: 12.5 mm; Material Properties - Gipsplaat, ThermalConductivity: 0.23; Gipsplaat, SpecificHeatCapacity: 840 J/kg/K; Gipsplaat, MassDensity: 800 kg/m3; Gipsplaat, Embodied Energy: 6.75 (MJ/kg); Gipsplaat, Embodied Carbon: 0.38 (kgCO₂/kg); Gipsplaat, Name: Gipsplaat; Gipsplaat, Participates in Collision Detection: yes
2 x Gipsplaat | Begane grond | Gipsplaat | 505.081 | 3470 | 12.5 | 0.043375 | 0.631352 | 0.924654 | Component Quantities - Projected Component Area (Net): 50.5081 m2; Projected Component Area (Gross): 73.9723 m2; Component Thickness: 12.5 mm; Material Properties - Gipsplaat, ThermalConductivity: 0.23; Gipsplaat, SpecificHeatCapacity: 840 J/kg/K; Gipsplaat, MassDensity: 800 kg/m3; Gipsplaat, Embodied Energy: 6.75 (MJ/kg); Gipsplaat, Embodied Carbon: 0.38 (kgCO₂/kg); Gipsplaat, Name: Gipsplaat; Gipsplaat, Participates in Collision Detection: yes
Isolatie - Steenwol LSW | Begane grond | Isolatie - Steenwol LSW | 140.773 | 3470 | 50 | 0.1735 | 2.55951 | 3.73272 | Component Quantities - Projected Component Area (Net): 51.1901 m2; Projected Component Area (Gross): 74.6543 m2; Component Thickness: 50 mm; Material Properties - Isolatie - Steenwol LSW, ThermalConductivity: 0.039; Isolatie - Steenwol LSW, SpecificHeatCapacity: 840 J/kg/K; Isolatie - Steenwol LSW, MassDensity: 55 kg/m3; Isolatie - Steenwol LSW, Embodied Energy: 16.8 (MJ/kg); Isolatie - Steenwol LSW, Embodied Carbon: 1.05 (kgCO₂/kg); Isolatie - Steenwol LSW, Name: Isolatie - Steenwol LSW; Isolatie - Steenwol LSW, Participates in Collision Detection: yes
Gipsplaat | Begane grond | Gipsplaat | 503.199 | 3470 | 12.5 | 0.043375 | 0.628999 | 0.922301 | Component Quantities - Projected Component Area (Net): 50.3366 m2; Projected Component Area (Gross): 73.8008 m2; Component Thickness: 12.5 mm; Material Properties - Gipsplaat, ThermalConductivity: 0.23; Gipsplaat, SpecificHeatCapacity: 840 J/kg/K; Gipsplaat, MassDensity: 800 kg/m3; Gipsplaat, Embodied Energy: 6.75 (MJ/kg); Gipsplaat, Embodied Carbon: 0.38 (kgCO₂/kg); Gipsplaat, Name: Gipsplaat; Gipsplaat, Participates in Collision Detection: yes
2 x Gipsplaat | Begane grond | Gipsplaat | 63.2407 | 3470 | 12.5 | 0.043375 | 0.0790509 | 0.0790509 | Component Quantities - Projected Component Area (Net): 6.32407 m2; Projected Component Area (Gross): 6.32407 m2; Component Thickness: 12.5 mm; Material Properties - Gipsplaat, ThermalConductivity: 0.23; Gipsplaat, SpecificHeatCapacity: 840 J/kg/K; Gipsplaat, MassDensity: 800 kg/m3; Gipsplaat, Embodied Energy: 6.75 (MJ/kg); Gipsplaat, Embodied Carbon: 0.38 (kgCO₂/kg); Gipsplaat, Name: Gipsplaat; Gipsplaat, Participates in Collision Detection: yes
2 x Gipsplaat | Begane grond | Gipsplaat | 64.1082 | 3470 | 12.5 | 0.043375 | 0.0801353 | 0.0801353 | Component Quantities - Projected Component Area (Net): 6.41082 m2; Projected Component Area (Gross): 6.41082 m2; Component Thickness: 12.5 mm; Material Properties - Gipsplaat, ThermalConductivity: 0.23; Gipsplaat, SpecificHeatCapacity: 840 J/kg/K; Gipsplaat, MassDensity: 800 kg/m3; Gipsplaat, Embodied Energy: 6.75 (MJ/kg); Gipsplaat, Embodied Carbon: 0.38 (kgCO₂/kg); Gipsplaat, Name: Gipsplaat; Gipsplaat, Participates in Collision Detection: yes
Isolatie - Steenwol LSW | Begane grond | Isolatie - Steenwol LSW | 17.9401 | 3470 | 50 | 0.1735 | 0.326183 | 0.326183 | Component Quantities - Projected Component Area (Net): 6.52366 m2; Projected Component Area (Gross): 6.52366 m2; Component Thickness: 50 mm; Material Properties - Isolatie - Steenwol LSW, ThermalConductivity: 0.039; Isolatie - Steenwol LSW, SpecificHeatCapacity: 840 J/kg/K; Isolatie - Steenwol LSW, MassDensity: 55 kg/m3; Isolatie - Steenwol LSW, Embodied Energy: 16.8 (MJ/kg); Isolatie - Steenwol LSW, Embodied Carbon: 1.05 (kgCO₂/kg); Isolatie - Steenwol LSW, Name: Isolatie - Steenwol LSW; Isolatie - Steenwol LSW, Participates in Collision Detection: yes
Steen - Kalkzandsteen C | Begane grond | Steen - Kalkzandsteen C | 13157 | 4235 | 150 | 0.63525 | 6.92473 | 14.5892 | Component Quantities - Projected Component Area (Net): 46.1652 m2; Projected Component Area (Gross): 97.261 m2; Component Thickness: 150 mm; Material Properties - Steen - Kalkzandsteen C, ThermalConductivity: 0.9; Steen - Kalkzandsteen C, SpecificHeatCapacity: 840 J/kg/K; Steen - Kalkzandsteen C, MassDensity: 1900 kg/m3; Steen - Kalkzandsteen C, Embodied Energy: 0.75 (MJ/kg); Steen - Kalkzandsteen C, Embodied Carbon: 0.1 (kgCO₂/kg); Steen - Kalkzandsteen C, Name: Steen - Kalkzandsteen C; Steen - Kalkzandsteen C, Participates in Collision Detection: yes
ALG - ISOLATIE | Begane grond | ALG - ISOLATIE | 433.647 | 4235 | 150 | 0.63525 | 9.6366 | 14.8204 | Component Quantities - Projected Component Area (Net): 65.2757 m2; Projected Component Area (Gross): 98.8025 m2; Component Thickness: 150 mm; Material Properties - ALG - ISOLATIE, ThermalConductivity: 0.035; ALG - ISOLATIE, SpecificHeatCapacity: 840 J/kg/K; ALG - ISOLATIE, MassDensity: 45 kg/m3; ALG - ISOLATIE, Embodied Energy: 16.8 (MJ/kg); ALG - ISOLATIE, Embodied Carbon: 1.05 (kgCO₂/kg); ALG - ISOLATIE, Name: ALG - ISOLATIE; ALG - ISOLATIE, Participates in Collision Detection: yes
Steen - Baksteen AFW | Begane grond | Steen - Baksteen AFW | 5190.32 | 4235 | 100 | 0.4235 | 3.24395 | 10.0395 | Component Quantities - Projected Component Area (Net): 32.5116 m2; Projected Component Area (Gross): 100.395 m2; Component Thickness: 100 mm; Material Properties - Steen - Baksteen AFW, ThermalConductivity: 0.9; Steen - Baksteen AFW, SpecificHeatCapacity: 840 J/kg/K; Steen - Baksteen AFW, MassDensity: 1600 kg/m3; Steen - Baksteen AFW, Embodied Energy: 3 (MJ/kg); Steen - Baksteen AFW, Embodied Carbon: 0.23 (kgCO₂/kg); Steen - Baksteen AFW, Name: Steen - Baksteen AFW; Steen - Baksteen AFW, Participates in Collision Detection: yes
Gipsplaat | Begane grond | Gipsplaat | 45.0343 | 3400 | 12.5 | 0.0425 | 0.0562929 | 0.178411 | Component Quantities - Projected Component Area (Net): 4.50343 m2; Projected Component Area (Gross): 14.2729 m2; Component Thickness: 12.5 mm; Material Properties - Gipsplaat, ThermalConductivity: 0.23; Gipsplaat, SpecificHeatCapacity: 840 J/kg/K; Gipsplaat, MassDensity: 800 kg/m3; Gipsplaat, Embodied Energy: 6.75 (MJ/kg); Gipsplaat, Embodied Carbon: 0.38 (kgCO₂/kg); Gipsplaat, Name: Gipsplaat; Gipsplaat, Participates in Collision Detection: yes
Gipsplaat | Begane grond | Gipsplaat | 45.4493 | 3400 | 12.5 | 0.0425 | 0.0568116 | 0.17893 | Component Quantities - Projected Component Area (Net): 4.54493 m2; Projected Component Area (Gross): 14.3144 m2; Component Thickness: 12.5 mm; Material Properties - Gipsplaat, ThermalConductivity: 0.23; Gipsplaat, SpecificHeatCapacity: 840 J/kg/K; Gipsplaat, MassDensity: 800 kg/m3; Gipsplaat, Embodied Energy: 6.75 (MJ/kg); Gipsplaat, Embodied Carbon: 0.38 (kgCO₂/kg); Gipsplaat, Name: Gipsplaat; Gipsplaat, Participates in Collision Detection: yes
Isolatie - Steenwol LSW | Begane grond | Isolatie - Steenwol LSW | 17.0844 | 3400 | 50 | 0.17 | 0.310626 | 0.799099 | Component Quantities - Projected Component Area (Net): 6.21251 m2; Projected Component Area (Gross): 15.982 m2; Component Thickness: 50 mm; Material Properties - Isolatie - Steenwol LSW, ThermalConductivity: 0.039; Isolatie - Steenwol LSW, SpecificHeatCapacity: 840 J/kg/K; Isolatie - Steenwol LSW, MassDensity: 55 kg/m3; Isolatie - Steenwol LSW, Embodied Energy: 16.8 (MJ/kg); Isolatie - Steenwol LSW, Embodied Carbon: 1.05 (kgCO₂/kg); Isolatie - Steenwol LSW, Name: Isolatie - Steenwol LSW; Isolatie - Steenwol LSW, Participates in Collision Detection: yes
Gipsplaat | Begane grond | Gipsplaat | 55.3651 | 3400 | 12.5 | 0.0425 | 0.0692064 | 0.191325 | Component Quantities - Projected Component Area (Net): 5.53651 m2; Projected Component Area (Gross): 15.306 m2; Component Thickness: 12.5 mm; Material Properties - Gipsplaat, ThermalConductivity: 0.23; Gipsplaat, SpecificHeatCapacity: 840 J/kg/K; Gipsplaat, MassDensity: 800 kg/m3; Gipsplaat, Embodied Energy: 6.75 (MJ/kg); Gipsplaat, Embodied Carbon: 0.38 (kgCO₂/kg); Gipsplaat, Name: Gipsplaat; Gipsplaat, Participates in Collision Detection: yes
Gipsplaat | Begane grond | Gipsplaat | 52.4001 | 3400 | 12.5 | 0.0425 | 0.0655002 | 0.187619 | Component Quantities - Projected Component Area (Net): 5.24001 m2; Projected Component Area (Gross): 15.0095 m2; Component Thickness: 12.5 mm; Material Properties - Gipsplaat, ThermalConductivity: 0.23; Gipsplaat, SpecificHeatCapacity: 840 J/kg/K; Gipsplaat, MassDensity: 800 kg/m3; Gipsplaat, Embodied Energy: 6.75 (MJ/kg); Gipsplaat, Embodied Carbon: 0.38 (kgCO₂/kg); Gipsplaat, Name: Gipsplaat; Gipsplaat, Participates in Collision Detection: yes
Gipsplaat | Begane grond | Gipsplaat | 11.1218 | 3400 | 12.5 | 0.0425 | 0.0139022 | 0.044625 | Component Quantities - Projected Component Area (Net): 1.11218 m2; Projected Component Area (Gross): 3.57 m2; Component Thickness: 12.5 mm; Material Properties - Gipsplaat, ThermalConductivity: 0.23; Gipsplaat, SpecificHeatCapacity: 840 J/kg/K; Gipsplaat, MassDensity: 800 kg/m3; Gipsplaat, Embodied Energy: 6.75 (MJ/kg); Gipsplaat, Embodied Carbon: 0.38 (kgCO₂/kg); Gipsplaat, Name: Gipsplaat; Gipsplaat, Participates in Collision Detection: yes
Gipsplaat | Begane grond | Gipsplaat | 11.5468 | 3400 | 12.5 | 0.0425 | 0.0144335 | 0.0451562 | Component Quantities - Projected Component Area (Net): 1.15468 m2; Projected Component Area (Gross): 3.6125 m2; Component Thickness: 12.5 mm; Material Properties - Gipsplaat, ThermalConductivity: 0.23; Gipsplaat, SpecificHeatCapacity: 840 J/kg/K; Gipsplaat, MassDensity: 800 kg/m3; Gipsplaat, Embodied Energy: 6.75 (MJ/kg); Gipsplaat, Embodied Carbon: 0.38 (kgCO₂/kg); Gipsplaat, Name: Gipsplaat; Gipsplaat, Participates in Collision Detection: yes
Isolatie - Steenwol LSW | Begane grond | Isolatie - Steenwol LSW | 3.29224 | 3400 | 50 | 0.17 | 0.0598589 | 0.18275 | Component Quantities - Projected Component Area (Net): 1.19718 m2; Projected Component Area (Gross): 3.655 m2; Component Thickness: 50 mm; Material Properties - Isolatie - Steenwol LSW, ThermalConductivity: 0.039; Isolatie - Steenwol LSW, SpecificHeatCapacity: 840 J/kg/K; Isolatie - Steenwol LSW, MassDensity: 55 kg/m3; Isolatie - Steenwol LSW, Embodied Energy: 16.8 (MJ/kg); Isolatie - Steenwol LSW, Embodied Carbon: 1.05 (kgCO₂/kg); Isolatie - Steenwol LSW, Name: Isolatie - Steenwol LSW; Isolatie - Steenwol LSW, Participates in Collision Detection: yes
Gipsplaat | Begane grond | Gipsplaat | 13.6718 | 3400 | 12.5 | 0.0425 | 0.0170897 | 0.0478125 | Component Quantities - Projected Component Area (Net): 1.36718 m2; Projected Component Area (Gross): 3.825 m2; Component Thickness: 12.5 mm; Material Properties - Gipsplaat, ThermalConductivity: 0.23; Gipsplaat, SpecificHeatCapacity: 840 J/kg/K; Gipsplaat, MassDensity: 800 kg/m3; Gipsplaat, Embodied Energy: 6.75 (MJ/kg); Gipsplaat, Embodied Carbon: 0.38 (kgCO₂/kg); Gipsplaat, Name: Gipsplaat; Gipsplaat, Participates in Collision Detection: yes
Gipsplaat | Begane grond | Gipsplaat | 14.0968 | 3400 | 12.5 | 0.0425 | 0.017621 | 0.0483437 | Component Quantities - Projected Component Area (Net): 1.40968 m2; Projected Component Area (Gross): 3.8675 m2; Component Thickness: 12.5 mm; Material Properties - Gipsplaat, ThermalConductivity: 0.23; Gipsplaat, SpecificHeatCapacity: 840 J/kg/K; Gipsplaat, MassDensity: 800 kg/m3; Gipsplaat, Embodied Energy: 6.75 (MJ/kg); Gipsplaat, Embodied Carbon: 0.38 (kgCO₂/kg); Gipsplaat, Name: Gipsplaat; Gipsplaat, Participates in Collision Detection: yes
2 x Isolatie - Steenwol LSW | Begane grond | Isolatie - Steenwol LSW | 12.5081 | 3350 | 50 | 0.1675 | 0.22742 | 0.22742 | Component Quantities - Projected Component Area (Net): 4.5484 m2; Projected Component Area (Gross): 4.5484 m2; Component Thickness: 50 mm; Material Properties - Isolatie - Steenwol LSW, ThermalConductivity: 0.039; Isolatie - Steenwol LSW, SpecificHeatCapacity: 840 J/kg/K; Isolatie - Steenwol LSW, MassDensity: 55 kg/m3; Isolatie - Steenwol LSW, Embodied Energy: 16.8 (MJ/kg); Isolatie - Steenwol LSW, Embodied Carbon: 1.05 (kgCO₂/kg); Isolatie - Steenwol LSW, Name: Isolatie - Steenwol LSW; Isolatie - Steenwol LSW, Participates in Collision Detection: yes
2 x Gipsplaat | Begane grond | Gipsplaat | 42.994 | 3350 | 12.5 | 0.041875 | 0.0537425 | 0.0537425 | Component Quantities - Projected Component Area (Net): 4.2994 m2; Projected Component Area (Gross): 4.2994 m2; Component Thickness: 12.5 mm; Material Properties - Gipsplaat, ThermalConductivity: 0.23; Gipsplaat, SpecificHeatCapacity: 840 J/kg/K; Gipsplaat, MassDensity: 800 kg/m3; Gipsplaat, Embodied Energy: 6.75 (MJ/kg); Gipsplaat, Embodied Carbon: 0.38 (kgCO₂/kg); Gipsplaat, Name: Gipsplaat; Gipsplaat, Participates in Collision Detection: yes
2 x Gipsplaat | Begane grond | Gipsplaat | 41.749 | 3350 | 12.5 | 0.041875 | 0.0521863 | 0.0521863 | Component Quantities - Projected Component Area (Net): 4.1749 m2; Projected Component Area (Gross): 4.1749 m2; Component Thickness: 12.5 mm; Material Properties - Gipsplaat, ThermalConductivity: 0.23; Gipsplaat, SpecificHeatCapacity: 840 J/kg/K; Gipsplaat, MassDensity: 800 kg/m3; Gipsplaat, Embodied Energy: 6.75 (MJ/kg); Gipsplaat, Embodied Carbon: 0.38 (kgCO₂/kg); Gipsplaat, Name: Gipsplaat; Gipsplaat, Participates in Collision Detection: yes
Membraan - waterdicht | Begane grond | Membraan - waterdicht | 135.492 | 4630 | 5 | 0.02315 | 0.12904 | 0.316952 | Component Quantities - Projected Component Area (Net): 25.8079 m2; Projected Component Area (Gross): 63.3903 m2; Component Thickness: 5 mm; Material Properties - Membraan - waterdicht, ThermalConductivity: 0.2; Membraan - waterdicht, SpecificHeatCapacity: 1840 J/kg/K; Membraan - waterdicht, MassDensity: 1050 kg/m3; Membraan - waterdicht, Embodied Energy: 51 (MJ/kg); Membraan - waterdicht, Embodied Carbon: 0.38 (kgCO₂/kg); Membraan - waterdicht, Name: Membraan - waterdicht; Membraan - waterdicht, Participates in Collision Detection: yes
Isolatie - Steenwol hard | Begane grond | Isolatie - Steenwol hard | 828.315 | 4630 | 196 | 0.90748 | 5.17697 | 12.2466 | Component Quantities - Projected Component Area (Net): 27.7681 m2; Projected Component Area (Gross): 62.4829 m2; Component Thickness: 196 mm; Material Properties - Isolatie - Steenwol hard, ThermalConductivity: 0.043; Isolatie - Steenwol hard, SpecificHeatCapacity: 840 J/kg/K; Isolatie - Steenwol hard, MassDensity: 160 kg/m3; Isolatie - Steenwol hard, Embodied Energy: 16.8 (MJ/kg); Isolatie - Steenwol hard, Embodied Carbon: 1.05 (kgCO₂/kg); Isolatie - Steenwol hard, Name: Isolatie - Steenwol hard; Isolatie - Steenwol hard, Participates in Collision Detection: yes
Metaal - Staal AFW | Begane grond | Metaal - Staal AFW | 882.436 | 4630 | 4 | 0.01852 | 0.110998 | 0.249857 | Component Quantities - Projected Component Area (Net): 27.7495 m2; Projected Component Area (Gross): 62.4643 m2; Component Thickness: 4 mm; Material Properties - Metaal - Staal AFW, ThermalConductivity: 52; Metaal - Staal AFW, SpecificHeatCapacity: 530 J/kg/K; Metaal - Staal AFW, MassDensity: 7950 kg/m3; Metaal - Staal AFW, Embodied Energy: 25 (MJ/kg); Metaal - Staal AFW, Embodied Carbon: 1.91 (kgCO₂/kg); Metaal - Staal AFW, Name: Metaal - Staal AFW; Metaal - Staal AFW, Participates in Collision Detection: yes
Gipsplaat | Begane grond | Gipsplaat | 32.4105 | 3400 | 12.5 | 0.0425 | 0.0405131 | 0.12971 | Component Quantities - Projected Component Area (Net): 3.24105 m2; Projected Component Area (Gross): 10.3768 m2; Component Thickness: 12.5 mm; Material Properties - Gipsplaat, ThermalConductivity: 0.23; Gipsplaat, SpecificHeatCapacity: 840 J/kg/K; Gipsplaat, MassDensity: 800 kg/m3; Gipsplaat, Embodied Energy: 6.75 (MJ/kg); Gipsplaat, Embodied Carbon: 0.38 (kgCO₂/kg); Gipsplaat, Name: Gipsplaat; Gipsplaat, Participates in Collision Detection: yes
Gipsplaat | Begane grond | Gipsplaat | 34.5355 | 3400 | 12.5 | 0.0425 | 0.0431693 | 0.132366 | Component Quantities - Projected Component Area (Net): 3.45355 m2; Projected Component Area (Gross): 10.5893 m2; Component Thickness: 12.5 mm; Material Properties - Gipsplaat, ThermalConductivity: 0.23; Gipsplaat, SpecificHeatCapacity: 840 J/kg/K; Gipsplaat, MassDensity: 800 kg/m3; Gipsplaat, Embodied Energy: 6.75 (MJ/kg); Gipsplaat, Embodied Carbon: 0.38 (kgCO₂/kg); Gipsplaat, Name: Gipsplaat; Gipsplaat, Participates in Collision Detection: yes
Isolatie - Steenwol LSW | Begane grond | Isolatie - Steenwol LSW | 10.5398 | 3400 | 50 | 0.17 | 0.191633 | 0.54842 | Component Quantities - Projected Component Area (Net): 3.83266 m2; Projected Component Area (Gross): 10.9684 m2; Component Thickness: 50 mm; Material Properties - Isolatie - Steenwol LSW, ThermalConductivity: 0.039; Isolatie - Steenwol LSW, SpecificHeatCapacity: 840 J/kg/K; Isolatie - Steenwol LSW, MassDensity: 55 kg/m3; Isolatie - Steenwol LSW, Embodied Energy: 16.8 (MJ/kg); Isolatie - Steenwol LSW, Embodied Carbon: 1.05 (kgCO₂/kg); Isolatie - Steenwol LSW, Name: Isolatie - Steenwol LSW; Isolatie - Steenwol LSW, Participates in Collision Detection: yes
Gipsplaat | Begane grond | Gipsplaat | 34.9545 | 3400 | 12.5 | 0.0425 | 0.0436931 | 0.135861 | Component Quantities - Projected Component Area (Net): 3.49545 m2; Projected Component Area (Gross): 10.8689 m2; Component Thickness: 12.5 mm; Material Properties - Gipsplaat, ThermalConductivity: 0.23; Gipsplaat, SpecificHeatCapacity: 840 J/kg/K; Gipsplaat, MassDensity: 800 kg/m3; Gipsplaat, Embodied Energy: 6.75 (MJ/kg); Gipsplaat, Embodied Carbon: 0.38 (kgCO₂/kg); Gipsplaat, Name: Gipsplaat; Gipsplaat, Participates in Collision Detection: yes
Gipsplaat | Begane grond | Gipsplaat | 34.1145 | 3400 | 12.5 | 0.0425 | 0.0426431 | 0.134811 | Component Quantities - Projected Component Area (Net): 3.41145 m2; Projected Component Area (Gross): 10.7849 m2; Component Thickness: 12.5 mm; Material Properties - Gipsplaat, ThermalConductivity: 0.23; Gipsplaat, SpecificHeatCapacity: 840 J/kg/K; Gipsplaat, MassDensity: 800 kg/m3; Gipsplaat, Embodied Energy: 6.75 (MJ/kg); Gipsplaat, Embodied Carbon: 0.38 (kgCO₂/kg); Gipsplaat, Name: Gipsplaat; Gipsplaat, Participates in Collision Detection: yes
Gipsplaat | Begane grond | Gipsplaat | 37.682 | 3400 | 12.5 | 0.0425 | 0.0471025 | 0.110102 | Component Quantities - Projected Component Area (Net): 3.7682 m2; Projected Component Area (Gross): 8.80819 m2; Component Thickness: 12.5 mm; Material Properties - Gipsplaat, ThermalConductivity: 0.23; Gipsplaat, SpecificHeatCapacity: 840 J/kg/K; Gipsplaat, MassDensity: 800 kg/m3; Gipsplaat, Embodied Energy: 6.75 (MJ/kg); Gipsplaat, Embodied Carbon: 0.38 (kgCO₂/kg); Gipsplaat, Name: Gipsplaat; Gipsplaat, Participates in Collision Detection: yes
Gipsplaat | Begane grond | Gipsplaat | 38.532 | 3400 | 12.5 | 0.0425 | 0.048165 | 0.111165 | Component Quantities - Projected Component Area (Net): 3.8532 m2; Projected Component Area (Gross): 8.89319 m2; Component Thickness: 12.5 mm; Material Properties - Gipsplaat, ThermalConductivity: 0.23; Gipsplaat, SpecificHeatCapacity: 840 J/kg/K; Gipsplaat, MassDensity: 800 kg/m3; Gipsplaat, Embodied Energy: 6.75 (MJ/kg); Gipsplaat, Embodied Carbon: 0.38 (kgCO₂/kg); Gipsplaat, Name: Gipsplaat; Gipsplaat, Participates in Collision Detection: yes
Isolatie - Steenwol LSW | Begane grond | Isolatie - Steenwol LSW | 10.8301 | 3400 | 50 | 0.17 | 0.19691 | 0.44891 | Component Quantities - Projected Component Area (Net): 3.9382 m2; Projected Component Area (Gross): 8.97819 m2; Component Thickness: 50 mm; Material Properties - Isolatie - Steenwol LSW, ThermalConductivity: 0.039; Isolatie - Steenwol LSW, SpecificHeatCapacity: 840 J/kg/K; Isolatie - Steenwol LSW, MassDensity: 55 kg/m3; Isolatie - Steenwol LSW, Embodied Energy: 16.8 (MJ/kg); Isolatie - Steenwol LSW, Embodied Carbon: 1.05 (kgCO₂/kg); Isolatie - Steenwol LSW, Name: Isolatie - Steenwol LSW; Isolatie - Steenwol LSW, Participates in Collision Detection: yes
Gipsplaat | Begane grond | Gipsplaat | 36.872 | 3400 | 12.5 | 0.0425 | 0.04609 | 0.10909 | Component Quantities - Projected Component Area (Net): 3.6872 m2; Projected Component Area (Gross): 8.72719 m2; Component Thickness: 12.5 mm; Material Properties - Gipsplaat, ThermalConductivity: 0.23; Gipsplaat, SpecificHeatCapacity: 840 J/kg/K; Gipsplaat, MassDensity: 800 kg/m3; Gipsplaat, Embodied Energy: 6.75 (MJ/kg); Gipsplaat, Embodied Carbon: 0.38 (kgCO₂/kg); Gipsplaat, Name: Gipsplaat; Gipsplaat, Participates in Collision Detection: yes
Gipsplaat | Begane grond | Gipsplaat | 35.607 | 3400 | 12.5 | 0.0425 | 0.0445088 | 0.107509 | Component Quantities - Projected Component Area (Net): 3.5607 m2; Projected Component Area (Gross): 8.60069 m2; Component Thickness: 12.5 mm; Material Properties - Gipsplaat, ThermalConductivity: 0.23; Gipsplaat, SpecificHeatCapacity: 840 J/kg/K; Gipsplaat, MassDensity: 800 kg/m3; Gipsplaat, Embodied Energy: 6.75 (MJ/kg); Gipsplaat, Embodied Carbon: 0.38 (kgCO₂/kg); Gipsplaat, Name: Gipsplaat; Gipsplaat, Participates in Collision Detection: yes
Gipsplaat | Begane grond | Gipsplaat | 59.8575 | 3470 | 12.5 | 0.043375 | 0.0748219 | 0.0748219 | Component Quantities - Projected Component Area (Net): 5.98575 m2; Projected Component Area (Gross): 5.98575 m2; Component Thickness: 12.5 mm; Material Properties - Gipsplaat, ThermalConductivity: 0.23; Gipsplaat, SpecificHeatCapacity: 840 J/kg/K; Gipsplaat, MassDensity: 800 kg/m3; Gipsplaat, Embodied Energy: 6.75 (MJ/kg); Gipsplaat, Embodied Carbon: 0.38 (kgCO₂/kg); Gipsplaat, Name: Gipsplaat; Gipsplaat, Participates in Collision Detection: yes
Gipsplaat | Begane grond | Gipsplaat | 58.99 | 3470 | 12.5 | 0.043375 | 0.0737375 | 0.0737375 | Component Quantities - Projected Component Area (Net): 5.899 m2; Projected Component Area (Gross): 5.899 m2; Component Thickness: 12.5 mm; Material Properties - Gipsplaat, ThermalConductivity: 0.23; Gipsplaat, SpecificHeatCapacity: 840 J/kg/K; Gipsplaat, MassDensity: 800 kg/m3; Gipsplaat, Embodied Energy: 6.75 (MJ/kg); Gipsplaat, Embodied Carbon: 0.38 (kgCO₂/kg); Gipsplaat, Name: Gipsplaat; Gipsplaat, Participates in Collision Detection: yes
Isolatie - Steenwol LSW | Begane grond | Isolatie - Steenwol LSW | 15.268 | 3470 | 50 | 0.1735 | 0.2776 | 0.2776 | Component Quantities - Projected Component Area (Net): 5.552 m2; Projected Component Area (Gross): 5.552 m2; Component Thickness: 50 mm; Material Properties - Isolatie - Steenwol LSW, ThermalConductivity: 0.039; Isolatie - Steenwol LSW, SpecificHeatCapacity: 840 J/kg/K; Isolatie - Steenwol LSW, MassDensity: 55 kg/m3; Isolatie - Steenwol LSW, Embodied Energy: 16.8 (MJ/kg); Isolatie - Steenwol LSW, Embodied Carbon: 1.05 (kgCO₂/kg); Isolatie - Steenwol LSW, Name: Isolatie - Steenwol LSW; Isolatie - Steenwol LSW, Participates in Collision Detection: yes
Gipsplaat | Begane grond | Gipsplaat | 54.6525 | 3470 | 12.5 | 0.043375 | 0.0683156 | 0.0683156 | Component Quantities - Projected Component Area (Net): 5.46525 m2; Projected Component Area (Gross): 5.46525 m2; Component Thickness: 12.5 mm; Material Properties - Gipsplaat, ThermalConductivity: 0.23; Gipsplaat, SpecificHeatCapacity: 840 J/kg/K; Gipsplaat, MassDensity: 800 kg/m3; Gipsplaat, Embodied Energy: 6.75 (MJ/kg); Gipsplaat, Embodied Carbon: 0.38 (kgCO₂/kg); Gipsplaat, Name: Gipsplaat; Gipsplaat, Participates in Collision Detection: yes
Gipsplaat | Begane grond | Gipsplaat | 53.785 | 3470 | 12.5 | 0.043375 | 0.0672312 | 0.0672312 | Component Quantities - Projected Component Area (Net): 5.3785 m2; Projected Component Area (Gross): 5.3785 m2; Component Thickness: 12.5 mm; Material Properties - Gipsplaat, ThermalConductivity: 0.23; Gipsplaat, SpecificHeatCapacity: 840 J/kg/K; Gipsplaat, MassDensity: 800 kg/m3; Gipsplaat, Embodied Energy: 6.75 (MJ/kg); Gipsplaat, Embodied Carbon: 0.38 (kgCO₂/kg); Gipsplaat, Name: Gipsplaat; Gipsplaat, Participates in Collision Detection: yes
Gipsplaat | Begane grond | Gipsplaat | 85.0718 | 3400 | 12.5 | 0.0425 | 0.10634 | 0.137063 | Component Quantities - Projected Component Area (Net): 8.50718 m2; Projected Component Area (Gross): 10.965 m2; Component Thickness: 12.5 mm; Material Properties - Gipsplaat, ThermalConductivity: 0.23; Gipsplaat, SpecificHeatCapacity: 840 J/kg/K; Gipsplaat, MassDensity: 800 kg/m3; Gipsplaat, Embodied Energy: 6.75 (MJ/kg); Gipsplaat, Embodied Carbon: 0.38 (kgCO₂/kg); Gipsplaat, Name: Gipsplaat; Gipsplaat, Participates in Collision Detection: yes
2 x Gipsplaat | Begane grond | Gipsplaat | 85.9218 | 3400 | 12.5 | 0.0425 | 0.107402 | 0.138125 | Component Quantities - Projected Component Area (Net): 8.59218 m2; Projected Component Area (Gross): 11.05 m2; Component Thickness: 12.5 mm; Material Properties - Gipsplaat, ThermalConductivity: 0.23; Gipsplaat, SpecificHeatCapacity: 840 J/kg/K; Gipsplaat, MassDensity: 800 kg/m3; Gipsplaat, Embodied Energy: 6.75 (MJ/kg); Gipsplaat, Embodied Carbon: 0.38 (kgCO₂/kg); Gipsplaat, Name: Gipsplaat; Gipsplaat, Participates in Collision Detection: yes
2 x Isolatie - Steenwol LSW | Begane grond | Isolatie - Steenwol LSW | 24.096 | 3400 | 50 | 0.17 | 0.438109 | 0.561 | Component Quantities - Projected Component Area (Net): 8.76218 m2; Projected Component Area (Gross): 11.22 m2; Component Thickness: 50 mm; Material Properties - Isolatie - Steenwol LSW, ThermalConductivity: 0.039; Isolatie - Steenwol LSW, SpecificHeatCapacity: 840 J/kg/K; Isolatie - Steenwol LSW, MassDensity: 55 kg/m3; Isolatie - Steenwol LSW, Embodied Energy: 16.8 (MJ/kg); Isolatie - Steenwol LSW, Embodied Carbon: 1.05 (kgCO₂/kg); Isolatie - Steenwol LSW, Name: Isolatie - Steenwol LSW; Isolatie - Steenwol LSW, Participates in Collision Detection: yes
Gipsplaat | Begane grond | Gipsplaat | 83.7968 | 3400 | 12.5 | 0.0425 | 0.104746 | 0.135469 | Component Quantities - Projected Component Area (Net): 8.37968 m2; Projected Component Area (Gross): 10.8375 m2; Component Thickness: 12.5 mm; Material Properties - Gipsplaat, ThermalConductivity: 0.23; Gipsplaat, SpecificHeatCapacity: 840 J/kg/K; Gipsplaat, MassDensity: 800 kg/m3; Gipsplaat, Embodied Energy: 6.75 (MJ/kg); Gipsplaat, Embodied Carbon: 0.38 (kgCO₂/kg); Gipsplaat, Name: Gipsplaat; Gipsplaat, Participates in Collision Detection: yes
Gipsplaat | Begane grond | Gipsplaat | 82.0968 | 3400 | 12.5 | 0.0425 | 0.102621 | 0.133344 | Component Quantities - Projected Component Area (Net): 8.20968 m2; Projected Component Area (Gross): 10.6675 m2; Component Thickness: 12.5 mm; Material Properties - Gipsplaat, ThermalConductivity: 0.23; Gipsplaat, SpecificHeatCapacity: 840 J/kg/K; Gipsplaat, MassDensity: 800 kg/m3; Gipsplaat, Embodied Energy: 6.75 (MJ/kg); Gipsplaat, Embodied Carbon: 0.38 (kgCO₂/kg); Gipsplaat, Name: Gipsplaat; Gipsplaat, Participates in Collision Detection: yes
Steen - Kalkzandsteen C | Begane grond | Steen - Kalkzandsteen C | 4754.72 | 4235 | 214 | 0.90629 | 2.50248 | 3.0542 | Component Quantities - Projected Component Area (Net): 11.6939 m2; Projected Component Area (Gross): 14.2719 m2; Component Thickness: 214 mm; Material Properties - Steen - Kalkzandsteen C, ThermalConductivity: 0.9; Steen - Kalkzandsteen C, SpecificHeatCapacity: 840 J/kg/K; Steen - Kalkzandsteen C, MassDensity: 1900 kg/m3; Steen - Kalkzandsteen C, Embodied Energy: 0.75 (MJ/kg); Steen - Kalkzandsteen C, Embodied Carbon: 0.1 (kgCO₂/kg); Steen - Kalkzandsteen C, Name: Steen - Kalkzandsteen C; Steen - Kalkzandsteen C, Participates in Collision Detection: yes
ALG - ISOLATIE | Begane grond | ALG - ISOLATIE | 92.0477 | 4235 | 150 | 0.63525 | 2.0455 | 2.0455 | Component Quantities - Projected Component Area (Net): 13.6367 m2; Projected Component Area (Gross): 13.6367 m2; Component Thickness: 150 mm; Material Properties - ALG - ISOLATIE, ThermalConductivity: 0.035; ALG - ISOLATIE, SpecificHeatCapacity: 840 J/kg/K; ALG - ISOLATIE, MassDensity: 45 kg/m3; ALG - ISOLATIE, Embodied Energy: 16.8 (MJ/kg); ALG - ISOLATIE, Embodied Carbon: 1.05 (kgCO₂/kg); ALG - ISOLATIE, Name: ALG - ISOLATIE; ALG - ISOLATIE, Participates in Collision Detection: yes
Isolatie - Steenwol hard | Begane grond | Isolatie - Steenwol hard | 68.6273 | 4235 | 30 | 0.12705 | 0.428921 | 0.428921 | Component Quantities - Projected Component Area (Net): 14.2974 m2; Projected Component Area (Gross): 14.2974 m2; Component Thickness: 30 mm; Material Properties - Isolatie - Steenwol hard, ThermalConductivity: 0.043; Isolatie - Steenwol hard, SpecificHeatCapacity: 840 J/kg/K; Isolatie - Steenwol hard, MassDensity: 160 kg/m3; Isolatie - Steenwol hard, Embodied Energy: 16.8 (MJ/kg); Isolatie - Steenwol hard, Embodied Carbon: 1.05 (kgCO₂/kg); Isolatie - Steenwol hard, Name: Isolatie - Steenwol hard; Isolatie - Steenwol hard, Participates in Collision Detection: yes
Membraan - dampopen | Begane grond | Membraan - dampopen | 26.0058 | 4235 | 2 | 0.00847 | 0.0285778 | 0.0285778 | Component Quantities - Projected Component Area (Net): 14.2889 m2; Projected Component Area (Gross): 14.2889 m2; Component Thickness: 2 mm; Material Properties - Membraan - dampopen, ThermalConductivity: 0.22; Membraan - dampopen, SpecificHeatCapacity: 1800 J/kg/K; Membraan - dampopen, MassDensity: 910 kg/m3; Membraan - dampopen, Embodied Energy: 99.2 (MJ/kg); Membraan - dampopen, Embodied Carbon: 3.43 (kgCO₂/kg); Membraan - dampopen, Name: Membraan - dampopen; Membraan - dampopen, Participates in Collision Detection: yes
Gipsplaat | Begane grond | Gipsplaat | 256.173 | 3470 | 12.5 | 0.043375 | 0.320216 | 0.442957 | Component Quantities - Projected Component Area (Net): 25.6198 m2; Projected Component Area (Gross): 35.4391 m2; Component Thickness: 12.5 mm; Material Properties - Gipsplaat, ThermalConductivity: 0.23; Gipsplaat, SpecificHeatCapacity: 840 J/kg/K; Gipsplaat, MassDensity: 800 kg/m3; Gipsplaat, Embodied Energy: 6.75 (MJ/kg); Gipsplaat, Embodied Carbon: 0.38 (kgCO₂/kg); Gipsplaat, Name: Gipsplaat; Gipsplaat, Participates in Collision Detection: yes
Gipsplaat | Begane grond | Gipsplaat | 256.622 | 3470 | 12.5 | 0.043375 | 0.320777 | 0.443518 | Component Quantities - Projected Component Area (Net): 25.6622 m2; Projected Component Area (Gross): 35.4815 m2; Component Thickness: 12.5 mm; Material Properties - Gipsplaat, ThermalConductivity: 0.23; Gipsplaat, SpecificHeatCapacity: 840 J/kg/K; Gipsplaat, MassDensity: 800 kg/m3; Gipsplaat, Embodied Energy: 6.75 (MJ/kg); Gipsplaat, Embodied Carbon: 0.38 (kgCO₂/kg); Gipsplaat, Name: Gipsplaat; Gipsplaat, Participates in Collision Detection: yes
Isolatie - Steenwol LSW | Begane grond | Isolatie - Steenwol LSW | 70.9206 | 3470 | 50 | 0.1735 | 1.28947 | 1.78043 | Component Quantities - Projected Component Area (Net): 25.7893 m2; Projected Component Area (Gross): 35.6086 m2; Component Thickness: 50 mm; Material Properties - Isolatie - Steenwol LSW, ThermalConductivity: 0.039; Isolatie - Steenwol LSW, SpecificHeatCapacity: 840 J/kg/K; Isolatie - Steenwol LSW, MassDensity: 55 kg/m3; Isolatie - Steenwol LSW, Embodied Energy: 16.8 (MJ/kg); Isolatie - Steenwol LSW, Embodied Carbon: 1.05 (kgCO₂/kg); Isolatie - Steenwol LSW, Name: Isolatie - Steenwol LSW; Isolatie - Steenwol LSW, Participates in Collision Detection: yes
Gipsplaat | Begane grond | Gipsplaat | 256.198 | 3470 | 12.5 | 0.043375 | 0.320248 | 0.442989 | Component Quantities - Projected Component Area (Net): 25.6198 m2; Projected Component Area (Gross): 35.4391 m2; Component Thickness: 12.5 mm; Material Properties - Gipsplaat, ThermalConductivity: 0.23; Gipsplaat, SpecificHeatCapacity: 840 J/kg/K; Gipsplaat, MassDensity: 800 kg/m3; Gipsplaat, Embodied Energy: 6.75 (MJ/kg); Gipsplaat, Embodied Carbon: 0.38 (kgCO₂/kg); Gipsplaat, Name: Gipsplaat; Gipsplaat, Participates in Collision Detection: yes
Gipsplaat | Begane grond | Gipsplaat | 255.774 | 3470 | 12.5 | 0.043375 | 0.319718 | 0.442459 | Component Quantities - Projected Component Area (Net): 25.5774 m2; Projected Component Area (Gross): 35.3967 m2; Component Thickness: 12.5 mm; Material Properties - Gipsplaat, ThermalConductivity: 0.23; Gipsplaat, SpecificHeatCapacity: 840 J/kg/K; Gipsplaat, MassDensity: 800 kg/m3; Gipsplaat, Embodied Energy: 6.75 (MJ/kg); Gipsplaat, Embodied Carbon: 0.38 (kgCO₂/kg); Gipsplaat, Name: Gipsplaat; Gipsplaat, Participates in Collision Detection: yes
2 x Gipsplaat | Begane grond | Gipsplaat | 109.445 | 3470 | 12.5 | 0.043375 | 0.136806 | 0.136806 | Component Quantities - Projected Component Area (Net): 10.9445 m2; Projected Component Area (Gross): 10.9445 m2; Component Thickness: 12.5 mm; Material Properties - Gipsplaat, ThermalConductivity: 0.23; Gipsplaat, SpecificHeatCapacity: 840 J/kg/K; Gipsplaat, MassDensity: 800 kg/m3; Gipsplaat, Embodied Energy: 6.75 (MJ/kg); Gipsplaat, Embodied Carbon: 0.38 (kgCO₂/kg); Gipsplaat, Name: Gipsplaat; Gipsplaat, Participates in Collision Detection: yes
2 x Gipsplaat | Begane grond | Gipsplaat | 110.313 | 3470 | 12.5 | 0.043375 | 0.137891 | 0.137891 | Component Quantities - Projected Component Area (Net): 11.0313 m2; Projected Component Area (Gross): 11.0313 m2; Component Thickness: 12.5 mm; Material Properties - Gipsplaat, ThermalConductivity: 0.23; Gipsplaat, SpecificHeatCapacity: 840 J/kg/K; Gipsplaat, MassDensity: 800 kg/m3; Gipsplaat, Embodied Energy: 6.75 (MJ/kg); Gipsplaat, Embodied Carbon: 0.38 (kgCO₂/kg); Gipsplaat, Name: Gipsplaat; Gipsplaat, Participates in Collision Detection: yes
Isolatie - Steenwol LSW | Begane grond | Isolatie - Steenwol LSW | 30.5745 | 3470 | 50 | 0.1735 | 0.5559 | 0.5559 | Component Quantities - Projected Component Area (Net): 11.118 m2; Projected Component Area (Gross): 11.118 m2; Component Thickness: 50 mm; Material Properties - Isolatie - Steenwol LSW, ThermalConductivity: 0.039; Isolatie - Steenwol LSW, SpecificHeatCapacity: 840 J/kg/K; Isolatie - Steenwol LSW, MassDensity: 55 kg/m3; Isolatie - Steenwol LSW, Embodied Energy: 16.8 (MJ/kg); Isolatie - Steenwol LSW, Embodied Carbon: 1.05 (kgCO₂/kg); Isolatie - Steenwol LSW, Name: Isolatie - Steenwol LSW; Isolatie - Steenwol LSW, Participates in Collision Detection: yes
Gipsplaat | Begane grond | Gipsplaat | 387.854 | 3400 | 12.5 | 0.0425 | 0.484817 | 0.484817 | Component Quantities - Projected Component Area (Net): 38.7854 m2; Projected Component Area (Gross): 38.7854 m2; Component Thickness: 12.5 mm; Material Properties - Gipsplaat, ThermalConductivity: 0.23; Gipsplaat, SpecificHeatCapacity: 840 J/kg/K; Gipsplaat, MassDensity: 800 kg/m3; Gipsplaat, Embodied Energy: 6.75 (MJ/kg); Gipsplaat, Embodied Carbon: 0.38 (kgCO₂/kg); Gipsplaat, Name: Gipsplaat; Gipsplaat, Participates in Collision Detection: yes
Gipsplaat | Begane grond | Gipsplaat | 395.059 | 3400 | 12.5 | 0.0425 | 0.493824 | 0.493824 | Component Quantities - Projected Component Area (Net): 39.5059 m2; Projected Component Area (Gross): 39.5059 m2; Component Thickness: 12.5 mm; Material Properties - Gipsplaat, ThermalConductivity: 0.23; Gipsplaat, SpecificHeatCapacity: 840 J/kg/K; Gipsplaat, MassDensity: 800 kg/m3; Gipsplaat, Embodied Energy: 6.75 (MJ/kg); Gipsplaat, Embodied Carbon: 0.38 (kgCO₂/kg); Gipsplaat, Name: Gipsplaat; Gipsplaat, Participates in Collision Detection: yes
Isolatie - Steenwol LSW | Begane grond | Isolatie - Steenwol LSW | 112.944 | 3400 | 50 | 0.17 | 2.05352 | 2.05352 | Component Quantities - Projected Component Area (Net): 41.0704 m2; Projected Component Area (Gross): 41.0704 m2; Component Thickness: 50 mm; Material Properties - Isolatie - Steenwol LSW, ThermalConductivity: 0.039; Isolatie - Steenwol LSW, SpecificHeatCapacity: 840 J/kg/K; Isolatie - Steenwol LSW, MassDensity: 55 kg/m3; Isolatie - Steenwol LSW, Embodied Energy: 16.8 (MJ/kg); Isolatie - Steenwol LSW, Embodied Carbon: 1.05 (kgCO₂/kg); Isolatie - Steenwol LSW, Name: Isolatie - Steenwol LSW; Isolatie - Steenwol LSW, Participates in Collision Detection: yes
Gipsplaat | Begane grond | Gipsplaat | 410.279 | 3400 | 12.5 | 0.0425 | 0.512849 | 0.512849 | Component Quantities - Projected Component Area (Net): 41.0279 m2; Projected Component Area (Gross): 41.0279 m2; Component Thickness: 12.5 mm; Material Properties - Gipsplaat, ThermalConductivity: 0.23; Gipsplaat, SpecificHeatCapacity: 840 J/kg/K; Gipsplaat, MassDensity: 800 kg/m3; Gipsplaat, Embodied Energy: 6.75 (MJ/kg); Gipsplaat, Embodied Carbon: 0.38 (kgCO₂/kg); Gipsplaat, Name: Gipsplaat; Gipsplaat, Participates in Collision Detection: yes
Gipsplaat | Begane grond | Gipsplaat | 409.854 | 3400 | 12.5 | 0.0425 | 0.512317 | 0.512317 | Component Quantities - Projected Component Area (Net): 40.9854 m2; Projected Component Area (Gross): 40.9854 m2; Component Thickness: 12.5 mm; Material Properties - Gipsplaat, ThermalConductivity: 0.23; Gipsplaat, SpecificHeatCapacity: 840 J/kg/K; Gipsplaat, MassDensity: 800 kg/m3; Gipsplaat, Embodied Energy: 6.75 (MJ/kg); Gipsplaat, Embodied Carbon: 0.38 (kgCO₂/kg); Gipsplaat, Name: Gipsplaat; Gipsplaat, Participates in Collision Detection: yes
2 x Gipsplaat | Begane grond | Gipsplaat | 85.4968 | 3400 | 12.5 | 0.0425 | 0.106871 | 0.137594 | Component Quantities - Projected Component Area (Net): 8.54968 m2; Projected Component Area (Gross): 11.0075 m2; Component Thickness: 12.5 mm; Material Properties - Gipsplaat, ThermalConductivity: 0.23; Gipsplaat, SpecificHeatCapacity: 840 J/kg/K; Gipsplaat, MassDensity: 800 kg/m3; Gipsplaat, Embodied Energy: 6.75 (MJ/kg); Gipsplaat, Embodied Carbon: 0.38 (kgCO₂/kg); Gipsplaat, Name: Gipsplaat; Gipsplaat, Participates in Collision Detection: yes
Gipsplaat | Begane grond | Gipsplaat | 84.6484 | 3400 | 12.5 | 0.0425 | 0.10581 | 0.136531 | Component Quantities - Projected Component Area (Net): 8.46774 m2; Projected Component Area (Gross): 10.9225 m2; Component Thickness: 12.5 mm; Material Properties - Gipsplaat, ThermalConductivity: 0.23; Gipsplaat, SpecificHeatCapacity: 840 J/kg/K; Gipsplaat, MassDensity: 800 kg/m3; Gipsplaat, Embodied Energy: 6.75 (MJ/kg); Gipsplaat, Embodied Carbon: 0.38 (kgCO₂/kg); Gipsplaat, Name: Gipsplaat; Gipsplaat, Participates in Collision Detection: yes
Membraan - dampopen | Begane grond | Membraan - dampopen | 27.4086 | 4235 | 2 | 0.00847 | 0.0301193 | 0.0301193 | Component Quantities - Projected Component Area (Net): 15.0597 m2; Projected Component Area (Gross): 15.0597 m2; Component Thickness: 2 mm; Material Properties - Membraan - dampopen, ThermalConductivity: 0.22; Membraan - dampopen, SpecificHeatCapacity: 1800 J/kg/K; Membraan - dampopen, MassDensity: 910 kg/m3; Membraan - dampopen, Embodied Energy: 99.2 (MJ/kg); Membraan - dampopen, Embodied Carbon: 3.43 (kgCO₂/kg); Membraan - dampopen, Name: Membraan - dampopen; Membraan - dampopen, Participates in Collision Detection: yes
Isolatie - Steenwol hard | Begane grond | Isolatie - Steenwol hard | 72.2864 | 4235 | 30 | 0.12705 | 0.45179 | 0.45179 | Component Quantities - Projected Component Area (Net): 15.0597 m2; Projected Component Area (Gross): 15.0597 m2; Component Thickness: 30 mm; Material Properties - Isolatie - Steenwol hard, ThermalConductivity: 0.043; Isolatie - Steenwol hard, SpecificHeatCapacity: 840 J/kg/K; Isolatie - Steenwol hard, MassDensity: 160 kg/m3; Isolatie - Steenwol hard, Embodied Energy: 16.8 (MJ/kg); Isolatie - Steenwol hard, Embodied Carbon: 1.05 (kgCO₂/kg); Isolatie - Steenwol hard, Name: Isolatie - Steenwol hard; Isolatie - Steenwol hard, Participates in Collision Detection: yes
ALG - ISOLATIE | Begane grond | ALG - ISOLATIE | 97.1933 | 4235 | 150 | 0.63525 | 2.15985 | 2.15985 | Component Quantities - Projected Component Area (Net): 14.399 m2; Projected Component Area (Gross): 14.399 m2; Component Thickness: 150 mm; Material Properties - ALG - ISOLATIE, ThermalConductivity: 0.035; ALG - ISOLATIE, SpecificHeatCapacity: 840 J/kg/K; ALG - ISOLATIE, MassDensity: 45 kg/m3; ALG - ISOLATIE, Embodied Energy: 16.8 (MJ/kg); ALG - ISOLATIE, Embodied Carbon: 1.05 (kgCO₂/kg); ALG - ISOLATIE, Name: ALG - ISOLATIE; ALG - ISOLATIE, Participates in Collision Detection: yes
Steen - Kalkzandsteen C | Begane grond | Steen - Kalkzandsteen C | 5096.18 | 4235 | 214 | 0.90629 | 2.6822 | 3.27352 | Component Quantities - Projected Component Area (Net): 12.5336 m2; Projected Component Area (Gross): 15.2968 m2; Component Thickness: 214 mm; Material Properties - Steen - Kalkzandsteen C, ThermalConductivity: 0.9; Steen - Kalkzandsteen C, SpecificHeatCapacity: 840 J/kg/K; Steen - Kalkzandsteen C, MassDensity: 1900 kg/m3; Steen - Kalkzandsteen C, Embodied Energy: 0.75 (MJ/kg); Steen - Kalkzandsteen C, Embodied Carbon: 0.1 (kgCO₂/kg); Steen - Kalkzandsteen C, Name: Steen - Kalkzandsteen C; Steen - Kalkzandsteen C, Participates in Collision Detection: yes
Gipsplaat | Begane grond | Gipsplaat | 378.385 | 3470 | 12.5 | 0.043375 | 0.472981 | 0.748307 | Component Quantities - Projected Component Area (Net): 37.8392 m2; Projected Component Area (Gross): 59.8653 m2; Component Thickness: 12.5 mm; Material Properties - Gipsplaat, ThermalConductivity: 0.23; Gipsplaat, SpecificHeatCapacity: 840 J/kg/K; Gipsplaat, MassDensity: 800 kg/m3; Gipsplaat, Embodied Energy: 6.75 (MJ/kg); Gipsplaat, Embodied Carbon: 0.38 (kgCO₂/kg); Gipsplaat, Name: Gipsplaat; Gipsplaat, Participates in Collision Detection: yes
Gipsplaat | Begane grond | Gipsplaat | 382.083 | 3470 | 12.5 | 0.043375 | 0.477603 | 0.752929 | Component Quantities - Projected Component Area (Net): 38.2083 m2; Projected Component Area (Gross): 60.2343 m2; Component Thickness: 12.5 mm; Material Properties - Gipsplaat, ThermalConductivity: 0.23; Gipsplaat, SpecificHeatCapacity: 840 J/kg/K; Gipsplaat, MassDensity: 800 kg/m3; Gipsplaat, Embodied Energy: 6.75 (MJ/kg); Gipsplaat, Embodied Carbon: 0.38 (kgCO₂/kg); Gipsplaat, Name: Gipsplaat; Gipsplaat, Participates in Collision Detection: yes
Isolatie - Steenwol LSW | Begane grond | Isolatie - Steenwol LSW | 108.289 | 3470 | 50 | 0.1735 | 1.96889 | 3.07019 | Component Quantities - Projected Component Area (Net): 39.3778 m2; Projected Component Area (Gross): 61.4038 m2; Component Thickness: 50 mm; Material Properties - Isolatie - Steenwol LSW, ThermalConductivity: 0.039; Isolatie - Steenwol LSW, SpecificHeatCapacity: 840 J/kg/K; Isolatie - Steenwol LSW, MassDensity: 55 kg/m3; Isolatie - Steenwol LSW, Embodied Energy: 16.8 (MJ/kg); Isolatie - Steenwol LSW, Embodied Carbon: 1.05 (kgCO₂/kg); Isolatie - Steenwol LSW, Name: Isolatie - Steenwol LSW; Isolatie - Steenwol LSW, Participates in Collision Detection: yes
Gipsplaat | Begane grond | Gipsplaat | 385.641 | 3470 | 12.5 | 0.043375 | 0.482052 | 0.757378 | Component Quantities - Projected Component Area (Net): 38.5641 m2; Projected Component Area (Gross): 60.5902 m2; Component Thickness: 12.5 mm; Material Properties - Gipsplaat, ThermalConductivity: 0.23; Gipsplaat, SpecificHeatCapacity: 840 J/kg/K; Gipsplaat, MassDensity: 800 kg/m3; Gipsplaat, Embodied Energy: 6.75 (MJ/kg); Gipsplaat, Embodied Carbon: 0.38 (kgCO₂/kg); Gipsplaat, Name: Gipsplaat; Gipsplaat, Participates in Collision Detection: yes
Gipsplaat | Begane grond | Gipsplaat | 383.49 | 3470 | 12.5 | 0.043375 | 0.479363 | 0.754689 | Component Quantities - Projected Component Area (Net): 38.349 m2; Projected Component Area (Gross): 60.3751 m2; Component Thickness: 12.5 mm; Material Properties - Gipsplaat, ThermalConductivity: 0.23; Gipsplaat, SpecificHeatCapacity: 840 J/kg/K; Gipsplaat, MassDensity: 800 kg/m3; Gipsplaat, Embodied Energy: 6.75 (MJ/kg); Gipsplaat, Embodied Carbon: 0.38 (kgCO₂/kg); Gipsplaat, Name: Gipsplaat; Gipsplaat, Participates in Collision Detection: yes
Metaal - Staal AFW | Begane grond | Metaal - Staal AFW | 2514.48 | 4255 | 4 | 0.01702 | 0.316287 | 0.365215 | Component Quantities - Projected Component Area (Net): 79.0718 m2; Projected Component Area (Gross): 91.3038 m2; Component Thickness: 4 mm; Material Properties - Metaal - Staal AFW, ThermalConductivity: 52; Metaal - Staal AFW, SpecificHeatCapacity: 530 J/kg/K; Metaal - Staal AFW, MassDensity: 7950 kg/m3; Metaal - Staal AFW, Embodied Energy: 25 (MJ/kg); Metaal - Staal AFW, Embodied Carbon: 1.91 (kgCO₂/kg); Metaal - Staal AFW, Name: Metaal - Staal AFW; Metaal - Staal AFW, Participates in Collision Detection: yes
Isolatie - Glaswol hard | Begane grond | Isolatie - Glaswol hard | 1009.34 | 4255 | 196 | 0.83398 | 15.771 | 18.2225 | Component Quantities - Projected Component Area (Net): 80.7398 m2; Projected Component Area (Gross): 92.9718 m2; Component Thickness: 196 mm; Material Properties - Isolatie - Glaswol hard, ThermalConductivity: 0.033; Isolatie - Glaswol hard, SpecificHeatCapacity: 1030 J/kg/K; Isolatie - Glaswol hard, MassDensity: 64 kg/m3; Isolatie - Glaswol hard, Embodied Energy: 37 (MJ/kg); Isolatie - Glaswol hard, Embodied Carbon: 1.48 (kgCO₂/kg); Isolatie - Glaswol hard, Name: Isolatie - Glaswol hard; Isolatie - Glaswol hard, Participates in Collision Detection: yes
Steen - Baksteen AFW | Begane grond | Steen - Baksteen AFW | 8132.44 | 4255 | 100 | 0.4255 | 5.08277 | 9.41632 | Component Quantities - Projected Component Area (Net): 50.8277 m2; Projected Component Area (Gross): 94.1632 m2; Component Thickness: 100 mm; Material Properties - Steen - Baksteen AFW, ThermalConductivity: 0.9; Steen - Baksteen AFW, SpecificHeatCapacity: 840 J/kg/K; Steen - Baksteen AFW, MassDensity: 1600 kg/m3; Steen - Baksteen AFW, Embodied Energy: 3 (MJ/kg); Steen - Baksteen AFW, Embodied Carbon: 0.23 (kgCO₂/kg); Steen - Baksteen AFW, Name: Steen - Baksteen AFW; Steen - Baksteen AFW, Participates in Collision Detection: yes
Membraan - dampopen | Begane grond | Membraan - dampopen | 92.9905 | 4235 | 2 | 0.00847 | 0.102187 | 0.130379 | Component Quantities - Projected Component Area (Net): 51.0937 m2; Projected Component Area (Gross): 65.1894 m2; Component Thickness: 2 mm; Material Properties - Membraan - dampopen, ThermalConductivity: 0.22; Membraan - dampopen, SpecificHeatCapacity: 1800 J/kg/K; Membraan - dampopen, MassDensity: 910 kg/m3; Membraan - dampopen, Embodied Energy: 99.2 (MJ/kg); Membraan - dampopen, Embodied Carbon: 3.43 (kgCO₂/kg); Membraan - dampopen, Name: Membraan - dampopen; Membraan - dampopen, Participates in Collision Detection: yes
Isolatie - Steenwol hard | Begane grond | Isolatie - Steenwol hard | 245.29 | 4235 | 30 | 0.12705 | 1.53306 | 1.95594 | Component Quantities - Projected Component Area (Net): 51.1021 m2; Projected Component Area (Gross): 65.1979 m2; Component Thickness: 30 mm; Material Properties - Isolatie - Steenwol hard, ThermalConductivity: 0.043; Isolatie - Steenwol hard, SpecificHeatCapacity: 840 J/kg/K; Isolatie - Steenwol hard, MassDensity: 160 kg/m3; Isolatie - Steenwol hard, Embodied Energy: 16.8 (MJ/kg); Isolatie - Steenwol hard, Embodied Carbon: 1.05 (kgCO₂/kg); Isolatie - Steenwol hard, Name: Isolatie - Steenwol hard; Isolatie - Steenwol hard, Participates in Collision Detection: yes
ALG - ISOLATIE | Begane grond | ALG - ISOLATIE | 347.034 | 4235 | 150 | 0.63525 | 7.71187 | 9.79874 | Component Quantities - Projected Component Area (Net): 51.7926 m2; Projected Component Area (Gross): 65.3249 m2; Component Thickness: 150 mm; Material Properties - ALG - ISOLATIE, ThermalConductivity: 0.035; ALG - ISOLATIE, SpecificHeatCapacity: 840 J/kg/K; ALG - ISOLATIE, MassDensity: 45 kg/m3; ALG - ISOLATIE, Embodied Energy: 16.8 (MJ/kg); ALG - ISOLATIE, Embodied Carbon: 1.05 (kgCO₂/kg); ALG - ISOLATIE, Name: ALG - ISOLATIE; ALG - ISOLATIE, Participates in Collision Detection: yes
Steen - Kalkzandsteen C | Begane grond | Steen - Kalkzandsteen C | 16474.2 | 4235 | 214 | 0.90629 | 8.67065 | 14.1155 | Component Quantities - Projected Component Area (Net): 50.2721 m2; Projected Component Area (Gross): 65.9602 m2; Component Thickness: 214 mm; Material Properties - Steen - Kalkzandsteen C, ThermalConductivity: 0.9; Steen - Kalkzandsteen C, SpecificHeatCapacity: 840 J/kg/K; Steen - Kalkzandsteen C, MassDensity: 1900 kg/m3; Steen - Kalkzandsteen C, Embodied Energy: 0.75 (MJ/kg); Steen - Kalkzandsteen C, Embodied Carbon: 0.1 (kgCO₂/kg); Steen - Kalkzandsteen C, Name: Steen - Kalkzandsteen C; Steen - Kalkzandsteen C, Participates in Collision Detection: yes
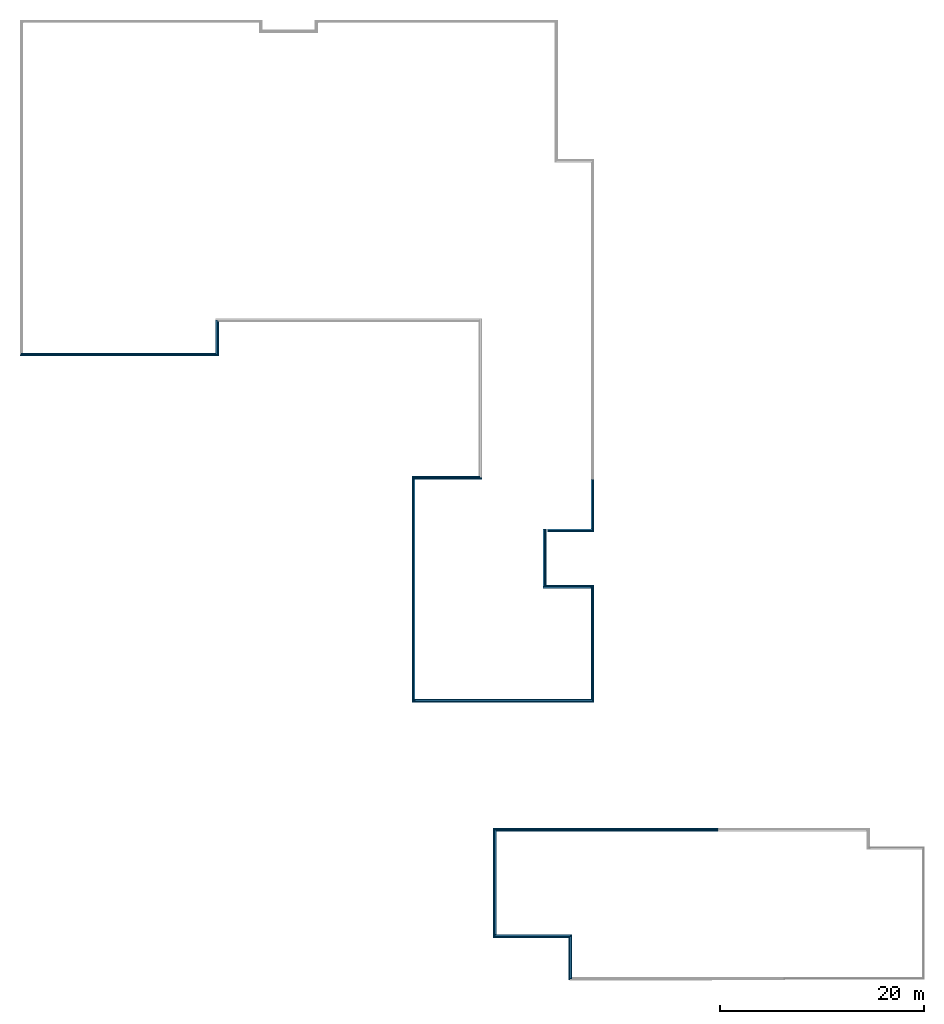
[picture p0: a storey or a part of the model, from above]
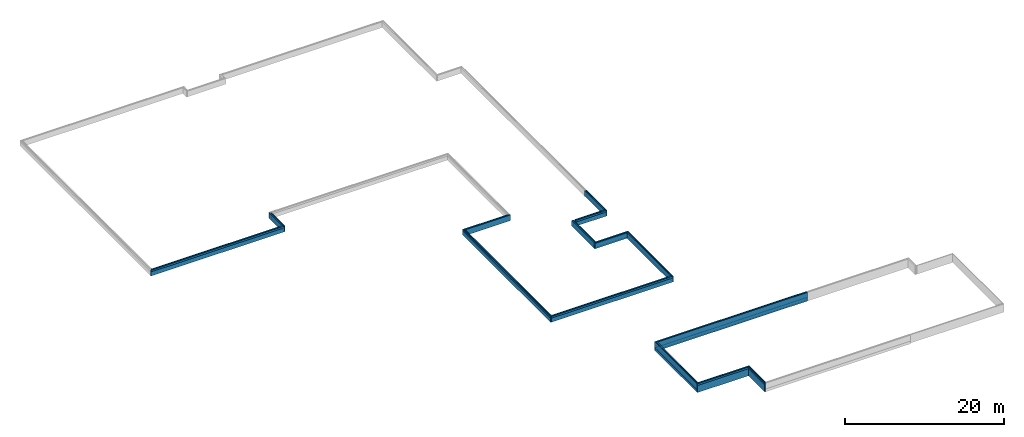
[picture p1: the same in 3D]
Properties of the parts of a building model (IFC2X3), part 6 of 19

# IfcBuildingElementPart (2070)
Name | In | Material | Mass (kg) | Rectangular Component Height (mm) | Rectangular Component Width (mm) | Component Cross Section Area (m2) | Component Volume (Net) (m3) | Component Volume (Gross) (m3)
2 x Gipsplaat | Begane grond | Gipsplaat | 172.201 | 3470 | 12.5 | 0.043375 | 0.215251 | 0.307876 | Component Quantities - Projected Component Area (Net): 17.2201 m2; Projected Component Area (Gross): 24.6301 m2; Component Thickness: 12.5 mm; Material Properties - Gipsplaat, ThermalConductivity: 0.23; Gipsplaat, SpecificHeatCapacity: 840 J/kg/K; Gipsplaat, MassDensity: 800 kg/m3; Gipsplaat, Embodied Energy: 6.75 (MJ/kg); Gipsplaat, Embodied Carbon: 0.38 (kgCO₂/kg); Gipsplaat, Name: Gipsplaat; Gipsplaat, Participates in Collision Detection: yes
2 x Gipsplaat | Begane grond | Gipsplaat | 172.624 | 3470 | 12.5 | 0.043375 | 0.215781 | 0.308406 | Component Quantities - Projected Component Area (Net): 17.2624 m2; Projected Component Area (Gross): 24.6724 m2; Component Thickness: 12.5 mm; Material Properties - Gipsplaat, ThermalConductivity: 0.23; Gipsplaat, SpecificHeatCapacity: 840 J/kg/K; Gipsplaat, MassDensity: 800 kg/m3; Gipsplaat, Embodied Energy: 6.75 (MJ/kg); Gipsplaat, Embodied Carbon: 0.38 (kgCO₂/kg); Gipsplaat, Name: Gipsplaat; Gipsplaat, Participates in Collision Detection: yes
Isolatie - Steenwol LSW | Begane grond | Isolatie - Steenwol LSW | 47.5882 | 3470 | 50 | 0.1735 | 0.865241 | 1.23574 | Component Quantities - Projected Component Area (Net): 17.3048 m2; Projected Component Area (Gross): 24.7148 m2; Component Thickness: 50 mm; Material Properties - Isolatie - Steenwol LSW, ThermalConductivity: 0.039; Isolatie - Steenwol LSW, SpecificHeatCapacity: 840 J/kg/K; Isolatie - Steenwol LSW, MassDensity: 55 kg/m3; Isolatie - Steenwol LSW, Embodied Energy: 16.8 (MJ/kg); Isolatie - Steenwol LSW, Embodied Carbon: 1.05 (kgCO₂/kg); Isolatie - Steenwol LSW, Name: Isolatie - Steenwol LSW; Isolatie - Steenwol LSW, Participates in Collision Detection: yes
Gipsplaat | Begane grond | Gipsplaat | 35.87 | 3400 | 12.5 | 0.0425 | 0.0448376 | 0.0448376 | Component Quantities - Projected Component Area (Net): 3.587 m2; Projected Component Area (Gross): 3.587 m2; Component Thickness: 12.5 mm; Material Properties - Gipsplaat, ThermalConductivity: 0.23; Gipsplaat, SpecificHeatCapacity: 840 J/kg/K; Gipsplaat, MassDensity: 800 kg/m3; Gipsplaat, Embodied Energy: 6.75 (MJ/kg); Gipsplaat, Embodied Carbon: 0.38 (kgCO₂/kg); Gipsplaat, Name: Gipsplaat; Gipsplaat, Participates in Collision Detection: yes
Gipsplaat | Begane grond | Gipsplaat | 36.72 | 3400 | 12.5 | 0.0425 | 0.0459001 | 0.0459001 | Component Quantities - Projected Component Area (Net): 3.672 m2; Projected Component Area (Gross): 3.672 m2; Component Thickness: 12.5 mm; Material Properties - Gipsplaat, ThermalConductivity: 0.23; Gipsplaat, SpecificHeatCapacity: 840 J/kg/K; Gipsplaat, MassDensity: 800 kg/m3; Gipsplaat, Embodied Energy: 6.75 (MJ/kg); Gipsplaat, Embodied Carbon: 0.38 (kgCO₂/kg); Gipsplaat, Name: Gipsplaat; Gipsplaat, Participates in Collision Detection: yes
Isolatie - Steenwol LSW | Begane grond | Isolatie - Steenwol LSW | 10.3318 | 3400 | 50 | 0.17 | 0.18785 | 0.18785 | Component Quantities - Projected Component Area (Net): 3.757 m2; Projected Component Area (Gross): 3.757 m2; Component Thickness: 50 mm; Material Properties - Isolatie - Steenwol LSW, ThermalConductivity: 0.039; Isolatie - Steenwol LSW, SpecificHeatCapacity: 840 J/kg/K; Isolatie - Steenwol LSW, MassDensity: 55 kg/m3; Isolatie - Steenwol LSW, Embodied Energy: 16.8 (MJ/kg); Isolatie - Steenwol LSW, Embodied Carbon: 1.05 (kgCO₂/kg); Isolatie - Steenwol LSW, Name: Isolatie - Steenwol LSW; Isolatie - Steenwol LSW, Participates in Collision Detection: yes
Steen - Baksteen AFW | Begane grond | Steen - Baksteen AFW | 4268.26 | 4235 | 100 | 0.4235 | 2.66767 | 8.22861 | Component Quantities - Projected Component Area (Net): 26.7487 m2; Projected Component Area (Gross): 82.2861 m2; Component Thickness: 100 mm; Material Properties - Steen - Baksteen AFW, ThermalConductivity: 0.9; Steen - Baksteen AFW, SpecificHeatCapacity: 840 J/kg/K; Steen - Baksteen AFW, MassDensity: 1600 kg/m3; Steen - Baksteen AFW, Embodied Energy: 3 (MJ/kg); Steen - Baksteen AFW, Embodied Carbon: 0.23 (kgCO₂/kg); Steen - Baksteen AFW, Name: Steen - Baksteen AFW; Steen - Baksteen AFW, Participates in Collision Detection: yes
ALG - ISOLATIE | Begane grond | ALG - ISOLATIE | 358.295 | 4235 | 150 | 0.63525 | 7.96211 | 12.2819 | Component Quantities - Projected Component Area (Net): 53.9405 m2; Projected Component Area (Gross): 81.8795 m2; Component Thickness: 150 mm; Material Properties - ALG - ISOLATIE, ThermalConductivity: 0.035; ALG - ISOLATIE, SpecificHeatCapacity: 840 J/kg/K; ALG - ISOLATIE, MassDensity: 45 kg/m3; ALG - ISOLATIE, Embodied Energy: 16.8 (MJ/kg); ALG - ISOLATIE, Embodied Carbon: 1.05 (kgCO₂/kg); ALG - ISOLATIE, Name: ALG - ISOLATIE; ALG - ISOLATIE, Participates in Collision Detection: yes
Steen - Kalkzandsteen C | Begane grond | Steen - Kalkzandsteen C | 10797.6 | 4235 | 150 | 0.63525 | 5.68297 | 12.0507 | Component Quantities - Projected Component Area (Net): 37.8869 m2; Projected Component Area (Gross): 80.338 m2; Component Thickness: 150 mm; Material Properties - Steen - Kalkzandsteen C, ThermalConductivity: 0.9; Steen - Kalkzandsteen C, SpecificHeatCapacity: 840 J/kg/K; Steen - Kalkzandsteen C, MassDensity: 1900 kg/m3; Steen - Kalkzandsteen C, Embodied Energy: 0.75 (MJ/kg); Steen - Kalkzandsteen C, Embodied Carbon: 0.1 (kgCO₂/kg); Steen - Kalkzandsteen C, Name: Steen - Kalkzandsteen C; Steen - Kalkzandsteen C, Participates in Collision Detection: yes
Gipsplaat | Begane grond | Gipsplaat | 12.4295 | 3470 | 12.5 | 0.043375 | 0.0155368 | 0.0872151 | Component Quantities - Projected Component Area (Net): 1.24295 m2; Projected Component Area (Gross): 6.97721 m2; Component Thickness: 12.5 mm; Material Properties - Gipsplaat, ThermalConductivity: 0.23; Gipsplaat, SpecificHeatCapacity: 840 J/kg/K; Gipsplaat, MassDensity: 800 kg/m3; Gipsplaat, Embodied Energy: 6.75 (MJ/kg); Gipsplaat, Embodied Carbon: 0.38 (kgCO₂/kg); Gipsplaat, Name: Gipsplaat; Gipsplaat, Participates in Collision Detection: yes
Gipsplaat | Begane grond | Gipsplaat | 12.8632 | 3470 | 12.5 | 0.043375 | 0.016079 | 0.0877573 | Component Quantities - Projected Component Area (Net): 1.28632 m2; Projected Component Area (Gross): 7.02058 m2; Component Thickness: 12.5 mm; Material Properties - Gipsplaat, ThermalConductivity: 0.23; Gipsplaat, SpecificHeatCapacity: 840 J/kg/K; Gipsplaat, MassDensity: 800 kg/m3; Gipsplaat, Embodied Energy: 6.75 (MJ/kg); Gipsplaat, Embodied Carbon: 0.38 (kgCO₂/kg); Gipsplaat, Name: Gipsplaat; Gipsplaat, Participates in Collision Detection: yes
Isolatie - Steenwol LSW | Begane grond | Isolatie - Steenwol LSW | 4.01451 | 3470 | 50 | 0.1735 | 0.0729911 | 0.359704 | Component Quantities - Projected Component Area (Net): 1.45982 m2; Projected Component Area (Gross): 7.19408 m2; Component Thickness: 50 mm; Material Properties - Isolatie - Steenwol LSW, ThermalConductivity: 0.039; Isolatie - Steenwol LSW, SpecificHeatCapacity: 840 J/kg/K; Isolatie - Steenwol LSW, MassDensity: 55 kg/m3; Isolatie - Steenwol LSW, Embodied Energy: 16.8 (MJ/kg); Isolatie - Steenwol LSW, Embodied Carbon: 1.05 (kgCO₂/kg); Isolatie - Steenwol LSW, Name: Isolatie - Steenwol LSW; Isolatie - Steenwol LSW, Participates in Collision Detection: yes
Gipsplaat | Begane grond | Gipsplaat | 15.032 | 3470 | 12.5 | 0.043375 | 0.01879 | 0.0904682 | Component Quantities - Projected Component Area (Net): 1.5032 m2; Projected Component Area (Gross): 7.23746 m2; Component Thickness: 12.5 mm; Material Properties - Gipsplaat, ThermalConductivity: 0.23; Gipsplaat, SpecificHeatCapacity: 840 J/kg/K; Gipsplaat, MassDensity: 800 kg/m3; Gipsplaat, Embodied Energy: 6.75 (MJ/kg); Gipsplaat, Embodied Carbon: 0.38 (kgCO₂/kg); Gipsplaat, Name: Gipsplaat; Gipsplaat, Participates in Collision Detection: yes
Gipsplaat | Begane grond | Gipsplaat | 15.4657 | 3470 | 12.5 | 0.043375 | 0.0193322 | 0.0910104 | Component Quantities - Projected Component Area (Net): 1.54657 m2; Projected Component Area (Gross): 7.28083 m2; Component Thickness: 12.5 mm; Material Properties - Gipsplaat, ThermalConductivity: 0.23; Gipsplaat, SpecificHeatCapacity: 840 J/kg/K; Gipsplaat, MassDensity: 800 kg/m3; Gipsplaat, Embodied Energy: 6.75 (MJ/kg); Gipsplaat, Embodied Carbon: 0.38 (kgCO₂/kg); Gipsplaat, Name: Gipsplaat; Gipsplaat, Participates in Collision Detection: yes
Gipsplaat | Begane grond | Gipsplaat | 135.712 | 3400 | 12.5 | 0.0425 | 0.16964 | 0.16964 | Component Quantities - Projected Component Area (Net): 13.5712 m2; Projected Component Area (Gross): 13.5712 m2; Component Thickness: 12.5 mm; Material Properties - Gipsplaat, ThermalConductivity: 0.23; Gipsplaat, SpecificHeatCapacity: 840 J/kg/K; Gipsplaat, MassDensity: 800 kg/m3; Gipsplaat, Embodied Energy: 6.75 (MJ/kg); Gipsplaat, Embodied Carbon: 0.38 (kgCO₂/kg); Gipsplaat, Name: Gipsplaat; Gipsplaat, Participates in Collision Detection: yes
Gipsplaat | Begane grond | Gipsplaat | 136.987 | 3400 | 12.5 | 0.0425 | 0.171234 | 0.171234 | Component Quantities - Projected Component Area (Net): 13.6987 m2; Projected Component Area (Gross): 13.6987 m2; Component Thickness: 12.5 mm; Material Properties - Gipsplaat, ThermalConductivity: 0.23; Gipsplaat, SpecificHeatCapacity: 840 J/kg/K; Gipsplaat, MassDensity: 800 kg/m3; Gipsplaat, Embodied Energy: 6.75 (MJ/kg); Gipsplaat, Embodied Carbon: 0.38 (kgCO₂/kg); Gipsplaat, Name: Gipsplaat; Gipsplaat, Participates in Collision Detection: yes
Isolatie - Steenwol LSW | Begane grond | Isolatie - Steenwol LSW | 39.9813 | 3400 | 50 | 0.17 | 0.726932 | 0.726932 | Component Quantities - Projected Component Area (Net): 14.5387 m2; Projected Component Area (Gross): 14.5387 m2; Component Thickness: 50 mm; Material Properties - Isolatie - Steenwol LSW, ThermalConductivity: 0.039; Isolatie - Steenwol LSW, SpecificHeatCapacity: 840 J/kg/K; Isolatie - Steenwol LSW, MassDensity: 55 kg/m3; Isolatie - Steenwol LSW, Embodied Energy: 16.8 (MJ/kg); Isolatie - Steenwol LSW, Embodied Carbon: 1.05 (kgCO₂/kg); Isolatie - Steenwol LSW, Name: Isolatie - Steenwol LSW; Isolatie - Steenwol LSW, Participates in Collision Detection: yes
Gipsplaat | Begane grond | Gipsplaat | 140.812 | 3400 | 12.5 | 0.0425 | 0.176015 | 0.176015 | Component Quantities - Projected Component Area (Net): 14.0812 m2; Projected Component Area (Gross): 14.0812 m2; Component Thickness: 12.5 mm; Material Properties - Gipsplaat, ThermalConductivity: 0.23; Gipsplaat, SpecificHeatCapacity: 840 J/kg/K; Gipsplaat, MassDensity: 800 kg/m3; Gipsplaat, Embodied Energy: 6.75 (MJ/kg); Gipsplaat, Embodied Carbon: 0.38 (kgCO₂/kg); Gipsplaat, Name: Gipsplaat; Gipsplaat, Participates in Collision Detection: yes
Gipsplaat | Begane grond | Gipsplaat | 139.112 | 3400 | 12.5 | 0.0425 | 0.17389 | 0.17389 | Component Quantities - Projected Component Area (Net): 13.9112 m2; Projected Component Area (Gross): 13.9112 m2; Component Thickness: 12.5 mm; Material Properties - Gipsplaat, ThermalConductivity: 0.23; Gipsplaat, SpecificHeatCapacity: 840 J/kg/K; Gipsplaat, MassDensity: 800 kg/m3; Gipsplaat, Embodied Energy: 6.75 (MJ/kg); Gipsplaat, Embodied Carbon: 0.38 (kgCO₂/kg); Gipsplaat, Name: Gipsplaat; Gipsplaat, Participates in Collision Detection: yes
Membraan - dampopen | Begane grond | Membraan - dampopen | 86.8289 | 4235 | 2 | 0.00847 | 0.0954164 | 0.115531 | Component Quantities - Projected Component Area (Net): 47.7082 m2; Projected Component Area (Gross): 57.7654 m2; Component Thickness: 2 mm; Material Properties - Membraan - dampopen, ThermalConductivity: 0.22; Membraan - dampopen, SpecificHeatCapacity: 1800 J/kg/K; Membraan - dampopen, MassDensity: 910 kg/m3; Membraan - dampopen, Embodied Energy: 99.2 (MJ/kg); Membraan - dampopen, Embodied Carbon: 3.43 (kgCO₂/kg); Membraan - dampopen, Name: Membraan - dampopen; Membraan - dampopen, Participates in Collision Detection: yes
Isolatie - Steenwol hard | Begane grond | Isolatie - Steenwol hard | 229.65 | 4235 | 30 | 0.12705 | 1.43531 | 1.73703 | Component Quantities - Projected Component Area (Net): 47.8437 m2; Projected Component Area (Gross): 57.9009 m2; Component Thickness: 30 mm; Material Properties - Isolatie - Steenwol hard, ThermalConductivity: 0.043; Isolatie - Steenwol hard, SpecificHeatCapacity: 840 J/kg/K; Isolatie - Steenwol hard, MassDensity: 160 kg/m3; Isolatie - Steenwol hard, Embodied Energy: 16.8 (MJ/kg); Isolatie - Steenwol hard, Embodied Carbon: 1.05 (kgCO₂/kg); Isolatie - Steenwol hard, Name: Isolatie - Steenwol hard; Isolatie - Steenwol hard, Participates in Collision Detection: yes
Isolatie - Steenwol zacht | Begane grond | Isolatie - Steenwol zacht | 378.718 | 4235 | 180 | 0.7623 | 8.41595 | 10.5091 | Component Quantities - Projected Component Area (Net): 48.7156 m2; Projected Component Area (Gross): 58.3837 m2; Component Thickness: 180 mm; Material Properties - Isolatie - Steenwol zacht, ThermalConductivity: 0.035; Isolatie - Steenwol zacht, SpecificHeatCapacity: 840 J/kg/K; Isolatie - Steenwol zacht, MassDensity: 45 kg/m3; Isolatie - Steenwol zacht, Embodied Energy: 16.8 (MJ/kg); Isolatie - Steenwol zacht, Embodied Carbon: 1.05 (kgCO₂/kg); Isolatie - Steenwol zacht, Name: Isolatie - Steenwol zacht; Isolatie - Steenwol zacht, Participates in Collision Detection: yes
Hout - Multiplex | Begane grond | Hout - Multiplex | 467.816 | 4235 | 18 | 0.07623 | 0.668309 | 1.02804 | Component Quantities - Projected Component Area (Net): 37.1283 m2; Projected Component Area (Gross): 57.1132 m2; Component Thickness: 18 mm; Material Properties - Hout - Multiplex, ThermalConductivity: 0.17; Hout - Multiplex, SpecificHeatCapacity: 1600 J/kg/K; Hout - Multiplex, MassDensity: 700 kg/m3; Hout - Multiplex, Embodied Energy: 15 (MJ/kg); Hout - Multiplex, Embodied Carbon: 0.77 (kgCO₂/kg); Hout - Multiplex, Name: Hout - Multiplex; Hout - Multiplex, Participates in Collision Detection: yes
Membraan - dampdicht | Begane grond | Membraan - dampdicht | 50.6801 | 4235 | 1.5 | 0.0063525 | 0.0556924 | 0.0856698 | Component Quantities - Projected Component Area (Net): 37.1283 m2; Projected Component Area (Gross): 57.1132 m2; Component Thickness: 1.5 mm; Material Properties - Membraan - dampdicht, ThermalConductivity: 0.22; Membraan - dampdicht, SpecificHeatCapacity: 1800 J/kg/K; Membraan - dampdicht, MassDensity: 910 kg/m3; Membraan - dampdicht, Embodied Energy: 99.2 (MJ/kg); Membraan - dampdicht, Embodied Carbon: 3.43 (kgCO₂/kg); Membraan - dampdicht, Name: Membraan - dampdicht; Membraan - dampdicht, Participates in Collision Detection: yes
ALG - BINNENAFWERKING | Begane grond | ALG - BINNENAFWERKING | 371.283 | 4235 | 12.5 | 0.0529375 | 0.464104 | 0.713915 | Component Quantities - Projected Component Area (Net): 37.1283 m2; Projected Component Area (Gross): 57.1132 m2; Component Thickness: 12.5 mm; Material Properties - ALG - BINNENAFWERKING, ThermalConductivity: 0.27; ALG - BINNENAFWERKING, SpecificHeatCapacity: 840 J/kg/K; ALG - BINNENAFWERKING, MassDensity: 800 kg/m3; ALG - BINNENAFWERKING, Embodied Energy: 2 (MJ/kg); ALG - BINNENAFWERKING, Embodied Carbon: 0.13 (kgCO₂/kg); ALG - BINNENAFWERKING, Name: ALG - BINNENAFWERKING; ALG - BINNENAFWERKING, Participates in Collision Detection: yes
Gipsplaat | Begane grond | Gipsplaat | 17.14 | 3470 | 12.5 | 0.043375 | 0.021425 | 0.374994 | Component Quantities - Projected Component Area (Net): 1.714 m2; Projected Component Area (Gross): 29.9995 m2; Component Thickness: 12.5 mm; Material Properties - Gipsplaat, ThermalConductivity: 0.23; Gipsplaat, SpecificHeatCapacity: 840 J/kg/K; Gipsplaat, MassDensity: 800 kg/m3; Gipsplaat, Embodied Energy: 6.75 (MJ/kg); Gipsplaat, Embodied Carbon: 0.38 (kgCO₂/kg); Gipsplaat, Name: Gipsplaat; Gipsplaat, Participates in Collision Detection: yes
Gipsplaat | Begane grond | Gipsplaat | 17.9875 | 3470 | 12.5 | 0.043375 | 0.0224844 | 0.376053 | Component Quantities - Projected Component Area (Net): 1.79875 m2; Projected Component Area (Gross): 30.0843 m2; Component Thickness: 12.5 mm; Material Properties - Gipsplaat, ThermalConductivity: 0.23; Gipsplaat, SpecificHeatCapacity: 840 J/kg/K; Gipsplaat, MassDensity: 800 kg/m3; Gipsplaat, Embodied Energy: 6.75 (MJ/kg); Gipsplaat, Embodied Carbon: 0.38 (kgCO₂/kg); Gipsplaat, Name: Gipsplaat; Gipsplaat, Participates in Collision Detection: yes
Isolatie - Steenwol LSW | Begane grond | Isolatie - Steenwol LSW | 6.11187 | 3470 | 50 | 0.1735 | 0.111125 | 1.5254 | Component Quantities - Projected Component Area (Net): 2.2225 m2; Projected Component Area (Gross): 30.508 m2; Component Thickness: 50 mm; Material Properties - Isolatie - Steenwol LSW, ThermalConductivity: 0.039; Isolatie - Steenwol LSW, SpecificHeatCapacity: 840 J/kg/K; Isolatie - Steenwol LSW, MassDensity: 55 kg/m3; Isolatie - Steenwol LSW, Embodied Energy: 16.8 (MJ/kg); Isolatie - Steenwol LSW, Embodied Carbon: 1.05 (kgCO₂/kg); Isolatie - Steenwol LSW, Name: Isolatie - Steenwol LSW; Isolatie - Steenwol LSW, Participates in Collision Detection: yes
Gipsplaat | Begane grond | Gipsplaat | 23.4962 | 3470 | 12.5 | 0.043375 | 0.0293703 | 0.382939 | Component Quantities - Projected Component Area (Net): 2.34962 m2; Projected Component Area (Gross): 30.6352 m2; Component Thickness: 12.5 mm; Material Properties - Gipsplaat, ThermalConductivity: 0.23; Gipsplaat, SpecificHeatCapacity: 840 J/kg/K; Gipsplaat, MassDensity: 800 kg/m3; Gipsplaat, Embodied Energy: 6.75 (MJ/kg); Gipsplaat, Embodied Carbon: 0.38 (kgCO₂/kg); Gipsplaat, Name: Gipsplaat; Gipsplaat, Participates in Collision Detection: yes
Gipsplaat | Begane grond | Gipsplaat | 23.4963 | 3470 | 12.5 | 0.043375 | 0.0293703 | 0.382939 | Component Quantities - Projected Component Area (Net): 2.34962 m2; Projected Component Area (Gross): 30.6352 m2; Component Thickness: 12.5 mm; Material Properties - Gipsplaat, ThermalConductivity: 0.23; Gipsplaat, SpecificHeatCapacity: 840 J/kg/K; Gipsplaat, MassDensity: 800 kg/m3; Gipsplaat, Embodied Energy: 6.75 (MJ/kg); Gipsplaat, Embodied Carbon: 0.38 (kgCO₂/kg); Gipsplaat, Name: Gipsplaat; Gipsplaat, Participates in Collision Detection: yes
Gipsplaat | Begane grond | Gipsplaat | 103.276 | 3400 | 12.5 | 0.0425 | 0.129096 | 0.159818 | Component Quantities - Projected Component Area (Net): 10.3276 m2; Projected Component Area (Gross): 12.7855 m2; Component Thickness: 12.5 mm; Material Properties - Gipsplaat, ThermalConductivity: 0.23; Gipsplaat, SpecificHeatCapacity: 840 J/kg/K; Gipsplaat, MassDensity: 800 kg/m3; Gipsplaat, Embodied Energy: 6.75 (MJ/kg); Gipsplaat, Embodied Carbon: 0.38 (kgCO₂/kg); Gipsplaat, Name: Gipsplaat; Gipsplaat, Participates in Collision Detection: yes
Gipsplaat | Begane grond | Gipsplaat | 102.436 | 3400 | 12.5 | 0.0425 | 0.128046 | 0.158768 | Component Quantities - Projected Component Area (Net): 10.2436 m2; Projected Component Area (Gross): 12.7015 m2; Component Thickness: 12.5 mm; Material Properties - Gipsplaat, ThermalConductivity: 0.23; Gipsplaat, SpecificHeatCapacity: 840 J/kg/K; Gipsplaat, MassDensity: 800 kg/m3; Gipsplaat, Embodied Energy: 6.75 (MJ/kg); Gipsplaat, Embodied Carbon: 0.38 (kgCO₂/kg); Gipsplaat, Name: Gipsplaat; Gipsplaat, Participates in Collision Detection: yes
Isolatie - Steenwol LSW | Begane grond | Isolatie - Steenwol LSW | 27.5884 | 3400 | 50 | 0.17 | 0.501607 | 0.624498 | Component Quantities - Projected Component Area (Net): 10.0321 m2; Projected Component Area (Gross): 12.49 m2; Component Thickness: 50 mm; Material Properties - Isolatie - Steenwol LSW, ThermalConductivity: 0.039; Isolatie - Steenwol LSW, SpecificHeatCapacity: 840 J/kg/K; Isolatie - Steenwol LSW, MassDensity: 55 kg/m3; Isolatie - Steenwol LSW, Embodied Energy: 16.8 (MJ/kg); Isolatie - Steenwol LSW, Embodied Carbon: 1.05 (kgCO₂/kg); Isolatie - Steenwol LSW, Name: Isolatie - Steenwol LSW; Isolatie - Steenwol LSW, Participates in Collision Detection: yes
Gipsplaat | Begane grond | Gipsplaat | 94.9165 | 3400 | 12.5 | 0.0425 | 0.118646 | 0.149368 | Component Quantities - Projected Component Area (Net): 9.49165 m2; Projected Component Area (Gross): 11.9495 m2; Component Thickness: 12.5 mm; Material Properties - Gipsplaat, ThermalConductivity: 0.23; Gipsplaat, SpecificHeatCapacity: 840 J/kg/K; Gipsplaat, MassDensity: 800 kg/m3; Gipsplaat, Embodied Energy: 6.75 (MJ/kg); Gipsplaat, Embodied Carbon: 0.38 (kgCO₂/kg); Gipsplaat, Name: Gipsplaat; Gipsplaat, Participates in Collision Detection: yes
Gipsplaat | Begane grond | Gipsplaat | 94.0765 | 3400 | 12.5 | 0.0425 | 0.117596 | 0.148318 | Component Quantities - Projected Component Area (Net): 9.40765 m2; Projected Component Area (Gross): 11.8655 m2; Component Thickness: 12.5 mm; Material Properties - Gipsplaat, ThermalConductivity: 0.23; Gipsplaat, SpecificHeatCapacity: 840 J/kg/K; Gipsplaat, MassDensity: 800 kg/m3; Gipsplaat, Embodied Energy: 6.75 (MJ/kg); Gipsplaat, Embodied Carbon: 0.38 (kgCO₂/kg); Gipsplaat, Name: Gipsplaat; Gipsplaat, Participates in Collision Detection: yes
Gipsplaat | Begane grond | Gipsplaat | 95.2 | 3400 | 12.5 | 0.0425 | 0.119 | 0.119 | Component Quantities - Projected Component Area (Net): 9.52 m2; Projected Component Area (Gross): 9.52 m2; Component Thickness: 12.5 mm; Material Properties - Gipsplaat, ThermalConductivity: 0.23; Gipsplaat, SpecificHeatCapacity: 840 J/kg/K; Gipsplaat, MassDensity: 800 kg/m3; Gipsplaat, Embodied Energy: 6.75 (MJ/kg); Gipsplaat, Embodied Carbon: 0.38 (kgCO₂/kg); Gipsplaat, Name: Gipsplaat; Gipsplaat, Participates in Collision Detection: yes
Gipsplaat | Begane grond | Gipsplaat | 94.7248 | 3400 | 12.5 | 0.0425 | 0.118406 | 0.118406 | Component Quantities - Projected Component Area (Net): 9.5625 m2; Projected Component Area (Gross): 9.5625 m2; Component Thickness: 12.5 mm; Material Properties - Gipsplaat, ThermalConductivity: 0.23; Gipsplaat, SpecificHeatCapacity: 840 J/kg/K; Gipsplaat, MassDensity: 800 kg/m3; Gipsplaat, Embodied Energy: 6.75 (MJ/kg); Gipsplaat, Embodied Carbon: 0.38 (kgCO₂/kg); Gipsplaat, Name: Gipsplaat; Gipsplaat, Participates in Collision Detection: yes
Isolatie - Steenwol LSW | Begane grond | Isolatie - Steenwol LSW | 25.7922 | 3400 | 50 | 0.17 | 0.46895 | 0.46895 | Component Quantities - Projected Component Area (Net): 9.379 m2; Projected Component Area (Gross): 9.379 m2; Component Thickness: 50 mm; Material Properties - Isolatie - Steenwol LSW, ThermalConductivity: 0.039; Isolatie - Steenwol LSW, SpecificHeatCapacity: 840 J/kg/K; Isolatie - Steenwol LSW, MassDensity: 55 kg/m3; Isolatie - Steenwol LSW, Embodied Energy: 16.8 (MJ/kg); Isolatie - Steenwol LSW, Embodied Carbon: 1.05 (kgCO₂/kg); Isolatie - Steenwol LSW, Name: Isolatie - Steenwol LSW; Isolatie - Steenwol LSW, Participates in Collision Detection: yes
Gipsplaat | Begane grond | Gipsplaat | 67.185 | 3400 | 12.5 | 0.0425 | 0.0839812 | 0.0839812 | Component Quantities - Projected Component Area (Net): 6.7185 m2; Projected Component Area (Gross): 6.7185 m2; Component Thickness: 12.5 mm; Material Properties - Gipsplaat, ThermalConductivity: 0.23; Gipsplaat, SpecificHeatCapacity: 840 J/kg/K; Gipsplaat, MassDensity: 800 kg/m3; Gipsplaat, Embodied Energy: 6.75 (MJ/kg); Gipsplaat, Embodied Carbon: 0.38 (kgCO₂/kg); Gipsplaat, Name: Gipsplaat; Gipsplaat, Participates in Collision Detection: yes
Gipsplaat | Begane grond | Gipsplaat | 68.46 | 3400 | 12.5 | 0.0425 | 0.0855749 | 0.0855749 | Component Quantities - Projected Component Area (Net): 6.846 m2; Projected Component Area (Gross): 6.846 m2; Component Thickness: 12.5 mm; Material Properties - Gipsplaat, ThermalConductivity: 0.23; Gipsplaat, SpecificHeatCapacity: 840 J/kg/K; Gipsplaat, MassDensity: 800 kg/m3; Gipsplaat, Embodied Energy: 6.75 (MJ/kg); Gipsplaat, Embodied Carbon: 0.38 (kgCO₂/kg); Gipsplaat, Name: Gipsplaat; Gipsplaat, Participates in Collision Detection: yes
Isolatie - Steenwol LSW | Begane grond | Isolatie - Steenwol LSW | 19.4109 | 3400 | 50 | 0.17 | 0.352925 | 0.352925 | Component Quantities - Projected Component Area (Net): 7.0585 m2; Projected Component Area (Gross): 7.0585 m2; Component Thickness: 50 mm; Material Properties - Isolatie - Steenwol LSW, ThermalConductivity: 0.039; Isolatie - Steenwol LSW, SpecificHeatCapacity: 840 J/kg/K; Isolatie - Steenwol LSW, MassDensity: 55 kg/m3; Isolatie - Steenwol LSW, Embodied Energy: 16.8 (MJ/kg); Isolatie - Steenwol LSW, Embodied Carbon: 1.05 (kgCO₂/kg); Isolatie - Steenwol LSW, Name: Isolatie - Steenwol LSW; Isolatie - Steenwol LSW, Participates in Collision Detection: yes
Gipsplaat | Begane grond | Gipsplaat | 72.285 | 3400 | 12.5 | 0.0425 | 0.0903562 | 0.0903562 | Component Quantities - Projected Component Area (Net): 7.2285 m2; Projected Component Area (Gross): 7.2285 m2; Component Thickness: 12.5 mm; Material Properties - Gipsplaat, ThermalConductivity: 0.23; Gipsplaat, SpecificHeatCapacity: 840 J/kg/K; Gipsplaat, MassDensity: 800 kg/m3; Gipsplaat, Embodied Energy: 6.75 (MJ/kg); Gipsplaat, Embodied Carbon: 0.38 (kgCO₂/kg); Gipsplaat, Name: Gipsplaat; Gipsplaat, Participates in Collision Detection: yes
Gipsplaat | Begane grond | Gipsplaat | 72.71 | 3400 | 12.5 | 0.0425 | 0.0908874 | 0.0908874 | Component Quantities - Projected Component Area (Net): 7.271 m2; Projected Component Area (Gross): 7.271 m2; Component Thickness: 12.5 mm; Material Properties - Gipsplaat, ThermalConductivity: 0.23; Gipsplaat, SpecificHeatCapacity: 840 J/kg/K; Gipsplaat, MassDensity: 800 kg/m3; Gipsplaat, Embodied Energy: 6.75 (MJ/kg); Gipsplaat, Embodied Carbon: 0.38 (kgCO₂/kg); Gipsplaat, Name: Gipsplaat; Gipsplaat, Participates in Collision Detection: yes
Steen - Baksteen AFW | Begane grond | Steen - Baksteen AFW | 1580.06 | 4235 | 100 | 0.4235 | 0.987538 | 4.80715 | Component Quantities - Projected Component Area (Net): 9.87538 m2; Projected Component Area (Gross): 48.0715 m2; Component Thickness: 100 mm; Material Properties - Steen - Baksteen AFW, ThermalConductivity: 0.9; Steen - Baksteen AFW, SpecificHeatCapacity: 840 J/kg/K; Steen - Baksteen AFW, MassDensity: 1600 kg/m3; Steen - Baksteen AFW, Embodied Energy: 3 (MJ/kg); Steen - Baksteen AFW, Embodied Carbon: 0.23 (kgCO₂/kg); Steen - Baksteen AFW, Name: Steen - Baksteen AFW; Steen - Baksteen AFW, Participates in Collision Detection: yes
ALG - ISOLATIE | Begane grond | ALG - ISOLATIE | 315.278 | 4235 | 150 | 0.63525 | 7.00618 | 7.00618 | Component Quantities - Projected Component Area (Net): 46.7079 m2; Projected Component Area (Gross): 46.7079 m2; Component Thickness: 150 mm; Material Properties - ALG - ISOLATIE, ThermalConductivity: 0.035; ALG - ISOLATIE, SpecificHeatCapacity: 840 J/kg/K; ALG - ISOLATIE, MassDensity: 45 kg/m3; ALG - ISOLATIE, Embodied Energy: 16.8 (MJ/kg); ALG - ISOLATIE, Embodied Carbon: 1.05 (kgCO₂/kg); ALG - ISOLATIE, Name: ALG - ISOLATIE; ALG - ISOLATIE, Participates in Collision Detection: yes
Steen - Betonblok C | Begane grond | Steen - Betonblok C | 10627.8 | 4235 | 200 | 0.847 | 6.64239 | 9.04512 | Component Quantities - Projected Component Area (Net): 33.2119 m2; Projected Component Area (Gross): 45.2256 m2; Component Thickness: 200 mm; Material Properties - Steen - Betonblok C, ThermalConductivity: 0.75; Steen - Betonblok C, SpecificHeatCapacity: 840 J/kg/K; Steen - Betonblok C, MassDensity: 1600 kg/m3; Steen - Betonblok C, Embodied Energy: 0.83 (MJ/kg); Steen - Betonblok C, Embodied Carbon: 0.1 (kgCO₂/kg); Steen - Betonblok C, Name: Steen - Betonblok C; Steen - Betonblok C, Participates in Collision Detection: yes
Gipsplaat | Begane grond | Gipsplaat | 148.356 | 3470 | 12.5 | 0.043375 | 0.185445 | 0.185445 | Component Quantities - Projected Component Area (Net): 14.8356 m2; Projected Component Area (Gross): 14.8356 m2; Component Thickness: 12.5 mm; Material Properties - Gipsplaat, ThermalConductivity: 0.23; Gipsplaat, SpecificHeatCapacity: 840 J/kg/K; Gipsplaat, MassDensity: 800 kg/m3; Gipsplaat, Embodied Energy: 6.75 (MJ/kg); Gipsplaat, Embodied Carbon: 0.38 (kgCO₂/kg); Gipsplaat, Name: Gipsplaat; Gipsplaat, Participates in Collision Detection: yes
2 x Gipsplaat | Begane grond | Gipsplaat | 148.779 | 3470 | 12.5 | 0.043375 | 0.185974 | 0.185974 | Component Quantities - Projected Component Area (Net): 14.8779 m2; Projected Component Area (Gross): 14.8779 m2; Component Thickness: 12.5 mm; Material Properties - Gipsplaat, ThermalConductivity: 0.23; Gipsplaat, SpecificHeatCapacity: 840 J/kg/K; Gipsplaat, MassDensity: 800 kg/m3; Gipsplaat, Embodied Energy: 6.75 (MJ/kg); Gipsplaat, Embodied Carbon: 0.38 (kgCO₂/kg); Gipsplaat, Name: Gipsplaat; Gipsplaat, Participates in Collision Detection: yes
Isolatie - Steenwol LSW | Begane grond | Isolatie - Steenwol LSW | 41.0309 | 3470 | 50 | 0.1735 | 0.746016 | 0.746016 | Component Quantities - Projected Component Area (Net): 14.9203 m2; Projected Component Area (Gross): 14.9203 m2; Component Thickness: 50 mm; Material Properties - Isolatie - Steenwol LSW, ThermalConductivity: 0.039; Isolatie - Steenwol LSW, SpecificHeatCapacity: 840 J/kg/K; Isolatie - Steenwol LSW, MassDensity: 55 kg/m3; Isolatie - Steenwol LSW, Embodied Energy: 16.8 (MJ/kg); Isolatie - Steenwol LSW, Embodied Carbon: 1.05 (kgCO₂/kg); Isolatie - Steenwol LSW, Name: Isolatie - Steenwol LSW; Isolatie - Steenwol LSW, Participates in Collision Detection: yes
Gipsplaat | Begane grond | Gipsplaat | 147.931 | 3470 | 12.5 | 0.043375 | 0.184913 | 0.184913 | Component Quantities - Projected Component Area (Net): 14.7931 m2; Projected Component Area (Gross): 14.7931 m2; Component Thickness: 12.5 mm; Material Properties - Gipsplaat, ThermalConductivity: 0.23; Gipsplaat, SpecificHeatCapacity: 840 J/kg/K; Gipsplaat, MassDensity: 800 kg/m3; Gipsplaat, Embodied Energy: 6.75 (MJ/kg); Gipsplaat, Embodied Carbon: 0.38 (kgCO₂/kg); Gipsplaat, Name: Gipsplaat; Gipsplaat, Participates in Collision Detection: yes
Steen - Kalkzandsteen C | Begane grond | Steen - Kalkzandsteen C | 10275.6 | 4235 | 150 | 0.63525 | 5.40821 | 11.7153 | Component Quantities - Projected Component Area (Net): 36.0547 m2; Projected Component Area (Gross): 78.1019 m2; Component Thickness: 150 mm; Material Properties - Steen - Kalkzandsteen C, ThermalConductivity: 0.9; Steen - Kalkzandsteen C, SpecificHeatCapacity: 840 J/kg/K; Steen - Kalkzandsteen C, MassDensity: 1900 kg/m3; Steen - Kalkzandsteen C, Embodied Energy: 0.75 (MJ/kg); Steen - Kalkzandsteen C, Embodied Carbon: 0.1 (kgCO₂/kg); Steen - Kalkzandsteen C, Name: Steen - Kalkzandsteen C; Steen - Kalkzandsteen C, Participates in Collision Detection: yes
ALG - ISOLATIE | Begane grond | ALG - ISOLATIE | 349.319 | 4235 | 150 | 0.63525 | 7.76264 | 12.0825 | Component Quantities - Projected Component Area (Net): 52.6107 m2; Projected Component Area (Gross): 80.5497 m2; Component Thickness: 150 mm; Material Properties - ALG - ISOLATIE, ThermalConductivity: 0.035; ALG - ISOLATIE, SpecificHeatCapacity: 840 J/kg/K; ALG - ISOLATIE, MassDensity: 45 kg/m3; ALG - ISOLATIE, Embodied Energy: 16.8 (MJ/kg); ALG - ISOLATIE, Embodied Carbon: 1.05 (kgCO₂/kg); ALG - ISOLATIE, Name: ALG - ISOLATIE; ALG - ISOLATIE, Participates in Collision Detection: yes
Steen - Baksteen AFW | Begane grond | Steen - Baksteen AFW | 4225.76 | 4235 | 100 | 0.4235 | 2.6411 | 8.1744 | Component Quantities - Projected Component Area (Net): 26.4298 m2; Projected Component Area (Gross): 81.744 m2; Component Thickness: 100 mm; Material Properties - Steen - Baksteen AFW, ThermalConductivity: 0.9; Steen - Baksteen AFW, SpecificHeatCapacity: 840 J/kg/K; Steen - Baksteen AFW, MassDensity: 1600 kg/m3; Steen - Baksteen AFW, Embodied Energy: 3 (MJ/kg); Steen - Baksteen AFW, Embodied Carbon: 0.23 (kgCO₂/kg); Steen - Baksteen AFW, Name: Steen - Baksteen AFW; Steen - Baksteen AFW, Participates in Collision Detection: yes
Steen - Kalkzandsteen C | Begane grond | Steen - Kalkzandsteen C | 3002.25 | 4235 | 150 | 0.63525 | 1.58013 | 3.71878 | Component Quantities - Projected Component Area (Net): 10.5342 m2; Projected Component Area (Gross): 24.7918 m2; Component Thickness: 150 mm; Material Properties - Steen - Kalkzandsteen C, ThermalConductivity: 0.9; Steen - Kalkzandsteen C, SpecificHeatCapacity: 840 J/kg/K; Steen - Kalkzandsteen C, MassDensity: 1900 kg/m3; Steen - Kalkzandsteen C, Embodied Energy: 0.75 (MJ/kg); Steen - Kalkzandsteen C, Embodied Carbon: 0.1 (kgCO₂/kg); Steen - Kalkzandsteen C, Name: Steen - Kalkzandsteen C; Steen - Kalkzandsteen C, Participates in Collision Detection: yes
ALG - ISOLATIE | Begane grond | ALG - ISOLATIE | 95.22 | 4235 | 150 | 0.63525 | 2.116 | 3.62349 | Component Quantities - Projected Component Area (Net): 14.3773 m2; Projected Component Area (Gross): 24.1566 m2; Component Thickness: 150 mm; Material Properties - ALG - ISOLATIE, ThermalConductivity: 0.035; ALG - ISOLATIE, SpecificHeatCapacity: 840 J/kg/K; ALG - ISOLATIE, MassDensity: 45 kg/m3; ALG - ISOLATIE, Embodied Energy: 16.8 (MJ/kg); ALG - ISOLATIE, Embodied Carbon: 1.05 (kgCO₂/kg); ALG - ISOLATIE, Name: ALG - ISOLATIE; ALG - ISOLATIE, Participates in Collision Detection: yes
Isolatie - Steenwol hard | Begane grond | Isolatie - Steenwol hard | 61.0255 | 4235 | 30 | 0.12705 | 0.381409 | 0.686583 | Component Quantities - Projected Component Area (Net): 12.7136 m2; Projected Component Area (Gross): 22.8861 m2; Component Thickness: 30 mm; Material Properties - Isolatie - Steenwol hard, ThermalConductivity: 0.043; Isolatie - Steenwol hard, SpecificHeatCapacity: 840 J/kg/K; Isolatie - Steenwol hard, MassDensity: 160 kg/m3; Isolatie - Steenwol hard, Embodied Energy: 16.8 (MJ/kg); Isolatie - Steenwol hard, Embodied Carbon: 1.05 (kgCO₂/kg); Isolatie - Steenwol hard, Name: Isolatie - Steenwol hard; Isolatie - Steenwol hard, Participates in Collision Detection: yes
Membraan - dampopen | Begane grond | Membraan - dampopen | 22.6764 | 4235 | 2 | 0.00847 | 0.0249191 | 0.045264 | Component Quantities - Projected Component Area (Net): 12.4595 m2; Projected Component Area (Gross): 22.632 m2; Component Thickness: 2 mm; Material Properties - Membraan - dampopen, ThermalConductivity: 0.22; Membraan - dampopen, SpecificHeatCapacity: 1800 J/kg/K; Membraan - dampopen, MassDensity: 910 kg/m3; Membraan - dampopen, Embodied Energy: 99.2 (MJ/kg); Membraan - dampopen, Embodied Carbon: 3.43 (kgCO₂/kg); Membraan - dampopen, Name: Membraan - dampopen; Membraan - dampopen, Participates in Collision Detection: yes
Steen - Betonblok C | Begane grond | Steen - Betonblok C | 3158.1 | 4065 | 150 | 0.60975 | 1.97381 | 2.51522 | Component Quantities - Projected Component Area (Net): 13.1588 m2; Projected Component Area (Gross): 16.7681 m2; Component Thickness: 150 mm; Material Properties - Steen - Betonblok C, ThermalConductivity: 0.75; Steen - Betonblok C, SpecificHeatCapacity: 840 J/kg/K; Steen - Betonblok C, MassDensity: 1600 kg/m3; Steen - Betonblok C, Embodied Energy: 0.83 (MJ/kg); Steen - Betonblok C, Embodied Carbon: 0.1 (kgCO₂/kg); Steen - Betonblok C, Name: Steen - Betonblok C; Steen - Betonblok C, Participates in Collision Detection: yes
ALG - ISOLATIE | Begane grond | ALG - ISOLATIE | 109.069 | 4065 | 150 | 0.60975 | 2.42376 | 2.42376 | Component Quantities - Projected Component Area (Net): 16.1584 m2; Projected Component Area (Gross): 16.1584 m2; Component Thickness: 150 mm; Material Properties - ALG - ISOLATIE, ThermalConductivity: 0.035; ALG - ISOLATIE, SpecificHeatCapacity: 840 J/kg/K; ALG - ISOLATIE, MassDensity: 45 kg/m3; ALG - ISOLATIE, Embodied Energy: 16.8 (MJ/kg); ALG - ISOLATIE, Embodied Carbon: 1.05 (kgCO₂/kg); ALG - ISOLATIE, Name: ALG - ISOLATIE; ALG - ISOLATIE, Participates in Collision Detection: yes
Isolatie - Steenwol hard | Begane grond | Isolatie - Steenwol hard | 80.604 | 4065 | 30 | 0.12195 | 0.503775 | 0.503775 | Component Quantities - Projected Component Area (Net): 16.7925 m2; Projected Component Area (Gross): 16.7925 m2; Component Thickness: 30 mm; Material Properties - Isolatie - Steenwol hard, ThermalConductivity: 0.043; Isolatie - Steenwol hard, SpecificHeatCapacity: 840 J/kg/K; Isolatie - Steenwol hard, MassDensity: 160 kg/m3; Isolatie - Steenwol hard, Embodied Energy: 16.8 (MJ/kg); Isolatie - Steenwol hard, Embodied Carbon: 1.05 (kgCO₂/kg); Isolatie - Steenwol hard, Name: Isolatie - Steenwol hard; Isolatie - Steenwol hard, Participates in Collision Detection: yes
Membraan - dampopen | Begane grond | Membraan - dampopen | 30.5476 | 4065 | 2 | 0.00813 | 0.0335688 | 0.0335688 | Component Quantities - Projected Component Area (Net): 16.7844 m2; Projected Component Area (Gross): 16.7844 m2; Component Thickness: 2 mm; Material Properties - Membraan - dampopen, ThermalConductivity: 0.22; Membraan - dampopen, SpecificHeatCapacity: 1800 J/kg/K; Membraan - dampopen, MassDensity: 910 kg/m3; Membraan - dampopen, Embodied Energy: 99.2 (MJ/kg); Membraan - dampopen, Embodied Carbon: 3.43 (kgCO₂/kg); Membraan - dampopen, Name: Membraan - dampopen; Membraan - dampopen, Participates in Collision Detection: yes
2 x Gipsplaat | Begane grond | Gipsplaat | 121.455 | 3470 | 12.5 | 0.043375 | 0.151819 | 0.151819 | Component Quantities - Projected Component Area (Net): 12.1455 m2; Projected Component Area (Gross): 12.1455 m2; Component Thickness: 12.5 mm; Material Properties - Gipsplaat, ThermalConductivity: 0.23; Gipsplaat, SpecificHeatCapacity: 840 J/kg/K; Gipsplaat, MassDensity: 800 kg/m3; Gipsplaat, Embodied Energy: 6.75 (MJ/kg); Gipsplaat, Embodied Carbon: 0.38 (kgCO₂/kg); Gipsplaat, Name: Gipsplaat; Gipsplaat, Participates in Collision Detection: yes
2 x Gipsplaat | Begane grond | Gipsplaat | 121.889 | 3470 | 12.5 | 0.043375 | 0.152361 | 0.152361 | Component Quantities - Projected Component Area (Net): 12.1889 m2; Projected Component Area (Gross): 12.1889 m2; Component Thickness: 12.5 mm; Material Properties - Gipsplaat, ThermalConductivity: 0.23; Gipsplaat, SpecificHeatCapacity: 840 J/kg/K; Gipsplaat, MassDensity: 800 kg/m3; Gipsplaat, Embodied Energy: 6.75 (MJ/kg); Gipsplaat, Embodied Carbon: 0.38 (kgCO₂/kg); Gipsplaat, Name: Gipsplaat; Gipsplaat, Participates in Collision Detection: yes
Isolatie - Steenwol LSW | Begane grond | Isolatie - Steenwol LSW | 33.6387 | 3470 | 50 | 0.1735 | 0.611613 | 0.611613 | Component Quantities - Projected Component Area (Net): 12.2323 m2; Projected Component Area (Gross): 12.2323 m2; Component Thickness: 50 mm; Material Properties - Isolatie - Steenwol LSW, ThermalConductivity: 0.039; Isolatie - Steenwol LSW, SpecificHeatCapacity: 840 J/kg/K; Isolatie - Steenwol LSW, MassDensity: 55 kg/m3; Isolatie - Steenwol LSW, Embodied Energy: 16.8 (MJ/kg); Isolatie - Steenwol LSW, Embodied Carbon: 1.05 (kgCO₂/kg); Isolatie - Steenwol LSW, Name: Isolatie - Steenwol LSW; Isolatie - Steenwol LSW, Participates in Collision Detection: yes
Gipsplaat | Begane grond | Gipsplaat | 120.309 | 3400 | 12.5 | 0.0425 | 0.150386 | 0.150386 | Component Quantities - Projected Component Area (Net): 12.0309 m2; Projected Component Area (Gross): 12.0309 m2; Component Thickness: 12.5 mm; Material Properties - Gipsplaat, ThermalConductivity: 0.23; Gipsplaat, SpecificHeatCapacity: 840 J/kg/K; Gipsplaat, MassDensity: 800 kg/m3; Gipsplaat, Embodied Energy: 6.75 (MJ/kg); Gipsplaat, Embodied Carbon: 0.38 (kgCO₂/kg); Gipsplaat, Name: Gipsplaat; Gipsplaat, Participates in Collision Detection: yes
Gipsplaat | Begane grond | Gipsplaat | 121.57 | 3400 | 12.5 | 0.0425 | 0.151962 | 0.151962 | Component Quantities - Projected Component Area (Net): 12.157 m2; Projected Component Area (Gross): 12.157 m2; Component Thickness: 12.5 mm; Material Properties - Gipsplaat, ThermalConductivity: 0.23; Gipsplaat, SpecificHeatCapacity: 840 J/kg/K; Gipsplaat, MassDensity: 800 kg/m3; Gipsplaat, Embodied Energy: 6.75 (MJ/kg); Gipsplaat, Embodied Carbon: 0.38 (kgCO₂/kg); Gipsplaat, Name: Gipsplaat; Gipsplaat, Participates in Collision Detection: yes
Isolatie - Steenwol LSW | Begane grond | Isolatie - Steenwol LSW | 34.3474 | 3400 | 50 | 0.17 | 0.624498 | 0.624498 | Component Quantities - Projected Component Area (Net): 12.49 m2; Projected Component Area (Gross): 12.49 m2; Component Thickness: 50 mm; Material Properties - Isolatie - Steenwol LSW, ThermalConductivity: 0.039; Isolatie - Steenwol LSW, SpecificHeatCapacity: 840 J/kg/K; Isolatie - Steenwol LSW, MassDensity: 55 kg/m3; Isolatie - Steenwol LSW, Embodied Energy: 16.8 (MJ/kg); Isolatie - Steenwol LSW, Embodied Carbon: 1.05 (kgCO₂/kg); Isolatie - Steenwol LSW, Name: Isolatie - Steenwol LSW; Isolatie - Steenwol LSW, Participates in Collision Detection: yes
Gipsplaat | Begane grond | Gipsplaat | 119.495 | 3400 | 12.5 | 0.0425 | 0.149368 | 0.149368 | Component Quantities - Projected Component Area (Net): 11.9495 m2; Projected Component Area (Gross): 11.9495 m2; Component Thickness: 12.5 mm; Material Properties - Gipsplaat, ThermalConductivity: 0.23; Gipsplaat, SpecificHeatCapacity: 840 J/kg/K; Gipsplaat, MassDensity: 800 kg/m3; Gipsplaat, Embodied Energy: 6.75 (MJ/kg); Gipsplaat, Embodied Carbon: 0.38 (kgCO₂/kg); Gipsplaat, Name: Gipsplaat; Gipsplaat, Participates in Collision Detection: yes
Gipsplaat | Begane grond | Gipsplaat | 118.655 | 3400 | 12.5 | 0.0425 | 0.148318 | 0.148318 | Component Quantities - Projected Component Area (Net): 11.8655 m2; Projected Component Area (Gross): 11.8655 m2; Component Thickness: 12.5 mm; Material Properties - Gipsplaat, ThermalConductivity: 0.23; Gipsplaat, SpecificHeatCapacity: 840 J/kg/K; Gipsplaat, MassDensity: 800 kg/m3; Gipsplaat, Embodied Energy: 6.75 (MJ/kg); Gipsplaat, Embodied Carbon: 0.38 (kgCO₂/kg); Gipsplaat, Name: Gipsplaat; Gipsplaat, Participates in Collision Detection: yes
2 x Gipsplaat | Begane grond | Gipsplaat | 22.5062 | 3470 | 12.5 | 0.043375 | 0.0281328 | 0.09359 | Component Quantities - Projected Component Area (Net): 2.25062 m2; Projected Component Area (Gross): 7.4872 m2; Component Thickness: 12.5 mm; Material Properties - Gipsplaat, ThermalConductivity: 0.23; Gipsplaat, SpecificHeatCapacity: 840 J/kg/K; Gipsplaat, MassDensity: 800 kg/m3; Gipsplaat, Embodied Energy: 6.75 (MJ/kg); Gipsplaat, Embodied Carbon: 0.38 (kgCO₂/kg); Gipsplaat, Name: Gipsplaat; Gipsplaat, Participates in Collision Detection: yes
2 x Gipsplaat | Begane grond | Gipsplaat | 23.3637 | 3470 | 12.5 | 0.043375 | 0.0292046 | 0.0946619 | Component Quantities - Projected Component Area (Net): 2.33637 m2; Projected Component Area (Gross): 7.57295 m2; Component Thickness: 12.5 mm; Material Properties - Gipsplaat, ThermalConductivity: 0.23; Gipsplaat, SpecificHeatCapacity: 840 J/kg/K; Gipsplaat, MassDensity: 800 kg/m3; Gipsplaat, Embodied Energy: 6.75 (MJ/kg); Gipsplaat, Embodied Carbon: 0.38 (kgCO₂/kg); Gipsplaat, Name: Gipsplaat; Gipsplaat, Participates in Collision Detection: yes
Isolatie - Steenwol LSW | Begane grond | Isolatie - Steenwol LSW | 6.66083 | 3470 | 50 | 0.1735 | 0.121106 | 0.382935 | Component Quantities - Projected Component Area (Net): 2.42212 m2; Projected Component Area (Gross): 7.6587 m2; Component Thickness: 50 mm; Material Properties - Isolatie - Steenwol LSW, ThermalConductivity: 0.039; Isolatie - Steenwol LSW, SpecificHeatCapacity: 840 J/kg/K; Isolatie - Steenwol LSW, MassDensity: 55 kg/m3; Isolatie - Steenwol LSW, Embodied Energy: 16.8 (MJ/kg); Isolatie - Steenwol LSW, Embodied Carbon: 1.05 (kgCO₂/kg); Isolatie - Steenwol LSW, Name: Isolatie - Steenwol LSW; Isolatie - Steenwol LSW, Participates in Collision Detection: yes
Steen - Kalkzandsteen C | Begane grond | Steen - Kalkzandsteen C | 28790.4 | 4235 | 214 | 0.90629 | 15.1529 | 29.3004 | Component Quantities - Projected Component Area (Net): 70.8074 m2; Projected Component Area (Gross): 136.918 m2; Component Thickness: 214 mm; Material Properties - Steen - Kalkzandsteen C, ThermalConductivity: 0.9; Steen - Kalkzandsteen C, SpecificHeatCapacity: 840 J/kg/K; Steen - Kalkzandsteen C, MassDensity: 1900 kg/m3; Steen - Kalkzandsteen C, Embodied Energy: 0.75 (MJ/kg); Steen - Kalkzandsteen C, Embodied Carbon: 0.1 (kgCO₂/kg); Steen - Kalkzandsteen C, Name: Steen - Kalkzandsteen C; Steen - Kalkzandsteen C, Participates in Collision Detection: yes
ALG - ISOLATIE | Begane grond | ALG - ISOLATIE | 660.621 | 4235 | 150 | 0.63525 | 14.6805 | 20.7282 | Component Quantities - Projected Component Area (Net): 99.0734 m2; Projected Component Area (Gross): 138.188 m2; Component Thickness: 150 mm; Material Properties - ALG - ISOLATIE, ThermalConductivity: 0.035; ALG - ISOLATIE, SpecificHeatCapacity: 840 J/kg/K; ALG - ISOLATIE, MassDensity: 45 kg/m3; ALG - ISOLATIE, Embodied Energy: 16.8 (MJ/kg); ALG - ISOLATIE, Embodied Carbon: 1.05 (kgCO₂/kg); ALG - ISOLATIE, Name: ALG - ISOLATIE; ALG - ISOLATIE, Participates in Collision Detection: yes
Steen - Baksteen AFW | Begane grond | Steen - Baksteen AFW | 8615.51 | 4235 | 100 | 0.4235 | 5.38469 | 13.934 | Component Quantities - Projected Component Area (Net): 53.8469 m2; Projected Component Area (Gross): 139.34 m2; Component Thickness: 100 mm; Material Properties - Steen - Baksteen AFW, ThermalConductivity: 0.9; Steen - Baksteen AFW, SpecificHeatCapacity: 840 J/kg/K; Steen - Baksteen AFW, MassDensity: 1600 kg/m3; Steen - Baksteen AFW, Embodied Energy: 3 (MJ/kg); Steen - Baksteen AFW, Embodied Carbon: 0.23 (kgCO₂/kg); Steen - Baksteen AFW, Name: Steen - Baksteen AFW; Steen - Baksteen AFW, Participates in Collision Detection: yes
Gipsplaat | Begane grond | Gipsplaat | 494.65 | 3470 | 12.5 | 0.043375 | 0.618313 | 0.965315 | Component Quantities - Projected Component Area (Net): 49.465 m2; Projected Component Area (Gross): 77.2252 m2; Component Thickness: 12.5 mm; Material Properties - Gipsplaat, ThermalConductivity: 0.23; Gipsplaat, SpecificHeatCapacity: 840 J/kg/K; Gipsplaat, MassDensity: 800 kg/m3; Gipsplaat, Embodied Energy: 6.75 (MJ/kg); Gipsplaat, Embodied Carbon: 0.38 (kgCO₂/kg); Gipsplaat, Name: Gipsplaat; Gipsplaat, Participates in Collision Detection: yes
Gipsplaat | Begane grond | Gipsplaat | 496.345 | 3470 | 12.5 | 0.043375 | 0.620431 | 0.967434 | Component Quantities - Projected Component Area (Net): 49.6345 m2; Projected Component Area (Gross): 77.3947 m2; Component Thickness: 12.5 mm; Material Properties - Gipsplaat, ThermalConductivity: 0.23; Gipsplaat, SpecificHeatCapacity: 840 J/kg/K; Gipsplaat, MassDensity: 800 kg/m3; Gipsplaat, Embodied Energy: 6.75 (MJ/kg); Gipsplaat, Embodied Carbon: 0.38 (kgCO₂/kg); Gipsplaat, Name: Gipsplaat; Gipsplaat, Participates in Collision Detection: yes
Isolatie - Steenwol LSW | Begane grond | Isolatie - Steenwol LSW | 137.353 | 3470 | 50 | 0.1735 | 2.49732 | 3.88533 | Component Quantities - Projected Component Area (Net): 49.9735 m2; Projected Component Area (Gross): 77.7337 m2; Component Thickness: 50 mm; Material Properties - Isolatie - Steenwol LSW, ThermalConductivity: 0.039; Isolatie - Steenwol LSW, SpecificHeatCapacity: 840 J/kg/K; Isolatie - Steenwol LSW, MassDensity: 55 kg/m3; Isolatie - Steenwol LSW, Embodied Energy: 16.8 (MJ/kg); Isolatie - Steenwol LSW, Embodied Carbon: 1.05 (kgCO₂/kg); Isolatie - Steenwol LSW, Name: Isolatie - Steenwol LSW; Isolatie - Steenwol LSW, Participates in Collision Detection: yes
Gipsplaat | Begane grond | Gipsplaat | 496.38 | 3470 | 12.5 | 0.043375 | 0.620475 | 0.967477 | Component Quantities - Projected Component Area (Net): 49.638 m2; Projected Component Area (Gross): 77.3982 m2; Component Thickness: 12.5 mm; Material Properties - Gipsplaat, ThermalConductivity: 0.23; Gipsplaat, SpecificHeatCapacity: 840 J/kg/K; Gipsplaat, MassDensity: 800 kg/m3; Gipsplaat, Embodied Energy: 6.75 (MJ/kg); Gipsplaat, Embodied Carbon: 0.38 (kgCO₂/kg); Gipsplaat, Name: Gipsplaat; Gipsplaat, Participates in Collision Detection: yes
Gipsplaat | Begane grond | Gipsplaat | 494.703 | 3470 | 12.5 | 0.043375 | 0.618378 | 0.965381 | Component Quantities - Projected Component Area (Net): 49.4702 m2; Projected Component Area (Gross): 77.2304 m2; Component Thickness: 12.5 mm; Material Properties - Gipsplaat, ThermalConductivity: 0.23; Gipsplaat, SpecificHeatCapacity: 840 J/kg/K; Gipsplaat, MassDensity: 800 kg/m3; Gipsplaat, Embodied Energy: 6.75 (MJ/kg); Gipsplaat, Embodied Carbon: 0.38 (kgCO₂/kg); Gipsplaat, Name: Gipsplaat; Gipsplaat, Participates in Collision Detection: yes
Gipsplaat | Begane grond | Gipsplaat | 160.574 | 3400 | 12.5 | 0.0425 | 0.200717 | 0.200717 | Component Quantities - Projected Component Area (Net): 16.0574 m2; Projected Component Area (Gross): 16.0574 m2; Component Thickness: 12.5 mm; Material Properties - Gipsplaat, ThermalConductivity: 0.23; Gipsplaat, SpecificHeatCapacity: 840 J/kg/K; Gipsplaat, MassDensity: 800 kg/m3; Gipsplaat, Embodied Energy: 6.75 (MJ/kg); Gipsplaat, Embodied Carbon: 0.38 (kgCO₂/kg); Gipsplaat, Name: Gipsplaat; Gipsplaat, Participates in Collision Detection: yes
Gipsplaat | Begane grond | Gipsplaat | 161.424 | 3400 | 12.5 | 0.0425 | 0.20178 | 0.20178 | Component Quantities - Projected Component Area (Net): 16.1424 m2; Projected Component Area (Gross): 16.1424 m2; Component Thickness: 12.5 mm; Material Properties - Gipsplaat, ThermalConductivity: 0.23; Gipsplaat, SpecificHeatCapacity: 840 J/kg/K; Gipsplaat, MassDensity: 800 kg/m3; Gipsplaat, Embodied Energy: 6.75 (MJ/kg); Gipsplaat, Embodied Carbon: 0.38 (kgCO₂/kg); Gipsplaat, Name: Gipsplaat; Gipsplaat, Participates in Collision Detection: yes
Isolatie - Steenwol LSW | Begane grond | Isolatie - Steenwol LSW | 44.859 | 3400 | 50 | 0.17 | 0.815619 | 0.815619 | Component Quantities - Projected Component Area (Net): 16.3124 m2; Projected Component Area (Gross): 16.3124 m2; Component Thickness: 50 mm; Material Properties - Isolatie - Steenwol LSW, ThermalConductivity: 0.039; Isolatie - Steenwol LSW, SpecificHeatCapacity: 840 J/kg/K; Isolatie - Steenwol LSW, MassDensity: 55 kg/m3; Isolatie - Steenwol LSW, Embodied Energy: 16.8 (MJ/kg); Isolatie - Steenwol LSW, Embodied Carbon: 1.05 (kgCO₂/kg); Isolatie - Steenwol LSW, Name: Isolatie - Steenwol LSW; Isolatie - Steenwol LSW, Participates in Collision Detection: yes
Gipsplaat | Begane grond | Gipsplaat | 159.724 | 3400 | 12.5 | 0.0425 | 0.199655 | 0.199655 | Component Quantities - Projected Component Area (Net): 15.9724 m2; Projected Component Area (Gross): 15.9724 m2; Component Thickness: 12.5 mm; Material Properties - Gipsplaat, ThermalConductivity: 0.23; Gipsplaat, SpecificHeatCapacity: 840 J/kg/K; Gipsplaat, MassDensity: 800 kg/m3; Gipsplaat, Embodied Energy: 6.75 (MJ/kg); Gipsplaat, Embodied Carbon: 0.38 (kgCO₂/kg); Gipsplaat, Name: Gipsplaat; Gipsplaat, Participates in Collision Detection: yes
Gipsplaat | Begane grond | Gipsplaat | 158.449 | 3400 | 12.5 | 0.0425 | 0.198061 | 0.198061 | Component Quantities - Projected Component Area (Net): 15.8449 m2; Projected Component Area (Gross): 15.8449 m2; Component Thickness: 12.5 mm; Material Properties - Gipsplaat, ThermalConductivity: 0.23; Gipsplaat, SpecificHeatCapacity: 840 J/kg/K; Gipsplaat, MassDensity: 800 kg/m3; Gipsplaat, Embodied Energy: 6.75 (MJ/kg); Gipsplaat, Embodied Carbon: 0.38 (kgCO₂/kg); Gipsplaat, Name: Gipsplaat; Gipsplaat, Participates in Collision Detection: yes
Gipsplaat | Begane grond | Gipsplaat | 251.161 | 3470 | 12.5 | 0.043375 | 0.313952 | 0.313952 | Component Quantities - Projected Component Area (Net): 25.1161 m2; Projected Component Area (Gross): 25.1161 m2; Component Thickness: 12.5 mm; Material Properties - Gipsplaat, ThermalConductivity: 0.23; Gipsplaat, SpecificHeatCapacity: 840 J/kg/K; Gipsplaat, MassDensity: 800 kg/m3; Gipsplaat, Embodied Energy: 6.75 (MJ/kg); Gipsplaat, Embodied Carbon: 0.38 (kgCO₂/kg); Gipsplaat, Name: Gipsplaat; Gipsplaat, Participates in Collision Detection: yes
Gipsplaat | Begane grond | Gipsplaat | 251.605 | 3470 | 12.5 | 0.043375 | 0.314507 | 0.314507 | Component Quantities - Projected Component Area (Net): 25.1605 m2; Projected Component Area (Gross): 25.1605 m2; Component Thickness: 12.5 mm; Material Properties - Gipsplaat, ThermalConductivity: 0.23; Gipsplaat, SpecificHeatCapacity: 840 J/kg/K; Gipsplaat, MassDensity: 800 kg/m3; Gipsplaat, Embodied Energy: 6.75 (MJ/kg); Gipsplaat, Embodied Carbon: 0.38 (kgCO₂/kg); Gipsplaat, Name: Gipsplaat; Gipsplaat, Participates in Collision Detection: yes
Isolatie - Steenwol LSW | Begane grond | Isolatie - Steenwol LSW | 139.104 | 3470 | 100 | 0.347 | 2.52916 | 2.52916 | Component Quantities - Projected Component Area (Net): 25.2916 m2; Projected Component Area (Gross): 25.2916 m2; Component Thickness: 100 mm; Material Properties - Isolatie - Steenwol LSW, ThermalConductivity: 0.039; Isolatie - Steenwol LSW, SpecificHeatCapacity: 840 J/kg/K; Isolatie - Steenwol LSW, MassDensity: 55 kg/m3; Isolatie - Steenwol LSW, Embodied Energy: 16.8 (MJ/kg); Isolatie - Steenwol LSW, Embodied Carbon: 1.05 (kgCO₂/kg); Isolatie - Steenwol LSW, Name: Isolatie - Steenwol LSW; Isolatie - Steenwol LSW, Participates in Collision Detection: yes
Isolatie - Steenwol LSW | Begane grond | Isolatie - Steenwol LSW | 137.146 | 3470 | 100 | 0.347 | 2.49357 | 2.49357 | Component Quantities - Projected Component Area (Net): 24.9357 m2; Projected Component Area (Gross): 24.9357 m2; Component Thickness: 100 mm; Material Properties - Isolatie - Steenwol LSW, ThermalConductivity: 0.039; Isolatie - Steenwol LSW, SpecificHeatCapacity: 840 J/kg/K; Isolatie - Steenwol LSW, MassDensity: 55 kg/m3; Isolatie - Steenwol LSW, Embodied Energy: 16.8 (MJ/kg); Isolatie - Steenwol LSW, Embodied Carbon: 1.05 (kgCO₂/kg); Isolatie - Steenwol LSW, Name: Isolatie - Steenwol LSW; Isolatie - Steenwol LSW, Participates in Collision Detection: yes
Gipsplaat | Begane grond | Gipsplaat | 245.967 | 3470 | 12.5 | 0.043375 | 0.307459 | 0.307459 | Component Quantities - Projected Component Area (Net): 24.5967 m2; Projected Component Area (Gross): 24.5967 m2; Component Thickness: 12.5 mm; Material Properties - Gipsplaat, ThermalConductivity: 0.23; Gipsplaat, SpecificHeatCapacity: 840 J/kg/K; Gipsplaat, MassDensity: 800 kg/m3; Gipsplaat, Embodied Energy: 6.75 (MJ/kg); Gipsplaat, Embodied Carbon: 0.38 (kgCO₂/kg); Gipsplaat, Name: Gipsplaat; Gipsplaat, Participates in Collision Detection: yes
Gipsplaat | Begane grond | Gipsplaat | 245.543 | 3470 | 12.5 | 0.043375 | 0.306929 | 0.306929 | Component Quantities - Projected Component Area (Net): 24.5543 m2; Projected Component Area (Gross): 24.5543 m2; Component Thickness: 12.5 mm; Material Properties - Gipsplaat, ThermalConductivity: 0.23; Gipsplaat, SpecificHeatCapacity: 840 J/kg/K; Gipsplaat, MassDensity: 800 kg/m3; Gipsplaat, Embodied Energy: 6.75 (MJ/kg); Gipsplaat, Embodied Carbon: 0.38 (kgCO₂/kg); Gipsplaat, Name: Gipsplaat; Gipsplaat, Participates in Collision Detection: yes
Gipsplaat | Begane grond | Gipsplaat | 113.846 | 3470 | 12.5 | 0.043375 | 0.142307 | 0.142307 | Component Quantities - Projected Component Area (Net): 11.3846 m2; Projected Component Area (Gross): 11.3846 m2; Component Thickness: 12.5 mm; Material Properties - Gipsplaat, ThermalConductivity: 0.23; Gipsplaat, SpecificHeatCapacity: 840 J/kg/K; Gipsplaat, MassDensity: 800 kg/m3; Gipsplaat, Embodied Energy: 6.75 (MJ/kg); Gipsplaat, Embodied Carbon: 0.38 (kgCO₂/kg); Gipsplaat, Name: Gipsplaat; Gipsplaat, Participates in Collision Detection: yes
Gipsplaat | Begane grond | Gipsplaat | 113.856 | 3470 | 12.5 | 0.043375 | 0.14232 | 0.14232 | Component Quantities - Projected Component Area (Net): 11.3856 m2; Projected Component Area (Gross): 11.3856 m2; Component Thickness: 12.5 mm; Material Properties - Gipsplaat, ThermalConductivity: 0.23; Gipsplaat, SpecificHeatCapacity: 840 J/kg/K; Gipsplaat, MassDensity: 800 kg/m3; Gipsplaat, Embodied Energy: 6.75 (MJ/kg); Gipsplaat, Embodied Carbon: 0.38 (kgCO₂/kg); Gipsplaat, Name: Gipsplaat; Gipsplaat, Participates in Collision Detection: yes
Isolatie - Steenwol LSW | Begane grond | Isolatie - Steenwol LSW | 30.9635 | 3470 | 50 | 0.1735 | 0.562973 | 0.562973 | Component Quantities - Projected Component Area (Net): 11.2595 m2; Projected Component Area (Gross): 11.2595 m2; Component Thickness: 50 mm; Material Properties - Isolatie - Steenwol LSW, ThermalConductivity: 0.039; Isolatie - Steenwol LSW, SpecificHeatCapacity: 840 J/kg/K; Isolatie - Steenwol LSW, MassDensity: 55 kg/m3; Isolatie - Steenwol LSW, Embodied Energy: 16.8 (MJ/kg); Isolatie - Steenwol LSW, Embodied Carbon: 1.05 (kgCO₂/kg); Isolatie - Steenwol LSW, Name: Isolatie - Steenwol LSW; Isolatie - Steenwol LSW, Participates in Collision Detection: yes
Gipsplaat | Begane grond | Gipsplaat | 110.516 | 3470 | 12.5 | 0.043375 | 0.138145 | 0.138145 | Component Quantities - Projected Component Area (Net): 11.0516 m2; Projected Component Area (Gross): 11.0516 m2; Component Thickness: 12.5 mm; Material Properties - Gipsplaat, ThermalConductivity: 0.23; Gipsplaat, SpecificHeatCapacity: 840 J/kg/K; Gipsplaat, MassDensity: 800 kg/m3; Gipsplaat, Embodied Energy: 6.75 (MJ/kg); Gipsplaat, Embodied Carbon: 0.38 (kgCO₂/kg); Gipsplaat, Name: Gipsplaat; Gipsplaat, Participates in Collision Detection: yes
Gipsplaat | Begane grond | Gipsplaat | 110.526 | 3470 | 12.5 | 0.043375 | 0.138157 | 0.138157 | Component Quantities - Projected Component Area (Net): 11.0526 m2; Projected Component Area (Gross): 11.0526 m2; Component Thickness: 12.5 mm; Material Properties - Gipsplaat, ThermalConductivity: 0.23; Gipsplaat, SpecificHeatCapacity: 840 J/kg/K; Gipsplaat, MassDensity: 800 kg/m3; Gipsplaat, Embodied Energy: 6.75 (MJ/kg); Gipsplaat, Embodied Carbon: 0.38 (kgCO₂/kg); Gipsplaat, Name: Gipsplaat; Gipsplaat, Participates in Collision Detection: yes
Gipsplaat | Begane grond | Gipsplaat | 140.172 | 3470 | 12.5 | 0.043375 | 0.175215 | 0.175215 | Component Quantities - Projected Component Area (Net): 14.0385 m2; Projected Component Area (Gross): 14.0385 m2; Component Thickness: 12.5 mm; Material Properties - Gipsplaat, ThermalConductivity: 0.23; Gipsplaat, SpecificHeatCapacity: 840 J/kg/K; Gipsplaat, MassDensity: 800 kg/m3; Gipsplaat, Embodied Energy: 6.75 (MJ/kg); Gipsplaat, Embodied Carbon: 0.38 (kgCO₂/kg); Gipsplaat, Name: Gipsplaat; Gipsplaat, Participates in Collision Detection: yes
Gipsplaat | Begane grond | Gipsplaat | 140.709 | 3470 | 12.5 | 0.043375 | 0.175886 | 0.175886 | Component Quantities - Projected Component Area (Net): 14.227 m2; Projected Component Area (Gross): 14.227 m2; Component Thickness: 12.5 mm; Material Properties - Gipsplaat, ThermalConductivity: 0.23; Gipsplaat, SpecificHeatCapacity: 840 J/kg/K; Gipsplaat, MassDensity: 800 kg/m3; Gipsplaat, Embodied Energy: 6.75 (MJ/kg); Gipsplaat, Embodied Carbon: 0.38 (kgCO₂/kg); Gipsplaat, Name: Gipsplaat; Gipsplaat, Participates in Collision Detection: yes
Isolatie - Steenwol LSW | Begane grond | Isolatie - Steenwol LSW | 39.1243 | 3470 | 50 | 0.1735 | 0.711351 | 0.711351 | Component Quantities - Projected Component Area (Net): 14.227 m2; Projected Component Area (Gross): 14.227 m2; Component Thickness: 50 mm; Material Properties - Isolatie - Steenwol LSW, ThermalConductivity: 0.039; Isolatie - Steenwol LSW, SpecificHeatCapacity: 840 J/kg/K; Isolatie - Steenwol LSW, MassDensity: 55 kg/m3; Isolatie - Steenwol LSW, Embodied Energy: 16.8 (MJ/kg); Isolatie - Steenwol LSW, Embodied Carbon: 1.05 (kgCO₂/kg); Isolatie - Steenwol LSW, Name: Isolatie - Steenwol LSW; Isolatie - Steenwol LSW, Participates in Collision Detection: yes
Gipsplaat | Begane grond | Gipsplaat | 140.101 | 3470 | 12.5 | 0.043375 | 0.175127 | 0.175127 | Component Quantities - Projected Component Area (Net): 14.0101 m2; Projected Component Area (Gross): 14.0101 m2; Component Thickness: 12.5 mm; Material Properties - Gipsplaat, ThermalConductivity: 0.23; Gipsplaat, SpecificHeatCapacity: 840 J/kg/K; Gipsplaat, MassDensity: 800 kg/m3; Gipsplaat, Embodied Energy: 6.75 (MJ/kg); Gipsplaat, Embodied Carbon: 0.38 (kgCO₂/kg); Gipsplaat, Name: Gipsplaat; Gipsplaat, Participates in Collision Detection: yes
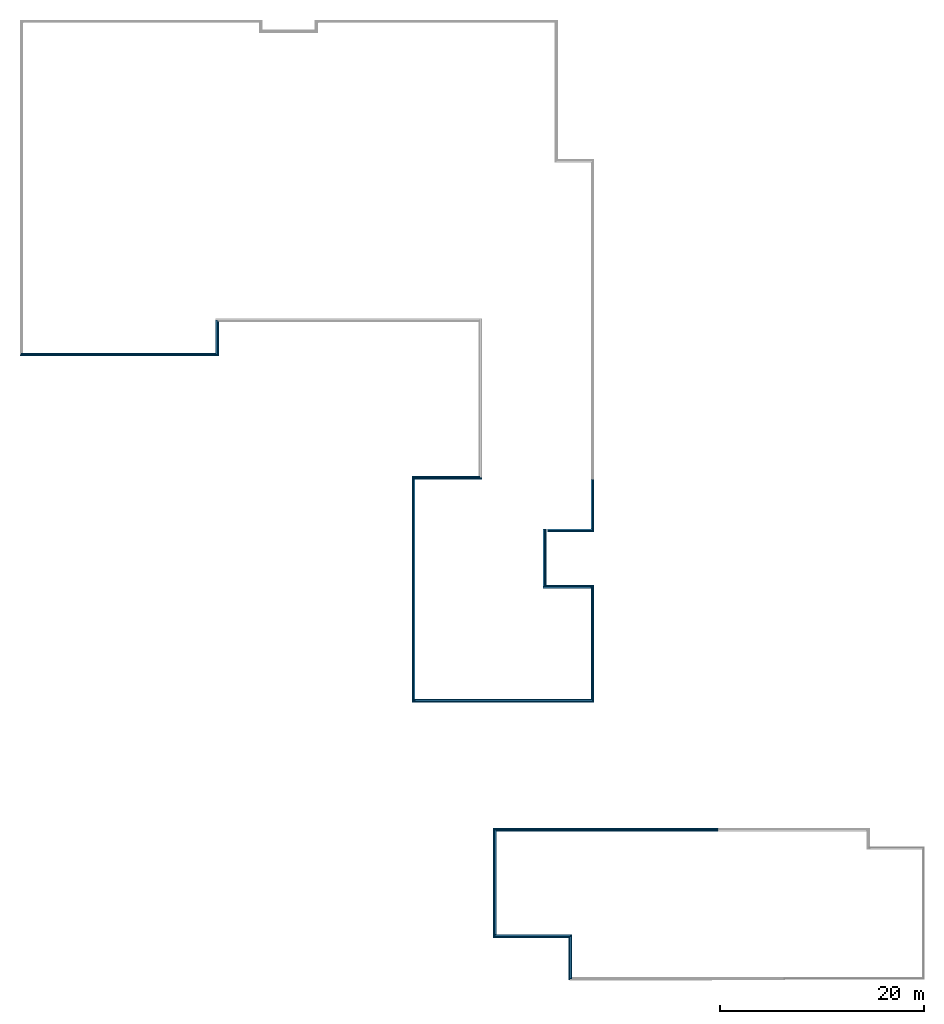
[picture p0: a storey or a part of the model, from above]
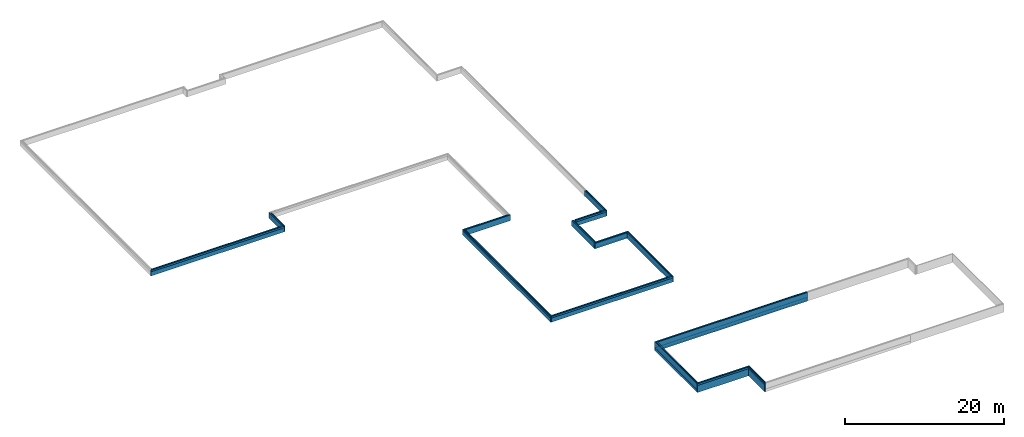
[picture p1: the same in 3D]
Properties of the parts of a building model (IFC2X3), part 7 of 19

# IfcBuildingElementPart (2070)
Name | In | Material | Mass (kg) | Rectangular Component Height (mm) | Rectangular Component Width (mm) | Component Cross Section Area (m2) | Component Volume (Net) (m3) | Component Volume (Gross) (m3)
Gipsplaat | Begane grond | Gipsplaat | 139.234 | 3470 | 12.5 | 0.043375 | 0.174042 | 0.174042 | Component Quantities - Projected Component Area (Net): 13.9234 m2; Projected Component Area (Gross): 13.9234 m2; Component Thickness: 12.5 mm; Material Properties - Gipsplaat, ThermalConductivity: 0.23; Gipsplaat, SpecificHeatCapacity: 840 J/kg/K; Gipsplaat, MassDensity: 800 kg/m3; Gipsplaat, Embodied Energy: 6.75 (MJ/kg); Gipsplaat, Embodied Carbon: 0.38 (kgCO₂/kg); Gipsplaat, Name: Gipsplaat; Gipsplaat, Participates in Collision Detection: yes
Gipsplaat | Begane grond | Gipsplaat | 132.294 | 3470 | 12.5 | 0.043375 | 0.165367 | 0.165367 | Component Quantities - Projected Component Area (Net): 13.2294 m2; Projected Component Area (Gross): 13.2294 m2; Component Thickness: 12.5 mm; Material Properties - Gipsplaat, ThermalConductivity: 0.23; Gipsplaat, SpecificHeatCapacity: 840 J/kg/K; Gipsplaat, MassDensity: 800 kg/m3; Gipsplaat, Embodied Energy: 6.75 (MJ/kg); Gipsplaat, Embodied Carbon: 0.38 (kgCO₂/kg); Gipsplaat, Name: Gipsplaat; Gipsplaat, Participates in Collision Detection: yes
Gipsplaat | Begane grond | Gipsplaat | 134.463 | 3470 | 12.5 | 0.043375 | 0.168078 | 0.168078 | Component Quantities - Projected Component Area (Net): 13.4463 m2; Projected Component Area (Gross): 13.4463 m2; Component Thickness: 12.5 mm; Material Properties - Gipsplaat, ThermalConductivity: 0.23; Gipsplaat, SpecificHeatCapacity: 840 J/kg/K; Gipsplaat, MassDensity: 800 kg/m3; Gipsplaat, Embodied Energy: 6.75 (MJ/kg); Gipsplaat, Embodied Carbon: 0.38 (kgCO₂/kg); Gipsplaat, Name: Gipsplaat; Gipsplaat, Participates in Collision Detection: yes
Isolatie - Steenwol LSW | Begane grond | Isolatie - Steenwol LSW | 38.6471 | 3470 | 50 | 0.1735 | 0.702675 | 0.702675 | Component Quantities - Projected Component Area (Net): 14.0535 m2; Projected Component Area (Gross): 14.0535 m2; Component Thickness: 50 mm; Material Properties - Isolatie - Steenwol LSW, ThermalConductivity: 0.039; Isolatie - Steenwol LSW, SpecificHeatCapacity: 840 J/kg/K; Isolatie - Steenwol LSW, MassDensity: 55 kg/m3; Isolatie - Steenwol LSW, Embodied Energy: 16.8 (MJ/kg); Isolatie - Steenwol LSW, Embodied Carbon: 1.05 (kgCO₂/kg); Isolatie - Steenwol LSW, Name: Isolatie - Steenwol LSW; Isolatie - Steenwol LSW, Participates in Collision Detection: yes
Gipsplaat | Begane grond | Gipsplaat | 139.668 | 3470 | 12.5 | 0.043375 | 0.174584 | 0.174584 | Component Quantities - Projected Component Area (Net): 13.9668 m2; Projected Component Area (Gross): 13.9668 m2; Component Thickness: 12.5 mm; Material Properties - Gipsplaat, ThermalConductivity: 0.23; Gipsplaat, SpecificHeatCapacity: 840 J/kg/K; Gipsplaat, MassDensity: 800 kg/m3; Gipsplaat, Embodied Energy: 6.75 (MJ/kg); Gipsplaat, Embodied Carbon: 0.38 (kgCO₂/kg); Gipsplaat, Name: Gipsplaat; Gipsplaat, Participates in Collision Detection: yes
Gipsplaat | Begane grond | Gipsplaat | 138.8 | 3470 | 12.5 | 0.043375 | 0.1735 | 0.1735 | Component Quantities - Projected Component Area (Net): 13.88 m2; Projected Component Area (Gross): 13.88 m2; Component Thickness: 12.5 mm; Material Properties - Gipsplaat, ThermalConductivity: 0.23; Gipsplaat, SpecificHeatCapacity: 840 J/kg/K; Gipsplaat, MassDensity: 800 kg/m3; Gipsplaat, Embodied Energy: 6.75 (MJ/kg); Gipsplaat, Embodied Carbon: 0.38 (kgCO₂/kg); Gipsplaat, Name: Gipsplaat; Gipsplaat, Participates in Collision Detection: yes
Gipsplaat | Begane grond | Gipsplaat | 110.709 | 3400 | 12.5 | 0.0425 | 0.138386 | 0.169109 | Component Quantities - Projected Component Area (Net): 11.0709 m2; Projected Component Area (Gross): 13.5287 m2; Component Thickness: 12.5 mm; Material Properties - Gipsplaat, ThermalConductivity: 0.23; Gipsplaat, SpecificHeatCapacity: 840 J/kg/K; Gipsplaat, MassDensity: 800 kg/m3; Gipsplaat, Embodied Energy: 6.75 (MJ/kg); Gipsplaat, Embodied Carbon: 0.38 (kgCO₂/kg); Gipsplaat, Name: Gipsplaat; Gipsplaat, Participates in Collision Detection: yes
Gipsplaat | Begane grond | Gipsplaat | 111.984 | 3400 | 12.5 | 0.0425 | 0.13998 | 0.170703 | Component Quantities - Projected Component Area (Net): 11.1984 m2; Projected Component Area (Gross): 13.6562 m2; Component Thickness: 12.5 mm; Material Properties - Gipsplaat, ThermalConductivity: 0.23; Gipsplaat, SpecificHeatCapacity: 840 J/kg/K; Gipsplaat, MassDensity: 800 kg/m3; Gipsplaat, Embodied Energy: 6.75 (MJ/kg); Gipsplaat, Embodied Carbon: 0.38 (kgCO₂/kg); Gipsplaat, Name: Gipsplaat; Gipsplaat, Participates in Collision Detection: yes
Isolatie - Steenwol LSW | Begane grond | Isolatie - Steenwol LSW | 32.7825 | 3400 | 50 | 0.17 | 0.596045 | 0.718936 | Component Quantities - Projected Component Area (Net): 11.9209 m2; Projected Component Area (Gross): 14.3787 m2; Component Thickness: 50 mm; Material Properties - Isolatie - Steenwol LSW, ThermalConductivity: 0.039; Isolatie - Steenwol LSW, SpecificHeatCapacity: 840 J/kg/K; Isolatie - Steenwol LSW, MassDensity: 55 kg/m3; Isolatie - Steenwol LSW, Embodied Energy: 16.8 (MJ/kg); Isolatie - Steenwol LSW, Embodied Carbon: 1.05 (kgCO₂/kg); Isolatie - Steenwol LSW, Name: Isolatie - Steenwol LSW; Isolatie - Steenwol LSW, Participates in Collision Detection: yes
Gipsplaat | Begane grond | Gipsplaat | 115.384 | 3400 | 12.5 | 0.0425 | 0.14423 | 0.174953 | Component Quantities - Projected Component Area (Net): 11.5384 m2; Projected Component Area (Gross): 13.9962 m2; Component Thickness: 12.5 mm; Material Properties - Gipsplaat, ThermalConductivity: 0.23; Gipsplaat, SpecificHeatCapacity: 840 J/kg/K; Gipsplaat, MassDensity: 800 kg/m3; Gipsplaat, Embodied Energy: 6.75 (MJ/kg); Gipsplaat, Embodied Carbon: 0.38 (kgCO₂/kg); Gipsplaat, Name: Gipsplaat; Gipsplaat, Participates in Collision Detection: yes
Gipsplaat | Begane grond | Gipsplaat | 114.959 | 3400 | 12.5 | 0.0425 | 0.143699 | 0.174422 | Component Quantities - Projected Component Area (Net): 11.4959 m2; Projected Component Area (Gross): 13.9537 m2; Component Thickness: 12.5 mm; Material Properties - Gipsplaat, ThermalConductivity: 0.23; Gipsplaat, SpecificHeatCapacity: 840 J/kg/K; Gipsplaat, MassDensity: 800 kg/m3; Gipsplaat, Embodied Energy: 6.75 (MJ/kg); Gipsplaat, Embodied Carbon: 0.38 (kgCO₂/kg); Gipsplaat, Name: Gipsplaat; Gipsplaat, Participates in Collision Detection: yes
Steen - Baksteen AFW | Begane grond | Steen - Baksteen AFW | 3138.05 | 4255 | 100 | 0.4255 | 1.96128 | 2.85724 | Component Quantities - Projected Component Area (Net): 19.6128 m2; Projected Component Area (Gross): 28.5724 m2; Component Thickness: 100 mm; Material Properties - Steen - Baksteen AFW, ThermalConductivity: 0.9; Steen - Baksteen AFW, SpecificHeatCapacity: 840 J/kg/K; Steen - Baksteen AFW, MassDensity: 1600 kg/m3; Steen - Baksteen AFW, Embodied Energy: 3 (MJ/kg); Steen - Baksteen AFW, Embodied Carbon: 0.23 (kgCO₂/kg); Steen - Baksteen AFW, Name: Steen - Baksteen AFW; Steen - Baksteen AFW, Participates in Collision Detection: yes
Isolatie - Glaswol hard | Begane grond | Isolatie - Glaswol hard | 345.816 | 4255 | 196 | 0.83398 | 5.40337 | 5.40337 | Component Quantities - Projected Component Area (Net): 27.5682 m2; Projected Component Area (Gross): 27.5682 m2; Component Thickness: 196 mm; Material Properties - Isolatie - Glaswol hard, ThermalConductivity: 0.033; Isolatie - Glaswol hard, SpecificHeatCapacity: 1030 J/kg/K; Isolatie - Glaswol hard, MassDensity: 64 kg/m3; Isolatie - Glaswol hard, Embodied Energy: 37 (MJ/kg); Isolatie - Glaswol hard, Embodied Carbon: 1.48 (kgCO₂/kg); Isolatie - Glaswol hard, Name: Isolatie - Glaswol hard; Isolatie - Glaswol hard, Participates in Collision Detection: yes
Metaal - Staal AFW | Begane grond | Metaal - Staal AFW | 876.129 | 4255 | 4 | 0.01702 | 0.110205 | 0.110205 | Component Quantities - Projected Component Area (Net): 27.5512 m2; Projected Component Area (Gross): 27.5512 m2; Component Thickness: 4 mm; Material Properties - Metaal - Staal AFW, ThermalConductivity: 52; Metaal - Staal AFW, SpecificHeatCapacity: 530 J/kg/K; Metaal - Staal AFW, MassDensity: 7950 kg/m3; Metaal - Staal AFW, Embodied Energy: 25 (MJ/kg); Metaal - Staal AFW, Embodied Carbon: 1.91 (kgCO₂/kg); Metaal - Staal AFW, Name: Metaal - Staal AFW; Metaal - Staal AFW, Participates in Collision Detection: yes
Gipsplaat | Begane grond | Gipsplaat | 77.7954 | 3400 | 12.5 | 0.0425 | 0.0972442 | 0.127967 | Component Quantities - Projected Component Area (Net): 7.77954 m2; Projected Component Area (Gross): 10.2374 m2; Component Thickness: 12.5 mm; Material Properties - Gipsplaat, ThermalConductivity: 0.23; Gipsplaat, SpecificHeatCapacity: 840 J/kg/K; Gipsplaat, MassDensity: 800 kg/m3; Gipsplaat, Embodied Energy: 6.75 (MJ/kg); Gipsplaat, Embodied Carbon: 0.38 (kgCO₂/kg); Gipsplaat, Name: Gipsplaat; Gipsplaat, Participates in Collision Detection: yes
Gipsplaat | Begane grond | Gipsplaat | 79.0704 | 3400 | 12.5 | 0.0425 | 0.098838 | 0.129561 | Component Quantities - Projected Component Area (Net): 7.90704 m2; Projected Component Area (Gross): 10.3649 m2; Component Thickness: 12.5 mm; Material Properties - Gipsplaat, ThermalConductivity: 0.23; Gipsplaat, SpecificHeatCapacity: 840 J/kg/K; Gipsplaat, MassDensity: 800 kg/m3; Gipsplaat, Embodied Energy: 6.75 (MJ/kg); Gipsplaat, Embodied Carbon: 0.38 (kgCO₂/kg); Gipsplaat, Name: Gipsplaat; Gipsplaat, Participates in Collision Detection: yes
Isolatie - Steenwol LSW | Begane grond | Isolatie - Steenwol LSW | 22.3287 | 3400 | 50 | 0.17 | 0.405977 | 0.528868 | Component Quantities - Projected Component Area (Net): 8.11954 m2; Projected Component Area (Gross): 10.5774 m2; Component Thickness: 50 mm; Material Properties - Isolatie - Steenwol LSW, ThermalConductivity: 0.039; Isolatie - Steenwol LSW, SpecificHeatCapacity: 840 J/kg/K; Isolatie - Steenwol LSW, MassDensity: 55 kg/m3; Isolatie - Steenwol LSW, Embodied Energy: 16.8 (MJ/kg); Isolatie - Steenwol LSW, Embodied Carbon: 1.05 (kgCO₂/kg); Isolatie - Steenwol LSW, Name: Isolatie - Steenwol LSW; Isolatie - Steenwol LSW, Participates in Collision Detection: yes
Gipsplaat | Begane grond | Gipsplaat | 80.7704 | 3400 | 12.5 | 0.0425 | 0.100963 | 0.131686 | Component Quantities - Projected Component Area (Net): 8.07704 m2; Projected Component Area (Gross): 10.5349 m2; Component Thickness: 12.5 mm; Material Properties - Gipsplaat, ThermalConductivity: 0.23; Gipsplaat, SpecificHeatCapacity: 840 J/kg/K; Gipsplaat, MassDensity: 800 kg/m3; Gipsplaat, Embodied Energy: 6.75 (MJ/kg); Gipsplaat, Embodied Carbon: 0.38 (kgCO₂/kg); Gipsplaat, Name: Gipsplaat; Gipsplaat, Participates in Collision Detection: yes
Gipsplaat | Begane grond | Gipsplaat | 80.3454 | 3400 | 12.5 | 0.0425 | 0.100432 | 0.131154 | Component Quantities - Projected Component Area (Net): 8.03454 m2; Projected Component Area (Gross): 10.4924 m2; Component Thickness: 12.5 mm; Material Properties - Gipsplaat, ThermalConductivity: 0.23; Gipsplaat, SpecificHeatCapacity: 840 J/kg/K; Gipsplaat, MassDensity: 800 kg/m3; Gipsplaat, Embodied Energy: 6.75 (MJ/kg); Gipsplaat, Embodied Carbon: 0.38 (kgCO₂/kg); Gipsplaat, Name: Gipsplaat; Gipsplaat, Participates in Collision Detection: yes
Cement | Begane grond | Cement | 231764 |  |  |  | 121.981 | 120.755 | Component Quantities - Projected Component Area (Net): 1742.61 m2; Projected Component Area (Gross): 1725.09 m2; Component Thickness: 70 mm; Material Properties - Cement, ThermalConductivity: 0.93; Cement, SpecificHeatCapacity: 840 J/kg/K; Cement, MassDensity: 1900 kg/m3; Cement, Embodied Energy: 0.97 (MJ/kg); Cement, Embodied Carbon: 0.146 (kgCO₂/kg); Cement, Name: Cement; Cement, Participates in Collision Detection: yes
Beton gewapend C vloer | Begane grond | Beton gewapend C vloer | 214573 |  |  |  | 89.4056 | 89.4776 | Component Quantities - Projected Component Area (Net): 1788.11 m2; Projected Component Area (Gross): 1789.55 m2; Component Thickness: 50 mm; Material Properties - Beton gewapend C vloer, ThermalConductivity: 2.5; Beton gewapend C vloer, SpecificHeatCapacity: 1000 J/kg/K; Beton gewapend C vloer, MassDensity: 2400 kg/m3; Beton gewapend C vloer, Embodied Energy: 2.33 (MJ/kg); Beton gewapend C vloer, Embodied Carbon: 0.242 (kgCO₂/kg); Beton gewapend C vloer, Name: Beton gewapend C vloer; Beton gewapend C vloer, Participates in Collision Detection: yes
Beton gewapend prefab vloer | Begane grond | Beton gewapend prefab vloer | 858294 |  |  |  | 357.622 | 357.91 | Component Quantities - Projected Component Area (Net): 1788.11 m2; Projected Component Area (Gross): 1789.55 m2; Component Thickness: 200 mm; Material Properties - Beton gewapend prefab vloer, ThermalConductivity: 2.5; Beton gewapend prefab vloer, SpecificHeatCapacity: 1000 J/kg/K; Beton gewapend prefab vloer, MassDensity: 2400 kg/m3; Beton gewapend prefab vloer, Embodied Energy: 2.33 (MJ/kg); Beton gewapend prefab vloer, Embodied Carbon: 0.242 (kgCO₂/kg); Beton gewapend prefab vloer, Name: Beton gewapend prefab vloer; Beton gewapend prefab vloer, Participates in Collision Detection: yes
ALG - ISOLATIE | Begane grond | ALG - ISOLATIE | 10621.4 |  |  |  | 236.031 | 236.221 | Component Quantities - Projected Component Area (Net): 1788.11 m2; Projected Component Area (Gross): 1789.55 m2; Component Thickness: 132 mm; Material Properties - ALG - ISOLATIE, ThermalConductivity: 0.035; ALG - ISOLATIE, SpecificHeatCapacity: 840 J/kg/K; ALG - ISOLATIE, MassDensity: 45 kg/m3; ALG - ISOLATIE, Embodied Energy: 16.8 (MJ/kg); ALG - ISOLATIE, Embodied Carbon: 1.05 (kgCO₂/kg); ALG - ISOLATIE, Name: ALG - ISOLATIE; ALG - ISOLATIE, Participates in Collision Detection: yes
5 x Gipsplaat | Begane grond | Gipsplaat | 131.808 | 3470 | 12.5 | 0.043375 | 0.16476 | 0.16476 | Component Quantities - Projected Component Area (Net): 13.1808 m2; Projected Component Area (Gross): 13.1808 m2; Component Thickness: 12.5 mm; Material Properties - Gipsplaat, ThermalConductivity: 0.23; Gipsplaat, SpecificHeatCapacity: 840 J/kg/K; Gipsplaat, MassDensity: 800 kg/m3; Gipsplaat, Embodied Energy: 6.75 (MJ/kg); Gipsplaat, Embodied Carbon: 0.38 (kgCO₂/kg); Gipsplaat, Name: Gipsplaat; Gipsplaat, Participates in Collision Detection: yes
2 x Isolatie - Steenwol LSW | Begane grond | Isolatie - Steenwol LSW | 36.3665 | 3470 | 50 | 0.1735 | 0.661208 | 0.661208 | Component Quantities - Projected Component Area (Net): 13.2242 m2; Projected Component Area (Gross): 13.2242 m2; Component Thickness: 50 mm; Material Properties - Isolatie - Steenwol LSW, ThermalConductivity: 0.039; Isolatie - Steenwol LSW, SpecificHeatCapacity: 840 J/kg/K; Isolatie - Steenwol LSW, MassDensity: 55 kg/m3; Isolatie - Steenwol LSW, Embodied Energy: 16.8 (MJ/kg); Isolatie - Steenwol LSW, Embodied Carbon: 1.05 (kgCO₂/kg); Isolatie - Steenwol LSW, Name: Isolatie - Steenwol LSW; Isolatie - Steenwol LSW, Participates in Collision Detection: yes
Gipsplaat | Begane grond | Gipsplaat | 247.524 | 3400 | 12.5 | 0.0425 | 0.309405 | 0.309405 | Component Quantities - Projected Component Area (Net): 24.7524 m2; Projected Component Area (Gross): 24.7524 m2; Component Thickness: 12.5 mm; Material Properties - Gipsplaat, ThermalConductivity: 0.23; Gipsplaat, SpecificHeatCapacity: 840 J/kg/K; Gipsplaat, MassDensity: 800 kg/m3; Gipsplaat, Embodied Energy: 6.75 (MJ/kg); Gipsplaat, Embodied Carbon: 0.38 (kgCO₂/kg); Gipsplaat, Name: Gipsplaat; Gipsplaat, Participates in Collision Detection: yes
Gipsplaat | Begane grond | Gipsplaat | 253.029 | 3400 | 12.5 | 0.0425 | 0.316286 | 0.316286 | Component Quantities - Projected Component Area (Net): 25.3029 m2; Projected Component Area (Gross): 25.3029 m2; Component Thickness: 12.5 mm; Material Properties - Gipsplaat, ThermalConductivity: 0.23; Gipsplaat, SpecificHeatCapacity: 840 J/kg/K; Gipsplaat, MassDensity: 800 kg/m3; Gipsplaat, Embodied Energy: 6.75 (MJ/kg); Gipsplaat, Embodied Carbon: 0.38 (kgCO₂/kg); Gipsplaat, Name: Gipsplaat; Gipsplaat, Participates in Collision Detection: yes
Isolatie - Steenwol LSW | Begane grond | Isolatie - Steenwol LSW | 71.0969 | 3400 | 50 | 0.17 | 1.29267 | 1.29267 | Component Quantities - Projected Component Area (Net): 25.8534 m2; Projected Component Area (Gross): 25.8534 m2; Component Thickness: 50 mm; Material Properties - Isolatie - Steenwol LSW, ThermalConductivity: 0.039; Isolatie - Steenwol LSW, SpecificHeatCapacity: 840 J/kg/K; Isolatie - Steenwol LSW, MassDensity: 55 kg/m3; Isolatie - Steenwol LSW, Embodied Energy: 16.8 (MJ/kg); Isolatie - Steenwol LSW, Embodied Carbon: 1.05 (kgCO₂/kg); Isolatie - Steenwol LSW, Name: Isolatie - Steenwol LSW; Isolatie - Steenwol LSW, Participates in Collision Detection: yes
2 x Gipsplaat | Begane grond | Gipsplaat | 27.9149 | 3470 | 12.5 | 0.043375 | 0.0348936 | 0.108437 | Component Quantities - Projected Component Area (Net): 2.79149 m2; Projected Component Area (Gross): 8.67499 m2; Component Thickness: 12.5 mm; Material Properties - Gipsplaat, ThermalConductivity: 0.23; Gipsplaat, SpecificHeatCapacity: 840 J/kg/K; Gipsplaat, MassDensity: 800 kg/m3; Gipsplaat, Embodied Energy: 6.75 (MJ/kg); Gipsplaat, Embodied Carbon: 0.38 (kgCO₂/kg); Gipsplaat, Name: Gipsplaat; Gipsplaat, Participates in Collision Detection: yes
2 x Gipsplaat | Begane grond | Gipsplaat | 28.3486 | 3470 | 12.5 | 0.043375 | 0.0354358 | 0.10898 | Component Quantities - Projected Component Area (Net): 2.83486 m2; Projected Component Area (Gross): 8.71836 m2; Component Thickness: 12.5 mm; Material Properties - Gipsplaat, ThermalConductivity: 0.23; Gipsplaat, SpecificHeatCapacity: 840 J/kg/K; Gipsplaat, MassDensity: 800 kg/m3; Gipsplaat, Embodied Energy: 6.75 (MJ/kg); Gipsplaat, Embodied Carbon: 0.38 (kgCO₂/kg); Gipsplaat, Name: Gipsplaat; Gipsplaat, Participates in Collision Detection: yes
Isolatie - Steenwol LSW | Begane grond | Isolatie - Steenwol LSW | 7.91516 | 3470 | 50 | 0.1735 | 0.143912 | 0.438087 | Component Quantities - Projected Component Area (Net): 2.87824 m2; Projected Component Area (Gross): 8.76174 m2; Component Thickness: 50 mm; Material Properties - Isolatie - Steenwol LSW, ThermalConductivity: 0.039; Isolatie - Steenwol LSW, SpecificHeatCapacity: 840 J/kg/K; Isolatie - Steenwol LSW, MassDensity: 55 kg/m3; Isolatie - Steenwol LSW, Embodied Energy: 16.8 (MJ/kg); Isolatie - Steenwol LSW, Embodied Carbon: 1.05 (kgCO₂/kg); Isolatie - Steenwol LSW, Name: Isolatie - Steenwol LSW; Isolatie - Steenwol LSW, Participates in Collision Detection: yes
2 x Gipsplaat | Begane grond | Gipsplaat | 58.7032 | 3470 | 12.5 | 0.043375 | 0.073379 | 0.134554 | Component Quantities - Projected Component Area (Net): 5.87032 m2; Projected Component Area (Gross): 10.7643 m2; Component Thickness: 12.5 mm; Material Properties - Gipsplaat, ThermalConductivity: 0.23; Gipsplaat, SpecificHeatCapacity: 840 J/kg/K; Gipsplaat, MassDensity: 800 kg/m3; Gipsplaat, Embodied Energy: 6.75 (MJ/kg); Gipsplaat, Embodied Carbon: 0.38 (kgCO₂/kg); Gipsplaat, Name: Gipsplaat; Gipsplaat, Participates in Collision Detection: yes
2 x Gipsplaat | Begane grond | Gipsplaat | 59.5707 | 3470 | 12.5 | 0.043375 | 0.0744634 | 0.135638 | Component Quantities - Projected Component Area (Net): 5.95707 m2; Projected Component Area (Gross): 10.8511 m2; Component Thickness: 12.5 mm; Material Properties - Gipsplaat, ThermalConductivity: 0.23; Gipsplaat, SpecificHeatCapacity: 840 J/kg/K; Gipsplaat, MassDensity: 800 kg/m3; Gipsplaat, Embodied Energy: 6.75 (MJ/kg); Gipsplaat, Embodied Carbon: 0.38 (kgCO₂/kg); Gipsplaat, Name: Gipsplaat; Gipsplaat, Participates in Collision Detection: yes
Isolatie - Steenwol LSW | Begane grond | Isolatie - Steenwol LSW | 16.6205 | 3470 | 50 | 0.1735 | 0.302191 | 0.546891 | Component Quantities - Projected Component Area (Net): 6.04382 m2; Projected Component Area (Gross): 10.9378 m2; Component Thickness: 50 mm; Material Properties - Isolatie - Steenwol LSW, ThermalConductivity: 0.039; Isolatie - Steenwol LSW, SpecificHeatCapacity: 840 J/kg/K; Isolatie - Steenwol LSW, MassDensity: 55 kg/m3; Isolatie - Steenwol LSW, Embodied Energy: 16.8 (MJ/kg); Isolatie - Steenwol LSW, Embodied Carbon: 1.05 (kgCO₂/kg); Isolatie - Steenwol LSW, Name: Isolatie - Steenwol LSW; Isolatie - Steenwol LSW, Participates in Collision Detection: yes
2 x Gipsplaat | Begane grond | Gipsplaat | 78.0633 | 3400 | 12.5 | 0.0425 | 0.0975791 | 0.0975791 | Component Quantities - Projected Component Area (Net): 7.80633 m2; Projected Component Area (Gross): 7.80633 m2; Component Thickness: 12.5 mm; Material Properties - Gipsplaat, ThermalConductivity: 0.23; Gipsplaat, SpecificHeatCapacity: 840 J/kg/K; Gipsplaat, MassDensity: 800 kg/m3; Gipsplaat, Embodied Energy: 6.75 (MJ/kg); Gipsplaat, Embodied Carbon: 0.38 (kgCO₂/kg); Gipsplaat, Name: Gipsplaat; Gipsplaat, Participates in Collision Detection: yes
Isolatie - Steenwol LSW | Begane grond | Isolatie - Steenwol LSW | 21.4674 | 3400 | 50 | 0.17 | 0.390317 | 0.390317 | Component Quantities - Projected Component Area (Net): 7.80633 m2; Projected Component Area (Gross): 7.80633 m2; Component Thickness: 50 mm; Material Properties - Isolatie - Steenwol LSW, ThermalConductivity: 0.039; Isolatie - Steenwol LSW, SpecificHeatCapacity: 840 J/kg/K; Isolatie - Steenwol LSW, MassDensity: 55 kg/m3; Isolatie - Steenwol LSW, Embodied Energy: 16.8 (MJ/kg); Isolatie - Steenwol LSW, Embodied Carbon: 1.05 (kgCO₂/kg); Isolatie - Steenwol LSW, Name: Isolatie - Steenwol LSW; Isolatie - Steenwol LSW, Participates in Collision Detection: yes
4 x Gipsplaat | Begane grond | Gipsplaat | 11.988 | 3470 | 12.5 | 0.043375 | 0.014985 | 0.0866632 | Component Quantities - Projected Component Area (Net): 1.1988 m2; Projected Component Area (Gross): 6.93306 m2; Component Thickness: 12.5 mm; Material Properties - Gipsplaat, ThermalConductivity: 0.23; Gipsplaat, SpecificHeatCapacity: 840 J/kg/K; Gipsplaat, MassDensity: 800 kg/m3; Gipsplaat, Embodied Energy: 6.75 (MJ/kg); Gipsplaat, Embodied Carbon: 0.38 (kgCO₂/kg); Gipsplaat, Name: Gipsplaat; Gipsplaat, Participates in Collision Detection: yes
Isolatie - Steenwol LSW | Begane grond | Isolatie - Steenwol LSW | 3.2967 | 3470 | 50 | 0.1735 | 0.05994 | 0.346653 | Component Quantities - Projected Component Area (Net): 1.1988 m2; Projected Component Area (Gross): 6.93306 m2; Component Thickness: 50 mm; Material Properties - Isolatie - Steenwol LSW, ThermalConductivity: 0.039; Isolatie - Steenwol LSW, SpecificHeatCapacity: 840 J/kg/K; Isolatie - Steenwol LSW, MassDensity: 55 kg/m3; Isolatie - Steenwol LSW, Embodied Energy: 16.8 (MJ/kg); Isolatie - Steenwol LSW, Embodied Carbon: 1.05 (kgCO₂/kg); Isolatie - Steenwol LSW, Name: Isolatie - Steenwol LSW; Isolatie - Steenwol LSW, Participates in Collision Detection: yes
2 x Gipsplaat | Begane grond | Gipsplaat | 51.9009 | 600 | 12.5 | 0.0075 | 0.0648761 | 0.0648761 | Component Quantities - Projected Component Area (Net): 5.19009 m2; Projected Component Area (Gross): 5.19009 m2; Component Thickness: 12.5 mm; Material Properties - Gipsplaat, ThermalConductivity: 0.23; Gipsplaat, SpecificHeatCapacity: 840 J/kg/K; Gipsplaat, MassDensity: 800 kg/m3; Gipsplaat, Embodied Energy: 6.75 (MJ/kg); Gipsplaat, Embodied Carbon: 0.38 (kgCO₂/kg); Gipsplaat, Name: Gipsplaat; Gipsplaat, Participates in Collision Detection: yes
Steen - Kalkzandsteen C | Begane grond | Steen - Kalkzandsteen C | 25089.9 | 4235 | 214 | 0.90629 | 13.2052 | 23.9968 | Component Quantities - Projected Component Area (Net): 61.7069 m2; Projected Component Area (Gross): 112.134 m2; Component Thickness: 214 mm; Material Properties - Steen - Kalkzandsteen C, ThermalConductivity: 0.9; Steen - Kalkzandsteen C, SpecificHeatCapacity: 840 J/kg/K; Steen - Kalkzandsteen C, MassDensity: 1900 kg/m3; Steen - Kalkzandsteen C, Embodied Energy: 0.75 (MJ/kg); Steen - Kalkzandsteen C, Embodied Carbon: 0.1 (kgCO₂/kg); Steen - Kalkzandsteen C, Name: Steen - Kalkzandsteen C; Steen - Kalkzandsteen C, Participates in Collision Detection: yes
ALG - ISOLATIE | Begane grond | ALG - ISOLATIE | 536.838 | 4235 | 150 | 0.63525 | 11.9297 | 16.5483 | Component Quantities - Projected Component Area (Net): 80.15 m2; Projected Component Area (Gross): 110.322 m2; Component Thickness: 150 mm; Material Properties - ALG - ISOLATIE, ThermalConductivity: 0.035; ALG - ISOLATIE, SpecificHeatCapacity: 840 J/kg/K; ALG - ISOLATIE, MassDensity: 45 kg/m3; ALG - ISOLATIE, Embodied Energy: 16.8 (MJ/kg); ALG - ISOLATIE, Embodied Carbon: 1.05 (kgCO₂/kg); ALG - ISOLATIE, Name: ALG - ISOLATIE; ALG - ISOLATIE, Participates in Collision Detection: yes
Isolatie - Steenwol hard | Begane grond | Isolatie - Steenwol hard | 374.061 | 4235 | 30 | 0.12705 | 2.33788 | 3.27154 | Component Quantities - Projected Component Area (Net): 77.9294 m2; Projected Component Area (Gross): 109.051 m2; Component Thickness: 30 mm; Material Properties - Isolatie - Steenwol hard, ThermalConductivity: 0.043; Isolatie - Steenwol hard, SpecificHeatCapacity: 840 J/kg/K; Isolatie - Steenwol hard, MassDensity: 160 kg/m3; Isolatie - Steenwol hard, Embodied Energy: 16.8 (MJ/kg); Isolatie - Steenwol hard, Embodied Carbon: 1.05 (kgCO₂/kg); Isolatie - Steenwol hard, Name: Isolatie - Steenwol hard; Isolatie - Steenwol hard, Participates in Collision Detection: yes
Membraan - dampopen | Begane grond | Membraan - dampopen | 141.369 | 4235 | 2 | 0.00847 | 0.155351 | 0.217595 | Component Quantities - Projected Component Area (Net): 77.6753 m2; Projected Component Area (Gross): 108.797 m2; Component Thickness: 2 mm; Material Properties - Membraan - dampopen, ThermalConductivity: 0.22; Membraan - dampopen, SpecificHeatCapacity: 1800 J/kg/K; Membraan - dampopen, MassDensity: 910 kg/m3; Membraan - dampopen, Embodied Energy: 99.2 (MJ/kg); Membraan - dampopen, Embodied Carbon: 3.43 (kgCO₂/kg); Membraan - dampopen, Name: Membraan - dampopen; Membraan - dampopen, Participates in Collision Detection: yes
Metaal - Staal AFW | Begane grond | Metaal - Staal AFW | 1684.6 | 4255 | 4 | 0.01702 | 0.211899 | 0.211899 | Component Quantities - Projected Component Area (Net): 52.9748 m2; Projected Component Area (Gross): 52.9748 m2; Component Thickness: 4 mm; Material Properties - Metaal - Staal AFW, ThermalConductivity: 52; Metaal - Staal AFW, SpecificHeatCapacity: 530 J/kg/K; Metaal - Staal AFW, MassDensity: 7950 kg/m3; Metaal - Staal AFW, Embodied Energy: 25 (MJ/kg); Metaal - Staal AFW, Embodied Carbon: 1.91 (kgCO₂/kg); Metaal - Staal AFW, Name: Metaal - Staal AFW; Metaal - Staal AFW, Participates in Collision Detection: yes
Isolatie - Glaswol hard | Begane grond | Isolatie - Glaswol hard | 664.729 | 4255 | 196 | 0.83398 | 10.3864 | 10.3864 | Component Quantities - Projected Component Area (Net): 52.9918 m2; Projected Component Area (Gross): 52.9918 m2; Component Thickness: 196 mm; Material Properties - Isolatie - Glaswol hard, ThermalConductivity: 0.033; Isolatie - Glaswol hard, SpecificHeatCapacity: 1030 J/kg/K; Isolatie - Glaswol hard, MassDensity: 64 kg/m3; Isolatie - Glaswol hard, Embodied Energy: 37 (MJ/kg); Isolatie - Glaswol hard, Embodied Carbon: 1.48 (kgCO₂/kg); Isolatie - Glaswol hard, Name: Isolatie - Glaswol hard; Isolatie - Glaswol hard, Participates in Collision Detection: yes
Steen - Baksteen AFW | Begane grond | Steen - Baksteen AFW | 5827.25 | 4255 | 100 | 0.4255 | 3.64203 | 5.3996 | Component Quantities - Projected Component Area (Net): 36.4203 m2; Projected Component Area (Gross): 53.996 m2; Component Thickness: 100 mm; Material Properties - Steen - Baksteen AFW, ThermalConductivity: 0.9; Steen - Baksteen AFW, SpecificHeatCapacity: 840 J/kg/K; Steen - Baksteen AFW, MassDensity: 1600 kg/m3; Steen - Baksteen AFW, Embodied Energy: 3 (MJ/kg); Steen - Baksteen AFW, Embodied Carbon: 0.23 (kgCO₂/kg); Steen - Baksteen AFW, Name: Steen - Baksteen AFW; Steen - Baksteen AFW, Participates in Collision Detection: yes
2 x Gipsplaat | Begane grond | Gipsplaat | 140.253 | 3470 | 12.5 | 0.043375 | 0.175316 | 0.268118 | Component Quantities - Projected Component Area (Net): 14.0253 m2; Projected Component Area (Gross): 21.4495 m2; Component Thickness: 12.5 mm; Material Properties - Gipsplaat, ThermalConductivity: 0.23; Gipsplaat, SpecificHeatCapacity: 840 J/kg/K; Gipsplaat, MassDensity: 800 kg/m3; Gipsplaat, Embodied Energy: 6.75 (MJ/kg); Gipsplaat, Embodied Carbon: 0.38 (kgCO₂/kg); Gipsplaat, Name: Gipsplaat; Gipsplaat, Participates in Collision Detection: yes
2 x Gipsplaat | Begane grond | Gipsplaat | 140.676 | 3470 | 12.5 | 0.043375 | 0.175845 | 0.268648 | Component Quantities - Projected Component Area (Net): 14.0676 m2; Projected Component Area (Gross): 21.4918 m2; Component Thickness: 12.5 mm; Material Properties - Gipsplaat, ThermalConductivity: 0.23; Gipsplaat, SpecificHeatCapacity: 840 J/kg/K; Gipsplaat, MassDensity: 800 kg/m3; Gipsplaat, Embodied Energy: 6.75 (MJ/kg); Gipsplaat, Embodied Carbon: 0.38 (kgCO₂/kg); Gipsplaat, Name: Gipsplaat; Gipsplaat, Participates in Collision Detection: yes
Isolatie - Steenwol LSW | Begane grond | Isolatie - Steenwol LSW | 39.7348 | 3470 | 50 | 0.1735 | 0.72245 | 1.09366 | Component Quantities - Projected Component Area (Net): 14.449 m2; Projected Component Area (Gross): 21.8732 m2; Component Thickness: 50 mm; Material Properties - Isolatie - Steenwol LSW, ThermalConductivity: 0.039; Isolatie - Steenwol LSW, SpecificHeatCapacity: 840 J/kg/K; Isolatie - Steenwol LSW, MassDensity: 55 kg/m3; Isolatie - Steenwol LSW, Embodied Energy: 16.8 (MJ/kg); Isolatie - Steenwol LSW, Embodied Carbon: 1.05 (kgCO₂/kg); Isolatie - Steenwol LSW, Name: Isolatie - Steenwol LSW; Isolatie - Steenwol LSW, Participates in Collision Detection: yes
Gipsplaat | Begane grond | Gipsplaat | 6.5933 | 3470 | 12.5 | 0.043375 | 0.00824162 | 0.00824162 | Component Quantities - Projected Component Area (Net): 0.65933 m2; Projected Component Area (Gross): 0.65933 m2; Component Thickness: 12.5 mm; Material Properties - Gipsplaat, ThermalConductivity: 0.23; Gipsplaat, SpecificHeatCapacity: 840 J/kg/K; Gipsplaat, MassDensity: 800 kg/m3; Gipsplaat, Embodied Energy: 6.75 (MJ/kg); Gipsplaat, Embodied Carbon: 0.38 (kgCO₂/kg); Gipsplaat, Name: Gipsplaat; Gipsplaat, Participates in Collision Detection: yes
Gipsplaat | Begane grond | Gipsplaat | 6.16955 | 3470 | 12.5 | 0.043375 | 0.00771193 | 0.00771193 | Component Quantities - Projected Component Area (Net): 0.616955 m2; Projected Component Area (Gross): 0.616955 m2; Component Thickness: 12.5 mm; Material Properties - Gipsplaat, ThermalConductivity: 0.23; Gipsplaat, SpecificHeatCapacity: 840 J/kg/K; Gipsplaat, MassDensity: 800 kg/m3; Gipsplaat, Embodied Energy: 6.75 (MJ/kg); Gipsplaat, Embodied Carbon: 0.38 (kgCO₂/kg); Gipsplaat, Name: Gipsplaat; Gipsplaat, Participates in Collision Detection: yes
2 x Gipsplaat | Begane grond | Gipsplaat | 183.54 | 3470 | 12.5 | 0.043375 | 0.229425 | 0.32205 | Component Quantities - Projected Component Area (Net): 18.354 m2; Projected Component Area (Gross): 25.764 m2; Component Thickness: 12.5 mm; Material Properties - Gipsplaat, ThermalConductivity: 0.23; Gipsplaat, SpecificHeatCapacity: 840 J/kg/K; Gipsplaat, MassDensity: 800 kg/m3; Gipsplaat, Embodied Energy: 6.75 (MJ/kg); Gipsplaat, Embodied Carbon: 0.38 (kgCO₂/kg); Gipsplaat, Name: Gipsplaat; Gipsplaat, Participates in Collision Detection: yes
2 x Gipsplaat | Begane grond | Gipsplaat | 183.963 | 3470 | 12.5 | 0.043375 | 0.229954 | 0.322579 | Component Quantities - Projected Component Area (Net): 18.3963 m2; Projected Component Area (Gross): 25.8063 m2; Component Thickness: 12.5 mm; Material Properties - Gipsplaat, ThermalConductivity: 0.23; Gipsplaat, SpecificHeatCapacity: 840 J/kg/K; Gipsplaat, MassDensity: 800 kg/m3; Gipsplaat, Embodied Energy: 6.75 (MJ/kg); Gipsplaat, Embodied Carbon: 0.38 (kgCO₂/kg); Gipsplaat, Name: Gipsplaat; Gipsplaat, Participates in Collision Detection: yes
Isolatie - Steenwol LSW | Begane grond | Isolatie - Steenwol LSW | 50.6013 | 3470 | 50 | 0.1735 | 0.920023 | 1.29052 | Component Quantities - Projected Component Area (Net): 18.4387 m2; Projected Component Area (Gross): 25.8487 m2; Component Thickness: 50 mm; Material Properties - Isolatie - Steenwol LSW, ThermalConductivity: 0.039; Isolatie - Steenwol LSW, SpecificHeatCapacity: 840 J/kg/K; Isolatie - Steenwol LSW, MassDensity: 55 kg/m3; Isolatie - Steenwol LSW, Embodied Energy: 16.8 (MJ/kg); Isolatie - Steenwol LSW, Embodied Carbon: 1.05 (kgCO₂/kg); Isolatie - Steenwol LSW, Name: Isolatie - Steenwol LSW; Isolatie - Steenwol LSW, Participates in Collision Detection: yes
2 x Gipsplaat | Begane grond | Gipsplaat | 19.24 | 520 | 12.5 | 0.0065 | 0.02405 | 0.02405 | Component Quantities - Projected Component Area (Net): 1.924 m2; Projected Component Area (Gross): 1.924 m2; Component Thickness: 12.5 mm; Material Properties - Gipsplaat, ThermalConductivity: 0.23; Gipsplaat, SpecificHeatCapacity: 840 J/kg/K; Gipsplaat, MassDensity: 800 kg/m3; Gipsplaat, Embodied Energy: 6.75 (MJ/kg); Gipsplaat, Embodied Carbon: 0.38 (kgCO₂/kg); Gipsplaat, Name: Gipsplaat; Gipsplaat, Participates in Collision Detection: yes
2 x Gipsplaat | Begane grond | Gipsplaat | 3.74 | 3400 | 12.5 | 0.0425 | 0.004675 | 0.004675 | Component Quantities - Projected Component Area (Net): 0.374 m2; Projected Component Area (Gross): 0.374 m2; Component Thickness: 12.5 mm; Material Properties - Gipsplaat, ThermalConductivity: 0.23; Gipsplaat, SpecificHeatCapacity: 840 J/kg/K; Gipsplaat, MassDensity: 800 kg/m3; Gipsplaat, Embodied Energy: 6.75 (MJ/kg); Gipsplaat, Embodied Carbon: 0.38 (kgCO₂/kg); Gipsplaat, Name: Gipsplaat; Gipsplaat, Participates in Collision Detection: yes
Gipsplaat | Begane grond | Gipsplaat | 37.1701 | 3400 | 12.5 | 0.0425 | 0.0464626 | 0.0464626 | Component Quantities - Projected Component Area (Net): 3.71701 m2; Projected Component Area (Gross): 3.71701 m2; Component Thickness: 12.5 mm; Material Properties - Gipsplaat, ThermalConductivity: 0.23; Gipsplaat, SpecificHeatCapacity: 840 J/kg/K; Gipsplaat, MassDensity: 800 kg/m3; Gipsplaat, Embodied Energy: 6.75 (MJ/kg); Gipsplaat, Embodied Carbon: 0.38 (kgCO₂/kg); Gipsplaat, Name: Gipsplaat; Gipsplaat, Participates in Collision Detection: yes
3 x Gipsplaat | Begane grond | Gipsplaat | 38.0201 | 3400 | 12.5 | 0.0425 | 0.0475251 | 0.0475251 | Component Quantities - Projected Component Area (Net): 3.80201 m2; Projected Component Area (Gross): 3.80201 m2; Component Thickness: 12.5 mm; Material Properties - Gipsplaat, ThermalConductivity: 0.23; Gipsplaat, SpecificHeatCapacity: 840 J/kg/K; Gipsplaat, MassDensity: 800 kg/m3; Gipsplaat, Embodied Energy: 6.75 (MJ/kg); Gipsplaat, Embodied Carbon: 0.38 (kgCO₂/kg); Gipsplaat, Name: Gipsplaat; Gipsplaat, Participates in Collision Detection: yes
Gipsplaat | Begane grond | Gipsplaat | 77.5402 | 3470 | 12.5 | 0.043375 | 0.0969253 | 0.164218 | Component Quantities - Projected Component Area (Net): 7.75402 m2; Projected Component Area (Gross): 13.1374 m2; Component Thickness: 12.5 mm; Material Properties - Gipsplaat, ThermalConductivity: 0.23; Gipsplaat, SpecificHeatCapacity: 840 J/kg/K; Gipsplaat, MassDensity: 800 kg/m3; Gipsplaat, Embodied Energy: 6.75 (MJ/kg); Gipsplaat, Embodied Carbon: 0.38 (kgCO₂/kg); Gipsplaat, Name: Gipsplaat; Gipsplaat, Participates in Collision Detection: yes
Gipsplaat | Begane grond | Gipsplaat | 77.974 | 3470 | 12.5 | 0.043375 | 0.0974675 | 0.16476 | Component Quantities - Projected Component Area (Net): 7.7974 m2; Projected Component Area (Gross): 13.1808 m2; Component Thickness: 12.5 mm; Material Properties - Gipsplaat, ThermalConductivity: 0.23; Gipsplaat, SpecificHeatCapacity: 840 J/kg/K; Gipsplaat, MassDensity: 800 kg/m3; Gipsplaat, Embodied Energy: 6.75 (MJ/kg); Gipsplaat, Embodied Carbon: 0.38 (kgCO₂/kg); Gipsplaat, Name: Gipsplaat; Gipsplaat, Participates in Collision Detection: yes
Isolatie - Steenwol LSW | Begane grond | Isolatie - Steenwol LSW | 21.5621 | 3470 | 50 | 0.1735 | 0.392039 | 0.661209 | Component Quantities - Projected Component Area (Net): 7.84077 m2; Projected Component Area (Gross): 13.2242 m2; Component Thickness: 50 mm; Material Properties - Isolatie - Steenwol LSW, ThermalConductivity: 0.039; Isolatie - Steenwol LSW, SpecificHeatCapacity: 840 J/kg/K; Isolatie - Steenwol LSW, MassDensity: 55 kg/m3; Isolatie - Steenwol LSW, Embodied Energy: 16.8 (MJ/kg); Isolatie - Steenwol LSW, Embodied Carbon: 1.05 (kgCO₂/kg); Isolatie - Steenwol LSW, Name: Isolatie - Steenwol LSW; Isolatie - Steenwol LSW, Participates in Collision Detection: yes
Gipsplaat | Begane grond | Gipsplaat | 76.239 | 3470 | 12.5 | 0.043375 | 0.0952987 | 0.162591 | Component Quantities - Projected Component Area (Net): 7.6239 m2; Projected Component Area (Gross): 13.0073 m2; Component Thickness: 12.5 mm; Material Properties - Gipsplaat, ThermalConductivity: 0.23; Gipsplaat, SpecificHeatCapacity: 840 J/kg/K; Gipsplaat, MassDensity: 800 kg/m3; Gipsplaat, Embodied Energy: 6.75 (MJ/kg); Gipsplaat, Embodied Carbon: 0.38 (kgCO₂/kg); Gipsplaat, Name: Gipsplaat; Gipsplaat, Participates in Collision Detection: yes
Gipsplaat | Begane grond | Gipsplaat | 74.9377 | 3470 | 12.5 | 0.043375 | 0.0936721 | 0.160965 | Component Quantities - Projected Component Area (Net): 7.49377 m2; Projected Component Area (Gross): 12.8772 m2; Component Thickness: 12.5 mm; Material Properties - Gipsplaat, ThermalConductivity: 0.23; Gipsplaat, SpecificHeatCapacity: 840 J/kg/K; Gipsplaat, MassDensity: 800 kg/m3; Gipsplaat, Embodied Energy: 6.75 (MJ/kg); Gipsplaat, Embodied Carbon: 0.38 (kgCO₂/kg); Gipsplaat, Name: Gipsplaat; Gipsplaat, Participates in Collision Detection: yes
Gipsplaat | Begane grond | Gipsplaat | 17.35 | 3470 | 12.5 | 0.043375 | 0.0216875 | 0.0216875 | Component Quantities - Projected Component Area (Net): 1.735 m2; Projected Component Area (Gross): 1.735 m2; Component Thickness: 12.5 mm; Material Properties - Gipsplaat, ThermalConductivity: 0.23; Gipsplaat, SpecificHeatCapacity: 840 J/kg/K; Gipsplaat, MassDensity: 800 kg/m3; Gipsplaat, Embodied Energy: 6.75 (MJ/kg); Gipsplaat, Embodied Carbon: 0.38 (kgCO₂/kg); Gipsplaat, Name: Gipsplaat; Gipsplaat, Participates in Collision Detection: yes
Gipsplaat | Begane grond | Gipsplaat | 18.2175 | 3470 | 12.5 | 0.043375 | 0.0227719 | 0.0227719 | Component Quantities - Projected Component Area (Net): 1.82175 m2; Projected Component Area (Gross): 1.82175 m2; Component Thickness: 12.5 mm; Material Properties - Gipsplaat, ThermalConductivity: 0.23; Gipsplaat, SpecificHeatCapacity: 840 J/kg/K; Gipsplaat, MassDensity: 800 kg/m3; Gipsplaat, Embodied Energy: 6.75 (MJ/kg); Gipsplaat, Embodied Carbon: 0.38 (kgCO₂/kg); Gipsplaat, Name: Gipsplaat; Gipsplaat, Participates in Collision Detection: yes
Isolatie - Steenwol LSW | Begane grond | Isolatie - Steenwol LSW | 5.24838 | 3470 | 50 | 0.1735 | 0.095425 | 0.095425 | Component Quantities - Projected Component Area (Net): 1.9085 m2; Projected Component Area (Gross): 1.9085 m2; Component Thickness: 50 mm; Material Properties - Isolatie - Steenwol LSW, ThermalConductivity: 0.039; Isolatie - Steenwol LSW, SpecificHeatCapacity: 840 J/kg/K; Isolatie - Steenwol LSW, MassDensity: 55 kg/m3; Isolatie - Steenwol LSW, Embodied Energy: 16.8 (MJ/kg); Isolatie - Steenwol LSW, Embodied Carbon: 1.05 (kgCO₂/kg); Isolatie - Steenwol LSW, Name: Isolatie - Steenwol LSW; Isolatie - Steenwol LSW, Participates in Collision Detection: yes
2 x Gipsplaat | Begane grond | Gipsplaat | 20.3863 | 3470 | 12.5 | 0.043375 | 0.0254828 | 0.0254828 | Component Quantities - Projected Component Area (Net): 2.03863 m2; Projected Component Area (Gross): 2.03863 m2; Component Thickness: 12.5 mm; Material Properties - Gipsplaat, ThermalConductivity: 0.23; Gipsplaat, SpecificHeatCapacity: 840 J/kg/K; Gipsplaat, MassDensity: 800 kg/m3; Gipsplaat, Embodied Energy: 6.75 (MJ/kg); Gipsplaat, Embodied Carbon: 0.38 (kgCO₂/kg); Gipsplaat, Name: Gipsplaat; Gipsplaat, Participates in Collision Detection: yes
Gipsplaat | Begane grond | Gipsplaat | 279.371 | 3470 | 12.5 | 0.043375 | 0.349214 | 0.404271 | Component Quantities - Projected Component Area (Net): 27.9371 m2; Projected Component Area (Gross): 32.3417 m2; Component Thickness: 12.5 mm; Material Properties - Gipsplaat, ThermalConductivity: 0.23; Gipsplaat, SpecificHeatCapacity: 840 J/kg/K; Gipsplaat, MassDensity: 800 kg/m3; Gipsplaat, Embodied Energy: 6.75 (MJ/kg); Gipsplaat, Embodied Carbon: 0.38 (kgCO₂/kg); Gipsplaat, Name: Gipsplaat; Gipsplaat, Participates in Collision Detection: yes
Gipsplaat | Begane grond | Gipsplaat | 280.642 | 3470 | 12.5 | 0.043375 | 0.350803 | 0.40586 | Component Quantities - Projected Component Area (Net): 28.0642 m2; Projected Component Area (Gross): 32.4688 m2; Component Thickness: 12.5 mm; Material Properties - Gipsplaat, ThermalConductivity: 0.23; Gipsplaat, SpecificHeatCapacity: 840 J/kg/K; Gipsplaat, MassDensity: 800 kg/m3; Gipsplaat, Embodied Energy: 6.75 (MJ/kg); Gipsplaat, Embodied Carbon: 0.38 (kgCO₂/kg); Gipsplaat, Name: Gipsplaat; Gipsplaat, Participates in Collision Detection: yes
Isolatie - Steenwol LSW | Begane grond | Isolatie - Steenwol LSW | 77.9924 | 3470 | 50 | 0.1735 | 1.41804 | 1.63827 | Component Quantities - Projected Component Area (Net): 28.3609 m2; Projected Component Area (Gross): 32.7655 m2; Component Thickness: 50 mm; Material Properties - Isolatie - Steenwol LSW, ThermalConductivity: 0.039; Isolatie - Steenwol LSW, SpecificHeatCapacity: 840 J/kg/K; Isolatie - Steenwol LSW, MassDensity: 55 kg/m3; Isolatie - Steenwol LSW, Embodied Energy: 16.8 (MJ/kg); Isolatie - Steenwol LSW, Embodied Carbon: 1.05 (kgCO₂/kg); Isolatie - Steenwol LSW, Name: Isolatie - Steenwol LSW; Isolatie - Steenwol LSW, Participates in Collision Detection: yes
Gipsplaat | Begane grond | Gipsplaat | 281.914 | 3470 | 12.5 | 0.043375 | 0.352392 | 0.40745 | Component Quantities - Projected Component Area (Net): 28.1914 m2; Projected Component Area (Gross): 32.596 m2; Component Thickness: 12.5 mm; Material Properties - Gipsplaat, ThermalConductivity: 0.23; Gipsplaat, SpecificHeatCapacity: 840 J/kg/K; Gipsplaat, MassDensity: 800 kg/m3; Gipsplaat, Embodied Energy: 6.75 (MJ/kg); Gipsplaat, Embodied Carbon: 0.38 (kgCO₂/kg); Gipsplaat, Name: Gipsplaat; Gipsplaat, Participates in Collision Detection: yes
Gipsplaat | Begane grond | Gipsplaat | 281.49 | 3470 | 12.5 | 0.043375 | 0.351862 | 0.40692 | Component Quantities - Projected Component Area (Net): 28.149 m2; Projected Component Area (Gross): 32.5536 m2; Component Thickness: 12.5 mm; Material Properties - Gipsplaat, ThermalConductivity: 0.23; Gipsplaat, SpecificHeatCapacity: 840 J/kg/K; Gipsplaat, MassDensity: 800 kg/m3; Gipsplaat, Embodied Energy: 6.75 (MJ/kg); Gipsplaat, Embodied Carbon: 0.38 (kgCO₂/kg); Gipsplaat, Name: Gipsplaat; Gipsplaat, Participates in Collision Detection: yes
Gipsplaat | Begane grond | Gipsplaat | 207.114 | 3470 | 12.5 | 0.043375 | 0.258892 | 0.258892 | Component Quantities - Projected Component Area (Net): 20.7114 m2; Projected Component Area (Gross): 20.7114 m2; Component Thickness: 12.5 mm; Material Properties - Gipsplaat, ThermalConductivity: 0.23; Gipsplaat, SpecificHeatCapacity: 840 J/kg/K; Gipsplaat, MassDensity: 800 kg/m3; Gipsplaat, Embodied Energy: 6.75 (MJ/kg); Gipsplaat, Embodied Carbon: 0.38 (kgCO₂/kg); Gipsplaat, Name: Gipsplaat; Gipsplaat, Participates in Collision Detection: yes
Gipsplaat | Begane grond | Gipsplaat | 208.405 | 3470 | 12.5 | 0.043375 | 0.260506 | 0.260506 | Component Quantities - Projected Component Area (Net): 20.8405 m2; Projected Component Area (Gross): 20.8405 m2; Component Thickness: 12.5 mm; Material Properties - Gipsplaat, ThermalConductivity: 0.23; Gipsplaat, SpecificHeatCapacity: 840 J/kg/K; Gipsplaat, MassDensity: 800 kg/m3; Gipsplaat, Embodied Energy: 6.75 (MJ/kg); Gipsplaat, Embodied Carbon: 0.38 (kgCO₂/kg); Gipsplaat, Name: Gipsplaat; Gipsplaat, Participates in Collision Detection: yes
Isolatie - Steenwol LSW | Begane grond | Isolatie - Steenwol LSW | 57.905 | 3470 | 50 | 0.1735 | 1.05282 | 1.05282 | Component Quantities - Projected Component Area (Net): 21.0564 m2; Projected Component Area (Gross): 21.0564 m2; Component Thickness: 50 mm; Material Properties - Isolatie - Steenwol LSW, ThermalConductivity: 0.039; Isolatie - Steenwol LSW, SpecificHeatCapacity: 840 J/kg/K; Isolatie - Steenwol LSW, MassDensity: 55 kg/m3; Isolatie - Steenwol LSW, Embodied Energy: 16.8 (MJ/kg); Isolatie - Steenwol LSW, Embodied Carbon: 1.05 (kgCO₂/kg); Isolatie - Steenwol LSW, Name: Isolatie - Steenwol LSW; Isolatie - Steenwol LSW, Participates in Collision Detection: yes
Gipsplaat | Begane grond | Gipsplaat | 210.14 | 3470 | 12.5 | 0.043375 | 0.262675 | 0.262675 | Component Quantities - Projected Component Area (Net): 21.014 m2; Projected Component Area (Gross): 21.014 m2; Component Thickness: 12.5 mm; Material Properties - Gipsplaat, ThermalConductivity: 0.23; Gipsplaat, SpecificHeatCapacity: 840 J/kg/K; Gipsplaat, MassDensity: 800 kg/m3; Gipsplaat, Embodied Energy: 6.75 (MJ/kg); Gipsplaat, Embodied Carbon: 0.38 (kgCO₂/kg); Gipsplaat, Name: Gipsplaat; Gipsplaat, Participates in Collision Detection: yes
Gipsplaat | Begane grond | Gipsplaat | 209.716 | 3470 | 12.5 | 0.043375 | 0.262145 | 0.262145 | Component Quantities - Projected Component Area (Net): 20.9716 m2; Projected Component Area (Gross): 20.9716 m2; Component Thickness: 12.5 mm; Material Properties - Gipsplaat, ThermalConductivity: 0.23; Gipsplaat, SpecificHeatCapacity: 840 J/kg/K; Gipsplaat, MassDensity: 800 kg/m3; Gipsplaat, Embodied Energy: 6.75 (MJ/kg); Gipsplaat, Embodied Carbon: 0.38 (kgCO₂/kg); Gipsplaat, Name: Gipsplaat; Gipsplaat, Participates in Collision Detection: yes
Gipsplaat | Begane grond | Gipsplaat | 134.41 | 3470 | 12.5 | 0.043375 | 0.168013 | 0.168013 | Component Quantities - Projected Component Area (Net): 13.441 m2; Projected Component Area (Gross): 13.441 m2; Component Thickness: 12.5 mm; Material Properties - Gipsplaat, ThermalConductivity: 0.23; Gipsplaat, SpecificHeatCapacity: 840 J/kg/K; Gipsplaat, MassDensity: 800 kg/m3; Gipsplaat, Embodied Energy: 6.75 (MJ/kg); Gipsplaat, Embodied Carbon: 0.38 (kgCO₂/kg); Gipsplaat, Name: Gipsplaat; Gipsplaat, Participates in Collision Detection: yes
Gipsplaat | Begane grond | Gipsplaat | 133.977 | 3470 | 12.5 | 0.043375 | 0.167471 | 0.167471 | Component Quantities - Projected Component Area (Net): 13.3977 m2; Projected Component Area (Gross): 13.3977 m2; Component Thickness: 12.5 mm; Material Properties - Gipsplaat, ThermalConductivity: 0.23; Gipsplaat, SpecificHeatCapacity: 840 J/kg/K; Gipsplaat, MassDensity: 800 kg/m3; Gipsplaat, Embodied Energy: 6.75 (MJ/kg); Gipsplaat, Embodied Carbon: 0.38 (kgCO₂/kg); Gipsplaat, Name: Gipsplaat; Gipsplaat, Participates in Collision Detection: yes
Isolatie - Steenwol LSW | Begane grond | Isolatie - Steenwol LSW | 36.2903 | 3470 | 50 | 0.1735 | 0.659824 | 0.659824 | Component Quantities - Projected Component Area (Net): 13.2242 m2; Projected Component Area (Gross): 13.2242 m2; Component Thickness: 50 mm; Material Properties - Isolatie - Steenwol LSW, ThermalConductivity: 0.039; Isolatie - Steenwol LSW, SpecificHeatCapacity: 840 J/kg/K; Isolatie - Steenwol LSW, MassDensity: 55 kg/m3; Isolatie - Steenwol LSW, Embodied Energy: 16.8 (MJ/kg); Isolatie - Steenwol LSW, Embodied Carbon: 1.05 (kgCO₂/kg); Isolatie - Steenwol LSW, Name: Isolatie - Steenwol LSW; Isolatie - Steenwol LSW, Participates in Collision Detection: yes
Hout - MDF binnenzijde | Begane grond | Hout - MDF binnenzijde | 35.428 | 729 | 20 | 0.01458 | 0.035428 | 0.035428 | Material Properties - Hout - MDF binnenzijde, ThermalConductivity: 0.24; Hout - MDF binnenzijde, SpecificHeatCapacity: 1600 J/kg/K; Hout - MDF binnenzijde, MassDensity: 1000 kg/m3; Hout - MDF binnenzijde, Embodied Energy: 16.8 (MJ/kg); Hout - MDF binnenzijde, Embodied Carbon: 0.87 (kgCO₂/kg); Hout - MDF binnenzijde, Name: Hout - MDF binnenzijde; Hout - MDF binnenzijde, Participates in Collision Detection: yes
2 x Hout - MDF binnenzijde | Begane grond | Hout - MDF binnenzijde | 7.2897 | 150 | 20 | 0.003 | 0.0072897 | 0.0072897 | Material Properties - Hout - MDF binnenzijde, ThermalConductivity: 0.24; Hout - MDF binnenzijde, SpecificHeatCapacity: 1600 J/kg/K; Hout - MDF binnenzijde, MassDensity: 1000 kg/m3; Hout - MDF binnenzijde, Embodied Energy: 16.8 (MJ/kg); Hout - MDF binnenzijde, Embodied Carbon: 0.87 (kgCO₂/kg); Hout - MDF binnenzijde, Name: Hout - MDF binnenzijde; Hout - MDF binnenzijde, Participates in Collision Detection: yes
2 x Hout - algemeen | Begane grond | Hout - algemeen | 3.11027 | 20 | 80 | 0.0016 | 0.00388784 | 0.00388784 | Material Properties - Hout - algemeen, ThermalConductivity: 0.17; Hout - algemeen, SpecificHeatCapacity: 1880 J/kg/K; Hout - algemeen, MassDensity: 800 kg/m3; Hout - algemeen, Embodied Energy: 10.4 (MJ/kg); Hout - algemeen, Embodied Carbon: 0.23 (kgCO₂/kg); Hout - algemeen, Name: Hout - algemeen; Hout - algemeen, Participates in Collision Detection: yes
Lucht_wit | Begane grond | Lucht_wit | 0.160957 | 690 | 80 | 0.0552 | 0.13413 | 0.13413 | Material Properties - Lucht_wit, ThermalConductivity: 0.15; Lucht_wit, SpecificHeatCapacity: 1008 J/kg/K; Lucht_wit, MassDensity: 1.2 kg/m3; Lucht_wit, Embodied Energy: 0 (MJ/kg); Lucht_wit, Embodied Carbon: 0 (kgCO₂/kg); Lucht_wit, Name: Lucht_wit; Lucht_wit, Participates in Collision Detection: yes
Hout - MDF binnenzijde | Begane grond | Hout - MDF binnenzijde | 5.83176 | 20 | 120 | 0.0024 | 0.00583176 | 0.00583176 | Material Properties - Hout - MDF binnenzijde, ThermalConductivity: 0.24; Hout - MDF binnenzijde, SpecificHeatCapacity: 1600 J/kg/K; Hout - MDF binnenzijde, MassDensity: 1000 kg/m3; Hout - MDF binnenzijde, Embodied Energy: 16.8 (MJ/kg); Hout - MDF binnenzijde, Embodied Carbon: 0.87 (kgCO₂/kg); Hout - MDF binnenzijde, Name: Hout - MDF binnenzijde; Hout - MDF binnenzijde, Participates in Collision Detection: yes
Hout - MDF binnenzijde | Begane grond | Hout - MDF binnenzijde | 35.4279 | 729 | 20 | 0.01458 | 0.0354279 | 0.0354279 | Material Properties - Hout - MDF binnenzijde, ThermalConductivity: 0.24; Hout - MDF binnenzijde, SpecificHeatCapacity: 1600 J/kg/K; Hout - MDF binnenzijde, MassDensity: 1000 kg/m3; Hout - MDF binnenzijde, Embodied Energy: 16.8 (MJ/kg); Hout - MDF binnenzijde, Embodied Carbon: 0.87 (kgCO₂/kg); Hout - MDF binnenzijde, Name: Hout - MDF binnenzijde; Hout - MDF binnenzijde, Participates in Collision Detection: yes
2 x Hout - MDF binnenzijde | Begane grond | Hout - MDF binnenzijde | 2.916 | 729 | 20 | 0.01458 | 0.002916 | 0.002916 | Material Properties - Hout - MDF binnenzijde, ThermalConductivity: 0.24; Hout - MDF binnenzijde, SpecificHeatCapacity: 1600 J/kg/K; Hout - MDF binnenzijde, MassDensity: 1000 kg/m3; Hout - MDF binnenzijde, Embodied Energy: 16.8 (MJ/kg); Hout - MDF binnenzijde, Embodied Carbon: 0.87 (kgCO₂/kg); Hout - MDF binnenzijde, Name: Hout - MDF binnenzijde; Hout - MDF binnenzijde, Participates in Collision Detection: yes
2 x Hout - MDF binnenzijde | Begane grond | Hout - MDF binnenzijde | 0.6 | 150 | 20 | 0.003 | 0.0006 | 0.0006 | Material Properties - Hout - MDF binnenzijde, ThermalConductivity: 0.24; Hout - MDF binnenzijde, SpecificHeatCapacity: 1600 J/kg/K; Hout - MDF binnenzijde, MassDensity: 1000 kg/m3; Hout - MDF binnenzijde, Embodied Energy: 16.8 (MJ/kg); Hout - MDF binnenzijde, Embodied Carbon: 0.87 (kgCO₂/kg); Hout - MDF binnenzijde, Name: Hout - MDF binnenzijde; Hout - MDF binnenzijde, Participates in Collision Detection: yes
Hout - MDF binnenzijde | Begane grond | Hout - MDF binnenzijde | 0.48 | 20 | 120 | 0.0024 | 0.00048 | 0.00048 | Material Properties - Hout - MDF binnenzijde, ThermalConductivity: 0.24; Hout - MDF binnenzijde, SpecificHeatCapacity: 1600 J/kg/K; Hout - MDF binnenzijde, MassDensity: 1000 kg/m3; Hout - MDF binnenzijde, Embodied Energy: 16.8 (MJ/kg); Hout - MDF binnenzijde, Embodied Carbon: 0.87 (kgCO₂/kg); Hout - MDF binnenzijde, Name: Hout - MDF binnenzijde; Hout - MDF binnenzijde, Participates in Collision Detection: yes
Lucht_wit | Begane grond | Lucht_wit | 0.013248 | 690 | 80 | 0.0552 | 0.01104 | 0.01104 | Material Properties - Lucht_wit, ThermalConductivity: 0.15; Lucht_wit, SpecificHeatCapacity: 1008 J/kg/K; Lucht_wit, MassDensity: 1.2 kg/m3; Lucht_wit, Embodied Energy: 0 (MJ/kg); Lucht_wit, Embodied Carbon: 0 (kgCO₂/kg); Lucht_wit, Name: Lucht_wit; Lucht_wit, Participates in Collision Detection: yes
2 x Hout - algemeen | Begane grond | Hout - algemeen | 0.256 | 20 | 80 | 0.0016 | 0.00032 | 0.00032 | Material Properties - Hout - algemeen, ThermalConductivity: 0.17; Hout - algemeen, SpecificHeatCapacity: 1880 J/kg/K; Hout - algemeen, MassDensity: 800 kg/m3; Hout - algemeen, Embodied Energy: 10.4 (MJ/kg); Hout - algemeen, Embodied Carbon: 0.23 (kgCO₂/kg); Hout - algemeen, Name: Hout - algemeen; Hout - algemeen, Participates in Collision Detection: yes
Gipsplaat | Begane grond | Gipsplaat | 77.8848 | 3470 | 12.5 | 0.043375 | 0.097356 | 0.097356 | Component Quantities - Projected Component Area (Net): 7.78848 m2; Projected Component Area (Gross): 7.78848 m2; Component Thickness: 12.5 mm; Material Properties - Gipsplaat, ThermalConductivity: 0.23; Gipsplaat, SpecificHeatCapacity: 840 J/kg/K; Gipsplaat, MassDensity: 800 kg/m3; Gipsplaat, Embodied Energy: 6.75 (MJ/kg); Gipsplaat, Embodied Carbon: 0.38 (kgCO₂/kg); Gipsplaat, Name: Gipsplaat; Gipsplaat, Participates in Collision Detection: yes
Gipsplaat | Begane grond | Gipsplaat | 78.3185 | 3470 | 12.5 | 0.043375 | 0.0978982 | 0.0978982 | Component Quantities - Projected Component Area (Net): 7.83185 m2; Projected Component Area (Gross): 7.83185 m2; Component Thickness: 12.5 mm; Material Properties - Gipsplaat, ThermalConductivity: 0.23; Gipsplaat, SpecificHeatCapacity: 840 J/kg/K; Gipsplaat, MassDensity: 800 kg/m3; Gipsplaat, Embodied Energy: 6.75 (MJ/kg); Gipsplaat, Embodied Carbon: 0.38 (kgCO₂/kg); Gipsplaat, Name: Gipsplaat; Gipsplaat, Participates in Collision Detection: yes
Isolatie - Steenwol LSW | Begane grond | Isolatie - Steenwol LSW | 22.0147 | 3470 | 50 | 0.1735 | 0.400268 | 0.400268 | Component Quantities - Projected Component Area (Net): 8.00535 m2; Projected Component Area (Gross): 8.00535 m2; Component Thickness: 50 mm; Material Properties - Isolatie - Steenwol LSW, ThermalConductivity: 0.039; Isolatie - Steenwol LSW, SpecificHeatCapacity: 840 J/kg/K; Isolatie - Steenwol LSW, MassDensity: 55 kg/m3; Isolatie - Steenwol LSW, Embodied Energy: 16.8 (MJ/kg); Isolatie - Steenwol LSW, Embodied Carbon: 1.05 (kgCO₂/kg); Isolatie - Steenwol LSW, Name: Isolatie - Steenwol LSW; Isolatie - Steenwol LSW, Participates in Collision Detection: yes
Gipsplaat | Begane grond | Gipsplaat | 80.4873 | 3470 | 12.5 | 0.043375 | 0.100609 | 0.100609 | Component Quantities - Projected Component Area (Net): 8.04873 m2; Projected Component Area (Gross): 8.04873 m2; Component Thickness: 12.5 mm; Material Properties - Gipsplaat, ThermalConductivity: 0.23; Gipsplaat, SpecificHeatCapacity: 840 J/kg/K; Gipsplaat, MassDensity: 800 kg/m3; Gipsplaat, Embodied Energy: 6.75 (MJ/kg); Gipsplaat, Embodied Carbon: 0.38 (kgCO₂/kg); Gipsplaat, Name: Gipsplaat; Gipsplaat, Participates in Collision Detection: yes
Gipsplaat | Begane grond | Gipsplaat | 80.921 | 3470 | 12.5 | 0.043375 | 0.101151 | 0.101151 | Component Quantities - Projected Component Area (Net): 8.0921 m2; Projected Component Area (Gross): 8.0921 m2; Component Thickness: 12.5 mm; Material Properties - Gipsplaat, ThermalConductivity: 0.23; Gipsplaat, SpecificHeatCapacity: 840 J/kg/K; Gipsplaat, MassDensity: 800 kg/m3; Gipsplaat, Embodied Energy: 6.75 (MJ/kg); Gipsplaat, Embodied Carbon: 0.38 (kgCO₂/kg); Gipsplaat, Name: Gipsplaat; Gipsplaat, Participates in Collision Detection: yes
Steen - Kalkzandsteen C | Begane grond | Steen - Kalkzandsteen C | 13143.2 | 4235 | 150 | 0.63525 | 6.91749 | 14.5802 | Component Quantities - Projected Component Area (Net): 46.1166 m2; Projected Component Area (Gross): 97.2017 m2; Component Thickness: 150 mm; Material Properties - Steen - Kalkzandsteen C, ThermalConductivity: 0.9; Steen - Kalkzandsteen C, SpecificHeatCapacity: 840 J/kg/K; Steen - Kalkzandsteen C, MassDensity: 1900 kg/m3; Steen - Kalkzandsteen C, Embodied Energy: 0.75 (MJ/kg); Steen - Kalkzandsteen C, Embodied Carbon: 0.1 (kgCO₂/kg); Steen - Kalkzandsteen C, Name: Steen - Kalkzandsteen C; Steen - Kalkzandsteen C, Participates in Collision Detection: yes
ALG - ISOLATIE | Begane grond | ALG - ISOLATIE | 433.246 | 4235 | 150 | 0.63525 | 9.6277 | 14.8115 | Component Quantities - Projected Component Area (Net): 65.2164 m2; Projected Component Area (Gross): 98.7432 m2; Component Thickness: 150 mm; Material Properties - ALG - ISOLATIE, ThermalConductivity: 0.035; ALG - ISOLATIE, SpecificHeatCapacity: 840 J/kg/K; ALG - ISOLATIE, MassDensity: 45 kg/m3; ALG - ISOLATIE, Embodied Energy: 16.8 (MJ/kg); ALG - ISOLATIE, Embodied Carbon: 1.05 (kgCO₂/kg); ALG - ISOLATIE, Name: ALG - ISOLATIE; ALG - ISOLATIE, Participates in Collision Detection: yes
Steen - Baksteen AFW | Begane grond | Steen - Baksteen AFW | 5253.06 | 4235 | 100 | 0.4235 | 3.28316 | 9.99375 | Component Quantities - Projected Component Area (Net): 32.8936 m2; Projected Component Area (Gross): 99.9375 m2; Component Thickness: 100 mm; Material Properties - Steen - Baksteen AFW, ThermalConductivity: 0.9; Steen - Baksteen AFW, SpecificHeatCapacity: 840 J/kg/K; Steen - Baksteen AFW, MassDensity: 1600 kg/m3; Steen - Baksteen AFW, Embodied Energy: 3 (MJ/kg); Steen - Baksteen AFW, Embodied Carbon: 0.23 (kgCO₂/kg); Steen - Baksteen AFW, Name: Steen - Baksteen AFW; Steen - Baksteen AFW, Participates in Collision Detection: yes
Steen - Kalkzandsteen C | Begane grond | Steen - Kalkzandsteen C | 781.269 | 4235 | 150 | 0.63525 | 0.411194 | 0.501847 | Component Quantities - Projected Component Area (Net): 2.7413 m2; Projected Component Area (Gross): 3.34564 m2; Component Thickness: 150 mm; Material Properties - Steen - Kalkzandsteen C, ThermalConductivity: 0.9; Steen - Kalkzandsteen C, SpecificHeatCapacity: 840 J/kg/K; Steen - Kalkzandsteen C, MassDensity: 1900 kg/m3; Steen - Kalkzandsteen C, Embodied Energy: 0.75 (MJ/kg); Steen - Kalkzandsteen C, Embodied Carbon: 0.1 (kgCO₂/kg); Steen - Kalkzandsteen C, Name: Steen - Kalkzandsteen C; Steen - Kalkzandsteen C, Participates in Collision Detection: yes
ALG - ISOLATIE | Begane grond | ALG - ISOLATIE | 22.5831 | 4235 | 150 | 0.63525 | 0.501847 | 0.501847 | Component Quantities - Projected Component Area (Net): 3.34564 m2; Projected Component Area (Gross): 3.34564 m2; Component Thickness: 150 mm; Material Properties - ALG - ISOLATIE, ThermalConductivity: 0.035; ALG - ISOLATIE, SpecificHeatCapacity: 840 J/kg/K; ALG - ISOLATIE, MassDensity: 45 kg/m3; ALG - ISOLATIE, Embodied Energy: 16.8 (MJ/kg); ALG - ISOLATIE, Embodied Carbon: 1.05 (kgCO₂/kg); ALG - ISOLATIE, Name: ALG - ISOLATIE; ALG - ISOLATIE, Participates in Collision Detection: yes
Isolatie - Steenwol hard | Begane grond | Isolatie - Steenwol hard | 19.2303 | 4235 | 30 | 0.12705 | 0.120189 | 0.120189 | Component Quantities - Projected Component Area (Net): 4.0063 m2; Projected Component Area (Gross): 4.0063 m2; Component Thickness: 30 mm; Material Properties - Isolatie - Steenwol hard, ThermalConductivity: 0.043; Isolatie - Steenwol hard, SpecificHeatCapacity: 840 J/kg/K; Isolatie - Steenwol hard, MassDensity: 160 kg/m3; Isolatie - Steenwol hard, Embodied Energy: 16.8 (MJ/kg); Isolatie - Steenwol hard, Embodied Carbon: 1.05 (kgCO₂/kg); Isolatie - Steenwol hard, Name: Isolatie - Steenwol hard; Isolatie - Steenwol hard, Participates in Collision Detection: yes
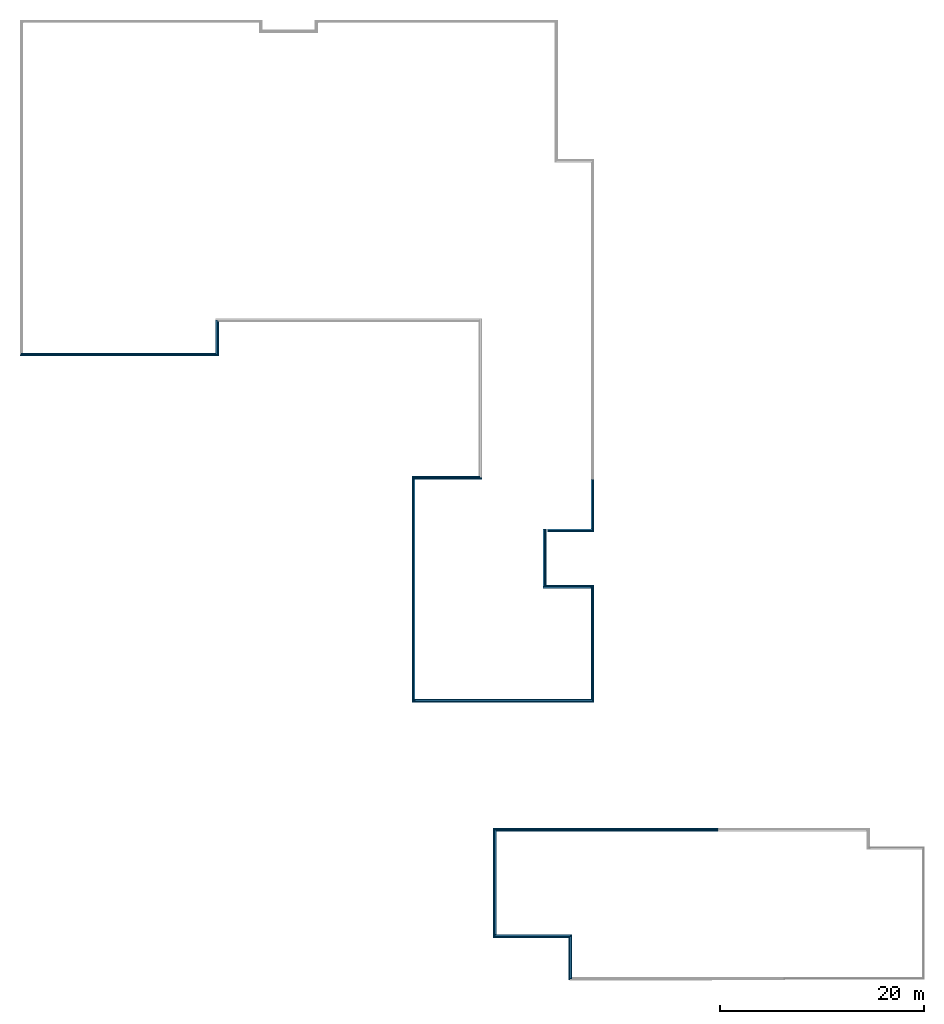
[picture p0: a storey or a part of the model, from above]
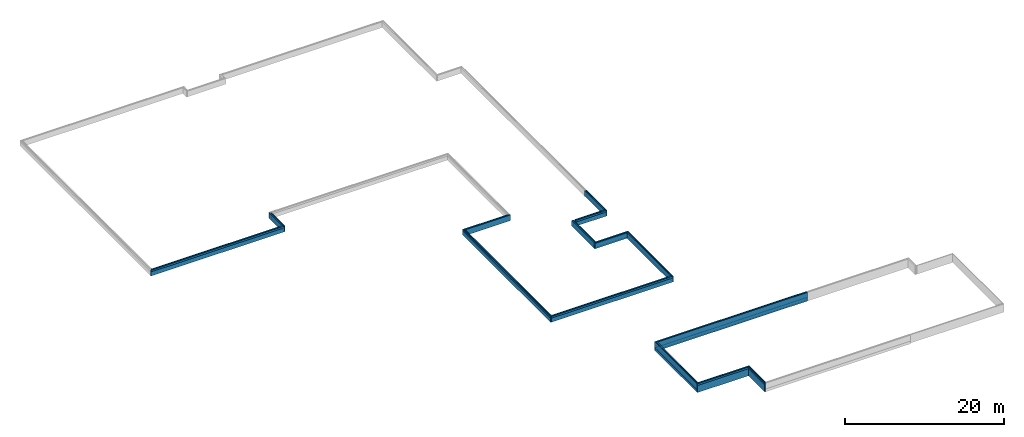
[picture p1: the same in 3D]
Properties of the parts of a building model (IFC2X3), part 8 of 19

# IfcBuildingElementPart (2070)
Name | In | Material | Mass (kg) | Rectangular Component Height (mm) | Rectangular Component Width (mm) | Component Cross Section Area (m2) | Component Volume (Net) (m3) | Component Volume (Gross) (m3)
Membraan - dampopen | Begane grond | Membraan - dampopen | 7.27606 | 4235 | 2 | 0.00847 | 0.00799567 | 0.00799567 | Component Quantities - Projected Component Area (Net): 3.99783 m2; Projected Component Area (Gross): 3.99783 m2; Component Thickness: 2 mm; Material Properties - Membraan - dampopen, ThermalConductivity: 0.22; Membraan - dampopen, SpecificHeatCapacity: 1800 J/kg/K; Membraan - dampopen, MassDensity: 910 kg/m3; Membraan - dampopen, Embodied Energy: 99.2 (MJ/kg); Membraan - dampopen, Embodied Carbon: 3.43 (kgCO₂/kg); Membraan - dampopen, Name: Membraan - dampopen; Membraan - dampopen, Participates in Collision Detection: yes
Membraan - dampopen | Begane grond | Membraan - dampopen | 7.27607 | 4235 | 2 | 0.00847 | 0.00799568 | 0.00799568 | Component Quantities - Projected Component Area (Net): 3.99784 m2; Projected Component Area (Gross): 3.99784 m2; Component Thickness: 2 mm; Material Properties - Membraan - dampopen, ThermalConductivity: 0.22; Membraan - dampopen, SpecificHeatCapacity: 1800 J/kg/K; Membraan - dampopen, MassDensity: 910 kg/m3; Membraan - dampopen, Embodied Energy: 99.2 (MJ/kg); Membraan - dampopen, Embodied Carbon: 3.43 (kgCO₂/kg); Membraan - dampopen, Name: Membraan - dampopen; Membraan - dampopen, Participates in Collision Detection: yes
Isolatie - Steenwol hard | Begane grond | Isolatie - Steenwol hard | 19.2303 | 4235 | 30 | 0.12705 | 0.120189 | 0.120189 | Component Quantities - Projected Component Area (Net): 4.00631 m2; Projected Component Area (Gross): 4.00631 m2; Component Thickness: 30 mm; Material Properties - Isolatie - Steenwol hard, ThermalConductivity: 0.043; Isolatie - Steenwol hard, SpecificHeatCapacity: 840 J/kg/K; Isolatie - Steenwol hard, MassDensity: 160 kg/m3; Isolatie - Steenwol hard, Embodied Energy: 16.8 (MJ/kg); Isolatie - Steenwol hard, Embodied Carbon: 1.05 (kgCO₂/kg); Isolatie - Steenwol hard, Name: Isolatie - Steenwol hard; Isolatie - Steenwol hard, Participates in Collision Detection: yes
ALG - ISOLATIE | Begane grond | ALG - ISOLATIE | 22.5831 | 4235 | 150 | 0.63525 | 0.501848 | 0.501848 | Component Quantities - Projected Component Area (Net): 3.34565 m2; Projected Component Area (Gross): 3.34565 m2; Component Thickness: 150 mm; Material Properties - ALG - ISOLATIE, ThermalConductivity: 0.035; ALG - ISOLATIE, SpecificHeatCapacity: 840 J/kg/K; ALG - ISOLATIE, MassDensity: 45 kg/m3; ALG - ISOLATIE, Embodied Energy: 16.8 (MJ/kg); ALG - ISOLATIE, Embodied Carbon: 1.05 (kgCO₂/kg); ALG - ISOLATIE, Name: ALG - ISOLATIE; ALG - ISOLATIE, Participates in Collision Detection: yes
Steen - Kalkzandsteen C | Begane grond | Steen - Kalkzandsteen C | 1537.88 | 4235 | 214 | 0.90629 | 0.809412 | 0.987856 | Component Quantities - Projected Component Area (Net): 3.7823 m2; Projected Component Area (Gross): 4.61615 m2; Component Thickness: 214 mm; Material Properties - Steen - Kalkzandsteen C, ThermalConductivity: 0.9; Steen - Kalkzandsteen C, SpecificHeatCapacity: 840 J/kg/K; Steen - Kalkzandsteen C, MassDensity: 1900 kg/m3; Steen - Kalkzandsteen C, Embodied Energy: 0.75 (MJ/kg); Steen - Kalkzandsteen C, Embodied Carbon: 0.1 (kgCO₂/kg); Steen - Kalkzandsteen C, Name: Steen - Kalkzandsteen C; Steen - Kalkzandsteen C, Participates in Collision Detection: yes
2 x Gipsplaat | Begane grond | Gipsplaat | 73.3706 | 3190 | 12.5 | 0.039875 | 0.0917132 | 0.0917132 | Component Quantities - Projected Component Area (Net): 7.33706 m2; Projected Component Area (Gross): 7.33706 m2; Component Thickness: 12.5 mm; Material Properties - Gipsplaat, ThermalConductivity: 0.23; Gipsplaat, SpecificHeatCapacity: 840 J/kg/K; Gipsplaat, MassDensity: 800 kg/m3; Gipsplaat, Embodied Energy: 6.75 (MJ/kg); Gipsplaat, Embodied Carbon: 0.38 (kgCO₂/kg); Gipsplaat, Name: Gipsplaat; Gipsplaat, Participates in Collision Detection: yes
Isolatie - Steenwol LSW | Begane grond | Isolatie - Steenwol LSW | 20.1769 | 3190 | 50 | 0.1595 | 0.366853 | 0.366853 | Component Quantities - Projected Component Area (Net): 7.33706 m2; Projected Component Area (Gross): 7.33706 m2; Component Thickness: 50 mm; Material Properties - Isolatie - Steenwol LSW, ThermalConductivity: 0.039; Isolatie - Steenwol LSW, SpecificHeatCapacity: 840 J/kg/K; Isolatie - Steenwol LSW, MassDensity: 55 kg/m3; Isolatie - Steenwol LSW, Embodied Energy: 16.8 (MJ/kg); Isolatie - Steenwol LSW, Embodied Carbon: 1.05 (kgCO₂/kg); Isolatie - Steenwol LSW, Name: Isolatie - Steenwol LSW; Isolatie - Steenwol LSW, Participates in Collision Detection: yes
Gipsplaat | Begane grond | Gipsplaat | 31.5013 | 3190 | 12.5 | 0.039875 | 0.0393766 | 0.0393766 | Component Quantities - Projected Component Area (Net): 3.15013 m2; Projected Component Area (Gross): 3.15013 m2; Component Thickness: 12.5 mm; Material Properties - Gipsplaat, ThermalConductivity: 0.23; Gipsplaat, SpecificHeatCapacity: 840 J/kg/K; Gipsplaat, MassDensity: 800 kg/m3; Gipsplaat, Embodied Energy: 6.75 (MJ/kg); Gipsplaat, Embodied Carbon: 0.38 (kgCO₂/kg); Gipsplaat, Name: Gipsplaat; Gipsplaat, Participates in Collision Detection: yes
Gipsplaat | Begane grond | Gipsplaat | 31.9 | 3190 | 12.5 | 0.039875 | 0.039875 | 0.039875 | Component Quantities - Projected Component Area (Net): 3.19 m2; Projected Component Area (Gross): 3.19 m2; Component Thickness: 12.5 mm; Material Properties - Gipsplaat, ThermalConductivity: 0.23; Gipsplaat, SpecificHeatCapacity: 840 J/kg/K; Gipsplaat, MassDensity: 800 kg/m3; Gipsplaat, Embodied Energy: 6.75 (MJ/kg); Gipsplaat, Embodied Carbon: 0.38 (kgCO₂/kg); Gipsplaat, Name: Gipsplaat; Gipsplaat, Participates in Collision Detection: yes
Gipsplaat | Begane grond | Gipsplaat | 5.104 | 3190 | 12.5 | 0.039875 | 0.00638 | 0.00638 | Component Quantities - Projected Component Area (Net): 0.5104 m2; Projected Component Area (Gross): 0.5104 m2; Component Thickness: 12.5 mm; Material Properties - Gipsplaat, ThermalConductivity: 0.23; Gipsplaat, SpecificHeatCapacity: 840 J/kg/K; Gipsplaat, MassDensity: 800 kg/m3; Gipsplaat, Embodied Energy: 6.75 (MJ/kg); Gipsplaat, Embodied Carbon: 0.38 (kgCO₂/kg); Gipsplaat, Name: Gipsplaat; Gipsplaat, Participates in Collision Detection: yes
Gipsplaat | Begane grond | Gipsplaat | 5.50275 | 3190 | 12.5 | 0.039875 | 0.00687844 | 0.00687844 | Component Quantities - Projected Component Area (Net): 0.550275 m2; Projected Component Area (Gross): 0.550275 m2; Component Thickness: 12.5 mm; Material Properties - Gipsplaat, ThermalConductivity: 0.23; Gipsplaat, SpecificHeatCapacity: 840 J/kg/K; Gipsplaat, MassDensity: 800 kg/m3; Gipsplaat, Embodied Energy: 6.75 (MJ/kg); Gipsplaat, Embodied Carbon: 0.38 (kgCO₂/kg); Gipsplaat, Name: Gipsplaat; Gipsplaat, Participates in Collision Detection: yes
Isolatie - Steenwol LSW | Begane grond | Isolatie - Steenwol LSW | 18.1415 | 3190 | 50 | 0.1595 | 0.329846 | 0.329846 | Component Quantities - Projected Component Area (Net): 6.59692 m2; Projected Component Area (Gross): 6.59692 m2; Component Thickness: 50 mm; Material Properties - Isolatie - Steenwol LSW, ThermalConductivity: 0.039; Isolatie - Steenwol LSW, SpecificHeatCapacity: 840 J/kg/K; Isolatie - Steenwol LSW, MassDensity: 55 kg/m3; Isolatie - Steenwol LSW, Embodied Energy: 16.8 (MJ/kg); Isolatie - Steenwol LSW, Embodied Carbon: 1.05 (kgCO₂/kg); Isolatie - Steenwol LSW, Name: Isolatie - Steenwol LSW; Isolatie - Steenwol LSW, Participates in Collision Detection: yes
2 x Gipsplaat | Begane grond | Gipsplaat | 65.9692 | 3190 | 12.5 | 0.039875 | 0.0824615 | 0.0824615 | Component Quantities - Projected Component Area (Net): 6.59692 m2; Projected Component Area (Gross): 6.59692 m2; Component Thickness: 12.5 mm; Material Properties - Gipsplaat, ThermalConductivity: 0.23; Gipsplaat, SpecificHeatCapacity: 840 J/kg/K; Gipsplaat, MassDensity: 800 kg/m3; Gipsplaat, Embodied Energy: 6.75 (MJ/kg); Gipsplaat, Embodied Carbon: 0.38 (kgCO₂/kg); Gipsplaat, Name: Gipsplaat; Gipsplaat, Participates in Collision Detection: yes
Isolatie - Steenwol LSW | Begane grond | Isolatie - Steenwol LSW | 9.21095 | 3190 | 50 | 0.1595 | 0.167472 | 0.167472 | Component Quantities - Projected Component Area (Net): 3.34944 m2; Projected Component Area (Gross): 3.34944 m2; Component Thickness: 50 mm; Material Properties - Isolatie - Steenwol LSW, ThermalConductivity: 0.039; Isolatie - Steenwol LSW, SpecificHeatCapacity: 840 J/kg/K; Isolatie - Steenwol LSW, MassDensity: 55 kg/m3; Isolatie - Steenwol LSW, Embodied Energy: 16.8 (MJ/kg); Isolatie - Steenwol LSW, Embodied Carbon: 1.05 (kgCO₂/kg); Isolatie - Steenwol LSW, Name: Isolatie - Steenwol LSW; Isolatie - Steenwol LSW, Participates in Collision Detection: yes
2 x Gipsplaat | Begane grond | Gipsplaat | 33.4944 | 3190 | 12.5 | 0.039875 | 0.041868 | 0.041868 | Component Quantities - Projected Component Area (Net): 3.34944 m2; Projected Component Area (Gross): 3.34944 m2; Component Thickness: 12.5 mm; Material Properties - Gipsplaat, ThermalConductivity: 0.23; Gipsplaat, SpecificHeatCapacity: 840 J/kg/K; Gipsplaat, MassDensity: 800 kg/m3; Gipsplaat, Embodied Energy: 6.75 (MJ/kg); Gipsplaat, Embodied Carbon: 0.38 (kgCO₂/kg); Gipsplaat, Name: Gipsplaat; Gipsplaat, Participates in Collision Detection: yes
2 x Gipsplaat | Begane grond | Gipsplaat | 33.4933 | 3190 | 12.5 | 0.039875 | 0.0418666 | 0.0418666 | Component Quantities - Projected Component Area (Net): 3.34933 m2; Projected Component Area (Gross): 3.34933 m2; Component Thickness: 12.5 mm; Material Properties - Gipsplaat, ThermalConductivity: 0.23; Gipsplaat, SpecificHeatCapacity: 840 J/kg/K; Gipsplaat, MassDensity: 800 kg/m3; Gipsplaat, Embodied Energy: 6.75 (MJ/kg); Gipsplaat, Embodied Carbon: 0.38 (kgCO₂/kg); Gipsplaat, Name: Gipsplaat; Gipsplaat, Participates in Collision Detection: yes
Isolatie - Steenwol LSW | Begane grond | Isolatie - Steenwol LSW | 9.21065 | 3190 | 50 | 0.1595 | 0.167466 | 0.167466 | Component Quantities - Projected Component Area (Net): 3.34933 m2; Projected Component Area (Gross): 3.34933 m2; Component Thickness: 50 mm; Material Properties - Isolatie - Steenwol LSW, ThermalConductivity: 0.039; Isolatie - Steenwol LSW, SpecificHeatCapacity: 840 J/kg/K; Isolatie - Steenwol LSW, MassDensity: 55 kg/m3; Isolatie - Steenwol LSW, Embodied Energy: 16.8 (MJ/kg); Isolatie - Steenwol LSW, Embodied Carbon: 1.05 (kgCO₂/kg); Isolatie - Steenwol LSW, Name: Isolatie - Steenwol LSW; Isolatie - Steenwol LSW, Participates in Collision Detection: yes
Isolatie - Steenwol LSW | Begane grond | Isolatie - Steenwol LSW | 21.4926 | 3190 | 50 | 0.1595 | 0.390775 | 0.390775 | Component Quantities - Projected Component Area (Net): 7.8155 m2; Projected Component Area (Gross): 7.8155 m2; Component Thickness: 50 mm; Material Properties - Isolatie - Steenwol LSW, ThermalConductivity: 0.039; Isolatie - Steenwol LSW, SpecificHeatCapacity: 840 J/kg/K; Isolatie - Steenwol LSW, MassDensity: 55 kg/m3; Isolatie - Steenwol LSW, Embodied Energy: 16.8 (MJ/kg); Isolatie - Steenwol LSW, Embodied Carbon: 1.05 (kgCO₂/kg); Isolatie - Steenwol LSW, Name: Isolatie - Steenwol LSW; Isolatie - Steenwol LSW, Participates in Collision Detection: yes
2 x Gipsplaat | Begane grond | Gipsplaat | 78.155 | 3190 | 12.5 | 0.039875 | 0.0976938 | 0.0976938 | Component Quantities - Projected Component Area (Net): 7.8155 m2; Projected Component Area (Gross): 7.8155 m2; Component Thickness: 12.5 mm; Material Properties - Gipsplaat, ThermalConductivity: 0.23; Gipsplaat, SpecificHeatCapacity: 840 J/kg/K; Gipsplaat, MassDensity: 800 kg/m3; Gipsplaat, Embodied Energy: 6.75 (MJ/kg); Gipsplaat, Embodied Carbon: 0.38 (kgCO₂/kg); Gipsplaat, Name: Gipsplaat; Gipsplaat, Participates in Collision Detection: yes
2 x Gipsplaat | Begane grond | Gipsplaat | 22.1853 | 1199.2 | 12.5 | 0.01499 | 0.0277316 | 0.0277316 | Component Quantities - Projected Component Area (Net): 2.21853 m2; Projected Component Area (Gross): 2.21853 m2; Component Thickness: 12.5 mm; Material Properties - Gipsplaat, ThermalConductivity: 0.23; Gipsplaat, SpecificHeatCapacity: 840 J/kg/K; Gipsplaat, MassDensity: 800 kg/m3; Gipsplaat, Embodied Energy: 6.75 (MJ/kg); Gipsplaat, Embodied Carbon: 0.38 (kgCO₂/kg); Gipsplaat, Name: Gipsplaat; Gipsplaat, Participates in Collision Detection: yes
Isolatie - Steenwol LSW | Begane grond | Isolatie - Steenwol LSW | 2.38563 | 3470 | 50 | 0.1735 | 0.043375 | 0.043375 | Component Quantities - Projected Component Area (Net): 0.8675 m2; Projected Component Area (Gross): 0.8675 m2; Component Thickness: 50 mm; Material Properties - Isolatie - Steenwol LSW, ThermalConductivity: 0.039; Isolatie - Steenwol LSW, SpecificHeatCapacity: 840 J/kg/K; Isolatie - Steenwol LSW, MassDensity: 55 kg/m3; Isolatie - Steenwol LSW, Embodied Energy: 16.8 (MJ/kg); Isolatie - Steenwol LSW, Embodied Carbon: 1.05 (kgCO₂/kg); Isolatie - Steenwol LSW, Name: Isolatie - Steenwol LSW; Isolatie - Steenwol LSW, Participates in Collision Detection: yes
Gipsplaat | Begane grond | Gipsplaat | 10.8438 | 3470 | 12.5 | 0.043375 | 0.0135547 | 0.0135547 | Component Quantities - Projected Component Area (Net): 1.08438 m2; Projected Component Area (Gross): 1.08438 m2; Component Thickness: 12.5 mm; Material Properties - Gipsplaat, ThermalConductivity: 0.23; Gipsplaat, SpecificHeatCapacity: 840 J/kg/K; Gipsplaat, MassDensity: 800 kg/m3; Gipsplaat, Embodied Energy: 6.75 (MJ/kg); Gipsplaat, Embodied Carbon: 0.38 (kgCO₂/kg); Gipsplaat, Name: Gipsplaat; Gipsplaat, Participates in Collision Detection: yes
Gipsplaat | Begane grond | Gipsplaat | 11.7112 | 3470 | 12.5 | 0.043375 | 0.0146391 | 0.0146391 | Component Quantities - Projected Component Area (Net): 1.17112 m2; Projected Component Area (Gross): 1.17112 m2; Component Thickness: 12.5 mm; Material Properties - Gipsplaat, ThermalConductivity: 0.23; Gipsplaat, SpecificHeatCapacity: 840 J/kg/K; Gipsplaat, MassDensity: 800 kg/m3; Gipsplaat, Embodied Energy: 6.75 (MJ/kg); Gipsplaat, Embodied Carbon: 0.38 (kgCO₂/kg); Gipsplaat, Name: Gipsplaat; Gipsplaat, Participates in Collision Detection: yes
2 x Isolatie - Steenwol LSW | Begane grond | Isolatie - Steenwol LSW | 5.91635 | 3470 | 50 | 0.1735 | 0.10757 | 0.10757 | Component Quantities - Projected Component Area (Net): 2.1514 m2; Projected Component Area (Gross): 2.1514 m2; Component Thickness: 50 mm; Material Properties - Isolatie - Steenwol LSW, ThermalConductivity: 0.039; Isolatie - Steenwol LSW, SpecificHeatCapacity: 840 J/kg/K; Isolatie - Steenwol LSW, MassDensity: 55 kg/m3; Isolatie - Steenwol LSW, Embodied Energy: 16.8 (MJ/kg); Isolatie - Steenwol LSW, Embodied Carbon: 1.05 (kgCO₂/kg); Isolatie - Steenwol LSW, Name: Isolatie - Steenwol LSW; Isolatie - Steenwol LSW, Participates in Collision Detection: yes
4 x Gipsplaat | Begane grond | Gipsplaat | 21.514 | 3470 | 12.5 | 0.043375 | 0.0268925 | 0.0268925 | Component Quantities - Projected Component Area (Net): 2.1514 m2; Projected Component Area (Gross): 2.1514 m2; Component Thickness: 12.5 mm; Material Properties - Gipsplaat, ThermalConductivity: 0.23; Gipsplaat, SpecificHeatCapacity: 840 J/kg/K; Gipsplaat, MassDensity: 800 kg/m3; Gipsplaat, Embodied Energy: 6.75 (MJ/kg); Gipsplaat, Embodied Carbon: 0.38 (kgCO₂/kg); Gipsplaat, Name: Gipsplaat; Gipsplaat, Participates in Collision Detection: yes
Isolatie - Steenwol LSW | Begane grond | Isolatie - Steenwol LSW | 1.62223 | 3470 | 50 | 0.1735 | 0.029495 | 0.029495 | Component Quantities - Projected Component Area (Net): 0.5899 m2; Projected Component Area (Gross): 0.5899 m2; Component Thickness: 50 mm; Material Properties - Isolatie - Steenwol LSW, ThermalConductivity: 0.039; Isolatie - Steenwol LSW, SpecificHeatCapacity: 840 J/kg/K; Isolatie - Steenwol LSW, MassDensity: 55 kg/m3; Isolatie - Steenwol LSW, Embodied Energy: 16.8 (MJ/kg); Isolatie - Steenwol LSW, Embodied Carbon: 1.05 (kgCO₂/kg); Isolatie - Steenwol LSW, Name: Isolatie - Steenwol LSW; Isolatie - Steenwol LSW, Participates in Collision Detection: yes
2 x Gipsplaat | Begane grond | Gipsplaat | 7.20025 | 3470 | 12.5 | 0.043375 | 0.00900031 | 0.00900031 | Component Quantities - Projected Component Area (Net): 0.720025 m2; Projected Component Area (Gross): 0.720025 m2; Component Thickness: 12.5 mm; Material Properties - Gipsplaat, ThermalConductivity: 0.23; Gipsplaat, SpecificHeatCapacity: 840 J/kg/K; Gipsplaat, MassDensity: 800 kg/m3; Gipsplaat, Embodied Energy: 6.75 (MJ/kg); Gipsplaat, Embodied Carbon: 0.38 (kgCO₂/kg); Gipsplaat, Name: Gipsplaat; Gipsplaat, Participates in Collision Detection: yes
2 x Gipsplaat | Begane grond | Gipsplaat | 21.0802 | 3470 | 12.5 | 0.043375 | 0.0263503 | 0.0263503 | Component Quantities - Projected Component Area (Net): 2.10803 m2; Projected Component Area (Gross): 2.10803 m2; Component Thickness: 12.5 mm; Material Properties - Gipsplaat, ThermalConductivity: 0.23; Gipsplaat, SpecificHeatCapacity: 840 J/kg/K; Gipsplaat, MassDensity: 800 kg/m3; Gipsplaat, Embodied Energy: 6.75 (MJ/kg); Gipsplaat, Embodied Carbon: 0.38 (kgCO₂/kg); Gipsplaat, Name: Gipsplaat; Gipsplaat, Participates in Collision Detection: yes
Isolatie - Steenwol LSW | Begane grond | Isolatie - Steenwol LSW | 5.43923 | 3470 | 50 | 0.1735 | 0.098895 | 0.098895 | Component Quantities - Projected Component Area (Net): 1.9779 m2; Projected Component Area (Gross): 1.9779 m2; Component Thickness: 50 mm; Material Properties - Isolatie - Steenwol LSW, ThermalConductivity: 0.039; Isolatie - Steenwol LSW, SpecificHeatCapacity: 840 J/kg/K; Isolatie - Steenwol LSW, MassDensity: 55 kg/m3; Isolatie - Steenwol LSW, Embodied Energy: 16.8 (MJ/kg); Isolatie - Steenwol LSW, Embodied Carbon: 1.05 (kgCO₂/kg); Isolatie - Steenwol LSW, Name: Isolatie - Steenwol LSW; Isolatie - Steenwol LSW, Participates in Collision Detection: yes
Metaal - Staal AFW | Begane grond | Metaal - Staal AFW | 206.267 | 1385 | 4 | 0.00554 | 0.0259455 | 0.0259455 | Component Quantities - Projected Component Area (Net): 6.4816 m2; Projected Component Area (Gross): 6.4816 m2; Component Thickness: 4 mm; Material Properties - Metaal - Staal AFW, ThermalConductivity: 52; Metaal - Staal AFW, SpecificHeatCapacity: 530 J/kg/K; Metaal - Staal AFW, MassDensity: 7950 kg/m3; Metaal - Staal AFW, Embodied Energy: 25 (MJ/kg); Metaal - Staal AFW, Embodied Carbon: 1.91 (kgCO₂/kg); Metaal - Staal AFW, Name: Metaal - Staal AFW; Metaal - Staal AFW, Participates in Collision Detection: yes
Isolatie - Steenwol hard | Begane grond | Isolatie - Steenwol hard | 117.339 | 1385 | 196 | 0.27146 | 0.733366 | 1.27148 | Component Quantities - Projected Component Area (Net): 6.48714 m2; Projected Component Area (Gross): 6.48714 m2; Component Thickness: 196 mm; Material Properties - Isolatie - Steenwol hard, ThermalConductivity: 0.043; Isolatie - Steenwol hard, SpecificHeatCapacity: 840 J/kg/K; Isolatie - Steenwol hard, MassDensity: 160 kg/m3; Isolatie - Steenwol hard, Embodied Energy: 16.8 (MJ/kg); Isolatie - Steenwol hard, Embodied Carbon: 1.05 (kgCO₂/kg); Isolatie - Steenwol hard, Name: Isolatie - Steenwol hard; Isolatie - Steenwol hard, Participates in Collision Detection: yes
Membraan - waterdicht | Begane grond | Membraan - waterdicht | 10.4859 | 1385 | 5 | 0.006925 | 0.00998661 | 0.032408 | Component Quantities - Projected Component Area (Net): 1.99732 m2; Projected Component Area (Gross): 6.4816 m2; Component Thickness: 5 mm; Material Properties - Membraan - waterdicht, ThermalConductivity: 0.2; Membraan - waterdicht, SpecificHeatCapacity: 1840 J/kg/K; Membraan - waterdicht, MassDensity: 1050 kg/m3; Membraan - waterdicht, Embodied Energy: 51 (MJ/kg); Membraan - waterdicht, Embodied Carbon: 0.38 (kgCO₂/kg); Membraan - waterdicht, Name: Membraan - waterdicht; Membraan - waterdicht, Participates in Collision Detection: yes
Steen - Betonblok C | Begane grond | Steen - Betonblok C | 4565.17 | 4235 | 200 | 0.847 | 2.85323 | 3.84114 | Component Quantities - Projected Component Area (Net): 19.2057 m2; Projected Component Area (Gross): 19.2057 m2; Component Thickness: 200 mm; Material Properties - Steen - Betonblok C, ThermalConductivity: 0.75; Steen - Betonblok C, SpecificHeatCapacity: 840 J/kg/K; Steen - Betonblok C, MassDensity: 1600 kg/m3; Steen - Betonblok C, Embodied Energy: 0.83 (MJ/kg); Steen - Betonblok C, Embodied Carbon: 0.1 (kgCO₂/kg); Steen - Betonblok C, Name: Steen - Betonblok C; Steen - Betonblok C, Participates in Collision Detection: yes
ALG - ISOLATIE | Begane grond | ALG - ISOLATIE | 135.356 | 4235 | 150 | 0.63525 | 3.0079 | 3.0079 | Component Quantities - Projected Component Area (Net): 20.0527 m2; Projected Component Area (Gross): 20.0527 m2; Component Thickness: 150 mm; Material Properties - ALG - ISOLATIE, ThermalConductivity: 0.035; ALG - ISOLATIE, SpecificHeatCapacity: 840 J/kg/K; ALG - ISOLATIE, MassDensity: 45 kg/m3; ALG - ISOLATIE, Embodied Energy: 16.8 (MJ/kg); ALG - ISOLATIE, Embodied Carbon: 1.05 (kgCO₂/kg); ALG - ISOLATIE, Name: ALG - ISOLATIE; ALG - ISOLATIE, Participates in Collision Detection: yes
Steen - Baksteen AFW | Begane grond | Steen - Baksteen AFW | 795.403 | 4235 | 100 | 0.4235 | 0.497127 | 2.08404 | Component Quantities - Projected Component Area (Net): 4.97127 m2; Projected Component Area (Gross): 20.8404 m2; Component Thickness: 100 mm; Material Properties - Steen - Baksteen AFW, ThermalConductivity: 0.9; Steen - Baksteen AFW, SpecificHeatCapacity: 840 J/kg/K; Steen - Baksteen AFW, MassDensity: 1600 kg/m3; Steen - Baksteen AFW, Embodied Energy: 3 (MJ/kg); Steen - Baksteen AFW, Embodied Carbon: 0.23 (kgCO₂/kg); Steen - Baksteen AFW, Name: Steen - Baksteen AFW; Steen - Baksteen AFW, Participates in Collision Detection: yes
Isolatie - Akkoestisch | Begane grond | Isolatie - Akkoestisch | 40.9954 | 2780 | 50 | 0.139 | 0.911009 | 0.911009 | Component Quantities - Projected Component Area (Net): 18.2202 m2; Projected Component Area (Gross): 18.2202 m2; Component Thickness: 50 mm; Material Properties - Isolatie - Akkoestisch, ThermalConductivity: 0.035; Isolatie - Akkoestisch, SpecificHeatCapacity: 840 J/kg/K; Isolatie - Akkoestisch, MassDensity: 45 kg/m3; Isolatie - Akkoestisch, Embodied Energy: 16.8 (MJ/kg); Isolatie - Akkoestisch, Embodied Carbon: 1.05 (kgCO₂/kg); Isolatie - Akkoestisch, Name: Isolatie - Akkoestisch; Isolatie - Akkoestisch, Participates in Collision Detection: yes
Hout geperforeerde plaat | Begane grond | Hout geperforeerde plaat | 199.505 | 2780 | 20 | 0.0556 | 0.362736 | 0.362736 | Component Quantities - Projected Component Area (Net): 18.1368 m2; Projected Component Area (Gross): 18.1368 m2; Component Thickness: 20 mm; Material Properties - Hout geperforeerde plaat, ThermalConductivity: 0.14; Hout geperforeerde plaat, SpecificHeatCapacity: 1880 J/kg/K; Hout geperforeerde plaat, MassDensity: 550 kg/m3; Hout geperforeerde plaat, Embodied Energy: 7.4 (MJ/kg); Hout geperforeerde plaat, Embodied Carbon: 0.19 (kgCO₂/kg); Hout geperforeerde plaat, Name: Hout geperforeerde plaat; Hout geperforeerde plaat, Participates in Collision Detection: yes
Steen - Baksteen AFW | Begane grond | Steen - Baksteen AFW | 2369.37 | 4235 | 100 | 0.4235 | 1.48086 | 2.1751 | Component Quantities - Projected Component Area (Net): 14.8768 m2; Projected Component Area (Gross): 21.751 m2; Component Thickness: 100 mm; Material Properties - Steen - Baksteen AFW, ThermalConductivity: 0.9; Steen - Baksteen AFW, SpecificHeatCapacity: 840 J/kg/K; Steen - Baksteen AFW, MassDensity: 1600 kg/m3; Steen - Baksteen AFW, Embodied Energy: 3 (MJ/kg); Steen - Baksteen AFW, Embodied Carbon: 0.23 (kgCO₂/kg); Steen - Baksteen AFW, Name: Steen - Baksteen AFW; Steen - Baksteen AFW, Participates in Collision Detection: yes
ALG - ISOLATIE | Begane grond | ALG - ISOLATIE | 142.931 | 4235 | 150 | 0.63525 | 3.17625 | 3.17625 | Component Quantities - Projected Component Area (Net): 21.175 m2; Projected Component Area (Gross): 21.175 m2; Component Thickness: 150 mm; Material Properties - ALG - ISOLATIE, ThermalConductivity: 0.035; ALG - ISOLATIE, SpecificHeatCapacity: 840 J/kg/K; ALG - ISOLATIE, MassDensity: 45 kg/m3; ALG - ISOLATIE, Embodied Energy: 16.8 (MJ/kg); ALG - ISOLATIE, Embodied Carbon: 1.05 (kgCO₂/kg); ALG - ISOLATIE, Name: ALG - ISOLATIE; ALG - ISOLATIE, Participates in Collision Detection: yes
Steen - Betonblok C | Begane grond | Steen - Betonblok C | 4929.54 | 4235 | 150 | 0.63525 | 3.08096 | 3.08096 | Component Quantities - Projected Component Area (Net): 20.5397 m2; Projected Component Area (Gross): 20.5397 m2; Component Thickness: 150 mm; Material Properties - Steen - Betonblok C, ThermalConductivity: 0.75; Steen - Betonblok C, SpecificHeatCapacity: 840 J/kg/K; Steen - Betonblok C, MassDensity: 1600 kg/m3; Steen - Betonblok C, Embodied Energy: 0.83 (MJ/kg); Steen - Betonblok C, Embodied Carbon: 0.1 (kgCO₂/kg); Steen - Betonblok C, Name: Steen - Betonblok C; Steen - Betonblok C, Participates in Collision Detection: yes
Membraan - waterdicht | Begane grond | Membraan - waterdicht | 17.7372 | 1385 | 5 | 0.006925 | 0.0168926 | 0.0437313 | Component Quantities - Projected Component Area (Net): 3.37852 m2; Projected Component Area (Gross): 8.74626 m2; Component Thickness: 5 mm; Material Properties - Membraan - waterdicht, ThermalConductivity: 0.2; Membraan - waterdicht, SpecificHeatCapacity: 1840 J/kg/K; Membraan - waterdicht, MassDensity: 1050 kg/m3; Membraan - waterdicht, Embodied Energy: 51 (MJ/kg); Membraan - waterdicht, Embodied Carbon: 0.38 (kgCO₂/kg); Membraan - waterdicht, Name: Membraan - waterdicht; Membraan - waterdicht, Participates in Collision Detection: yes
Isolatie - Steenwol hard | Begane grond | Isolatie - Steenwol hard | 123.985 | 1385 | 196 | 0.27146 | 0.774907 | 1.71427 | Component Quantities - Projected Component Area (Net): 8.74626 m2; Projected Component Area (Gross): 8.74626 m2; Component Thickness: 196 mm; Material Properties - Isolatie - Steenwol hard, ThermalConductivity: 0.043; Isolatie - Steenwol hard, SpecificHeatCapacity: 840 J/kg/K; Isolatie - Steenwol hard, MassDensity: 160 kg/m3; Isolatie - Steenwol hard, Embodied Energy: 16.8 (MJ/kg); Isolatie - Steenwol hard, Embodied Carbon: 1.05 (kgCO₂/kg); Isolatie - Steenwol hard, Name: Isolatie - Steenwol hard; Isolatie - Steenwol hard, Participates in Collision Detection: yes
Metaal - Staal AFW | Begane grond | Metaal - Staal AFW | 269.499 | 1385 | 4 | 0.00554 | 0.0338992 | 0.0338992 | Component Quantities - Projected Component Area (Net): 8.4748 m2; Projected Component Area (Gross): 8.4748 m2; Component Thickness: 4 mm; Material Properties - Metaal - Staal AFW, ThermalConductivity: 52; Metaal - Staal AFW, SpecificHeatCapacity: 530 J/kg/K; Metaal - Staal AFW, MassDensity: 7950 kg/m3; Metaal - Staal AFW, Embodied Energy: 25 (MJ/kg); Metaal - Staal AFW, Embodied Carbon: 1.91 (kgCO₂/kg); Metaal - Staal AFW, Name: Metaal - Staal AFW; Metaal - Staal AFW, Participates in Collision Detection: yes
2 x Gipsplaat | Begane grond | Gipsplaat | 38.5897 | 3400 | 12.5 | 0.0425 | 0.0482372 | 0.111237 | Component Quantities - Projected Component Area (Net): 3.85897 m2; Projected Component Area (Gross): 8.89896 m2; Component Thickness: 12.5 mm; Material Properties - Gipsplaat, ThermalConductivity: 0.23; Gipsplaat, SpecificHeatCapacity: 840 J/kg/K; Gipsplaat, MassDensity: 800 kg/m3; Gipsplaat, Embodied Energy: 6.75 (MJ/kg); Gipsplaat, Embodied Carbon: 0.38 (kgCO₂/kg); Gipsplaat, Name: Gipsplaat; Gipsplaat, Participates in Collision Detection: yes
2 x Gipsplaat | Begane grond | Gipsplaat | 39.0047 | 3400 | 12.5 | 0.0425 | 0.0487559 | 0.111756 | Component Quantities - Projected Component Area (Net): 3.90047 m2; Projected Component Area (Gross): 8.94046 m2; Component Thickness: 12.5 mm; Material Properties - Gipsplaat, ThermalConductivity: 0.23; Gipsplaat, SpecificHeatCapacity: 840 J/kg/K; Gipsplaat, MassDensity: 800 kg/m3; Gipsplaat, Embodied Energy: 6.75 (MJ/kg); Gipsplaat, Embodied Carbon: 0.38 (kgCO₂/kg); Gipsplaat, Name: Gipsplaat; Gipsplaat, Participates in Collision Detection: yes
Isolatie - Steenwol LSW | Begane grond | Isolatie - Steenwol LSW | 11.7534 | 3400 | 50 | 0.17 | 0.213699 | 0.465698 | Component Quantities - Projected Component Area (Net): 4.27397 m2; Projected Component Area (Gross): 9.31396 m2; Component Thickness: 50 mm; Material Properties - Isolatie - Steenwol LSW, ThermalConductivity: 0.039; Isolatie - Steenwol LSW, SpecificHeatCapacity: 840 J/kg/K; Isolatie - Steenwol LSW, MassDensity: 55 kg/m3; Isolatie - Steenwol LSW, Embodied Energy: 16.8 (MJ/kg); Isolatie - Steenwol LSW, Embodied Carbon: 1.05 (kgCO₂/kg); Isolatie - Steenwol LSW, Name: Isolatie - Steenwol LSW; Isolatie - Steenwol LSW, Participates in Collision Detection: yes
Steen - Baksteen AFW | Begane grond | Steen - Baksteen AFW | 4727.3 | 4065 | 100 | 0.4065 | 2.95456 | 8.57552 | Component Quantities - Projected Component Area (Net): 29.6212 m2; Projected Component Area (Gross): 85.7552 m2; Component Thickness: 100 mm; Material Properties - Steen - Baksteen AFW, ThermalConductivity: 0.9; Steen - Baksteen AFW, SpecificHeatCapacity: 840 J/kg/K; Steen - Baksteen AFW, MassDensity: 1600 kg/m3; Steen - Baksteen AFW, Embodied Energy: 3 (MJ/kg); Steen - Baksteen AFW, Embodied Carbon: 0.23 (kgCO₂/kg); Steen - Baksteen AFW, Name: Steen - Baksteen AFW; Steen - Baksteen AFW, Participates in Collision Detection: yes
ALG - ISOLATIE | Begane grond | ALG - ISOLATIE | 576.214 | 4065 | 150 | 0.60975 | 12.8048 | 12.8048 | Component Quantities - Projected Component Area (Net): 85.365 m2; Projected Component Area (Gross): 85.365 m2; Component Thickness: 150 mm; Material Properties - ALG - ISOLATIE, ThermalConductivity: 0.035; ALG - ISOLATIE, SpecificHeatCapacity: 840 J/kg/K; ALG - ISOLATIE, MassDensity: 45 kg/m3; ALG - ISOLATIE, Embodied Energy: 16.8 (MJ/kg); ALG - ISOLATIE, Embodied Carbon: 1.05 (kgCO₂/kg); ALG - ISOLATIE, Name: ALG - ISOLATIE; ALG - ISOLATIE, Participates in Collision Detection: yes
Steen - Betonblok C | Begane grond | Steen - Betonblok C | 15845.9 | 4065 | 150 | 0.60975 | 9.90366 | 12.6218 | Component Quantities - Projected Component Area (Net): 66.033 m2; Projected Component Area (Gross): 84.1455 m2; Component Thickness: 150 mm; Material Properties - Steen - Betonblok C, ThermalConductivity: 0.75; Steen - Betonblok C, SpecificHeatCapacity: 840 J/kg/K; Steen - Betonblok C, MassDensity: 1600 kg/m3; Steen - Betonblok C, Embodied Energy: 0.83 (MJ/kg); Steen - Betonblok C, Embodied Carbon: 0.1 (kgCO₂/kg); Steen - Betonblok C, Name: Steen - Betonblok C; Steen - Betonblok C, Participates in Collision Detection: yes
Membraan - dampopen | Begane grond | Membraan - dampopen | 8.83768 | 4065 | 2 | 0.00813 | 0.00971174 | 0.0145231 | Component Quantities - Projected Component Area (Net): 4.85587 m2; Projected Component Area (Gross): 7.26157 m2; Component Thickness: 2 mm; Material Properties - Membraan - dampopen, ThermalConductivity: 0.22; Membraan - dampopen, SpecificHeatCapacity: 1800 J/kg/K; Membraan - dampopen, MassDensity: 910 kg/m3; Membraan - dampopen, Embodied Energy: 99.2 (MJ/kg); Membraan - dampopen, Embodied Carbon: 3.43 (kgCO₂/kg); Membraan - dampopen, Name: Membraan - dampopen; Membraan - dampopen, Participates in Collision Detection: yes
Isolatie - Steenwol hard | Begane grond | Isolatie - Steenwol hard | 28.2752 | 4065 | 30 | 0.12195 | 0.17672 | 0.220023 | Component Quantities - Projected Component Area (Net): 7.33409 m2; Projected Component Area (Gross): 7.33409 m2; Component Thickness: 30 mm; Material Properties - Isolatie - Steenwol hard, ThermalConductivity: 0.043; Isolatie - Steenwol hard, SpecificHeatCapacity: 840 J/kg/K; Isolatie - Steenwol hard, MassDensity: 160 kg/m3; Isolatie - Steenwol hard, Embodied Energy: 16.8 (MJ/kg); Isolatie - Steenwol hard, Embodied Carbon: 1.05 (kgCO₂/kg); Isolatie - Steenwol hard, Name: Isolatie - Steenwol hard; Isolatie - Steenwol hard, Participates in Collision Detection: yes
ALG - ISOLATIE | Begane grond | ALG - ISOLATIE | 49.3897 | 4065 | 150 | 0.60975 | 1.09755 | 1.09755 | Component Quantities - Projected Component Area (Net): 7.317 m2; Projected Component Area (Gross): 7.317 m2; Component Thickness: 150 mm; Material Properties - ALG - ISOLATIE, ThermalConductivity: 0.035; ALG - ISOLATIE, SpecificHeatCapacity: 840 J/kg/K; ALG - ISOLATIE, MassDensity: 45 kg/m3; ALG - ISOLATIE, Embodied Energy: 16.8 (MJ/kg); ALG - ISOLATIE, Embodied Carbon: 1.05 (kgCO₂/kg); ALG - ISOLATIE, Name: ALG - ISOLATIE; ALG - ISOLATIE, Participates in Collision Detection: yes
Steen - Betonblok C | Begane grond | Steen - Betonblok C | 1378.08 | 4065 | 150 | 0.60975 | 0.861299 | 1.09755 | Component Quantities - Projected Component Area (Net): 5.74199 m2; Projected Component Area (Gross): 7.317 m2; Component Thickness: 150 mm; Material Properties - Steen - Betonblok C, ThermalConductivity: 0.75; Steen - Betonblok C, SpecificHeatCapacity: 840 J/kg/K; Steen - Betonblok C, MassDensity: 1600 kg/m3; Steen - Betonblok C, Embodied Energy: 0.83 (MJ/kg); Steen - Betonblok C, Embodied Carbon: 0.1 (kgCO₂/kg); Steen - Betonblok C, Name: Steen - Betonblok C; Steen - Betonblok C, Participates in Collision Detection: yes
Steen - Baksteen AFW | Begane grond | Steen - Baksteen AFW | 8698.43 | 4065 | 100 | 0.4065 | 5.43652 | 14.9316 | Component Quantities - Projected Component Area (Net): 54.3745 m2; Projected Component Area (Gross): 149.316 m2; Component Thickness: 100 mm; Material Properties - Steen - Baksteen AFW, ThermalConductivity: 0.9; Steen - Baksteen AFW, SpecificHeatCapacity: 840 J/kg/K; Steen - Baksteen AFW, MassDensity: 1600 kg/m3; Steen - Baksteen AFW, Embodied Energy: 3 (MJ/kg); Steen - Baksteen AFW, Embodied Carbon: 0.23 (kgCO₂/kg); Steen - Baksteen AFW, Name: Steen - Baksteen AFW; Steen - Baksteen AFW, Participates in Collision Detection: yes
ALG - ISOLATIE | Begane grond | ALG - ISOLATIE | 888.263 | 4065 | 150 | 0.60975 | 19.7392 | 22.2254 | Component Quantities - Projected Component Area (Net): 132.118 m2; Projected Component Area (Gross): 148.169 m2; Component Thickness: 150 mm; Material Properties - ALG - ISOLATIE, ThermalConductivity: 0.035; ALG - ISOLATIE, SpecificHeatCapacity: 840 J/kg/K; ALG - ISOLATIE, MassDensity: 45 kg/m3; ALG - ISOLATIE, Embodied Energy: 16.8 (MJ/kg); ALG - ISOLATIE, Embodied Carbon: 1.05 (kgCO₂/kg); ALG - ISOLATIE, Name: ALG - ISOLATIE; ALG - ISOLATIE, Participates in Collision Detection: yes
Steen - Betonblok C | Begane grond | Steen - Betonblok C | 23709.1 | 4065 | 150 | 0.60975 | 14.8182 | 21.951 | Component Quantities - Projected Component Area (Net): 98.7886 m2; Projected Component Area (Gross): 146.34 m2; Component Thickness: 150 mm; Material Properties - Steen - Betonblok C, ThermalConductivity: 0.75; Steen - Betonblok C, SpecificHeatCapacity: 840 J/kg/K; Steen - Betonblok C, MassDensity: 1600 kg/m3; Steen - Betonblok C, Embodied Energy: 0.83 (MJ/kg); Steen - Betonblok C, Embodied Carbon: 0.1 (kgCO₂/kg); Steen - Betonblok C, Name: Steen - Betonblok C; Steen - Betonblok C, Participates in Collision Detection: yes
Hout geperforeerde plaat | Begane grond | Hout geperforeerde plaat | 88.2228 | 2780 | 20 | 0.0556 | 0.160405 | 0.160405 | Component Quantities - Projected Component Area (Net): 8.02026 m2; Projected Component Area (Gross): 8.02026 m2; Component Thickness: 20 mm; Material Properties - Hout geperforeerde plaat, ThermalConductivity: 0.14; Hout geperforeerde plaat, SpecificHeatCapacity: 1880 J/kg/K; Hout geperforeerde plaat, MassDensity: 550 kg/m3; Hout geperforeerde plaat, Embodied Energy: 7.4 (MJ/kg); Hout geperforeerde plaat, Embodied Carbon: 0.19 (kgCO₂/kg); Hout geperforeerde plaat, Name: Hout geperforeerde plaat; Hout geperforeerde plaat, Participates in Collision Detection: yes
Isolatie - Akkoestisch | Begane grond | Isolatie - Akkoestisch | 18.0456 | 2780 | 50 | 0.139 | 0.401013 | 0.401013 | Component Quantities - Projected Component Area (Net): 8.02026 m2; Projected Component Area (Gross): 8.02026 m2; Component Thickness: 50 mm; Material Properties - Isolatie - Akkoestisch, ThermalConductivity: 0.035; Isolatie - Akkoestisch, SpecificHeatCapacity: 840 J/kg/K; Isolatie - Akkoestisch, MassDensity: 45 kg/m3; Isolatie - Akkoestisch, Embodied Energy: 16.8 (MJ/kg); Isolatie - Akkoestisch, Embodied Carbon: 1.05 (kgCO₂/kg); Isolatie - Akkoestisch, Name: Isolatie - Akkoestisch; Isolatie - Akkoestisch, Participates in Collision Detection: yes
Hout geperforeerde plaat | Begane grond | Hout geperforeerde plaat | 375.626 | 2780 | 20 | 0.0556 | 0.682956 | 0.682956 | Component Quantities - Projected Component Area (Net): 34.1756 m2; Projected Component Area (Gross): 34.1756 m2; Component Thickness: 20 mm; Material Properties - Hout geperforeerde plaat, ThermalConductivity: 0.14; Hout geperforeerde plaat, SpecificHeatCapacity: 1880 J/kg/K; Hout geperforeerde plaat, MassDensity: 550 kg/m3; Hout geperforeerde plaat, Embodied Energy: 7.4 (MJ/kg); Hout geperforeerde plaat, Embodied Carbon: 0.19 (kgCO₂/kg); Hout geperforeerde plaat, Name: Hout geperforeerde plaat; Hout geperforeerde plaat, Participates in Collision Detection: yes
Isolatie - Akkoestisch | Begane grond | Isolatie - Akkoestisch | 76.9264 | 2780 | 50 | 0.139 | 1.70947 | 1.70947 | Component Quantities - Projected Component Area (Net): 34.259 m2; Projected Component Area (Gross): 34.259 m2; Component Thickness: 50 mm; Material Properties - Isolatie - Akkoestisch, ThermalConductivity: 0.035; Isolatie - Akkoestisch, SpecificHeatCapacity: 840 J/kg/K; Isolatie - Akkoestisch, MassDensity: 45 kg/m3; Isolatie - Akkoestisch, Embodied Energy: 16.8 (MJ/kg); Isolatie - Akkoestisch, Embodied Carbon: 1.05 (kgCO₂/kg); Isolatie - Akkoestisch, Name: Isolatie - Akkoestisch; Isolatie - Akkoestisch, Participates in Collision Detection: yes
Hout geperforeerde plaat | Begane grond | Hout geperforeerde plaat | 1.49842 | 2780 | 20 | 0.0556 | 0.0027244 | 0.0027244 | Component Quantities - Projected Component Area (Net): 0.16402 m2; Projected Component Area (Gross): 0.16402 m2; Component Thickness: 20 mm; Material Properties - Hout geperforeerde plaat, ThermalConductivity: 0.14; Hout geperforeerde plaat, SpecificHeatCapacity: 1880 J/kg/K; Hout geperforeerde plaat, MassDensity: 550 kg/m3; Hout geperforeerde plaat, Embodied Energy: 7.4 (MJ/kg); Hout geperforeerde plaat, Embodied Carbon: 0.19 (kgCO₂/kg); Hout geperforeerde plaat, Name: Hout geperforeerde plaat; Hout geperforeerde plaat, Participates in Collision Detection: yes
Isolatie - Akkoestisch | Begane grond | Isolatie - Akkoestisch | 0.0951385 | 2780 | 50 | 0.139 | 0.00211419 | 0.00211419 | Component Quantities - Projected Component Area (Net): 0.10842 m2; Projected Component Area (Gross): 0.10842 m2; Component Thickness: 50 mm; Material Properties - Isolatie - Akkoestisch, ThermalConductivity: 0.035; Isolatie - Akkoestisch, SpecificHeatCapacity: 840 J/kg/K; Isolatie - Akkoestisch, MassDensity: 45 kg/m3; Isolatie - Akkoestisch, Embodied Energy: 16.8 (MJ/kg); Isolatie - Akkoestisch, Embodied Carbon: 1.05 (kgCO₂/kg); Isolatie - Akkoestisch, Name: Isolatie - Akkoestisch; Isolatie - Akkoestisch, Participates in Collision Detection: yes
3 x Hout geperforeerde plaat | Begane grond | Hout geperforeerde plaat | 8.16488 | 2780 | 20 | 0.0556 | 0.0148452 | 0.0148452 | Component Quantities - Projected Component Area (Net): 0.742262 m2; Projected Component Area (Gross): 0.742262 m2; Component Thickness: 20 mm; Material Properties - Hout geperforeerde plaat, ThermalConductivity: 0.14; Hout geperforeerde plaat, SpecificHeatCapacity: 1880 J/kg/K; Hout geperforeerde plaat, MassDensity: 550 kg/m3; Hout geperforeerde plaat, Embodied Energy: 7.4 (MJ/kg); Hout geperforeerde plaat, Embodied Carbon: 0.19 (kgCO₂/kg); Hout geperforeerde plaat, Name: Hout geperforeerde plaat; Hout geperforeerde plaat, Participates in Collision Detection: yes
3 x Isolatie - Akkoestisch | Begane grond | Isolatie - Akkoestisch | 1.35734 | 2780 | 50 | 0.139 | 0.0301631 | 0.0301631 | Component Quantities - Projected Component Area (Net): 0.603262 m2; Projected Component Area (Gross): 0.603262 m2; Component Thickness: 50 mm; Material Properties - Isolatie - Akkoestisch, ThermalConductivity: 0.035; Isolatie - Akkoestisch, SpecificHeatCapacity: 840 J/kg/K; Isolatie - Akkoestisch, MassDensity: 45 kg/m3; Isolatie - Akkoestisch, Embodied Energy: 16.8 (MJ/kg); Isolatie - Akkoestisch, Embodied Carbon: 1.05 (kgCO₂/kg); Isolatie - Akkoestisch, Name: Isolatie - Akkoestisch; Isolatie - Akkoestisch, Participates in Collision Detection: yes
Hout geperforeerde plaat | Begane grond | Hout geperforeerde plaat | 317.181 | 2780 | 20 | 0.0556 | 0.576694 | 0.608822 | Component Quantities - Projected Component Area (Net): 28.8347 m2; Projected Component Area (Gross): 30.4411 m2; Component Thickness: 20 mm; Material Properties - Hout geperforeerde plaat, ThermalConductivity: 0.14; Hout geperforeerde plaat, SpecificHeatCapacity: 1880 J/kg/K; Hout geperforeerde plaat, MassDensity: 550 kg/m3; Hout geperforeerde plaat, Embodied Energy: 7.4 (MJ/kg); Hout geperforeerde plaat, Embodied Carbon: 0.19 (kgCO₂/kg); Hout geperforeerde plaat, Name: Hout geperforeerde plaat; Hout geperforeerde plaat, Participates in Collision Detection: yes
Isolatie - Akkoestisch | Begane grond | Isolatie - Akkoestisch | 64.6278 | 2780 | 50 | 0.139 | 1.43617 | 1.51649 | Component Quantities - Projected Component Area (Net): 28.7235 m2; Projected Component Area (Gross): 30.3299 m2; Component Thickness: 50 mm; Material Properties - Isolatie - Akkoestisch, ThermalConductivity: 0.035; Isolatie - Akkoestisch, SpecificHeatCapacity: 840 J/kg/K; Isolatie - Akkoestisch, MassDensity: 45 kg/m3; Isolatie - Akkoestisch, Embodied Energy: 16.8 (MJ/kg); Isolatie - Akkoestisch, Embodied Carbon: 1.05 (kgCO₂/kg); Isolatie - Akkoestisch, Name: Isolatie - Akkoestisch; Isolatie - Akkoestisch, Participates in Collision Detection: yes
Isolatie - Akkoestisch | Begane grond | Isolatie - Akkoestisch | 1.67009 | 2780 | 50 | 0.139 | 0.0371131 | 0.0371131 | Component Quantities - Projected Component Area (Net): 0.742262 m2; Projected Component Area (Gross): 0.742262 m2; Component Thickness: 50 mm; Material Properties - Isolatie - Akkoestisch, ThermalConductivity: 0.035; Isolatie - Akkoestisch, SpecificHeatCapacity: 840 J/kg/K; Isolatie - Akkoestisch, MassDensity: 45 kg/m3; Isolatie - Akkoestisch, Embodied Energy: 16.8 (MJ/kg); Isolatie - Akkoestisch, Embodied Carbon: 1.05 (kgCO₂/kg); Isolatie - Akkoestisch, Name: Isolatie - Akkoestisch; Isolatie - Akkoestisch, Participates in Collision Detection: yes
Hout geperforeerde plaat | Begane grond | Hout geperforeerde plaat | 8.77648 | 2780 | 20 | 0.0556 | 0.0159572 | 0.0159572 | Component Quantities - Projected Component Area (Net): 0.797862 m2; Projected Component Area (Gross): 0.797862 m2; Component Thickness: 20 mm; Material Properties - Hout geperforeerde plaat, ThermalConductivity: 0.14; Hout geperforeerde plaat, SpecificHeatCapacity: 1880 J/kg/K; Hout geperforeerde plaat, MassDensity: 550 kg/m3; Hout geperforeerde plaat, Embodied Energy: 7.4 (MJ/kg); Hout geperforeerde plaat, Embodied Carbon: 0.19 (kgCO₂/kg); Hout geperforeerde plaat, Name: Hout geperforeerde plaat; Hout geperforeerde plaat, Participates in Collision Detection: yes
Hout geperforeerde plaat | Begane grond | Hout geperforeerde plaat | 87.6117 | 2780 | 20 | 0.0556 | 0.159294 | 0.159294 | Component Quantities - Projected Component Area (Net): 7.9647 m2; Projected Component Area (Gross): 7.9647 m2; Component Thickness: 20 mm; Material Properties - Hout geperforeerde plaat, ThermalConductivity: 0.14; Hout geperforeerde plaat, SpecificHeatCapacity: 1880 J/kg/K; Hout geperforeerde plaat, MassDensity: 550 kg/m3; Hout geperforeerde plaat, Embodied Energy: 7.4 (MJ/kg); Hout geperforeerde plaat, Embodied Carbon: 0.19 (kgCO₂/kg); Hout geperforeerde plaat, Name: Hout geperforeerde plaat; Hout geperforeerde plaat, Participates in Collision Detection: yes
Isolatie - Akkoestisch | Begane grond | Isolatie - Akkoestisch | 17.7329 | 2780 | 50 | 0.139 | 0.394065 | 0.394065 | Component Quantities - Projected Component Area (Net): 7.8813 m2; Projected Component Area (Gross): 7.8813 m2; Component Thickness: 50 mm; Material Properties - Isolatie - Akkoestisch, ThermalConductivity: 0.035; Isolatie - Akkoestisch, SpecificHeatCapacity: 840 J/kg/K; Isolatie - Akkoestisch, MassDensity: 45 kg/m3; Isolatie - Akkoestisch, Embodied Energy: 16.8 (MJ/kg); Isolatie - Akkoestisch, Embodied Carbon: 1.05 (kgCO₂/kg); Isolatie - Akkoestisch, Name: Isolatie - Akkoestisch; Isolatie - Akkoestisch, Participates in Collision Detection: yes
Isolatie - Akkoestisch | Begane grond | Isolatie - Akkoestisch | 1.31359 | 2780 | 50 | 0.139 | 0.0291909 | 0.0291909 | Component Quantities - Projected Component Area (Net): 0.583819 m2; Projected Component Area (Gross): 0.583819 m2; Component Thickness: 50 mm; Material Properties - Isolatie - Akkoestisch, ThermalConductivity: 0.035; Isolatie - Akkoestisch, SpecificHeatCapacity: 840 J/kg/K; Isolatie - Akkoestisch, MassDensity: 45 kg/m3; Isolatie - Akkoestisch, Embodied Energy: 16.8 (MJ/kg); Isolatie - Akkoestisch, Embodied Carbon: 1.05 (kgCO₂/kg); Isolatie - Akkoestisch, Name: Isolatie - Akkoestisch; Isolatie - Akkoestisch, Participates in Collision Detection: yes
Hout geperforeerde plaat | Begane grond | Hout geperforeerde plaat | 7.03361 | 2780 | 20 | 0.0556 | 0.0127884 | 0.0127884 | Component Quantities - Projected Component Area (Net): 0.639419 m2; Projected Component Area (Gross): 0.639419 m2; Component Thickness: 20 mm; Material Properties - Hout geperforeerde plaat, ThermalConductivity: 0.14; Hout geperforeerde plaat, SpecificHeatCapacity: 1880 J/kg/K; Hout geperforeerde plaat, MassDensity: 550 kg/m3; Hout geperforeerde plaat, Embodied Energy: 7.4 (MJ/kg); Hout geperforeerde plaat, Embodied Carbon: 0.19 (kgCO₂/kg); Hout geperforeerde plaat, Name: Hout geperforeerde plaat; Hout geperforeerde plaat, Participates in Collision Detection: yes
Isolatie - Akkoestisch | Begane grond | Isolatie - Akkoestisch | 22.3677 | 2780 | 50 | 0.139 | 0.497061 | 0.497061 | Component Quantities - Projected Component Area (Net): 9.94122 m2; Projected Component Area (Gross): 9.94122 m2; Component Thickness: 50 mm; Material Properties - Isolatie - Akkoestisch, ThermalConductivity: 0.035; Isolatie - Akkoestisch, SpecificHeatCapacity: 840 J/kg/K; Isolatie - Akkoestisch, MassDensity: 45 kg/m3; Isolatie - Akkoestisch, Embodied Energy: 16.8 (MJ/kg); Isolatie - Akkoestisch, Embodied Carbon: 1.05 (kgCO₂/kg); Isolatie - Akkoestisch, Name: Isolatie - Akkoestisch; Isolatie - Akkoestisch, Participates in Collision Detection: yes
Hout geperforeerde plaat | Begane grond | Hout geperforeerde plaat | 109.353 | 2780 | 20 | 0.0556 | 0.198824 | 0.198824 | Component Quantities - Projected Component Area (Net): 9.94122 m2; Projected Component Area (Gross): 9.94122 m2; Component Thickness: 20 mm; Material Properties - Hout geperforeerde plaat, ThermalConductivity: 0.14; Hout geperforeerde plaat, SpecificHeatCapacity: 1880 J/kg/K; Hout geperforeerde plaat, MassDensity: 550 kg/m3; Hout geperforeerde plaat, Embodied Energy: 7.4 (MJ/kg); Hout geperforeerde plaat, Embodied Carbon: 0.19 (kgCO₂/kg); Hout geperforeerde plaat, Name: Hout geperforeerde plaat; Hout geperforeerde plaat, Participates in Collision Detection: yes
Isolatie - Akkoestisch | Begane grond | Isolatie - Akkoestisch | 1.00084 | 2780 | 50 | 0.139 | 0.0222409 | 0.0222409 | Component Quantities - Projected Component Area (Net): 0.444819 m2; Projected Component Area (Gross): 0.444819 m2; Component Thickness: 50 mm; Material Properties - Isolatie - Akkoestisch, ThermalConductivity: 0.035; Isolatie - Akkoestisch, SpecificHeatCapacity: 840 J/kg/K; Isolatie - Akkoestisch, MassDensity: 45 kg/m3; Isolatie - Akkoestisch, Embodied Energy: 16.8 (MJ/kg); Isolatie - Akkoestisch, Embodied Carbon: 1.05 (kgCO₂/kg); Isolatie - Akkoestisch, Name: Isolatie - Akkoestisch; Isolatie - Akkoestisch, Participates in Collision Detection: yes
Hout geperforeerde plaat | Begane grond | Hout geperforeerde plaat | 6.42201 | 2780 | 20 | 0.0556 | 0.0116764 | 0.0116764 | Component Quantities - Projected Component Area (Net): 0.583819 m2; Projected Component Area (Gross): 0.583819 m2; Component Thickness: 20 mm; Material Properties - Hout geperforeerde plaat, ThermalConductivity: 0.14; Hout geperforeerde plaat, SpecificHeatCapacity: 1880 J/kg/K; Hout geperforeerde plaat, MassDensity: 550 kg/m3; Hout geperforeerde plaat, Embodied Energy: 7.4 (MJ/kg); Hout geperforeerde plaat, Embodied Carbon: 0.19 (kgCO₂/kg); Hout geperforeerde plaat, Name: Hout geperforeerde plaat; Hout geperforeerde plaat, Participates in Collision Detection: yes
Isolatie - Akkoestisch | Begane grond | Isolatie - Akkoestisch | 66.5219 | 2780 | 50 | 0.139 | 1.47827 | 1.47827 | Component Quantities - Projected Component Area (Net): 29.5653 m2; Projected Component Area (Gross): 29.5653 m2; Component Thickness: 50 mm; Material Properties - Isolatie - Akkoestisch, ThermalConductivity: 0.035; Isolatie - Akkoestisch, SpecificHeatCapacity: 840 J/kg/K; Isolatie - Akkoestisch, MassDensity: 45 kg/m3; Isolatie - Akkoestisch, Embodied Energy: 16.8 (MJ/kg); Isolatie - Akkoestisch, Embodied Carbon: 1.05 (kgCO₂/kg); Isolatie - Akkoestisch, Name: Isolatie - Akkoestisch; Isolatie - Akkoestisch, Participates in Collision Detection: yes
Hout geperforeerde plaat | Begane grond | Hout geperforeerde plaat | 325.218 | 2780 | 20 | 0.0556 | 0.591306 | 0.591306 | Component Quantities - Projected Component Area (Net): 29.5653 m2; Projected Component Area (Gross): 29.5653 m2; Component Thickness: 20 mm; Material Properties - Hout geperforeerde plaat, ThermalConductivity: 0.14; Hout geperforeerde plaat, SpecificHeatCapacity: 1880 J/kg/K; Hout geperforeerde plaat, MassDensity: 550 kg/m3; Hout geperforeerde plaat, Embodied Energy: 7.4 (MJ/kg); Hout geperforeerde plaat, Embodied Carbon: 0.19 (kgCO₂/kg); Hout geperforeerde plaat, Name: Hout geperforeerde plaat; Hout geperforeerde plaat, Participates in Collision Detection: yes
Isolatie - Akkoestisch | Begane grond | Isolatie - Akkoestisch | 1.03245 | 2800 | 50 | 0.14 | 0.0229432 | 0.0229432 | Component Quantities - Projected Component Area (Net): 0.458864 m2; Projected Component Area (Gross): 0.458864 m2; Component Thickness: 50 mm; Material Properties - Isolatie - Akkoestisch, ThermalConductivity: 0.035; Isolatie - Akkoestisch, SpecificHeatCapacity: 840 J/kg/K; Isolatie - Akkoestisch, MassDensity: 45 kg/m3; Isolatie - Akkoestisch, Embodied Energy: 16.8 (MJ/kg); Isolatie - Akkoestisch, Embodied Carbon: 1.05 (kgCO₂/kg); Isolatie - Akkoestisch, Name: Isolatie - Akkoestisch; Isolatie - Akkoestisch, Participates in Collision Detection: yes
Hout geperforeerde plaat | Begane grond | Hout geperforeerde plaat | 6.57651 | 2800 | 20 | 0.056 | 0.0119573 | 0.0119573 | Component Quantities - Projected Component Area (Net): 0.597864 m2; Projected Component Area (Gross): 0.597864 m2; Component Thickness: 20 mm; Material Properties - Hout geperforeerde plaat, ThermalConductivity: 0.14; Hout geperforeerde plaat, SpecificHeatCapacity: 1880 J/kg/K; Hout geperforeerde plaat, MassDensity: 550 kg/m3; Hout geperforeerde plaat, Embodied Energy: 7.4 (MJ/kg); Hout geperforeerde plaat, Embodied Carbon: 0.19 (kgCO₂/kg); Hout geperforeerde plaat, Name: Hout geperforeerde plaat; Hout geperforeerde plaat, Participates in Collision Detection: yes
Isolatie - Akkoestisch | Begane grond | Isolatie - Akkoestisch | 14.2163 | 1170 | 50 | 0.0585 | 0.315917 | 0.315917 | Component Quantities - Projected Component Area (Net): 6.31834 m2; Projected Component Area (Gross): 6.31834 m2; Component Thickness: 50 mm; Material Properties - Isolatie - Akkoestisch, ThermalConductivity: 0.035; Isolatie - Akkoestisch, SpecificHeatCapacity: 840 J/kg/K; Isolatie - Akkoestisch, MassDensity: 45 kg/m3; Isolatie - Akkoestisch, Embodied Energy: 16.8 (MJ/kg); Isolatie - Akkoestisch, Embodied Carbon: 1.05 (kgCO₂/kg); Isolatie - Akkoestisch, Name: Isolatie - Akkoestisch; Isolatie - Akkoestisch, Participates in Collision Detection: yes
Hout geperforeerde plaat | Begane grond | Hout geperforeerde plaat | 68.8769 | 1170 | 20 | 0.0234 | 0.125231 | 0.125231 | Component Quantities - Projected Component Area (Net): 6.26154 m2; Projected Component Area (Gross): 6.26154 m2; Component Thickness: 20 mm; Material Properties - Hout geperforeerde plaat, ThermalConductivity: 0.14; Hout geperforeerde plaat, SpecificHeatCapacity: 1880 J/kg/K; Hout geperforeerde plaat, MassDensity: 550 kg/m3; Hout geperforeerde plaat, Embodied Energy: 7.4 (MJ/kg); Hout geperforeerde plaat, Embodied Carbon: 0.19 (kgCO₂/kg); Hout geperforeerde plaat, Name: Hout geperforeerde plaat; Hout geperforeerde plaat, Participates in Collision Detection: yes
Isolatie - Akkoestisch | Begane grond | Isolatie - Akkoestisch | 31.1321 | 1170 | 50 | 0.0585 | 0.691824 | 0.691824 | Component Quantities - Projected Component Area (Net): 13.8365 m2; Projected Component Area (Gross): 13.8365 m2; Component Thickness: 50 mm; Material Properties - Isolatie - Akkoestisch, ThermalConductivity: 0.035; Isolatie - Akkoestisch, SpecificHeatCapacity: 840 J/kg/K; Isolatie - Akkoestisch, MassDensity: 45 kg/m3; Isolatie - Akkoestisch, Embodied Energy: 16.8 (MJ/kg); Isolatie - Akkoestisch, Embodied Carbon: 1.05 (kgCO₂/kg); Isolatie - Akkoestisch, Name: Isolatie - Akkoestisch; Isolatie - Akkoestisch, Participates in Collision Detection: yes
Hout geperforeerde plaat | Begane grond | Hout geperforeerde plaat | 152.46 | 1170 | 20 | 0.0234 | 0.2772 | 0.2772 | Component Quantities - Projected Component Area (Net): 14.1687 m2; Projected Component Area (Gross): 14.1687 m2; Component Thickness: 20 mm; Material Properties - Hout geperforeerde plaat, ThermalConductivity: 0.14; Hout geperforeerde plaat, SpecificHeatCapacity: 1880 J/kg/K; Hout geperforeerde plaat, MassDensity: 550 kg/m3; Hout geperforeerde plaat, Embodied Energy: 7.4 (MJ/kg); Hout geperforeerde plaat, Embodied Carbon: 0.19 (kgCO₂/kg); Hout geperforeerde plaat, Name: Hout geperforeerde plaat; Hout geperforeerde plaat, Participates in Collision Detection: yes
Hout geperforeerde plaat | Begane grond | Hout geperforeerde plaat | 171.212 | 1170 | 20 | 0.0234 | 0.311294 | 0.311294 | Component Quantities - Projected Component Area (Net): 15.5647 m2; Projected Component Area (Gross): 15.5647 m2; Component Thickness: 20 mm; Material Properties - Hout geperforeerde plaat, ThermalConductivity: 0.14; Hout geperforeerde plaat, SpecificHeatCapacity: 1880 J/kg/K; Hout geperforeerde plaat, MassDensity: 550 kg/m3; Hout geperforeerde plaat, Embodied Energy: 7.4 (MJ/kg); Hout geperforeerde plaat, Embodied Carbon: 0.19 (kgCO₂/kg); Hout geperforeerde plaat, Name: Hout geperforeerde plaat; Hout geperforeerde plaat, Participates in Collision Detection: yes
Isolatie - Akkoestisch | Begane grond | Isolatie - Akkoestisch | 35.0721 | 1170 | 50 | 0.0585 | 0.77938 | 0.77938 | Component Quantities - Projected Component Area (Net): 15.5876 m2; Projected Component Area (Gross): 15.5876 m2; Component Thickness: 50 mm; Material Properties - Isolatie - Akkoestisch, ThermalConductivity: 0.035; Isolatie - Akkoestisch, SpecificHeatCapacity: 840 J/kg/K; Isolatie - Akkoestisch, MassDensity: 45 kg/m3; Isolatie - Akkoestisch, Embodied Energy: 16.8 (MJ/kg); Isolatie - Akkoestisch, Embodied Carbon: 1.05 (kgCO₂/kg); Isolatie - Akkoestisch, Name: Isolatie - Akkoestisch; Isolatie - Akkoestisch, Participates in Collision Detection: yes
Gipsplaat | Begane grond | Gipsplaat | 5.50884 | 3470 | 12.5 | 0.043375 | 0.00688606 | 0.00688606 | Component Quantities - Projected Component Area (Net): 0.550884 m2; Projected Component Area (Gross): 0.550884 m2; Component Thickness: 12.5 mm; Material Properties - Gipsplaat, ThermalConductivity: 0.23; Gipsplaat, SpecificHeatCapacity: 840 J/kg/K; Gipsplaat, MassDensity: 800 kg/m3; Gipsplaat, Embodied Energy: 6.75 (MJ/kg); Gipsplaat, Embodied Carbon: 0.38 (kgCO₂/kg); Gipsplaat, Name: Gipsplaat; Gipsplaat, Participates in Collision Detection: yes
Gipsplaat | Begane grond | Gipsplaat | 5.08509 | 3470 | 12.5 | 0.043375 | 0.00635637 | 0.00635637 | Component Quantities - Projected Component Area (Net): 0.508509 m2; Projected Component Area (Gross): 0.508509 m2; Component Thickness: 12.5 mm; Material Properties - Gipsplaat, ThermalConductivity: 0.23; Gipsplaat, SpecificHeatCapacity: 840 J/kg/K; Gipsplaat, MassDensity: 800 kg/m3; Gipsplaat, Embodied Energy: 6.75 (MJ/kg); Gipsplaat, Embodied Carbon: 0.38 (kgCO₂/kg); Gipsplaat, Name: Gipsplaat; Gipsplaat, Participates in Collision Detection: yes
Gipsplaat | Begane grond | Gipsplaat | 98.31 | 3470 | 12.5 | 0.043375 | 0.122887 | 0.122887 | Component Quantities - Projected Component Area (Net): 9.831 m2; Projected Component Area (Gross): 9.831 m2; Component Thickness: 12.5 mm; Material Properties - Gipsplaat, ThermalConductivity: 0.23; Gipsplaat, SpecificHeatCapacity: 840 J/kg/K; Gipsplaat, MassDensity: 800 kg/m3; Gipsplaat, Embodied Energy: 6.75 (MJ/kg); Gipsplaat, Embodied Carbon: 0.38 (kgCO₂/kg); Gipsplaat, Name: Gipsplaat; Gipsplaat, Participates in Collision Detection: yes
Gipsplaat | Begane grond | Gipsplaat | 98.725 | 3470 | 12.5 | 0.043375 | 0.123406 | 0.123406 | Component Quantities - Projected Component Area (Net): 9.8725 m2; Projected Component Area (Gross): 9.8725 m2; Component Thickness: 12.5 mm; Material Properties - Gipsplaat, ThermalConductivity: 0.23; Gipsplaat, SpecificHeatCapacity: 840 J/kg/K; Gipsplaat, MassDensity: 800 kg/m3; Gipsplaat, Embodied Energy: 6.75 (MJ/kg); Gipsplaat, Embodied Carbon: 0.38 (kgCO₂/kg); Gipsplaat, Name: Gipsplaat; Gipsplaat, Participates in Collision Detection: yes
Isolatie - Steenwol LSW | Begane grond | Isolatie - Steenwol LSW | 27.2635 | 3470 | 50 | 0.1735 | 0.4957 | 0.4957 | Component Quantities - Projected Component Area (Net): 9.914 m2; Projected Component Area (Gross): 9.914 m2; Component Thickness: 50 mm; Material Properties - Isolatie - Steenwol LSW, ThermalConductivity: 0.039; Isolatie - Steenwol LSW, SpecificHeatCapacity: 840 J/kg/K; Isolatie - Steenwol LSW, MassDensity: 55 kg/m3; Isolatie - Steenwol LSW, Embodied Energy: 16.8 (MJ/kg); Isolatie - Steenwol LSW, Embodied Carbon: 1.05 (kgCO₂/kg); Isolatie - Steenwol LSW, Name: Isolatie - Steenwol LSW; Isolatie - Steenwol LSW, Participates in Collision Detection: yes
Gipsplaat | Begane grond | Gipsplaat | 97.03 | 3470 | 12.5 | 0.043375 | 0.121288 | 0.121288 | Component Quantities - Projected Component Area (Net): 9.703 m2; Projected Component Area (Gross): 9.703 m2; Component Thickness: 12.5 mm; Material Properties - Gipsplaat, ThermalConductivity: 0.23; Gipsplaat, SpecificHeatCapacity: 840 J/kg/K; Gipsplaat, MassDensity: 800 kg/m3; Gipsplaat, Embodied Energy: 6.75 (MJ/kg); Gipsplaat, Embodied Carbon: 0.38 (kgCO₂/kg); Gipsplaat, Name: Gipsplaat; Gipsplaat, Participates in Collision Detection: yes
Gipsplaat | Begane grond | Gipsplaat | 95.7675 | 3470 | 12.5 | 0.043375 | 0.119709 | 0.119709 | Component Quantities - Projected Component Area (Net): 9.57675 m2; Projected Component Area (Gross): 9.57675 m2; Component Thickness: 12.5 mm; Material Properties - Gipsplaat, ThermalConductivity: 0.23; Gipsplaat, SpecificHeatCapacity: 840 J/kg/K; Gipsplaat, MassDensity: 800 kg/m3; Gipsplaat, Embodied Energy: 6.75 (MJ/kg); Gipsplaat, Embodied Carbon: 0.38 (kgCO₂/kg); Gipsplaat, Name: Gipsplaat; Gipsplaat, Participates in Collision Detection: yes
Gipsplaat | Begane grond | Gipsplaat | 35.2355 | 3400 | 12.5 | 0.0425 | 0.0440444 | 0.136213 | Component Quantities - Projected Component Area (Net): 3.52355 m2; Projected Component Area (Gross): 10.897 m2; Component Thickness: 12.5 mm; Material Properties - Gipsplaat, ThermalConductivity: 0.23; Gipsplaat, SpecificHeatCapacity: 840 J/kg/K; Gipsplaat, MassDensity: 800 kg/m3; Gipsplaat, Embodied Energy: 6.75 (MJ/kg); Gipsplaat, Embodied Carbon: 0.38 (kgCO₂/kg); Gipsplaat, Name: Gipsplaat; Gipsplaat, Participates in Collision Detection: yes
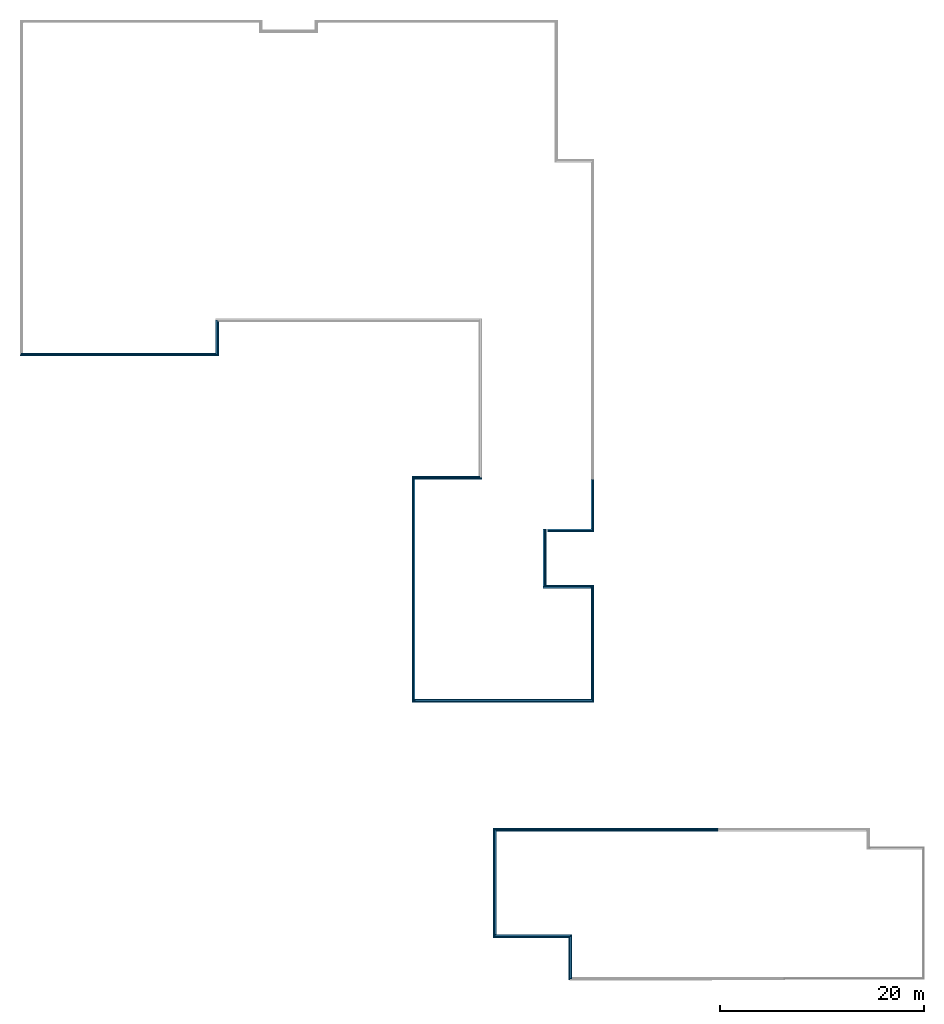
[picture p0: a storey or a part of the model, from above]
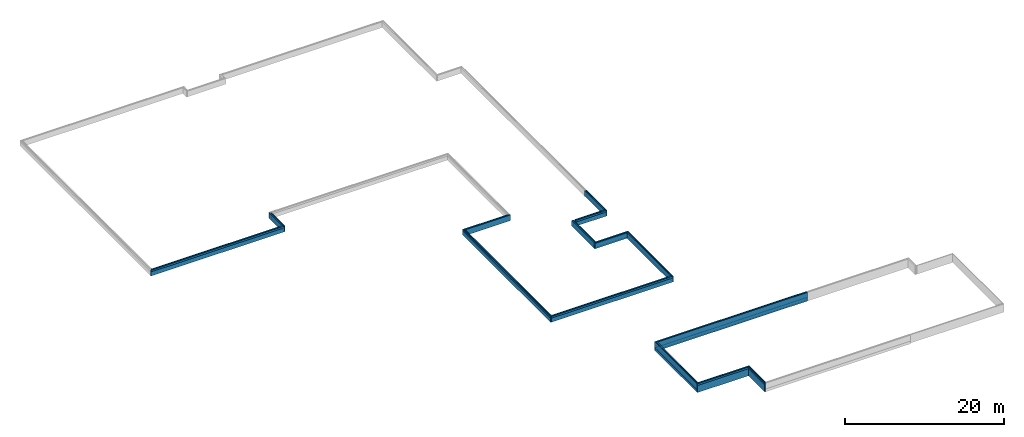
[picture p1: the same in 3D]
Properties of the parts of a building model (IFC2X3), part 9 of 19

# IfcBuildingElementPart (2070)
Name | In | Material | Mass (kg) | Rectangular Component Height (mm) | Rectangular Component Width (mm) | Component Cross Section Area (m2) | Component Volume (Net) (m3) | Component Volume (Gross) (m3)
Gipsplaat | Begane grond | Gipsplaat | 37.7855 | 3400 | 12.5 | 0.0425 | 0.0472319 | 0.1394 | Component Quantities - Projected Component Area (Net): 3.77855 m2; Projected Component Area (Gross): 11.152 m2; Component Thickness: 12.5 mm; Material Properties - Gipsplaat, ThermalConductivity: 0.23; Gipsplaat, SpecificHeatCapacity: 840 J/kg/K; Gipsplaat, MassDensity: 800 kg/m3; Gipsplaat, Embodied Energy: 6.75 (MJ/kg); Gipsplaat, Embodied Carbon: 0.38 (kgCO₂/kg); Gipsplaat, Name: Gipsplaat; Gipsplaat, Participates in Collision Detection: yes
Isolatie - Steenwol LSW | Begane grond | Isolatie - Steenwol LSW | 11.5598 | 3400 | 50 | 0.17 | 0.210178 | 0.57885 | Component Quantities - Projected Component Area (Net): 4.20355 m2; Projected Component Area (Gross): 11.577 m2; Component Thickness: 50 mm; Material Properties - Isolatie - Steenwol LSW, ThermalConductivity: 0.039; Isolatie - Steenwol LSW, SpecificHeatCapacity: 840 J/kg/K; Isolatie - Steenwol LSW, MassDensity: 55 kg/m3; Isolatie - Steenwol LSW, Embodied Energy: 16.8 (MJ/kg); Isolatie - Steenwol LSW, Embodied Carbon: 1.05 (kgCO₂/kg); Isolatie - Steenwol LSW, Name: Isolatie - Steenwol LSW; Isolatie - Steenwol LSW, Participates in Collision Detection: yes
Gipsplaat | Begane grond | Gipsplaat | 37.7958 | 3400 | 12.5 | 0.0425 | 0.0472448 | 0.139413 | Component Quantities - Projected Component Area (Net): 3.77959 m2; Projected Component Area (Gross): 11.153 m2; Component Thickness: 12.5 mm; Material Properties - Gipsplaat, ThermalConductivity: 0.23; Gipsplaat, SpecificHeatCapacity: 840 J/kg/K; Gipsplaat, MassDensity: 800 kg/m3; Gipsplaat, Embodied Energy: 6.75 (MJ/kg); Gipsplaat, Embodied Carbon: 0.38 (kgCO₂/kg); Gipsplaat, Name: Gipsplaat; Gipsplaat, Participates in Collision Detection: yes
Gipsplaat | Begane grond | Gipsplaat | 37.7959 | 3400 | 12.5 | 0.0425 | 0.0472448 | 0.139413 | Component Quantities - Projected Component Area (Net): 3.77959 m2; Projected Component Area (Gross): 11.153 m2; Component Thickness: 12.5 mm; Material Properties - Gipsplaat, ThermalConductivity: 0.23; Gipsplaat, SpecificHeatCapacity: 840 J/kg/K; Gipsplaat, MassDensity: 800 kg/m3; Gipsplaat, Embodied Energy: 6.75 (MJ/kg); Gipsplaat, Embodied Carbon: 0.38 (kgCO₂/kg); Gipsplaat, Name: Gipsplaat; Gipsplaat, Participates in Collision Detection: yes
Gipsplaat | Begane grond | Gipsplaat | 219.954 | 3400 | 12.5 | 0.0425 | 0.274942 | 0.359147 | Component Quantities - Projected Component Area (Net): 21.9954 m2; Projected Component Area (Gross): 28.7318 m2; Component Thickness: 12.5 mm; Material Properties - Gipsplaat, ThermalConductivity: 0.23; Gipsplaat, SpecificHeatCapacity: 840 J/kg/K; Gipsplaat, MassDensity: 800 kg/m3; Gipsplaat, Embodied Energy: 6.75 (MJ/kg); Gipsplaat, Embodied Carbon: 0.38 (kgCO₂/kg); Gipsplaat, Name: Gipsplaat; Gipsplaat, Participates in Collision Detection: yes
Gipsplaat | Begane grond | Gipsplaat | 221.654 | 3400 | 12.5 | 0.0425 | 0.277067 | 0.361272 | Component Quantities - Projected Component Area (Net): 22.1654 m2; Projected Component Area (Gross): 28.9018 m2; Component Thickness: 12.5 mm; Material Properties - Gipsplaat, ThermalConductivity: 0.23; Gipsplaat, SpecificHeatCapacity: 840 J/kg/K; Gipsplaat, MassDensity: 800 kg/m3; Gipsplaat, Embodied Energy: 6.75 (MJ/kg); Gipsplaat, Embodied Carbon: 0.38 (kgCO₂/kg); Gipsplaat, Name: Gipsplaat; Gipsplaat, Participates in Collision Detection: yes
Isolatie - Steenwol LSW | Begane grond | Isolatie - Steenwol LSW | 61.5879 | 3400 | 50 | 0.17 | 1.11978 | 1.4566 | Component Quantities - Projected Component Area (Net): 22.4244 m2; Projected Component Area (Gross): 29.1608 m2; Component Thickness: 50 mm; Material Properties - Isolatie - Steenwol LSW, ThermalConductivity: 0.039; Isolatie - Steenwol LSW, SpecificHeatCapacity: 840 J/kg/K; Isolatie - Steenwol LSW, MassDensity: 55 kg/m3; Isolatie - Steenwol LSW, Embodied Energy: 16.8 (MJ/kg); Isolatie - Steenwol LSW, Embodied Carbon: 1.05 (kgCO₂/kg); Isolatie - Steenwol LSW, Name: Isolatie - Steenwol LSW; Isolatie - Steenwol LSW, Participates in Collision Detection: yes
Gipsplaat | Begane grond | Gipsplaat | 227.604 | 3400 | 12.5 | 0.0425 | 0.284505 | 0.36871 | Component Quantities - Projected Component Area (Net): 22.7604 m2; Projected Component Area (Gross): 29.4968 m2; Component Thickness: 12.5 mm; Material Properties - Gipsplaat, ThermalConductivity: 0.23; Gipsplaat, SpecificHeatCapacity: 840 J/kg/K; Gipsplaat, MassDensity: 800 kg/m3; Gipsplaat, Embodied Energy: 6.75 (MJ/kg); Gipsplaat, Embodied Carbon: 0.38 (kgCO₂/kg); Gipsplaat, Name: Gipsplaat; Gipsplaat, Participates in Collision Detection: yes
Gipsplaat | Begane grond | Gipsplaat | 228.454 | 3400 | 12.5 | 0.0425 | 0.285567 | 0.369772 | Component Quantities - Projected Component Area (Net): 22.8454 m2; Projected Component Area (Gross): 29.5818 m2; Component Thickness: 12.5 mm; Material Properties - Gipsplaat, ThermalConductivity: 0.23; Gipsplaat, SpecificHeatCapacity: 840 J/kg/K; Gipsplaat, MassDensity: 800 kg/m3; Gipsplaat, Embodied Energy: 6.75 (MJ/kg); Gipsplaat, Embodied Carbon: 0.38 (kgCO₂/kg); Gipsplaat, Name: Gipsplaat; Gipsplaat, Participates in Collision Detection: yes
2 x Gipsplaat | Begane grond | Gipsplaat | 18.8529 | 3400 | 12.5 | 0.0425 | 0.0235662 | 0.0235662 | Component Quantities - Projected Component Area (Net): 1.88529 m2; Projected Component Area (Gross): 1.88529 m2; Component Thickness: 12.5 mm; Material Properties - Gipsplaat, ThermalConductivity: 0.23; Gipsplaat, SpecificHeatCapacity: 840 J/kg/K; Gipsplaat, MassDensity: 800 kg/m3; Gipsplaat, Embodied Energy: 6.75 (MJ/kg); Gipsplaat, Embodied Carbon: 0.38 (kgCO₂/kg); Gipsplaat, Name: Gipsplaat; Gipsplaat, Participates in Collision Detection: yes
Isolatie - Steenwol LSW | Begane grond | Isolatie - Steenwol LSW | 5.19606 | 3400 | 50 | 0.17 | 0.0944737 | 0.0944737 | Component Quantities - Projected Component Area (Net): 1.91729 m2; Projected Component Area (Gross): 1.91729 m2; Component Thickness: 50 mm; Material Properties - Isolatie - Steenwol LSW, ThermalConductivity: 0.039; Isolatie - Steenwol LSW, SpecificHeatCapacity: 840 J/kg/K; Isolatie - Steenwol LSW, MassDensity: 55 kg/m3; Isolatie - Steenwol LSW, Embodied Energy: 16.8 (MJ/kg); Isolatie - Steenwol LSW, Embodied Carbon: 1.05 (kgCO₂/kg); Isolatie - Steenwol LSW, Name: Isolatie - Steenwol LSW; Isolatie - Steenwol LSW, Participates in Collision Detection: yes
2 x Gipsplaat | Begane grond | Gipsplaat | 19.1729 | 3400 | 12.5 | 0.0425 | 0.0239662 | 0.0239662 | Component Quantities - Projected Component Area (Net): 1.91729 m2; Projected Component Area (Gross): 1.91729 m2; Component Thickness: 12.5 mm; Material Properties - Gipsplaat, ThermalConductivity: 0.23; Gipsplaat, SpecificHeatCapacity: 840 J/kg/K; Gipsplaat, MassDensity: 800 kg/m3; Gipsplaat, Embodied Energy: 6.75 (MJ/kg); Gipsplaat, Embodied Carbon: 0.38 (kgCO₂/kg); Gipsplaat, Name: Gipsplaat; Gipsplaat, Participates in Collision Detection: yes
Gipsplaat | Begane grond | Gipsplaat | 0.884 | 3400 | 12.5 | 0.0425 | 0.001105 | 0.001105 | Component Quantities - Projected Component Area (Net): 0.0884 m2; Projected Component Area (Gross): 0.0884 m2; Component Thickness: 12.5 mm; Material Properties - Gipsplaat, ThermalConductivity: 0.23; Gipsplaat, SpecificHeatCapacity: 840 J/kg/K; Gipsplaat, MassDensity: 800 kg/m3; Gipsplaat, Embodied Energy: 6.75 (MJ/kg); Gipsplaat, Embodied Carbon: 0.38 (kgCO₂/kg); Gipsplaat, Name: Gipsplaat; Gipsplaat, Participates in Collision Detection: yes
2 x Gipsplaat | Begane grond | Gipsplaat | 0.459 | 3400 | 12.5 | 0.0425 | 0.00057375 | 0.00057375 | Component Quantities - Projected Component Area (Net): 0.0459 m2; Projected Component Area (Gross): 0.0459 m2; Component Thickness: 12.5 mm; Material Properties - Gipsplaat, ThermalConductivity: 0.23; Gipsplaat, SpecificHeatCapacity: 840 J/kg/K; Gipsplaat, MassDensity: 800 kg/m3; Gipsplaat, Embodied Energy: 6.75 (MJ/kg); Gipsplaat, Embodied Carbon: 0.38 (kgCO₂/kg); Gipsplaat, Name: Gipsplaat; Gipsplaat, Participates in Collision Detection: yes
Gipsplaat | Begane grond | Gipsplaat | 6.375 | 3400 | 12.5 | 0.0425 | 0.00796875 | 0.00796875 | Component Quantities - Projected Component Area (Net): 0.6375 m2; Projected Component Area (Gross): 0.6375 m2; Component Thickness: 12.5 mm; Material Properties - Gipsplaat, ThermalConductivity: 0.23; Gipsplaat, SpecificHeatCapacity: 840 J/kg/K; Gipsplaat, MassDensity: 800 kg/m3; Gipsplaat, Embodied Energy: 6.75 (MJ/kg); Gipsplaat, Embodied Carbon: 0.38 (kgCO₂/kg); Gipsplaat, Name: Gipsplaat; Gipsplaat, Participates in Collision Detection: yes
Gipsplaat | Begane grond | Gipsplaat | 5.525 | 3400 | 12.5 | 0.0425 | 0.00690625 | 0.00690625 | Component Quantities - Projected Component Area (Net): 0.5525 m2; Projected Component Area (Gross): 0.5525 m2; Component Thickness: 12.5 mm; Material Properties - Gipsplaat, ThermalConductivity: 0.23; Gipsplaat, SpecificHeatCapacity: 840 J/kg/K; Gipsplaat, MassDensity: 800 kg/m3; Gipsplaat, Embodied Energy: 6.75 (MJ/kg); Gipsplaat, Embodied Carbon: 0.38 (kgCO₂/kg); Gipsplaat, Name: Gipsplaat; Gipsplaat, Participates in Collision Detection: yes
Gipsplaat | Begane grond | Gipsplaat | 0.034 | 3400 | 12.5 | 0.0425 | 0.0000425 | 0.0000425 | Component Quantities - Projected Component Area (Net): 0.0034 m2; Projected Component Area (Gross): 0.0034 m2; Component Thickness: 12.5 mm; Material Properties - Gipsplaat, ThermalConductivity: 0.23; Gipsplaat, SpecificHeatCapacity: 840 J/kg/K; Gipsplaat, MassDensity: 800 kg/m3; Gipsplaat, Embodied Energy: 6.75 (MJ/kg); Gipsplaat, Embodied Carbon: 0.38 (kgCO₂/kg); Gipsplaat, Name: Gipsplaat; Gipsplaat, Participates in Collision Detection: yes
Gipsplaat | Begane grond | Gipsplaat | 86.5171 | 3470 | 12.5 | 0.043375 | 0.108146 | 0.179788 | Component Quantities - Projected Component Area (Net): 8.65171 m2; Projected Component Area (Gross): 14.383 m2; Component Thickness: 12.5 mm; Material Properties - Gipsplaat, ThermalConductivity: 0.23; Gipsplaat, SpecificHeatCapacity: 840 J/kg/K; Gipsplaat, MassDensity: 800 kg/m3; Gipsplaat, Embodied Energy: 6.75 (MJ/kg); Gipsplaat, Embodied Carbon: 0.38 (kgCO₂/kg); Gipsplaat, Name: Gipsplaat; Gipsplaat, Participates in Collision Detection: yes
Gipsplaat | Begane grond | Gipsplaat | 88.8398 | 3470 | 12.5 | 0.043375 | 0.11105 | 0.182691 | Component Quantities - Projected Component Area (Net): 8.90732 m2; Projected Component Area (Gross): 14.6386 m2; Component Thickness: 12.5 mm; Material Properties - Gipsplaat, ThermalConductivity: 0.23; Gipsplaat, SpecificHeatCapacity: 840 J/kg/K; Gipsplaat, MassDensity: 800 kg/m3; Gipsplaat, Embodied Energy: 6.75 (MJ/kg); Gipsplaat, Embodied Carbon: 0.38 (kgCO₂/kg); Gipsplaat, Name: Gipsplaat; Gipsplaat, Participates in Collision Detection: yes
Isolatie - Steenwol LSW | Begane grond | Isolatie - Steenwol LSW | 25.9392 | 3470 | 50 | 0.1735 | 0.471622 | 0.758186 | Component Quantities - Projected Component Area (Net): 9.43246 m2; Projected Component Area (Gross): 15.1638 m2; Component Thickness: 50 mm; Material Properties - Isolatie - Steenwol LSW, ThermalConductivity: 0.039; Isolatie - Steenwol LSW, SpecificHeatCapacity: 840 J/kg/K; Isolatie - Steenwol LSW, MassDensity: 55 kg/m3; Isolatie - Steenwol LSW, Embodied Energy: 16.8 (MJ/kg); Isolatie - Steenwol LSW, Embodied Carbon: 1.05 (kgCO₂/kg); Isolatie - Steenwol LSW, Name: Isolatie - Steenwol LSW; Isolatie - Steenwol LSW, Participates in Collision Detection: yes
2 x Gipsplaat | Begane grond | Gipsplaat | 94.3246 | 3470 | 12.5 | 0.043375 | 0.117906 | 0.189547 | Component Quantities - Projected Component Area (Net): 9.43246 m2; Projected Component Area (Gross): 15.1638 m2; Component Thickness: 12.5 mm; Material Properties - Gipsplaat, ThermalConductivity: 0.23; Gipsplaat, SpecificHeatCapacity: 840 J/kg/K; Gipsplaat, MassDensity: 800 kg/m3; Gipsplaat, Embodied Energy: 6.75 (MJ/kg); Gipsplaat, Embodied Carbon: 0.38 (kgCO₂/kg); Gipsplaat, Name: Gipsplaat; Gipsplaat, Participates in Collision Detection: yes
Cement | Begane grond | Cement | 2801.74 |  |  |  | 1.4746 | 1.4746 | Component Quantities - Projected Component Area (Net): 21.0657 m2; Projected Component Area (Gross): 21.0657 m2; Component Thickness: 70 mm; Material Properties - Cement, ThermalConductivity: 0.93; Cement, SpecificHeatCapacity: 840 J/kg/K; Cement, MassDensity: 1900 kg/m3; Cement, Embodied Energy: 0.97 (MJ/kg); Cement, Embodied Carbon: 0.146 (kgCO₂/kg); Cement, Name: Cement; Cement, Participates in Collision Detection: yes
Beton gewapend C vloer | Begane grond | Beton gewapend C vloer | 10783.3 |  |  |  | 4.49302 | 4.49302 | Component Quantities - Projected Component Area (Net): 22.4651 m2; Projected Component Area (Gross): 22.4651 m2; Component Thickness: 200 mm; Material Properties - Beton gewapend C vloer, ThermalConductivity: 2.5; Beton gewapend C vloer, SpecificHeatCapacity: 1000 J/kg/K; Beton gewapend C vloer, MassDensity: 2400 kg/m3; Beton gewapend C vloer, Embodied Energy: 2.33 (MJ/kg); Beton gewapend C vloer, Embodied Carbon: 0.242 (kgCO₂/kg); Beton gewapend C vloer, Name: Beton gewapend C vloer; Beton gewapend C vloer, Participates in Collision Detection: yes
ALG - ISOLATIE | Begane grond | ALG - ISOLATIE | 161.749 |  |  |  | 3.59442 | 3.59442 | Component Quantities - Projected Component Area (Net): 22.4651 m2; Projected Component Area (Gross): 22.4651 m2; Component Thickness: 160 mm; Material Properties - ALG - ISOLATIE, ThermalConductivity: 0.035; ALG - ISOLATIE, SpecificHeatCapacity: 840 J/kg/K; ALG - ISOLATIE, MassDensity: 45 kg/m3; ALG - ISOLATIE, Embodied Energy: 16.8 (MJ/kg); ALG - ISOLATIE, Embodied Carbon: 1.05 (kgCO₂/kg); ALG - ISOLATIE, Name: ALG - ISOLATIE; ALG - ISOLATIE, Participates in Collision Detection: yes
Grondverbetering | Begane grond | Grondverbetering | 10310.5 |  |  |  | 5.72808 | 5.72808 | Component Quantities - Projected Component Area (Net): 19.0936 m2; Projected Component Area (Gross): 19.0936 m2; Component Thickness: 300 mm; Material Properties - Grondverbetering, ThermalConductivity: 1.4; Grondverbetering, SpecificHeatCapacity: 1000 J/kg/K; Grondverbetering, MassDensity: 1800 kg/m3; Grondverbetering, Embodied Energy: 0.083 (MJ/kg); Grondverbetering, Embodied Carbon: 0.0048 (kgCO₂/kg); Grondverbetering, Name: Grondverbetering; Grondverbetering, Participates in Collision Detection: yes
Isolatie - Steenwol LSW | Begane grond | Isolatie - Steenwol LSW | 9.13001 | 3400 | 50 | 0.17 | 0.166 | 0.166 | Component Quantities - Projected Component Area (Net): 3.38 m2; Projected Component Area (Gross): 3.38 m2; Component Thickness: 50 mm; Material Properties - Isolatie - Steenwol LSW, ThermalConductivity: 0.039; Isolatie - Steenwol LSW, SpecificHeatCapacity: 840 J/kg/K; Isolatie - Steenwol LSW, MassDensity: 55 kg/m3; Isolatie - Steenwol LSW, Embodied Energy: 16.8 (MJ/kg); Isolatie - Steenwol LSW, Embodied Carbon: 1.05 (kgCO₂/kg); Isolatie - Steenwol LSW, Name: Isolatie - Steenwol LSW; Isolatie - Steenwol LSW, Participates in Collision Detection: yes
2 x Gipsplaat | Begane grond | Gipsplaat | 33.2 | 3400 | 12.5 | 0.0425 | 0.0415 | 0.0415 | Component Quantities - Projected Component Area (Net): 3.32 m2; Projected Component Area (Gross): 3.32 m2; Component Thickness: 12.5 mm; Material Properties - Gipsplaat, ThermalConductivity: 0.23; Gipsplaat, SpecificHeatCapacity: 840 J/kg/K; Gipsplaat, MassDensity: 800 kg/m3; Gipsplaat, Embodied Energy: 6.75 (MJ/kg); Gipsplaat, Embodied Carbon: 0.38 (kgCO₂/kg); Gipsplaat, Name: Gipsplaat; Gipsplaat, Participates in Collision Detection: yes
Isolatie - Steenwol LSW | Begane grond | Isolatie - Steenwol LSW | 1.76602 | 3400 | 50 | 0.17 | 0.0321095 | 0.0321095 | Component Quantities - Projected Component Area (Net): 0.64219 m2; Projected Component Area (Gross): 0.64219 m2; Component Thickness: 50 mm; Material Properties - Isolatie - Steenwol LSW, ThermalConductivity: 0.039; Isolatie - Steenwol LSW, SpecificHeatCapacity: 840 J/kg/K; Isolatie - Steenwol LSW, MassDensity: 55 kg/m3; Isolatie - Steenwol LSW, Embodied Energy: 16.8 (MJ/kg); Isolatie - Steenwol LSW, Embodied Carbon: 1.05 (kgCO₂/kg); Isolatie - Steenwol LSW, Name: Isolatie - Steenwol LSW; Isolatie - Steenwol LSW, Participates in Collision Detection: yes
Gipsplaat | Begane grond | Gipsplaat | 8.0819 | 3400 | 12.5 | 0.0425 | 0.0101024 | 0.0101024 | Component Quantities - Projected Component Area (Net): 0.80819 m2; Projected Component Area (Gross): 0.80819 m2; Component Thickness: 12.5 mm; Material Properties - Gipsplaat, ThermalConductivity: 0.23; Gipsplaat, SpecificHeatCapacity: 840 J/kg/K; Gipsplaat, MassDensity: 800 kg/m3; Gipsplaat, Embodied Energy: 6.75 (MJ/kg); Gipsplaat, Embodied Carbon: 0.38 (kgCO₂/kg); Gipsplaat, Name: Gipsplaat; Gipsplaat, Participates in Collision Detection: yes
Gipsplaat | Begane grond | Gipsplaat | 8.4969 | 3400 | 12.5 | 0.0425 | 0.0106211 | 0.0106211 | Component Quantities - Projected Component Area (Net): 0.84969 m2; Projected Component Area (Gross): 0.84969 m2; Component Thickness: 12.5 mm; Material Properties - Gipsplaat, ThermalConductivity: 0.23; Gipsplaat, SpecificHeatCapacity: 840 J/kg/K; Gipsplaat, MassDensity: 800 kg/m3; Gipsplaat, Embodied Energy: 6.75 (MJ/kg); Gipsplaat, Embodied Carbon: 0.38 (kgCO₂/kg); Gipsplaat, Name: Gipsplaat; Gipsplaat, Participates in Collision Detection: yes
Isolatie - Steenwol LSW | Begane grond | Isolatie - Steenwol LSW | 9.21113 | 3190 | 50 | 0.1595 | 0.167475 | 0.167475 | Component Quantities - Projected Component Area (Net): 3.3495 m2; Projected Component Area (Gross): 3.3495 m2; Component Thickness: 50 mm; Material Properties - Isolatie - Steenwol LSW, ThermalConductivity: 0.039; Isolatie - Steenwol LSW, SpecificHeatCapacity: 840 J/kg/K; Isolatie - Steenwol LSW, MassDensity: 55 kg/m3; Isolatie - Steenwol LSW, Embodied Energy: 16.8 (MJ/kg); Isolatie - Steenwol LSW, Embodied Carbon: 1.05 (kgCO₂/kg); Isolatie - Steenwol LSW, Name: Isolatie - Steenwol LSW; Isolatie - Steenwol LSW, Participates in Collision Detection: yes
2 x Gipsplaat | Begane grond | Gipsplaat | 33.495 | 3190 | 12.5 | 0.039875 | 0.0418688 | 0.0418688 | Component Quantities - Projected Component Area (Net): 3.3495 m2; Projected Component Area (Gross): 3.3495 m2; Component Thickness: 12.5 mm; Material Properties - Gipsplaat, ThermalConductivity: 0.23; Gipsplaat, SpecificHeatCapacity: 840 J/kg/K; Gipsplaat, MassDensity: 800 kg/m3; Gipsplaat, Embodied Energy: 6.75 (MJ/kg); Gipsplaat, Embodied Carbon: 0.38 (kgCO₂/kg); Gipsplaat, Name: Gipsplaat; Gipsplaat, Participates in Collision Detection: yes
Gipsplaat | Begane grond | Gipsplaat | 74.8665 | 3470 | 12.5 | 0.043375 | 0.0935831 | 0.0935831 | Component Quantities - Projected Component Area (Net): 7.48665 m2; Projected Component Area (Gross): 7.48665 m2; Component Thickness: 12.5 mm; Material Properties - Gipsplaat, ThermalConductivity: 0.23; Gipsplaat, SpecificHeatCapacity: 840 J/kg/K; Gipsplaat, MassDensity: 800 kg/m3; Gipsplaat, Embodied Energy: 6.75 (MJ/kg); Gipsplaat, Embodied Carbon: 0.38 (kgCO₂/kg); Gipsplaat, Name: Gipsplaat; Gipsplaat, Participates in Collision Detection: yes
Gipsplaat | Begane grond | Gipsplaat | 74.0365 | 3470 | 12.5 | 0.043375 | 0.0925456 | 0.0925456 | Component Quantities - Projected Component Area (Net): 7.40365 m2; Projected Component Area (Gross): 7.40365 m2; Component Thickness: 12.5 mm; Material Properties - Gipsplaat, ThermalConductivity: 0.23; Gipsplaat, SpecificHeatCapacity: 840 J/kg/K; Gipsplaat, MassDensity: 800 kg/m3; Gipsplaat, Embodied Energy: 6.75 (MJ/kg); Gipsplaat, Embodied Carbon: 0.38 (kgCO₂/kg); Gipsplaat, Name: Gipsplaat; Gipsplaat, Participates in Collision Detection: yes
Isolatie - Steenwol LSW | Begane grond | Isolatie - Steenwol LSW | 19.447 | 3470 | 50 | 0.1735 | 0.353582 | 0.353582 | Component Quantities - Projected Component Area (Net): 7.07165 m2; Projected Component Area (Gross): 7.07165 m2; Component Thickness: 50 mm; Material Properties - Isolatie - Steenwol LSW, ThermalConductivity: 0.039; Isolatie - Steenwol LSW, SpecificHeatCapacity: 840 J/kg/K; Isolatie - Steenwol LSW, MassDensity: 55 kg/m3; Isolatie - Steenwol LSW, Embodied Energy: 16.8 (MJ/kg); Isolatie - Steenwol LSW, Embodied Carbon: 1.05 (kgCO₂/kg); Isolatie - Steenwol LSW, Name: Isolatie - Steenwol LSW; Isolatie - Steenwol LSW, Participates in Collision Detection: yes
Gipsplaat | Begane grond | Gipsplaat | 69.8865 | 3470 | 12.5 | 0.043375 | 0.0873581 | 0.0873581 | Component Quantities - Projected Component Area (Net): 6.98865 m2; Projected Component Area (Gross): 6.98865 m2; Component Thickness: 12.5 mm; Material Properties - Gipsplaat, ThermalConductivity: 0.23; Gipsplaat, SpecificHeatCapacity: 840 J/kg/K; Gipsplaat, MassDensity: 800 kg/m3; Gipsplaat, Embodied Energy: 6.75 (MJ/kg); Gipsplaat, Embodied Carbon: 0.38 (kgCO₂/kg); Gipsplaat, Name: Gipsplaat; Gipsplaat, Participates in Collision Detection: yes
Gipsplaat | Begane grond | Gipsplaat | 69.0565 | 3470 | 12.5 | 0.043375 | 0.0863206 | 0.0863206 | Component Quantities - Projected Component Area (Net): 6.90565 m2; Projected Component Area (Gross): 6.90565 m2; Component Thickness: 12.5 mm; Material Properties - Gipsplaat, ThermalConductivity: 0.23; Gipsplaat, SpecificHeatCapacity: 840 J/kg/K; Gipsplaat, MassDensity: 800 kg/m3; Gipsplaat, Embodied Energy: 6.75 (MJ/kg); Gipsplaat, Embodied Carbon: 0.38 (kgCO₂/kg); Gipsplaat, Name: Gipsplaat; Gipsplaat, Participates in Collision Detection: yes
Steen - Betonblok C | Begane grond | Steen - Betonblok C | 3011.48 | 4235 | 150 | 0.63525 | 1.88218 | 2.91262 | Component Quantities - Projected Component Area (Net): 12.5478 m2; Projected Component Area (Gross): 19.4175 m2; Component Thickness: 150 mm; Material Properties - Steen - Betonblok C, ThermalConductivity: 0.75; Steen - Betonblok C, SpecificHeatCapacity: 840 J/kg/K; Steen - Betonblok C, MassDensity: 1600 kg/m3; Steen - Betonblok C, Embodied Energy: 0.83 (MJ/kg); Steen - Betonblok C, Embodied Carbon: 0.1 (kgCO₂/kg); Steen - Betonblok C, Name: Steen - Betonblok C; Steen - Betonblok C, Participates in Collision Detection: yes
ALG - ISOLATIE | Begane grond | ALG - ISOLATIE | 98.8962 | 4235 | 150 | 0.63525 | 2.19769 | 3.00791 | Component Quantities - Projected Component Area (Net): 14.7707 m2; Projected Component Area (Gross): 20.0527 m2; Component Thickness: 150 mm; Material Properties - ALG - ISOLATIE, ThermalConductivity: 0.035; ALG - ISOLATIE, SpecificHeatCapacity: 840 J/kg/K; ALG - ISOLATIE, MassDensity: 45 kg/m3; ALG - ISOLATIE, Embodied Energy: 16.8 (MJ/kg); ALG - ISOLATIE, Embodied Carbon: 1.05 (kgCO₂/kg); ALG - ISOLATIE, Name: ALG - ISOLATIE; ALG - ISOLATIE, Participates in Collision Detection: yes
Steen - Baksteen AFW | Begane grond | Steen - Baksteen AFW | 2345.66 | 4235 | 100 | 0.4235 | 1.46604 | 2.01516 | Component Quantities - Projected Component Area (Net): 14.6604 m2; Projected Component Area (Gross): 20.1516 m2; Component Thickness: 100 mm; Material Properties - Steen - Baksteen AFW, ThermalConductivity: 0.9; Steen - Baksteen AFW, SpecificHeatCapacity: 840 J/kg/K; Steen - Baksteen AFW, MassDensity: 1600 kg/m3; Steen - Baksteen AFW, Embodied Energy: 3 (MJ/kg); Steen - Baksteen AFW, Embodied Carbon: 0.23 (kgCO₂/kg); Steen - Baksteen AFW, Name: Steen - Baksteen AFW; Steen - Baksteen AFW, Participates in Collision Detection: yes
Gipsplaat | Begane grond | Gipsplaat | 186.727 | 3470 | 12.5 | 0.043375 | 0.233409 | 0.312139 | Component Quantities - Projected Component Area (Net): 18.6841 m2; Projected Component Area (Gross): 24.9826 m2; Component Thickness: 12.5 mm; Material Properties - Gipsplaat, ThermalConductivity: 0.23; Gipsplaat, SpecificHeatCapacity: 840 J/kg/K; Gipsplaat, MassDensity: 800 kg/m3; Gipsplaat, Embodied Energy: 6.75 (MJ/kg); Gipsplaat, Embodied Carbon: 0.38 (kgCO₂/kg); Gipsplaat, Name: Gipsplaat; Gipsplaat, Participates in Collision Detection: yes
Gipsplaat | Begane grond | Gipsplaat | 187.348 | 3470 | 12.5 | 0.043375 | 0.234186 | 0.312917 | Component Quantities - Projected Component Area (Net): 18.7787 m2; Projected Component Area (Gross): 25.0772 m2; Component Thickness: 12.5 mm; Material Properties - Gipsplaat, ThermalConductivity: 0.23; Gipsplaat, SpecificHeatCapacity: 840 J/kg/K; Gipsplaat, MassDensity: 800 kg/m3; Gipsplaat, Embodied Energy: 6.75 (MJ/kg); Gipsplaat, Embodied Carbon: 0.38 (kgCO₂/kg); Gipsplaat, Name: Gipsplaat; Gipsplaat, Participates in Collision Detection: yes
Isolatie - Steenwol LSW | Begane grond | Isolatie - Steenwol LSW | 103.516 | 3470 | 100 | 0.347 | 1.88211 | 2.51196 | Component Quantities - Projected Component Area (Net): 18.8211 m2; Projected Component Area (Gross): 25.1196 m2; Component Thickness: 100 mm; Material Properties - Isolatie - Steenwol LSW, ThermalConductivity: 0.039; Isolatie - Steenwol LSW, SpecificHeatCapacity: 840 J/kg/K; Isolatie - Steenwol LSW, MassDensity: 55 kg/m3; Isolatie - Steenwol LSW, Embodied Energy: 16.8 (MJ/kg); Isolatie - Steenwol LSW, Embodied Carbon: 1.05 (kgCO₂/kg); Isolatie - Steenwol LSW, Name: Isolatie - Steenwol LSW; Isolatie - Steenwol LSW, Participates in Collision Detection: yes
Isolatie - Steenwol LSW | Begane grond | Isolatie - Steenwol LSW | 104.897 | 3470 | 100 | 0.347 | 1.90722 | 2.53707 | Component Quantities - Projected Component Area (Net): 19.177 m2; Projected Component Area (Gross): 25.4755 m2; Component Thickness: 100 mm; Material Properties - Isolatie - Steenwol LSW, ThermalConductivity: 0.039; Isolatie - Steenwol LSW, SpecificHeatCapacity: 840 J/kg/K; Isolatie - Steenwol LSW, MassDensity: 55 kg/m3; Isolatie - Steenwol LSW, Embodied Energy: 16.8 (MJ/kg); Isolatie - Steenwol LSW, Embodied Carbon: 1.05 (kgCO₂/kg); Isolatie - Steenwol LSW, Name: Isolatie - Steenwol LSW; Isolatie - Steenwol LSW, Participates in Collision Detection: yes
Gipsplaat | Begane grond | Gipsplaat | 193.24 | 3470 | 12.5 | 0.043375 | 0.24155 | 0.320281 | Component Quantities - Projected Component Area (Net): 19.324 m2; Projected Component Area (Gross): 25.6225 m2; Component Thickness: 12.5 mm; Material Properties - Gipsplaat, ThermalConductivity: 0.23; Gipsplaat, SpecificHeatCapacity: 840 J/kg/K; Gipsplaat, MassDensity: 800 kg/m3; Gipsplaat, Embodied Energy: 6.75 (MJ/kg); Gipsplaat, Embodied Carbon: 0.38 (kgCO₂/kg); Gipsplaat, Name: Gipsplaat; Gipsplaat, Participates in Collision Detection: yes
Gipsplaat | Begane grond | Gipsplaat | 193.664 | 3470 | 12.5 | 0.043375 | 0.24208 | 0.320811 | Component Quantities - Projected Component Area (Net): 19.3664 m2; Projected Component Area (Gross): 25.6649 m2; Component Thickness: 12.5 mm; Material Properties - Gipsplaat, ThermalConductivity: 0.23; Gipsplaat, SpecificHeatCapacity: 840 J/kg/K; Gipsplaat, MassDensity: 800 kg/m3; Gipsplaat, Embodied Energy: 6.75 (MJ/kg); Gipsplaat, Embodied Carbon: 0.38 (kgCO₂/kg); Gipsplaat, Name: Gipsplaat; Gipsplaat, Participates in Collision Detection: yes
2 x Gipsplaat | Begane grond | Gipsplaat | 12.1814 | 3080 | 12.5 | 0.0385 | 0.0152268 | 0.0152268 | Component Quantities - Projected Component Area (Net): 1.21814 m2; Projected Component Area (Gross): 1.21814 m2; Component Thickness: 12.5 mm; Material Properties - Gipsplaat, ThermalConductivity: 0.23; Gipsplaat, SpecificHeatCapacity: 840 J/kg/K; Gipsplaat, MassDensity: 800 kg/m3; Gipsplaat, Embodied Energy: 6.75 (MJ/kg); Gipsplaat, Embodied Carbon: 0.38 (kgCO₂/kg); Gipsplaat, Name: Gipsplaat; Gipsplaat, Participates in Collision Detection: yes
Lucht frame_wit | Begane grond | Lucht frame_wit | 0.112556 | 3080 | 77 | 0.23716 | 0.093797 | 0.093797 | Component Quantities - Projected Component Area (Net): 1.21814 m2; Projected Component Area (Gross): 1.21814 m2; Component Thickness: 77 mm; Material Properties - Lucht frame_wit, ThermalConductivity: 0.15; Lucht frame_wit, SpecificHeatCapacity: 1008 J/kg/K; Lucht frame_wit, MassDensity: 1.2 kg/m3; Lucht frame_wit, Embodied Energy: 0 (MJ/kg); Lucht frame_wit, Embodied Carbon: 0 (kgCO₂/kg); Lucht frame_wit, Name: Lucht frame_wit; Lucht frame_wit, Participates in Collision Detection: yes
2 x Gipsplaat | Begane grond | Gipsplaat | 4.57803 | 2800 | 12.5 | 0.035 | 0.00572254 | 0.00572254 | Component Quantities - Projected Component Area (Net): 0.457803 m2; Projected Component Area (Gross): 0.457803 m2; Component Thickness: 12.5 mm; Material Properties - Gipsplaat, ThermalConductivity: 0.23; Gipsplaat, SpecificHeatCapacity: 840 J/kg/K; Gipsplaat, MassDensity: 800 kg/m3; Gipsplaat, Embodied Energy: 6.75 (MJ/kg); Gipsplaat, Embodied Carbon: 0.38 (kgCO₂/kg); Gipsplaat, Name: Gipsplaat; Gipsplaat, Participates in Collision Detection: yes
Lucht frame_wit | Begane grond | Lucht frame_wit | 0.042301 | 2800 | 77 | 0.2156 | 0.0352508 | 0.0352508 | Component Quantities - Projected Component Area (Net): 0.457803 m2; Projected Component Area (Gross): 0.457803 m2; Component Thickness: 77 mm; Material Properties - Lucht frame_wit, ThermalConductivity: 0.15; Lucht frame_wit, SpecificHeatCapacity: 1008 J/kg/K; Lucht frame_wit, MassDensity: 1.2 kg/m3; Lucht frame_wit, Embodied Energy: 0 (MJ/kg); Lucht frame_wit, Embodied Carbon: 0 (kgCO₂/kg); Lucht frame_wit, Name: Lucht frame_wit; Lucht frame_wit, Participates in Collision Detection: yes
2 x Gipsplaat | Begane grond | Gipsplaat | 11.116 | 2800 | 12.5 | 0.035 | 0.013895 | 0.013895 | Component Quantities - Projected Component Area (Net): 1.1116 m2; Projected Component Area (Gross): 1.1116 m2; Component Thickness: 12.5 mm; Material Properties - Gipsplaat, ThermalConductivity: 0.23; Gipsplaat, SpecificHeatCapacity: 840 J/kg/K; Gipsplaat, MassDensity: 800 kg/m3; Gipsplaat, Embodied Energy: 6.75 (MJ/kg); Gipsplaat, Embodied Carbon: 0.38 (kgCO₂/kg); Gipsplaat, Name: Gipsplaat; Gipsplaat, Participates in Collision Detection: yes
Lucht frame_wit | Begane grond | Lucht frame_wit | 0.102712 | 2800 | 77 | 0.2156 | 0.0855932 | 0.0855932 | Component Quantities - Projected Component Area (Net): 1.1116 m2; Projected Component Area (Gross): 1.1116 m2; Component Thickness: 77 mm; Material Properties - Lucht frame_wit, ThermalConductivity: 0.15; Lucht frame_wit, SpecificHeatCapacity: 1008 J/kg/K; Lucht frame_wit, MassDensity: 1.2 kg/m3; Lucht frame_wit, Embodied Energy: 0 (MJ/kg); Lucht frame_wit, Embodied Carbon: 0 (kgCO₂/kg); Lucht frame_wit, Name: Lucht frame_wit; Lucht frame_wit, Participates in Collision Detection: yes
14 x Gipsplaat | Begane grond | Gipsplaat | 12.6292 | 2780 | 12.5 | 0.03475 | 0.0157865 | 0.0374258 | Component Quantities - Projected Component Area (Net): 1.26292 m2; Projected Component Area (Gross): 2.99406 m2; Component Thickness: 12.5 mm; Material Properties - Gipsplaat, ThermalConductivity: 0.23; Gipsplaat, SpecificHeatCapacity: 840 J/kg/K; Gipsplaat, MassDensity: 800 kg/m3; Gipsplaat, Embodied Energy: 6.75 (MJ/kg); Gipsplaat, Embodied Carbon: 0.38 (kgCO₂/kg); Gipsplaat, Name: Gipsplaat; Gipsplaat, Participates in Collision Detection: yes
7 x Lucht frame_wit | Begane grond | Lucht frame_wit | 0.116694 | 2780 | 77 | 0.21406 | 0.0972448 | 0.230543 | Component Quantities - Projected Component Area (Net): 1.26292 m2; Projected Component Area (Gross): 2.99406 m2; Component Thickness: 77 mm; Material Properties - Lucht frame_wit, ThermalConductivity: 0.15; Lucht frame_wit, SpecificHeatCapacity: 1008 J/kg/K; Lucht frame_wit, MassDensity: 1.2 kg/m3; Lucht frame_wit, Embodied Energy: 0 (MJ/kg); Lucht frame_wit, Embodied Carbon: 0 (kgCO₂/kg); Lucht frame_wit, Name: Lucht frame_wit; Lucht frame_wit, Participates in Collision Detection: yes
2 x Gipsplaat | Begane grond | Gipsplaat | 23.2039 | 549.204 | 12.5 | 0.00686505 | 0.0290048 | 0.0290048 | Component Quantities - Projected Component Area (Net): 2.32039 m2; Projected Component Area (Gross): 2.32039 m2; Component Thickness: 12.5 mm; Material Properties - Gipsplaat, ThermalConductivity: 0.23; Gipsplaat, SpecificHeatCapacity: 840 J/kg/K; Gipsplaat, MassDensity: 800 kg/m3; Gipsplaat, Embodied Energy: 6.75 (MJ/kg); Gipsplaat, Embodied Carbon: 0.38 (kgCO₂/kg); Gipsplaat, Name: Gipsplaat; Gipsplaat, Participates in Collision Detection: yes
2 x Gipsplaat | Begane grond | Gipsplaat | 23.3412 | 549.204 | 12.5 | 0.00686505 | 0.0291764 | 0.0291764 | Component Quantities - Projected Component Area (Net): 2.33412 m2; Projected Component Area (Gross): 2.33412 m2; Component Thickness: 12.5 mm; Material Properties - Gipsplaat, ThermalConductivity: 0.23; Gipsplaat, SpecificHeatCapacity: 840 J/kg/K; Gipsplaat, MassDensity: 800 kg/m3; Gipsplaat, Embodied Energy: 6.75 (MJ/kg); Gipsplaat, Embodied Carbon: 0.38 (kgCO₂/kg); Gipsplaat, Name: Gipsplaat; Gipsplaat, Participates in Collision Detection: yes
4 x Gipsplaat | Begane grond | Gipsplaat | 16.6134 | 549.204 | 12.5 | 0.00686505 | 0.0207668 | 0.0207668 | Component Quantities - Projected Component Area (Net): 1.66134 m2; Projected Component Area (Gross): 1.66134 m2; Component Thickness: 12.5 mm; Material Properties - Gipsplaat, ThermalConductivity: 0.23; Gipsplaat, SpecificHeatCapacity: 840 J/kg/K; Gipsplaat, MassDensity: 800 kg/m3; Gipsplaat, Embodied Energy: 6.75 (MJ/kg); Gipsplaat, Embodied Carbon: 0.38 (kgCO₂/kg); Gipsplaat, Name: Gipsplaat; Gipsplaat, Participates in Collision Detection: yes
4 x Gipsplaat | Begane grond | Gipsplaat | 16.4761 | 549.204 | 12.5 | 0.00686505 | 0.0205951 | 0.0205951 | Component Quantities - Projected Component Area (Net): 1.64761 m2; Projected Component Area (Gross): 1.64761 m2; Component Thickness: 12.5 mm; Material Properties - Gipsplaat, ThermalConductivity: 0.23; Gipsplaat, SpecificHeatCapacity: 840 J/kg/K; Gipsplaat, MassDensity: 800 kg/m3; Gipsplaat, Embodied Energy: 6.75 (MJ/kg); Gipsplaat, Embodied Carbon: 0.38 (kgCO₂/kg); Gipsplaat, Name: Gipsplaat; Gipsplaat, Participates in Collision Detection: yes
2 x Gipsplaat | Begane grond | Gipsplaat | 39.68 | 549.204 | 12.5 | 0.00686505 | 0.0496 | 0.0496 | Component Quantities - Projected Component Area (Net): 3.968 m2; Projected Component Area (Gross): 3.968 m2; Component Thickness: 12.5 mm; Material Properties - Gipsplaat, ThermalConductivity: 0.23; Gipsplaat, SpecificHeatCapacity: 840 J/kg/K; Gipsplaat, MassDensity: 800 kg/m3; Gipsplaat, Embodied Energy: 6.75 (MJ/kg); Gipsplaat, Embodied Carbon: 0.38 (kgCO₂/kg); Gipsplaat, Name: Gipsplaat; Gipsplaat, Participates in Collision Detection: yes
2 x Gipsplaat | Begane grond | Gipsplaat | 39.8173 | 549.204 | 12.5 | 0.00686505 | 0.0497716 | 0.0497716 | Component Quantities - Projected Component Area (Net): 3.98173 m2; Projected Component Area (Gross): 3.98173 m2; Component Thickness: 12.5 mm; Material Properties - Gipsplaat, ThermalConductivity: 0.23; Gipsplaat, SpecificHeatCapacity: 840 J/kg/K; Gipsplaat, MassDensity: 800 kg/m3; Gipsplaat, Embodied Energy: 6.75 (MJ/kg); Gipsplaat, Embodied Carbon: 0.38 (kgCO₂/kg); Gipsplaat, Name: Gipsplaat; Gipsplaat, Participates in Collision Detection: yes
2 x Gipsplaat | Begane grond | Gipsplaat | 38.5896 | 3400 | 12.5 | 0.0425 | 0.048237 | 0.111237 | Component Quantities - Projected Component Area (Net): 3.85896 m2; Projected Component Area (Gross): 8.89895 m2; Component Thickness: 12.5 mm; Material Properties - Gipsplaat, ThermalConductivity: 0.23; Gipsplaat, SpecificHeatCapacity: 840 J/kg/K; Gipsplaat, MassDensity: 800 kg/m3; Gipsplaat, Embodied Energy: 6.75 (MJ/kg); Gipsplaat, Embodied Carbon: 0.38 (kgCO₂/kg); Gipsplaat, Name: Gipsplaat; Gipsplaat, Participates in Collision Detection: yes
2 x Gipsplaat | Begane grond | Gipsplaat | 39.4296 | 3400 | 12.5 | 0.0425 | 0.049287 | 0.112287 | Component Quantities - Projected Component Area (Net): 3.94296 m2; Projected Component Area (Gross): 8.98295 m2; Component Thickness: 12.5 mm; Material Properties - Gipsplaat, ThermalConductivity: 0.23; Gipsplaat, SpecificHeatCapacity: 840 J/kg/K; Gipsplaat, MassDensity: 800 kg/m3; Gipsplaat, Embodied Energy: 6.75 (MJ/kg); Gipsplaat, Embodied Carbon: 0.38 (kgCO₂/kg); Gipsplaat, Name: Gipsplaat; Gipsplaat, Participates in Collision Detection: yes
Isolatie - Steenwol LSW | Begane grond | Isolatie - Steenwol LSW | 11.9871 | 3400 | 50 | 0.17 | 0.217948 | 0.469948 | Component Quantities - Projected Component Area (Net): 4.35896 m2; Projected Component Area (Gross): 9.39895 m2; Component Thickness: 50 mm; Material Properties - Isolatie - Steenwol LSW, ThermalConductivity: 0.039; Isolatie - Steenwol LSW, SpecificHeatCapacity: 840 J/kg/K; Isolatie - Steenwol LSW, MassDensity: 55 kg/m3; Isolatie - Steenwol LSW, Embodied Energy: 16.8 (MJ/kg); Isolatie - Steenwol LSW, Embodied Carbon: 1.05 (kgCO₂/kg); Isolatie - Steenwol LSW, Name: Isolatie - Steenwol LSW; Isolatie - Steenwol LSW, Participates in Collision Detection: yes
Gipsplaat | Begane grond | Gipsplaat | 3.9875 | 3190 | 12.5 | 0.039875 | 0.00498438 | 0.00498438 | Component Quantities - Projected Component Area (Net): 0.39875 m2; Projected Component Area (Gross): 0.39875 m2; Component Thickness: 12.5 mm; Material Properties - Gipsplaat, ThermalConductivity: 0.23; Gipsplaat, SpecificHeatCapacity: 840 J/kg/K; Gipsplaat, MassDensity: 800 kg/m3; Gipsplaat, Embodied Energy: 6.75 (MJ/kg); Gipsplaat, Embodied Carbon: 0.38 (kgCO₂/kg); Gipsplaat, Name: Gipsplaat; Gipsplaat, Participates in Collision Detection: yes
2 x Gipsplaat | Begane grond | Gipsplaat | 4.38625 | 3190 | 12.5 | 0.039875 | 0.00548281 | 0.00548281 | Component Quantities - Projected Component Area (Net): 0.438625 m2; Projected Component Area (Gross): 0.438625 m2; Component Thickness: 12.5 mm; Material Properties - Gipsplaat, ThermalConductivity: 0.23; Gipsplaat, SpecificHeatCapacity: 840 J/kg/K; Gipsplaat, MassDensity: 800 kg/m3; Gipsplaat, Embodied Energy: 6.75 (MJ/kg); Gipsplaat, Embodied Carbon: 0.38 (kgCO₂/kg); Gipsplaat, Name: Gipsplaat; Gipsplaat, Participates in Collision Detection: yes
Gipsplaat | Begane grond | Gipsplaat | 4.785 | 3190 | 12.5 | 0.039875 | 0.00598125 | 0.00598125 | Component Quantities - Projected Component Area (Net): 0.4785 m2; Projected Component Area (Gross): 0.4785 m2; Component Thickness: 12.5 mm; Material Properties - Gipsplaat, ThermalConductivity: 0.23; Gipsplaat, SpecificHeatCapacity: 840 J/kg/K; Gipsplaat, MassDensity: 800 kg/m3; Gipsplaat, Embodied Energy: 6.75 (MJ/kg); Gipsplaat, Embodied Carbon: 0.38 (kgCO₂/kg); Gipsplaat, Name: Gipsplaat; Gipsplaat, Participates in Collision Detection: yes
5 x ALG - BINNENAFWERKING_hoge prioriteit | Begane grond | ALG - BINNENAFWERKING_hoge prioriteit | 12.48 |  |  |  | 0.0096 | 0.0096 | Component Quantities - Projected Component Area (Net): 0.48 m2; Projected Component Area (Gross): 0.48 m2; Component Thickness: 20 mm; Material Properties - ALG - BINNENAFWERKING_hoge prioriteit, ThermalConductivity: 0.5; ALG - BINNENAFWERKING_hoge prioriteit, SpecificHeatCapacity: 840 J/kg/K; ALG - BINNENAFWERKING_hoge prioriteit, MassDensity: 1300 kg/m3; ALG - BINNENAFWERKING_hoge prioriteit, Embodied Energy: 0.75 (MJ/kg); ALG - BINNENAFWERKING_hoge prioriteit, Embodied Carbon: 0.1 (kgCO₂/kg); ALG - BINNENAFWERKING_hoge prioriteit, Name: ALG - BINNENAFWERKING_hoge prioriteit; ALG - BINNENAFWERKING_hoge prioriteit, Participates in Collision Detection: yes
5 x ALG - ISOLATIE | Begane grond | ALG - ISOLATIE | 1.08 |  |  |  | 0.024 | 0.024 | Component Quantities - Projected Component Area (Net): 0.48 m2; Projected Component Area (Gross): 0.48 m2; Component Thickness: 50 mm; Material Properties - ALG - ISOLATIE, ThermalConductivity: 0.035; ALG - ISOLATIE, SpecificHeatCapacity: 840 J/kg/K; ALG - ISOLATIE, MassDensity: 45 kg/m3; ALG - ISOLATIE, Embodied Energy: 16.8 (MJ/kg); ALG - ISOLATIE, Embodied Carbon: 1.05 (kgCO₂/kg); ALG - ISOLATIE, Name: ALG - ISOLATIE; ALG - ISOLATIE, Participates in Collision Detection: yes
Cement | Begane grond | Cement | 33.3238 | 15.1058 | 84.9826 | 0.00128369 | 0.0175389 | 0.0175389 | Material Properties - Cement, ThermalConductivity: 0.93; Cement, SpecificHeatCapacity: 840 J/kg/K; Cement, MassDensity: 1900 kg/m3; Cement, Embodied Energy: 0.97 (MJ/kg); Cement, Embodied Carbon: 0.146 (kgCO₂/kg); Cement, Name: Cement; Cement, Participates in Collision Detection: yes
Steen - Betonblok vuilwerk | Begane grond | Steen - Betonblok vuilwerk | 475.251 | 214 | 100 | 0.0214 | 0.297032 | 0.297032 | Material Properties - Steen - Betonblok vuilwerk, ThermalConductivity: 0.75; Steen - Betonblok vuilwerk, SpecificHeatCapacity: 840 J/kg/K; Steen - Betonblok vuilwerk, MassDensity: 1600 kg/m3; Steen - Betonblok vuilwerk, Embodied Energy: 0.83 (MJ/kg); Steen - Betonblok vuilwerk, Embodied Carbon: 0.1 (kgCO₂/kg); Steen - Betonblok vuilwerk, Name: Steen - Betonblok vuilwerk; Steen - Betonblok vuilwerk, Participates in Collision Detection: yes
Beton gewapend prefab | Begane grond | Beton gewapend prefab | 7876.4 |  |  | 0.240906 | 3.28183 | 3.28183 | Material Properties - Beton gewapend prefab, ThermalConductivity: 2.5; Beton gewapend prefab, SpecificHeatCapacity: 1000 J/kg/K; Beton gewapend prefab, MassDensity: 2400 kg/m3; Beton gewapend prefab, Embodied Energy: 2.33 (MJ/kg); Beton gewapend prefab, Embodied Carbon: 0.242 (kgCO₂/kg); Beton gewapend prefab, Name: Beton gewapend prefab; Beton gewapend prefab, Participates in Collision Detection: yes
Beton gewapend prefab | Begane grond | Beton gewapend prefab | 439.436 | 110 | 120.009 | 0.013201 | 0.183098 | 0.183098 | Material Properties - Beton gewapend prefab, ThermalConductivity: 2.5; Beton gewapend prefab, SpecificHeatCapacity: 1000 J/kg/K; Beton gewapend prefab, MassDensity: 2400 kg/m3; Beton gewapend prefab, Embodied Energy: 2.33 (MJ/kg); Beton gewapend prefab, Embodied Carbon: 0.242 (kgCO₂/kg); Beton gewapend prefab, Name: Beton gewapend prefab; Beton gewapend prefab, Participates in Collision Detection: yes
Cement | Begane grond | Cement | 47.6114 | 15.1058 | 84.9826 | 0.00128369 | 0.0250586 | 0.0250586 | Material Properties - Cement, ThermalConductivity: 0.93; Cement, SpecificHeatCapacity: 840 J/kg/K; Cement, MassDensity: 1900 kg/m3; Cement, Embodied Energy: 0.97 (MJ/kg); Cement, Embodied Carbon: 0.146 (kgCO₂/kg); Cement, Name: Cement; Cement, Participates in Collision Detection: yes
Steen - Betonblok vuilwerk | Begane grond | Steen - Betonblok vuilwerk | 681.376 | 214 | 100 | 0.0214 | 0.42586 | 0.42586 | Material Properties - Steen - Betonblok vuilwerk, ThermalConductivity: 0.75; Steen - Betonblok vuilwerk, SpecificHeatCapacity: 840 J/kg/K; Steen - Betonblok vuilwerk, MassDensity: 1600 kg/m3; Steen - Betonblok vuilwerk, Embodied Energy: 0.83 (MJ/kg); Steen - Betonblok vuilwerk, Embodied Carbon: 0.1 (kgCO₂/kg); Steen - Betonblok vuilwerk, Name: Steen - Betonblok vuilwerk; Steen - Betonblok vuilwerk, Participates in Collision Detection: yes
Beton gewapend prefab | Begane grond | Beton gewapend prefab | 11208.5 |  |  | 0.240906 | 4.67021 | 4.67021 | Material Properties - Beton gewapend prefab, ThermalConductivity: 2.5; Beton gewapend prefab, SpecificHeatCapacity: 1000 J/kg/K; Beton gewapend prefab, MassDensity: 2400 kg/m3; Beton gewapend prefab, Embodied Energy: 2.33 (MJ/kg); Beton gewapend prefab, Embodied Carbon: 0.242 (kgCO₂/kg); Beton gewapend prefab, Name: Beton gewapend prefab; Beton gewapend prefab, Participates in Collision Detection: yes
Beton gewapend prefab | Begane grond | Beton gewapend prefab | 629.848 | 110 | 120.009 | 0.013201 | 0.262437 | 0.262437 | Material Properties - Beton gewapend prefab, ThermalConductivity: 2.5; Beton gewapend prefab, SpecificHeatCapacity: 1000 J/kg/K; Beton gewapend prefab, MassDensity: 2400 kg/m3; Beton gewapend prefab, Embodied Energy: 2.33 (MJ/kg); Beton gewapend prefab, Embodied Carbon: 0.242 (kgCO₂/kg); Beton gewapend prefab, Name: Beton gewapend prefab; Beton gewapend prefab, Participates in Collision Detection: yes
Cement | Begane grond | Cement | 31.2748 | 15.1058 | 84.9826 | 0.00128369 | 0.0164604 | 0.0164604 | Material Properties - Cement, ThermalConductivity: 0.93; Cement, SpecificHeatCapacity: 840 J/kg/K; Cement, MassDensity: 1900 kg/m3; Cement, Embodied Energy: 0.97 (MJ/kg); Cement, Embodied Carbon: 0.146 (kgCO₂/kg); Cement, Name: Cement; Cement, Participates in Collision Detection: yes
Steen - Betonblok vuilwerk | Begane grond | Steen - Betonblok vuilwerk | 446.283 | 214 | 100 | 0.0214 | 0.278927 | 0.278927 | Material Properties - Steen - Betonblok vuilwerk, ThermalConductivity: 0.75; Steen - Betonblok vuilwerk, SpecificHeatCapacity: 840 J/kg/K; Steen - Betonblok vuilwerk, MassDensity: 1600 kg/m3; Steen - Betonblok vuilwerk, Embodied Energy: 0.83 (MJ/kg); Steen - Betonblok vuilwerk, Embodied Carbon: 0.1 (kgCO₂/kg); Steen - Betonblok vuilwerk, Name: Steen - Betonblok vuilwerk; Steen - Betonblok vuilwerk, Participates in Collision Detection: yes
Beton gewapend prefab | Begane grond | Beton gewapend prefab | 7387.27 |  |  | 0.240906 | 3.07803 | 3.07803 | Material Properties - Beton gewapend prefab, ThermalConductivity: 2.5; Beton gewapend prefab, SpecificHeatCapacity: 1000 J/kg/K; Beton gewapend prefab, MassDensity: 2400 kg/m3; Beton gewapend prefab, Embodied Energy: 2.33 (MJ/kg); Beton gewapend prefab, Embodied Carbon: 0.242 (kgCO₂/kg); Beton gewapend prefab, Name: Beton gewapend prefab; Beton gewapend prefab, Participates in Collision Detection: yes
Beton gewapend prefab | Begane grond | Beton gewapend prefab | 412.631 | 110 | 120.009 | 0.013201 | 0.17193 | 0.17193 | Material Properties - Beton gewapend prefab, ThermalConductivity: 2.5; Beton gewapend prefab, SpecificHeatCapacity: 1000 J/kg/K; Beton gewapend prefab, MassDensity: 2400 kg/m3; Beton gewapend prefab, Embodied Energy: 2.33 (MJ/kg); Beton gewapend prefab, Embodied Carbon: 0.242 (kgCO₂/kg); Beton gewapend prefab, Name: Beton gewapend prefab; Beton gewapend prefab, Participates in Collision Detection: yes
4 x Beton gewapend prefab | Begane grond | Beton gewapend prefab | 531.196 |  |  | 0.110684 | 0.221332 | 0.221332 | Material Properties - Beton gewapend prefab, ThermalConductivity: 2.5; Beton gewapend prefab, SpecificHeatCapacity: 1000 J/kg/K; Beton gewapend prefab, MassDensity: 2400 kg/m3; Beton gewapend prefab, Embodied Energy: 2.33 (MJ/kg); Beton gewapend prefab, Embodied Carbon: 0.242 (kgCO₂/kg); Beton gewapend prefab, Name: Beton gewapend prefab; Beton gewapend prefab, Participates in Collision Detection: yes
12 x Beton gewapend prefab | Begane grond | Beton gewapend prefab | 416.693 |  |  | 0.0868291 | 0.173622 | 0.173622 | Material Properties - Beton gewapend prefab, ThermalConductivity: 2.5; Beton gewapend prefab, SpecificHeatCapacity: 1000 J/kg/K; Beton gewapend prefab, MassDensity: 2400 kg/m3; Beton gewapend prefab, Embodied Energy: 2.33 (MJ/kg); Beton gewapend prefab, Embodied Carbon: 0.242 (kgCO₂/kg); Beton gewapend prefab, Name: Beton gewapend prefab; Beton gewapend prefab, Participates in Collision Detection: yes
4 x Beton gewapend prefab | Begane grond | Beton gewapend prefab | 204.293 |  |  | 0.0425791 | 0.0851222 | 0.0851222 | Material Properties - Beton gewapend prefab, ThermalConductivity: 2.5; Beton gewapend prefab, SpecificHeatCapacity: 1000 J/kg/K; Beton gewapend prefab, MassDensity: 2400 kg/m3; Beton gewapend prefab, Embodied Energy: 2.33 (MJ/kg); Beton gewapend prefab, Embodied Carbon: 0.242 (kgCO₂/kg); Beton gewapend prefab, Name: Beton gewapend prefab; Beton gewapend prefab, Participates in Collision Detection: yes
2 x Steen - Betonblok vuilwerk | Begane grond | Steen - Betonblok vuilwerk | 29.9851 | 214 | 100 | 0.0214 | 0.0187407 | 0.0187407 | Material Properties - Steen - Betonblok vuilwerk, ThermalConductivity: 0.75; Steen - Betonblok vuilwerk, SpecificHeatCapacity: 840 J/kg/K; Steen - Betonblok vuilwerk, MassDensity: 1600 kg/m3; Steen - Betonblok vuilwerk, Embodied Energy: 0.83 (MJ/kg); Steen - Betonblok vuilwerk, Embodied Carbon: 0.1 (kgCO₂/kg); Steen - Betonblok vuilwerk, Name: Steen - Betonblok vuilwerk; Steen - Betonblok vuilwerk, Participates in Collision Detection: yes
8 x Beton gewapend prefab | Begane grond | Beton gewapend prefab | 716.976 |  |  | 0.298747 | 0.29874 | 0.29874 | Material Properties - Beton gewapend prefab, ThermalConductivity: 2.5; Beton gewapend prefab, SpecificHeatCapacity: 1000 J/kg/K; Beton gewapend prefab, MassDensity: 2400 kg/m3; Beton gewapend prefab, Embodied Energy: 2.33 (MJ/kg); Beton gewapend prefab, Embodied Carbon: 0.242 (kgCO₂/kg); Beton gewapend prefab, Name: Beton gewapend prefab; Beton gewapend prefab, Participates in Collision Detection: yes
8 x Beton gewapend prefab | Begane grond | Beton gewapend prefab | 31.6825 | 110 | 120.009 | 0.013201 | 0.013201 | 0.013201 | Material Properties - Beton gewapend prefab, ThermalConductivity: 2.5; Beton gewapend prefab, SpecificHeatCapacity: 1000 J/kg/K; Beton gewapend prefab, MassDensity: 2400 kg/m3; Beton gewapend prefab, Embodied Energy: 2.33 (MJ/kg); Beton gewapend prefab, Embodied Carbon: 0.242 (kgCO₂/kg); Beton gewapend prefab, Name: Beton gewapend prefab; Beton gewapend prefab, Participates in Collision Detection: yes
6 x Steen - Betonblok vuilwerk | Begane grond | Steen - Betonblok vuilwerk | 34.24 | 214 | 100 | 0.0214 | 0.0214 | 0.0214 | Material Properties - Steen - Betonblok vuilwerk, ThermalConductivity: 0.75; Steen - Betonblok vuilwerk, SpecificHeatCapacity: 840 J/kg/K; Steen - Betonblok vuilwerk, MassDensity: 1600 kg/m3; Steen - Betonblok vuilwerk, Embodied Energy: 0.83 (MJ/kg); Steen - Betonblok vuilwerk, Embodied Carbon: 0.1 (kgCO₂/kg); Steen - Betonblok vuilwerk, Name: Steen - Betonblok vuilwerk; Steen - Betonblok vuilwerk, Participates in Collision Detection: yes
Cement | Begane grond | Cement | 55.2113 | 15.1058 | 84.9826 | 0.00128369 | 0.0290586 | 0.0290586 | Material Properties - Cement, ThermalConductivity: 0.93; Cement, SpecificHeatCapacity: 840 J/kg/K; Cement, MassDensity: 1900 kg/m3; Cement, Embodied Energy: 0.97 (MJ/kg); Cement, Embodied Carbon: 0.146 (kgCO₂/kg); Cement, Name: Cement; Cement, Participates in Collision Detection: yes
Steen - Betonblok vuilwerk | Begane grond | Steen - Betonblok vuilwerk | 779.867 | 214 | 100 | 0.0214 | 0.487417 | 0.487417 | Material Properties - Steen - Betonblok vuilwerk, ThermalConductivity: 0.75; Steen - Betonblok vuilwerk, SpecificHeatCapacity: 840 J/kg/K; Steen - Betonblok vuilwerk, MassDensity: 1600 kg/m3; Steen - Betonblok vuilwerk, Embodied Energy: 0.83 (MJ/kg); Steen - Betonblok vuilwerk, Embodied Carbon: 0.1 (kgCO₂/kg); Steen - Betonblok vuilwerk, Name: Steen - Betonblok vuilwerk; Steen - Betonblok vuilwerk, Participates in Collision Detection: yes
Beton gewapend prefab | Begane grond | Beton gewapend prefab | 13409.4 |  |  | 0.240906 | 5.58725 | 5.58725 | Material Properties - Beton gewapend prefab, ThermalConductivity: 2.5; Beton gewapend prefab, SpecificHeatCapacity: 1000 J/kg/K; Beton gewapend prefab, MassDensity: 2400 kg/m3; Beton gewapend prefab, Embodied Energy: 2.33 (MJ/kg); Beton gewapend prefab, Embodied Carbon: 0.242 (kgCO₂/kg); Beton gewapend prefab, Name: Beton gewapend prefab; Beton gewapend prefab, Participates in Collision Detection: yes
Beton gewapend prefab | Begane grond | Beton gewapend prefab | 721.601 | 110 | 120.009 | 0.013201 | 0.300667 | 0.300667 | Material Properties - Beton gewapend prefab, ThermalConductivity: 2.5; Beton gewapend prefab, SpecificHeatCapacity: 1000 J/kg/K; Beton gewapend prefab, MassDensity: 2400 kg/m3; Beton gewapend prefab, Embodied Energy: 2.33 (MJ/kg); Beton gewapend prefab, Embodied Carbon: 0.242 (kgCO₂/kg); Beton gewapend prefab, Name: Beton gewapend prefab; Beton gewapend prefab, Participates in Collision Detection: yes
Cement | Begane grond | Cement | 38.2936 | 15.1058 | 84.9826 | 0.00128369 | 0.0201545 | 0.0201545 | Material Properties - Cement, ThermalConductivity: 0.93; Cement, SpecificHeatCapacity: 840 J/kg/K; Cement, MassDensity: 1900 kg/m3; Cement, Embodied Energy: 0.97 (MJ/kg); Cement, Embodied Carbon: 0.146 (kgCO₂/kg); Cement, Name: Cement; Cement, Participates in Collision Detection: yes
Steen - Betonblok vuilwerk | Begane grond | Steen - Betonblok vuilwerk | 540.689 | 214 | 100 | 0.0214 | 0.337931 | 0.337931 | Material Properties - Steen - Betonblok vuilwerk, ThermalConductivity: 0.75; Steen - Betonblok vuilwerk, SpecificHeatCapacity: 840 J/kg/K; Steen - Betonblok vuilwerk, MassDensity: 1600 kg/m3; Steen - Betonblok vuilwerk, Embodied Energy: 0.83 (MJ/kg); Steen - Betonblok vuilwerk, Embodied Carbon: 0.1 (kgCO₂/kg); Steen - Betonblok vuilwerk, Name: Steen - Betonblok vuilwerk; Steen - Betonblok vuilwerk, Participates in Collision Detection: yes
Beton gewapend prefab | Begane grond | Beton gewapend prefab | 9370.86 |  |  | 0.240906 | 3.90453 | 3.90453 | Material Properties - Beton gewapend prefab, ThermalConductivity: 2.5; Beton gewapend prefab, SpecificHeatCapacity: 1000 J/kg/K; Beton gewapend prefab, MassDensity: 2400 kg/m3; Beton gewapend prefab, Embodied Energy: 2.33 (MJ/kg); Beton gewapend prefab, Embodied Carbon: 0.242 (kgCO₂/kg); Beton gewapend prefab, Name: Beton gewapend prefab; Beton gewapend prefab, Participates in Collision Detection: yes
Beton gewapend prefab | Begane grond | Beton gewapend prefab | 500.293 | 110 | 120.009 | 0.013201 | 0.208455 | 0.208455 | Material Properties - Beton gewapend prefab, ThermalConductivity: 2.5; Beton gewapend prefab, SpecificHeatCapacity: 1000 J/kg/K; Beton gewapend prefab, MassDensity: 2400 kg/m3; Beton gewapend prefab, Embodied Energy: 2.33 (MJ/kg); Beton gewapend prefab, Embodied Carbon: 0.242 (kgCO₂/kg); Beton gewapend prefab, Name: Beton gewapend prefab; Beton gewapend prefab, Participates in Collision Detection: yes
Hout - MDF binnenzijde | Begane grond | Hout - MDF binnenzijde | 13.39 | 1030 | 20 | 0.0206 | 0.01339 | 0.01339 | Material Properties - Hout - MDF binnenzijde, ThermalConductivity: 0.24; Hout - MDF binnenzijde, SpecificHeatCapacity: 1600 J/kg/K; Hout - MDF binnenzijde, MassDensity: 1000 kg/m3; Hout - MDF binnenzijde, Embodied Energy: 16.8 (MJ/kg); Hout - MDF binnenzijde, Embodied Carbon: 0.87 (kgCO₂/kg); Hout - MDF binnenzijde, Name: Hout - MDF binnenzijde; Hout - MDF binnenzijde, Participates in Collision Detection: yes
Hout - MDF binnenzijde | Begane grond | Hout - MDF binnenzijde | 2.07 | 150 | 20 | 0.003 | 0.00207 | 0.00207 | Material Properties - Hout - MDF binnenzijde, ThermalConductivity: 0.24; Hout - MDF binnenzijde, SpecificHeatCapacity: 1600 J/kg/K; Hout - MDF binnenzijde, MassDensity: 1000 kg/m3; Hout - MDF binnenzijde, Embodied Energy: 16.8 (MJ/kg); Hout - MDF binnenzijde, Embodied Carbon: 0.87 (kgCO₂/kg); Hout - MDF binnenzijde, Name: Hout - MDF binnenzijde; Hout - MDF binnenzijde, Participates in Collision Detection: yes
Lucht_wit | Begane grond | Lucht_wit | 0.0044352 | 80 | 60 | 0.0048 | 0.003696 | 0.003696 | Material Properties - Lucht_wit, ThermalConductivity: 0.15; Lucht_wit, SpecificHeatCapacity: 1008 J/kg/K; Lucht_wit, MassDensity: 1.2 kg/m3; Lucht_wit, Embodied Energy: 0 (MJ/kg); Lucht_wit, Embodied Carbon: 0 (kgCO₂/kg); Lucht_wit, Name: Lucht_wit; Lucht_wit, Participates in Collision Detection: yes
2 x Hout - algemeen | Begane grond | Hout - algemeen | 1.0368 | 20 | 80 | 0.0016 | 0.001296 | 0.001296 | Material Properties - Hout - algemeen, ThermalConductivity: 0.17; Hout - algemeen, SpecificHeatCapacity: 1880 J/kg/K; Hout - algemeen, MassDensity: 800 kg/m3; Hout - algemeen, Embodied Energy: 10.4 (MJ/kg); Hout - algemeen, Embodied Carbon: 0.23 (kgCO₂/kg); Hout - algemeen, Name: Hout - algemeen; Hout - algemeen, Participates in Collision Detection: yes
Lucht_wit | Begane grond | Lucht_wit | 0.0707616 | 910 | 80 | 0.0728 | 0.058968 | 0.058968 | Material Properties - Lucht_wit, ThermalConductivity: 0.15; Lucht_wit, SpecificHeatCapacity: 1008 J/kg/K; Lucht_wit, MassDensity: 1.2 kg/m3; Lucht_wit, Embodied Energy: 0 (MJ/kg); Lucht_wit, Embodied Carbon: 0 (kgCO₂/kg); Lucht_wit, Name: Lucht_wit; Lucht_wit, Participates in Collision Detection: yes
Hout - MDF binnenzijde | Begane grond | Hout - MDF binnenzijde | 1.296 | 80 | 20 | 0.0016 | 0.001296 | 0.001296 | Material Properties - Hout - MDF binnenzijde, ThermalConductivity: 0.24; Hout - MDF binnenzijde, SpecificHeatCapacity: 1600 J/kg/K; Hout - MDF binnenzijde, MassDensity: 1000 kg/m3; Hout - MDF binnenzijde, Embodied Energy: 16.8 (MJ/kg); Hout - MDF binnenzijde, Embodied Carbon: 0.87 (kgCO₂/kg); Hout - MDF binnenzijde, Name: Hout - MDF binnenzijde; Hout - MDF binnenzijde, Participates in Collision Detection: yes
Hout - MDF binnenzijde | Begane grond | Hout - MDF binnenzijde | 2.43 | 150 | 20 | 0.003 | 0.00243 | 0.00243 | Material Properties - Hout - MDF binnenzijde, ThermalConductivity: 0.24; Hout - MDF binnenzijde, SpecificHeatCapacity: 1600 J/kg/K; Hout - MDF binnenzijde, MassDensity: 1000 kg/m3; Hout - MDF binnenzijde, Embodied Energy: 16.8 (MJ/kg); Hout - MDF binnenzijde, Embodied Carbon: 0.87 (kgCO₂/kg); Hout - MDF binnenzijde, Name: Hout - MDF binnenzijde; Hout - MDF binnenzijde, Participates in Collision Detection: yes
Hout - MDF binnenzijde | Begane grond | Hout - MDF binnenzijde | 16.66 | 980 | 20 | 0.0196 | 0.01666 | 0.01666 | Material Properties - Hout - MDF binnenzijde, ThermalConductivity: 0.24; Hout - MDF binnenzijde, SpecificHeatCapacity: 1600 J/kg/K; Hout - MDF binnenzijde, MassDensity: 1000 kg/m3; Hout - MDF binnenzijde, Embodied Energy: 16.8 (MJ/kg); Hout - MDF binnenzijde, Embodied Carbon: 0.87 (kgCO₂/kg); Hout - MDF binnenzijde, Name: Hout - MDF binnenzijde; Hout - MDF binnenzijde, Participates in Collision Detection: yes
2 x Hout - MDF binnenzijde | Begane grond | Hout - MDF binnenzijde | 31.312 | 1030 | 20 | 0.0206 | 0.031312 | 0.031312 | Material Properties - Hout - MDF binnenzijde, ThermalConductivity: 0.24; Hout - MDF binnenzijde, SpecificHeatCapacity: 1600 J/kg/K; Hout - MDF binnenzijde, MassDensity: 1000 kg/m3; Hout - MDF binnenzijde, Embodied Energy: 16.8 (MJ/kg); Hout - MDF binnenzijde, Embodied Carbon: 0.87 (kgCO₂/kg); Hout - MDF binnenzijde, Name: Hout - MDF binnenzijde; Hout - MDF binnenzijde, Participates in Collision Detection: yes
2 x Hout - MDF binnenzijde | Begane grond | Hout - MDF binnenzijde | 4.68 | 150 | 20 | 0.003 | 0.00468 | 0.00468 | Material Properties - Hout - MDF binnenzijde, ThermalConductivity: 0.24; Hout - MDF binnenzijde, SpecificHeatCapacity: 1600 J/kg/K; Hout - MDF binnenzijde, MassDensity: 1000 kg/m3; Hout - MDF binnenzijde, Embodied Energy: 16.8 (MJ/kg); Hout - MDF binnenzijde, Embodied Carbon: 0.87 (kgCO₂/kg); Hout - MDF binnenzijde, Name: Hout - MDF binnenzijde; Hout - MDF binnenzijde, Participates in Collision Detection: yes
2 x Lucht_wit | Begane grond | Lucht_wit | 0.009216 | 80 | 60 | 0.0048 | 0.00768 | 0.00768 | Material Properties - Lucht_wit, ThermalConductivity: 0.15; Lucht_wit, SpecificHeatCapacity: 1008 J/kg/K; Lucht_wit, MassDensity: 1.2 kg/m3; Lucht_wit, Embodied Energy: 0 (MJ/kg); Lucht_wit, Embodied Carbon: 0 (kgCO₂/kg); Lucht_wit, Name: Lucht_wit; Lucht_wit, Participates in Collision Detection: yes
4 x Hout - algemeen | Begane grond | Hout - algemeen | 2.0736 | 20 | 80 | 0.0016 | 0.002592 | 0.002592 | Material Properties - Hout - algemeen, ThermalConductivity: 0.17; Hout - algemeen, SpecificHeatCapacity: 1880 J/kg/K; Hout - algemeen, MassDensity: 800 kg/m3; Hout - algemeen, Embodied Energy: 10.4 (MJ/kg); Hout - algemeen, Embodied Carbon: 0.23 (kgCO₂/kg); Hout - algemeen, Name: Hout - algemeen; Hout - algemeen, Participates in Collision Detection: yes
2 x Lucht_wit | Begane grond | Lucht_wit | 0.141523 | 910 | 80 | 0.0728 | 0.117936 | 0.117936 | Material Properties - Lucht_wit, ThermalConductivity: 0.15; Lucht_wit, SpecificHeatCapacity: 1008 J/kg/K; Lucht_wit, MassDensity: 1.2 kg/m3; Lucht_wit, Embodied Energy: 0 (MJ/kg); Lucht_wit, Embodied Carbon: 0 (kgCO₂/kg); Lucht_wit, Name: Lucht_wit; Lucht_wit, Participates in Collision Detection: yes
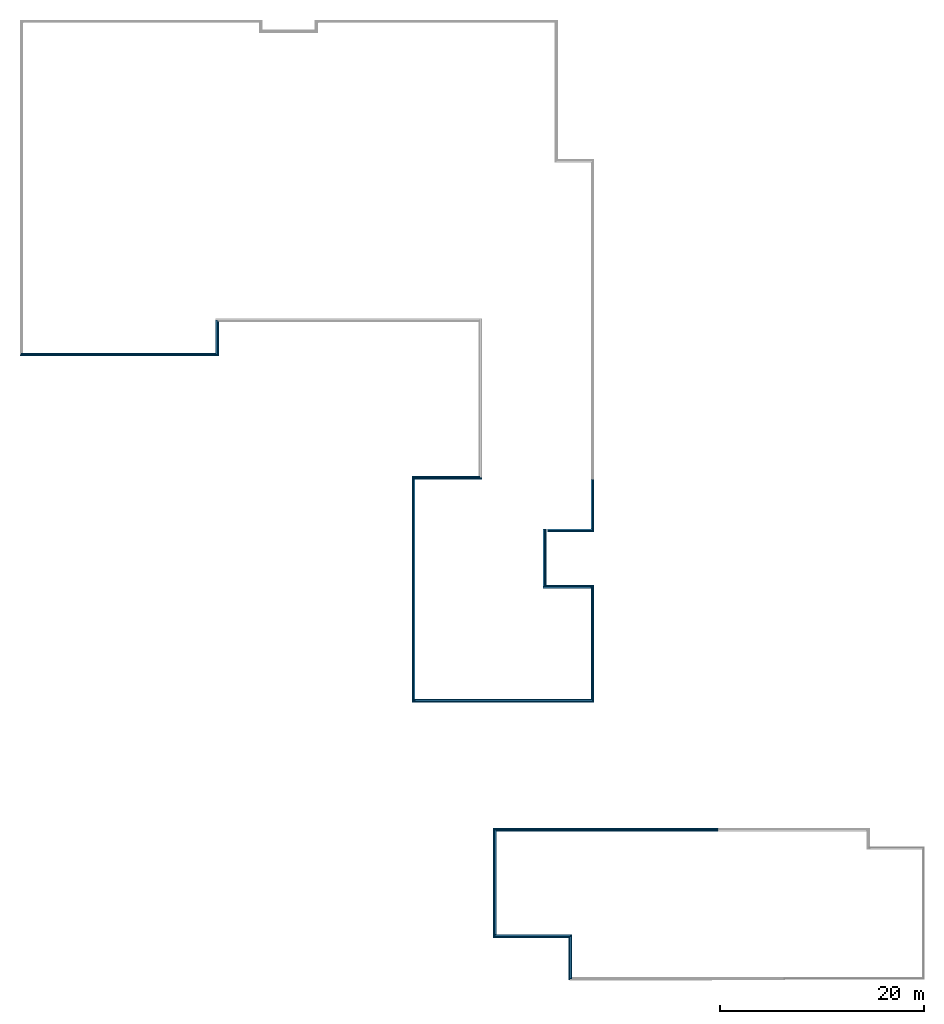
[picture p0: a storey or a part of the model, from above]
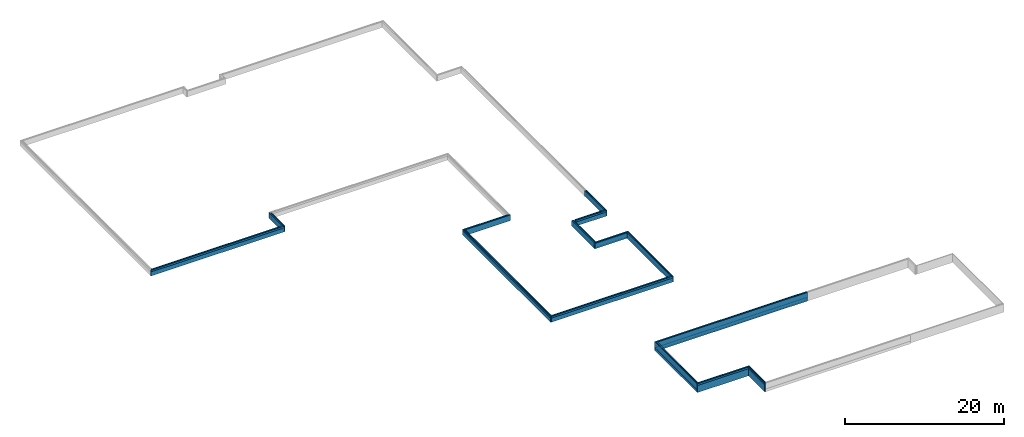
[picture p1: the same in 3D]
Properties of the parts of a building model (IFC2X3), part 10 of 19

# IfcBuildingElementPart (2070)
Name | In | Material | Mass (kg) | Rectangular Component Height (mm) | Rectangular Component Width (mm) | Component Cross Section Area (m2) | Component Volume (Net) (m3) | Component Volume (Gross) (m3)
2 x Hout - MDF binnenzijde | Begane grond | Hout - MDF binnenzijde | 2.688 | 80 | 20 | 0.0016 | 0.002688 | 0.002688 | Material Properties - Hout - MDF binnenzijde, ThermalConductivity: 0.24; Hout - MDF binnenzijde, SpecificHeatCapacity: 1600 J/kg/K; Hout - MDF binnenzijde, MassDensity: 1000 kg/m3; Hout - MDF binnenzijde, Embodied Energy: 16.8 (MJ/kg); Hout - MDF binnenzijde, Embodied Carbon: 0.87 (kgCO₂/kg); Hout - MDF binnenzijde, Name: Hout - MDF binnenzijde; Hout - MDF binnenzijde, Participates in Collision Detection: yes
2 x Hout - MDF binnenzijde | Begane grond | Hout - MDF binnenzijde | 5.04 | 150 | 20 | 0.003 | 0.00504 | 0.00504 | Material Properties - Hout - MDF binnenzijde, ThermalConductivity: 0.24; Hout - MDF binnenzijde, SpecificHeatCapacity: 1600 J/kg/K; Hout - MDF binnenzijde, MassDensity: 1000 kg/m3; Hout - MDF binnenzijde, Embodied Energy: 16.8 (MJ/kg); Hout - MDF binnenzijde, Embodied Carbon: 0.87 (kgCO₂/kg); Hout - MDF binnenzijde, Name: Hout - MDF binnenzijde; Hout - MDF binnenzijde, Participates in Collision Detection: yes
2 x Hout - MDF binnenzijde | Begane grond | Hout - MDF binnenzijde | 33.712 | 980 | 20 | 0.0196 | 0.033712 | 0.033712 | Material Properties - Hout - MDF binnenzijde, ThermalConductivity: 0.24; Hout - MDF binnenzijde, SpecificHeatCapacity: 1600 J/kg/K; Hout - MDF binnenzijde, MassDensity: 1000 kg/m3; Hout - MDF binnenzijde, Embodied Energy: 16.8 (MJ/kg); Hout - MDF binnenzijde, Embodied Carbon: 0.87 (kgCO₂/kg); Hout - MDF binnenzijde, Name: Hout - MDF binnenzijde; Hout - MDF binnenzijde, Participates in Collision Detection: yes
Hout - MDF binnenzijde | Begane grond | Hout - MDF binnenzijde | 12.978 | 1030 | 20 | 0.0206 | 0.012978 | 0.012978 | Material Properties - Hout - MDF binnenzijde, ThermalConductivity: 0.24; Hout - MDF binnenzijde, SpecificHeatCapacity: 1600 J/kg/K; Hout - MDF binnenzijde, MassDensity: 1000 kg/m3; Hout - MDF binnenzijde, Embodied Energy: 16.8 (MJ/kg); Hout - MDF binnenzijde, Embodied Carbon: 0.87 (kgCO₂/kg); Hout - MDF binnenzijde, Name: Hout - MDF binnenzijde; Hout - MDF binnenzijde, Participates in Collision Detection: yes
Hout - MDF binnenzijde | Begane grond | Hout - MDF binnenzijde | 2.01 | 150 | 20 | 0.003 | 0.00201 | 0.00201 | Material Properties - Hout - MDF binnenzijde, ThermalConductivity: 0.24; Hout - MDF binnenzijde, SpecificHeatCapacity: 1600 J/kg/K; Hout - MDF binnenzijde, MassDensity: 1000 kg/m3; Hout - MDF binnenzijde, Embodied Energy: 16.8 (MJ/kg); Hout - MDF binnenzijde, Embodied Carbon: 0.87 (kgCO₂/kg); Hout - MDF binnenzijde, Name: Hout - MDF binnenzijde; Hout - MDF binnenzijde, Participates in Collision Detection: yes
Lucht_wit | Begane grond | Lucht_wit | 0.0040896 | 80 | 60 | 0.0048 | 0.003408 | 0.003408 | Material Properties - Lucht_wit, ThermalConductivity: 0.15; Lucht_wit, SpecificHeatCapacity: 1008 J/kg/K; Lucht_wit, MassDensity: 1.2 kg/m3; Lucht_wit, Embodied Energy: 0 (MJ/kg); Lucht_wit, Embodied Carbon: 0 (kgCO₂/kg); Lucht_wit, Name: Lucht_wit; Lucht_wit, Participates in Collision Detection: yes
2 x Hout - algemeen | Begane grond | Hout - algemeen | 0.9344 | 20 | 80 | 0.0016 | 0.001168 | 0.001168 | Material Properties - Hout - algemeen, ThermalConductivity: 0.17; Hout - algemeen, SpecificHeatCapacity: 1880 J/kg/K; Hout - algemeen, MassDensity: 800 kg/m3; Hout - algemeen, Embodied Energy: 10.4 (MJ/kg); Hout - algemeen, Embodied Carbon: 0.23 (kgCO₂/kg); Hout - algemeen, Name: Hout - algemeen; Hout - algemeen, Participates in Collision Detection: yes
Lucht_wit | Begane grond | Lucht_wit | 0.0637728 | 910 | 80 | 0.0728 | 0.053144 | 0.053144 | Material Properties - Lucht_wit, ThermalConductivity: 0.15; Lucht_wit, SpecificHeatCapacity: 1008 J/kg/K; Lucht_wit, MassDensity: 1.2 kg/m3; Lucht_wit, Embodied Energy: 0 (MJ/kg); Lucht_wit, Embodied Carbon: 0 (kgCO₂/kg); Lucht_wit, Name: Lucht_wit; Lucht_wit, Participates in Collision Detection: yes
Hout - MDF binnenzijde | Begane grond | Hout - MDF binnenzijde | 1.264 | 80 | 20 | 0.0016 | 0.001264 | 0.001264 | Material Properties - Hout - MDF binnenzijde, ThermalConductivity: 0.24; Hout - MDF binnenzijde, SpecificHeatCapacity: 1600 J/kg/K; Hout - MDF binnenzijde, MassDensity: 1000 kg/m3; Hout - MDF binnenzijde, Embodied Energy: 16.8 (MJ/kg); Hout - MDF binnenzijde, Embodied Carbon: 0.87 (kgCO₂/kg); Hout - MDF binnenzijde, Name: Hout - MDF binnenzijde; Hout - MDF binnenzijde, Participates in Collision Detection: yes
Hout - MDF binnenzijde | Begane grond | Hout - MDF binnenzijde | 2.37 | 150 | 20 | 0.003 | 0.00237 | 0.00237 | Material Properties - Hout - MDF binnenzijde, ThermalConductivity: 0.24; Hout - MDF binnenzijde, SpecificHeatCapacity: 1600 J/kg/K; Hout - MDF binnenzijde, MassDensity: 1000 kg/m3; Hout - MDF binnenzijde, Embodied Energy: 16.8 (MJ/kg); Hout - MDF binnenzijde, Embodied Carbon: 0.87 (kgCO₂/kg); Hout - MDF binnenzijde, Name: Hout - MDF binnenzijde; Hout - MDF binnenzijde, Participates in Collision Detection: yes
Hout - MDF binnenzijde | Begane grond | Hout - MDF binnenzijde | 16.268 | 980 | 20 | 0.0196 | 0.016268 | 0.016268 | Material Properties - Hout - MDF binnenzijde, ThermalConductivity: 0.24; Hout - MDF binnenzijde, SpecificHeatCapacity: 1600 J/kg/K; Hout - MDF binnenzijde, MassDensity: 1000 kg/m3; Hout - MDF binnenzijde, Embodied Energy: 16.8 (MJ/kg); Hout - MDF binnenzijde, Embodied Carbon: 0.87 (kgCO₂/kg); Hout - MDF binnenzijde, Name: Hout - MDF binnenzijde; Hout - MDF binnenzijde, Participates in Collision Detection: yes
2 x Hout - MDF binnenzijde | Begane grond | Hout - MDF binnenzijde | 1.96 | 980 | 20 | 0.0196 | 0.00196 | 0.00196 | Material Properties - Hout - MDF binnenzijde, ThermalConductivity: 0.24; Hout - MDF binnenzijde, SpecificHeatCapacity: 1600 J/kg/K; Hout - MDF binnenzijde, MassDensity: 1000 kg/m3; Hout - MDF binnenzijde, Embodied Energy: 16.8 (MJ/kg); Hout - MDF binnenzijde, Embodied Carbon: 0.87 (kgCO₂/kg); Hout - MDF binnenzijde, Name: Hout - MDF binnenzijde; Hout - MDF binnenzijde, Participates in Collision Detection: yes
2 x Hout - MDF binnenzijde | Begane grond | Hout - MDF binnenzijde | 0.24 | 150 | 20 | 0.003 | 0.00024 | 0.00024 | Material Properties - Hout - MDF binnenzijde, ThermalConductivity: 0.24; Hout - MDF binnenzijde, SpecificHeatCapacity: 1600 J/kg/K; Hout - MDF binnenzijde, MassDensity: 1000 kg/m3; Hout - MDF binnenzijde, Embodied Energy: 16.8 (MJ/kg); Hout - MDF binnenzijde, Embodied Carbon: 0.87 (kgCO₂/kg); Hout - MDF binnenzijde, Name: Hout - MDF binnenzijde; Hout - MDF binnenzijde, Participates in Collision Detection: yes
2 x Hout - MDF binnenzijde | Begane grond | Hout - MDF binnenzijde | 0.128 | 80 | 20 | 0.0016 | 0.000128 | 0.000128 | Material Properties - Hout - MDF binnenzijde, ThermalConductivity: 0.24; Hout - MDF binnenzijde, SpecificHeatCapacity: 1600 J/kg/K; Hout - MDF binnenzijde, MassDensity: 1000 kg/m3; Hout - MDF binnenzijde, Embodied Energy: 16.8 (MJ/kg); Hout - MDF binnenzijde, Embodied Carbon: 0.87 (kgCO₂/kg); Hout - MDF binnenzijde, Name: Hout - MDF binnenzijde; Hout - MDF binnenzijde, Participates in Collision Detection: yes
2 x Lucht_wit | Begane grond | Lucht_wit | 0.0017472 | 910 | 80 | 0.0728 | 0.001456 | 0.001456 | Material Properties - Lucht_wit, ThermalConductivity: 0.15; Lucht_wit, SpecificHeatCapacity: 1008 J/kg/K; Lucht_wit, MassDensity: 1.2 kg/m3; Lucht_wit, Embodied Energy: 0 (MJ/kg); Lucht_wit, Embodied Carbon: 0 (kgCO₂/kg); Lucht_wit, Name: Lucht_wit; Lucht_wit, Participates in Collision Detection: yes
4 x Hout - algemeen | Begane grond | Hout - algemeen | 0.0256 | 20 | 80 | 0.0016 | 0.000032 | 0.000032 | Material Properties - Hout - algemeen, ThermalConductivity: 0.17; Hout - algemeen, SpecificHeatCapacity: 1880 J/kg/K; Hout - algemeen, MassDensity: 800 kg/m3; Hout - algemeen, Embodied Energy: 10.4 (MJ/kg); Hout - algemeen, Embodied Carbon: 0.23 (kgCO₂/kg); Hout - algemeen, Name: Hout - algemeen; Hout - algemeen, Participates in Collision Detection: yes
2 x Lucht_wit | Begane grond | Lucht_wit | 0.0001152 | 80 | 60 | 0.0048 | 0.000096 | 0.000096 | Material Properties - Lucht_wit, ThermalConductivity: 0.15; Lucht_wit, SpecificHeatCapacity: 1008 J/kg/K; Lucht_wit, MassDensity: 1.2 kg/m3; Lucht_wit, Embodied Energy: 0 (MJ/kg); Lucht_wit, Embodied Carbon: 0 (kgCO₂/kg); Lucht_wit, Name: Lucht_wit; Lucht_wit, Participates in Collision Detection: yes
2 x Hout - MDF binnenzijde | Begane grond | Hout - MDF binnenzijde | 0.06 | 150 | 20 | 0.003 | 0.00006 | 0.00006 | Material Properties - Hout - MDF binnenzijde, ThermalConductivity: 0.24; Hout - MDF binnenzijde, SpecificHeatCapacity: 1600 J/kg/K; Hout - MDF binnenzijde, MassDensity: 1000 kg/m3; Hout - MDF binnenzijde, Embodied Energy: 16.8 (MJ/kg); Hout - MDF binnenzijde, Embodied Carbon: 0.87 (kgCO₂/kg); Hout - MDF binnenzijde, Name: Hout - MDF binnenzijde; Hout - MDF binnenzijde, Participates in Collision Detection: yes
Hout - MDF binnenzijde | Begane grond | Hout - MDF binnenzijde | 9.9144 | 729 | 20 | 0.01458 | 0.0099144 | 0.0099144 | Material Properties - Hout - MDF binnenzijde, ThermalConductivity: 0.24; Hout - MDF binnenzijde, SpecificHeatCapacity: 1600 J/kg/K; Hout - MDF binnenzijde, MassDensity: 1000 kg/m3; Hout - MDF binnenzijde, Embodied Energy: 16.8 (MJ/kg); Hout - MDF binnenzijde, Embodied Carbon: 0.87 (kgCO₂/kg); Hout - MDF binnenzijde, Name: Hout - MDF binnenzijde; Hout - MDF binnenzijde, Participates in Collision Detection: yes
Hout - MDF binnenzijde | Begane grond | Hout - MDF binnenzijde | 1.632 | 20 | 120 | 0.0024 | 0.001632 | 0.001632 | Material Properties - Hout - MDF binnenzijde, ThermalConductivity: 0.24; Hout - MDF binnenzijde, SpecificHeatCapacity: 1600 J/kg/K; Hout - MDF binnenzijde, MassDensity: 1000 kg/m3; Hout - MDF binnenzijde, Embodied Energy: 16.8 (MJ/kg); Hout - MDF binnenzijde, Embodied Carbon: 0.87 (kgCO₂/kg); Hout - MDF binnenzijde, Name: Hout - MDF binnenzijde; Hout - MDF binnenzijde, Participates in Collision Detection: yes
Lucht_wit | Begane grond | Lucht_wit | 0.0450432 | 690 | 80 | 0.0552 | 0.037536 | 0.037536 | Material Properties - Lucht_wit, ThermalConductivity: 0.15; Lucht_wit, SpecificHeatCapacity: 1008 J/kg/K; Lucht_wit, MassDensity: 1.2 kg/m3; Lucht_wit, Embodied Energy: 0 (MJ/kg); Lucht_wit, Embodied Carbon: 0 (kgCO₂/kg); Lucht_wit, Name: Lucht_wit; Lucht_wit, Participates in Collision Detection: yes
2 x Hout - algemeen | Begane grond | Hout - algemeen | 0.8704 | 20 | 80 | 0.0016 | 0.001088 | 0.001088 | Material Properties - Hout - algemeen, ThermalConductivity: 0.17; Hout - algemeen, SpecificHeatCapacity: 1880 J/kg/K; Hout - algemeen, MassDensity: 800 kg/m3; Hout - algemeen, Embodied Energy: 10.4 (MJ/kg); Hout - algemeen, Embodied Carbon: 0.23 (kgCO₂/kg); Hout - algemeen, Name: Hout - algemeen; Hout - algemeen, Participates in Collision Detection: yes
Hout - MDF binnenzijde | Begane grond | Hout - MDF binnenzijde | 9.9144 |  |  | 0.01458 | 0.0099144 | 0.0099144 | Material Properties - Hout - MDF binnenzijde, ThermalConductivity: 0.24; Hout - MDF binnenzijde, SpecificHeatCapacity: 1600 J/kg/K; Hout - MDF binnenzijde, MassDensity: 1000 kg/m3; Hout - MDF binnenzijde, Embodied Energy: 16.8 (MJ/kg); Hout - MDF binnenzijde, Embodied Carbon: 0.87 (kgCO₂/kg); Hout - MDF binnenzijde, Name: Hout - MDF binnenzijde; Hout - MDF binnenzijde, Participates in Collision Detection: yes
Cement | Begane grond | Cement | 14.7719 | 15.1058 | 84.9826 | 0.00128369 | 0.00777469 | 0.00777469 | Material Properties - Cement, ThermalConductivity: 0.93; Cement, SpecificHeatCapacity: 840 J/kg/K; Cement, MassDensity: 1900 kg/m3; Cement, Embodied Energy: 0.97 (MJ/kg); Cement, Embodied Carbon: 0.146 (kgCO₂/kg); Cement, Name: Cement; Cement, Participates in Collision Detection: yes
Steen - Betonblok vuilwerk | Begane grond | Steen - Betonblok vuilwerk | 213.144 | 214 | 100 | 0.0214 | 0.133215 | 0.133215 | Material Properties - Steen - Betonblok vuilwerk, ThermalConductivity: 0.75; Steen - Betonblok vuilwerk, SpecificHeatCapacity: 840 J/kg/K; Steen - Betonblok vuilwerk, MassDensity: 1600 kg/m3; Steen - Betonblok vuilwerk, Embodied Energy: 0.83 (MJ/kg); Steen - Betonblok vuilwerk, Embodied Carbon: 0.1 (kgCO₂/kg); Steen - Betonblok vuilwerk, Name: Steen - Betonblok vuilwerk; Steen - Betonblok vuilwerk, Participates in Collision Detection: yes
Beton gewapend prefab | Begane grond | Beton gewapend prefab | 3450.61 |  |  | 0.240906 | 1.43775 | 1.43775 | Material Properties - Beton gewapend prefab, ThermalConductivity: 2.5; Beton gewapend prefab, SpecificHeatCapacity: 1000 J/kg/K; Beton gewapend prefab, MassDensity: 2400 kg/m3; Beton gewapend prefab, Embodied Energy: 2.33 (MJ/kg); Beton gewapend prefab, Embodied Carbon: 0.242 (kgCO₂/kg); Beton gewapend prefab, Name: Beton gewapend prefab; Beton gewapend prefab, Participates in Collision Detection: yes
Beton gewapend prefab | Begane grond | Beton gewapend prefab | 196.906 | 110 | 120.009 | 0.013201 | 0.0820443 | 0.0820443 | Material Properties - Beton gewapend prefab, ThermalConductivity: 2.5; Beton gewapend prefab, SpecificHeatCapacity: 1000 J/kg/K; Beton gewapend prefab, MassDensity: 2400 kg/m3; Beton gewapend prefab, Embodied Energy: 2.33 (MJ/kg); Beton gewapend prefab, Embodied Carbon: 0.242 (kgCO₂/kg); Beton gewapend prefab, Name: Beton gewapend prefab; Beton gewapend prefab, Participates in Collision Detection: yes
Cement | Begane grond | Cement | 6.83244 | 15.1058 | 84.9826 | 0.00128369 | 0.00359602 | 0.00359602 | Material Properties - Cement, ThermalConductivity: 0.93; Cement, SpecificHeatCapacity: 840 J/kg/K; Cement, MassDensity: 1900 kg/m3; Cement, Embodied Energy: 0.97 (MJ/kg); Cement, Embodied Carbon: 0.146 (kgCO₂/kg); Cement, Name: Cement; Cement, Participates in Collision Detection: yes
Steen - Betonblok vuilwerk | Begane grond | Steen - Betonblok vuilwerk | 100.729 | 214 | 100 | 0.0214 | 0.0629553 | 0.0629553 | Material Properties - Steen - Betonblok vuilwerk, ThermalConductivity: 0.75; Steen - Betonblok vuilwerk, SpecificHeatCapacity: 840 J/kg/K; Steen - Betonblok vuilwerk, MassDensity: 1600 kg/m3; Steen - Betonblok vuilwerk, Embodied Energy: 0.83 (MJ/kg); Steen - Betonblok vuilwerk, Embodied Carbon: 0.1 (kgCO₂/kg); Steen - Betonblok vuilwerk, Name: Steen - Betonblok vuilwerk; Steen - Betonblok vuilwerk, Participates in Collision Detection: yes
Beton gewapend prefab | Begane grond | Beton gewapend prefab | 1552.43 |  |  | 0.240906 | 0.646845 | 0.646845 | Material Properties - Beton gewapend prefab, ThermalConductivity: 2.5; Beton gewapend prefab, SpecificHeatCapacity: 1000 J/kg/K; Beton gewapend prefab, MassDensity: 2400 kg/m3; Beton gewapend prefab, Embodied Energy: 2.33 (MJ/kg); Beton gewapend prefab, Embodied Carbon: 0.242 (kgCO₂/kg); Beton gewapend prefab, Name: Beton gewapend prefab; Beton gewapend prefab, Participates in Collision Detection: yes
Beton gewapend prefab | Begane grond | Beton gewapend prefab | 92.8878 | 110 | 120.009 | 0.013201 | 0.0387033 | 0.0387033 | Material Properties - Beton gewapend prefab, ThermalConductivity: 2.5; Beton gewapend prefab, SpecificHeatCapacity: 1000 J/kg/K; Beton gewapend prefab, MassDensity: 2400 kg/m3; Beton gewapend prefab, Embodied Energy: 2.33 (MJ/kg); Beton gewapend prefab, Embodied Carbon: 0.242 (kgCO₂/kg); Beton gewapend prefab, Name: Beton gewapend prefab; Beton gewapend prefab, Participates in Collision Detection: yes
2 x Gipsplaat | Begane grond | Gipsplaat | 5.115 | 3100 | 12.5 | 0.03875 | 0.00639375 | 0.00639375 | Component Quantities - Projected Component Area (Net): 0.5115 m2; Projected Component Area (Gross): 0.5115 m2; Component Thickness: 12.5 mm; Material Properties - Gipsplaat, ThermalConductivity: 0.23; Gipsplaat, SpecificHeatCapacity: 840 J/kg/K; Gipsplaat, MassDensity: 800 kg/m3; Gipsplaat, Embodied Energy: 6.75 (MJ/kg); Gipsplaat, Embodied Carbon: 0.38 (kgCO₂/kg); Gipsplaat, Name: Gipsplaat; Gipsplaat, Participates in Collision Detection: yes
Lucht frame_wit | Begane grond | Lucht frame_wit | 0.0472626 | 3100 | 77 | 0.2387 | 0.0393855 | 0.0393855 | Component Quantities - Projected Component Area (Net): 0.5115 m2; Projected Component Area (Gross): 0.5115 m2; Component Thickness: 77 mm; Material Properties - Lucht frame_wit, ThermalConductivity: 0.15; Lucht frame_wit, SpecificHeatCapacity: 1008 J/kg/K; Lucht frame_wit, MassDensity: 1.2 kg/m3; Lucht frame_wit, Embodied Energy: 0 (MJ/kg); Lucht frame_wit, Embodied Carbon: 0 (kgCO₂/kg); Lucht frame_wit, Name: Lucht frame_wit; Lucht frame_wit, Participates in Collision Detection: yes
12 x Gipsplaat | Begane grond | Gipsplaat | 13.806 | 3080 | 12.5 | 0.0385 | 0.0172575 | 0.0440825 | Component Quantities - Projected Component Area (Net): 1.3806 m2; Projected Component Area (Gross): 3.5266 m2; Component Thickness: 12.5 mm; Material Properties - Gipsplaat, ThermalConductivity: 0.23; Gipsplaat, SpecificHeatCapacity: 840 J/kg/K; Gipsplaat, MassDensity: 800 kg/m3; Gipsplaat, Embodied Energy: 6.75 (MJ/kg); Gipsplaat, Embodied Carbon: 0.38 (kgCO₂/kg); Gipsplaat, Name: Gipsplaat; Gipsplaat, Participates in Collision Detection: yes
6 x Lucht frame_wit | Begane grond | Lucht frame_wit | 0.127567 | 3080 | 77 | 0.23716 | 0.106306 | 0.271548 | Component Quantities - Projected Component Area (Net): 1.3806 m2; Projected Component Area (Gross): 3.5266 m2; Component Thickness: 77 mm; Material Properties - Lucht frame_wit, ThermalConductivity: 0.15; Lucht frame_wit, SpecificHeatCapacity: 1008 J/kg/K; Lucht frame_wit, MassDensity: 1.2 kg/m3; Lucht frame_wit, Embodied Energy: 0 (MJ/kg); Lucht frame_wit, Embodied Carbon: 0 (kgCO₂/kg); Lucht frame_wit, Name: Lucht frame_wit; Lucht frame_wit, Participates in Collision Detection: yes
374 x _Dichte arcering | Begane grond | _Dichte arcering | 0.0181823 |  |  |  | 0.0000139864 | 0.0000139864 | Material Properties - _Dichte arcering, ThermalConductivity: 0.5; _Dichte arcering, SpecificHeatCapacity: 840 J/kg/K; _Dichte arcering, MassDensity: 1300 kg/m3; _Dichte arcering, Embodied Energy: 0.75 (MJ/kg); _Dichte arcering, Embodied Carbon: 0.1 (kgCO₂/kg); _Dichte arcering, Name: _Dichte arcering; _Dichte arcering, Participates in Collision Detection: yes
374 x  | Begane grond |  |  |  |  |  | 0.0000434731 | 0.0000434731
Isolatie - Steenwol hard | 1e verdieping | Isolatie - Steenwol hard | 99.7754 | 924.998 | 131 | 0.121175 | 0.623596 | 0.62361 | Component Quantities - Projected Component Area (Net): 4.76038 m2; Projected Component Area (Gross): 4.76038 m2; Component Thickness: 131 mm; Material Properties - Isolatie - Steenwol hard, ThermalConductivity: 0.043; Isolatie - Steenwol hard, SpecificHeatCapacity: 840 J/kg/K; Isolatie - Steenwol hard, MassDensity: 160 kg/m3; Isolatie - Steenwol hard, Embodied Energy: 16.8 (MJ/kg); Isolatie - Steenwol hard, Embodied Carbon: 1.05 (kgCO₂/kg); Isolatie - Steenwol hard, Name: Isolatie - Steenwol hard; Isolatie - Steenwol hard, Participates in Collision Detection: yes
Membraan - waterdicht | 1e verdieping | Membraan - waterdicht | 24.3558 | 924.998 | 5 | 0.00462499 | 0.023196 | 0.023196 | Component Quantities - Projected Component Area (Net): 4.63921 m2; Projected Component Area (Gross): 4.63921 m2; Component Thickness: 5 mm; Material Properties - Membraan - waterdicht, ThermalConductivity: 0.2; Membraan - waterdicht, SpecificHeatCapacity: 1840 J/kg/K; Membraan - waterdicht, MassDensity: 1050 kg/m3; Membraan - waterdicht, Embodied Energy: 51 (MJ/kg); Membraan - waterdicht, Embodied Carbon: 0.38 (kgCO₂/kg); Membraan - waterdicht, Name: Membraan - waterdicht; Membraan - waterdicht, Participates in Collision Detection: yes
Cement - Dekvloer/ chape | 1e verdieping | Cement - Dekvloer/ chape | 168716 |  |  |  | 88.798 | 89.4774 | Component Quantities - Projected Component Area (Net): 1775.96 m2; Projected Component Area (Gross): 1789.55 m2; Component Thickness: 50 mm; Material Properties - Cement - Dekvloer/ chape, ThermalConductivity: 0.93; Cement - Dekvloer/ chape, SpecificHeatCapacity: 840 J/kg/K; Cement - Dekvloer/ chape, MassDensity: 1900 kg/m3; Cement - Dekvloer/ chape, Embodied Energy: 0.97 (MJ/kg); Cement - Dekvloer/ chape, Embodied Carbon: 0.146 (kgCO₂/kg); Cement - Dekvloer/ chape, Name: Cement - Dekvloer/ chape; Cement - Dekvloer/ chape, Participates in Collision Detection: yes
Beton gewapend prefab | 1e verdieping | Beton gewapend prefab | 852461 |  |  |  | 355.192 | 357.909 | Component Quantities - Projected Component Area (Net): 1775.96 m2; Projected Component Area (Gross): 1789.55 m2; Component Thickness: 200 mm; Material Properties - Beton gewapend prefab, ThermalConductivity: 2.5; Beton gewapend prefab, SpecificHeatCapacity: 1000 J/kg/K; Beton gewapend prefab, MassDensity: 2400 kg/m3; Beton gewapend prefab, Embodied Energy: 2.33 (MJ/kg); Beton gewapend prefab, Embodied Carbon: 0.242 (kgCO₂/kg); Beton gewapend prefab, Name: Beton gewapend prefab; Beton gewapend prefab, Participates in Collision Detection: yes
Membraan - dampdicht | 1e verdieping | Membraan - dampdicht | 589.542 |  |  |  | 0.647848 | 0.647848 | Component Quantities - Projected Component Area (Net): 129.57 m2; Projected Component Area (Gross): 129.57 m2; Component Thickness: 5 mm; Material Properties - Membraan - dampdicht, ThermalConductivity: 0.22; Membraan - dampdicht, SpecificHeatCapacity: 1800 J/kg/K; Membraan - dampdicht, MassDensity: 910 kg/m3; Membraan - dampdicht, Embodied Energy: 99.2 (MJ/kg); Membraan - dampdicht, Embodied Carbon: 3.43 (kgCO₂/kg); Membraan - dampdicht, Name: Membraan - dampdicht; Membraan - dampdicht, Participates in Collision Detection: yes
Isolatie - Steenwol zacht | 1e verdieping | Isolatie - Steenwol zacht | 886.256 |  |  |  | 19.6946 | 19.6946 | Component Quantities - Projected Component Area (Net): 129.57 m2; Projected Component Area (Gross): 129.57 m2; Component Thickness: 152 mm; Material Properties - Isolatie - Steenwol zacht, ThermalConductivity: 0.035; Isolatie - Steenwol zacht, SpecificHeatCapacity: 840 J/kg/K; Isolatie - Steenwol zacht, MassDensity: 45 kg/m3; Isolatie - Steenwol zacht, Embodied Energy: 16.8 (MJ/kg); Isolatie - Steenwol zacht, Embodied Carbon: 1.05 (kgCO₂/kg); Isolatie - Steenwol zacht, Name: Isolatie - Steenwol zacht; Isolatie - Steenwol zacht, Participates in Collision Detection: yes
Metaal - Staal C | 1e verdieping | Metaal - Staal C | 6180.47 |  |  |  | 0.777418 | 0.777418 | Component Quantities - Projected Component Area (Net): 129.57 m2; Projected Component Area (Gross): 129.57 m2; Component Thickness: 6 mm; Material Properties - Metaal - Staal C, ThermalConductivity: 52; Metaal - Staal C, SpecificHeatCapacity: 530 J/kg/K; Metaal - Staal C, MassDensity: 7950 kg/m3; Metaal - Staal C, Embodied Energy: 25 (MJ/kg); Metaal - Staal C, Embodied Carbon: 1.91 (kgCO₂/kg); Metaal - Staal C, Name: Metaal - Staal C; Metaal - Staal C, Participates in Collision Detection: yes
Beton gewapend C vloer | 1e verdieping | Beton gewapend C vloer | 51672.5 |  |  |  | 21.5302 | 21.5302 | Component Quantities - Projected Component Area (Net): 430.604 m2; Projected Component Area (Gross): 430.604 m2; Component Thickness: 50 mm; Material Properties - Beton gewapend C vloer, ThermalConductivity: 2.5; Beton gewapend C vloer, SpecificHeatCapacity: 1000 J/kg/K; Beton gewapend C vloer, MassDensity: 2400 kg/m3; Beton gewapend C vloer, Embodied Energy: 2.33 (MJ/kg); Beton gewapend C vloer, Embodied Carbon: 0.242 (kgCO₂/kg); Beton gewapend C vloer, Name: Beton gewapend C vloer; Beton gewapend C vloer, Participates in Collision Detection: yes
Beton gewapend prefab vloer | 1e verdieping | Beton gewapend prefab vloer | 155017 |  |  |  | 64.5906 | 64.5906 | Component Quantities - Projected Component Area (Net): 430.604 m2; Projected Component Area (Gross): 430.604 m2; Component Thickness: 150 mm; Material Properties - Beton gewapend prefab vloer, ThermalConductivity: 2.5; Beton gewapend prefab vloer, SpecificHeatCapacity: 1000 J/kg/K; Beton gewapend prefab vloer, MassDensity: 2400 kg/m3; Beton gewapend prefab vloer, Embodied Energy: 2.33 (MJ/kg); Beton gewapend prefab vloer, Embodied Carbon: 0.242 (kgCO₂/kg); Beton gewapend prefab vloer, Name: Beton gewapend prefab vloer; Beton gewapend prefab vloer, Participates in Collision Detection: yes
Hout - gevel opengewerkt | 1e verdieping | Hout - gevel opengewerkt | 704.365 | 3215 | 18 | 0.05787 | 1.28066 | 1.28066 | Component Quantities - Projected Component Area (Net): 71.148 m2; Projected Component Area (Gross): 71.148 m2; Component Thickness: 18 mm; Material Properties - Hout - gevel opengewerkt, ThermalConductivity: 0.14; Hout - gevel opengewerkt, SpecificHeatCapacity: 1880 J/kg/K; Hout - gevel opengewerkt, MassDensity: 550 kg/m3; Hout - gevel opengewerkt, Embodied Energy: 7.4 (MJ/kg); Hout - gevel opengewerkt, Embodied Carbon: 0.19 (kgCO₂/kg); Hout - gevel opengewerkt, Name: Hout - gevel opengewerkt; Hout - gevel opengewerkt, Participates in Collision Detection: yes
Membraan - dampopen | 1e verdieping | Membraan - dampopen | 127.874 | 3215 | 2 | 0.00643 | 0.140521 | 0.140521 | Component Quantities - Projected Component Area (Net): 70.2607 m2; Projected Component Area (Gross): 70.2607 m2; Component Thickness: 2 mm; Material Properties - Membraan - dampopen, ThermalConductivity: 0.22; Membraan - dampopen, SpecificHeatCapacity: 1800 J/kg/K; Membraan - dampopen, MassDensity: 910 kg/m3; Membraan - dampopen, Embodied Energy: 99.2 (MJ/kg); Membraan - dampopen, Embodied Carbon: 3.43 (kgCO₂/kg); Membraan - dampopen, Name: Membraan - dampopen; Membraan - dampopen, Participates in Collision Detection: yes
Isolatie - Steenwol hard | 1e verdieping | Isolatie - Steenwol hard | 2202.97 | 3215 | 196 | 0.63014 | 13.7686 | 13.7686 | Component Quantities - Projected Component Area (Net): 70.2478 m2; Projected Component Area (Gross): 70.2478 m2; Component Thickness: 196 mm; Material Properties - Isolatie - Steenwol hard, ThermalConductivity: 0.043; Isolatie - Steenwol hard, SpecificHeatCapacity: 840 J/kg/K; Isolatie - Steenwol hard, MassDensity: 160 kg/m3; Isolatie - Steenwol hard, Embodied Energy: 16.8 (MJ/kg); Isolatie - Steenwol hard, Embodied Carbon: 1.05 (kgCO₂/kg); Isolatie - Steenwol hard, Name: Isolatie - Steenwol hard; Isolatie - Steenwol hard, Participates in Collision Detection: yes
Metaal - Staal AFW | 1e verdieping | Metaal - Staal AFW | 2193.8 | 3215 | 4 | 0.01286 | 0.27595 | 0.27595 | Component Quantities - Projected Component Area (Net): 68.9875 m2; Projected Component Area (Gross): 68.9875 m2; Component Thickness: 4 mm; Material Properties - Metaal - Staal AFW, ThermalConductivity: 52; Metaal - Staal AFW, SpecificHeatCapacity: 530 J/kg/K; Metaal - Staal AFW, MassDensity: 7950 kg/m3; Metaal - Staal AFW, Embodied Energy: 25 (MJ/kg); Metaal - Staal AFW, Embodied Carbon: 1.91 (kgCO₂/kg); Metaal - Staal AFW, Name: Metaal - Staal AFW; Metaal - Staal AFW, Participates in Collision Detection: yes
Membraan - dampdicht | 1e verdieping | Membraan - dampdicht | 1215.09 |  |  |  | 1.33526 | 1.33526 | Component Quantities - Projected Component Area (Net): 267.053 m2; Projected Component Area (Gross): 267.053 m2; Component Thickness: 5 mm; Material Properties - Membraan - dampdicht, ThermalConductivity: 0.22; Membraan - dampdicht, SpecificHeatCapacity: 1800 J/kg/K; Membraan - dampdicht, MassDensity: 910 kg/m3; Membraan - dampdicht, Embodied Energy: 99.2 (MJ/kg); Membraan - dampdicht, Embodied Carbon: 3.43 (kgCO₂/kg); Membraan - dampdicht, Name: Membraan - dampdicht; Membraan - dampdicht, Participates in Collision Detection: yes
Isolatie - Steenwol zacht | 1e verdieping | Isolatie - Steenwol zacht | 1826.64 |  |  |  | 40.592 | 40.592 | Component Quantities - Projected Component Area (Net): 267.053 m2; Projected Component Area (Gross): 267.053 m2; Component Thickness: 152 mm; Material Properties - Isolatie - Steenwol zacht, ThermalConductivity: 0.035; Isolatie - Steenwol zacht, SpecificHeatCapacity: 840 J/kg/K; Isolatie - Steenwol zacht, MassDensity: 45 kg/m3; Isolatie - Steenwol zacht, Embodied Energy: 16.8 (MJ/kg); Isolatie - Steenwol zacht, Embodied Carbon: 1.05 (kgCO₂/kg); Isolatie - Steenwol zacht, Name: Isolatie - Steenwol zacht; Isolatie - Steenwol zacht, Participates in Collision Detection: yes
Metaal - Staal C | 1e verdieping | Metaal - Staal C | 12738.4 |  |  |  | 1.60232 | 1.60232 | Component Quantities - Projected Component Area (Net): 267.053 m2; Projected Component Area (Gross): 267.053 m2; Component Thickness: 6 mm; Material Properties - Metaal - Staal C, ThermalConductivity: 52; Metaal - Staal C, SpecificHeatCapacity: 530 J/kg/K; Metaal - Staal C, MassDensity: 7950 kg/m3; Metaal - Staal C, Embodied Energy: 25 (MJ/kg); Metaal - Staal C, Embodied Carbon: 1.91 (kgCO₂/kg); Metaal - Staal C, Name: Metaal - Staal C; Metaal - Staal C, Participates in Collision Detection: yes
2 x Hout - gevel opengewerkt | 1e verdieping | Hout - gevel opengewerkt | 417.336 | 3215 | 18 | 0.05787 | 0.758792 | 0.758792 | Component Quantities - Projected Component Area (Net): 42.1551 m2; Projected Component Area (Gross): 42.1551 m2; Component Thickness: 18 mm; Material Properties - Hout - gevel opengewerkt, ThermalConductivity: 0.14; Hout - gevel opengewerkt, SpecificHeatCapacity: 1880 J/kg/K; Hout - gevel opengewerkt, MassDensity: 550 kg/m3; Hout - gevel opengewerkt, Embodied Energy: 7.4 (MJ/kg); Hout - gevel opengewerkt, Embodied Carbon: 0.19 (kgCO₂/kg); Hout - gevel opengewerkt, Name: Hout - gevel opengewerkt; Hout - gevel opengewerkt, Participates in Collision Detection: yes
2 x Membraan - dampopen | 1e verdieping | Membraan - dampopen | 75.201 | 3215 | 2 | 0.00643 | 0.0826384 | 0.0826384 | Component Quantities - Projected Component Area (Net): 41.3192 m2; Projected Component Area (Gross): 41.3192 m2; Component Thickness: 2 mm; Material Properties - Membraan - dampopen, ThermalConductivity: 0.22; Membraan - dampopen, SpecificHeatCapacity: 1800 J/kg/K; Membraan - dampopen, MassDensity: 910 kg/m3; Membraan - dampopen, Embodied Energy: 99.2 (MJ/kg); Membraan - dampopen, Embodied Carbon: 3.43 (kgCO₂/kg); Membraan - dampopen, Name: Membraan - dampopen; Membraan - dampopen, Participates in Collision Detection: yes
2 x Isolatie - Steenwol hard | 1e verdieping | Isolatie - Steenwol hard | 1275.81 | 3215 | 196 | 0.63014 | 7.9738 | 7.9738 | Component Quantities - Projected Component Area (Net): 40.6826 m2; Projected Component Area (Gross): 40.6826 m2; Component Thickness: 196 mm; Material Properties - Isolatie - Steenwol hard, ThermalConductivity: 0.043; Isolatie - Steenwol hard, SpecificHeatCapacity: 840 J/kg/K; Isolatie - Steenwol hard, MassDensity: 160 kg/m3; Isolatie - Steenwol hard, Embodied Energy: 16.8 (MJ/kg); Isolatie - Steenwol hard, Embodied Carbon: 1.05 (kgCO₂/kg); Isolatie - Steenwol hard, Name: Isolatie - Steenwol hard; Isolatie - Steenwol hard, Participates in Collision Detection: yes
2 x Metaal - Staal AFW | 1e verdieping | Metaal - Staal AFW | 1273.26 | 3215 | 4 | 0.01286 | 0.160159 | 0.160159 | Component Quantities - Projected Component Area (Net): 40.0396 m2; Projected Component Area (Gross): 40.0396 m2; Component Thickness: 4 mm; Material Properties - Metaal - Staal AFW, ThermalConductivity: 52; Metaal - Staal AFW, SpecificHeatCapacity: 530 J/kg/K; Metaal - Staal AFW, MassDensity: 7950 kg/m3; Metaal - Staal AFW, Embodied Energy: 25 (MJ/kg); Metaal - Staal AFW, Embodied Carbon: 1.91 (kgCO₂/kg); Metaal - Staal AFW, Name: Metaal - Staal AFW; Metaal - Staal AFW, Participates in Collision Detection: yes
Beton gewapend C vloer | 1e verdieping | Beton gewapend C vloer | 5998.57 |  |  |  | 2.4994 | 2.4994 | Component Quantities - Projected Component Area (Net): 49.9881 m2; Projected Component Area (Gross): 49.9881 m2; Component Thickness: 50 mm; Material Properties - Beton gewapend C vloer, ThermalConductivity: 2.5; Beton gewapend C vloer, SpecificHeatCapacity: 1000 J/kg/K; Beton gewapend C vloer, MassDensity: 2400 kg/m3; Beton gewapend C vloer, Embodied Energy: 2.33 (MJ/kg); Beton gewapend C vloer, Embodied Carbon: 0.242 (kgCO₂/kg); Beton gewapend C vloer, Name: Beton gewapend C vloer; Beton gewapend C vloer, Participates in Collision Detection: yes
Beton gewapend prefab vloer | 1e verdieping | Beton gewapend prefab vloer | 17995.7 |  |  |  | 7.49821 | 7.49821 | Component Quantities - Projected Component Area (Net): 49.9881 m2; Projected Component Area (Gross): 49.9881 m2; Component Thickness: 150 mm; Material Properties - Beton gewapend prefab vloer, ThermalConductivity: 2.5; Beton gewapend prefab vloer, SpecificHeatCapacity: 1000 J/kg/K; Beton gewapend prefab vloer, MassDensity: 2400 kg/m3; Beton gewapend prefab vloer, Embodied Energy: 2.33 (MJ/kg); Beton gewapend prefab vloer, Embodied Carbon: 0.242 (kgCO₂/kg); Beton gewapend prefab vloer, Name: Beton gewapend prefab vloer; Beton gewapend prefab vloer, Participates in Collision Detection: yes
Isolatie - Steenwol hard | 1e verdieping | Isolatie - Steenwol hard | 161.881 | 1019 | 131 | 0.133489 | 1.01176 | 1.01176 | Component Quantities - Projected Component Area (Net): 7.72335 m2; Projected Component Area (Gross): 7.72335 m2; Component Thickness: 131 mm; Material Properties - Isolatie - Steenwol hard, ThermalConductivity: 0.043; Isolatie - Steenwol hard, SpecificHeatCapacity: 840 J/kg/K; Isolatie - Steenwol hard, MassDensity: 160 kg/m3; Isolatie - Steenwol hard, Embodied Energy: 16.8 (MJ/kg); Isolatie - Steenwol hard, Embodied Carbon: 1.05 (kgCO₂/kg); Isolatie - Steenwol hard, Name: Isolatie - Steenwol hard; Isolatie - Steenwol hard, Participates in Collision Detection: yes
Membraan - waterdicht | 1e verdieping | Membraan - waterdicht | 40.5476 | 1019 | 5 | 0.00509499 | 0.0386167 | 0.0386167 | Component Quantities - Projected Component Area (Net): 7.72335 m2; Projected Component Area (Gross): 7.72335 m2; Component Thickness: 5 mm; Material Properties - Membraan - waterdicht, ThermalConductivity: 0.2; Membraan - waterdicht, SpecificHeatCapacity: 1840 J/kg/K; Membraan - waterdicht, MassDensity: 1050 kg/m3; Membraan - waterdicht, Embodied Energy: 51 (MJ/kg); Membraan - waterdicht, Embodied Carbon: 0.38 (kgCO₂/kg); Membraan - waterdicht, Name: Membraan - waterdicht; Membraan - waterdicht, Participates in Collision Detection: yes
Isolatie - Steenwol hard | 1e verdieping | Isolatie - Steenwol hard | 152.254 | 924.998 | 131 | 0.121175 | 0.951586 | 0.951586 | Component Quantities - Projected Component Area (Net): 7.26401 m2; Projected Component Area (Gross): 7.26401 m2; Component Thickness: 131 mm; Material Properties - Isolatie - Steenwol hard, ThermalConductivity: 0.043; Isolatie - Steenwol hard, SpecificHeatCapacity: 840 J/kg/K; Isolatie - Steenwol hard, MassDensity: 160 kg/m3; Isolatie - Steenwol hard, Embodied Energy: 16.8 (MJ/kg); Isolatie - Steenwol hard, Embodied Carbon: 1.05 (kgCO₂/kg); Isolatie - Steenwol hard, Name: Isolatie - Steenwol hard; Isolatie - Steenwol hard, Participates in Collision Detection: yes
Membraan - waterdicht | 1e verdieping | Membraan - waterdicht | 38.1118 | 924.998 | 5 | 0.00462499 | 0.0362969 | 0.0362969 | Component Quantities - Projected Component Area (Net): 7.25939 m2; Projected Component Area (Gross): 7.25939 m2; Component Thickness: 5 mm; Material Properties - Membraan - waterdicht, ThermalConductivity: 0.2; Membraan - waterdicht, SpecificHeatCapacity: 1840 J/kg/K; Membraan - waterdicht, MassDensity: 1050 kg/m3; Membraan - waterdicht, Embodied Energy: 51 (MJ/kg); Membraan - waterdicht, Embodied Carbon: 0.38 (kgCO₂/kg); Membraan - waterdicht, Name: Membraan - waterdicht; Membraan - waterdicht, Participates in Collision Detection: yes
Metaal - Staal AFW | 1e verdieping | Metaal - Staal AFW | 2192.99 | 3215 | 4 | 0.01286 | 0.275847 | 0.275847 | Component Quantities - Projected Component Area (Net): 68.9618 m2; Projected Component Area (Gross): 68.9618 m2; Component Thickness: 4 mm; Material Properties - Metaal - Staal AFW, ThermalConductivity: 52; Metaal - Staal AFW, SpecificHeatCapacity: 530 J/kg/K; Metaal - Staal AFW, MassDensity: 7950 kg/m3; Metaal - Staal AFW, Embodied Energy: 25 (MJ/kg); Metaal - Staal AFW, Embodied Carbon: 1.91 (kgCO₂/kg); Metaal - Staal AFW, Name: Metaal - Staal AFW; Metaal - Staal AFW, Participates in Collision Detection: yes
Isolatie - Steenwol hard | 1e verdieping | Isolatie - Steenwol hard | 2163.45 | 3215 | 196 | 0.63014 | 13.5216 | 13.5216 | Component Quantities - Projected Component Area (Net): 68.9875 m2; Projected Component Area (Gross): 68.9875 m2; Component Thickness: 196 mm; Material Properties - Isolatie - Steenwol hard, ThermalConductivity: 0.043; Isolatie - Steenwol hard, SpecificHeatCapacity: 840 J/kg/K; Isolatie - Steenwol hard, MassDensity: 160 kg/m3; Isolatie - Steenwol hard, Embodied Energy: 16.8 (MJ/kg); Isolatie - Steenwol hard, Embodied Carbon: 1.05 (kgCO₂/kg); Isolatie - Steenwol hard, Name: Isolatie - Steenwol hard; Isolatie - Steenwol hard, Participates in Collision Detection: yes
Membraan - dampopen | 1e verdieping | Membraan - dampopen | 127.851 | 3215 | 2 | 0.00643 | 0.140496 | 0.140496 | Component Quantities - Projected Component Area (Net): 70.2478 m2; Projected Component Area (Gross): 70.2478 m2; Component Thickness: 2 mm; Material Properties - Membraan - dampopen, ThermalConductivity: 0.22; Membraan - dampopen, SpecificHeatCapacity: 1800 J/kg/K; Membraan - dampopen, MassDensity: 910 kg/m3; Membraan - dampopen, Embodied Energy: 99.2 (MJ/kg); Membraan - dampopen, Embodied Carbon: 3.43 (kgCO₂/kg); Membraan - dampopen, Name: Membraan - dampopen; Membraan - dampopen, Participates in Collision Detection: yes
Hout - gevel opengewerkt | 1e verdieping | Hout - gevel opengewerkt | 703.22 | 3215 | 18 | 0.05787 | 1.27858 | 1.27858 | Component Quantities - Projected Component Area (Net): 71.0323 m2; Projected Component Area (Gross): 71.0323 m2; Component Thickness: 18 mm; Material Properties - Hout - gevel opengewerkt, ThermalConductivity: 0.14; Hout - gevel opengewerkt, SpecificHeatCapacity: 1880 J/kg/K; Hout - gevel opengewerkt, MassDensity: 550 kg/m3; Hout - gevel opengewerkt, Embodied Energy: 7.4 (MJ/kg); Hout - gevel opengewerkt, Embodied Carbon: 0.19 (kgCO₂/kg); Hout - gevel opengewerkt, Name: Hout - gevel opengewerkt; Hout - gevel opengewerkt, Participates in Collision Detection: yes
Hout - Multiplex | 1e verdieping | Hout - Multiplex | 202.015 | 15 | 586 | 0.00879 | 0.288593 | 0.288593 | Material Properties - Hout - Multiplex, ThermalConductivity: 0.17; Hout - Multiplex, SpecificHeatCapacity: 1600 J/kg/K; Hout - Multiplex, MassDensity: 700 kg/m3; Hout - Multiplex, Embodied Energy: 15 (MJ/kg); Hout - Multiplex, Embodied Carbon: 0.77 (kgCO₂/kg); Hout - Multiplex, Name: Hout - Multiplex; Hout - Multiplex, Participates in Collision Detection: yes
Membraan - waterdicht | 1e verdieping | Membraan - waterdicht | 101.848 |  |  | 0.002955 | 0.0969983 | 0.0969983 | Material Properties - Membraan - waterdicht, ThermalConductivity: 0.2; Membraan - waterdicht, SpecificHeatCapacity: 1840 J/kg/K; Membraan - waterdicht, MassDensity: 1050 kg/m3; Membraan - waterdicht, Embodied Energy: 51 (MJ/kg); Membraan - waterdicht, Embodied Carbon: 0.38 (kgCO₂/kg); Membraan - waterdicht, Name: Membraan - waterdicht; Membraan - waterdicht, Participates in Collision Detection: yes
Membraan - waterdicht | 1e verdieping | Membraan - waterdicht | 65.5749 | 390 | 5 | 0.00195 | 0.0624523 | 0.0624523 | Material Properties - Membraan - waterdicht, ThermalConductivity: 0.2; Membraan - waterdicht, SpecificHeatCapacity: 1840 J/kg/K; Membraan - waterdicht, MassDensity: 1050 kg/m3; Membraan - waterdicht, Embodied Energy: 51 (MJ/kg); Membraan - waterdicht, Embodied Carbon: 0.38 (kgCO₂/kg); Membraan - waterdicht, Name: Membraan - waterdicht; Membraan - waterdicht, Participates in Collision Detection: yes
Steen - Cellenbeton | 1e verdieping | Steen - Cellenbeton | 1743.27 | 515 | 150 | 0.07725 | 2.49038 | 2.49038 | Material Properties - Steen - Cellenbeton, ThermalConductivity: 0.23; Steen - Cellenbeton, SpecificHeatCapacity: 840 J/kg/K; Steen - Cellenbeton, MassDensity: 700 kg/m3; Steen - Cellenbeton, Embodied Energy: 0.75 (MJ/kg); Steen - Cellenbeton, Embodied Carbon: 0.1 (kgCO₂/kg); Steen - Cellenbeton, Name: Steen - Cellenbeton; Steen - Cellenbeton, Participates in Collision Detection: yes
Metaal - kleur buitenkozijnen | 1e verdieping | Metaal - kleur buitenkozijnen | 26.0966 |  |  | 0.000277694 | 0.00932022 | 0.00932022 | Material Properties - Metaal - kleur buitenkozijnen, ThermalConductivity: 160; Metaal - kleur buitenkozijnen, SpecificHeatCapacity: 880 J/kg/K; Metaal - kleur buitenkozijnen, MassDensity: 2800 kg/m3; Metaal - kleur buitenkozijnen, Embodied Energy: 155 (MJ/kg); Metaal - kleur buitenkozijnen, Embodied Carbon: 9.16 (kgCO₂/kg); Metaal - kleur buitenkozijnen, Name: Metaal - kleur buitenkozijnen; Metaal - kleur buitenkozijnen, Participates in Collision Detection: yes
Hout - Multiplex | 1e verdieping | Hout - Multiplex | 209.274 | 15 | 1036 | 0.01554 | 0.298962 | 0.298962 | Material Properties - Hout - Multiplex, ThermalConductivity: 0.17; Hout - Multiplex, SpecificHeatCapacity: 1600 J/kg/K; Hout - Multiplex, MassDensity: 700 kg/m3; Hout - Multiplex, Embodied Energy: 15 (MJ/kg); Hout - Multiplex, Embodied Carbon: 0.77 (kgCO₂/kg); Hout - Multiplex, Name: Hout - Multiplex; Hout - Multiplex, Participates in Collision Detection: yes
Membraan - waterdicht | 1e verdieping | Membraan - waterdicht | 105.134 |  |  | 0.00520501 | 0.100128 | 0.100128 | Material Properties - Membraan - waterdicht, ThermalConductivity: 0.2; Membraan - waterdicht, SpecificHeatCapacity: 1840 J/kg/K; Membraan - waterdicht, MassDensity: 1050 kg/m3; Membraan - waterdicht, Embodied Energy: 51 (MJ/kg); Membraan - waterdicht, Embodied Carbon: 0.38 (kgCO₂/kg); Membraan - waterdicht, Name: Membraan - waterdicht; Membraan - waterdicht, Participates in Collision Detection: yes
Membraan - waterdicht | 1e verdieping | Membraan - waterdicht | 38.7724 | 390 | 5 | 0.00195 | 0.0369261 | 0.0369261 | Material Properties - Membraan - waterdicht, ThermalConductivity: 0.2; Membraan - waterdicht, SpecificHeatCapacity: 1840 J/kg/K; Membraan - waterdicht, MassDensity: 1050 kg/m3; Membraan - waterdicht, Embodied Energy: 51 (MJ/kg); Membraan - waterdicht, Embodied Carbon: 0.38 (kgCO₂/kg); Membraan - waterdicht, Name: Membraan - waterdicht; Membraan - waterdicht, Participates in Collision Detection: yes
Steen - Cellenbeton | 1e verdieping | Steen - Cellenbeton | 1026.42 | 515 | 150 | 0.07725 | 1.46631 | 1.46631 | Material Properties - Steen - Cellenbeton, ThermalConductivity: 0.23; Steen - Cellenbeton, SpecificHeatCapacity: 840 J/kg/K; Steen - Cellenbeton, MassDensity: 700 kg/m3; Steen - Cellenbeton, Embodied Energy: 0.75 (MJ/kg); Steen - Cellenbeton, Embodied Carbon: 0.1 (kgCO₂/kg); Steen - Cellenbeton, Name: Steen - Cellenbeton; Steen - Cellenbeton, Participates in Collision Detection: yes
Metaal - kleur buitenkozijnen | 1e verdieping | Metaal - kleur buitenkozijnen | 15.1598 |  |  | 0.000277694 | 0.0054142 | 0.0054142 | Material Properties - Metaal - kleur buitenkozijnen, ThermalConductivity: 160; Metaal - kleur buitenkozijnen, SpecificHeatCapacity: 880 J/kg/K; Metaal - kleur buitenkozijnen, MassDensity: 2800 kg/m3; Metaal - kleur buitenkozijnen, Embodied Energy: 155 (MJ/kg); Metaal - kleur buitenkozijnen, Embodied Carbon: 9.16 (kgCO₂/kg); Metaal - kleur buitenkozijnen, Name: Metaal - kleur buitenkozijnen; Metaal - kleur buitenkozijnen, Participates in Collision Detection: yes
Hout - Multiplex | 1e verdieping | Hout - Multiplex | 142.466 | 15 | 586 | 0.00879 | 0.203523 | 0.203523 | Material Properties - Hout - Multiplex, ThermalConductivity: 0.17; Hout - Multiplex, SpecificHeatCapacity: 1600 J/kg/K; Hout - Multiplex, MassDensity: 700 kg/m3; Hout - Multiplex, Embodied Energy: 15 (MJ/kg); Hout - Multiplex, Embodied Carbon: 0.77 (kgCO₂/kg); Hout - Multiplex, Name: Hout - Multiplex; Hout - Multiplex, Participates in Collision Detection: yes
Membraan - waterdicht | 1e verdieping | Membraan - waterdicht | 71.8333 |  |  | 0.002955 | 0.0684127 | 0.0684127 | Material Properties - Membraan - waterdicht, ThermalConductivity: 0.2; Membraan - waterdicht, SpecificHeatCapacity: 1840 J/kg/K; Membraan - waterdicht, MassDensity: 1050 kg/m3; Membraan - waterdicht, Embodied Energy: 51 (MJ/kg); Membraan - waterdicht, Embodied Carbon: 0.38 (kgCO₂/kg); Membraan - waterdicht, Name: Membraan - waterdicht; Membraan - waterdicht, Participates in Collision Detection: yes
Membraan - waterdicht | 1e verdieping | Membraan - waterdicht | 46.8028 | 390 | 5 | 0.00195 | 0.0445741 | 0.0445741 | Material Properties - Membraan - waterdicht, ThermalConductivity: 0.2; Membraan - waterdicht, SpecificHeatCapacity: 1840 J/kg/K; Membraan - waterdicht, MassDensity: 1050 kg/m3; Membraan - waterdicht, Embodied Energy: 51 (MJ/kg); Membraan - waterdicht, Embodied Carbon: 0.38 (kgCO₂/kg); Membraan - waterdicht, Name: Membraan - waterdicht; Membraan - waterdicht, Participates in Collision Detection: yes
Steen - Cellenbeton | 1e verdieping | Steen - Cellenbeton | 1240.26 | 515 | 150 | 0.07725 | 1.7718 | 1.7718 | Material Properties - Steen - Cellenbeton, ThermalConductivity: 0.23; Steen - Cellenbeton, SpecificHeatCapacity: 840 J/kg/K; Steen - Cellenbeton, MassDensity: 700 kg/m3; Steen - Cellenbeton, Embodied Energy: 0.75 (MJ/kg); Steen - Cellenbeton, Embodied Carbon: 0.1 (kgCO₂/kg); Steen - Cellenbeton, Name: Steen - Cellenbeton; Steen - Cellenbeton, Participates in Collision Detection: yes
Metaal - kleur buitenkozijnen | 1e verdieping | Metaal - kleur buitenkozijnen | 18.1928 |  |  | 0.000277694 | 0.00649743 | 0.00649743 | Material Properties - Metaal - kleur buitenkozijnen, ThermalConductivity: 160; Metaal - kleur buitenkozijnen, SpecificHeatCapacity: 880 J/kg/K; Metaal - kleur buitenkozijnen, MassDensity: 2800 kg/m3; Metaal - kleur buitenkozijnen, Embodied Energy: 155 (MJ/kg); Metaal - kleur buitenkozijnen, Embodied Carbon: 9.16 (kgCO₂/kg); Metaal - kleur buitenkozijnen, Name: Metaal - kleur buitenkozijnen; Metaal - kleur buitenkozijnen, Participates in Collision Detection: yes
Hout - Multiplex | 1e verdieping | Hout - Multiplex | 142.325 | 15 | 586 | 0.00879 | 0.203321 | 0.203321 | Material Properties - Hout - Multiplex, ThermalConductivity: 0.17; Hout - Multiplex, SpecificHeatCapacity: 1600 J/kg/K; Hout - Multiplex, MassDensity: 700 kg/m3; Hout - Multiplex, Embodied Energy: 15 (MJ/kg); Hout - Multiplex, Embodied Carbon: 0.77 (kgCO₂/kg); Hout - Multiplex, Name: Hout - Multiplex; Hout - Multiplex, Participates in Collision Detection: yes
Membraan - waterdicht | 1e verdieping | Membraan - waterdicht | 71.7637 |  |  | 0.002955 | 0.0683463 | 0.0683463 | Material Properties - Membraan - waterdicht, ThermalConductivity: 0.2; Membraan - waterdicht, SpecificHeatCapacity: 1840 J/kg/K; Membraan - waterdicht, MassDensity: 1050 kg/m3; Membraan - waterdicht, Embodied Energy: 51 (MJ/kg); Membraan - waterdicht, Embodied Carbon: 0.38 (kgCO₂/kg); Membraan - waterdicht, Name: Membraan - waterdicht; Membraan - waterdicht, Participates in Collision Detection: yes
Membraan - waterdicht | 1e verdieping | Membraan - waterdicht | 46.8955 | 390 | 5 | 0.00195 | 0.0446623 | 0.0446623 | Material Properties - Membraan - waterdicht, ThermalConductivity: 0.2; Membraan - waterdicht, SpecificHeatCapacity: 1840 J/kg/K; Membraan - waterdicht, MassDensity: 1050 kg/m3; Membraan - waterdicht, Embodied Energy: 51 (MJ/kg); Membraan - waterdicht, Embodied Carbon: 0.38 (kgCO₂/kg); Membraan - waterdicht, Name: Membraan - waterdicht; Membraan - waterdicht, Participates in Collision Detection: yes
Steen - Cellenbeton | 1e verdieping | Steen - Cellenbeton | 1241.87 | 515 | 150 | 0.07725 | 1.7741 | 1.7741 | Material Properties - Steen - Cellenbeton, ThermalConductivity: 0.23; Steen - Cellenbeton, SpecificHeatCapacity: 840 J/kg/K; Steen - Cellenbeton, MassDensity: 700 kg/m3; Steen - Cellenbeton, Embodied Energy: 0.75 (MJ/kg); Steen - Cellenbeton, Embodied Carbon: 0.1 (kgCO₂/kg); Steen - Cellenbeton, Name: Steen - Cellenbeton; Steen - Cellenbeton, Participates in Collision Detection: yes
Metaal - kleur buitenkozijnen | 1e verdieping | Metaal - kleur buitenkozijnen | 18.1196 |  |  | 0.000277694 | 0.00647129 | 0.00647129 | Material Properties - Metaal - kleur buitenkozijnen, ThermalConductivity: 160; Metaal - kleur buitenkozijnen, SpecificHeatCapacity: 880 J/kg/K; Metaal - kleur buitenkozijnen, MassDensity: 2800 kg/m3; Metaal - kleur buitenkozijnen, Embodied Energy: 155 (MJ/kg); Metaal - kleur buitenkozijnen, Embodied Carbon: 9.16 (kgCO₂/kg); Metaal - kleur buitenkozijnen, Name: Metaal - kleur buitenkozijnen; Metaal - kleur buitenkozijnen, Participates in Collision Detection: yes
Hout - Multiplex | 1e verdieping | Hout - Multiplex | 3.05973 | 15 | 310.003 | 0.00465005 | 0.00437104 | 0.00437104 | Material Properties - Hout - Multiplex, ThermalConductivity: 0.17; Hout - Multiplex, SpecificHeatCapacity: 1600 J/kg/K; Hout - Multiplex, MassDensity: 700 kg/m3; Hout - Multiplex, Embodied Energy: 15 (MJ/kg); Hout - Multiplex, Embodied Carbon: 0.77 (kgCO₂/kg); Hout - Multiplex, Name: Hout - Multiplex; Hout - Multiplex, Participates in Collision Detection: yes
Membraan - waterdicht | 1e verdieping | Membraan - waterdicht | 1.55454 | 5 | 315.003 | 0.00157502 | 0.00148051 | 0.00148051 | Material Properties - Membraan - waterdicht, ThermalConductivity: 0.2; Membraan - waterdicht, SpecificHeatCapacity: 1840 J/kg/K; Membraan - waterdicht, MassDensity: 1050 kg/m3; Membraan - waterdicht, Embodied Energy: 51 (MJ/kg); Membraan - waterdicht, Embodied Carbon: 0.38 (kgCO₂/kg); Membraan - waterdicht, Name: Membraan - waterdicht; Membraan - waterdicht, Participates in Collision Detection: yes
2 x Membraan - waterdicht | 1e verdieping | Membraan - waterdicht | 1.20907 | 245 | 4.99999 | 0.001225 | 0.0011515 | 0.0011515 | Material Properties - Membraan - waterdicht, ThermalConductivity: 0.2; Membraan - waterdicht, SpecificHeatCapacity: 1840 J/kg/K; Membraan - waterdicht, MassDensity: 1050 kg/m3; Membraan - waterdicht, Embodied Energy: 51 (MJ/kg); Membraan - waterdicht, Embodied Carbon: 0.38 (kgCO₂/kg); Membraan - waterdicht, Name: Membraan - waterdicht; Membraan - waterdicht, Participates in Collision Detection: yes
Steen - Cellenbeton | 1e verdieping | Steen - Cellenbeton | 50.8304 | 515 | 150 | 0.07725 | 0.0726149 | 0.0726149 | Material Properties - Steen - Cellenbeton, ThermalConductivity: 0.23; Steen - Cellenbeton, SpecificHeatCapacity: 840 J/kg/K; Steen - Cellenbeton, MassDensity: 700 kg/m3; Steen - Cellenbeton, Embodied Energy: 0.75 (MJ/kg); Steen - Cellenbeton, Embodied Carbon: 0.1 (kgCO₂/kg); Steen - Cellenbeton, Name: Steen - Cellenbeton; Steen - Cellenbeton, Participates in Collision Detection: yes
Membraan - waterdicht | 1e verdieping | Membraan - waterdicht | 0.0246749 | 5 | 315.003 | 0.00157502 | 0.0000234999 | 0.0000234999 | Material Properties - Membraan - waterdicht, ThermalConductivity: 0.2; Membraan - waterdicht, SpecificHeatCapacity: 1840 J/kg/K; Membraan - waterdicht, MassDensity: 1050 kg/m3; Membraan - waterdicht, Embodied Energy: 51 (MJ/kg); Membraan - waterdicht, Embodied Carbon: 0.38 (kgCO₂/kg); Membraan - waterdicht, Name: Membraan - waterdicht; Membraan - waterdicht, Participates in Collision Detection: yes
Steen - Cellenbeton | 1e verdieping | Steen - Cellenbeton | 42.7192 | 515 | 150 | 0.07725 | 0.0610274 | 0.0610274 | Material Properties - Steen - Cellenbeton, ThermalConductivity: 0.23; Steen - Cellenbeton, SpecificHeatCapacity: 840 J/kg/K; Steen - Cellenbeton, MassDensity: 700 kg/m3; Steen - Cellenbeton, Embodied Energy: 0.75 (MJ/kg); Steen - Cellenbeton, Embodied Carbon: 0.1 (kgCO₂/kg); Steen - Cellenbeton, Name: Steen - Cellenbeton; Steen - Cellenbeton, Participates in Collision Detection: yes
Hout - Multiplex | 1e verdieping | Hout - Multiplex | 62.7506 | 15 | 436 | 0.00654 | 0.0896438 | 0.0896438 | Material Properties - Hout - Multiplex, ThermalConductivity: 0.17; Hout - Multiplex, SpecificHeatCapacity: 1600 J/kg/K; Hout - Multiplex, MassDensity: 700 kg/m3; Hout - Multiplex, Embodied Energy: 15 (MJ/kg); Hout - Multiplex, Embodied Carbon: 0.77 (kgCO₂/kg); Hout - Multiplex, Name: Hout - Multiplex; Hout - Multiplex, Participates in Collision Detection: yes
Membraan - waterdicht | 1e verdieping | Membraan - waterdicht | 31.7333 |  |  | 0.002205 | 0.0302222 | 0.0302222 | Material Properties - Membraan - waterdicht, ThermalConductivity: 0.2; Membraan - waterdicht, SpecificHeatCapacity: 1840 J/kg/K; Membraan - waterdicht, MassDensity: 1050 kg/m3; Membraan - waterdicht, Embodied Energy: 51 (MJ/kg); Membraan - waterdicht, Embodied Carbon: 0.38 (kgCO₂/kg); Membraan - waterdicht, Name: Membraan - waterdicht; Membraan - waterdicht, Participates in Collision Detection: yes
Membraan - waterdicht | 1e verdieping | Membraan - waterdicht | 27.9213 | 390 | 5 | 0.00195 | 0.0265918 | 0.0265918 | Material Properties - Membraan - waterdicht, ThermalConductivity: 0.2; Membraan - waterdicht, SpecificHeatCapacity: 1840 J/kg/K; Membraan - waterdicht, MassDensity: 1050 kg/m3; Membraan - waterdicht, Embodied Energy: 51 (MJ/kg); Membraan - waterdicht, Embodied Carbon: 0.38 (kgCO₂/kg); Membraan - waterdicht, Name: Membraan - waterdicht; Membraan - waterdicht, Participates in Collision Detection: yes
Steen - Cellenbeton | 1e verdieping | Steen - Cellenbeton | 738.413 | 515 | 150 | 0.07725 | 1.05488 | 1.05535 | Material Properties - Steen - Cellenbeton, ThermalConductivity: 0.23; Steen - Cellenbeton, SpecificHeatCapacity: 840 J/kg/K; Steen - Cellenbeton, MassDensity: 700 kg/m3; Steen - Cellenbeton, Embodied Energy: 0.75 (MJ/kg); Steen - Cellenbeton, Embodied Carbon: 0.1 (kgCO₂/kg); Steen - Cellenbeton, Name: Steen - Cellenbeton; Steen - Cellenbeton, Participates in Collision Detection: yes
Metaal - kleur buitenkozijnen | 1e verdieping | Metaal - kleur buitenkozijnen | 10.6888 |  |  | 0.000277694 | 0.00381743 | 0.00381743 | Material Properties - Metaal - kleur buitenkozijnen, ThermalConductivity: 160; Metaal - kleur buitenkozijnen, SpecificHeatCapacity: 880 J/kg/K; Metaal - kleur buitenkozijnen, MassDensity: 2800 kg/m3; Metaal - kleur buitenkozijnen, Embodied Energy: 155 (MJ/kg); Metaal - kleur buitenkozijnen, Embodied Carbon: 9.16 (kgCO₂/kg); Metaal - kleur buitenkozijnen, Name: Metaal - kleur buitenkozijnen; Metaal - kleur buitenkozijnen, Participates in Collision Detection: yes
Hout - Multiplex | 1e verdieping | Hout - Multiplex | 19.5032 | 15 | 436 | 0.00654 | 0.0278618 | 0.0278618 | Material Properties - Hout - Multiplex, ThermalConductivity: 0.17; Hout - Multiplex, SpecificHeatCapacity: 1600 J/kg/K; Hout - Multiplex, MassDensity: 700 kg/m3; Hout - Multiplex, Embodied Energy: 15 (MJ/kg); Hout - Multiplex, Embodied Carbon: 0.77 (kgCO₂/kg); Hout - Multiplex, Name: Hout - Multiplex; Hout - Multiplex, Participates in Collision Detection: yes
Membraan - waterdicht | 1e verdieping | Membraan - waterdicht | 9.84502 |  |  | 0.002205 | 0.00937621 | 0.00937621 | Material Properties - Membraan - waterdicht, ThermalConductivity: 0.2; Membraan - waterdicht, SpecificHeatCapacity: 1840 J/kg/K; Membraan - waterdicht, MassDensity: 1050 kg/m3; Membraan - waterdicht, Embodied Energy: 51 (MJ/kg); Membraan - waterdicht, Embodied Carbon: 0.38 (kgCO₂/kg); Membraan - waterdicht, Name: Membraan - waterdicht; Membraan - waterdicht, Participates in Collision Detection: yes
Membraan - waterdicht | 1e verdieping | Membraan - waterdicht | 7.28497 | 390 | 5 | 0.00195 | 0.00693807 | 0.00693807 | Material Properties - Membraan - waterdicht, ThermalConductivity: 0.2; Membraan - waterdicht, SpecificHeatCapacity: 1840 J/kg/K; Membraan - waterdicht, MassDensity: 1050 kg/m3; Membraan - waterdicht, Embodied Energy: 51 (MJ/kg); Membraan - waterdicht, Embodied Carbon: 0.38 (kgCO₂/kg); Membraan - waterdicht, Name: Membraan - waterdicht; Membraan - waterdicht, Participates in Collision Detection: yes
Steen - Cellenbeton | 1e verdieping | Steen - Cellenbeton | 205.744 | 515 | 150 | 0.07725 | 0.293921 | 0.293921 | Material Properties - Steen - Cellenbeton, ThermalConductivity: 0.23; Steen - Cellenbeton, SpecificHeatCapacity: 840 J/kg/K; Steen - Cellenbeton, MassDensity: 700 kg/m3; Steen - Cellenbeton, Embodied Energy: 0.75 (MJ/kg); Steen - Cellenbeton, Embodied Carbon: 0.1 (kgCO₂/kg); Steen - Cellenbeton, Name: Steen - Cellenbeton; Steen - Cellenbeton, Participates in Collision Detection: yes
Metaal - kleur buitenkozijnen | 1e verdieping | Metaal - kleur buitenkozijnen | 3.84995 |  |  | 0.000277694 | 0.00137498 | 0.00137498 | Material Properties - Metaal - kleur buitenkozijnen, ThermalConductivity: 160; Metaal - kleur buitenkozijnen, SpecificHeatCapacity: 880 J/kg/K; Metaal - kleur buitenkozijnen, MassDensity: 2800 kg/m3; Metaal - kleur buitenkozijnen, Embodied Energy: 155 (MJ/kg); Metaal - kleur buitenkozijnen, Embodied Carbon: 9.16 (kgCO₂/kg); Metaal - kleur buitenkozijnen, Name: Metaal - kleur buitenkozijnen; Metaal - kleur buitenkozijnen, Participates in Collision Detection: yes
Hout - Multiplex | 1e verdieping | Hout - Multiplex | 157.393 | 15 | 588.5 | 0.00882751 | 0.224847 | 0.224847 | Material Properties - Hout - Multiplex, ThermalConductivity: 0.17; Hout - Multiplex, SpecificHeatCapacity: 1600 J/kg/K; Hout - Multiplex, MassDensity: 700 kg/m3; Hout - Multiplex, Embodied Energy: 15 (MJ/kg); Hout - Multiplex, Embodied Carbon: 0.77 (kgCO₂/kg); Hout - Multiplex, Name: Hout - Multiplex; Hout - Multiplex, Participates in Collision Detection: yes
Membraan - waterdicht | 1e verdieping | Membraan - waterdicht | 78.693 | 5 | 588.5 | 0.0029425 | 0.0749457 | 0.0749457 | Material Properties - Membraan - waterdicht, ThermalConductivity: 0.2; Membraan - waterdicht, SpecificHeatCapacity: 1840 J/kg/K; Membraan - waterdicht, MassDensity: 1050 kg/m3; Membraan - waterdicht, Embodied Energy: 51 (MJ/kg); Membraan - waterdicht, Embodied Carbon: 0.38 (kgCO₂/kg); Membraan - waterdicht, Name: Membraan - waterdicht; Membraan - waterdicht, Participates in Collision Detection: yes
Metaal - kleur buitenkozijnen | 1e verdieping | Metaal - kleur buitenkozijnen | 19.776 |  |  | 0.000277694 | 0.00706287 | 0.00706287 | Material Properties - Metaal - kleur buitenkozijnen, ThermalConductivity: 160; Metaal - kleur buitenkozijnen, SpecificHeatCapacity: 880 J/kg/K; Metaal - kleur buitenkozijnen, MassDensity: 2800 kg/m3; Metaal - kleur buitenkozijnen, Embodied Energy: 155 (MJ/kg); Metaal - kleur buitenkozijnen, Embodied Carbon: 9.16 (kgCO₂/kg); Metaal - kleur buitenkozijnen, Name: Metaal - kleur buitenkozijnen; Metaal - kleur buitenkozijnen, Participates in Collision Detection: yes
Hout - Multiplex | 1e verdieping | Hout - Multiplex | 14.3118 | 15 | 436 | 0.00654 | 0.0204454 | 0.0204454 | Material Properties - Hout - Multiplex, ThermalConductivity: 0.17; Hout - Multiplex, SpecificHeatCapacity: 1600 J/kg/K; Hout - Multiplex, MassDensity: 700 kg/m3; Hout - Multiplex, Embodied Energy: 15 (MJ/kg); Hout - Multiplex, Embodied Carbon: 0.77 (kgCO₂/kg); Hout - Multiplex, Name: Hout - Multiplex; Hout - Multiplex, Participates in Collision Detection: yes
Membraan - waterdicht | 1e verdieping | Membraan - waterdicht | 7.24401 |  |  | 0.002205 | 0.00689906 | 0.00689906 | Material Properties - Membraan - waterdicht, ThermalConductivity: 0.2; Membraan - waterdicht, SpecificHeatCapacity: 1840 J/kg/K; Membraan - waterdicht, MassDensity: 1050 kg/m3; Membraan - waterdicht, Embodied Energy: 51 (MJ/kg); Membraan - waterdicht, Embodied Carbon: 0.38 (kgCO₂/kg); Membraan - waterdicht, Name: Membraan - waterdicht; Membraan - waterdicht, Participates in Collision Detection: yes
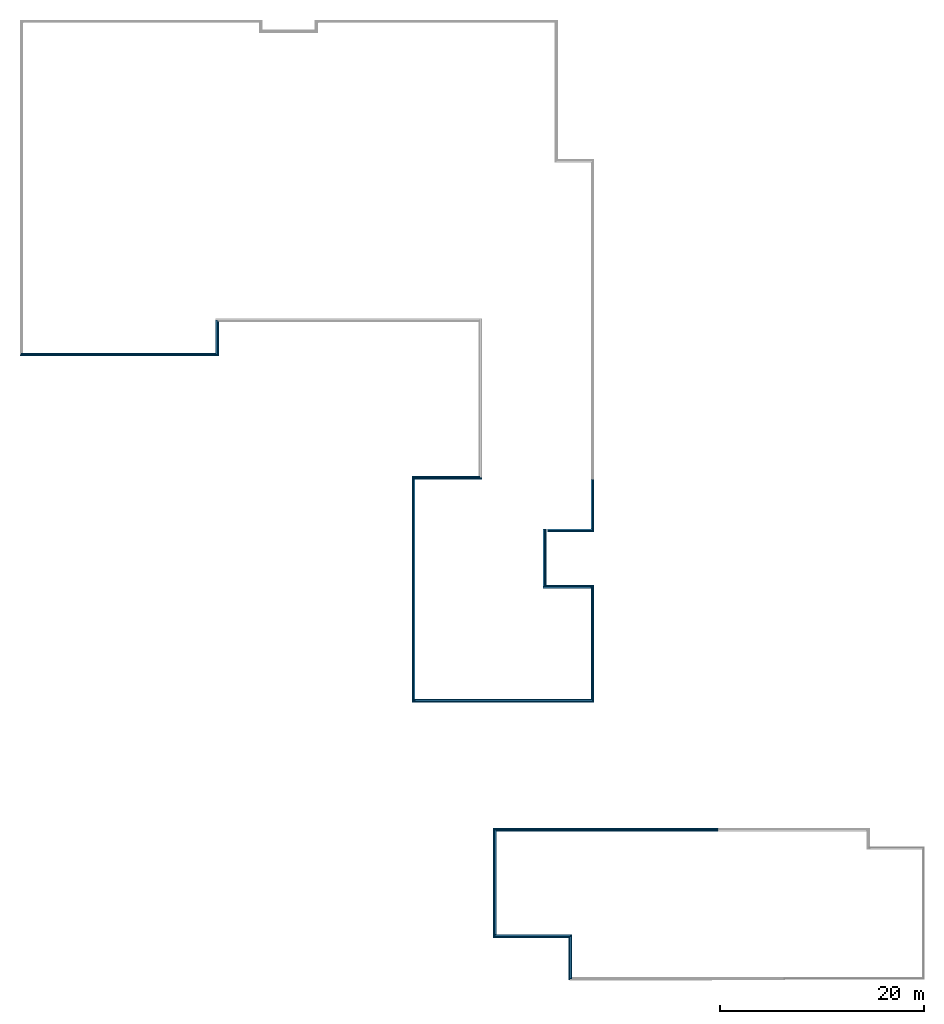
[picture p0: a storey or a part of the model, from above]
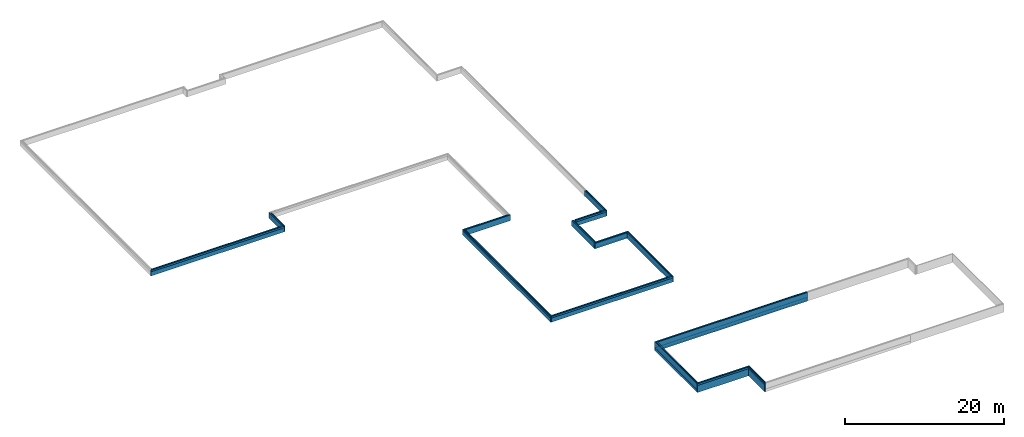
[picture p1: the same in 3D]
Properties of the parts of a building model (IFC2X3), part 11 of 19

# IfcBuildingElementPart (2070)
Name | In | Material | Mass (kg) | Rectangular Component Height (mm) | Rectangular Component Width (mm) | Component Cross Section Area (m2) | Component Volume (Net) (m3) | Component Volume (Gross) (m3)
Membraan - waterdicht | 1e verdieping | Membraan - waterdicht | 6.89496 | 390 | 5 | 0.00195 | 0.00656662 | 0.00656662 | Material Properties - Membraan - waterdicht, ThermalConductivity: 0.2; Membraan - waterdicht, SpecificHeatCapacity: 1840 J/kg/K; Membraan - waterdicht, MassDensity: 1050 kg/m3; Membraan - waterdicht, Embodied Energy: 51 (MJ/kg); Membraan - waterdicht, Embodied Carbon: 0.38 (kgCO₂/kg); Membraan - waterdicht, Name: Membraan - waterdicht; Membraan - waterdicht, Participates in Collision Detection: yes
Steen - Cellenbeton | 1e verdieping | Steen - Cellenbeton | 177.907 | 515 | 150 | 0.07725 | 0.254152 | 0.254152 | Material Properties - Steen - Cellenbeton, ThermalConductivity: 0.23; Steen - Cellenbeton, SpecificHeatCapacity: 840 J/kg/K; Steen - Cellenbeton, MassDensity: 700 kg/m3; Steen - Cellenbeton, Embodied Energy: 0.75 (MJ/kg); Steen - Cellenbeton, Embodied Carbon: 0.1 (kgCO₂/kg); Steen - Cellenbeton, Name: Steen - Cellenbeton; Steen - Cellenbeton, Participates in Collision Detection: yes
Metaal - kleur buitenkozijnen | 1e verdieping | Metaal - kleur buitenkozijnen | 2.23001 |  |  | 0.000277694 | 0.000796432 | 0.000796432 | Material Properties - Metaal - kleur buitenkozijnen, ThermalConductivity: 160; Metaal - kleur buitenkozijnen, SpecificHeatCapacity: 880 J/kg/K; Metaal - kleur buitenkozijnen, MassDensity: 2800 kg/m3; Metaal - kleur buitenkozijnen, Embodied Energy: 155 (MJ/kg); Metaal - kleur buitenkozijnen, Embodied Carbon: 9.16 (kgCO₂/kg); Metaal - kleur buitenkozijnen, Name: Metaal - kleur buitenkozijnen; Metaal - kleur buitenkozijnen, Participates in Collision Detection: yes
Hout - Multiplex | 1e verdieping | Hout - Multiplex | 3.86038 | 15 | 230 | 0.00345 | 0.00551483 | 0.00551483 | Material Properties - Hout - Multiplex, ThermalConductivity: 0.17; Hout - Multiplex, SpecificHeatCapacity: 1600 J/kg/K; Hout - Multiplex, MassDensity: 700 kg/m3; Hout - Multiplex, Embodied Energy: 15 (MJ/kg); Hout - Multiplex, Embodied Carbon: 0.77 (kgCO₂/kg); Hout - Multiplex, Name: Hout - Multiplex; Hout - Multiplex, Participates in Collision Detection: yes
Membraan - waterdicht | 1e verdieping | Membraan - waterdicht | 1.92874 | 5 | 230 | 0.00115 | 0.0018369 | 0.0018369 | Material Properties - Membraan - waterdicht, ThermalConductivity: 0.2; Membraan - waterdicht, SpecificHeatCapacity: 1840 J/kg/K; Membraan - waterdicht, MassDensity: 1050 kg/m3; Membraan - waterdicht, Embodied Energy: 51 (MJ/kg); Membraan - waterdicht, Embodied Carbon: 0.38 (kgCO₂/kg); Membraan - waterdicht, Name: Membraan - waterdicht; Membraan - waterdicht, Participates in Collision Detection: yes
Metaal - kleur buitenkozijnen | 1e verdieping | Metaal - kleur buitenkozijnen | 1.2277 |  |  | 0.000277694 | 0.000438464 | 0.000438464 | Material Properties - Metaal - kleur buitenkozijnen, ThermalConductivity: 160; Metaal - kleur buitenkozijnen, SpecificHeatCapacity: 880 J/kg/K; Metaal - kleur buitenkozijnen, MassDensity: 2800 kg/m3; Metaal - kleur buitenkozijnen, Embodied Energy: 155 (MJ/kg); Metaal - kleur buitenkozijnen, Embodied Carbon: 9.16 (kgCO₂/kg); Metaal - kleur buitenkozijnen, Name: Metaal - kleur buitenkozijnen; Metaal - kleur buitenkozijnen, Participates in Collision Detection: yes
Hout - Multiplex | 1e verdieping | Hout - Multiplex | 387.756 | 15 | 1936 | 0.02904 | 0.553938 | 0.553938 | Material Properties - Hout - Multiplex, ThermalConductivity: 0.17; Hout - Multiplex, SpecificHeatCapacity: 1600 J/kg/K; Hout - Multiplex, MassDensity: 700 kg/m3; Hout - Multiplex, Embodied Energy: 15 (MJ/kg); Hout - Multiplex, Embodied Carbon: 0.77 (kgCO₂/kg); Hout - Multiplex, Name: Hout - Multiplex; Hout - Multiplex, Participates in Collision Detection: yes
Membraan - waterdicht | 1e verdieping | Membraan - waterdicht | 194.377 |  |  | 0.00970496 | 0.185121 | 0.185121 | Material Properties - Membraan - waterdicht, ThermalConductivity: 0.2; Membraan - waterdicht, SpecificHeatCapacity: 1840 J/kg/K; Membraan - waterdicht, MassDensity: 1050 kg/m3; Membraan - waterdicht, Embodied Energy: 51 (MJ/kg); Membraan - waterdicht, Embodied Carbon: 0.38 (kgCO₂/kg); Membraan - waterdicht, Name: Membraan - waterdicht; Membraan - waterdicht, Participates in Collision Detection: yes
Membraan - waterdicht | 1e verdieping | Membraan - waterdicht | 38.9631 | 390 | 5 | 0.00195 | 0.0371077 | 0.0371077 | Material Properties - Membraan - waterdicht, ThermalConductivity: 0.2; Membraan - waterdicht, SpecificHeatCapacity: 1840 J/kg/K; Membraan - waterdicht, MassDensity: 1050 kg/m3; Membraan - waterdicht, Embodied Energy: 51 (MJ/kg); Membraan - waterdicht, Embodied Carbon: 0.38 (kgCO₂/kg); Membraan - waterdicht, Name: Membraan - waterdicht; Membraan - waterdicht, Participates in Collision Detection: yes
Steen - Cellenbeton | 1e verdieping | Steen - Cellenbeton | 1030.03 | 515 | 150 | 0.07725 | 1.47147 | 1.47147 | Material Properties - Steen - Cellenbeton, ThermalConductivity: 0.23; Steen - Cellenbeton, SpecificHeatCapacity: 840 J/kg/K; Steen - Cellenbeton, MassDensity: 700 kg/m3; Steen - Cellenbeton, Embodied Energy: 0.75 (MJ/kg); Steen - Cellenbeton, Embodied Carbon: 0.1 (kgCO₂/kg); Steen - Cellenbeton, Name: Steen - Cellenbeton; Steen - Cellenbeton, Participates in Collision Detection: yes
Metaal - kleur buitenkozijnen | 1e verdieping | Metaal - kleur buitenkozijnen | 15.1042 |  |  | 0.000277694 | 0.00539437 | 0.00539437 | Material Properties - Metaal - kleur buitenkozijnen, ThermalConductivity: 160; Metaal - kleur buitenkozijnen, SpecificHeatCapacity: 880 J/kg/K; Metaal - kleur buitenkozijnen, MassDensity: 2800 kg/m3; Metaal - kleur buitenkozijnen, Embodied Energy: 155 (MJ/kg); Metaal - kleur buitenkozijnen, Embodied Carbon: 9.16 (kgCO₂/kg); Metaal - kleur buitenkozijnen, Name: Metaal - kleur buitenkozijnen; Metaal - kleur buitenkozijnen, Participates in Collision Detection: yes
Hout - Multiplex | 1e verdieping | Hout - Multiplex | 143.845 | 15 | 1038 | 0.01557 | 0.205493 | 0.205493 | Material Properties - Hout - Multiplex, ThermalConductivity: 0.17; Hout - Multiplex, SpecificHeatCapacity: 1600 J/kg/K; Hout - Multiplex, MassDensity: 700 kg/m3; Hout - Multiplex, Embodied Energy: 15 (MJ/kg); Hout - Multiplex, Embodied Carbon: 0.77 (kgCO₂/kg); Hout - Multiplex, Name: Hout - Multiplex; Hout - Multiplex, Participates in Collision Detection: yes
Membraan - waterdicht | 1e verdieping | Membraan - waterdicht | 71.9227 | 5 | 1038 | 0.00519 | 0.0684978 | 0.0684978 | Material Properties - Membraan - waterdicht, ThermalConductivity: 0.2; Membraan - waterdicht, SpecificHeatCapacity: 1840 J/kg/K; Membraan - waterdicht, MassDensity: 1050 kg/m3; Membraan - waterdicht, Embodied Energy: 51 (MJ/kg); Membraan - waterdicht, Embodied Carbon: 0.38 (kgCO₂/kg); Membraan - waterdicht, Name: Membraan - waterdicht; Membraan - waterdicht, Participates in Collision Detection: yes
Metaal - kleur buitenkozijnen | 1e verdieping | Metaal - kleur buitenkozijnen | 10.0936 |  |  | 0.000277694 | 0.00360487 | 0.00360487 | Material Properties - Metaal - kleur buitenkozijnen, ThermalConductivity: 160; Metaal - kleur buitenkozijnen, SpecificHeatCapacity: 880 J/kg/K; Metaal - kleur buitenkozijnen, MassDensity: 2800 kg/m3; Metaal - kleur buitenkozijnen, Embodied Energy: 155 (MJ/kg); Metaal - kleur buitenkozijnen, Embodied Carbon: 9.16 (kgCO₂/kg); Metaal - kleur buitenkozijnen, Name: Metaal - kleur buitenkozijnen; Metaal - kleur buitenkozijnen, Participates in Collision Detection: yes
Hout - Multiplex | 1e verdieping | Hout - Multiplex | 148.052 | 15 | 1038 | 0.01557 | 0.211502 | 0.211502 | Material Properties - Hout - Multiplex, ThermalConductivity: 0.17; Hout - Multiplex, SpecificHeatCapacity: 1600 J/kg/K; Hout - Multiplex, MassDensity: 700 kg/m3; Hout - Multiplex, Embodied Energy: 15 (MJ/kg); Hout - Multiplex, Embodied Carbon: 0.77 (kgCO₂/kg); Hout - Multiplex, Name: Hout - Multiplex; Hout - Multiplex, Participates in Collision Detection: yes
Membraan - waterdicht | 1e verdieping | Membraan - waterdicht | 74.0258 | 5 | 1038 | 0.00519 | 0.0705008 | 0.0705008 | Material Properties - Membraan - waterdicht, ThermalConductivity: 0.2; Membraan - waterdicht, SpecificHeatCapacity: 1840 J/kg/K; Membraan - waterdicht, MassDensity: 1050 kg/m3; Membraan - waterdicht, Embodied Energy: 51 (MJ/kg); Membraan - waterdicht, Embodied Carbon: 0.38 (kgCO₂/kg); Membraan - waterdicht, Name: Membraan - waterdicht; Membraan - waterdicht, Participates in Collision Detection: yes
Metaal - kleur buitenkozijnen | 1e verdieping | Metaal - kleur buitenkozijnen | 10.6877 |  |  | 0.000277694 | 0.00381705 | 0.00381705 | Material Properties - Metaal - kleur buitenkozijnen, ThermalConductivity: 160; Metaal - kleur buitenkozijnen, SpecificHeatCapacity: 880 J/kg/K; Metaal - kleur buitenkozijnen, MassDensity: 2800 kg/m3; Metaal - kleur buitenkozijnen, Embodied Energy: 155 (MJ/kg); Metaal - kleur buitenkozijnen, Embodied Carbon: 9.16 (kgCO₂/kg); Metaal - kleur buitenkozijnen, Name: Metaal - kleur buitenkozijnen; Metaal - kleur buitenkozijnen, Participates in Collision Detection: yes
Hout - Multiplex | 1e verdieping | Hout - Multiplex | 118.634 | 15 | 436 | 0.00654 | 0.169478 | 0.169478 | Material Properties - Hout - Multiplex, ThermalConductivity: 0.17; Hout - Multiplex, SpecificHeatCapacity: 1600 J/kg/K; Hout - Multiplex, MassDensity: 700 kg/m3; Hout - Multiplex, Embodied Energy: 15 (MJ/kg); Hout - Multiplex, Embodied Carbon: 0.77 (kgCO₂/kg); Hout - Multiplex, Name: Hout - Multiplex; Hout - Multiplex, Participates in Collision Detection: yes
Membraan - waterdicht | 1e verdieping | Membraan - waterdicht | 60.009 |  |  | 0.002205 | 0.0571515 | 0.0571515 | Material Properties - Membraan - waterdicht, ThermalConductivity: 0.2; Membraan - waterdicht, SpecificHeatCapacity: 1840 J/kg/K; Membraan - waterdicht, MassDensity: 1050 kg/m3; Membraan - waterdicht, Embodied Energy: 51 (MJ/kg); Membraan - waterdicht, Embodied Carbon: 0.38 (kgCO₂/kg); Membraan - waterdicht, Name: Membraan - waterdicht; Membraan - waterdicht, Participates in Collision Detection: yes
Membraan - waterdicht | 1e verdieping | Membraan - waterdicht | 53.962 | 390 | 5 | 0.00195 | 0.0513923 | 0.0513923 | Material Properties - Membraan - waterdicht, ThermalConductivity: 0.2; Membraan - waterdicht, SpecificHeatCapacity: 1840 J/kg/K; Membraan - waterdicht, MassDensity: 1050 kg/m3; Membraan - waterdicht, Embodied Energy: 51 (MJ/kg); Membraan - waterdicht, Embodied Carbon: 0.38 (kgCO₂/kg); Membraan - waterdicht, Name: Membraan - waterdicht; Membraan - waterdicht, Participates in Collision Detection: yes
Steen - Cellenbeton | 1e verdieping | Steen - Cellenbeton | 1416.77 | 515 | 150 | 0.07725 | 2.02395 | 2.02395 | Material Properties - Steen - Cellenbeton, ThermalConductivity: 0.23; Steen - Cellenbeton, SpecificHeatCapacity: 840 J/kg/K; Steen - Cellenbeton, MassDensity: 700 kg/m3; Steen - Cellenbeton, Embodied Energy: 0.75 (MJ/kg); Steen - Cellenbeton, Embodied Carbon: 0.1 (kgCO₂/kg); Steen - Cellenbeton, Name: Steen - Cellenbeton; Steen - Cellenbeton, Participates in Collision Detection: yes
Metaal - kleur buitenkozijnen | 1e verdieping | Metaal - kleur buitenkozijnen | 19.7628 |  |  | 0.000277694 | 0.00705815 | 0.00705815 | Material Properties - Metaal - kleur buitenkozijnen, ThermalConductivity: 160; Metaal - kleur buitenkozijnen, SpecificHeatCapacity: 880 J/kg/K; Metaal - kleur buitenkozijnen, MassDensity: 2800 kg/m3; Metaal - kleur buitenkozijnen, Embodied Energy: 155 (MJ/kg); Metaal - kleur buitenkozijnen, Embodied Carbon: 9.16 (kgCO₂/kg); Metaal - kleur buitenkozijnen, Name: Metaal - kleur buitenkozijnen; Metaal - kleur buitenkozijnen, Participates in Collision Detection: yes
Hout - Multiplex | 1e verdieping | Hout - Multiplex | 18.8522 | 15 | 436 | 0.00654 | 0.0269317 | 0.0269317 | Material Properties - Hout - Multiplex, ThermalConductivity: 0.17; Hout - Multiplex, SpecificHeatCapacity: 1600 J/kg/K; Hout - Multiplex, MassDensity: 700 kg/m3; Hout - Multiplex, Embodied Energy: 15 (MJ/kg); Hout - Multiplex, Embodied Carbon: 0.77 (kgCO₂/kg); Hout - Multiplex, Name: Hout - Multiplex; Hout - Multiplex, Participates in Collision Detection: yes
Membraan - waterdicht | 1e verdieping | Membraan - waterdicht | 9.53998 |  |  | 0.002205 | 0.0090857 | 0.0090857 | Material Properties - Membraan - waterdicht, ThermalConductivity: 0.2; Membraan - waterdicht, SpecificHeatCapacity: 1840 J/kg/K; Membraan - waterdicht, MassDensity: 1050 kg/m3; Membraan - waterdicht, Embodied Energy: 51 (MJ/kg); Membraan - waterdicht, Embodied Carbon: 0.38 (kgCO₂/kg); Membraan - waterdicht, Name: Membraan - waterdicht; Membraan - waterdicht, Participates in Collision Detection: yes
Membraan - waterdicht | 1e verdieping | Membraan - waterdicht | 8.88308 | 390 | 5 | 0.00195 | 0.00846007 | 0.00846007 | Material Properties - Membraan - waterdicht, ThermalConductivity: 0.2; Membraan - waterdicht, SpecificHeatCapacity: 1840 J/kg/K; Membraan - waterdicht, MassDensity: 1050 kg/m3; Membraan - waterdicht, Embodied Energy: 51 (MJ/kg); Membraan - waterdicht, Embodied Carbon: 0.38 (kgCO₂/kg); Membraan - waterdicht, Name: Membraan - waterdicht; Membraan - waterdicht, Participates in Collision Detection: yes
Steen - Cellenbeton | 1e verdieping | Steen - Cellenbeton | 230.414 | 515 | 150 | 0.07725 | 0.329162 | 0.329162 | Material Properties - Steen - Cellenbeton, ThermalConductivity: 0.23; Steen - Cellenbeton, SpecificHeatCapacity: 840 J/kg/K; Steen - Cellenbeton, MassDensity: 700 kg/m3; Steen - Cellenbeton, Embodied Energy: 0.75 (MJ/kg); Steen - Cellenbeton, Embodied Carbon: 0.1 (kgCO₂/kg); Steen - Cellenbeton, Name: Steen - Cellenbeton; Steen - Cellenbeton, Participates in Collision Detection: yes
Metaal - kleur buitenkozijnen | 1e verdieping | Metaal - kleur buitenkozijnen | 3.01034 |  |  | 0.000277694 | 0.00107512 | 0.00107512 | Material Properties - Metaal - kleur buitenkozijnen, ThermalConductivity: 160; Metaal - kleur buitenkozijnen, SpecificHeatCapacity: 880 J/kg/K; Metaal - kleur buitenkozijnen, MassDensity: 2800 kg/m3; Metaal - kleur buitenkozijnen, Embodied Energy: 155 (MJ/kg); Metaal - kleur buitenkozijnen, Embodied Carbon: 9.16 (kgCO₂/kg); Metaal - kleur buitenkozijnen, Name: Metaal - kleur buitenkozijnen; Metaal - kleur buitenkozijnen, Participates in Collision Detection: yes
Hout - Multiplex | 1e verdieping | Hout - Multiplex | 20.3618 | 15 | 435.001 | 0.00652501 | 0.0290883 | 0.0290883 | Material Properties - Hout - Multiplex, ThermalConductivity: 0.17; Hout - Multiplex, SpecificHeatCapacity: 1600 J/kg/K; Hout - Multiplex, MassDensity: 700 kg/m3; Hout - Multiplex, Embodied Energy: 15 (MJ/kg); Hout - Multiplex, Embodied Carbon: 0.77 (kgCO₂/kg); Hout - Multiplex, Name: Hout - Multiplex; Hout - Multiplex, Participates in Collision Detection: yes
Membraan - waterdicht | 1e verdieping | Membraan - waterdicht | 10.2921 |  |  | 0.0022 | 0.00980203 | 0.00980203 | Material Properties - Membraan - waterdicht, ThermalConductivity: 0.2; Membraan - waterdicht, SpecificHeatCapacity: 1840 J/kg/K; Membraan - waterdicht, MassDensity: 1050 kg/m3; Membraan - waterdicht, Embodied Energy: 51 (MJ/kg); Membraan - waterdicht, Embodied Carbon: 0.38 (kgCO₂/kg); Membraan - waterdicht, Name: Membraan - waterdicht; Membraan - waterdicht, Participates in Collision Detection: yes
Membraan - waterdicht | 1e verdieping | Membraan - waterdicht | 17.7974 | 800 | 4.99999 | 0.00399999 | 0.0169499 | 0.0169499 | Material Properties - Membraan - waterdicht, ThermalConductivity: 0.2; Membraan - waterdicht, SpecificHeatCapacity: 1840 J/kg/K; Membraan - waterdicht, MassDensity: 1050 kg/m3; Membraan - waterdicht, Embodied Energy: 51 (MJ/kg); Membraan - waterdicht, Embodied Carbon: 0.38 (kgCO₂/kg); Membraan - waterdicht, Name: Membraan - waterdicht; Membraan - waterdicht, Participates in Collision Detection: yes
Steen - Cellenbeton | 1e verdieping | Steen - Cellenbeton | 419.11 | 925 | 150 | 0.13875 | 0.598728 | 0.598728 | Material Properties - Steen - Cellenbeton, ThermalConductivity: 0.23; Steen - Cellenbeton, SpecificHeatCapacity: 840 J/kg/K; Steen - Cellenbeton, MassDensity: 700 kg/m3; Steen - Cellenbeton, Embodied Energy: 0.75 (MJ/kg); Steen - Cellenbeton, Embodied Carbon: 0.1 (kgCO₂/kg); Steen - Cellenbeton, Name: Steen - Cellenbeton; Steen - Cellenbeton, Participates in Collision Detection: yes
Metaal - kleur buitenkozijnen | 1e verdieping | Metaal - kleur buitenkozijnen | 3.62965 |  |  | 0.000277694 | 0.0012963 | 0.0012963 | Material Properties - Metaal - kleur buitenkozijnen, ThermalConductivity: 160; Metaal - kleur buitenkozijnen, SpecificHeatCapacity: 880 J/kg/K; Metaal - kleur buitenkozijnen, MassDensity: 2800 kg/m3; Metaal - kleur buitenkozijnen, Embodied Energy: 155 (MJ/kg); Metaal - kleur buitenkozijnen, Embodied Carbon: 9.16 (kgCO₂/kg); Metaal - kleur buitenkozijnen, Name: Metaal - kleur buitenkozijnen; Metaal - kleur buitenkozijnen, Participates in Collision Detection: yes
Hout - Multiplex | 1e verdieping | Hout - Multiplex | 54.1872 | 15 | 436 | 0.00654 | 0.0774102 | 0.0774102 | Material Properties - Hout - Multiplex, ThermalConductivity: 0.17; Hout - Multiplex, SpecificHeatCapacity: 1600 J/kg/K; Hout - Multiplex, MassDensity: 700 kg/m3; Hout - Multiplex, Embodied Energy: 15 (MJ/kg); Hout - Multiplex, Embodied Carbon: 0.77 (kgCO₂/kg); Hout - Multiplex, Name: Hout - Multiplex; Hout - Multiplex, Participates in Collision Detection: yes
Membraan - waterdicht | 1e verdieping | Membraan - waterdicht | 27.4012 |  |  | 0.002205 | 0.0260964 | 0.0260964 | Material Properties - Membraan - waterdicht, ThermalConductivity: 0.2; Membraan - waterdicht, SpecificHeatCapacity: 1840 J/kg/K; Membraan - waterdicht, MassDensity: 1050 kg/m3; Membraan - waterdicht, Embodied Energy: 51 (MJ/kg); Membraan - waterdicht, Embodied Carbon: 0.38 (kgCO₂/kg); Membraan - waterdicht, Name: Membraan - waterdicht; Membraan - waterdicht, Participates in Collision Detection: yes
Membraan - waterdicht | 1e verdieping | Membraan - waterdicht | 24.043 | 390 | 5 | 0.00195 | 0.0228981 | 0.0228981 | Material Properties - Membraan - waterdicht, ThermalConductivity: 0.2; Membraan - waterdicht, SpecificHeatCapacity: 1840 J/kg/K; Membraan - waterdicht, MassDensity: 1050 kg/m3; Membraan - waterdicht, Embodied Energy: 51 (MJ/kg); Membraan - waterdicht, Embodied Carbon: 0.38 (kgCO₂/kg); Membraan - waterdicht, Name: Membraan - waterdicht; Membraan - waterdicht, Participates in Collision Detection: yes
Steen - Cellenbeton | 1e verdieping | Steen - Cellenbeton | 634.841 | 515 | 150 | 0.07725 | 0.906915 | 0.906915 | Material Properties - Steen - Cellenbeton, ThermalConductivity: 0.23; Steen - Cellenbeton, SpecificHeatCapacity: 840 J/kg/K; Steen - Cellenbeton, MassDensity: 700 kg/m3; Steen - Cellenbeton, Embodied Energy: 0.75 (MJ/kg); Steen - Cellenbeton, Embodied Carbon: 0.1 (kgCO₂/kg); Steen - Cellenbeton, Name: Steen - Cellenbeton; Steen - Cellenbeton, Participates in Collision Detection: yes
Metaal - kleur buitenkozijnen | 1e verdieping | Metaal - kleur buitenkozijnen | 9.22463 |  |  | 0.000277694 | 0.00329451 | 0.00329451 | Material Properties - Metaal - kleur buitenkozijnen, ThermalConductivity: 160; Metaal - kleur buitenkozijnen, SpecificHeatCapacity: 880 J/kg/K; Metaal - kleur buitenkozijnen, MassDensity: 2800 kg/m3; Metaal - kleur buitenkozijnen, Embodied Energy: 155 (MJ/kg); Metaal - kleur buitenkozijnen, Embodied Carbon: 9.16 (kgCO₂/kg); Metaal - kleur buitenkozijnen, Name: Metaal - kleur buitenkozijnen; Metaal - kleur buitenkozijnen, Participates in Collision Detection: yes
2 x Hout - Multiplex | 1e verdieping | Hout - Multiplex | 20.4316 | 15 | 436 | 0.00654 | 0.0291879 | 0.0291879 | Material Properties - Hout - Multiplex, ThermalConductivity: 0.17; Hout - Multiplex, SpecificHeatCapacity: 1600 J/kg/K; Hout - Multiplex, MassDensity: 700 kg/m3; Hout - Multiplex, Embodied Energy: 15 (MJ/kg); Hout - Multiplex, Embodied Carbon: 0.77 (kgCO₂/kg); Hout - Multiplex, Name: Hout - Multiplex; Hout - Multiplex, Participates in Collision Detection: yes
2 x Membraan - waterdicht | 1e verdieping | Membraan - waterdicht | 10.3271 |  |  | 0.002205 | 0.00983538 | 0.00983538 | Material Properties - Membraan - waterdicht, ThermalConductivity: 0.2; Membraan - waterdicht, SpecificHeatCapacity: 1840 J/kg/K; Membraan - waterdicht, MassDensity: 1050 kg/m3; Membraan - waterdicht, Embodied Energy: 51 (MJ/kg); Membraan - waterdicht, Embodied Carbon: 0.38 (kgCO₂/kg); Membraan - waterdicht, Name: Membraan - waterdicht; Membraan - waterdicht, Participates in Collision Detection: yes
Membraan - waterdicht | 1e verdieping | Membraan - waterdicht | 17.8184 | 800 | 4.99999 | 0.00399999 | 0.0169699 | 0.0169699 | Material Properties - Membraan - waterdicht, ThermalConductivity: 0.2; Membraan - waterdicht, SpecificHeatCapacity: 1840 J/kg/K; Membraan - waterdicht, MassDensity: 1050 kg/m3; Membraan - waterdicht, Embodied Energy: 51 (MJ/kg); Membraan - waterdicht, Embodied Carbon: 0.38 (kgCO₂/kg); Membraan - waterdicht, Name: Membraan - waterdicht; Membraan - waterdicht, Participates in Collision Detection: yes
Steen - Cellenbeton | 1e verdieping | Steen - Cellenbeton | 419.579 | 925 | 150 | 0.13875 | 0.599398 | 0.599398 | Material Properties - Steen - Cellenbeton, ThermalConductivity: 0.23; Steen - Cellenbeton, SpecificHeatCapacity: 840 J/kg/K; Steen - Cellenbeton, MassDensity: 700 kg/m3; Steen - Cellenbeton, Embodied Energy: 0.75 (MJ/kg); Steen - Cellenbeton, Embodied Carbon: 0.1 (kgCO₂/kg); Steen - Cellenbeton, Name: Steen - Cellenbeton; Steen - Cellenbeton, Participates in Collision Detection: yes
Metaal - kleur buitenkozijnen | 1e verdieping | Metaal - kleur buitenkozijnen | 3.63357 |  |  | 0.000277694 | 0.00129771 | 0.00129771 | Material Properties - Metaal - kleur buitenkozijnen, ThermalConductivity: 160; Metaal - kleur buitenkozijnen, SpecificHeatCapacity: 880 J/kg/K; Metaal - kleur buitenkozijnen, MassDensity: 2800 kg/m3; Metaal - kleur buitenkozijnen, Embodied Energy: 155 (MJ/kg); Metaal - kleur buitenkozijnen, Embodied Carbon: 9.16 (kgCO₂/kg); Metaal - kleur buitenkozijnen, Name: Metaal - kleur buitenkozijnen; Metaal - kleur buitenkozijnen, Participates in Collision Detection: yes
Hout - Multiplex | 1e verdieping | Hout - Multiplex | 6.91428 |  |  | 0.00225001 | 0.00987754 | 0.00987754 | Material Properties - Hout - Multiplex, ThermalConductivity: 0.17; Hout - Multiplex, SpecificHeatCapacity: 1600 J/kg/K; Hout - Multiplex, MassDensity: 700 kg/m3; Hout - Multiplex, Embodied Energy: 15 (MJ/kg); Hout - Multiplex, Embodied Carbon: 0.77 (kgCO₂/kg); Hout - Multiplex, Name: Hout - Multiplex; Hout - Multiplex, Participates in Collision Detection: yes
Membraan - waterdicht | 1e verdieping | Membraan - waterdicht | 3.57646 | 5 | 155.002 | 0.000775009 | 0.00340616 | 0.00340616 | Material Properties - Membraan - waterdicht, ThermalConductivity: 0.2; Membraan - waterdicht, SpecificHeatCapacity: 1840 J/kg/K; Membraan - waterdicht, MassDensity: 1050 kg/m3; Membraan - waterdicht, Embodied Energy: 51 (MJ/kg); Membraan - waterdicht, Embodied Carbon: 0.38 (kgCO₂/kg); Membraan - waterdicht, Name: Membraan - waterdicht; Membraan - waterdicht, Participates in Collision Detection: yes
Membraan - waterdicht | 1e verdieping | Membraan - waterdicht | 5.47192 | 245 | 4.99999 | 0.001225 | 0.00521135 | 0.00521135 | Material Properties - Membraan - waterdicht, ThermalConductivity: 0.2; Membraan - waterdicht, SpecificHeatCapacity: 1840 J/kg/K; Membraan - waterdicht, MassDensity: 1050 kg/m3; Membraan - waterdicht, Embodied Energy: 51 (MJ/kg); Membraan - waterdicht, Embodied Carbon: 0.38 (kgCO₂/kg); Membraan - waterdicht, Name: Membraan - waterdicht; Membraan - waterdicht, Participates in Collision Detection: yes
Steen - Cellenbeton | 1e verdieping | Steen - Cellenbeton | 237.659 | 515 | 150 | 0.07725 | 0.339513 | 0.339513 | Material Properties - Steen - Cellenbeton, ThermalConductivity: 0.23; Steen - Cellenbeton, SpecificHeatCapacity: 840 J/kg/K; Steen - Cellenbeton, MassDensity: 700 kg/m3; Steen - Cellenbeton, Embodied Energy: 0.75 (MJ/kg); Steen - Cellenbeton, Embodied Carbon: 0.1 (kgCO₂/kg); Steen - Cellenbeton, Name: Steen - Cellenbeton; Steen - Cellenbeton, Participates in Collision Detection: yes
Hout - Multiplex | 1e verdieping | Hout - Multiplex | 50.4245 | 15 | 436 | 0.00654 | 0.072035 | 0.072035 | Material Properties - Hout - Multiplex, ThermalConductivity: 0.17; Hout - Multiplex, SpecificHeatCapacity: 1600 J/kg/K; Hout - Multiplex, MassDensity: 700 kg/m3; Hout - Multiplex, Embodied Energy: 15 (MJ/kg); Hout - Multiplex, Embodied Carbon: 0.77 (kgCO₂/kg); Hout - Multiplex, Name: Hout - Multiplex; Hout - Multiplex, Participates in Collision Detection: yes
Membraan - waterdicht | 1e verdieping | Membraan - waterdicht | 25.4899 |  |  | 0.002205 | 0.024276 | 0.024276 | Material Properties - Membraan - waterdicht, ThermalConductivity: 0.2; Membraan - waterdicht, SpecificHeatCapacity: 1840 J/kg/K; Membraan - waterdicht, MassDensity: 1050 kg/m3; Membraan - waterdicht, Embodied Energy: 51 (MJ/kg); Membraan - waterdicht, Embodied Carbon: 0.38 (kgCO₂/kg); Membraan - waterdicht, Name: Membraan - waterdicht; Membraan - waterdicht, Participates in Collision Detection: yes
Membraan - waterdicht | 1e verdieping | Membraan - waterdicht | 44.4107 | 800 | 4.99999 | 0.00399999 | 0.0422959 | 0.0422959 | Material Properties - Membraan - waterdicht, ThermalConductivity: 0.2; Membraan - waterdicht, SpecificHeatCapacity: 1840 J/kg/K; Membraan - waterdicht, MassDensity: 1050 kg/m3; Membraan - waterdicht, Embodied Energy: 51 (MJ/kg); Membraan - waterdicht, Embodied Carbon: 0.38 (kgCO₂/kg); Membraan - waterdicht, Name: Membraan - waterdicht; Membraan - waterdicht, Participates in Collision Detection: yes
Steen - Cellenbeton | 1e verdieping | Steen - Cellenbeton | 1042.04 | 925 | 150 | 0.13875 | 1.48863 | 1.48863 | Material Properties - Steen - Cellenbeton, ThermalConductivity: 0.23; Steen - Cellenbeton, SpecificHeatCapacity: 840 J/kg/K; Steen - Cellenbeton, MassDensity: 700 kg/m3; Steen - Cellenbeton, Embodied Energy: 0.75 (MJ/kg); Steen - Cellenbeton, Embodied Carbon: 0.1 (kgCO₂/kg); Steen - Cellenbeton, Name: Steen - Cellenbeton; Steen - Cellenbeton, Participates in Collision Detection: yes
Metaal - kleur buitenkozijnen | 1e verdieping | Metaal - kleur buitenkozijnen | 8.88716 |  |  | 0.000277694 | 0.00317398 | 0.00317398 | Material Properties - Metaal - kleur buitenkozijnen, ThermalConductivity: 160; Metaal - kleur buitenkozijnen, SpecificHeatCapacity: 880 J/kg/K; Metaal - kleur buitenkozijnen, MassDensity: 2800 kg/m3; Metaal - kleur buitenkozijnen, Embodied Energy: 155 (MJ/kg); Metaal - kleur buitenkozijnen, Embodied Carbon: 9.16 (kgCO₂/kg); Metaal - kleur buitenkozijnen, Name: Metaal - kleur buitenkozijnen; Metaal - kleur buitenkozijnen, Participates in Collision Detection: yes
2 x Hout - Multiplex | 1e verdieping | Hout - Multiplex | 7.80256 | 15 | 143 | 0.002145 | 0.0111465 | 0.0111465 | Material Properties - Hout - Multiplex, ThermalConductivity: 0.17; Hout - Multiplex, SpecificHeatCapacity: 1600 J/kg/K; Hout - Multiplex, MassDensity: 700 kg/m3; Hout - Multiplex, Embodied Energy: 15 (MJ/kg); Hout - Multiplex, Embodied Carbon: 0.77 (kgCO₂/kg); Hout - Multiplex, Name: Hout - Multiplex; Hout - Multiplex, Participates in Collision Detection: yes
2 x Membraan - waterdicht | 1e verdieping | Membraan - waterdicht | 3.90038 | 5 | 143 | 0.000715 | 0.00371464 | 0.00371464 | Material Properties - Membraan - waterdicht, ThermalConductivity: 0.2; Membraan - waterdicht, SpecificHeatCapacity: 1840 J/kg/K; Membraan - waterdicht, MassDensity: 1050 kg/m3; Membraan - waterdicht, Embodied Energy: 51 (MJ/kg); Membraan - waterdicht, Embodied Carbon: 0.38 (kgCO₂/kg); Membraan - waterdicht, Name: Membraan - waterdicht; Membraan - waterdicht, Participates in Collision Detection: yes
Metaal - kleur buitenkozijnen | 1e verdieping | Metaal - kleur buitenkozijnen | 4.01915 |  |  | 0.000277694 | 0.00143541 | 0.00143541 | Material Properties - Metaal - kleur buitenkozijnen, ThermalConductivity: 160; Metaal - kleur buitenkozijnen, SpecificHeatCapacity: 880 J/kg/K; Metaal - kleur buitenkozijnen, MassDensity: 2800 kg/m3; Metaal - kleur buitenkozijnen, Embodied Energy: 155 (MJ/kg); Metaal - kleur buitenkozijnen, Embodied Carbon: 9.16 (kgCO₂/kg); Metaal - kleur buitenkozijnen, Name: Metaal - kleur buitenkozijnen; Metaal - kleur buitenkozijnen, Participates in Collision Detection: yes
Hout - Multiplex | 1e verdieping | Hout - Multiplex | 21.6904 | 15 | 436 | 0.00654 | 0.0309863 | 0.0309863 | Material Properties - Hout - Multiplex, ThermalConductivity: 0.17; Hout - Multiplex, SpecificHeatCapacity: 1600 J/kg/K; Hout - Multiplex, MassDensity: 700 kg/m3; Hout - Multiplex, Embodied Energy: 15 (MJ/kg); Hout - Multiplex, Embodied Carbon: 0.77 (kgCO₂/kg); Hout - Multiplex, Name: Hout - Multiplex; Hout - Multiplex, Participates in Collision Detection: yes
Membraan - waterdicht | 1e verdieping | Membraan - waterdicht | 10.9639 |  |  | 0.002205 | 0.0104418 | 0.0104418 | Material Properties - Membraan - waterdicht, ThermalConductivity: 0.2; Membraan - waterdicht, SpecificHeatCapacity: 1840 J/kg/K; Membraan - waterdicht, MassDensity: 1050 kg/m3; Membraan - waterdicht, Embodied Energy: 51 (MJ/kg); Membraan - waterdicht, Embodied Carbon: 0.38 (kgCO₂/kg); Membraan - waterdicht, Name: Membraan - waterdicht; Membraan - waterdicht, Participates in Collision Detection: yes
Membraan - waterdicht | 1e verdieping | Membraan - waterdicht | 5.9501 | 249 | 5 | 0.001245 | 0.00566676 | 0.00566676 | Material Properties - Membraan - waterdicht, ThermalConductivity: 0.2; Membraan - waterdicht, SpecificHeatCapacity: 1840 J/kg/K; Membraan - waterdicht, MassDensity: 1050 kg/m3; Membraan - waterdicht, Embodied Energy: 51 (MJ/kg); Membraan - waterdicht, Embodied Carbon: 0.38 (kgCO₂/kg); Membraan - waterdicht, Name: Membraan - waterdicht; Membraan - waterdicht, Participates in Collision Detection: yes
Steen - Cellenbeton | 1e verdieping | Steen - Cellenbeton | 181.624 | 374 | 150 | 0.0561 | 0.259463 | 0.259463 | Material Properties - Steen - Cellenbeton, ThermalConductivity: 0.23; Steen - Cellenbeton, SpecificHeatCapacity: 840 J/kg/K; Steen - Cellenbeton, MassDensity: 700 kg/m3; Steen - Cellenbeton, Embodied Energy: 0.75 (MJ/kg); Steen - Cellenbeton, Embodied Carbon: 0.1 (kgCO₂/kg); Steen - Cellenbeton, Name: Steen - Cellenbeton; Steen - Cellenbeton, Participates in Collision Detection: yes
Metaal - kleur buitenkozijnen | 1e verdieping | Metaal - kleur buitenkozijnen | 3.98658 |  |  | 0.000277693 | 0.00142378 | 0.00142378 | Material Properties - Metaal - kleur buitenkozijnen, ThermalConductivity: 160; Metaal - kleur buitenkozijnen, SpecificHeatCapacity: 880 J/kg/K; Metaal - kleur buitenkozijnen, MassDensity: 2800 kg/m3; Metaal - kleur buitenkozijnen, Embodied Energy: 155 (MJ/kg); Metaal - kleur buitenkozijnen, Embodied Carbon: 9.16 (kgCO₂/kg); Metaal - kleur buitenkozijnen, Name: Metaal - kleur buitenkozijnen; Metaal - kleur buitenkozijnen, Participates in Collision Detection: yes
Metaal - kleur buitenkozijnen | 1e verdieping | Metaal - kleur buitenkozijnen | 4.00985 |  |  | 0.000277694 | 0.00143209 | 0.00143209 | Material Properties - Metaal - kleur buitenkozijnen, ThermalConductivity: 160; Metaal - kleur buitenkozijnen, SpecificHeatCapacity: 880 J/kg/K; Metaal - kleur buitenkozijnen, MassDensity: 2800 kg/m3; Metaal - kleur buitenkozijnen, Embodied Energy: 155 (MJ/kg); Metaal - kleur buitenkozijnen, Embodied Carbon: 9.16 (kgCO₂/kg); Metaal - kleur buitenkozijnen, Name: Metaal - kleur buitenkozijnen; Metaal - kleur buitenkozijnen, Participates in Collision Detection: yes
Membraan - waterdicht | 1e verdieping | Membraan - waterdicht | 5.54599 | 249 | 5 | 0.001245 | 0.0052819 | 0.0052819 | Material Properties - Membraan - waterdicht, ThermalConductivity: 0.2; Membraan - waterdicht, SpecificHeatCapacity: 1840 J/kg/K; Membraan - waterdicht, MassDensity: 1050 kg/m3; Membraan - waterdicht, Embodied Energy: 51 (MJ/kg); Membraan - waterdicht, Embodied Carbon: 0.38 (kgCO₂/kg); Membraan - waterdicht, Name: Membraan - waterdicht; Membraan - waterdicht, Participates in Collision Detection: yes
Steen - Cellenbeton | 1e verdieping | Steen - Cellenbeton | 169.646 | 374 | 150 | 0.0561 | 0.242351 | 0.242351 | Material Properties - Steen - Cellenbeton, ThermalConductivity: 0.23; Steen - Cellenbeton, SpecificHeatCapacity: 840 J/kg/K; Steen - Cellenbeton, MassDensity: 700 kg/m3; Steen - Cellenbeton, Embodied Energy: 0.75 (MJ/kg); Steen - Cellenbeton, Embodied Carbon: 0.1 (kgCO₂/kg); Steen - Cellenbeton, Name: Steen - Cellenbeton; Steen - Cellenbeton, Participates in Collision Detection: yes
Metaal - kleur buitenkozijnen | 1e verdieping | Metaal - kleur buitenkozijnen | 3.63357 |  |  | 0.000277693 | 0.0012977 | 0.0012977 | Material Properties - Metaal - kleur buitenkozijnen, ThermalConductivity: 160; Metaal - kleur buitenkozijnen, SpecificHeatCapacity: 880 J/kg/K; Metaal - kleur buitenkozijnen, MassDensity: 2800 kg/m3; Metaal - kleur buitenkozijnen, Embodied Energy: 155 (MJ/kg); Metaal - kleur buitenkozijnen, Embodied Carbon: 9.16 (kgCO₂/kg); Metaal - kleur buitenkozijnen, Name: Metaal - kleur buitenkozijnen; Metaal - kleur buitenkozijnen, Participates in Collision Detection: yes
Hout - Multiplex | 1e verdieping | Hout - Multiplex | 47.2038 | 15 | 436 | 0.00654 | 0.0674339 | 0.0674339 | Material Properties - Hout - Multiplex, ThermalConductivity: 0.17; Hout - Multiplex, SpecificHeatCapacity: 1600 J/kg/K; Hout - Multiplex, MassDensity: 700 kg/m3; Hout - Multiplex, Embodied Energy: 15 (MJ/kg); Hout - Multiplex, Embodied Carbon: 0.77 (kgCO₂/kg); Hout - Multiplex, Name: Hout - Multiplex; Hout - Multiplex, Participates in Collision Detection: yes
Membraan - waterdicht | 1e verdieping | Membraan - waterdicht | 23.861 |  |  | 0.002205 | 0.0227247 | 0.0227247 | Material Properties - Membraan - waterdicht, ThermalConductivity: 0.2; Membraan - waterdicht, SpecificHeatCapacity: 1840 J/kg/K; Membraan - waterdicht, MassDensity: 1050 kg/m3; Membraan - waterdicht, Embodied Energy: 51 (MJ/kg); Membraan - waterdicht, Embodied Carbon: 0.38 (kgCO₂/kg); Membraan - waterdicht, Name: Membraan - waterdicht; Membraan - waterdicht, Participates in Collision Detection: yes
Membraan - waterdicht | 1e verdieping | Membraan - waterdicht | 28.4997 | 550 | 5 | 0.00275 | 0.0271425 | 0.0271425 | Material Properties - Membraan - waterdicht, ThermalConductivity: 0.2; Membraan - waterdicht, SpecificHeatCapacity: 1840 J/kg/K; Membraan - waterdicht, MassDensity: 1050 kg/m3; Membraan - waterdicht, Embodied Energy: 51 (MJ/kg); Membraan - waterdicht, Embodied Carbon: 0.38 (kgCO₂/kg); Membraan - waterdicht, Name: Membraan - waterdicht; Membraan - waterdicht, Participates in Collision Detection: yes
Steen - Cellenbeton | 1e verdieping | Steen - Cellenbeton | 710.522 | 675 | 150 | 0.10125 | 1.01503 | 1.01503 | Material Properties - Steen - Cellenbeton, ThermalConductivity: 0.23; Steen - Cellenbeton, SpecificHeatCapacity: 840 J/kg/K; Steen - Cellenbeton, MassDensity: 700 kg/m3; Steen - Cellenbeton, Embodied Energy: 0.75 (MJ/kg); Steen - Cellenbeton, Embodied Carbon: 0.1 (kgCO₂/kg); Steen - Cellenbeton, Name: Steen - Cellenbeton; Steen - Cellenbeton, Participates in Collision Detection: yes
Metaal - kleur buitenkozijnen | 1e verdieping | Metaal - kleur buitenkozijnen | 8.34169 |  |  | 0.000277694 | 0.00297918 | 0.00297918 | Material Properties - Metaal - kleur buitenkozijnen, ThermalConductivity: 160; Metaal - kleur buitenkozijnen, SpecificHeatCapacity: 880 J/kg/K; Metaal - kleur buitenkozijnen, MassDensity: 2800 kg/m3; Metaal - kleur buitenkozijnen, Embodied Energy: 155 (MJ/kg); Metaal - kleur buitenkozijnen, Embodied Carbon: 9.16 (kgCO₂/kg); Metaal - kleur buitenkozijnen, Name: Metaal - kleur buitenkozijnen; Metaal - kleur buitenkozijnen, Participates in Collision Detection: yes
Hout - Multiplex | 1e verdieping | Hout - Multiplex | 103.27 | 15 | 436 | 0.00654 | 0.147529 | 0.147529 | Material Properties - Hout - Multiplex, ThermalConductivity: 0.17; Hout - Multiplex, SpecificHeatCapacity: 1600 J/kg/K; Hout - Multiplex, MassDensity: 700 kg/m3; Hout - Multiplex, Embodied Energy: 15 (MJ/kg); Hout - Multiplex, Embodied Carbon: 0.77 (kgCO₂/kg); Hout - Multiplex, Name: Hout - Multiplex; Hout - Multiplex, Participates in Collision Detection: yes
Membraan - waterdicht | 1e verdieping | Membraan - waterdicht | 52.2217 |  |  | 0.002205 | 0.0497349 | 0.0497349 | Material Properties - Membraan - waterdicht, ThermalConductivity: 0.2; Membraan - waterdicht, SpecificHeatCapacity: 1840 J/kg/K; Membraan - waterdicht, MassDensity: 1050 kg/m3; Membraan - waterdicht, Embodied Energy: 51 (MJ/kg); Membraan - waterdicht, Embodied Carbon: 0.38 (kgCO₂/kg); Membraan - waterdicht, Name: Membraan - waterdicht; Membraan - waterdicht, Participates in Collision Detection: yes
Membraan - waterdicht | 1e verdieping | Membraan - waterdicht | 64.4999 | 550 | 5 | 0.00275 | 0.0614285 | 0.0614285 | Material Properties - Membraan - waterdicht, ThermalConductivity: 0.2; Membraan - waterdicht, SpecificHeatCapacity: 1840 J/kg/K; Membraan - waterdicht, MassDensity: 1050 kg/m3; Membraan - waterdicht, Embodied Energy: 51 (MJ/kg); Membraan - waterdicht, Embodied Carbon: 0.38 (kgCO₂/kg); Membraan - waterdicht, Name: Membraan - waterdicht; Membraan - waterdicht, Participates in Collision Detection: yes
Steen - Cellenbeton | 1e verdieping | Steen - Cellenbeton | 1588.67 | 675 | 150 | 0.10125 | 2.26953 | 2.26953 | Material Properties - Steen - Cellenbeton, ThermalConductivity: 0.23; Steen - Cellenbeton, SpecificHeatCapacity: 840 J/kg/K; Steen - Cellenbeton, MassDensity: 700 kg/m3; Steen - Cellenbeton, Embodied Energy: 0.75 (MJ/kg); Steen - Cellenbeton, Embodied Carbon: 0.1 (kgCO₂/kg); Steen - Cellenbeton, Name: Steen - Cellenbeton; Steen - Cellenbeton, Participates in Collision Detection: yes
Metaal - kleur buitenkozijnen | 1e verdieping | Metaal - kleur buitenkozijnen | 17.6955 |  |  | 0.000277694 | 0.00631982 | 0.00631982 | Material Properties - Metaal - kleur buitenkozijnen, ThermalConductivity: 160; Metaal - kleur buitenkozijnen, SpecificHeatCapacity: 880 J/kg/K; Metaal - kleur buitenkozijnen, MassDensity: 2800 kg/m3; Metaal - kleur buitenkozijnen, Embodied Energy: 155 (MJ/kg); Metaal - kleur buitenkozijnen, Embodied Carbon: 9.16 (kgCO₂/kg); Metaal - kleur buitenkozijnen, Name: Metaal - kleur buitenkozijnen; Metaal - kleur buitenkozijnen, Participates in Collision Detection: yes
Hout - Multiplex | 1e verdieping | Hout - Multiplex | 33.8772 | 15 | 436 | 0.00654 | 0.048396 | 0.048396 | Material Properties - Hout - Multiplex, ThermalConductivity: 0.17; Hout - Multiplex, SpecificHeatCapacity: 1600 J/kg/K; Hout - Multiplex, MassDensity: 700 kg/m3; Hout - Multiplex, Embodied Energy: 15 (MJ/kg); Hout - Multiplex, Embodied Carbon: 0.77 (kgCO₂/kg); Hout - Multiplex, Name: Hout - Multiplex; Hout - Multiplex, Participates in Collision Detection: yes
Membraan - waterdicht | 1e verdieping | Membraan - waterdicht | 17.1329 |  |  | 0.002205 | 0.016317 | 0.016317 | Material Properties - Membraan - waterdicht, ThermalConductivity: 0.2; Membraan - waterdicht, SpecificHeatCapacity: 1840 J/kg/K; Membraan - waterdicht, MassDensity: 1050 kg/m3; Membraan - waterdicht, Embodied Energy: 51 (MJ/kg); Membraan - waterdicht, Embodied Carbon: 0.38 (kgCO₂/kg); Membraan - waterdicht, Name: Membraan - waterdicht; Membraan - waterdicht, Participates in Collision Detection: yes
Membraan - waterdicht | 1e verdieping | Membraan - waterdicht | 21.3675 | 550 | 5 | 0.00275 | 0.02035 | 0.02035 | Material Properties - Membraan - waterdicht, ThermalConductivity: 0.2; Membraan - waterdicht, SpecificHeatCapacity: 1840 J/kg/K; Membraan - waterdicht, MassDensity: 1050 kg/m3; Membraan - waterdicht, Embodied Energy: 51 (MJ/kg); Membraan - waterdicht, Embodied Carbon: 0.38 (kgCO₂/kg); Membraan - waterdicht, Name: Membraan - waterdicht; Membraan - waterdicht, Participates in Collision Detection: yes
Steen - Cellenbeton | 1e verdieping | Steen - Cellenbeton | 524.475 | 675 | 150 | 0.10125 | 0.74925 | 0.74925 | Material Properties - Steen - Cellenbeton, ThermalConductivity: 0.23; Steen - Cellenbeton, SpecificHeatCapacity: 840 J/kg/K; Steen - Cellenbeton, MassDensity: 700 kg/m3; Steen - Cellenbeton, Embodied Energy: 0.75 (MJ/kg); Steen - Cellenbeton, Embodied Carbon: 0.1 (kgCO₂/kg); Steen - Cellenbeton, Name: Steen - Cellenbeton; Steen - Cellenbeton, Participates in Collision Detection: yes
Metaal - kleur buitenkozijnen | 1e verdieping | Metaal - kleur buitenkozijnen | 5.74115 |  |  | 0.000277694 | 0.00205041 | 0.00205041 | Material Properties - Metaal - kleur buitenkozijnen, ThermalConductivity: 160; Metaal - kleur buitenkozijnen, SpecificHeatCapacity: 880 J/kg/K; Metaal - kleur buitenkozijnen, MassDensity: 2800 kg/m3; Metaal - kleur buitenkozijnen, Embodied Energy: 155 (MJ/kg); Metaal - kleur buitenkozijnen, Embodied Carbon: 9.16 (kgCO₂/kg); Metaal - kleur buitenkozijnen, Name: Metaal - kleur buitenkozijnen; Metaal - kleur buitenkozijnen, Participates in Collision Detection: yes
Hout - Multiplex | 1e verdieping | Hout - Multiplex | 18.8842 | 15 | 436 | 0.00654 | 0.0269775 | 0.0269775 | Material Properties - Hout - Multiplex, ThermalConductivity: 0.17; Hout - Multiplex, SpecificHeatCapacity: 1600 J/kg/K; Hout - Multiplex, MassDensity: 700 kg/m3; Hout - Multiplex, Embodied Energy: 15 (MJ/kg); Hout - Multiplex, Embodied Carbon: 0.77 (kgCO₂/kg); Hout - Multiplex, Name: Hout - Multiplex; Hout - Multiplex, Participates in Collision Detection: yes
Membraan - waterdicht | 1e verdieping | Membraan - waterdicht | 9.5504 |  |  | 0.002205 | 0.00909562 | 0.00909562 | Material Properties - Membraan - waterdicht, ThermalConductivity: 0.2; Membraan - waterdicht, SpecificHeatCapacity: 1840 J/kg/K; Membraan - waterdicht, MassDensity: 1050 kg/m3; Membraan - waterdicht, Embodied Energy: 51 (MJ/kg); Membraan - waterdicht, Embodied Carbon: 0.38 (kgCO₂/kg); Membraan - waterdicht, Name: Membraan - waterdicht; Membraan - waterdicht, Participates in Collision Detection: yes
Membraan - waterdicht | 1e verdieping | Membraan - waterdicht | 11.9109 | 550 | 5 | 0.00275 | 0.0113438 | 0.0113438 | Material Properties - Membraan - waterdicht, ThermalConductivity: 0.2; Membraan - waterdicht, SpecificHeatCapacity: 1840 J/kg/K; Membraan - waterdicht, MassDensity: 1050 kg/m3; Membraan - waterdicht, Embodied Energy: 51 (MJ/kg); Membraan - waterdicht, Embodied Carbon: 0.38 (kgCO₂/kg); Membraan - waterdicht, Name: Membraan - waterdicht; Membraan - waterdicht, Participates in Collision Detection: yes
Steen - Cellenbeton | 1e verdieping | Steen - Cellenbeton | 292.359 | 675 | 150 | 0.10125 | 0.417656 | 0.417656 | Material Properties - Steen - Cellenbeton, ThermalConductivity: 0.23; Steen - Cellenbeton, SpecificHeatCapacity: 840 J/kg/K; Steen - Cellenbeton, MassDensity: 700 kg/m3; Steen - Cellenbeton, Embodied Energy: 0.75 (MJ/kg); Steen - Cellenbeton, Embodied Carbon: 0.1 (kgCO₂/kg); Steen - Cellenbeton, Name: Steen - Cellenbeton; Steen - Cellenbeton, Participates in Collision Detection: yes
Metaal - kleur buitenkozijnen | 1e verdieping | Metaal - kleur buitenkozijnen | 3.19877 |  |  | 0.000277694 | 0.00114242 | 0.00114242 | Material Properties - Metaal - kleur buitenkozijnen, ThermalConductivity: 160; Metaal - kleur buitenkozijnen, SpecificHeatCapacity: 880 J/kg/K; Metaal - kleur buitenkozijnen, MassDensity: 2800 kg/m3; Metaal - kleur buitenkozijnen, Embodied Energy: 155 (MJ/kg); Metaal - kleur buitenkozijnen, Embodied Carbon: 9.16 (kgCO₂/kg); Metaal - kleur buitenkozijnen, Name: Metaal - kleur buitenkozijnen; Metaal - kleur buitenkozijnen, Participates in Collision Detection: yes
Hout - Multiplex | 1e verdieping | Hout - Multiplex | 93.7666 | 15 | 436 | 0.00654 | 0.133952 | 0.133952 | Material Properties - Hout - Multiplex, ThermalConductivity: 0.17; Hout - Multiplex, SpecificHeatCapacity: 1600 J/kg/K; Hout - Multiplex, MassDensity: 700 kg/m3; Hout - Multiplex, Embodied Energy: 15 (MJ/kg); Hout - Multiplex, Embodied Carbon: 0.77 (kgCO₂/kg); Hout - Multiplex, Name: Hout - Multiplex; Hout - Multiplex, Participates in Collision Detection: yes
Membraan - waterdicht | 1e verdieping | Membraan - waterdicht | 47.4152 |  |  | 0.002205 | 0.0451573 | 0.0451573 | Material Properties - Membraan - waterdicht, ThermalConductivity: 0.2; Membraan - waterdicht, SpecificHeatCapacity: 1840 J/kg/K; Membraan - waterdicht, MassDensity: 1050 kg/m3; Membraan - waterdicht, Embodied Energy: 51 (MJ/kg); Membraan - waterdicht, Embodied Carbon: 0.38 (kgCO₂/kg); Membraan - waterdicht, Name: Membraan - waterdicht; Membraan - waterdicht, Participates in Collision Detection: yes
Membraan - waterdicht | 1e verdieping | Membraan - waterdicht | 58.5051 | 550 | 5 | 0.00275 | 0.0557192 | 0.0557192 | Material Properties - Membraan - waterdicht, ThermalConductivity: 0.2; Membraan - waterdicht, SpecificHeatCapacity: 1840 J/kg/K; Membraan - waterdicht, MassDensity: 1050 kg/m3; Membraan - waterdicht, Embodied Energy: 51 (MJ/kg); Membraan - waterdicht, Embodied Carbon: 0.38 (kgCO₂/kg); Membraan - waterdicht, Name: Membraan - waterdicht; Membraan - waterdicht, Participates in Collision Detection: yes
Steen - Cellenbeton | 1e verdieping | Steen - Cellenbeton | 1441.53 | 675 | 150 | 0.10125 | 2.05932 | 2.05932 | Material Properties - Steen - Cellenbeton, ThermalConductivity: 0.23; Steen - Cellenbeton, SpecificHeatCapacity: 840 J/kg/K; Steen - Cellenbeton, MassDensity: 700 kg/m3; Steen - Cellenbeton, Embodied Energy: 0.75 (MJ/kg); Steen - Cellenbeton, Embodied Carbon: 0.1 (kgCO₂/kg); Steen - Cellenbeton, Name: Steen - Cellenbeton; Steen - Cellenbeton, Participates in Collision Detection: yes
Metaal - kleur buitenkozijnen | 1e verdieping | Metaal - kleur buitenkozijnen | 16.0616 |  |  | 0.000277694 | 0.00573629 | 0.00573629 | Material Properties - Metaal - kleur buitenkozijnen, ThermalConductivity: 160; Metaal - kleur buitenkozijnen, SpecificHeatCapacity: 880 J/kg/K; Metaal - kleur buitenkozijnen, MassDensity: 2800 kg/m3; Metaal - kleur buitenkozijnen, Embodied Energy: 155 (MJ/kg); Metaal - kleur buitenkozijnen, Embodied Carbon: 9.16 (kgCO₂/kg); Metaal - kleur buitenkozijnen, Name: Metaal - kleur buitenkozijnen; Metaal - kleur buitenkozijnen, Participates in Collision Detection: yes
Hout - Multiplex | 1e verdieping | Hout - Multiplex | 408.049 | 15 | 2800 | 0.0419999 | 0.582927 | 0.582927 | Material Properties - Hout - Multiplex, ThermalConductivity: 0.17; Hout - Multiplex, SpecificHeatCapacity: 1600 J/kg/K; Hout - Multiplex, MassDensity: 700 kg/m3; Hout - Multiplex, Embodied Energy: 15 (MJ/kg); Hout - Multiplex, Embodied Carbon: 0.77 (kgCO₂/kg); Hout - Multiplex, Name: Hout - Multiplex; Hout - Multiplex, Participates in Collision Detection: yes
Membraan - waterdicht | 1e verdieping | Membraan - waterdicht | 204.395 |  |  | 0.0140251 | 0.194662 | 0.194662 | Material Properties - Membraan - waterdicht, ThermalConductivity: 0.2; Membraan - waterdicht, SpecificHeatCapacity: 1840 J/kg/K; Membraan - waterdicht, MassDensity: 1050 kg/m3; Membraan - waterdicht, Embodied Energy: 51 (MJ/kg); Membraan - waterdicht, Embodied Carbon: 0.38 (kgCO₂/kg); Membraan - waterdicht, Name: Membraan - waterdicht; Membraan - waterdicht, Participates in Collision Detection: yes
Membraan - waterdicht | 1e verdieping | Membraan - waterdicht | 40.7027 | 550.007 | 5 | 0.00275003 | 0.0387645 | 0.0387645 | Material Properties - Membraan - waterdicht, ThermalConductivity: 0.2; Membraan - waterdicht, SpecificHeatCapacity: 1840 J/kg/K; Membraan - waterdicht, MassDensity: 1050 kg/m3; Membraan - waterdicht, Embodied Energy: 51 (MJ/kg); Membraan - waterdicht, Embodied Carbon: 0.38 (kgCO₂/kg); Membraan - waterdicht, Name: Membraan - waterdicht; Membraan - waterdicht, Participates in Collision Detection: yes
Steen - Cellenbeton | 1e verdieping | Steen - Cellenbeton | 999.065 | 675.007 | 150 | 0.101251 | 1.42724 | 1.42724 | Material Properties - Steen - Cellenbeton, ThermalConductivity: 0.23; Steen - Cellenbeton, SpecificHeatCapacity: 840 J/kg/K; Steen - Cellenbeton, MassDensity: 700 kg/m3; Steen - Cellenbeton, Embodied Energy: 0.75 (MJ/kg); Steen - Cellenbeton, Embodied Carbon: 0.1 (kgCO₂/kg); Steen - Cellenbeton, Name: Steen - Cellenbeton; Steen - Cellenbeton, Participates in Collision Detection: yes
Metaal - kleur buitenkozijnen | 1e verdieping | Metaal - kleur buitenkozijnen | 10.8942 |  |  | 0.000277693 | 0.00389079 | 0.00389079 | Material Properties - Metaal - kleur buitenkozijnen, ThermalConductivity: 160; Metaal - kleur buitenkozijnen, SpecificHeatCapacity: 880 J/kg/K; Metaal - kleur buitenkozijnen, MassDensity: 2800 kg/m3; Metaal - kleur buitenkozijnen, Embodied Energy: 155 (MJ/kg); Metaal - kleur buitenkozijnen, Embodied Carbon: 9.16 (kgCO₂/kg); Metaal - kleur buitenkozijnen, Name: Metaal - kleur buitenkozijnen; Metaal - kleur buitenkozijnen, Participates in Collision Detection: yes
Hout - Multiplex | 1e verdieping | Hout - Multiplex | 5.70544 | 15 | 230 | 0.00345 | 0.00815063 | 0.00815063 | Material Properties - Hout - Multiplex, ThermalConductivity: 0.17; Hout - Multiplex, SpecificHeatCapacity: 1600 J/kg/K; Hout - Multiplex, MassDensity: 700 kg/m3; Hout - Multiplex, Embodied Energy: 15 (MJ/kg); Hout - Multiplex, Embodied Carbon: 0.77 (kgCO₂/kg); Hout - Multiplex, Name: Hout - Multiplex; Hout - Multiplex, Participates in Collision Detection: yes
Membraan - waterdicht | 1e verdieping | Membraan - waterdicht | 2.85128 | 5 | 230 | 0.00115 | 0.0027155 | 0.0027155 | Material Properties - Membraan - waterdicht, ThermalConductivity: 0.2; Membraan - waterdicht, SpecificHeatCapacity: 1840 J/kg/K; Membraan - waterdicht, MassDensity: 1050 kg/m3; Membraan - waterdicht, Embodied Energy: 51 (MJ/kg); Membraan - waterdicht, Embodied Carbon: 0.38 (kgCO₂/kg); Membraan - waterdicht, Name: Membraan - waterdicht; Membraan - waterdicht, Participates in Collision Detection: yes
Metaal - kleur buitenkozijnen | 1e verdieping | Metaal - kleur buitenkozijnen | 1.83406 |  |  | 0.000277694 | 0.000655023 | 0.000655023 | Material Properties - Metaal - kleur buitenkozijnen, ThermalConductivity: 160; Metaal - kleur buitenkozijnen, SpecificHeatCapacity: 880 J/kg/K; Metaal - kleur buitenkozijnen, MassDensity: 2800 kg/m3; Metaal - kleur buitenkozijnen, Embodied Energy: 155 (MJ/kg); Metaal - kleur buitenkozijnen, Embodied Carbon: 9.16 (kgCO₂/kg); Metaal - kleur buitenkozijnen, Name: Metaal - kleur buitenkozijnen; Metaal - kleur buitenkozijnen, Participates in Collision Detection: yes
Hout - Multiplex | 1e verdieping | Hout - Multiplex | 294.315 | 15 | 4250 | 0.0637501 | 0.42045 | 0.42045 | Material Properties - Hout - Multiplex, ThermalConductivity: 0.17; Hout - Multiplex, SpecificHeatCapacity: 1600 J/kg/K; Hout - Multiplex, MassDensity: 700 kg/m3; Hout - Multiplex, Embodied Energy: 15 (MJ/kg); Hout - Multiplex, Embodied Carbon: 0.77 (kgCO₂/kg); Hout - Multiplex, Name: Hout - Multiplex; Hout - Multiplex, Participates in Collision Detection: yes
Membraan - waterdicht | 1e verdieping | Membraan - waterdicht | 147.157 | 5 | 4250 | 0.02125 | 0.14015 | 0.14015 | Material Properties - Membraan - waterdicht, ThermalConductivity: 0.2; Membraan - waterdicht, SpecificHeatCapacity: 1840 J/kg/K; Membraan - waterdicht, MassDensity: 1050 kg/m3; Membraan - waterdicht, Embodied Energy: 51 (MJ/kg); Membraan - waterdicht, Embodied Carbon: 0.38 (kgCO₂/kg); Membraan - waterdicht, Name: Membraan - waterdicht; Membraan - waterdicht, Participates in Collision Detection: yes
Metaal - kleur buitenkozijnen | 1e verdieping | Metaal - kleur buitenkozijnen | 6.07323 |  |  | 0.000277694 | 0.00216901 | 0.00216901 | Material Properties - Metaal - kleur buitenkozijnen, ThermalConductivity: 160; Metaal - kleur buitenkozijnen, SpecificHeatCapacity: 880 J/kg/K; Metaal - kleur buitenkozijnen, MassDensity: 2800 kg/m3; Metaal - kleur buitenkozijnen, Embodied Energy: 155 (MJ/kg); Metaal - kleur buitenkozijnen, Embodied Carbon: 9.16 (kgCO₂/kg); Metaal - kleur buitenkozijnen, Name: Metaal - kleur buitenkozijnen; Metaal - kleur buitenkozijnen, Participates in Collision Detection: yes
Hout - Multiplex | 1e verdieping | Hout - Multiplex | 417.751 | 15 | 2450 | 0.03675 | 0.596787 | 0.596787 | Material Properties - Hout - Multiplex, ThermalConductivity: 0.17; Hout - Multiplex, SpecificHeatCapacity: 1600 J/kg/K; Hout - Multiplex, MassDensity: 700 kg/m3; Hout - Multiplex, Embodied Energy: 15 (MJ/kg); Hout - Multiplex, Embodied Carbon: 0.77 (kgCO₂/kg); Hout - Multiplex, Name: Hout - Multiplex; Hout - Multiplex, Participates in Collision Detection: yes
Membraan - waterdicht | 1e verdieping | Membraan - waterdicht | 208.875 | 5 | 2450 | 0.01225 | 0.198929 | 0.198929 | Material Properties - Membraan - waterdicht, ThermalConductivity: 0.2; Membraan - waterdicht, SpecificHeatCapacity: 1840 J/kg/K; Membraan - waterdicht, MassDensity: 1050 kg/m3; Membraan - waterdicht, Embodied Energy: 51 (MJ/kg); Membraan - waterdicht, Embodied Carbon: 0.38 (kgCO₂/kg); Membraan - waterdicht, Name: Membraan - waterdicht; Membraan - waterdicht, Participates in Collision Detection: yes
Metaal - kleur buitenkozijnen | 1e verdieping | Metaal - kleur buitenkozijnen | 15.1946 |  |  | 0.000277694 | 0.00542665 | 0.00542665 | Material Properties - Metaal - kleur buitenkozijnen, ThermalConductivity: 160; Metaal - kleur buitenkozijnen, SpecificHeatCapacity: 880 J/kg/K; Metaal - kleur buitenkozijnen, MassDensity: 2800 kg/m3; Metaal - kleur buitenkozijnen, Embodied Energy: 155 (MJ/kg); Metaal - kleur buitenkozijnen, Embodied Carbon: 9.16 (kgCO₂/kg); Metaal - kleur buitenkozijnen, Name: Metaal - kleur buitenkozijnen; Metaal - kleur buitenkozijnen, Participates in Collision Detection: yes
Hout - Multiplex | 1e verdieping | Hout - Multiplex | 389.524 | 15 | 2450 | 0.03675 | 0.556463 | 0.556463 | Material Properties - Hout - Multiplex, ThermalConductivity: 0.17; Hout - Multiplex, SpecificHeatCapacity: 1600 J/kg/K; Hout - Multiplex, MassDensity: 700 kg/m3; Hout - Multiplex, Embodied Energy: 15 (MJ/kg); Hout - Multiplex, Embodied Carbon: 0.77 (kgCO₂/kg); Hout - Multiplex, Name: Hout - Multiplex; Hout - Multiplex, Participates in Collision Detection: yes
Membraan - waterdicht | 1e verdieping | Membraan - waterdicht | 194.776 | 5 | 2450 | 0.01225 | 0.185501 | 0.185501 | Material Properties - Membraan - waterdicht, ThermalConductivity: 0.2; Membraan - waterdicht, SpecificHeatCapacity: 1840 J/kg/K; Membraan - waterdicht, MassDensity: 1050 kg/m3; Membraan - waterdicht, Embodied Energy: 51 (MJ/kg); Membraan - waterdicht, Embodied Carbon: 0.38 (kgCO₂/kg); Membraan - waterdicht, Name: Membraan - waterdicht; Membraan - waterdicht, Participates in Collision Detection: yes
Metaal - kleur buitenkozijnen | 1e verdieping | Metaal - kleur buitenkozijnen | 12.8347 |  |  | 0.000277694 | 0.00458381 | 0.00458381 | Material Properties - Metaal - kleur buitenkozijnen, ThermalConductivity: 160; Metaal - kleur buitenkozijnen, SpecificHeatCapacity: 880 J/kg/K; Metaal - kleur buitenkozijnen, MassDensity: 2800 kg/m3; Metaal - kleur buitenkozijnen, Embodied Energy: 155 (MJ/kg); Metaal - kleur buitenkozijnen, Embodied Carbon: 9.16 (kgCO₂/kg); Metaal - kleur buitenkozijnen, Name: Metaal - kleur buitenkozijnen; Metaal - kleur buitenkozijnen, Participates in Collision Detection: yes
Hout - Multiplex | 1e verdieping | Hout - Multiplex | 5.70542 | 15 | 230 | 0.00345 | 0.0081506 | 0.0081506 | Material Properties - Hout - Multiplex, ThermalConductivity: 0.17; Hout - Multiplex, SpecificHeatCapacity: 1600 J/kg/K; Hout - Multiplex, MassDensity: 700 kg/m3; Hout - Multiplex, Embodied Energy: 15 (MJ/kg); Hout - Multiplex, Embodied Carbon: 0.77 (kgCO₂/kg); Hout - Multiplex, Name: Hout - Multiplex; Hout - Multiplex, Participates in Collision Detection: yes
Membraan - waterdicht | 1e verdieping | Membraan - waterdicht | 2.85188 | 5 | 230 | 0.00115 | 0.00271607 | 0.00271607 | Material Properties - Membraan - waterdicht, ThermalConductivity: 0.2; Membraan - waterdicht, SpecificHeatCapacity: 1840 J/kg/K; Membraan - waterdicht, MassDensity: 1050 kg/m3; Membraan - waterdicht, Embodied Energy: 51 (MJ/kg); Membraan - waterdicht, Embodied Carbon: 0.38 (kgCO₂/kg); Membraan - waterdicht, Name: Membraan - waterdicht; Membraan - waterdicht, Participates in Collision Detection: yes
Metaal - kleur buitenkozijnen | 1e verdieping | Metaal - kleur buitenkozijnen | 1.83406 |  |  | 0.000277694 | 0.00065502 | 0.00065502 | Material Properties - Metaal - kleur buitenkozijnen, ThermalConductivity: 160; Metaal - kleur buitenkozijnen, SpecificHeatCapacity: 880 J/kg/K; Metaal - kleur buitenkozijnen, MassDensity: 2800 kg/m3; Metaal - kleur buitenkozijnen, Embodied Energy: 155 (MJ/kg); Metaal - kleur buitenkozijnen, Embodied Carbon: 9.16 (kgCO₂/kg); Metaal - kleur buitenkozijnen, Name: Metaal - kleur buitenkozijnen; Metaal - kleur buitenkozijnen, Participates in Collision Detection: yes
Hout - Multiplex | 1e verdieping | Hout - Multiplex | 5.97429 | 15 | 436 | 0.00654 | 0.00853471 | 0.00853471 | Material Properties - Hout - Multiplex, ThermalConductivity: 0.17; Hout - Multiplex, SpecificHeatCapacity: 1600 J/kg/K; Hout - Multiplex, MassDensity: 700 kg/m3; Hout - Multiplex, Embodied Energy: 15 (MJ/kg); Hout - Multiplex, Embodied Carbon: 0.77 (kgCO₂/kg); Hout - Multiplex, Name: Hout - Multiplex; Hout - Multiplex, Participates in Collision Detection: yes
Membraan - waterdicht | 1e verdieping | Membraan - waterdicht | 3.0214 | 5 | 441 | 0.002205 | 0.00287753 | 0.00287753 | Material Properties - Membraan - waterdicht, ThermalConductivity: 0.2; Membraan - waterdicht, SpecificHeatCapacity: 1840 J/kg/K; Membraan - waterdicht, MassDensity: 1050 kg/m3; Membraan - waterdicht, Embodied Energy: 51 (MJ/kg); Membraan - waterdicht, Embodied Carbon: 0.38 (kgCO₂/kg); Membraan - waterdicht, Name: Membraan - waterdicht; Membraan - waterdicht, Participates in Collision Detection: yes
Membraan - waterdicht | 1e verdieping | Membraan - waterdicht | 1.67856 | 245 | 5 | 0.001225 | 0.00159863 | 0.00159863 | Material Properties - Membraan - waterdicht, ThermalConductivity: 0.2; Membraan - waterdicht, SpecificHeatCapacity: 1840 J/kg/K; Membraan - waterdicht, MassDensity: 1050 kg/m3; Membraan - waterdicht, Embodied Energy: 51 (MJ/kg); Membraan - waterdicht, Embodied Carbon: 0.38 (kgCO₂/kg); Membraan - waterdicht, Name: Membraan - waterdicht; Membraan - waterdicht, Participates in Collision Detection: yes
Steen - Cellenbeton | 1e verdieping | Steen - Cellenbeton | 92.4919 | 675 | 150 | 0.10125 | 0.132131 | 0.132131 | Material Properties - Steen - Cellenbeton, ThermalConductivity: 0.23; Steen - Cellenbeton, SpecificHeatCapacity: 840 J/kg/K; Steen - Cellenbeton, MassDensity: 700 kg/m3; Steen - Cellenbeton, Embodied Energy: 0.75 (MJ/kg); Steen - Cellenbeton, Embodied Carbon: 0.1 (kgCO₂/kg); Steen - Cellenbeton, Name: Steen - Cellenbeton; Steen - Cellenbeton, Participates in Collision Detection: yes
Hout - Multiplex | 1e verdieping | Hout - Multiplex | 15.4147 | 15 | 286.003 | 0.00429005 | 0.0220211 | 0.0220211 | Material Properties - Hout - Multiplex, ThermalConductivity: 0.17; Hout - Multiplex, SpecificHeatCapacity: 1600 J/kg/K; Hout - Multiplex, MassDensity: 700 kg/m3; Hout - Multiplex, Embodied Energy: 15 (MJ/kg); Hout - Multiplex, Embodied Carbon: 0.77 (kgCO₂/kg); Hout - Multiplex, Name: Hout - Multiplex; Hout - Multiplex, Participates in Collision Detection: yes
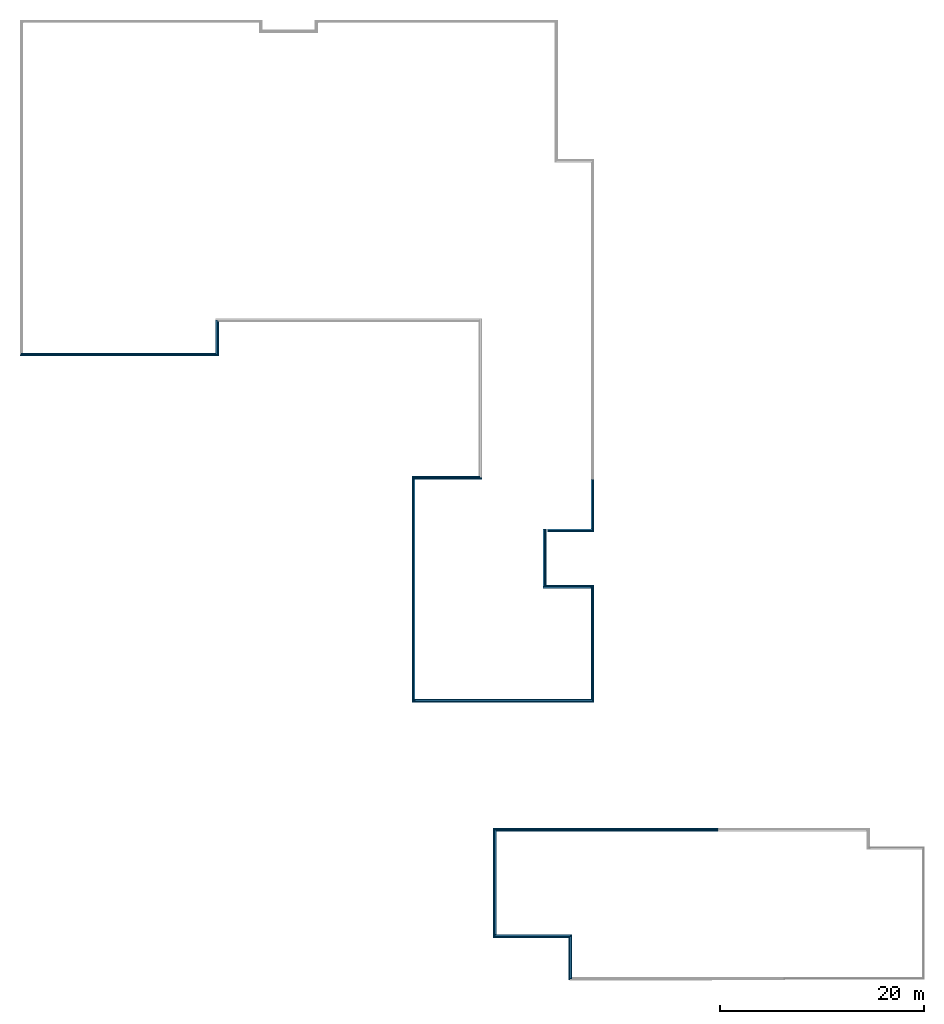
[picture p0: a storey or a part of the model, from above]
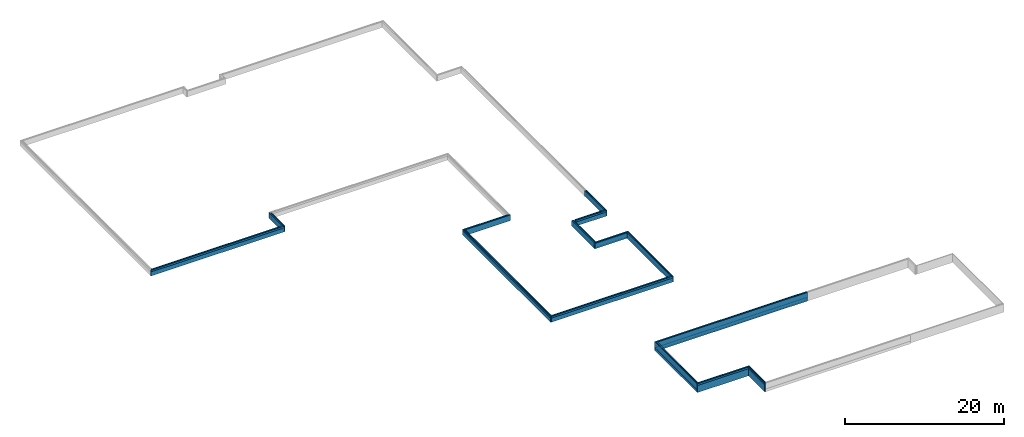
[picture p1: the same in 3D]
Properties of the parts of a building model (IFC2X3), part 12 of 19

# IfcBuildingElementPart (2070)
Name | In | Material | Mass (kg) | Rectangular Component Height (mm) | Rectangular Component Width (mm) | Component Cross Section Area (m2) | Component Volume (Net) (m3) | Component Volume (Gross) (m3)
Membraan - waterdicht | 1e verdieping | Membraan - waterdicht | 7.84126 | 5 | 291.003 | 0.00145502 | 0.00746787 | 0.00746787 | Material Properties - Membraan - waterdicht, ThermalConductivity: 0.2; Membraan - waterdicht, SpecificHeatCapacity: 1840 J/kg/K; Membraan - waterdicht, MassDensity: 1050 kg/m3; Membraan - waterdicht, Embodied Energy: 51 (MJ/kg); Membraan - waterdicht, Embodied Carbon: 0.38 (kgCO₂/kg); Membraan - waterdicht, Name: Membraan - waterdicht; Membraan - waterdicht, Participates in Collision Detection: yes
Membraan - waterdicht | 1e verdieping | Membraan - waterdicht | 8.08716 | 302.008 | 5 | 0.00151004 | 0.00770205 | 0.00770205 | Material Properties - Membraan - waterdicht, ThermalConductivity: 0.2; Membraan - waterdicht, SpecificHeatCapacity: 1840 J/kg/K; Membraan - waterdicht, MassDensity: 1050 kg/m3; Membraan - waterdicht, Embodied Energy: 51 (MJ/kg); Membraan - waterdicht, Embodied Carbon: 0.38 (kgCO₂/kg); Membraan - waterdicht, Name: Membraan - waterdicht; Membraan - waterdicht, Participates in Collision Detection: yes
Isolatie - Steenwol hard | 1e verdieping | Isolatie - Steenwol hard | 72.1015 | 587.008 | 150 | 0.0880512 | 0.450635 | 0.450635 | Material Properties - Isolatie - Steenwol hard, ThermalConductivity: 0.043; Isolatie - Steenwol hard, SpecificHeatCapacity: 840 J/kg/K; Isolatie - Steenwol hard, MassDensity: 160 kg/m3; Isolatie - Steenwol hard, Embodied Energy: 16.8 (MJ/kg); Isolatie - Steenwol hard, Embodied Carbon: 1.05 (kgCO₂/kg); Isolatie - Steenwol hard, Name: Isolatie - Steenwol hard; Isolatie - Steenwol hard, Participates in Collision Detection: yes
Hout - Multiplex | 1e verdieping | Hout - Multiplex | 46.2567 | 15 | 351 | 0.005265 | 0.066081 | 0.066081 | Material Properties - Hout - Multiplex, ThermalConductivity: 0.17; Hout - Multiplex, SpecificHeatCapacity: 1600 J/kg/K; Hout - Multiplex, MassDensity: 700 kg/m3; Hout - Multiplex, Embodied Energy: 15 (MJ/kg); Hout - Multiplex, Embodied Carbon: 0.77 (kgCO₂/kg); Hout - Multiplex, Name: Hout - Multiplex; Hout - Multiplex, Participates in Collision Detection: yes
Membraan - waterdicht | 1e verdieping | Membraan - waterdicht | 23.4485 | 5 | 356 | 0.00178 | 0.0223319 | 0.0223319 | Material Properties - Membraan - waterdicht, ThermalConductivity: 0.2; Membraan - waterdicht, SpecificHeatCapacity: 1840 J/kg/K; Membraan - waterdicht, MassDensity: 1050 kg/m3; Membraan - waterdicht, Embodied Energy: 51 (MJ/kg); Membraan - waterdicht, Embodied Carbon: 0.38 (kgCO₂/kg); Membraan - waterdicht, Name: Membraan - waterdicht; Membraan - waterdicht, Participates in Collision Detection: yes
Membraan - waterdicht | 1e verdieping | Membraan - waterdicht | 19.3357 | 302.008 | 5 | 0.00151004 | 0.018415 | 0.018415 | Material Properties - Membraan - waterdicht, ThermalConductivity: 0.2; Membraan - waterdicht, SpecificHeatCapacity: 1840 J/kg/K; Membraan - waterdicht, MassDensity: 1050 kg/m3; Membraan - waterdicht, Embodied Energy: 51 (MJ/kg); Membraan - waterdicht, Embodied Carbon: 0.38 (kgCO₂/kg); Membraan - waterdicht, Name: Membraan - waterdicht; Membraan - waterdicht, Participates in Collision Detection: yes
Isolatie - Steenwol hard | 1e verdieping | Isolatie - Steenwol hard | 173.989 | 587.008 | 150 | 0.0880513 | 1.08743 | 1.08743 | Material Properties - Isolatie - Steenwol hard, ThermalConductivity: 0.043; Isolatie - Steenwol hard, SpecificHeatCapacity: 840 J/kg/K; Isolatie - Steenwol hard, MassDensity: 160 kg/m3; Isolatie - Steenwol hard, Embodied Energy: 16.8 (MJ/kg); Isolatie - Steenwol hard, Embodied Carbon: 1.05 (kgCO₂/kg); Isolatie - Steenwol hard, Name: Isolatie - Steenwol hard; Isolatie - Steenwol hard, Participates in Collision Detection: yes
Hout - Multiplex | 1e verdieping | Hout - Multiplex | 20.7053 | 15 | 351 | 0.005265 | 0.029579 | 0.029579 | Material Properties - Hout - Multiplex, ThermalConductivity: 0.17; Hout - Multiplex, SpecificHeatCapacity: 1600 J/kg/K; Hout - Multiplex, MassDensity: 700 kg/m3; Hout - Multiplex, Embodied Energy: 15 (MJ/kg); Hout - Multiplex, Embodied Carbon: 0.77 (kgCO₂/kg); Hout - Multiplex, Name: Hout - Multiplex; Hout - Multiplex, Participates in Collision Detection: yes
Membraan - waterdicht | 1e verdieping | Membraan - waterdicht | 10.4916 | 5 | 356 | 0.00178 | 0.00999202 | 0.00999202 | Material Properties - Membraan - waterdicht, ThermalConductivity: 0.2; Membraan - waterdicht, SpecificHeatCapacity: 1840 J/kg/K; Membraan - waterdicht, MassDensity: 1050 kg/m3; Membraan - waterdicht, Embodied Energy: 51 (MJ/kg); Membraan - waterdicht, Embodied Carbon: 0.38 (kgCO₂/kg); Membraan - waterdicht, Name: Membraan - waterdicht; Membraan - waterdicht, Participates in Collision Detection: yes
Membraan - waterdicht | 1e verdieping | Membraan - waterdicht | 8.39467 | 302.007 | 4.99999 | 0.00151003 | 0.00799493 | 0.00799493 | Material Properties - Membraan - waterdicht, ThermalConductivity: 0.2; Membraan - waterdicht, SpecificHeatCapacity: 1840 J/kg/K; Membraan - waterdicht, MassDensity: 1050 kg/m3; Membraan - waterdicht, Embodied Energy: 51 (MJ/kg); Membraan - waterdicht, Embodied Carbon: 0.38 (kgCO₂/kg); Membraan - waterdicht, Name: Membraan - waterdicht; Membraan - waterdicht, Participates in Collision Detection: yes
Isolatie - Steenwol hard | 1e verdieping | Isolatie - Steenwol hard | 76.5747 | 587.007 | 150 | 0.088051 | 0.478592 | 0.478592 | Material Properties - Isolatie - Steenwol hard, ThermalConductivity: 0.043; Isolatie - Steenwol hard, SpecificHeatCapacity: 840 J/kg/K; Isolatie - Steenwol hard, MassDensity: 160 kg/m3; Isolatie - Steenwol hard, Embodied Energy: 16.8 (MJ/kg); Isolatie - Steenwol hard, Embodied Carbon: 1.05 (kgCO₂/kg); Isolatie - Steenwol hard, Name: Isolatie - Steenwol hard; Isolatie - Steenwol hard, Participates in Collision Detection: yes
Hout - Multiplex | 1e verdieping | Hout - Multiplex | 50.3904 | 15 | 351 | 0.005265 | 0.0719863 | 0.0719863 | Material Properties - Hout - Multiplex, ThermalConductivity: 0.17; Hout - Multiplex, SpecificHeatCapacity: 1600 J/kg/K; Hout - Multiplex, MassDensity: 700 kg/m3; Hout - Multiplex, Embodied Energy: 15 (MJ/kg); Hout - Multiplex, Embodied Carbon: 0.77 (kgCO₂/kg); Hout - Multiplex, Name: Hout - Multiplex; Hout - Multiplex, Participates in Collision Detection: yes
Membraan - waterdicht | 1e verdieping | Membraan - waterdicht | 25.5455 | 5 | 356 | 0.00178 | 0.024329 | 0.024329 | Material Properties - Membraan - waterdicht, ThermalConductivity: 0.2; Membraan - waterdicht, SpecificHeatCapacity: 1840 J/kg/K; Membraan - waterdicht, MassDensity: 1050 kg/m3; Membraan - waterdicht, Embodied Energy: 51 (MJ/kg); Membraan - waterdicht, Embodied Carbon: 0.38 (kgCO₂/kg); Membraan - waterdicht, Name: Membraan - waterdicht; Membraan - waterdicht, Participates in Collision Detection: yes
Membraan - waterdicht | 1e verdieping | Membraan - waterdicht | 21.1583 | 302.007 | 4.99999 | 0.00151003 | 0.0201508 | 0.0201508 | Material Properties - Membraan - waterdicht, ThermalConductivity: 0.2; Membraan - waterdicht, SpecificHeatCapacity: 1840 J/kg/K; Membraan - waterdicht, MassDensity: 1050 kg/m3; Membraan - waterdicht, Embodied Energy: 51 (MJ/kg); Membraan - waterdicht, Embodied Carbon: 0.38 (kgCO₂/kg); Membraan - waterdicht, Name: Membraan - waterdicht; Membraan - waterdicht, Participates in Collision Detection: yes
Isolatie - Steenwol hard | 1e verdieping | Isolatie - Steenwol hard | 190.013 | 587.007 | 150 | 0.088051 | 1.18758 | 1.18758 | Material Properties - Isolatie - Steenwol hard, ThermalConductivity: 0.043; Isolatie - Steenwol hard, SpecificHeatCapacity: 840 J/kg/K; Isolatie - Steenwol hard, MassDensity: 160 kg/m3; Isolatie - Steenwol hard, Embodied Energy: 16.8 (MJ/kg); Isolatie - Steenwol hard, Embodied Carbon: 1.05 (kgCO₂/kg); Isolatie - Steenwol hard, Name: Isolatie - Steenwol hard; Isolatie - Steenwol hard, Participates in Collision Detection: yes
Hout - Multiplex | 1e verdieping | Hout - Multiplex | 22.9804 | 15 | 295.005 | 0.00442507 | 0.0328291 | 0.0328291 | Material Properties - Hout - Multiplex, ThermalConductivity: 0.17; Hout - Multiplex, SpecificHeatCapacity: 1600 J/kg/K; Hout - Multiplex, MassDensity: 700 kg/m3; Hout - Multiplex, Embodied Energy: 15 (MJ/kg); Hout - Multiplex, Embodied Carbon: 0.77 (kgCO₂/kg); Hout - Multiplex, Name: Hout - Multiplex; Hout - Multiplex, Participates in Collision Detection: yes
Membraan - waterdicht | 1e verdieping | Membraan - waterdicht | 11.6764 | 5 | 300.005 | 0.00150002 | 0.0111204 | 0.0111204 | Material Properties - Membraan - waterdicht, ThermalConductivity: 0.2; Membraan - waterdicht, SpecificHeatCapacity: 1840 J/kg/K; Membraan - waterdicht, MassDensity: 1050 kg/m3; Membraan - waterdicht, Embodied Energy: 51 (MJ/kg); Membraan - waterdicht, Embodied Carbon: 0.38 (kgCO₂/kg); Membraan - waterdicht, Name: Membraan - waterdicht; Membraan - waterdicht, Participates in Collision Detection: yes
Membraan - waterdicht | 1e verdieping | Membraan - waterdicht | 11.2501 | 302.01 | 5 | 0.00151005 | 0.0107144 | 0.0107144 | Material Properties - Membraan - waterdicht, ThermalConductivity: 0.2; Membraan - waterdicht, SpecificHeatCapacity: 1840 J/kg/K; Membraan - waterdicht, MassDensity: 1050 kg/m3; Membraan - waterdicht, Embodied Energy: 51 (MJ/kg); Membraan - waterdicht, Embodied Carbon: 0.38 (kgCO₂/kg); Membraan - waterdicht, Name: Membraan - waterdicht; Membraan - waterdicht, Participates in Collision Detection: yes
Isolatie - Steenwol hard | 1e verdieping | Isolatie - Steenwol hard | 102.316 | 587.01 | 150 | 0.0880514 | 0.639476 | 0.639476 | Material Properties - Isolatie - Steenwol hard, ThermalConductivity: 0.043; Isolatie - Steenwol hard, SpecificHeatCapacity: 840 J/kg/K; Isolatie - Steenwol hard, MassDensity: 160 kg/m3; Isolatie - Steenwol hard, Embodied Energy: 16.8 (MJ/kg); Isolatie - Steenwol hard, Embodied Carbon: 1.05 (kgCO₂/kg); Isolatie - Steenwol hard, Name: Isolatie - Steenwol hard; Isolatie - Steenwol hard, Participates in Collision Detection: yes
Hout - Multiplex | 1e verdieping | Hout - Multiplex | 24.1882 | 15 | 286.003 | 0.00429005 | 0.0345545 | 0.0345545 | Material Properties - Hout - Multiplex, ThermalConductivity: 0.17; Hout - Multiplex, SpecificHeatCapacity: 1600 J/kg/K; Hout - Multiplex, MassDensity: 700 kg/m3; Hout - Multiplex, Embodied Energy: 15 (MJ/kg); Hout - Multiplex, Embodied Carbon: 0.77 (kgCO₂/kg); Hout - Multiplex, Name: Hout - Multiplex; Hout - Multiplex, Participates in Collision Detection: yes
Membraan - waterdicht | 1e verdieping | Membraan - waterdicht | 12.3054 | 5 | 291.003 | 0.00145502 | 0.0117194 | 0.0117194 | Material Properties - Membraan - waterdicht, ThermalConductivity: 0.2; Membraan - waterdicht, SpecificHeatCapacity: 1840 J/kg/K; Membraan - waterdicht, MassDensity: 1050 kg/m3; Membraan - waterdicht, Embodied Energy: 51 (MJ/kg); Membraan - waterdicht, Embodied Carbon: 0.38 (kgCO₂/kg); Membraan - waterdicht, Name: Membraan - waterdicht; Membraan - waterdicht, Participates in Collision Detection: yes
Membraan - waterdicht | 1e verdieping | Membraan - waterdicht | 12.7637 | 302.008 | 5 | 0.00151004 | 0.0121559 | 0.0121559 | Material Properties - Membraan - waterdicht, ThermalConductivity: 0.2; Membraan - waterdicht, SpecificHeatCapacity: 1840 J/kg/K; Membraan - waterdicht, MassDensity: 1050 kg/m3; Membraan - waterdicht, Embodied Energy: 51 (MJ/kg); Membraan - waterdicht, Embodied Carbon: 0.38 (kgCO₂/kg); Membraan - waterdicht, Name: Membraan - waterdicht; Membraan - waterdicht, Participates in Collision Detection: yes
Isolatie - Steenwol hard | 1e verdieping | Isolatie - Steenwol hard | 113.445 | 587.008 | 150 | 0.0880512 | 0.70903 | 0.70903 | Material Properties - Isolatie - Steenwol hard, ThermalConductivity: 0.043; Isolatie - Steenwol hard, SpecificHeatCapacity: 840 J/kg/K; Isolatie - Steenwol hard, MassDensity: 160 kg/m3; Isolatie - Steenwol hard, Embodied Energy: 16.8 (MJ/kg); Isolatie - Steenwol hard, Embodied Carbon: 1.05 (kgCO₂/kg); Isolatie - Steenwol hard, Name: Isolatie - Steenwol hard; Isolatie - Steenwol hard, Participates in Collision Detection: yes
Hout - Multiplex | 1e verdieping | Hout - Multiplex | 157.832 | 15 | 588.5 | 0.00882751 | 0.225474 | 0.225474 | Material Properties - Hout - Multiplex, ThermalConductivity: 0.17; Hout - Multiplex, SpecificHeatCapacity: 1600 J/kg/K; Hout - Multiplex, MassDensity: 700 kg/m3; Hout - Multiplex, Embodied Energy: 15 (MJ/kg); Hout - Multiplex, Embodied Carbon: 0.77 (kgCO₂/kg); Hout - Multiplex, Name: Hout - Multiplex; Hout - Multiplex, Participates in Collision Detection: yes
Membraan - waterdicht | 1e verdieping | Membraan - waterdicht | 78.9107 | 5 | 588.5 | 0.0029425 | 0.075153 | 0.075153 | Material Properties - Membraan - waterdicht, ThermalConductivity: 0.2; Membraan - waterdicht, SpecificHeatCapacity: 1840 J/kg/K; Membraan - waterdicht, MassDensity: 1050 kg/m3; Membraan - waterdicht, Embodied Energy: 51 (MJ/kg); Membraan - waterdicht, Embodied Carbon: 0.38 (kgCO₂/kg); Membraan - waterdicht, Name: Membraan - waterdicht; Membraan - waterdicht, Participates in Collision Detection: yes
Metaal - kleur buitenkozijnen | 1e verdieping | Metaal - kleur buitenkozijnen | 19.8179 |  |  | 0.000277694 | 0.0070778 | 0.0070778 | Material Properties - Metaal - kleur buitenkozijnen, ThermalConductivity: 160; Metaal - kleur buitenkozijnen, SpecificHeatCapacity: 880 J/kg/K; Metaal - kleur buitenkozijnen, MassDensity: 2800 kg/m3; Metaal - kleur buitenkozijnen, Embodied Energy: 155 (MJ/kg); Metaal - kleur buitenkozijnen, Embodied Carbon: 9.16 (kgCO₂/kg); Metaal - kleur buitenkozijnen, Name: Metaal - kleur buitenkozijnen; Metaal - kleur buitenkozijnen, Participates in Collision Detection: yes
Hout - Multiplex | 1e verdieping | Hout - Multiplex | 13.2974 | 15 | 363 | 0.005445 | 0.0189962 | 0.0189962 | Material Properties - Hout - Multiplex, ThermalConductivity: 0.17; Hout - Multiplex, SpecificHeatCapacity: 1600 J/kg/K; Hout - Multiplex, MassDensity: 700 kg/m3; Hout - Multiplex, Embodied Energy: 15 (MJ/kg); Hout - Multiplex, Embodied Carbon: 0.77 (kgCO₂/kg); Hout - Multiplex, Name: Hout - Multiplex; Hout - Multiplex, Participates in Collision Detection: yes
Membraan - waterdicht | 1e verdieping | Membraan - waterdicht | 6.64868 | 5 | 363 | 0.001815 | 0.00633208 | 0.00633208 | Material Properties - Membraan - waterdicht, ThermalConductivity: 0.2; Membraan - waterdicht, SpecificHeatCapacity: 1840 J/kg/K; Membraan - waterdicht, MassDensity: 1050 kg/m3; Membraan - waterdicht, Embodied Energy: 51 (MJ/kg); Membraan - waterdicht, Embodied Carbon: 0.38 (kgCO₂/kg); Membraan - waterdicht, Name: Membraan - waterdicht; Membraan - waterdicht, Participates in Collision Detection: yes
Metaal - kleur buitenkozijnen | 1e verdieping | Metaal - kleur buitenkozijnen | 2.3188 |  |  | 0.000277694 | 0.000828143 | 0.000828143 | Material Properties - Metaal - kleur buitenkozijnen, ThermalConductivity: 160; Metaal - kleur buitenkozijnen, SpecificHeatCapacity: 880 J/kg/K; Metaal - kleur buitenkozijnen, MassDensity: 2800 kg/m3; Metaal - kleur buitenkozijnen, Embodied Energy: 155 (MJ/kg); Metaal - kleur buitenkozijnen, Embodied Carbon: 9.16 (kgCO₂/kg); Metaal - kleur buitenkozijnen, Name: Metaal - kleur buitenkozijnen; Metaal - kleur buitenkozijnen, Participates in Collision Detection: yes
Hout - Multiplex | 1e verdieping | Hout - Multiplex | 93.1737 | 15 | 1526 | 0.02289 | 0.133105 | 0.133105 | Material Properties - Hout - Multiplex, ThermalConductivity: 0.17; Hout - Multiplex, SpecificHeatCapacity: 1600 J/kg/K; Hout - Multiplex, MassDensity: 700 kg/m3; Hout - Multiplex, Embodied Energy: 15 (MJ/kg); Hout - Multiplex, Embodied Carbon: 0.77 (kgCO₂/kg); Hout - Multiplex, Name: Hout - Multiplex; Hout - Multiplex, Participates in Collision Detection: yes
Membraan - waterdicht | 1e verdieping | Membraan - waterdicht | 46.7445 |  |  | 0.00765498 | 0.0445186 | 0.0445186 | Material Properties - Membraan - waterdicht, ThermalConductivity: 0.2; Membraan - waterdicht, SpecificHeatCapacity: 1840 J/kg/K; Membraan - waterdicht, MassDensity: 1050 kg/m3; Membraan - waterdicht, Embodied Energy: 51 (MJ/kg); Membraan - waterdicht, Embodied Carbon: 0.38 (kgCO₂/kg); Membraan - waterdicht, Name: Membraan - waterdicht; Membraan - waterdicht, Participates in Collision Detection: yes
Membraan - waterdicht | 1e verdieping | Membraan - waterdicht | 12.2997 | 390 | 5 | 0.00195 | 0.011714 | 0.011714 | Material Properties - Membraan - waterdicht, ThermalConductivity: 0.2; Membraan - waterdicht, SpecificHeatCapacity: 1840 J/kg/K; Membraan - waterdicht, MassDensity: 1050 kg/m3; Membraan - waterdicht, Embodied Energy: 51 (MJ/kg); Membraan - waterdicht, Embodied Carbon: 0.38 (kgCO₂/kg); Membraan - waterdicht, Name: Membraan - waterdicht; Membraan - waterdicht, Participates in Collision Detection: yes
Steen - Cellenbeton | 1e verdieping | Steen - Cellenbeton | 316.557 | 515 | 150 | 0.07725 | 0.452224 | 0.452224 | Material Properties - Steen - Cellenbeton, ThermalConductivity: 0.23; Steen - Cellenbeton, SpecificHeatCapacity: 840 J/kg/K; Steen - Cellenbeton, MassDensity: 700 kg/m3; Steen - Cellenbeton, Embodied Energy: 0.75 (MJ/kg); Steen - Cellenbeton, Embodied Carbon: 0.1 (kgCO₂/kg); Steen - Cellenbeton, Name: Steen - Cellenbeton; Steen - Cellenbeton, Participates in Collision Detection: yes
Metaal - kleur buitenkozijnen | 1e verdieping | Metaal - kleur buitenkozijnen | 4.662 |  |  | 0.000277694 | 0.001665 | 0.001665 | Material Properties - Metaal - kleur buitenkozijnen, ThermalConductivity: 160; Metaal - kleur buitenkozijnen, SpecificHeatCapacity: 880 J/kg/K; Metaal - kleur buitenkozijnen, MassDensity: 2800 kg/m3; Metaal - kleur buitenkozijnen, Embodied Energy: 155 (MJ/kg); Metaal - kleur buitenkozijnen, Embodied Carbon: 9.16 (kgCO₂/kg); Metaal - kleur buitenkozijnen, Name: Metaal - kleur buitenkozijnen; Metaal - kleur buitenkozijnen, Participates in Collision Detection: yes
Hout - Multiplex | 1e verdieping | Hout - Multiplex | 9.20793 | 15 | 220 | 0.0033 | 0.0131542 | 0.0131542 | Material Properties - Hout - Multiplex, ThermalConductivity: 0.17; Hout - Multiplex, SpecificHeatCapacity: 1600 J/kg/K; Hout - Multiplex, MassDensity: 700 kg/m3; Hout - Multiplex, Embodied Energy: 15 (MJ/kg); Hout - Multiplex, Embodied Carbon: 0.77 (kgCO₂/kg); Hout - Multiplex, Name: Hout - Multiplex; Hout - Multiplex, Participates in Collision Detection: yes
Membraan - waterdicht | 1e verdieping | Membraan - waterdicht | 4.60397 | 5 | 220 | 0.0011 | 0.00438473 | 0.00438473 | Material Properties - Membraan - waterdicht, ThermalConductivity: 0.2; Membraan - waterdicht, SpecificHeatCapacity: 1840 J/kg/K; Membraan - waterdicht, MassDensity: 1050 kg/m3; Membraan - waterdicht, Embodied Energy: 51 (MJ/kg); Membraan - waterdicht, Embodied Carbon: 0.38 (kgCO₂/kg); Membraan - waterdicht, Name: Membraan - waterdicht; Membraan - waterdicht, Participates in Collision Detection: yes
Metaal - kleur buitenkozijnen | 1e verdieping | Metaal - kleur buitenkozijnen | 3.17912 |  |  | 0.000277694 | 0.0011354 | 0.0011354 | Material Properties - Metaal - kleur buitenkozijnen, ThermalConductivity: 160; Metaal - kleur buitenkozijnen, SpecificHeatCapacity: 880 J/kg/K; Metaal - kleur buitenkozijnen, MassDensity: 2800 kg/m3; Metaal - kleur buitenkozijnen, Embodied Energy: 155 (MJ/kg); Metaal - kleur buitenkozijnen, Embodied Carbon: 9.16 (kgCO₂/kg); Metaal - kleur buitenkozijnen, Name: Metaal - kleur buitenkozijnen; Metaal - kleur buitenkozijnen, Participates in Collision Detection: yes
Hout - Multiplex | 1e verdieping | Hout - Multiplex | 8.54105 | 15 | 220 | 0.0033 | 0.0122015 | 0.0122015 | Material Properties - Hout - Multiplex, ThermalConductivity: 0.17; Hout - Multiplex, SpecificHeatCapacity: 1600 J/kg/K; Hout - Multiplex, MassDensity: 700 kg/m3; Hout - Multiplex, Embodied Energy: 15 (MJ/kg); Hout - Multiplex, Embodied Carbon: 0.77 (kgCO₂/kg); Hout - Multiplex, Name: Hout - Multiplex; Hout - Multiplex, Participates in Collision Detection: yes
Membraan - waterdicht | 1e verdieping | Membraan - waterdicht | 4.27053 | 5 | 220 | 0.0011 | 0.00406717 | 0.00406717 | Material Properties - Membraan - waterdicht, ThermalConductivity: 0.2; Membraan - waterdicht, SpecificHeatCapacity: 1840 J/kg/K; Membraan - waterdicht, MassDensity: 1050 kg/m3; Membraan - waterdicht, Embodied Energy: 51 (MJ/kg); Membraan - waterdicht, Embodied Carbon: 0.38 (kgCO₂/kg); Membraan - waterdicht, Name: Membraan - waterdicht; Membraan - waterdicht, Participates in Collision Detection: yes
Metaal - kleur buitenkozijnen | 1e verdieping | Metaal - kleur buitenkozijnen | 2.83667 |  |  | 0.000277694 | 0.0010131 | 0.0010131 | Material Properties - Metaal - kleur buitenkozijnen, ThermalConductivity: 160; Metaal - kleur buitenkozijnen, SpecificHeatCapacity: 880 J/kg/K; Metaal - kleur buitenkozijnen, MassDensity: 2800 kg/m3; Metaal - kleur buitenkozijnen, Embodied Energy: 155 (MJ/kg); Metaal - kleur buitenkozijnen, Embodied Carbon: 9.16 (kgCO₂/kg); Metaal - kleur buitenkozijnen, Name: Metaal - kleur buitenkozijnen; Metaal - kleur buitenkozijnen, Participates in Collision Detection: yes
Hout - Multiplex | 1e verdieping | Hout - Multiplex | 16.1257 | 15 | 218 | 0.00327 | 0.0230367 | 0.0230367 | Material Properties - Hout - Multiplex, ThermalConductivity: 0.17; Hout - Multiplex, SpecificHeatCapacity: 1600 J/kg/K; Hout - Multiplex, MassDensity: 700 kg/m3; Hout - Multiplex, Embodied Energy: 15 (MJ/kg); Hout - Multiplex, Embodied Carbon: 0.77 (kgCO₂/kg); Hout - Multiplex, Name: Hout - Multiplex; Hout - Multiplex, Participates in Collision Detection: yes
Membraan - waterdicht | 1e verdieping | Membraan - waterdicht | 8.06286 | 5 | 218 | 0.00109 | 0.00767891 | 0.00767891 | Material Properties - Membraan - waterdicht, ThermalConductivity: 0.2; Membraan - waterdicht, SpecificHeatCapacity: 1840 J/kg/K; Membraan - waterdicht, MassDensity: 1050 kg/m3; Membraan - waterdicht, Embodied Energy: 51 (MJ/kg); Membraan - waterdicht, Embodied Carbon: 0.38 (kgCO₂/kg); Membraan - waterdicht, Name: Membraan - waterdicht; Membraan - waterdicht, Participates in Collision Detection: yes
Metaal - kleur buitenkozijnen | 1e verdieping | Metaal - kleur buitenkozijnen | 5.37964 |  |  | 0.000277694 | 0.0019213 | 0.0019213 | Material Properties - Metaal - kleur buitenkozijnen, ThermalConductivity: 160; Metaal - kleur buitenkozijnen, SpecificHeatCapacity: 880 J/kg/K; Metaal - kleur buitenkozijnen, MassDensity: 2800 kg/m3; Metaal - kleur buitenkozijnen, Embodied Energy: 155 (MJ/kg); Metaal - kleur buitenkozijnen, Embodied Carbon: 9.16 (kgCO₂/kg); Metaal - kleur buitenkozijnen, Name: Metaal - kleur buitenkozijnen; Metaal - kleur buitenkozijnen, Participates in Collision Detection: yes
Hout - Multiplex | 1e verdieping | Hout - Multiplex | 16.6179 | 15 | 218 | 0.00327 | 0.0237398 | 0.0237398 | Material Properties - Hout - Multiplex, ThermalConductivity: 0.17; Hout - Multiplex, SpecificHeatCapacity: 1600 J/kg/K; Hout - Multiplex, MassDensity: 700 kg/m3; Hout - Multiplex, Embodied Energy: 15 (MJ/kg); Hout - Multiplex, Embodied Carbon: 0.77 (kgCO₂/kg); Hout - Multiplex, Name: Hout - Multiplex; Hout - Multiplex, Participates in Collision Detection: yes
Membraan - waterdicht | 1e verdieping | Membraan - waterdicht | 8.30893 | 5 | 218 | 0.00109 | 0.00791327 | 0.00791327 | Material Properties - Membraan - waterdicht, ThermalConductivity: 0.2; Membraan - waterdicht, SpecificHeatCapacity: 1840 J/kg/K; Membraan - waterdicht, MassDensity: 1050 kg/m3; Membraan - waterdicht, Embodied Energy: 51 (MJ/kg); Membraan - waterdicht, Embodied Carbon: 0.38 (kgCO₂/kg); Membraan - waterdicht, Name: Membraan - waterdicht; Membraan - waterdicht, Participates in Collision Detection: yes
Metaal - kleur buitenkozijnen | 1e verdieping | Metaal - kleur buitenkozijnen | 5.71962 |  |  | 0.000277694 | 0.00204272 | 0.00204272 | Material Properties - Metaal - kleur buitenkozijnen, ThermalConductivity: 160; Metaal - kleur buitenkozijnen, SpecificHeatCapacity: 880 J/kg/K; Metaal - kleur buitenkozijnen, MassDensity: 2800 kg/m3; Metaal - kleur buitenkozijnen, Embodied Energy: 155 (MJ/kg); Metaal - kleur buitenkozijnen, Embodied Carbon: 9.16 (kgCO₂/kg); Metaal - kleur buitenkozijnen, Name: Metaal - kleur buitenkozijnen; Metaal - kleur buitenkozijnen, Participates in Collision Detection: yes
Hout - Multiplex | 1e verdieping | Hout - Multiplex | 17.0573 | 15 | 363 | 0.005445 | 0.0243676 | 0.0243676 | Material Properties - Hout - Multiplex, ThermalConductivity: 0.17; Hout - Multiplex, SpecificHeatCapacity: 1600 J/kg/K; Hout - Multiplex, MassDensity: 700 kg/m3; Hout - Multiplex, Embodied Energy: 15 (MJ/kg); Hout - Multiplex, Embodied Carbon: 0.77 (kgCO₂/kg); Hout - Multiplex, Name: Hout - Multiplex; Hout - Multiplex, Participates in Collision Detection: yes
Membraan - waterdicht | 1e verdieping | Membraan - waterdicht | 8.52867 | 5 | 363 | 0.001815 | 0.00812254 | 0.00812254 | Material Properties - Membraan - waterdicht, ThermalConductivity: 0.2; Membraan - waterdicht, SpecificHeatCapacity: 1840 J/kg/K; Membraan - waterdicht, MassDensity: 1050 kg/m3; Membraan - waterdicht, Embodied Energy: 51 (MJ/kg); Membraan - waterdicht, Embodied Carbon: 0.38 (kgCO₂/kg); Membraan - waterdicht, Name: Membraan - waterdicht; Membraan - waterdicht, Participates in Collision Detection: yes
Metaal - kleur buitenkozijnen | 1e verdieping | Metaal - kleur buitenkozijnen | 3.85991 |  |  | 0.000277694 | 0.00137854 | 0.00137854 | Material Properties - Metaal - kleur buitenkozijnen, ThermalConductivity: 160; Metaal - kleur buitenkozijnen, SpecificHeatCapacity: 880 J/kg/K; Metaal - kleur buitenkozijnen, MassDensity: 2800 kg/m3; Metaal - kleur buitenkozijnen, Embodied Energy: 155 (MJ/kg); Metaal - kleur buitenkozijnen, Embodied Carbon: 9.16 (kgCO₂/kg); Metaal - kleur buitenkozijnen, Name: Metaal - kleur buitenkozijnen; Metaal - kleur buitenkozijnen, Participates in Collision Detection: yes
Hout - Multiplex | 1e verdieping | Hout - Multiplex | 122.031 | 15 | 1036 | 0.01554 | 0.17433 | 0.17433 | Material Properties - Hout - Multiplex, ThermalConductivity: 0.17; Hout - Multiplex, SpecificHeatCapacity: 1600 J/kg/K; Hout - Multiplex, MassDensity: 700 kg/m3; Hout - Multiplex, Embodied Energy: 15 (MJ/kg); Hout - Multiplex, Embodied Carbon: 0.77 (kgCO₂/kg); Hout - Multiplex, Name: Hout - Multiplex; Hout - Multiplex, Participates in Collision Detection: yes
Membraan - waterdicht | 1e verdieping | Membraan - waterdicht | 61.3063 |  |  | 0.00520501 | 0.0583869 | 0.0583869 | Material Properties - Membraan - waterdicht, ThermalConductivity: 0.2; Membraan - waterdicht, SpecificHeatCapacity: 1840 J/kg/K; Membraan - waterdicht, MassDensity: 1050 kg/m3; Membraan - waterdicht, Embodied Energy: 51 (MJ/kg); Membraan - waterdicht, Embodied Carbon: 0.38 (kgCO₂/kg); Membraan - waterdicht, Name: Membraan - waterdicht; Membraan - waterdicht, Participates in Collision Detection: yes
Membraan - waterdicht | 1e verdieping | Membraan - waterdicht | 22.9709 | 390 | 5 | 0.00195 | 0.0218771 | 0.0218771 | Material Properties - Membraan - waterdicht, ThermalConductivity: 0.2; Membraan - waterdicht, SpecificHeatCapacity: 1840 J/kg/K; Membraan - waterdicht, MassDensity: 1050 kg/m3; Membraan - waterdicht, Embodied Energy: 51 (MJ/kg); Membraan - waterdicht, Embodied Carbon: 0.38 (kgCO₂/kg); Membraan - waterdicht, Name: Membraan - waterdicht; Membraan - waterdicht, Participates in Collision Detection: yes
Steen - Cellenbeton | 1e verdieping | Steen - Cellenbeton | 606.667 | 515 | 150 | 0.07725 | 0.866668 | 0.866668 | Material Properties - Steen - Cellenbeton, ThermalConductivity: 0.23; Steen - Cellenbeton, SpecificHeatCapacity: 840 J/kg/K; Steen - Cellenbeton, MassDensity: 700 kg/m3; Steen - Cellenbeton, Embodied Energy: 0.75 (MJ/kg); Steen - Cellenbeton, Embodied Carbon: 0.1 (kgCO₂/kg); Steen - Cellenbeton, Name: Steen - Cellenbeton; Steen - Cellenbeton, Participates in Collision Detection: yes
Metaal - kleur buitenkozijnen | 1e verdieping | Metaal - kleur buitenkozijnen | 8.70404 |  |  | 0.000277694 | 0.00310859 | 0.00310859 | Material Properties - Metaal - kleur buitenkozijnen, ThermalConductivity: 160; Metaal - kleur buitenkozijnen, SpecificHeatCapacity: 880 J/kg/K; Metaal - kleur buitenkozijnen, MassDensity: 2800 kg/m3; Metaal - kleur buitenkozijnen, Embodied Energy: 155 (MJ/kg); Metaal - kleur buitenkozijnen, Embodied Carbon: 9.16 (kgCO₂/kg); Metaal - kleur buitenkozijnen, Name: Metaal - kleur buitenkozijnen; Metaal - kleur buitenkozijnen, Participates in Collision Detection: yes
Hout - Multiplex | 1e verdieping | Hout - Multiplex | 8.64441 | 15 | 174.996 | 0.00262494 | 0.0123492 | 0.0123492 | Material Properties - Hout - Multiplex, ThermalConductivity: 0.17; Hout - Multiplex, SpecificHeatCapacity: 1600 J/kg/K; Hout - Multiplex, MassDensity: 700 kg/m3; Hout - Multiplex, Embodied Energy: 15 (MJ/kg); Hout - Multiplex, Embodied Carbon: 0.77 (kgCO₂/kg); Hout - Multiplex, Name: Hout - Multiplex; Hout - Multiplex, Participates in Collision Detection: yes
Membraan - waterdicht | 1e verdieping | Membraan - waterdicht | 4.44937 | 5 | 179.996 | 0.00089998 | 0.0042375 | 0.0042375 | Material Properties - Membraan - waterdicht, ThermalConductivity: 0.2; Membraan - waterdicht, SpecificHeatCapacity: 1840 J/kg/K; Membraan - waterdicht, MassDensity: 1050 kg/m3; Membraan - waterdicht, Embodied Energy: 51 (MJ/kg); Membraan - waterdicht, Embodied Carbon: 0.38 (kgCO₂/kg); Membraan - waterdicht, Name: Membraan - waterdicht; Membraan - waterdicht, Participates in Collision Detection: yes
Membraan - waterdicht | 1e verdieping | Membraan - waterdicht | 5.54448 | 245 | 5 | 0.001225 | 0.00528046 | 0.00528046 | Material Properties - Membraan - waterdicht, ThermalConductivity: 0.2; Membraan - waterdicht, SpecificHeatCapacity: 1840 J/kg/K; Membraan - waterdicht, MassDensity: 1050 kg/m3; Membraan - waterdicht, Embodied Energy: 51 (MJ/kg); Membraan - waterdicht, Embodied Carbon: 0.38 (kgCO₂/kg); Membraan - waterdicht, Name: Membraan - waterdicht; Membraan - waterdicht, Participates in Collision Detection: yes
Steen - Cellenbeton | 1e verdieping | Steen - Cellenbeton | 173.547 | 374 | 150 | 0.0561 | 0.247924 | 0.247924 | Material Properties - Steen - Cellenbeton, ThermalConductivity: 0.23; Steen - Cellenbeton, SpecificHeatCapacity: 840 J/kg/K; Steen - Cellenbeton, MassDensity: 700 kg/m3; Steen - Cellenbeton, Embodied Energy: 0.75 (MJ/kg); Steen - Cellenbeton, Embodied Carbon: 0.1 (kgCO₂/kg); Steen - Cellenbeton, Name: Steen - Cellenbeton; Steen - Cellenbeton, Participates in Collision Detection: yes
Membraan - waterdicht | 1e verdieping | Membraan - waterdicht | 1200.29 |  |  |  | 1.14313 | 1.14313 | Component Quantities - Projected Component Area (Net): 228.628 m2; Projected Component Area (Gross): 228.628 m2; Component Thickness: 5 mm; Material Properties - Membraan - waterdicht, ThermalConductivity: 0.2; Membraan - waterdicht, SpecificHeatCapacity: 1840 J/kg/K; Membraan - waterdicht, MassDensity: 1050 kg/m3; Membraan - waterdicht, Embodied Energy: 51 (MJ/kg); Membraan - waterdicht, Embodied Carbon: 0.38 (kgCO₂/kg); Membraan - waterdicht, Name: Membraan - waterdicht; Membraan - waterdicht, Participates in Collision Detection: yes
Isolatie - Kunststof hard | 1e verdieping | Isolatie - Kunststof hard | 5660.69 |  |  |  | 56.6069 | 91.4503 | Component Quantities - Projected Component Area (Net): 228.734 m2; Projected Component Area (Gross): 228.842 m2; Component Thickness: 400 mm; Material Properties - Isolatie - Kunststof hard, ThermalConductivity: 0.029; Isolatie - Kunststof hard, SpecificHeatCapacity: 1470 J/kg/K; Isolatie - Kunststof hard, MassDensity: 100 kg/m3; Isolatie - Kunststof hard, Embodied Energy: 101.5 (MJ/kg); Isolatie - Kunststof hard, Embodied Carbon: 3.48 (kgCO₂/kg); Isolatie - Kunststof hard, Name: Isolatie - Kunststof hard; Isolatie - Kunststof hard, Participates in Collision Detection: yes
Membraan - waterdicht | 1e verdieping | Membraan - waterdicht | 979.301 |  |  |  | 0.932667 | 0.932667 | Component Quantities - Projected Component Area (Net): 186.536 m2; Projected Component Area (Gross): 186.536 m2; Component Thickness: 5 mm; Material Properties - Membraan - waterdicht, ThermalConductivity: 0.2; Membraan - waterdicht, SpecificHeatCapacity: 1840 J/kg/K; Membraan - waterdicht, MassDensity: 1050 kg/m3; Membraan - waterdicht, Embodied Energy: 51 (MJ/kg); Membraan - waterdicht, Embodied Carbon: 0.38 (kgCO₂/kg); Membraan - waterdicht, Name: Membraan - waterdicht; Membraan - waterdicht, Participates in Collision Detection: yes
Isolatie - Kunststof hard | 1e verdieping | Isolatie - Kunststof hard | 4702.15 |  |  |  | 47.0215 | 74.6134 | Component Quantities - Projected Component Area (Net): 186.641 m2; Projected Component Area (Gross): 186.749 m2; Component Thickness: 400 mm; Material Properties - Isolatie - Kunststof hard, ThermalConductivity: 0.029; Isolatie - Kunststof hard, SpecificHeatCapacity: 1470 J/kg/K; Isolatie - Kunststof hard, MassDensity: 100 kg/m3; Isolatie - Kunststof hard, Embodied Energy: 101.5 (MJ/kg); Isolatie - Kunststof hard, Embodied Carbon: 3.48 (kgCO₂/kg); Isolatie - Kunststof hard, Name: Isolatie - Kunststof hard; Isolatie - Kunststof hard, Participates in Collision Detection: yes
Membraan - waterdicht | 1e verdieping | Membraan - waterdicht | 141.923 |  |  |  | 0.135165 | 0.135165 | Component Quantities - Projected Component Area (Net): 27.0334 m2; Projected Component Area (Gross): 27.0334 m2; Component Thickness: 5 mm; Material Properties - Membraan - waterdicht, ThermalConductivity: 0.2; Membraan - waterdicht, SpecificHeatCapacity: 1840 J/kg/K; Membraan - waterdicht, MassDensity: 1050 kg/m3; Membraan - waterdicht, Embodied Energy: 51 (MJ/kg); Membraan - waterdicht, Embodied Carbon: 0.38 (kgCO₂/kg); Membraan - waterdicht, Name: Membraan - waterdicht; Membraan - waterdicht, Participates in Collision Detection: yes
Isolatie - Kunststof hard | 1e verdieping | Isolatie - Kunststof hard | 643.987 |  |  |  | 6.43987 | 10.8132 | Component Quantities - Projected Component Area (Net): 27.0489 m2; Projected Component Area (Gross): 27.0648 m2; Component Thickness: 400 mm; Material Properties - Isolatie - Kunststof hard, ThermalConductivity: 0.029; Isolatie - Kunststof hard, SpecificHeatCapacity: 1470 J/kg/K; Isolatie - Kunststof hard, MassDensity: 100 kg/m3; Isolatie - Kunststof hard, Embodied Energy: 101.5 (MJ/kg); Isolatie - Kunststof hard, Embodied Carbon: 3.48 (kgCO₂/kg); Isolatie - Kunststof hard, Name: Isolatie - Kunststof hard; Isolatie - Kunststof hard, Participates in Collision Detection: yes
Membraan - waterdicht | 1e verdieping | Membraan - waterdicht | 497.676 |  |  |  | 0.473977 | 0.473977 | Component Quantities - Projected Component Area (Net): 94.7964 m2; Projected Component Area (Gross): 94.7964 m2; Component Thickness: 5 mm; Material Properties - Membraan - waterdicht, ThermalConductivity: 0.2; Membraan - waterdicht, SpecificHeatCapacity: 1840 J/kg/K; Membraan - waterdicht, MassDensity: 1050 kg/m3; Membraan - waterdicht, Embodied Energy: 51 (MJ/kg); Membraan - waterdicht, Embodied Carbon: 0.38 (kgCO₂/kg); Membraan - waterdicht, Name: Membraan - waterdicht; Membraan - waterdicht, Participates in Collision Detection: yes
Isolatie - Kunststof hard | 1e verdieping | Isolatie - Kunststof hard | 2400.42 |  |  |  | 24.0042 | 37.9182 | Component Quantities - Projected Component Area (Net): 94.8355 m2; Projected Component Area (Gross): 94.8755 m2; Component Thickness: 400 mm; Material Properties - Isolatie - Kunststof hard, ThermalConductivity: 0.029; Isolatie - Kunststof hard, SpecificHeatCapacity: 1470 J/kg/K; Isolatie - Kunststof hard, MassDensity: 100 kg/m3; Isolatie - Kunststof hard, Embodied Energy: 101.5 (MJ/kg); Isolatie - Kunststof hard, Embodied Carbon: 3.48 (kgCO₂/kg); Isolatie - Kunststof hard, Name: Isolatie - Kunststof hard; Isolatie - Kunststof hard, Participates in Collision Detection: yes
Membraan - waterdicht | 1e verdieping | Membraan - waterdicht | 2382.97 |  |  |  | 2.26949 | 2.29781 | Component Quantities - Projected Component Area (Net): 453.903 m2; Projected Component Area (Gross): 459.566 m2; Component Thickness: 5 mm; Material Properties - Membraan - waterdicht, ThermalConductivity: 0.2; Membraan - waterdicht, SpecificHeatCapacity: 1840 J/kg/K; Membraan - waterdicht, MassDensity: 1050 kg/m3; Membraan - waterdicht, Embodied Energy: 51 (MJ/kg); Membraan - waterdicht, Embodied Carbon: 0.38 (kgCO₂/kg); Membraan - waterdicht, Name: Membraan - waterdicht; Membraan - waterdicht, Participates in Collision Detection: yes
Isolatie - Kunststof hard | 1e verdieping | Isolatie - Kunststof hard | 12068.8 |  |  |  | 120.688 | 183.825 | Component Quantities - Projected Component Area (Net): 454.096 m2; Projected Component Area (Gross): 459.894 m2; Component Thickness: 400 mm; Material Properties - Isolatie - Kunststof hard, ThermalConductivity: 0.029; Isolatie - Kunststof hard, SpecificHeatCapacity: 1470 J/kg/K; Isolatie - Kunststof hard, MassDensity: 100 kg/m3; Isolatie - Kunststof hard, Embodied Energy: 101.5 (MJ/kg); Isolatie - Kunststof hard, Embodied Carbon: 3.48 (kgCO₂/kg); Isolatie - Kunststof hard, Name: Isolatie - Kunststof hard; Isolatie - Kunststof hard, Participates in Collision Detection: yes
Membraan - waterdicht | 1e verdieping | Membraan - waterdicht | 2487.33 |  |  |  | 2.36888 | 2.40851 | Component Quantities - Projected Component Area (Net): 473.781 m2; Projected Component Area (Gross): 481.706 m2; Component Thickness: 5 mm; Material Properties - Membraan - waterdicht, ThermalConductivity: 0.2; Membraan - waterdicht, SpecificHeatCapacity: 1840 J/kg/K; Membraan - waterdicht, MassDensity: 1050 kg/m3; Membraan - waterdicht, Embodied Energy: 51 (MJ/kg); Membraan - waterdicht, Embodied Carbon: 0.38 (kgCO₂/kg); Membraan - waterdicht, Name: Membraan - waterdicht; Membraan - waterdicht, Participates in Collision Detection: yes
Isolatie - Kunststof hard | 1e verdieping | Isolatie - Kunststof hard | 12561.2 |  |  |  | 125.612 | 192.681 | Component Quantities - Projected Component Area (Net): 473.977 m2; Projected Component Area (Gross): 482.034 m2; Component Thickness: 400 mm; Material Properties - Isolatie - Kunststof hard, ThermalConductivity: 0.029; Isolatie - Kunststof hard, SpecificHeatCapacity: 1470 J/kg/K; Isolatie - Kunststof hard, MassDensity: 100 kg/m3; Isolatie - Kunststof hard, Embodied Energy: 101.5 (MJ/kg); Isolatie - Kunststof hard, Embodied Carbon: 3.48 (kgCO₂/kg); Isolatie - Kunststof hard, Name: Isolatie - Kunststof hard; Isolatie - Kunststof hard, Participates in Collision Detection: yes
Membraan - waterdicht | 1e verdieping | Membraan - waterdicht | 1605.58 |  |  |  | 1.52912 | 1.52912 | Component Quantities - Projected Component Area (Net): 305.828 m2; Projected Component Area (Gross): 305.828 m2; Component Thickness: 5 mm; Material Properties - Membraan - waterdicht, ThermalConductivity: 0.2; Membraan - waterdicht, SpecificHeatCapacity: 1840 J/kg/K; Membraan - waterdicht, MassDensity: 1050 kg/m3; Membraan - waterdicht, Embodied Energy: 51 (MJ/kg); Membraan - waterdicht, Embodied Carbon: 0.38 (kgCO₂/kg); Membraan - waterdicht, Name: Membraan - waterdicht; Membraan - waterdicht, Participates in Collision Detection: yes
Isolatie - Kunststof hard | 1e verdieping | Isolatie - Kunststof hard | 7490.45 |  |  |  | 74.9045 | 122.33 | Component Quantities - Projected Component Area (Net): 305.99 m2; Projected Component Area (Gross): 306.156 m2; Component Thickness: 400 mm; Material Properties - Isolatie - Kunststof hard, ThermalConductivity: 0.029; Isolatie - Kunststof hard, SpecificHeatCapacity: 1470 J/kg/K; Isolatie - Kunststof hard, MassDensity: 100 kg/m3; Isolatie - Kunststof hard, Embodied Energy: 101.5 (MJ/kg); Isolatie - Kunststof hard, Embodied Carbon: 3.48 (kgCO₂/kg); Isolatie - Kunststof hard, Name: Isolatie - Kunststof hard; Isolatie - Kunststof hard, Participates in Collision Detection: yes
Membraan - waterdicht | 1e verdieping | Membraan - waterdicht | 1982.25 |  |  |  | 1.88785 | 1.88785 | Component Quantities - Projected Component Area (Net): 377.575 m2; Projected Component Area (Gross): 377.575 m2; Component Thickness: 5 mm; Material Properties - Membraan - waterdicht, ThermalConductivity: 0.2; Membraan - waterdicht, SpecificHeatCapacity: 1840 J/kg/K; Membraan - waterdicht, MassDensity: 1050 kg/m3; Membraan - waterdicht, Embodied Energy: 51 (MJ/kg); Membraan - waterdicht, Embodied Carbon: 0.38 (kgCO₂/kg); Membraan - waterdicht, Name: Membraan - waterdicht; Membraan - waterdicht, Participates in Collision Detection: yes
Isolatie - Kunststof hard | 1e verdieping | Isolatie - Kunststof hard | 9618.49 |  |  |  | 96.1849 | 151.028 | Component Quantities - Projected Component Area (Net): 377.726 m2; Projected Component Area (Gross): 377.882 m2; Component Thickness: 400 mm; Material Properties - Isolatie - Kunststof hard, ThermalConductivity: 0.029; Isolatie - Kunststof hard, SpecificHeatCapacity: 1470 J/kg/K; Isolatie - Kunststof hard, MassDensity: 100 kg/m3; Isolatie - Kunststof hard, Embodied Energy: 101.5 (MJ/kg); Isolatie - Kunststof hard, Embodied Carbon: 3.48 (kgCO₂/kg); Isolatie - Kunststof hard, Name: Isolatie - Kunststof hard; Isolatie - Kunststof hard, Participates in Collision Detection: yes
Membraan - waterdicht | 1e verdieping | Membraan - waterdicht | 368.783 |  |  |  | 0.351222 | 0.351222 | Component Quantities - Projected Component Area (Net): 70.2451 m2; Projected Component Area (Gross): 70.2451 m2; Component Thickness: 5 mm; Material Properties - Membraan - waterdicht, ThermalConductivity: 0.2; Membraan - waterdicht, SpecificHeatCapacity: 1840 J/kg/K; Membraan - waterdicht, MassDensity: 1050 kg/m3; Membraan - waterdicht, Embodied Energy: 51 (MJ/kg); Membraan - waterdicht, Embodied Carbon: 0.38 (kgCO₂/kg); Membraan - waterdicht, Name: Membraan - waterdicht; Membraan - waterdicht, Participates in Collision Detection: yes
Isolatie - Kunststof hard | 1e verdieping | Isolatie - Kunststof hard | 1760.45 |  |  |  | 17.6045 | 28.0977 | Component Quantities - Projected Component Area (Net): 70.2756 m2; Projected Component Area (Gross): 70.3068 m2; Component Thickness: 400 mm; Material Properties - Isolatie - Kunststof hard, ThermalConductivity: 0.029; Isolatie - Kunststof hard, SpecificHeatCapacity: 1470 J/kg/K; Isolatie - Kunststof hard, MassDensity: 100 kg/m3; Isolatie - Kunststof hard, Embodied Energy: 101.5 (MJ/kg); Isolatie - Kunststof hard, Embodied Carbon: 3.48 (kgCO₂/kg); Isolatie - Kunststof hard, Name: Isolatie - Kunststof hard; Isolatie - Kunststof hard, Participates in Collision Detection: yes
Membraan - waterdicht | 1e verdieping | Membraan - waterdicht | 332.598 |  |  |  | 0.31676 | 0.317685 | Component Quantities - Projected Component Area (Net): 63.3528 m2; Projected Component Area (Gross): 63.5378 m2; Component Thickness: 5 mm; Material Properties - Membraan - waterdicht, ThermalConductivity: 0.2; Membraan - waterdicht, SpecificHeatCapacity: 1840 J/kg/K; Membraan - waterdicht, MassDensity: 1050 kg/m3; Membraan - waterdicht, Embodied Energy: 51 (MJ/kg); Membraan - waterdicht, Embodied Carbon: 0.38 (kgCO₂/kg); Membraan - waterdicht, Name: Membraan - waterdicht; Membraan - waterdicht, Participates in Collision Detection: yes
Isolatie - Kunststof hard | 1e verdieping | Isolatie - Kunststof hard | 1556.26 |  |  |  | 15.5626 | 25.4148 | Component Quantities - Projected Component Area (Net): 63.3832 m2; Projected Component Area (Gross): 63.5994 m2; Component Thickness: 400 mm; Material Properties - Isolatie - Kunststof hard, ThermalConductivity: 0.029; Isolatie - Kunststof hard, SpecificHeatCapacity: 1470 J/kg/K; Isolatie - Kunststof hard, MassDensity: 100 kg/m3; Isolatie - Kunststof hard, Embodied Energy: 101.5 (MJ/kg); Isolatie - Kunststof hard, Embodied Carbon: 3.48 (kgCO₂/kg); Isolatie - Kunststof hard, Name: Isolatie - Kunststof hard; Isolatie - Kunststof hard, Participates in Collision Detection: yes
Membraan - waterdicht | 1e verdieping | Membraan - waterdicht | 104.183 |  |  |  | 0.0992216 | 0.0992216 | Component Quantities - Projected Component Area (Net): 19.8446 m2; Projected Component Area (Gross): 19.8446 m2; Component Thickness: 5 mm; Material Properties - Membraan - waterdicht, ThermalConductivity: 0.2; Membraan - waterdicht, SpecificHeatCapacity: 1840 J/kg/K; Membraan - waterdicht, MassDensity: 1050 kg/m3; Membraan - waterdicht, Embodied Energy: 51 (MJ/kg); Membraan - waterdicht, Embodied Carbon: 0.38 (kgCO₂/kg); Membraan - waterdicht, Name: Membraan - waterdicht; Membraan - waterdicht, Participates in Collision Detection: yes
Isolatie - Kunststof hard | 1e verdieping | Isolatie - Kunststof hard | 198.443 |  |  |  | 1.98443 | 1.98443 | Component Quantities - Projected Component Area (Net): 19.8509 m2; Projected Component Area (Gross): 19.8509 m2; Component Thickness: 100 mm; Material Properties - Isolatie - Kunststof hard, ThermalConductivity: 0.029; Isolatie - Kunststof hard, SpecificHeatCapacity: 1470 J/kg/K; Isolatie - Kunststof hard, MassDensity: 100 kg/m3; Isolatie - Kunststof hard, Embodied Energy: 101.5 (MJ/kg); Isolatie - Kunststof hard, Embodied Carbon: 3.48 (kgCO₂/kg); Isolatie - Kunststof hard, Name: Isolatie - Kunststof hard; Isolatie - Kunststof hard, Participates in Collision Detection: yes
Hout - Vloer | 1e verdieping | Hout - Vloer | 196.459 |  |  |  | 0.357198 | 0.357198 | Component Quantities - Projected Component Area (Net): 19.8455 m2; Projected Component Area (Gross): 19.8455 m2; Component Thickness: 18 mm; Material Properties - Hout - Vloer, ThermalConductivity: 0.14; Hout - Vloer, SpecificHeatCapacity: 1880 J/kg/K; Hout - Vloer, MassDensity: 550 kg/m3; Hout - Vloer, Embodied Energy: 7.4 (MJ/kg); Hout - Vloer, Embodied Carbon: 0.19 (kgCO₂/kg); Hout - Vloer, Name: Hout - Vloer; Hout - Vloer, Participates in Collision Detection: yes
Membraan - waterdicht | 1e verdieping | Membraan - waterdicht | 243.569 |  |  |  | 0.23197 | 0.23197 | Component Quantities - Projected Component Area (Net): 46.3944 m2; Projected Component Area (Gross): 46.3944 m2; Component Thickness: 5 mm; Material Properties - Membraan - waterdicht, ThermalConductivity: 0.2; Membraan - waterdicht, SpecificHeatCapacity: 1840 J/kg/K; Membraan - waterdicht, MassDensity: 1050 kg/m3; Membraan - waterdicht, Embodied Energy: 51 (MJ/kg); Membraan - waterdicht, Embodied Carbon: 0.38 (kgCO₂/kg); Membraan - waterdicht, Name: Membraan - waterdicht; Membraan - waterdicht, Participates in Collision Detection: yes
Isolatie - Kunststof hard | 1e verdieping | Isolatie - Kunststof hard | 1295.84 |  |  |  | 12.9584 | 18.5576 | Component Quantities - Projected Component Area (Net): 46.4072 m2; Projected Component Area (Gross): 46.4204 m2; Component Thickness: 400 mm; Material Properties - Isolatie - Kunststof hard, ThermalConductivity: 0.029; Isolatie - Kunststof hard, SpecificHeatCapacity: 1470 J/kg/K; Isolatie - Kunststof hard, MassDensity: 100 kg/m3; Isolatie - Kunststof hard, Embodied Energy: 101.5 (MJ/kg); Isolatie - Kunststof hard, Embodied Carbon: 3.48 (kgCO₂/kg); Isolatie - Kunststof hard, Name: Isolatie - Kunststof hard; Isolatie - Kunststof hard, Participates in Collision Detection: yes
Hout - Multiplex | Dak | Hout - Multiplex | 65.0328 | 15 | 490 | 0.00735 | 0.092904 | 0.092904 | Material Properties - Hout - Multiplex, ThermalConductivity: 0.17; Hout - Multiplex, SpecificHeatCapacity: 1600 J/kg/K; Hout - Multiplex, MassDensity: 700 kg/m3; Hout - Multiplex, Embodied Energy: 15 (MJ/kg); Hout - Multiplex, Embodied Carbon: 0.77 (kgCO₂/kg); Hout - Multiplex, Name: Hout - Multiplex; Hout - Multiplex, Participates in Collision Detection: yes
Membraan - waterdicht | Dak | Membraan - waterdicht | 32.8352 |  |  | 0.002475 | 0.0312717 | 0.0312717 | Material Properties - Membraan - waterdicht, ThermalConductivity: 0.2; Membraan - waterdicht, SpecificHeatCapacity: 1840 J/kg/K; Membraan - waterdicht, MassDensity: 1050 kg/m3; Membraan - waterdicht, Embodied Energy: 51 (MJ/kg); Membraan - waterdicht, Embodied Carbon: 0.38 (kgCO₂/kg); Membraan - waterdicht, Name: Membraan - waterdicht; Membraan - waterdicht, Participates in Collision Detection: yes
2 x Membraan - waterdicht | Dak | Membraan - waterdicht | 22.444 | 352 | 5 | 0.00176 | 0.0213752 | 0.0213752 | Material Properties - Membraan - waterdicht, ThermalConductivity: 0.2; Membraan - waterdicht, SpecificHeatCapacity: 1840 J/kg/K; Membraan - waterdicht, MassDensity: 1050 kg/m3; Membraan - waterdicht, Embodied Energy: 51 (MJ/kg); Membraan - waterdicht, Embodied Carbon: 0.38 (kgCO₂/kg); Membraan - waterdicht, Name: Membraan - waterdicht; Membraan - waterdicht, Participates in Collision Detection: yes
2 x Metaal - kleur buitenkozijnen | Dak | Metaal - kleur buitenkozijnen | 11.3146 |  |  | 0.000307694 | 0.00404093 | 0.00404093 | Material Properties - Metaal - kleur buitenkozijnen, ThermalConductivity: 160; Metaal - kleur buitenkozijnen, SpecificHeatCapacity: 880 J/kg/K; Metaal - kleur buitenkozijnen, MassDensity: 2800 kg/m3; Metaal - kleur buitenkozijnen, Embodied Energy: 155 (MJ/kg); Metaal - kleur buitenkozijnen, Embodied Carbon: 9.16 (kgCO₂/kg); Metaal - kleur buitenkozijnen, Name: Metaal - kleur buitenkozijnen; Metaal - kleur buitenkozijnen, Participates in Collision Detection: yes
2 x Isolatie - Steenwol hard | Dak | Isolatie - Steenwol hard | 158.523 | 537 | 150 | 0.0805502 | 0.990767 | 0.990767 | Material Properties - Isolatie - Steenwol hard, ThermalConductivity: 0.043; Isolatie - Steenwol hard, SpecificHeatCapacity: 840 J/kg/K; Isolatie - Steenwol hard, MassDensity: 160 kg/m3; Isolatie - Steenwol hard, Embodied Energy: 16.8 (MJ/kg); Isolatie - Steenwol hard, Embodied Carbon: 1.05 (kgCO₂/kg); Isolatie - Steenwol hard, Name: Isolatie - Steenwol hard; Isolatie - Steenwol hard, Participates in Collision Detection: yes
2 x Hout - Multiplex | Dak | Hout - Multiplex | 111.338 | 15 | 490 | 0.00735 | 0.159054 | 0.159054 | Material Properties - Hout - Multiplex, ThermalConductivity: 0.17; Hout - Multiplex, SpecificHeatCapacity: 1600 J/kg/K; Hout - Multiplex, MassDensity: 700 kg/m3; Hout - Multiplex, Embodied Energy: 15 (MJ/kg); Hout - Multiplex, Embodied Carbon: 0.77 (kgCO₂/kg); Hout - Multiplex, Name: Hout - Multiplex; Hout - Multiplex, Participates in Collision Detection: yes
2 x Membraan - waterdicht | Dak | Membraan - waterdicht | 56.224 |  |  | 0.002475 | 0.0535467 | 0.0535467 | Material Properties - Membraan - waterdicht, ThermalConductivity: 0.2; Membraan - waterdicht, SpecificHeatCapacity: 1840 J/kg/K; Membraan - waterdicht, MassDensity: 1050 kg/m3; Membraan - waterdicht, Embodied Energy: 51 (MJ/kg); Membraan - waterdicht, Embodied Carbon: 0.38 (kgCO₂/kg); Membraan - waterdicht, Name: Membraan - waterdicht; Membraan - waterdicht, Participates in Collision Detection: yes
2 x Membraan - waterdicht | Dak | Membraan - waterdicht | 39.076 | 352 | 5 | 0.00176 | 0.0372152 | 0.0372152 | Material Properties - Membraan - waterdicht, ThermalConductivity: 0.2; Membraan - waterdicht, SpecificHeatCapacity: 1840 J/kg/K; Membraan - waterdicht, MassDensity: 1050 kg/m3; Membraan - waterdicht, Embodied Energy: 51 (MJ/kg); Membraan - waterdicht, Embodied Carbon: 0.38 (kgCO₂/kg); Membraan - waterdicht, Name: Membraan - waterdicht; Membraan - waterdicht, Participates in Collision Detection: yes
Metaal - kleur buitenkozijnen | Dak | Metaal - kleur buitenkozijnen | 19.0531 |  |  | 0.000307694 | 0.00680468 | 0.00680468 | Material Properties - Metaal - kleur buitenkozijnen, ThermalConductivity: 160; Metaal - kleur buitenkozijnen, SpecificHeatCapacity: 880 J/kg/K; Metaal - kleur buitenkozijnen, MassDensity: 2800 kg/m3; Metaal - kleur buitenkozijnen, Embodied Energy: 155 (MJ/kg); Metaal - kleur buitenkozijnen, Embodied Carbon: 9.16 (kgCO₂/kg); Metaal - kleur buitenkozijnen, Name: Metaal - kleur buitenkozijnen; Metaal - kleur buitenkozijnen, Participates in Collision Detection: yes
2 x Isolatie - Steenwol hard | Dak | Isolatie - Steenwol hard | 274.515 | 537 | 150 | 0.0805502 | 1.71572 | 1.71572 | Material Properties - Isolatie - Steenwol hard, ThermalConductivity: 0.043; Isolatie - Steenwol hard, SpecificHeatCapacity: 840 J/kg/K; Isolatie - Steenwol hard, MassDensity: 160 kg/m3; Isolatie - Steenwol hard, Embodied Energy: 16.8 (MJ/kg); Isolatie - Steenwol hard, Embodied Carbon: 1.05 (kgCO₂/kg); Isolatie - Steenwol hard, Name: Isolatie - Steenwol hard; Isolatie - Steenwol hard, Participates in Collision Detection: yes
Metaal - kleur buitenkozijnen | Dak | Metaal - kleur buitenkozijnen | 19.0531 |  |  | 0.000307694 | 0.00680467 | 0.00680467 | Material Properties - Metaal - kleur buitenkozijnen, ThermalConductivity: 160; Metaal - kleur buitenkozijnen, SpecificHeatCapacity: 880 J/kg/K; Metaal - kleur buitenkozijnen, MassDensity: 2800 kg/m3; Metaal - kleur buitenkozijnen, Embodied Energy: 155 (MJ/kg); Metaal - kleur buitenkozijnen, Embodied Carbon: 9.16 (kgCO₂/kg); Metaal - kleur buitenkozijnen, Name: Metaal - kleur buitenkozijnen; Metaal - kleur buitenkozijnen, Participates in Collision Detection: yes
Hout - Multiplex | Dak | Hout - Multiplex | 65.0329 | 15 | 490 | 0.00735 | 0.0929041 | 0.0929041 | Material Properties - Hout - Multiplex, ThermalConductivity: 0.17; Hout - Multiplex, SpecificHeatCapacity: 1600 J/kg/K; Hout - Multiplex, MassDensity: 700 kg/m3; Hout - Multiplex, Embodied Energy: 15 (MJ/kg); Hout - Multiplex, Embodied Carbon: 0.77 (kgCO₂/kg); Hout - Multiplex, Name: Hout - Multiplex; Hout - Multiplex, Participates in Collision Detection: yes
Membraan - waterdicht | Dak | Membraan - waterdicht | 32.8353 |  |  | 0.002475 | 0.0312717 | 0.0312717 | Material Properties - Membraan - waterdicht, ThermalConductivity: 0.2; Membraan - waterdicht, SpecificHeatCapacity: 1840 J/kg/K; Membraan - waterdicht, MassDensity: 1050 kg/m3; Membraan - waterdicht, Embodied Energy: 51 (MJ/kg); Membraan - waterdicht, Embodied Carbon: 0.38 (kgCO₂/kg); Membraan - waterdicht, Name: Membraan - waterdicht; Membraan - waterdicht, Participates in Collision Detection: yes
Membraan - waterdicht | Dak | Membraan - waterdicht | 1349.26 |  |  |  | 1.28501 | 1.28501 | Component Quantities - Projected Component Area (Net): 257.003 m2; Projected Component Area (Gross): 257.003 m2; Component Thickness: 5 mm; Material Properties - Membraan - waterdicht, ThermalConductivity: 0.2; Membraan - waterdicht, SpecificHeatCapacity: 1840 J/kg/K; Membraan - waterdicht, MassDensity: 1050 kg/m3; Membraan - waterdicht, Embodied Energy: 51 (MJ/kg); Membraan - waterdicht, Embodied Carbon: 0.38 (kgCO₂/kg); Membraan - waterdicht, Name: Membraan - waterdicht; Membraan - waterdicht, Participates in Collision Detection: yes
Isolatie - Kunststof hard | Dak | Isolatie - Kunststof hard | 7481.1 |  |  |  | 74.811 | 102.801 | Component Quantities - Projected Component Area (Net): 257.065 m2; Projected Component Area (Gross): 257.128 m2; Component Thickness: 400 mm; Material Properties - Isolatie - Kunststof hard, ThermalConductivity: 0.029; Isolatie - Kunststof hard, SpecificHeatCapacity: 1470 J/kg/K; Isolatie - Kunststof hard, MassDensity: 100 kg/m3; Isolatie - Kunststof hard, Embodied Energy: 101.5 (MJ/kg); Isolatie - Kunststof hard, Embodied Carbon: 3.48 (kgCO₂/kg); Isolatie - Kunststof hard, Name: Isolatie - Kunststof hard; Isolatie - Kunststof hard, Participates in Collision Detection: yes

# IfcBuildingElementProxy: 1354 wand balie_hoog 120 x 1180 (6)
In: Begane grond
Classification: 22 BINNENWANDEN (NL/SfB (4 cijfers)); Wand (ARCHICAD Classification NED)
AC_Pset_RenovationAndPhasing - Renovation Status: Existing

# IfcBuildingElementProxy: 1354 wand balie_klapdeur 120 x 750, Bi.wand C
In: Begane grond
Classification: 22 BINNENWANDEN (NL/SfB (4 cijfers)); Wand (ARCHICAD Classification NED)
AC_Pset_RenovationAndPhasing - Renovation Status: Existing

# IfcBuildingElementProxy: 1354 wand balie_laag 120 x 900 (2)
In: Begane grond
Classification: 22 BINNENWANDEN (NL/SfB (4 cijfers)); Wand (ARCHICAD Classification NED)
AC_Pset_RenovationAndPhasing - Renovation Status: Existing

# IfcBuildingElementProxy: 27 Dakrand met daktrim - gymzaal 545 x 572 (4)
In: Dak
Classification: Dakafwerking (ARCHICAD Classification)
AC_Pset_RenovationAndPhasing - Renovation Status: Existing

# IfcBuildingElementProxy: 27 Dakrand met daktrim - h&b variabel 1071 x 550 (2)
In: 1e verdieping
Classification: Dakafwerking (ARCHICAD Classification)
AC_Pset_RenovationAndPhasing - Renovation Status: Existing

# IfcBuildingElementProxy: 27 Dakrand met daktrim - h&b variabel 1561 x 550, Dakrand
In: 1e verdieping
Classification: Dakafwerking (ARCHICAD Classification)
AC_Pset_RenovationAndPhasing - Renovation Status: Existing

# IfcBuildingElementProxy: 27 Dakrand met daktrim - h&b variabel 1971 x 550, Dakrand
In: 1e verdieping
Classification: Dakafwerking (ARCHICAD Classification)
AC_Pset_RenovationAndPhasing - Renovation Status: Existing

# IfcBuildingElementProxy: 27 Dakrand met daktrim - h&b variabel 2835 x 710, Dakrand
In: 1e verdieping
Classification: Dakafwerking (ARCHICAD Classification)
AC_Pset_RenovationAndPhasing - Renovation Status: Existing

# IfcBuildingElementProxy: 27 Dakrand met daktrim - h&b variabel 470 x 960, Dakrand
In: 1e verdieping
Classification: Dakafwerking (ARCHICAD Classification)
AC_Pset_RenovationAndPhasing - Renovation Status: Existing

# IfcBuildingElementProxy: 27 Dakrand met daktrim - h&b variabel 471 x 409 (2)
In: 1e verdieping
Classification: Dakafwerking (ARCHICAD Classification)
AC_Pset_RenovationAndPhasing - Renovation Status: Existing

# IfcBuildingElementProxy: 27 Dakrand met daktrim - h&b variabel 471 x 550 (6)
In: 1e verdieping
Classification: Dakafwerking (ARCHICAD Classification)
AC_Pset_RenovationAndPhasing - Renovation Status: Existing

# IfcBuildingElementProxy: 27 Dakrand met daktrim - h&b variabel 471 x 710 (5)
In: 1e verdieping
Classification: Dakafwerking (ARCHICAD Classification)
AC_Pset_RenovationAndPhasing - Renovation Status: Existing

# IfcBuildingElementProxy: 27 Dakrand met daktrim - h&b variabel 471 x 960 (2)
In: 1e verdieping
Classification: Dakafwerking (ARCHICAD Classification)
AC_Pset_RenovationAndPhasing - Renovation Status: Existing

# IfcBuildingElementProxy: 27 Dakrand met daktrim - h&b variabel 621 x 550 (3)
In: 1e verdieping
Classification: Dakafwerking (ARCHICAD Classification)
AC_Pset_RenovationAndPhasing - Renovation Status: Existing

# IfcBuildingElementProxy: 27 Dakrand zonder daktrim - hoogte variabel 155 x 535, Dakrand
In: 1e verdieping
Classification: Dakafwerking (ARCHICAD Classification)
AC_Pset_RenovationAndPhasing - Renovation Status: Existing

# IfcBuildingElementProxy: 27 Dakrand zonder daktrim - hoogte variabel 180 x 394, Dakrand
In: 1e verdieping
Classification: Dakafwerking (ARCHICAD Classification)
AC_Pset_RenovationAndPhasing - Renovation Status: Existing

# IfcBuildingElementProxy: 27 Dakrand zonder daktrim - hoogte variabel 315 x 535 (2)
In: 1e verdieping
Classification: Dakafwerking (ARCHICAD Classification)
AC_Pset_RenovationAndPhasing - Renovation Status: Existing

# IfcBuildingElementProxy: 27 Dakrand zonder daktrim - hoogte variabel 441 x 695, Dakrand
In: 1e verdieping
Classification: Dakafwerking (ARCHICAD Classification)
AC_Pset_RenovationAndPhasing - Renovation Status: Existing

# IfcBuildingElementProxy: 27 Dakrand zonder daktrim - kantine 291 x 607 (2)
In: 1e verdieping
Classification: Dakafwerking (ARCHICAD Classification)
AC_Pset_RenovationAndPhasing - Renovation Status: Existing

# IfcBuildingElementProxy: 27 Dakrand zonder daktrim - kantine 300 x 607, Dakrand
In: 1e verdieping
Classification: Dakafwerking (ARCHICAD Classification)
AC_Pset_RenovationAndPhasing - Renovation Status: Existing

# IfcBuildingElementProxy: 27 Dakrand zonder daktrim - kantine 356 x 607 (3)
In: 1e verdieping
Classification: Dakafwerking (ARCHICAD Classification)
AC_Pset_RenovationAndPhasing - Renovation Status: Existing
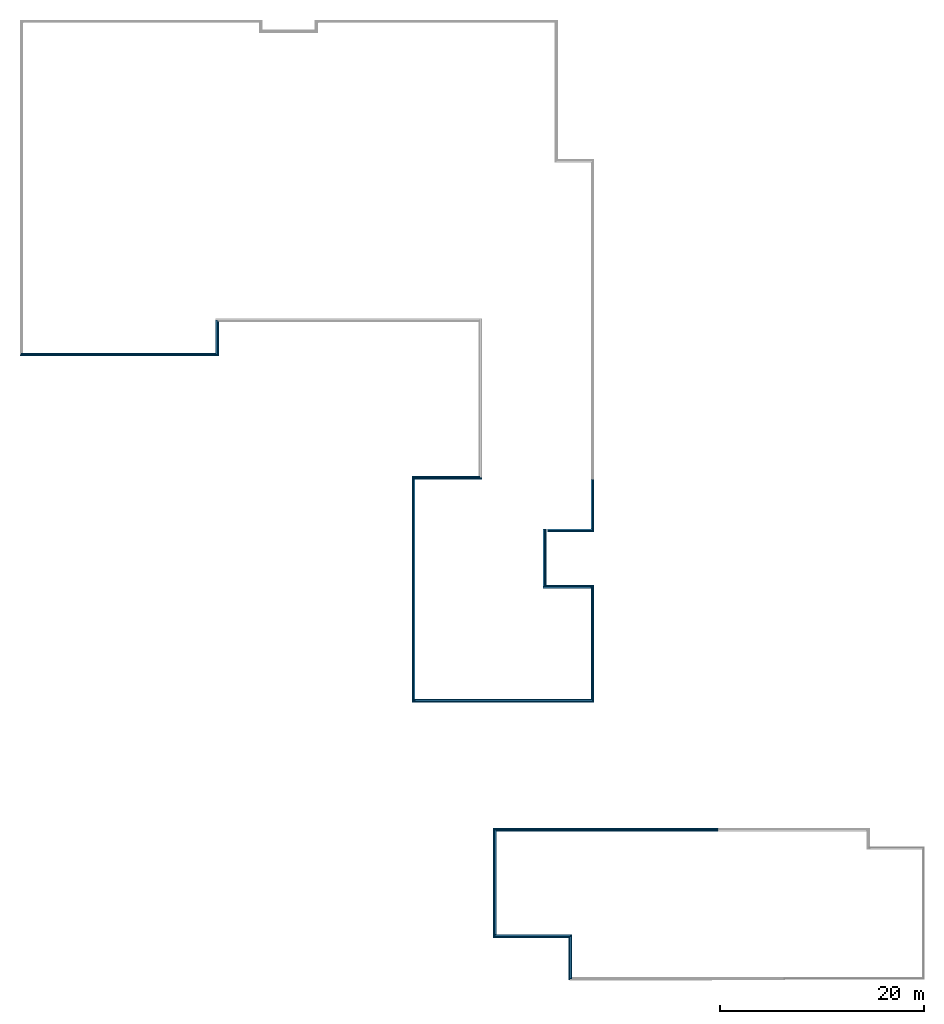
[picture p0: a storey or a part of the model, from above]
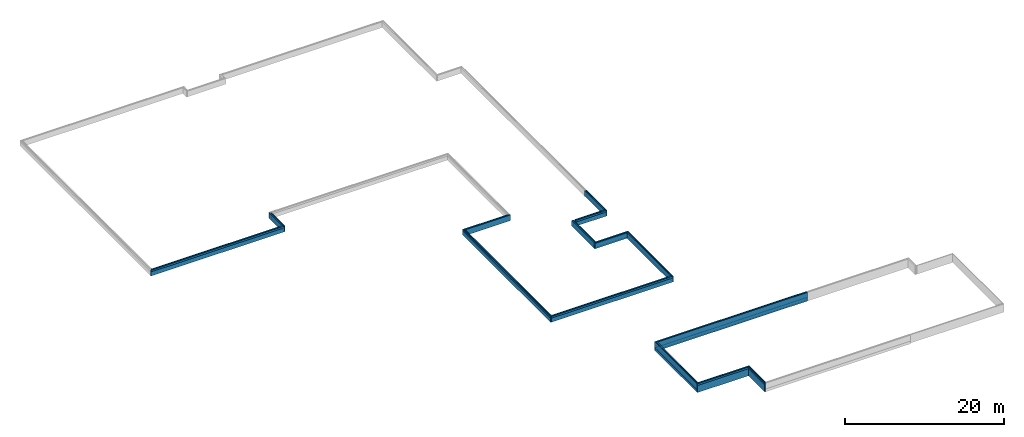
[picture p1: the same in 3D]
Properties of the parts of a building model (IFC2X3), part 13 of 19

# IfcBuildingElementProxy: 27 Houten bekleding ingefreesd 47 x 1365 (25)
Classification: Dakafwerking (ARCHICAD Classification); Material: Hout - gevel
AC_Pset_RenovationAndPhasing - Renovation Status: Existing
Material Properties - Hout - gevel, ThermalConductivity: 0.14; Hout - gevel, SpecificHeatCapacity: 1880 J/kg/K; Hout - gevel, MassDensity: 550 kg/m3; Hout - gevel, Embodied Energy: 7.4 (MJ/kg); Hout - gevel, Embodied Carbon: 0.19 (kgCO₂/kg); Hout - gevel, Name: Hout - gevel; Hout - gevel, Participates in Collision Detection: yes
Component Quantities - Hout - gevel, Rectangular Component Width: 8 mm
Name | In | Hout - gevel, Mass (kg) | Hout - gevel, Rectangular Component Height (mm) | Hout - gevel, Component Cross Section Area (m2) | Hout - gevel, Component Volume (Net) (m3) = Hout - gevel, Component Volume (Gross) (m3)
Dakrand | Begane grond | 117.249 | 1365 | 0.01092 | 0.21318
Dakrand | Begane grond | 199.688 | 1365 | 0.01092 | 0.363068
Dakrand | Begane grond | 9.009 | 1365 | 0.01092 | 0.01638
Dakrand | Begane grond | 78.4389 | 1365 | 0.01092 | 0.142616
Dakrand | Begane grond | 149.839 | 1365.01 | 0.0109201 | 0.272435
Dakrand | Begane grond | 153.768 | 1365.02 | 0.0109202 | 0.279578
Dakrand | Begane grond | 14.1737 | 1365 | 0.01092 | 0.0257704
Dakrand | Begane grond | 99.5674 | 1365 | 0.01092 | 0.181032
Dakrand | Begane grond | 117.67 | 1365 | 0.01092 | 0.213945
Dakrand | Begane grond | 131.363 | 1365 | 0.01092 | 0.238842
Dakrand | Begane grond | 14.4561 | 1365 | 0.01092 | 0.0262837
Dakrand | Begane grond | 67.1652 | 1365 | 0.01092 | 0.122119
Dakrand | Begane grond | 202.066 | 1365 | 0.01092 | 0.367393
Dakrand | Begane grond | 143.208 | 1365 | 0.01092 | 0.260379
Dakrand | Begane grond | 204.203 | 1365 | 0.01092 | 0.371278
Dakrand | Begane grond | 44.4204 | 1365 | 0.01092 | 0.0807644
Dakrand | Begane grond | 41.8498 | 1365 | 0.01092 | 0.0760906
Dakrand | Begane grond | 22.1802 | 1365 | 0.01092 | 0.0403276
Dakrand | Begane grond | 24.7507 | 1365 | 0.01092 | 0.0450013
Dakrand | Begane grond | 17.8865 | 1365 | 0.01092 | 0.0325208
Dakrand | Begane grond | 64.5219 | 1365 | 0.01092 | 0.117313
Dakrand | Begane grond | 36.9488 | 1365 | 0.01092 | 0.0671796
Dakrand | Begane grond | 29.3454 | 1365 | 0.01092 | 0.0533553
Dakrand | 1e verdieping | 133.682 | 1365 | 0.01092 | 0.243058
Dakrand | 1e verdieping | 31.3994 | 1365 | 0.01092 | 0.0570899

# IfcBuildingElementProxy: 27 Houten bekleding ingefreesd 47 x 1385 (3)
In: Begane grond
Classification: Dakafwerking (ARCHICAD Classification); Material: Hout - gevel
AC_Pset_RenovationAndPhasing - Renovation Status: Existing
Material Properties - Hout - gevel, ThermalConductivity: 0.14; Hout - gevel, SpecificHeatCapacity: 1880 J/kg/K; Hout - gevel, MassDensity: 550 kg/m3; Hout - gevel, Embodied Energy: 7.4 (MJ/kg); Hout - gevel, Embodied Carbon: 0.19 (kgCO₂/kg); Hout - gevel, Name: Hout - gevel; Hout - gevel, Participates in Collision Detection: yes
Component Quantities - Hout - gevel, Rectangular Component Height: 1385 mm; Hout - gevel, Rectangular Component Width: 8 mm; Hout - gevel, Component Cross Section Area: 0.01108 m2
Name | Hout - gevel, Mass (kg) | Hout - gevel, Component Volume (Net) (m3) = Hout - gevel, Component Volume (Gross) (m3)
Dakrand | 80.0204 | 0.145492
Dakrand | 134.812 | 0.245112
Dakrand | 40.0072 | 0.0727404

# IfcBuildingElementProxy: 27 Houten bekleding ingefreesd 47 x 1680 (3)
In: Begane grond
Classification: Dakafwerking (ARCHICAD Classification); Material: Hout - gevel
AC_Pset_RenovationAndPhasing - Renovation Status: Existing
Material Properties - Hout - gevel, ThermalConductivity: 0.14; Hout - gevel, SpecificHeatCapacity: 1880 J/kg/K; Hout - gevel, MassDensity: 550 kg/m3; Hout - gevel, Embodied Energy: 7.4 (MJ/kg); Hout - gevel, Embodied Carbon: 0.19 (kgCO₂/kg); Hout - gevel, Name: Hout - gevel; Hout - gevel, Participates in Collision Detection: yes
Component Quantities - Hout - gevel, Rectangular Component Height: 1680 mm; Hout - gevel, Rectangular Component Width: 8 mm; Hout - gevel, Component Cross Section Area: 0.01344 m2
Name | Hout - gevel, Mass (kg) | Hout - gevel, Component Volume (Net) (m3) = Hout - gevel, Component Volume (Gross) (m3)
Dakrand | 1.2873 | 0.00234054
Dakrand | 3.20052 | 0.00581913
Dakrand | 1.56754 | 0.00285008

# IfcBuildingElementProxy: 27 Houten bekleding ingefreesd 47 x 3045 (2)
In: Begane grond
Classification: Dakafwerking (ARCHICAD Classification); Material: Hout - gevel
AC_Pset_RenovationAndPhasing - Renovation Status: Existing
Material Properties - Hout - gevel, ThermalConductivity: 0.14; Hout - gevel, SpecificHeatCapacity: 1880 J/kg/K; Hout - gevel, MassDensity: 550 kg/m3; Hout - gevel, Embodied Energy: 7.4 (MJ/kg); Hout - gevel, Embodied Carbon: 0.19 (kgCO₂/kg); Hout - gevel, Name: Hout - gevel; Hout - gevel, Participates in Collision Detection: yes
Component Quantities - Hout - gevel, Rectangular Component Height: 3045 mm; Hout - gevel, Rectangular Component Width: 8 mm; Hout - gevel, Component Cross Section Area: 0.02436 m2
Name | Hout - gevel, Mass (kg) | Hout - gevel, Component Volume (Net) (m3) = Hout - gevel, Component Volume (Gross) (m3)
Dakrand | 223.036 | 0.405521
Dakrand | 211.876 | 0.385229

# IfcBuildingElementProxy: 27 Houten bekleding ingefreesd 47 x 3365 (2)
In: Begane grond
Classification: Dakafwerking (ARCHICAD Classification); Material: Hout - gevel
AC_Pset_RenovationAndPhasing - Renovation Status: Existing
Material Properties - Hout - gevel, ThermalConductivity: 0.14; Hout - gevel, SpecificHeatCapacity: 1880 J/kg/K; Hout - gevel, MassDensity: 550 kg/m3; Hout - gevel, Embodied Energy: 7.4 (MJ/kg); Hout - gevel, Embodied Carbon: 0.19 (kgCO₂/kg); Hout - gevel, Name: Hout - gevel; Hout - gevel, Participates in Collision Detection: yes
Component Quantities - Hout - gevel, Rectangular Component Height: 3365 mm; Hout - gevel, Rectangular Component Width: 8 mm; Hout - gevel, Component Cross Section Area: 0.02692 m2
Name | Hout - gevel, Mass (kg) | Hout - gevel, Component Volume (Net) (m3) = Hout - gevel, Component Volume (Gross) (m3)
Dakrand | 169.484 | 0.308153
Dakrand | 69.1734 | 0.12577

# IfcBuildingElementProxy: 27 Luifelrand met daktrim - breedte variabel 1068 x 64 (2)
In: 1e verdieping
Classification: Dakafwerking (ARCHICAD Classification)
AC_Pset_RenovationAndPhasing - Renovation Status: Existing

# IfcBuildingElementProxy: 27 Luifelrand met daktrim - breedte variabel 173 x 64 (2)
In: 1e verdieping
Classification: Dakafwerking (ARCHICAD Classification)
AC_Pset_RenovationAndPhasing - Renovation Status: Existing

# IfcBuildingElementProxy: 27 Luifelrand met daktrim - breedte variabel 248 x 64 (2)
In: 1e verdieping
Classification: Dakafwerking (ARCHICAD Classification)
AC_Pset_RenovationAndPhasing - Renovation Status: Existing

# IfcBuildingElementProxy: 27 Luifelrand met daktrim - breedte variabel 2480 x 64 (2)
In: 1e verdieping
Classification: Dakafwerking (ARCHICAD Classification)
AC_Pset_RenovationAndPhasing - Renovation Status: Existing

# IfcBuildingElementProxy: 27 Luifelrand met daktrim - breedte variabel 250 x 64 (2)
In: 1e verdieping
Classification: Dakafwerking (ARCHICAD Classification)
AC_Pset_RenovationAndPhasing - Renovation Status: Existing

# IfcBuildingElementProxy: 27 Luifelrand met daktrim - breedte variabel 260 x 64 (3)
In: 1e verdieping
Classification: Dakafwerking (ARCHICAD Classification)
AC_Pset_RenovationAndPhasing - Renovation Status: Existing

# IfcBuildingElementProxy: 27 Luifelrand met daktrim - breedte variabel 393 x 64 (2)
In: 1e verdieping
Classification: Dakafwerking (ARCHICAD Classification)
AC_Pset_RenovationAndPhasing - Renovation Status: Existing

# IfcBuildingElementProxy: 27 Luifelrand met daktrim - breedte variabel 4280 x 64, Dakrand
In: 1e verdieping
Classification: Dakafwerking (ARCHICAD Classification)
AC_Pset_RenovationAndPhasing - Renovation Status: Existing

# IfcBuildingElementProxy: 27 Luifelrand met daktrim - breedte variabel 619 x 64 (2)
In: 1e verdieping
Classification: Dakafwerking (ARCHICAD Classification)
AC_Pset_RenovationAndPhasing - Renovation Status: Existing

# IfcBuildingElementProxy: 27 afschotisolatie & dakbedekking 405 (12)
Pset_SlabCommon - Reference: Type Dak
AC_Pset_RenovationAndPhasing - Renovation Status: Existing
Name | In
11 x Afschotisolatie | 1e verdieping
Afschotisolatie | Dak

# IfcBuildingElementProxy: 27 dakbeschot, isolatie, dakbedekking 123, Dakbeschot & isolatie
In: 1e verdieping
Pset_SlabCommon - Reference: Type Dak
AC_Pset_RenovationAndPhasing - Renovation Status: Existing

# IfcBuildingElementProxy: 30 Panelenwand 102 102 (17)
In: Begane grond
Classification: 22 Binnenwanden (NL/SfB (2 cijfers))
AC_Pset_RenovationAndPhasing - Renovation Status: Existing

# IfcBuildingElementProxy: 3D Man lopend contour 01 25, betontrap
In: 1e verdieping
Type - ElementType: Elements; PredefinedType: USERDEFINED
Classification: 74 Vaste sanitaire voorzieningen (NL/SfB (2 cijfers)); 74 VASTE SANITAIRE VOORZIENINGEN (EcoQuaestor); 9 TERREIN (NL/SfB (4 cijfers)); Elementen (ARCHICAD Classification)
CPset_Phasing - Renovation Phase: Bestaand
AC_Pset_RenovationAndPhasing - Renovation Status: Existing
Component Quantities - Component, Component Volume (Net): 0.00592057 m3; Component, Component Volume (Gross): 0.00592057 m3

# IfcBuildingElementProxy: 3D Man staand contour 01 25, betontrap
In: 1e verdieping
Type - ElementType: Elements; PredefinedType: USERDEFINED
Classification: 74 Vaste sanitaire voorzieningen (NL/SfB (2 cijfers)); 74 VASTE SANITAIRE VOORZIENINGEN (EcoQuaestor); 9 TERREIN (NL/SfB (4 cijfers)); Elementen (ARCHICAD Classification)
CPset_Phasing - Renovation Phase: Bestaand
AC_Pset_RenovationAndPhasing - Renovation Status: Existing
Component Quantities - Component, Component Volume (Net): 0.0063607 m3; Component, Component Volume (Gross): 0.0063607 m3

# IfcBuildingElementProxy: 41 betonnen onderdorpel gevelbeplating 100 x 70 (16)
In: Begane grond
Classification: Dakafwerking (ARCHICAD Classification); Material: Beton gewapend prefab
AC_Pset_RenovationAndPhasing - Renovation Status: Existing
Material Properties - Beton gewapend prefab, ThermalConductivity: 2.5; Beton gewapend prefab, SpecificHeatCapacity: 1000 J/kg/K; Beton gewapend prefab, MassDensity: 2400 kg/m3; Beton gewapend prefab, Embodied Energy: 2.33 (MJ/kg); Beton gewapend prefab, Embodied Carbon: 0.242 (kgCO₂/kg); Beton gewapend prefab, Name: Beton gewapend prefab; Beton gewapend prefab, Participates in Collision Detection: yes
Component Quantities - Beton gewapend prefab, Component Cross Section Area: 0.00489091 m2
Name | Beton gewapend prefab, Mass (kg) | Beton gewapend prefab, Component Volume (Net) (m3) = Beton gewapend prefab, Component Volume (Gross) (m3)
onderdorpel | 108.162 | 0.0450674
onderdorpel | 33.2542 | 0.0138559
onderdorpel | 14.2126 | 0.00592192
onderdorpel | 22.2232 | 0.00925966
onderdorpel | 187.448 | 0.0781035
onderdorpel | 9.21569 | 0.00383987
onderdorpel | 36.7656 | 0.015319
onderdorpel | 8.56886 | 0.00357036
onderdorpel | 4.23839 | 0.001766
onderdorpel | 25.9415 | 0.010809
onderdorpel | 91.0883 | 0.0379535
onderdorpel | 39.2653 | 0.0163605
onderdorpel | 35.5562 | 0.0148151
onderdorpel | 21.0113 | 0.00875473
onderdorpel | 44.476 | 0.0185316
onderdorpel | 61.204 | 0.0255017

# IfcBuildingElementProxy: 41 lekdorpel - breedte variabel 180 x 70 (7)
Classification: Dakafwerking (ARCHICAD Classification); Material: Metaal - kleur buitenkozijnen
AC_Pset_RenovationAndPhasing - Renovation Status: Existing
Material Properties - Metaal - kleur buitenkozijnen, ThermalConductivity: 160; Metaal - kleur buitenkozijnen, SpecificHeatCapacity: 880 J/kg/K; Metaal - kleur buitenkozijnen, MassDensity: 2800 kg/m3; Metaal - kleur buitenkozijnen, Embodied Energy: 155 (MJ/kg); Metaal - kleur buitenkozijnen, Embodied Carbon: 9.16 (kgCO₂/kg); Metaal - kleur buitenkozijnen, Name: Metaal - kleur buitenkozijnen; Metaal - kleur buitenkozijnen, Participates in Collision Detection: yes
Name | In | Metaal - kleur buitenkozijnen, Mass (kg) | Metaal - kleur buitenkozijnen, Component Cross Section Area (m2) | Metaal - kleur buitenkozijnen, Component Volume (Net) (m3) | Metaal - kleur buitenkozijnen, Component Volume (Gross) (m3)
Lekdorpel | Begane grond | 18.7014 | 0.000510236 | 0.00667907 | 0.00667907
Lekdorpel | Begane grond | 31.4881 | 0.000510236 | 0.0112458 | 0.0112458
Dakrand | Begane grond | 9.08653 | 0.000510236 | 0.00324519 | 0.00324519
Lekdorpel | 1e verdieping | 31.4881 | 0.000510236 | 0.0112458 | 0.0112458
Lekdorpel | 1e verdieping | 18.6302 | 0.000510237 | 0.00665366 | 0.00665366
Lekdorpel | 1e verdieping | 31.3334 | 0.000510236 | 0.0111905 | 0.0112458
Lekdorpel | 1e verdieping | 18.63 | 0.000510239 | 0.00665357 | 0.00665368

# IfcBuildingElementProxy: 41 lekdorpel - breedte variabel 185 x 70 (3)
In: Begane grond
Classification: Dakafwerking (ARCHICAD Classification); Material: Metaal - kleur buitenkozijnen
AC_Pset_RenovationAndPhasing - Renovation Status: Existing
Material Properties - Metaal - kleur buitenkozijnen, ThermalConductivity: 160; Metaal - kleur buitenkozijnen, SpecificHeatCapacity: 880 J/kg/K; Metaal - kleur buitenkozijnen, MassDensity: 2800 kg/m3; Metaal - kleur buitenkozijnen, Embodied Energy: 155 (MJ/kg); Metaal - kleur buitenkozijnen, Embodied Carbon: 9.16 (kgCO₂/kg); Metaal - kleur buitenkozijnen, Name: Metaal - kleur buitenkozijnen; Metaal - kleur buitenkozijnen, Participates in Collision Detection: yes
Component Quantities - Metaal - kleur buitenkozijnen, Component Cross Section Area: 0.000520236 m2
Name | Metaal - kleur buitenkozijnen, Mass (kg) | Metaal - kleur buitenkozijnen, Component Volume (Net) (m3) = Metaal - kleur buitenkozijnen, Component Volume (Gross) (m3)
Lekdorpel | 24.8011 | 0.00885753
Lekdorpel | 16.6113 | 0.00593261
Lekdorpel | 6.74242 | 0.00240801

# IfcBuildingElementProxy: 41 lekdorpel - breedte variabel 195 x 70 (5)
In: Begane grond
Classification: Dakafwerking (ARCHICAD Classification); Material: Metaal - kleur buitenkozijnen
AC_Pset_RenovationAndPhasing - Renovation Status: Existing
Material Properties - Metaal - kleur buitenkozijnen, ThermalConductivity: 160; Metaal - kleur buitenkozijnen, SpecificHeatCapacity: 880 J/kg/K; Metaal - kleur buitenkozijnen, MassDensity: 2800 kg/m3; Metaal - kleur buitenkozijnen, Embodied Energy: 155 (MJ/kg); Metaal - kleur buitenkozijnen, Embodied Carbon: 9.16 (kgCO₂/kg); Metaal - kleur buitenkozijnen, Name: Metaal - kleur buitenkozijnen; Metaal - kleur buitenkozijnen, Participates in Collision Detection: yes
Name | Metaal - kleur buitenkozijnen, Mass (kg) | Metaal - kleur buitenkozijnen, Component Cross Section Area (m2) | Metaal - kleur buitenkozijnen, Component Volume (Net) (m3) = Metaal - kleur buitenkozijnen, Component Volume (Gross) (m3)
Lekdorpel | 16.1775 | 0.000540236 | 0.00577769
Lekdorpel | 9.22823 | 0.000539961 | 0.0032958
Lekdorpel | 25.173 | 0.000539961 | 0.00899037
Lekdorpel | 24.5682 | 0.000539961 | 0.00877436
Lekdorpel | 7.39694 | 0.000540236 | 0.00264177

# IfcBuildingElementProxy: AFW - noodoverloop 300 x 1040, NO
In: 1e verdieping
Classification: Dakafwerking (ARCHICAD Classification); Material: AFW - noodoverloop
AC_Pset_RenovationAndPhasing - Renovation Status: Existing
Material Properties - AFW - noodoverloop, ThermalConductivity: 52; AFW - noodoverloop, SpecificHeatCapacity: 530 J/kg/K; AFW - noodoverloop, MassDensity: 7800 kg/m3; AFW - noodoverloop, Embodied Energy: 25 (MJ/kg); AFW - noodoverloop, Embodied Carbon: 1.91 (kgCO₂/kg); AFW - noodoverloop, Name: AFW - noodoverloop; AFW - noodoverloop, Participates in Collision Detection: yes
Component Quantities - AFW - noodoverloop, Mass: 267.696 kg; AFW - noodoverloop, Projected Component Area (Net): 0.1144 m2; AFW - noodoverloop, Projected Component Area (Gross): 0.1144 m2; AFW - noodoverloop, Component Thickness: 300 mm; AFW - noodoverloop, Rectangular Component Height: 1040 mm; AFW - noodoverloop, Rectangular Component Width: 300 mm; AFW - noodoverloop, Component Cross Section Area: 0.312 m2; AFW - noodoverloop, Component Volume (Net): 0.03432 m3; AFW - noodoverloop, Component Volume (Gross): 0.03432 m3

# IfcBuildingElementProxy: AFW - noodoverloop 300 x 110 (28)
Classification: Dakafwerking (ARCHICAD Classification); Material: AFW - noodoverloop
AC_Pset_RenovationAndPhasing - Renovation Status: Existing
Material Properties - AFW - noodoverloop, ThermalConductivity: 52; AFW - noodoverloop, SpecificHeatCapacity: 530 J/kg/K; AFW - noodoverloop, MassDensity: 7800 kg/m3; AFW - noodoverloop, Embodied Energy: 25 (MJ/kg); AFW - noodoverloop, Embodied Carbon: 1.91 (kgCO₂/kg); AFW - noodoverloop, Name: AFW - noodoverloop; AFW - noodoverloop, Participates in Collision Detection: yes
Component Quantities - AFW - noodoverloop, Component Thickness: 300 mm; AFW - noodoverloop, Rectangular Component Height: 110 mm; AFW - noodoverloop, Rectangular Component Width: 300 mm; AFW - noodoverloop, Component Cross Section Area: 0.033 m2
Name | In | AFW - noodoverloop, Mass (kg) | AFW - noodoverloop, Projected Component Area (Net) (m2) = AFW - noodoverloop, Projected Component Area (Gross) (m2) | AFW - noodoverloop, Component Volume (Net) (m3) = AFW - noodoverloop, Component Volume (Gross) (m3)
3 x NO | 1e verdieping | 154.44 | 0.066 | 0.0198
13 x NO | 1e verdieping | 128.7 | 0.055 | 0.0165
7 x NO | 1e verdieping | 143.372 | 0.06127 | 0.018381
NO | 1e verdieping | 2.0592 | 0.00088 | 0.000264
NO | 1e verdieping | 108.881 | 0.0465302 | 0.0139591
3 x NO | Dak | 141.57 | 0.0605 | 0.01815

# IfcBuildingElementProxy: AFW - noodoverloop 300 x 1170 (10)
In: 1e verdieping
Classification: Dakafwerking (ARCHICAD Classification); Material: AFW - noodoverloop
AC_Pset_RenovationAndPhasing - Renovation Status: Existing
Material Properties - AFW - noodoverloop, ThermalConductivity: 52; AFW - noodoverloop, SpecificHeatCapacity: 530 J/kg/K; AFW - noodoverloop, MassDensity: 7800 kg/m3; AFW - noodoverloop, Embodied Energy: 25 (MJ/kg); AFW - noodoverloop, Embodied Carbon: 1.91 (kgCO₂/kg); AFW - noodoverloop, Name: AFW - noodoverloop; AFW - noodoverloop, Participates in Collision Detection: yes
Component Quantities - AFW - noodoverloop, Component Thickness: 300 mm; AFW - noodoverloop, Rectangular Component Height: 1170 mm; AFW - noodoverloop, Rectangular Component Width: 300 mm; AFW - noodoverloop, Component Cross Section Area: 0.351 m2
Name | AFW - noodoverloop, Mass (kg) | AFW - noodoverloop, Projected Component Area (Net) (m2) = AFW - noodoverloop, Projected Component Area (Gross) (m2) | AFW - noodoverloop, Component Volume (Net) (m3) = AFW - noodoverloop, Component Volume (Gross) (m3)
9 x NO | 301.158 | 0.1287 | 0.03861
NO | 21.9024 | 0.00936 | 0.002808

# IfcBuildingElementProxy: AFW - noodoverloop 300 x 1590, NO
In: 1e verdieping
Classification: Dakafwerking (ARCHICAD Classification); Material: AFW - noodoverloop
AC_Pset_RenovationAndPhasing - Renovation Status: Existing
Material Properties - AFW - noodoverloop, ThermalConductivity: 52; AFW - noodoverloop, SpecificHeatCapacity: 530 J/kg/K; AFW - noodoverloop, MassDensity: 7800 kg/m3; AFW - noodoverloop, Embodied Energy: 25 (MJ/kg); AFW - noodoverloop, Embodied Carbon: 1.91 (kgCO₂/kg); AFW - noodoverloop, Name: AFW - noodoverloop; AFW - noodoverloop, Participates in Collision Detection: yes
Component Quantities - AFW - noodoverloop, Mass: 409.266 kg; AFW - noodoverloop, Projected Component Area (Net): 0.1749 m2; AFW - noodoverloop, Projected Component Area (Gross): 0.1749 m2; AFW - noodoverloop, Component Thickness: 300 mm; AFW - noodoverloop, Rectangular Component Height: 1590 mm; AFW - noodoverloop, Rectangular Component Width: 300 mm; AFW - noodoverloop, Component Cross Section Area: 0.477 m2; AFW - noodoverloop, Component Volume (Net): 0.05247 m3; AFW - noodoverloop, Component Volume (Gross): 0.05247 m3

# IfcBuildingElementProxy: ALG - ALGEMEEN 20 (20)
In: Begane grond
Material: ALG - ALGEMEEN
AC_Pset_RenovationAndPhasing - Renovation Status: Existing
Material Properties - ALG - ALGEMEEN, ThermalConductivity: 0.27; ALG - ALGEMEEN, SpecificHeatCapacity: 840 J/kg/K; ALG - ALGEMEEN, MassDensity: 800 kg/m3; ALG - ALGEMEEN, Embodied Energy: 2 (MJ/kg); ALG - ALGEMEEN, Embodied Carbon: 0.13 (kgCO₂/kg); ALG - ALGEMEEN, Name: ALG - ALGEMEEN; ALG - ALGEMEEN, Participates in Collision Detection: yes
Component Quantities - ALG - ALGEMEEN, Component Thickness: 20 mm
Name | ALG - ALGEMEEN, Mass (kg) | ALG - ALGEMEEN, Projected Component Area (Net) (m2) = ALG - ALGEMEEN, Projected Component Area (Gross) (m2) | ALG - ALGEMEEN, Component Volume (Net) (m3) = ALG - ALGEMEEN, Component Volume (Gross) (m3)
6 x Garderobe | 8.70203 | 0.543877 | 0.0108775
2 x garderobe | 8.704 | 0.544 | 0.01088
2 x garderobe | 8.70355 | 0.543972 | 0.0108794
10 x garderobe | 8.70203 | 0.543877 | 0.0108775

# IfcBuildingElementProxy: ALG - ALGEMEEN 50 (8)
In: Begane grond
Classification: 72 Vaste inrichting voor gebruiksruimten (NL/SfB (2 cijfers)); Material: ALG - ALGEMEEN
AC_Pset_RenovationAndPhasing - Renovation Status: Existing
Material Properties - ALG - ALGEMEEN, ThermalConductivity: 0.27; ALG - ALGEMEEN, SpecificHeatCapacity: 840 J/kg/K; ALG - ALGEMEEN, MassDensity: 800 kg/m3; ALG - ALGEMEEN, Embodied Energy: 2 (MJ/kg); ALG - ALGEMEEN, Embodied Carbon: 0.13 (kgCO₂/kg); ALG - ALGEMEEN, Name: ALG - ALGEMEEN; ALG - ALGEMEEN, Participates in Collision Detection: yes
Component Quantities - ALG - ALGEMEEN, Component Thickness: 50 mm; ALG - ALGEMEEN, Rectangular Component Width: 50 mm
Name | ALG - ALGEMEEN, Mass (kg) | ALG - ALGEMEEN, Projected Component Area (Net) (m2) = ALG - ALGEMEEN, Projected Component Area (Gross) (m2) | ALG - ALGEMEEN, Rectangular Component Height (mm) | ALG - ALGEMEEN, Component Cross Section Area (m2) | ALG - ALGEMEEN, Component Volume (Net) (m3) = ALG - ALGEMEEN, Component Volume (Gross) (m3)
wandtegelwerk | 5.6 | 0.14 | 700 | 0.035 | 0.007
wandtegelwerk | 21 | 0.525 | 700 | 0.035 | 0.02625
 | 109.2 | 2.73 | 700 | 0.035 | 0.1365
wandtegelwerk | 22.4 | 0.56 | 700 | 0.035 | 0.028
wandtegelwerk | 4.2 | 0.105 | 700 | 0.035 | 0.00525
2 x wandtegelwerk | 6.5 | 0.1625 | 250 | 0.0125 | 0.008125
 | 36 | 0.9 | 250 | 0.0125 | 0.045

# IfcBuildingElementProxy: ALG - ALGEMEEN D20 (6)
In: Begane grond
Classification: Dakafwerking (ARCHICAD Classification); Material: ALG - ALGEMEEN
AC_Pset_RenovationAndPhasing - Renovation Status: Existing
Material Properties - ALG - ALGEMEEN, ThermalConductivity: 0.27; ALG - ALGEMEEN, SpecificHeatCapacity: 840 J/kg/K; ALG - ALGEMEEN, MassDensity: 800 kg/m3; ALG - ALGEMEEN, Embodied Energy: 2 (MJ/kg); ALG - ALGEMEEN, Embodied Carbon: 0.13 (kgCO₂/kg); ALG - ALGEMEEN, Name: ALG - ALGEMEEN; ALG - ALGEMEEN, Participates in Collision Detection: yes
Component Quantities - ALG - ALGEMEEN, Mass: 0.134407 kg; ALG - ALGEMEEN, Projected Component Area (Net): 0.01188 m2; ALG - ALGEMEEN, Projected Component Area (Gross): 0.01188 m2; ALG - ALGEMEEN, Component Thickness: 20 mm; ALG - ALGEMEEN, Component Cross Section Area: 0.000314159 m2; ALG - ALGEMEEN, Component Volume (Net): 0.000168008 m3; ALG - ALGEMEEN, Component Volume (Gross): 0.000168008 m3

# IfcBuildingElementProxy: ALG - BINNENAFWERKING 10 (40)
In: Begane grond
Classification: 72 Vaste inrichting voor gebruiksruimten (NL/SfB (2 cijfers)); Material: ALG - BINNENAFWERKING
AC_Pset_RenovationAndPhasing - Renovation Status: Existing
Material Properties - ALG - BINNENAFWERKING, ThermalConductivity: 0.27; ALG - BINNENAFWERKING, SpecificHeatCapacity: 840 J/kg/K; ALG - BINNENAFWERKING, MassDensity: 800 kg/m3; ALG - BINNENAFWERKING, Embodied Energy: 2 (MJ/kg); ALG - BINNENAFWERKING, Embodied Carbon: 0.13 (kgCO₂/kg); ALG - BINNENAFWERKING, Name: ALG - BINNENAFWERKING; ALG - BINNENAFWERKING, Participates in Collision Detection: yes
Component Quantities - ALG - BINNENAFWERKING, Component Thickness: 10 mm; ALG - BINNENAFWERKING, Rectangular Component Height: 1240 mm; ALG - BINNENAFWERKING, Rectangular Component Width: 10 mm; ALG - BINNENAFWERKING, Component Cross Section Area: 0.0124 m2
Name | ALG - BINNENAFWERKING, Mass (kg) | ALG - BINNENAFWERKING, Projected Component Area (Net) (m2) = ALG - BINNENAFWERKING, Projected Component Area (Gross) (m2) | ALG - BINNENAFWERKING, Component Volume (Net) (m3) = ALG - BINNENAFWERKING, Component Volume (Gross) (m3)
17 x garderobe | 6.7344 | 0.8418 | 0.008418
3 x garderobe | 6.9328 | 0.8666 | 0.008666
2 x garderobe | 6.936 | 0.867 | 0.00867
17 x garderobe | 6.5392 | 0.8174 | 0.008174
garderobe | 6.48083 | 0.810104 | 0.00810104

# IfcBuildingElementProxy: ALG - BINNENAFWERKING 19 (72)
In: Begane grond
Classification: 72 Vaste inrichting voor gebruiksruimten (NL/SfB (2 cijfers)); Material: ALG - BINNENAFWERKING
AC_Pset_RenovationAndPhasing - Renovation Status: Existing
Material Properties - ALG - BINNENAFWERKING, ThermalConductivity: 0.27; ALG - BINNENAFWERKING, SpecificHeatCapacity: 840 J/kg/K; ALG - BINNENAFWERKING, MassDensity: 800 kg/m3; ALG - BINNENAFWERKING, Embodied Energy: 2 (MJ/kg); ALG - BINNENAFWERKING, Embodied Carbon: 0.13 (kgCO₂/kg); ALG - BINNENAFWERKING, Name: ALG - BINNENAFWERKING; ALG - BINNENAFWERKING, Participates in Collision Detection: yes
Component Quantities - ALG - BINNENAFWERKING, Component Thickness: 19 mm; ALG - BINNENAFWERKING, Rectangular Component Width: 19 mm
Name | ALG - BINNENAFWERKING, Mass (kg) | ALG - BINNENAFWERKING, Projected Component Area (Net) (m2) | ALG - BINNENAFWERKING, Projected Component Area (Gross) (m2) | ALG - BINNENAFWERKING, Rectangular Component Height (mm) | ALG - BINNENAFWERKING, Component Cross Section Area (m2) | ALG - BINNENAFWERKING, Component Volume (Net) (m3) | ALG - BINNENAFWERKING, Component Volume (Gross) (m3)
10 x garderobe | 0.32019 | 0.0210651 | 0.0210651 | 60 | 0.00114 | 0.000400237 | 0.000400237
12 x garderobe | 2.43456 | 0.160169 | 0.165787 | 251 | 0.004769 | 0.0030432 | 0.00314996
6 x garderobe | 1.50734 | 0.0991668 | 0.0991668 | 261 | 0.004959 | 0.00188417 | 0.00188417
22 x garderobe | 3.51424 | 0.2312 | 0.2312 | 170 | 0.00323 | 0.0043928 | 0.0043928
10 x garderobe | 2.55359 | 0.168 | 0.168 | 60 | 0.00114 | 0.00319199 | 0.00319199
10 x garderobe | 0.320107 | 0.0210597 | 0.0210597 | 60 | 0.00114 | 0.000400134 | 0.000400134
2 x garderobe | 1.27093 | 0.0836139 | 0.0836139 | 220 | 0.00418 | 0.00158866 | 0.00158866

# IfcBuildingElementProxy: ALG - BINNENAFWERKING 20 (71)
In: Begane grond
Classification: 72 Vaste inrichting voor gebruiksruimten (NL/SfB (2 cijfers)); Material: ALG - BINNENAFWERKING
AC_Pset_RenovationAndPhasing - Renovation Status: Existing
Material Properties - ALG - BINNENAFWERKING, ThermalConductivity: 0.27; ALG - BINNENAFWERKING, SpecificHeatCapacity: 840 J/kg/K; ALG - BINNENAFWERKING, MassDensity: 800 kg/m3; ALG - BINNENAFWERKING, Embodied Energy: 2 (MJ/kg); ALG - BINNENAFWERKING, Embodied Carbon: 0.13 (kgCO₂/kg); ALG - BINNENAFWERKING, Name: ALG - BINNENAFWERKING; ALG - BINNENAFWERKING, Participates in Collision Detection: yes
Component Quantities - ALG - BINNENAFWERKING, Component Thickness: 20 mm; ALG - BINNENAFWERKING, Rectangular Component Width: 20 mm
Name | ALG - BINNENAFWERKING, Mass (kg) | ALG - BINNENAFWERKING, Projected Component Area (Net) (m2) = ALG - BINNENAFWERKING, Projected Component Area (Gross) (m2) | ALG - BINNENAFWERKING, Rectangular Component Height (mm) | ALG - BINNENAFWERKING, Component Cross Section Area (m2) | ALG - BINNENAFWERKING, Component Volume (Net) (m3) = ALG - BINNENAFWERKING, Component Volume (Gross) (m3)
garderobe | 11.4274 | 0.73892 | 2247.27 | 0.0449454 | 0.0142843
2 x garderobe | 8.85722 | 0.553576 | 732 | 0.01464 | 0.0110715
2 x garderobe | 8.7401 | 0.546256 | 732 | 0.01464 | 0.0109251
garderobe | 8.733 | 0.546256 | 732 | 0.01464 | 0.0109163
garderobe | 8.85002 | 0.553576 | 732 | 0.01464 | 0.0110625
6 x garderobe | 7.7376 | 0.4836 | 1240 | 0.0248 | 0.009672
13 x garderobe | 7.936 | 0.496 | 1240 | 0.0248 | 0.00992
20 x garderobe | 1.30547 | 0.0815917 | 219.924 | 0.00439847 | 0.00163183
10 x garderobe | 7.9342 | 0.495888 | 1240 | 0.0248 | 0.00991775
3 x garderobe | 7.94591 | 0.496619 | 1240 | 0.0248 | 0.00993238
8 x garderobe | 7.93421 | 0.495888 | 1240 | 0.0248 | 0.00991776
4 x garderobe | 5.88306 | 0.367691 | 919.27 | 0.0183854 | 0.00735382

# IfcBuildingElementProxy: ALG - BINNENAFWERKING 24 (2)
In: Begane grond
Classification: 72 Vaste inrichting voor gebruiksruimten (NL/SfB (2 cijfers)); Material: ALG - BINNENAFWERKING
AC_Pset_RenovationAndPhasing - Renovation Status: Existing
Material Properties - ALG - BINNENAFWERKING, ThermalConductivity: 0.27; ALG - BINNENAFWERKING, SpecificHeatCapacity: 840 J/kg/K; ALG - BINNENAFWERKING, MassDensity: 800 kg/m3; ALG - BINNENAFWERKING, Embodied Energy: 2 (MJ/kg); ALG - BINNENAFWERKING, Embodied Carbon: 0.13 (kgCO₂/kg); ALG - BINNENAFWERKING, Name: ALG - BINNENAFWERKING; ALG - BINNENAFWERKING, Participates in Collision Detection: yes
Component Quantities - ALG - BINNENAFWERKING, Mass: 9.45143 kg; ALG - BINNENAFWERKING, Projected Component Area (Net): 0.492262 m2; ALG - BINNENAFWERKING, Projected Component Area (Gross): 0.492262 m2; ALG - BINNENAFWERKING, Component Thickness: 24 mm; ALG - BINNENAFWERKING, Component Volume (Net): 0.0118143 m3; ALG - BINNENAFWERKING, Component Volume (Gross): 0.0118143 m3

# IfcBuildingElementProxy: ALG - BINNENAFWERKING_hoge prioriteit 100 x 20 (6)
In: Begane grond
Material: ALG - BINNENAFWERKING_hoge prioriteit
AC_Pset_RenovationAndPhasing - Renovation Status: Existing
Material Properties - ALG - BINNENAFWERKING_hoge prioriteit, ThermalConductivity: 0.5; ALG - BINNENAFWERKING_hoge prioriteit, SpecificHeatCapacity: 840 J/kg/K; ALG - BINNENAFWERKING_hoge prioriteit, MassDensity: 1300 kg/m3; ALG - BINNENAFWERKING_hoge prioriteit, Embodied Energy: 0.75 (MJ/kg); ALG - BINNENAFWERKING_hoge prioriteit, Embodied Carbon: 0.1 (kgCO₂/kg); ALG - BINNENAFWERKING_hoge prioriteit, Name: ALG - BINNENAFWERKING_hoge prioriteit; ALG - BINNENAFWERKING_hoge prioriteit, Participates in Collision Detection: yes
Component Quantities - ALG - BINNENAFWERKING_hoge prioriteit, Component Thickness: 100 mm; ALG - BINNENAFWERKING_hoge prioriteit, Rectangular Component Height: 20 mm; ALG - BINNENAFWERKING_hoge prioriteit, Rectangular Component Width: 100 mm; ALG - BINNENAFWERKING_hoge prioriteit, Component Cross Section Area: 0.002 m2
Name | Classification | ALG - BINNENAFWERKING_hoge prioriteit, Mass (kg) | ALG - BINNENAFWERKING_hoge prioriteit, Component Volume (Net) (m3) = ALG - BINNENAFWERKING_hoge prioriteit, Component Volume (Gross) (m3)
4 x Kolom | 28 HOOFDDRAAGCONSTRUCTIES (EcoQuaestor); 28 Hoofddraagconstructies (NL/SfB (2 cijfers)) | 6.006 | 0.00462
 | Dakafwerking (ARCHICAD Classification) | 7.384 | 0.00568 | Component Quantities - ALG - BINNENAFWERKING_hoge prioriteit, Projected Component Area (Net): 0.0568 m2; ALG - BINNENAFWERKING_hoge prioriteit, Projected Component Area (Gross): 0.0568 m2
 | Dakafwerking (ARCHICAD Classification) | 6.63 | 0.0051 | Component Quantities - ALG - BINNENAFWERKING_hoge prioriteit, Projected Component Area (Net): 0.051 m2; ALG - BINNENAFWERKING_hoge prioriteit, Projected Component Area (Gross): 0.051 m2

# IfcBuildingElementProxy: ALG - BINNENAFWERKING_hoge prioriteit 104 x 90 (12)
In: Begane grond
Material: ALG - BINNENAFWERKING_hoge prioriteit
AC_Pset_RenovationAndPhasing - Renovation Status: Existing
Material Properties - ALG - BINNENAFWERKING_hoge prioriteit, ThermalConductivity: 0.5; ALG - BINNENAFWERKING_hoge prioriteit, SpecificHeatCapacity: 840 J/kg/K; ALG - BINNENAFWERKING_hoge prioriteit, MassDensity: 1300 kg/m3; ALG - BINNENAFWERKING_hoge prioriteit, Embodied Energy: 0.75 (MJ/kg); ALG - BINNENAFWERKING_hoge prioriteit, Embodied Carbon: 0.1 (kgCO₂/kg); ALG - BINNENAFWERKING_hoge prioriteit, Name: ALG - BINNENAFWERKING_hoge prioriteit; ALG - BINNENAFWERKING_hoge prioriteit, Participates in Collision Detection: yes
Component Quantities - ALG - BINNENAFWERKING_hoge prioriteit, Component Thickness: 104 mm; ALG - BINNENAFWERKING_hoge prioriteit, Rectangular Component Height: 90 mm; ALG - BINNENAFWERKING_hoge prioriteit, Rectangular Component Width: 104 mm; ALG - BINNENAFWERKING_hoge prioriteit, Component Cross Section Area: 0.00936 m2
Name | Classification | ALG - BINNENAFWERKING_hoge prioriteit, Mass (kg) | ALG - BINNENAFWERKING_hoge prioriteit, Component Volume (Net) (m3) = ALG - BINNENAFWERKING_hoge prioriteit, Component Volume (Gross) (m3)
8 x Kolom | 28 HOOFDDRAAGCONSTRUCTIES (EcoQuaestor); 28 Hoofddraagconstructies (NL/SfB (2 cijfers)) | 28.1081 | 0.0216216
2 x  | Dakafwerking (ARCHICAD Classification) | 62.3002 | 0.0479232 | Component Quantities - ALG - BINNENAFWERKING_hoge prioriteit, Projected Component Area (Net): 0.4608 m2; ALG - BINNENAFWERKING_hoge prioriteit, Projected Component Area (Gross): 0.4608 m2
2 x  | Dakafwerking (ARCHICAD Classification) | 67.8974 | 0.0522288 | Component Quantities - ALG - BINNENAFWERKING_hoge prioriteit, Projected Component Area (Net): 0.5022 m2; ALG - BINNENAFWERKING_hoge prioriteit, Projected Component Area (Gross): 0.5022 m2

# IfcBuildingElementProxy: ALG - BINNENAFWERKING_hoge prioriteit 114 x 70, Kolom
In: Begane grond
Classification: 28 HOOFDDRAAGCONSTRUCTIES (EcoQuaestor); 28 Hoofddraagconstructies (NL/SfB (2 cijfers)); Material: ALG - BINNENAFWERKING_hoge prioriteit
AC_Pset_RenovationAndPhasing - Renovation Status: Existing
Material Properties - ALG - BINNENAFWERKING_hoge prioriteit, ThermalConductivity: 0.5; ALG - BINNENAFWERKING_hoge prioriteit, SpecificHeatCapacity: 840 J/kg/K; ALG - BINNENAFWERKING_hoge prioriteit, MassDensity: 1300 kg/m3; ALG - BINNENAFWERKING_hoge prioriteit, Embodied Energy: 0.75 (MJ/kg); ALG - BINNENAFWERKING_hoge prioriteit, Embodied Carbon: 0.1 (kgCO₂/kg); ALG - BINNENAFWERKING_hoge prioriteit, Name: ALG - BINNENAFWERKING_hoge prioriteit; ALG - BINNENAFWERKING_hoge prioriteit, Participates in Collision Detection: yes
Component Quantities - ALG - BINNENAFWERKING_hoge prioriteit, Mass: 24.659 kg; ALG - BINNENAFWERKING_hoge prioriteit, Component Thickness: 114 mm; ALG - BINNENAFWERKING_hoge prioriteit, Rectangular Component Height: 70 mm; ALG - BINNENAFWERKING_hoge prioriteit, Rectangular Component Width: 114 mm; ALG - BINNENAFWERKING_hoge prioriteit, Component Cross Section Area: 0.00798 m2; ALG - BINNENAFWERKING_hoge prioriteit, Component Volume (Net): 0.0189685 m3; ALG - BINNENAFWERKING_hoge prioriteit, Component Volume (Gross): 0.0189685 m3

# IfcBuildingElementProxy: ALG - BINNENAFWERKING_hoge prioriteit 20 x 130, Kolom
In: Begane grond
Classification: 28 HOOFDDRAAGCONSTRUCTIES (EcoQuaestor); 28 Hoofddraagconstructies (NL/SfB (2 cijfers)); Material: ALG - BINNENAFWERKING_hoge prioriteit
AC_Pset_RenovationAndPhasing - Renovation Status: Existing
Material Properties - ALG - BINNENAFWERKING_hoge prioriteit, ThermalConductivity: 0.5; ALG - BINNENAFWERKING_hoge prioriteit, SpecificHeatCapacity: 840 J/kg/K; ALG - BINNENAFWERKING_hoge prioriteit, MassDensity: 1300 kg/m3; ALG - BINNENAFWERKING_hoge prioriteit, Embodied Energy: 0.75 (MJ/kg); ALG - BINNENAFWERKING_hoge prioriteit, Embodied Carbon: 0.1 (kgCO₂/kg); ALG - BINNENAFWERKING_hoge prioriteit, Name: ALG - BINNENAFWERKING_hoge prioriteit; ALG - BINNENAFWERKING_hoge prioriteit, Participates in Collision Detection: yes
Component Quantities - ALG - BINNENAFWERKING_hoge prioriteit, Mass: 7.8078 kg; ALG - BINNENAFWERKING_hoge prioriteit, Component Thickness: 20 mm; ALG - BINNENAFWERKING_hoge prioriteit, Rectangular Component Height: 130 mm; ALG - BINNENAFWERKING_hoge prioriteit, Rectangular Component Width: 20 mm; ALG - BINNENAFWERKING_hoge prioriteit, Component Cross Section Area: 0.0026 m2; ALG - BINNENAFWERKING_hoge prioriteit, Component Volume (Net): 0.006006 m3; ALG - BINNENAFWERKING_hoge prioriteit, Component Volume (Gross): 0.006006 m3

# IfcBuildingElementProxy: ALG - BINNENAFWERKING_hoge prioriteit 20 x 90 (11)
In: Begane grond
Material: ALG - BINNENAFWERKING_hoge prioriteit
AC_Pset_RenovationAndPhasing - Renovation Status: Existing
Material Properties - ALG - BINNENAFWERKING_hoge prioriteit, ThermalConductivity: 0.5; ALG - BINNENAFWERKING_hoge prioriteit, SpecificHeatCapacity: 840 J/kg/K; ALG - BINNENAFWERKING_hoge prioriteit, MassDensity: 1300 kg/m3; ALG - BINNENAFWERKING_hoge prioriteit, Embodied Energy: 0.75 (MJ/kg); ALG - BINNENAFWERKING_hoge prioriteit, Embodied Carbon: 0.1 (kgCO₂/kg); ALG - BINNENAFWERKING_hoge prioriteit, Name: ALG - BINNENAFWERKING_hoge prioriteit; ALG - BINNENAFWERKING_hoge prioriteit, Participates in Collision Detection: yes
Component Quantities - ALG - BINNENAFWERKING_hoge prioriteit, Component Thickness: 20 mm; ALG - BINNENAFWERKING_hoge prioriteit, Rectangular Component Height: 90 mm; ALG - BINNENAFWERKING_hoge prioriteit, Rectangular Component Width: 20 mm; ALG - BINNENAFWERKING_hoge prioriteit, Component Cross Section Area: 0.0018 m2
Name | Classification | ALG - BINNENAFWERKING_hoge prioriteit, Mass (kg) | ALG - BINNENAFWERKING_hoge prioriteit, Component Volume (Net) (m3) = ALG - BINNENAFWERKING_hoge prioriteit, Component Volume (Gross) (m3)
7 x Kolom | 28 HOOFDDRAAGCONSTRUCTIES (EcoQuaestor); 28 Hoofddraagconstructies (NL/SfB (2 cijfers)) | 5.4054 | 0.004158
2 x  | Dakafwerking (ARCHICAD Classification) | 6.3414 | 0.004878 | Component Quantities - ALG - BINNENAFWERKING_hoge prioriteit, Projected Component Area (Net): 0.2439 m2; ALG - BINNENAFWERKING_hoge prioriteit, Projected Component Area (Gross): 0.2439 m2
 | Dakafwerking (ARCHICAD Classification) | 6.8796 | 0.005292 | Component Quantities - ALG - BINNENAFWERKING_hoge prioriteit, Projected Component Area (Net): 0.2646 m2; ALG - BINNENAFWERKING_hoge prioriteit, Projected Component Area (Gross): 0.2646 m2
 | Dakafwerking (ARCHICAD Classification) | 6.9732 | 0.005364 | Component Quantities - ALG - BINNENAFWERKING_hoge prioriteit, Projected Component Area (Net): 0.2682 m2; ALG - BINNENAFWERKING_hoge prioriteit, Projected Component Area (Gross): 0.2682 m2

# IfcBuildingElementProxy: ALG - BINNENAFWERKING_hoge prioriteit 200 x 20 (6)
In: Begane grond
Material: ALG - BINNENAFWERKING_hoge prioriteit
AC_Pset_RenovationAndPhasing - Renovation Status: Existing
Material Properties - ALG - BINNENAFWERKING_hoge prioriteit, ThermalConductivity: 0.5; ALG - BINNENAFWERKING_hoge prioriteit, SpecificHeatCapacity: 840 J/kg/K; ALG - BINNENAFWERKING_hoge prioriteit, MassDensity: 1300 kg/m3; ALG - BINNENAFWERKING_hoge prioriteit, Embodied Energy: 0.75 (MJ/kg); ALG - BINNENAFWERKING_hoge prioriteit, Embodied Carbon: 0.1 (kgCO₂/kg); ALG - BINNENAFWERKING_hoge prioriteit, Name: ALG - BINNENAFWERKING_hoge prioriteit; ALG - BINNENAFWERKING_hoge prioriteit, Participates in Collision Detection: yes
Component Quantities - ALG - BINNENAFWERKING_hoge prioriteit, Component Thickness: 200 mm; ALG - BINNENAFWERKING_hoge prioriteit, Rectangular Component Height: 20 mm; ALG - BINNENAFWERKING_hoge prioriteit, Rectangular Component Width: 200 mm; ALG - BINNENAFWERKING_hoge prioriteit, Component Cross Section Area: 0.004 m2
Name | Classification | ALG - BINNENAFWERKING_hoge prioriteit, Mass (kg) | ALG - BINNENAFWERKING_hoge prioriteit, Component Volume (Net) (m3) = ALG - BINNENAFWERKING_hoge prioriteit, Component Volume (Gross) (m3)
4 x Kolom | 28 HOOFDDRAAGCONSTRUCTIES (EcoQuaestor); 28 Hoofddraagconstructies (NL/SfB (2 cijfers)) | 12.012 | 0.00924
 | Dakafwerking (ARCHICAD Classification) | 13.364 | 0.01028 | Component Quantities - ALG - BINNENAFWERKING_hoge prioriteit, Projected Component Area (Net): 0.0514 m2; ALG - BINNENAFWERKING_hoge prioriteit, Projected Component Area (Gross): 0.0514 m2
 | Dakafwerking (ARCHICAD Classification) | 14.56 | 0.0112 | Component Quantities - ALG - BINNENAFWERKING_hoge prioriteit, Projected Component Area (Net): 0.056 m2; ALG - BINNENAFWERKING_hoge prioriteit, Projected Component Area (Gross): 0.056 m2

# IfcBuildingElementProxy: ALG - BINNENWAND 410, garderobe
In: Begane grond
Classification: 22 BINNENWANDEN (NL/SfB (4 cijfers)); Material: ALG - BINNENWAND
AC_Pset_RenovationAndPhasing - Renovation Status: Existing
Material Properties - ALG - BINNENWAND, ThermalConductivity: 0.9; ALG - BINNENWAND, SpecificHeatCapacity: 840 J/kg/K; ALG - BINNENWAND, MassDensity: 1900 kg/m3; ALG - BINNENWAND, Embodied Energy: 0.75 (MJ/kg); ALG - BINNENWAND, Embodied Carbon: 0.1 (kgCO₂/kg); ALG - BINNENWAND, Name: ALG - BINNENWAND; ALG - BINNENWAND, Participates in Collision Detection: yes
Component Quantities - ALG - BINNENWAND, Mass: 1080.37 kg; ALG - BINNENWAND, Projected Component Area (Net): 1.38687 m2; ALG - BINNENWAND, Projected Component Area (Gross): 7.38714 m2; ALG - BINNENWAND, Component Thickness: 410 mm; ALG - BINNENWAND, Rectangular Component Height: 1219 mm; ALG - BINNENWAND, Rectangular Component Width: 410 mm; ALG - BINNENWAND, Component Cross Section Area: 0.49979 m2; ALG - BINNENWAND, Component Volume (Net): 0.568618 m3; ALG - BINNENWAND, Component Volume (Gross): 3.0287 m3

# IfcBuildingElementProxy: ALG - BINNENWAND 600, garderobe
In: Begane grond
Classification: 22 BINNENWANDEN (NL/SfB (4 cijfers)); Material: ALG - BINNENWAND
AC_Pset_RenovationAndPhasing - Renovation Status: Existing
Material Properties - ALG - BINNENWAND, ThermalConductivity: 0.9; ALG - BINNENWAND, SpecificHeatCapacity: 840 J/kg/K; ALG - BINNENWAND, MassDensity: 1900 kg/m3; ALG - BINNENWAND, Embodied Energy: 0.75 (MJ/kg); ALG - BINNENWAND, Embodied Carbon: 0.1 (kgCO₂/kg); ALG - BINNENWAND, Name: ALG - BINNENWAND; ALG - BINNENWAND, Participates in Collision Detection: yes
Component Quantities - ALG - BINNENWAND, Mass: 3253.56 kg; ALG - BINNENWAND, Projected Component Area (Net): 2.854 m2; ALG - BINNENWAND, Projected Component Area (Gross): 12.214 m2; ALG - BINNENWAND, Component Thickness: 600 mm; ALG - BINNENWAND, Rectangular Component Height: 3100 mm; ALG - BINNENWAND, Rectangular Component Width: 600 mm; ALG - BINNENWAND, Component Cross Section Area: 1.86 m2; ALG - BINNENWAND, Component Volume (Net): 1.7124 m3; ALG - BINNENWAND, Component Volume (Gross): 7.3284 m3

# IfcBuildingElementProxy: ALG - BUITEN MEMBRAAN 20 (22)
In: Begane grond
Material: ALG - BUITEN MEMBRAAN
Pset_SlabCommon - Reference: Type Dak
AC_Pset_RenovationAndPhasing - Renovation Status: Existing
Material Properties - ALG - BUITEN MEMBRAAN, ThermalConductivity: 0.2; ALG - BUITEN MEMBRAAN, SpecificHeatCapacity: 1840 J/kg/K; ALG - BUITEN MEMBRAAN, MassDensity: 1050 kg/m3; ALG - BUITEN MEMBRAAN, Embodied Energy: 51 (MJ/kg); ALG - BUITEN MEMBRAAN, Embodied Carbon: 0.38 (kgCO₂/kg); ALG - BUITEN MEMBRAAN, Name: ALG - BUITEN MEMBRAAN; ALG - BUITEN MEMBRAAN, Participates in Collision Detection: yes
Component Quantities - ALG - BUITEN MEMBRAAN, Component Thickness: 20 mm
Name | ALG - BUITEN MEMBRAAN, Mass (kg) | ALG - BUITEN MEMBRAAN, Projected Component Area (Net) (m2) = ALG - BUITEN MEMBRAAN, Projected Component Area (Gross) (m2) | ALG - BUITEN MEMBRAAN, Component Volume (Net) (m3) = ALG - BUITEN MEMBRAAN, Component Volume (Gross) (m3)
20 x Dak-x | 11.1809 | 0.534806 | 0.0106485
2 x Dak-x | 11.5113 | 0.550536 | 0.0109631

# IfcBuildingElementProxy: Afwerking dagkant 02 21 (3)
In: Begane grond
Material: Hout - algemeen
AC_Pset_RenovationAndPhasing - Renovation Status: Existing
Material Properties - Hout - algemeen, ThermalConductivity: 0.17; Hout - algemeen, SpecificHeatCapacity: 1880 J/kg/K; Hout - algemeen, MassDensity: 800 kg/m3; Hout - algemeen, Embodied Energy: 10.4 (MJ/kg); Hout - algemeen, Embodied Carbon: 0.23 (kgCO₂/kg); Hout - algemeen, Name: Hout - algemeen; Hout - algemeen, Participates in Collision Detection: yes
Name | Hout - algemeen, Mass (kg) | Hout - algemeen, Component Volume (Net) (m3) = Hout - algemeen, Component Volume (Gross) (m3)
garderobe | 11.2847 | 0.0141059
2 x garderobe | 12.5976 | 0.015747

# IfcBuildingElementProxy: Bol half 25 (30)
In: Begane grond
AC_Pset_RenovationAndPhasing - Renovation Status: Existing
Component Quantities - Component, Component Volume (Net): 0.000258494 m3; Component, Component Volume (Gross): 0.000258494 m3

# IfcBuildingElementProxy: Buis 25 (4)
In: Begane grond
AC_Pset_RenovationAndPhasing - Renovation Status: Existing
Name | Component, Component Volume (Net) (m3) = Component, Component Volume (Gross) (m3)
2 x kruis | 0.000994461
2 x kruis | 0.000559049

# IfcBuildingElementProxy: Cilinder 25 (30)
In: Begane grond
AC_Pset_RenovationAndPhasing - Renovation Status: Existing
Component Quantities - Component, Component Volume (Net): 0.0000195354 m3; Component, Component Volume (Gross): 0.0000195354 m3

# IfcBuildingElementProxy: D1 25 (2)
In: Begane grond
AC_Pset_RenovationAndPhasing - Renovation Status: Existing
Name | Component, Component Volume (Net) (m3) = Component, Component Volume (Gross) (m3)
deur panelenwand | 0.24568
deur panelenwand | 0.227073

# IfcBuildingElementProxy: DS1 voor wand 25 (4)
In: Begane grond
Type - ElementType: Elements; PredefinedType: USERDEFINED
Classification: 32 Binnenwandopeningen (NL/SfB (4 cijfers)); Openingen (ARCHICAD Classification)
Pset_FireRatingProperties - FireResistanceRating: ---
CPset_Phasing - Renovation Phase: Bestaand
AC_Pset_RenovationAndPhasing - Renovation Status: Existing
Name | Component, Component Volume (Net) (m3) = Component, Component Volume (Gross) (m3)
s.07 | 0.10333
s.06 | 0.0972466
s.05 | 0.10333
s.08 | 0.0972466

# IfcBuildingElementProxy: DSn 25 (11)
In: Begane grond
Type - ElementType: Elements; PredefinedType: USERDEFINED
Classification: 32 Binnenwandopeningen (NL/SfB (4 cijfers)); Openingen (ARCHICAD Classification)
Pset_FireRatingProperties - FireResistanceRating: ---
CPset_Phasing - Renovation Phase: Bestaand
AC_Pset_RenovationAndPhasing - Renovation Status: Existing
Name | Component, Component Volume (Net) (m3) = Component, Component Volume (Gross) (m3)
5 x s.02 | 0.23336
2 x s.04 | 0.287901
2 x s.04-sp | 0.287901
s.01 | 0.287901
s.03 | 0.23336

# IfcBuildingElementProxy: Daklicht rond 02 25 (12)
In: 1e verdieping
AC_Pset_RenovationAndPhasing - Renovation Status: Existing
Name | Component, Component Volume (Net) (m3) = Component, Component Volume (Gross) (m3)
6 x hart | 0.00571525
6 x hart | 0.00599651

# IfcBuildingElementProxy: Hellingbaan recht 25 (4)
In: Begane grond
Material: Tegels - Bestrating
AC_Pset_RenovationAndPhasing - Renovation Status: Existing
Material Properties - Tegels - Bestrating, ThermalConductivity: 1.3; Tegels - Bestrating, SpecificHeatCapacity: 840 J/kg/K; Tegels - Bestrating, MassDensity: 2300 kg/m3; Tegels - Bestrating, Embodied Energy: 10 (MJ/kg); Tegels - Bestrating, Embodied Carbon: 0.7 (kgCO₂/kg); Tegels - Bestrating, Name: Tegels - Bestrating; Tegels - Bestrating, Participates in Collision Detection: yes
Name | Tegels - Bestrating, Mass (kg) | Tegels - Bestrating, Component Volume (Net) (m3) = Tegels - Bestrating, Component Volume (Gross) (m3)
bestrating | 2555.22 | 1.11096
bestrating | 2595.04 | 1.12828
tafel | 2555.22 | 1.11096
tafel | 2595.04 | 1.12828

# IfcBuildingElementProxy: Hout - MDF binnenzijde 10 x 50 (2)
In: Begane grond
Classification: 21 Buitenwanden (NL/SfB (2 cijfers)); Discrete Accessory (ARCHICAD Classification); Material: Hout - MDF binnenzijde
AC_Pset_RenovationAndPhasing - Renovation Status: Existing
Material Properties - Hout - MDF binnenzijde, ThermalConductivity: 0.24; Hout - MDF binnenzijde, SpecificHeatCapacity: 1600 J/kg/K; Hout - MDF binnenzijde, MassDensity: 1000 kg/m3; Hout - MDF binnenzijde, Embodied Energy: 16.8 (MJ/kg); Hout - MDF binnenzijde, Embodied Carbon: 0.87 (kgCO₂/kg); Hout - MDF binnenzijde, Name: Hout - MDF binnenzijde; Hout - MDF binnenzijde, Participates in Collision Detection: yes
Component Quantities - Hout - MDF binnenzijde, Component Thickness: 10 mm; Hout - MDF binnenzijde, Rectangular Component Height: 50 mm; Hout - MDF binnenzijde, Rectangular Component Width: 10 mm; Hout - MDF binnenzijde, Component Cross Section Area: 0.0005 m2
Name | Hout - MDF binnenzijde, Mass (kg) | Hout - MDF binnenzijde, Projected Component Area (Net) (m2) = Hout - MDF binnenzijde, Projected Component Area (Gross) (m2) | Hout - MDF binnenzijde, Component Volume (Net) (m3) = Hout - MDF binnenzijde, Component Volume (Gross) (m3)
door derden | 0.745 | 0.0745 | 0.000745
door derden | 0.75 | 0.075 | 0.00075

# IfcBuildingElementProxy: Hout - MDF binnenzijde 14 (3)
In: Begane grond
Classification: 22 Binnenwanden (NL/SfB (2 cijfers)); Material: Hout - MDF binnenzijde
AC_Pset_RenovationAndPhasing - Renovation Status: Existing
Material Properties - Hout - MDF binnenzijde, ThermalConductivity: 0.24; Hout - MDF binnenzijde, SpecificHeatCapacity: 1600 J/kg/K; Hout - MDF binnenzijde, MassDensity: 1000 kg/m3; Hout - MDF binnenzijde, Embodied Energy: 16.8 (MJ/kg); Hout - MDF binnenzijde, Embodied Carbon: 0.87 (kgCO₂/kg); Hout - MDF binnenzijde, Name: Hout - MDF binnenzijde; Hout - MDF binnenzijde, Participates in Collision Detection: yes
Component Quantities - Hout - MDF binnenzijde, Component Thickness: 14 mm; Hout - MDF binnenzijde, Rectangular Component Height: 1177 mm; Hout - MDF binnenzijde, Rectangular Component Width: 14 mm; Hout - MDF binnenzijde, Component Cross Section Area: 0.016478 m2
Name | Hout - MDF binnenzijde, Mass (kg) | Hout - MDF binnenzijde, Projected Component Area (Net) (m2) = Hout - MDF binnenzijde, Projected Component Area (Gross) (m2) | Hout - MDF binnenzijde, Component Volume (Net) (m3) = Hout - MDF binnenzijde, Component Volume (Gross) (m3)
door derden | 1.63405 | 0.116718 | 0.00163405
door derden | 1.63381 | 0.1177 | 0.00163381
door derden | 1.6338 | 0.116699 | 0.0016338

# IfcBuildingElementProxy: Hout - MDF binnenzijde 391 (40)
In: Begane grond
Classification: 22 Binnenwanden (NL/SfB (2 cijfers)); Material: Hout - MDF binnenzijde
AC_Pset_RenovationAndPhasing - Renovation Status: Existing
Material Properties - Hout - MDF binnenzijde, ThermalConductivity: 0.24; Hout - MDF binnenzijde, SpecificHeatCapacity: 1600 J/kg/K; Hout - MDF binnenzijde, MassDensity: 1000 kg/m3; Hout - MDF binnenzijde, Embodied Energy: 16.8 (MJ/kg); Hout - MDF binnenzijde, Embodied Carbon: 0.87 (kgCO₂/kg); Hout - MDF binnenzijde, Name: Hout - MDF binnenzijde; Hout - MDF binnenzijde, Participates in Collision Detection: yes
Component Quantities - Hout - MDF binnenzijde, Mass: 18.944 kg; Hout - MDF binnenzijde, Projected Component Area (Net): 0.04845 m2; Hout - MDF binnenzijde, Projected Component Area (Gross): 0.04845 m2; Hout - MDF binnenzijde, Component Thickness: 391 mm; Hout - MDF binnenzijde, Rectangular Component Height: 170 mm; Hout - MDF binnenzijde, Rectangular Component Width: 391 mm; Hout - MDF binnenzijde, Component Cross Section Area: 0.06647 m2; Hout - MDF binnenzijde, Component Volume (Net): 0.018944 m3; Hout - MDF binnenzijde, Component Volume (Gross): 0.018944 m3

# IfcBuildingElementProxy: Hout - Multiplex 30 (2)
In: Begane grond
Material: Hout - Multiplex
AC_Pset_RenovationAndPhasing - Renovation Status: Existing
Material Properties - Hout - Multiplex, ThermalConductivity: 0.17; Hout - Multiplex, SpecificHeatCapacity: 1600 J/kg/K; Hout - Multiplex, MassDensity: 700 kg/m3; Hout - Multiplex, Embodied Energy: 15 (MJ/kg); Hout - Multiplex, Embodied Carbon: 0.77 (kgCO₂/kg); Hout - Multiplex, Name: Hout - Multiplex; Hout - Multiplex, Participates in Collision Detection: yes
Component Quantities - Hout - Multiplex, Component Thickness: 30 mm
Name | Classification | Hout - Multiplex, Mass (kg) | Hout - Multiplex, Projected Component Area (Net) (m2) | Hout - Multiplex, Projected Component Area (Gross) (m2) | Hout - Multiplex, Component Volume (Net) (m3) | Hout - Multiplex, Component Volume (Gross) (m3)
wandtegelwerk | 72 Vaste inrichting voor gebruiksruimten (NL/SfB (2 cijfers)) | 11.0361 | 0.525528 | 0.525528 | 0.0157658 | 0.0157658 | Component Quantities - Hout - Multiplex, Rectangular Component Height: 750 mm; Hout - Multiplex, Rectangular Component Width: 30 mm; Hout - Multiplex, Component Cross Section Area: 0.0225 m2
Vaste inrichting | 27 DAKEN (NL/SfB (4 cijfers)) | 9.18954 | 0.437597 | 0.4599 | 0.0131279 | 0.013797

# IfcBuildingElementProxy: Hout - binnenkozijnen 8 x 50 (7)
In: Begane grond
Material: Hout - binnenkozijnen
AC_Pset_RenovationAndPhasing - Renovation Status: Existing
Material Properties - Hout - binnenkozijnen, ThermalConductivity: 0.17; Hout - binnenkozijnen, SpecificHeatCapacity: 1880 J/kg/K; Hout - binnenkozijnen, MassDensity: 800 kg/m3; Hout - binnenkozijnen, Embodied Energy: 10.4 (MJ/kg); Hout - binnenkozijnen, Embodied Carbon: 0.23 (kgCO₂/kg); Hout - binnenkozijnen, Name: Hout - binnenkozijnen; Hout - binnenkozijnen, Participates in Collision Detection: yes
Component Quantities - Hout - binnenkozijnen, Component Thickness: 8 mm; Hout - binnenkozijnen, Rectangular Component Height: 50 mm; Hout - binnenkozijnen, Rectangular Component Width: 8 mm; Hout - binnenkozijnen, Component Cross Section Area: 0.0004 m2
Name | Hout - binnenkozijnen, Mass (kg) | Hout - binnenkozijnen, Projected Component Area (Net) (m2) = Hout - binnenkozijnen, Projected Component Area (Gross) (m2) | Hout - binnenkozijnen, Component Volume (Net) (m3) = Hout - binnenkozijnen, Component Volume (Gross) (m3)
vloerplint | 0.576 | 0.09 | 0.00072
vloerplint | 0.0576017 | 0.00940036 | 0.0000720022
2 x vloerplint | 0.1328 | 0.02095 | 0.000166
vloerplint | 0.0575994 | 0.00939984 | 0.0000719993
vloerplint | 0.0112011 | 0.00195012 | 0.0000140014
vloerplint | 0.0112023 | 0.00195045 | 0.0000140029

# IfcBuildingElementProxy: Hout AFW 100 x 28 (5)
In: Begane grond
Classification: 28 HOOFDDRAAGCONSTRUCTIES (EcoQuaestor); 28 Hoofddraagconstructies (NL/SfB (2 cijfers)); Material: Hout AFW
AC_Pset_RenovationAndPhasing - Renovation Status: Existing
Material Properties - Hout AFW, ThermalConductivity: 0.14; Hout AFW, SpecificHeatCapacity: 1880 J/kg/K; Hout AFW, MassDensity: 550 kg/m3; Hout AFW, Embodied Energy: 7.4 (MJ/kg); Hout AFW, Embodied Carbon: 0.19 (kgCO₂/kg); Hout AFW, Name: Hout AFW; Hout AFW, Participates in Collision Detection: yes
Component Quantities - Hout AFW, Mass: 3.66059 kg; Hout AFW, Component Thickness: 100 mm; Hout AFW, Rectangular Component Height: 28 mm; Hout AFW, Rectangular Component Width: 100 mm; Hout AFW, Component Cross Section Area: 0.0028 m2; Hout AFW, Component Volume (Net): 0.00665561 m3; Hout AFW, Component Volume (Gross): 0.00665561 m3

# IfcBuildingElementProxy: Hout AFW 116 x 28 (2)
In: Begane grond
Classification: 28 HOOFDDRAAGCONSTRUCTIES (EcoQuaestor); 28 Hoofddraagconstructies (NL/SfB (2 cijfers)); Material: Hout AFW
AC_Pset_RenovationAndPhasing - Renovation Status: Existing
Material Properties - Hout AFW, ThermalConductivity: 0.14; Hout AFW, SpecificHeatCapacity: 1880 J/kg/K; Hout AFW, MassDensity: 550 kg/m3; Hout AFW, Embodied Energy: 7.4 (MJ/kg); Hout AFW, Embodied Carbon: 0.19 (kgCO₂/kg); Hout AFW, Name: Hout AFW; Hout AFW, Participates in Collision Detection: yes
Component Quantities - Hout AFW, Mass: 4.2463 kg; Hout AFW, Component Thickness: 116.001 mm; Hout AFW, Rectangular Component Height: 28 mm; Hout AFW, Rectangular Component Width: 116.001 mm; Hout AFW, Component Cross Section Area: 0.00324802 m2; Hout AFW, Component Volume (Net): 0.00772055 m3; Hout AFW, Component Volume (Gross): 0.00772055 m3

# IfcBuildingElementProxy: Hout AFW 150 x 12 (2)
In: Begane grond
Classification: Dakafwerking (ARCHICAD Classification); Material: Hout AFW
AC_Pset_RenovationAndPhasing - Renovation Status: Existing
Material Properties - Hout AFW, ThermalConductivity: 0.14; Hout AFW, SpecificHeatCapacity: 1880 J/kg/K; Hout AFW, MassDensity: 550 kg/m3; Hout AFW, Embodied Energy: 7.4 (MJ/kg); Hout AFW, Embodied Carbon: 0.19 (kgCO₂/kg); Hout AFW, Name: Hout AFW; Hout AFW, Participates in Collision Detection: yes
Component Quantities - Hout AFW, Mass: 1.089 kg; Hout AFW, Projected Component Area (Net): 0.0132 m2; Hout AFW, Projected Component Area (Gross): 0.0132 m2; Hout AFW, Component Thickness: 150 mm; Hout AFW, Rectangular Component Height: 12 mm; Hout AFW, Rectangular Component Width: 150 mm; Hout AFW, Component Cross Section Area: 0.0018 m2; Hout AFW, Component Volume (Net): 0.00198 m3; Hout AFW, Component Volume (Gross): 0.00198 m3

# IfcBuildingElementProxy: Hout AFW 190 x 28 (6)
In: Begane grond
Material: Hout AFW
AC_Pset_RenovationAndPhasing - Renovation Status: Existing
Material Properties - Hout AFW, ThermalConductivity: 0.14; Hout AFW, SpecificHeatCapacity: 1880 J/kg/K; Hout AFW, MassDensity: 550 kg/m3; Hout AFW, Embodied Energy: 7.4 (MJ/kg); Hout AFW, Embodied Carbon: 0.19 (kgCO₂/kg); Hout AFW, Name: Hout AFW; Hout AFW, Participates in Collision Detection: yes
Component Quantities - Hout AFW, Component Thickness: 190 mm; Hout AFW, Rectangular Component Height: 28 mm; Hout AFW, Rectangular Component Width: 190 mm; Hout AFW, Component Cross Section Area: 0.00532 m2
Name | Classification | Hout AFW, Mass (kg) | Hout AFW, Component Volume (Net) (m3) = Hout AFW, Component Volume (Gross) (m3)
4 x  | 28 HOOFDDRAAGCONSTRUCTIES (EcoQuaestor); 28 Hoofddraagconstructies (NL/SfB (2 cijfers)) | 3.9501 | 0.007182
2 x  | Dakafwerking (ARCHICAD Classification) | 5.43066 | 0.00987392 | Component Quantities - Hout AFW, Projected Component Area (Net): 0.051968 m2; Hout AFW, Projected Component Area (Gross): 0.051968 m2

# IfcBuildingElementProxy: Hout AFW 20 (36)
In: Begane grond
Classification:  (NL/SfB (2 cijfers)); Material: Hout AFW
AC_Pset_RenovationAndPhasing - Renovation Status: To Be Demolished
Material Properties - Hout AFW, ThermalConductivity: 0.14; Hout AFW, SpecificHeatCapacity: 1880 J/kg/K; Hout AFW, MassDensity: 550 kg/m3; Hout AFW, Embodied Energy: 7.4 (MJ/kg); Hout AFW, Embodied Carbon: 0.19 (kgCO₂/kg); Hout AFW, Name: Hout AFW; Hout AFW, Participates in Collision Detection: yes
Component Quantities - Hout AFW, Component Thickness: 20 mm
Name | Hout AFW, Mass (kg) | Hout AFW, Projected Component Area (Net) (m2) = Hout AFW, Projected Component Area (Gross) (m2) | Hout AFW, Component Volume (Net) (m3) = Hout AFW, Component Volume (Gross) (m3)
2 x Zitbank | 5.247 | 0.477 | 0.00954
2 x Zitbank | 5.225 | 0.475 | 0.0095
2 x Zitbank | 4.092 | 0.372 | 0.00744
2 x Zitbank | 3.85 | 0.35 | 0.007
2 x Zitbank | 7.227 | 0.657 | 0.01314
2 x Zitbank | 6.985 | 0.635 | 0.0127
2 x Zitbank | 4.202 | 0.382 | 0.00764
2 x Zitbank | 4.18 | 0.38 | 0.0076
8 x Zitbank | 2.2005 | 0.200045 | 0.00400091
2 x Zitbank | 8.70758 | 0.791598 | 0.015832
2 x Zitbank | 8.57558 | 0.779598 | 0.015592
2 x Zitbank | 3.179 | 0.289 | 0.00578
2 x Zitbank | 2.805 | 0.255 | 0.0051
2 x Zitbank | 2.002 | 0.182 | 0.00364
2 x Zitbank | 1.87 | 0.17 | 0.0034

# IfcBuildingElementProxy: Hout AFW 226 x 12 (3)
In: Begane grond
Material: Hout AFW
AC_Pset_RenovationAndPhasing - Renovation Status: Existing
Material Properties - Hout AFW, ThermalConductivity: 0.14; Hout AFW, SpecificHeatCapacity: 1880 J/kg/K; Hout AFW, MassDensity: 550 kg/m3; Hout AFW, Embodied Energy: 7.4 (MJ/kg); Hout AFW, Embodied Carbon: 0.19 (kgCO₂/kg); Hout AFW, Name: Hout AFW; Hout AFW, Participates in Collision Detection: yes
Component Quantities - Hout AFW, Component Thickness: 226 mm; Hout AFW, Rectangular Component Height: 12 mm; Hout AFW, Rectangular Component Width: 226 mm; Hout AFW, Component Cross Section Area: 0.002712 m2
Name | Classification | Hout AFW, Mass (kg) | Hout AFW, Component Volume (Net) (m3) = Hout AFW, Component Volume (Gross) (m3)
 | Dakafwerking (ARCHICAD Classification) | 9.07489 | 0.0164998 | Component Quantities - Hout AFW, Projected Component Area (Net): 0.073008 m2; Hout AFW, Projected Component Area (Gross): 0.073008 m2
2 x  | 28 HOOFDDRAAGCONSTRUCTIES (EcoQuaestor); 28 Hoofddraagconstructies (NL/SfB (2 cijfers)) | 1.81975 | 0.00330864

# IfcBuildingElementProxy: Hout AFW 35, Dak-x
In: Begane grond
Material: Hout AFW
Pset_SlabCommon - Reference: Type Shell
AC_Pset_RenovationAndPhasing - Renovation Status: Existing
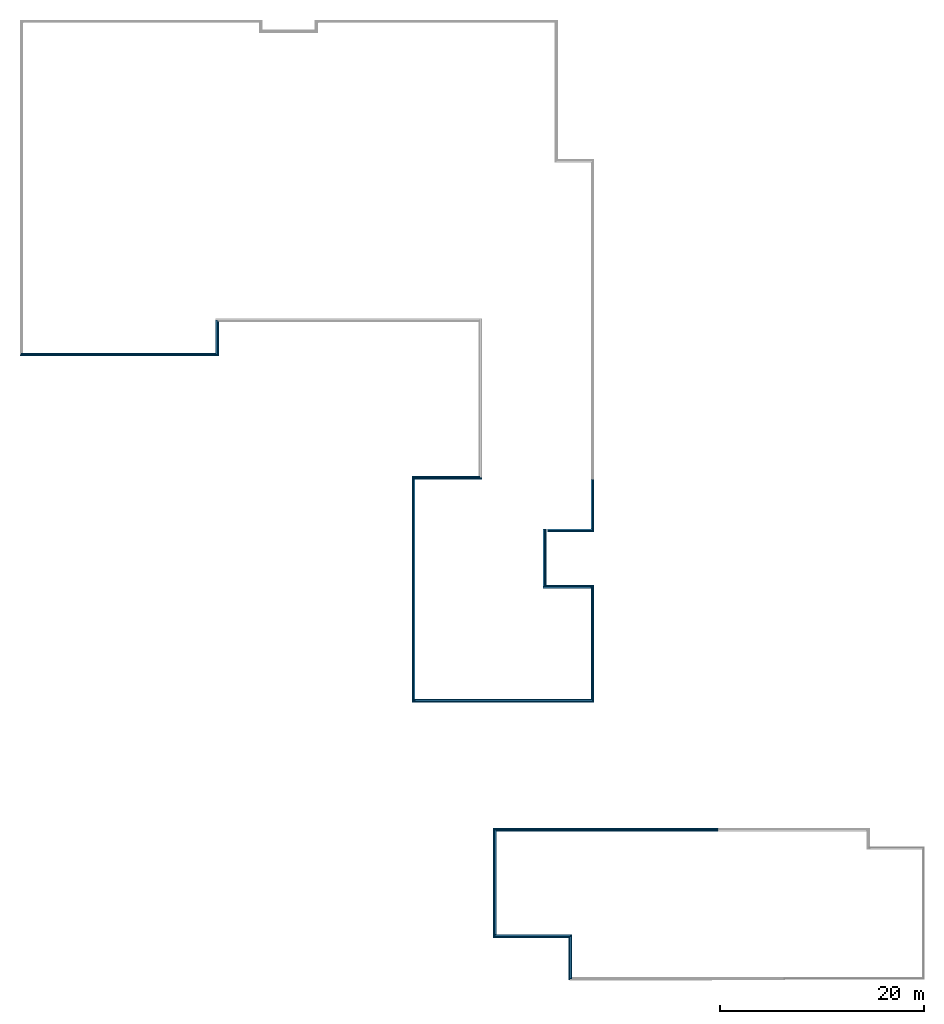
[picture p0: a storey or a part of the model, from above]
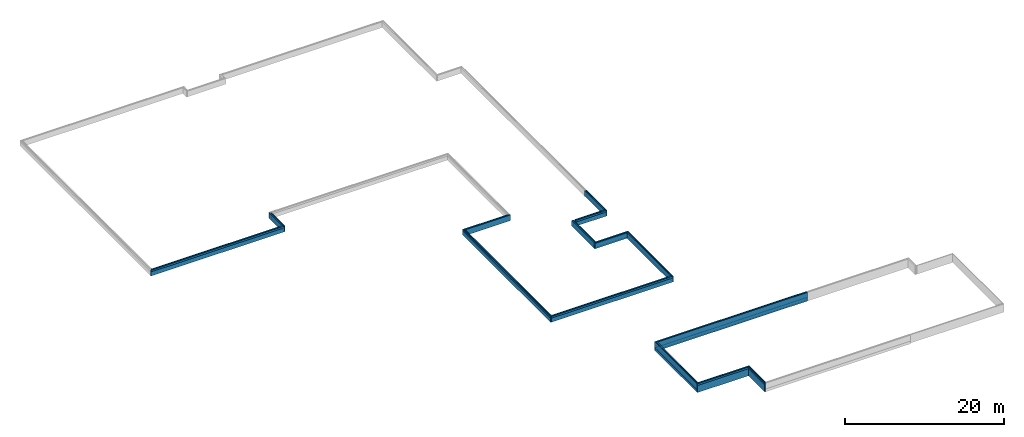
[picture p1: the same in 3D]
Properties of the parts of a building model (IFC2X3), part 14 of 19

# IfcBuildingElementProxy: Hout AFW 35, Dak-x
Material Properties - Hout AFW, ThermalConductivity: 0.14; Hout AFW, SpecificHeatCapacity: 1880 J/kg/K; Hout AFW, MassDensity: 550 kg/m3; Hout AFW, Embodied Energy: 7.4 (MJ/kg); Hout AFW, Embodied Carbon: 0.19 (kgCO₂/kg); Hout AFW, Name: Hout AFW; Hout AFW, Participates in Collision Detection: yes
Component Quantities - Hout AFW, Mass: 33.0329 kg; Hout AFW, Projected Component Area (Net): 1.8 m2; Hout AFW, Projected Component Area (Gross): 1.8 m2; Hout AFW, Component Thickness: 35 mm; Hout AFW, Component Volume (Net): 0.0600599 m3; Hout AFW, Component Volume (Gross): 0.0600599 m3

# IfcBuildingElementProxy: Hout AFW 58 x 20 (4)
In: Begane grond
Classification: 28 HOOFDDRAAGCONSTRUCTIES (EcoQuaestor); 28 Hoofddraagconstructies (NL/SfB (2 cijfers)); Material: Hout AFW
AC_Pset_RenovationAndPhasing - Renovation Status: Existing
Material Properties - Hout AFW, ThermalConductivity: 0.14; Hout AFW, SpecificHeatCapacity: 1880 J/kg/K; Hout AFW, MassDensity: 550 kg/m3; Hout AFW, Embodied Energy: 7.4 (MJ/kg); Hout AFW, Embodied Carbon: 0.19 (kgCO₂/kg); Hout AFW, Name: Hout AFW; Hout AFW, Participates in Collision Detection: yes
Component Quantities - Hout AFW, Mass: 0.77836 kg; Hout AFW, Component Thickness: 58 mm; Hout AFW, Rectangular Component Height: 20 mm; Hout AFW, Rectangular Component Width: 58 mm; Hout AFW, Component Cross Section Area: 0.00116 m2; Hout AFW, Component Volume (Net): 0.0014152 m3; Hout AFW, Component Volume (Gross): 0.0014152 m3

# IfcBuildingElementProxy: Hout AFW 58 x 58 (12)
In: Begane grond
Material: Hout AFW
AC_Pset_RenovationAndPhasing - Renovation Status: Existing
Material Properties - Hout AFW, ThermalConductivity: 0.14; Hout AFW, SpecificHeatCapacity: 1880 J/kg/K; Hout AFW, MassDensity: 550 kg/m3; Hout AFW, Embodied Energy: 7.4 (MJ/kg); Hout AFW, Embodied Carbon: 0.19 (kgCO₂/kg); Hout AFW, Name: Hout AFW; Hout AFW, Participates in Collision Detection: yes
Component Quantities - Hout AFW, Component Thickness: 58 mm; Hout AFW, Rectangular Component Height: 58 mm; Hout AFW, Rectangular Component Width: 58 mm; Hout AFW, Component Cross Section Area: 0.003364 m2
Name | Classification | Hout AFW, Mass (kg) | Hout AFW, Component Volume (Net) (m3) = Hout AFW, Component Volume (Gross) (m3)
6 x houten hekje | 28 HOOFDDRAAGCONSTRUCTIES (EcoQuaestor); 28 Hoofddraagconstructies (NL/SfB (2 cijfers)) | 2.02967 | 0.00369031
2 x houten hekje | 28 HOOFDDRAAGCONSTRUCTIES (EcoQuaestor); 28 Hoofddraagconstructies (NL/SfB (2 cijfers)) | 1.74289 | 0.00316889
2 x houten hekje | 45 Plafondafwerkingen (NL/SfB (2 cijfers)); 45 PLAFONDAFWERKINGEN (EcoQuaestor) | 1.64634 | 0.00299334 | Component Quantities - Hout AFW, Projected Component Area (Net): 0.0580711 m2; Hout AFW, Projected Component Area (Gross): 0.0580711 m2
2 x houten hekje | 45 Plafondafwerkingen (NL/SfB (2 cijfers)); 45 PLAFONDAFWERKINGEN (EcoQuaestor) | 2.28172 | 0.00414857 | Component Quantities - Hout AFW, Projected Component Area (Net): 0.0715271 m2; Hout AFW, Projected Component Area (Gross): 0.0715271 m2

# IfcBuildingElementProxy: Hout AFW 80 x 28
In: Begane grond
Classification: 28 HOOFDDRAAGCONSTRUCTIES (EcoQuaestor); 28 Hoofddraagconstructies (NL/SfB (2 cijfers)); Material: Hout AFW
AC_Pset_RenovationAndPhasing - Renovation Status: Existing
Material Properties - Hout AFW, ThermalConductivity: 0.14; Hout AFW, SpecificHeatCapacity: 1880 J/kg/K; Hout AFW, MassDensity: 550 kg/m3; Hout AFW, Embodied Energy: 7.4 (MJ/kg); Hout AFW, Embodied Carbon: 0.19 (kgCO₂/kg); Hout AFW, Name: Hout AFW; Hout AFW, Participates in Collision Detection: yes
Component Quantities - Hout AFW, Mass: 2.9568 kg; Hout AFW, Component Thickness: 80 mm; Hout AFW, Rectangular Component Height: 28 mm; Hout AFW, Rectangular Component Width: 80 mm; Hout AFW, Component Cross Section Area: 0.00224 m2; Hout AFW, Component Volume (Net): 0.005376 m3; Hout AFW, Component Volume (Gross): 0.005376 m3

# IfcBuildingElementProxy: Hout geperforeerde plaat 20 x 1058 (2)
In: Begane grond
Classification: 45 Plafondafwerkingen (NL/SfB (2 cijfers)); 45 PLAFONDAFWERKINGEN (EcoQuaestor); Material: Hout geperforeerde plaat
AC_Pset_RenovationAndPhasing - Renovation Status: Existing
Material Properties - Hout geperforeerde plaat, ThermalConductivity: 0.14; Hout geperforeerde plaat, SpecificHeatCapacity: 1880 J/kg/K; Hout geperforeerde plaat, MassDensity: 550 kg/m3; Hout geperforeerde plaat, Embodied Energy: 7.4 (MJ/kg); Hout geperforeerde plaat, Embodied Carbon: 0.19 (kgCO₂/kg); Hout geperforeerde plaat, Name: Hout geperforeerde plaat; Hout geperforeerde plaat, Participates in Collision Detection: yes
Component Quantities - Hout geperforeerde plaat, Mass: 11.6491 kg; Hout geperforeerde plaat, Projected Component Area (Net): 1.05901 m2; Hout geperforeerde plaat, Projected Component Area (Gross): 1.05901 m2; Hout geperforeerde plaat, Component Thickness: 20 mm; Hout geperforeerde plaat, Rectangular Component Height: 1057.72 mm; Hout geperforeerde plaat, Rectangular Component Width: 20 mm; Hout geperforeerde plaat, Component Cross Section Area: 0.0211543 m2; Hout geperforeerde plaat, Component Volume (Net): 0.0211803 m3; Hout geperforeerde plaat, Component Volume (Gross): 0.0211803 m3

# IfcBuildingElementProxy: IfcBuildingElementProxy (132)
In: Begane grond
AC_Pset_RenovationAndPhasing - Renovation Status: Existing
Name | Material | Metaal - kleur buitenkozijnen, ThermalConductivity | Metaal - kleur buitenkozijnen, SpecificHeatCapacity (J/kg/K) | Metaal - kleur buitenkozijnen, MassDensity (kg/m3) | Metaal - kleur buitenkozijnen, Embodied Energy | Metaal - kleur buitenkozijnen, Embodied Carbon | Metaal - kleur buitenkozijnen, Name | Metaal - kleur buitenkozijnen, Participates in Collision Detection
4 x Bovenregel-x | Metaal - kleur buitenkozijnen | 160 | 880 | 2800 | 155 (MJ/kg) | 9.16 (kgCO₂/kg) | Metaal - kleur buitenkozijnen | yes | Component Quantities - Metaal - kleur buitenkozijnen, Mass: 1.05164 kg; Metaal - kleur buitenkozijnen, Component Volume (Net): 0.000375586 m3; Metaal - kleur buitenkozijnen, Component Volume (Gross): 0.000375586 m3
4 x Bovenregel-x | Metaal - kleur buitenkozijnen | 160 | 880 | 2800 | 155 (MJ/kg) | 9.16 (kgCO₂/kg) | Metaal - kleur buitenkozijnen | yes | Component Quantities - Metaal - kleur buitenkozijnen, Mass: 5.34983 kg; Metaal - kleur buitenkozijnen, Component Volume (Net): 0.00191065 m3; Metaal - kleur buitenkozijnen, Component Volume (Gross): 0.00191065 m3
Bovenregel-x | Metaal - kleur buitenkozijnen | 160 | 880 | 2800 | 155 (MJ/kg) | 9.16 (kgCO₂/kg) | Metaal - kleur buitenkozijnen | yes | Component Quantities - Metaal - kleur buitenkozijnen, Mass: 0.846958 kg; Metaal - kleur buitenkozijnen, Component Volume (Net): 0.000302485 m3; Metaal - kleur buitenkozijnen, Component Volume (Gross): 0.000302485 m3
Bovenregel-x | Metaal - kleur buitenkozijnen | 160 | 880 | 2800 | 155 (MJ/kg) | 9.16 (kgCO₂/kg) | Metaal - kleur buitenkozijnen | yes | Component Quantities - Metaal - kleur buitenkozijnen, Mass: 4.28551 kg; Metaal - kleur buitenkozijnen, Component Volume (Net): 0.00153054 m3; Metaal - kleur buitenkozijnen, Component Volume (Gross): 0.00153054 m3
7 x Bovenregel-x | Metaal - kleur buitenkozijnen | 160 | 880 | 2800 | 155 (MJ/kg) | 9.16 (kgCO₂/kg) | Metaal - kleur buitenkozijnen | yes
Bovenregel-x | Metaal - kleur buitenkozijnen | 160 | 880 | 2800 | 155 (MJ/kg) | 9.16 (kgCO₂/kg) | Metaal - kleur buitenkozijnen | yes | Component Quantities - Metaal - kleur buitenkozijnen, Mass: 0.459105 kg; Metaal - kleur buitenkozijnen, Component Volume (Net): 0.000163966 m3; Metaal - kleur buitenkozijnen, Component Volume (Gross): 0.000163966 m3
3 x Bovenregel-x | Metaal - kleur buitenkozijnen | 160 | 880 | 2800 | 155 (MJ/kg) | 9.16 (kgCO₂/kg) | Metaal - kleur buitenkozijnen | yes | Component Quantities - Metaal - kleur buitenkozijnen, Mass: 9.76783 kg; Metaal - kleur buitenkozijnen, Component Volume (Net): 0.00348851 m3; Metaal - kleur buitenkozijnen, Component Volume (Gross): 0.00348851 m3
2 x Bovenregel-x | Metaal - kleur buitenkozijnen | 160 | 880 | 2800 | 155 (MJ/kg) | 9.16 (kgCO₂/kg) | Metaal - kleur buitenkozijnen | yes | Component Quantities - Metaal - kleur buitenkozijnen, Mass: 2.04451 kg; Metaal - kleur buitenkozijnen, Component Volume (Net): 0.000730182 m3; Metaal - kleur buitenkozijnen, Component Volume (Gross): 0.000730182 m3
2 x Bovenregel-x | Metaal - kleur buitenkozijnen | 160 | 880 | 2800 | 155 (MJ/kg) | 9.16 (kgCO₂/kg) | Metaal - kleur buitenkozijnen | yes | Component Quantities - Metaal - kleur buitenkozijnen, Mass: 0.407468 kg; Metaal - kleur buitenkozijnen, Component Volume (Net): 0.000145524 m3; Metaal - kleur buitenkozijnen, Component Volume (Gross): 0.000145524 m3
Bovenregel-x | Metaal - kleur buitenkozijnen | 160 | 880 | 2800 | 155 (MJ/kg) | 9.16 (kgCO₂/kg) | Metaal - kleur buitenkozijnen | yes | Component Quantities - Metaal - kleur buitenkozijnen, Mass: 1.00747 kg; Metaal - kleur buitenkozijnen, Component Volume (Net): 0.00035981 m3; Metaal - kleur buitenkozijnen, Component Volume (Gross): 0.00035981 m3
2 x Hoofdbaluster-x | Metaal - kleur buitenkozijnen | 160 | 880 | 2800 | 155 (MJ/kg) | 9.16 (kgCO₂/kg) | Metaal - kleur buitenkozijnen | yes | Component Quantities - Metaal - kleur buitenkozijnen, Mass: 1.74303 kg; Metaal - kleur buitenkozijnen, Component Volume (Net): 0.000622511 m3; Metaal - kleur buitenkozijnen, Component Volume (Gross): 0.000622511 m3
9 x Hoofdbaluster-x | Metaal - kleur buitenkozijnen | 160 | 880 | 2800 | 155 (MJ/kg) | 9.16 (kgCO₂/kg) | Metaal - kleur buitenkozijnen | yes
Bovenregel-x | Metaal - kleur buitenkozijnen | 160 | 880 | 2800 | 155 (MJ/kg) | 9.16 (kgCO₂/kg) | Metaal - kleur buitenkozijnen | yes | Component Quantities - Metaal - kleur buitenkozijnen, Mass: 26.243 kg; Metaal - kleur buitenkozijnen, Component Volume (Net): 0.00937251 m3; Metaal - kleur buitenkozijnen, Component Volume (Gross): 0.00937251 m3
2 x Baluster-x | Metaal - RVS | Material Properties - Metaal - RVS, ThermalConductivity: 17; Metaal - RVS, SpecificHeatCapacity: 460 J/kg/K; Metaal - RVS, MassDensity: 7900 kg/m3; Metaal - RVS, Embodied Energy: 56.7 (MJ/kg); Metaal - RVS, Embodied Carbon: 6.15 (kgCO₂/kg); Metaal - RVS, Name: Metaal - RVS; Metaal - RVS, Participates in Collision Detection: yes; Component Quantities - Metaal - RVS, Mass: 5.6011 kg; Metaal - RVS, Component Volume (Net): 0.000709 m3; Metaal - RVS, Component Volume (Gross): 0.000709 m3
35 x Baluster-x | Metaal - RVS | Material Properties - Metaal - RVS, ThermalConductivity: 17; Metaal - RVS, SpecificHeatCapacity: 460 J/kg/K; Metaal - RVS, MassDensity: 7900 kg/m3; Metaal - RVS, Embodied Energy: 56.7 (MJ/kg); Metaal - RVS, Embodied Carbon: 6.15 (kgCO₂/kg); Metaal - RVS, Name: Metaal - RVS; Metaal - RVS, Participates in Collision Detection: yes
Bovenregel-x | Metaal - kleur buitenkozijnen | 160 | 880 | 2800 | 155 (MJ/kg) | 9.16 (kgCO₂/kg) | Metaal - kleur buitenkozijnen | yes | Component Quantities - Metaal - kleur buitenkozijnen, Mass: 38.1043 kg; Metaal - kleur buitenkozijnen, Component Volume (Net): 0.0136087 m3; Metaal - kleur buitenkozijnen, Component Volume (Gross): 0.0136087 m3
Bovenregel-x | Metaal - kleur buitenkozijnen | 160 | 880 | 2800 | 155 (MJ/kg) | 9.16 (kgCO₂/kg) | Metaal - kleur buitenkozijnen | yes | Component Quantities - Metaal - kleur buitenkozijnen, Mass: 22.7724 kg; Metaal - kleur buitenkozijnen, Component Volume (Net): 0.00813299 m3; Metaal - kleur buitenkozijnen, Component Volume (Gross): 0.00813299 m3
Baluster-x | Metaal - kleur buitenkozijnen | 160 | 880 | 2800 | 155 (MJ/kg) | 9.16 (kgCO₂/kg) | Metaal - kleur buitenkozijnen | yes | Component Quantities - Metaal - kleur buitenkozijnen, Mass: 1.72623 kg; Metaal - kleur buitenkozijnen, Component Volume (Net): 0.000616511 m3; Metaal - kleur buitenkozijnen, Component Volume (Gross): 0.000616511 m3
50 x Baluster-x | Metaal - kleur buitenkozijnen | 160 | 880 | 2800 | 155 (MJ/kg) | 9.16 (kgCO₂/kg) | Metaal - kleur buitenkozijnen | yes
Bovenregel-x | Metaal - kleur buitenkozijnen | 160 | 880 | 2800 | 155 (MJ/kg) | 9.16 (kgCO₂/kg) | Metaal - kleur buitenkozijnen | yes | Component Quantities - Metaal - kleur buitenkozijnen, Mass: 32.5081 kg; Metaal - kleur buitenkozijnen, Component Volume (Net): 0.01161 m3; Metaal - kleur buitenkozijnen, Component Volume (Gross): 0.01161 m3
Bovenregel-x | Metaal - kleur buitenkozijnen | 160 | 880 | 2800 | 155 (MJ/kg) | 9.16 (kgCO₂/kg) | Metaal - kleur buitenkozijnen | yes | Component Quantities - Metaal - kleur buitenkozijnen, Mass: 21.3511 kg; Metaal - kleur buitenkozijnen, Component Volume (Net): 0.00762541 m3; Metaal - kleur buitenkozijnen, Component Volume (Gross): 0.00762541 m3
Bovenregel-x | Metaal - kleur buitenkozijnen | 160 | 880 | 2800 | 155 (MJ/kg) | 9.16 (kgCO₂/kg) | Metaal - kleur buitenkozijnen | yes | Component Quantities - Metaal - kleur buitenkozijnen, Mass: 4.39629 kg; Metaal - kleur buitenkozijnen, Component Volume (Net): 0.0015701 m3; Metaal - kleur buitenkozijnen, Component Volume (Gross): 0.0015701 m3
Bovenregel-x | Metaal - kleur buitenkozijnen | 160 | 880 | 2800 | 155 (MJ/kg) | 9.16 (kgCO₂/kg) | Metaal - kleur buitenkozijnen | yes | Component Quantities - Metaal - kleur buitenkozijnen, Mass: 9.9036 kg; Metaal - kleur buitenkozijnen, Component Volume (Net): 0.003537 m3; Metaal - kleur buitenkozijnen, Component Volume (Gross): 0.003537 m3

# IfcBuildingElementProxy: KW80/4 80 x 80 (3)
In: Begane grond
Material: STEEL/S235
AC_Pset_RenovationAndPhasing - Renovation Status: Existing
Material Properties - STEEL/S235, ThermalConductivity: 2.3; STEEL/S235, SpecificHeatCapacity: 1000 J/kg/K; STEEL/S235, MassDensity: 2300 kg/m3; STEEL/S235, Embodied Energy: 1.92 (MJ/kg); STEEL/S235, Embodied Carbon: 0.198 (kgCO₂/kg); STEEL/S235, Name: STEEL/S235; STEEL/S235, Participates in Collision Detection: yes
Component Quantities - STEEL/S235, Component Cross Section Area: 0.00118853 m2
Name | Classification | STEEL/S235, Mass (kg) | STEEL/S235, Component Volume (Net) (m3) = STEEL/S235, Component Volume (Gross) (m3)
2 x houten hekje | 28 HOOFDDRAAGCONSTRUCTIES (EcoQuaestor); 28 Hoofddraagconstructies (NL/SfB (2 cijfers)) | 9.06686 | 0.00394211
Keerwand | 45 Plafondafwerkingen (NL/SfB (2 cijfers)); 45 PLAFONDAFWERKINGEN (EcoQuaestor) | 5.96326 | 0.00259272

# IfcBuildingElementProxy: Kast hoog 1D 24, Keuken
In: Begane grond
AC_Pset_RenovationAndPhasing - Renovation Status: Existing
Component Quantities - Component, Component Volume (Net): 0.171323 m3; Component, Component Volume (Gross): 0.171323 m3

# IfcBuildingElementProxy: Kast hoog 1D inbouwapparatuur 24 (4)
In: Begane grond
AC_Pset_RenovationAndPhasing - Renovation Status: Existing
Name | Component, Component Volume (Net) (m3) = Component, Component Volume (Gross) (m3)
Keuken | 0.178106
Keuken | 0.167946
Keuken | 0.177917
Keuken | 0.167116

# IfcBuildingElementProxy: Lucht 80 x 80 (3)
In: Begane grond
Classification: 28 HOOFDDRAAGCONSTRUCTIES (EcoQuaestor); 28 Hoofddraagconstructies (NL/SfB (2 cijfers)); Material: Metaal - Aluminium
AC_Pset_RenovationAndPhasing - Renovation Status: Existing
Material Properties - Metaal - Aluminium, ThermalConductivity: 160; Metaal - Aluminium, SpecificHeatCapacity: 880 J/kg/K; Metaal - Aluminium, MassDensity: 2800 kg/m3; Metaal - Aluminium, Embodied Energy: 155 (MJ/kg); Metaal - Aluminium, Embodied Carbon: 9.16 (kgCO₂/kg); Metaal - Aluminium, Name: Metaal - Aluminium; Metaal - Aluminium, Participates in Collision Detection: yes
Component Quantities - Metaal - Aluminium, Mass: 5.57357 kg; Metaal - Aluminium, Projected Component Area (Net): 0.995281 m2; Metaal - Aluminium, Projected Component Area (Gross): 0.995281 m2; Metaal - Aluminium, Component Thickness: 2 mm; Metaal - Aluminium, Component Cross Section Area: 0.000624 m2; Metaal - Aluminium, Component Volume (Net): 0.00199056 m3; Metaal - Aluminium, Component Volume (Gross): 0.00199056 m3

# IfcBuildingElementProxy: Lucht D110 (16)
Classification: 28 HOOFDDRAAGCONSTRUCTIES (EcoQuaestor); 28 Hoofddraagconstructies (NL/SfB (2 cijfers)); Material: Metaal - Aluminium
AC_Pset_RenovationAndPhasing - Renovation Status: Existing
Material Properties - Metaal - Aluminium, ThermalConductivity: 160; Metaal - Aluminium, SpecificHeatCapacity: 880 J/kg/K; Metaal - Aluminium, MassDensity: 2800 kg/m3; Metaal - Aluminium, Embodied Energy: 155 (MJ/kg); Metaal - Aluminium, Embodied Carbon: 9.16 (kgCO₂/kg); Metaal - Aluminium, Name: Metaal - Aluminium; Metaal - Aluminium, Participates in Collision Detection: yes
Component Quantities - Metaal - Aluminium, Component Thickness: 2 mm; Metaal - Aluminium, Component Cross Section Area: 0.000678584 m2
Name | In | Metaal - Aluminium, Mass (kg) | Metaal - Aluminium, Projected Component Area (Net) (m2) = Metaal - Aluminium, Projected Component Area (Gross) (m2) | Metaal - Aluminium, Component Volume (Net) (m3) = Metaal - Aluminium, Component Volume (Gross) (m3)
4 x hwa | Begane grond | 6.65534 | 1.1502 | 0.00237691
4 x hwa | Begane grond | 6.8124 | 1.17734 | 0.002433
3 x hwa | Begane grond | 6.2627 | 1.08234 | 0.00223668
hwa | 1e verdieping | 7.06762 | 1.22145 | 0.00252415
hwa | 1e verdieping | 7.89218 | 1.36395 | 0.00281863
hwa | 1e verdieping | 14.5672 | 2.51755 | 0.00520255
2 x hwa | 1e verdieping | 1.57058 | 0.271434 | 0.000560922

# IfcBuildingElementProxy: Lucht D250 (6)
In: Begane grond
Classification: 28 HOOFDDRAAGCONSTRUCTIES (EcoQuaestor); 28 Hoofddraagconstructies (NL/SfB (2 cijfers)); Material: Metaal - RVS
AC_Pset_RenovationAndPhasing - Renovation Status: Existing
Material Properties - Metaal - RVS, ThermalConductivity: 17; Metaal - RVS, SpecificHeatCapacity: 460 J/kg/K; Metaal - RVS, MassDensity: 7900 kg/m3; Metaal - RVS, Embodied Energy: 56.7 (MJ/kg); Metaal - RVS, Embodied Carbon: 6.15 (kgCO₂/kg); Metaal - RVS, Name: Metaal - RVS; Metaal - RVS, Participates in Collision Detection: yes
Component Quantities - Metaal - RVS, Mass: 192.175 kg; Metaal - RVS, Projected Component Area (Net): 2.41274 m2; Metaal - RVS, Projected Component Area (Gross): 2.41274 m2; Metaal - RVS, Component Thickness: 10 mm; Metaal - RVS, Component Cross Section Area: 0.00753982 m2; Metaal - RVS, Component Volume (Net): 0.024326 m3; Metaal - RVS, Component Volume (Gross): 0.024326 m3
Name
5 x 
gelamineerde kolom 200x200mm

# IfcBuildingElementProxy: Metaal - Aluminium 102 x 100 (2)
In: Begane grond
Classification: 45 Plafondafwerkingen (NL/SfB (2 cijfers)); 45 PLAFONDAFWERKINGEN (EcoQuaestor); Material: Metaal - Aluminium
AC_Pset_RenovationAndPhasing - Renovation Status: Existing
Material Properties - Metaal - Aluminium, ThermalConductivity: 160; Metaal - Aluminium, SpecificHeatCapacity: 880 J/kg/K; Metaal - Aluminium, MassDensity: 2800 kg/m3; Metaal - Aluminium, Embodied Energy: 155 (MJ/kg); Metaal - Aluminium, Embodied Carbon: 9.16 (kgCO₂/kg); Metaal - Aluminium, Name: Metaal - Aluminium; Metaal - Aluminium, Participates in Collision Detection: yes
Component Quantities - Metaal - Aluminium, Component Thickness: 102 mm; Metaal - Aluminium, Rectangular Component Height: 100 mm; Metaal - Aluminium, Rectangular Component Width: 102 mm; Metaal - Aluminium, Component Cross Section Area: 0.0102 m2
Name | Metaal - Aluminium, Mass (kg) | Metaal - Aluminium, Projected Component Area (Net) (m2) = Metaal - Aluminium, Projected Component Area (Gross) (m2) | Metaal - Aluminium, Component Volume (Net) (m3) = Metaal - Aluminium, Component Volume (Gross) (m3)
 | 247.044 | 0.865001 | 0.0882301
 | 266.179 | 0.932 | 0.095064

# IfcBuildingElementProxy: Metaal - Titanium zink 40 (143)
In: Begane grond
Classification:  (NL/SfB (2 cijfers)); Material: Metaal - Titanium zink
AC_Pset_RenovationAndPhasing - Renovation Status: To Be Demolished
Material Properties - Metaal - Titanium zink, ThermalConductivity: 110; Metaal - Titanium zink, SpecificHeatCapacity: 380 J/kg/K; Metaal - Titanium zink, MassDensity: 7200 kg/m3; Metaal - Titanium zink, Embodied Energy: 53.1 (MJ/kg); Metaal - Titanium zink, Embodied Carbon: 3.09 (kgCO₂/kg); Metaal - Titanium zink, Name: Metaal - Titanium zink; Metaal - Titanium zink, Participates in Collision Detection: yes
Component Quantities - Metaal - Titanium zink, Component Thickness: 40 mm
Name | Metaal - Titanium zink, Mass (kg) | Metaal - Titanium zink, Projected Component Area (Net) (m2) = Metaal - Titanium zink, Projected Component Area (Gross) (m2) | Metaal - Titanium zink, Component Volume (Net) (m3) = Metaal - Titanium zink, Component Volume (Gross) (m3)
Zitbank | 58.176 | 0.202 | 0.00808
121 x Zitbank | 4.608 | 0.016 | 0.00064
2 x Zitbank | 44.928 | 0.156 | 0.00624
Zitbank | 57.312 | 0.199 | 0.00796
2 x Zitbank | 77.76 | 0.27 | 0.0108
2 x Zitbank | 47.232 | 0.164 | 0.00656
3 x Zitbank | 23.0452 | 0.0800182 | 0.00320073
Zitbank | 23.0345 | 0.079981 | 0.00319924
2 x Zitbank | 4.60779 | 0.0159993 | 0.000639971
Zitbank | 4.60778 | 0.0159993 | 0.00063997
Zitbank | 4.60778 | 0.0159992 | 0.000639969
2 x Zitbank | 93.2657 | 0.323839 | 0.0129536
2 x Zitbank | 37.44 | 0.13 | 0.0052
2 x Zitbank | 23.04 | 0.08 | 0.0032

# IfcBuildingElementProxy: Metaal - kleur buitenkozijnen (6)
In: Begane grond
Classification:  (NL/SfB (2 cijfers)); Material: Metaal - kleur buitenkozijnen
AC_Pset_RenovationAndPhasing - Renovation Status: Existing
Material Properties - Metaal - kleur buitenkozijnen, ThermalConductivity: 160; Metaal - kleur buitenkozijnen, SpecificHeatCapacity: 880 J/kg/K; Metaal - kleur buitenkozijnen, MassDensity: 2800 kg/m3; Metaal - kleur buitenkozijnen, Embodied Energy: 155 (MJ/kg); Metaal - kleur buitenkozijnen, Embodied Carbon: 9.16 (kgCO₂/kg); Metaal - kleur buitenkozijnen, Name: Metaal - kleur buitenkozijnen; Metaal - kleur buitenkozijnen, Participates in Collision Detection: yes
Name | Metaal - kleur buitenkozijnen, Mass (kg) | Metaal - kleur buitenkozijnen, Component Volume (Net) (m3) = Metaal - kleur buitenkozijnen, Component Volume (Gross) (m3)
4 x zetwerk tpv kozijnen | 2.21281 | 0.000790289
2 x zetwerk tpv kozijnen | 7.47097 | 0.0026682

# IfcBuildingElementProxy: R1 25 (13)
In: Begane grond
Classification: 32 Binnenwandopeningen (NL/SfB (2 cijfers))
AC_Pset_RenovationAndPhasing - Renovation Status: Existing
Name | Component, Component Volume (Net) (m3) = Component, Component Volume (Gross) (m3)
7 x raam panelenwand | 0.00117218
6 x raam panelenwand | 0.00132233

# IfcBuildingElementProxy: Rail Balustrade 16 (4)
In: Begane grond
AC_Pset_RenovationAndPhasing - Renovation Status: Existing
Component Quantities - Component, Component Volume (Net): 0.041772 m3; Component, Component Volume (Gross): 0.041772 m3

# IfcBuildingElementProxy: Railing Type (10)
In: Begane grond
AC_Pset_RenovationAndPhasing - Renovation Status: Existing

# IfcBuildingElementProxy: Range Hood #1043, Keuken
In: Begane grond
AC_Pset_RenovationAndPhasing - Renovation Status: Existing
Component Quantities - Component, Component Volume (Net): 0.10736 m3; Component, Component Volume (Gross): 0.10736 m3

# IfcBuildingElementProxy: Schap wand 21 (7)
In: Begane grond
Pset_FireRatingProperties - FireResistanceRating: WBDBO (min)
Pset_QuantityTakeOff - LocalContext: Code; Reference: Omschrijving
AC_Pset_RenovationAndPhasing - Renovation Status: Existing
Name | Component, Component Volume (Net) (m3) = Component, Component Volume (Gross) (m3)
garderobe | 0.083534
4 x garderobe | 0.032617
2 x garderobe | 0.0380316

# IfcBuildingElementProxy: Tegels - Bestrating 100 (2)
In: Begane grond
Classification:  (NL/SfB (2 cijfers)); Material: Tegels - Bestrating
AC_Pset_RenovationAndPhasing - Renovation Status: Existing
Material Properties - Tegels - Bestrating, ThermalConductivity: 1.3; Tegels - Bestrating, SpecificHeatCapacity: 840 J/kg/K; Tegels - Bestrating, MassDensity: 2300 kg/m3; Tegels - Bestrating, Embodied Energy: 10 (MJ/kg); Tegels - Bestrating, Embodied Carbon: 0.7 (kgCO₂/kg); Tegels - Bestrating, Name: Tegels - Bestrating; Tegels - Bestrating, Participates in Collision Detection: yes
Component Quantities - Tegels - Bestrating, Mass: 533.772 kg; Tegels - Bestrating, Projected Component Area (Net): 2.32163 m2; Tegels - Bestrating, Projected Component Area (Gross): 2.32163 m2; Tegels - Bestrating, Component Thickness: 100 mm; Tegels - Bestrating, Component Volume (Net): 0.232075 m3; Tegels - Bestrating, Component Volume (Gross): 0.232075 m3

# IfcBuildingElementProxy: Tegels - vegatatievrije zone 45 (92)
Classification: 47 DAKAFWERKINGEN (EcoQuaestor); 47 Dakafwerkingen (NL/SfB (2 cijfers)); Material: Tegels - vegatatievrije zone
Pset_SlabCommon - Reference: Type Dak
AC_Pset_RenovationAndPhasing - Renovation Status: Existing
Material Properties - Tegels - vegatatievrije zone, ThermalConductivity: 2.3; Tegels - vegatatievrije zone, SpecificHeatCapacity: 1000 J/kg/K; Tegels - vegatatievrije zone, MassDensity: 2300 kg/m3; Tegels - vegatatievrije zone, Embodied Energy: 1.92 (MJ/kg); Tegels - vegatatievrije zone, Embodied Carbon: 0.198 (kgCO₂/kg); Tegels - vegatatievrije zone, Name: Tegels - vegatatievrije zone; Tegels - vegatatievrije zone, Participates in Collision Detection: yes
Component Quantities - Tegels - vegatatievrije zone, Component Thickness: 45 mm
Name | In | Tegels - vegatatievrije zone, Mass (kg) | Tegels - vegatatievrije zone, Projected Component Area (Net) (m2) = Tegels - vegatatievrije zone, Projected Component Area (Gross) (m2) | Tegels - vegatatievrije zone, Component Volume (Net) (m3) = Tegels - vegatatievrije zone, Component Volume (Gross) (m3)
30 x Dakafwerking | 1e verdieping | 83.8444 | 0.810699 | 0.0364541
Dakafwerking | 1e verdieping | 1453.3 | 14.0732 | 0.631871
2 x Dakafwerking | 1e verdieping | 173.745 | 1.67889 | 0.0755411
4 x Dakafwerking | 1e verdieping | 270.321 | 2.612 | 0.117531
Dakafwerking | 1e verdieping | 170.639 | 1.64889 | 0.0741908
Dakafwerking | 1e verdieping | 449.034 | 4.34825 | 0.195232
Dakafwerking | 1e verdieping | 76.7021 | 0.741286 | 0.0333488
Dakafwerking | 1e verdieping | 149.212 | 1.44186 | 0.0648748
Dakafwerking | 1e verdieping | 936.263 | 9.06637 | 0.407071
2 x Dakafwerking | 1e verdieping | 208.058 | 2.01043 | 0.0904602
Dakafwerking | 1e verdieping | 204.953 | 1.98468 | 0.0891102
Dakafwerking | 1e verdieping | 209.611 | 2.02543 | 0.0911352
2 x Dakafwerking | 1e verdieping | 27.9481 | 0.270232 | 0.0121513
Dakafwerking | 1e verdieping | 177.003 | 1.71403 | 0.076958
Dakafwerking | 1e verdieping | 242.373 | 2.34197 | 0.105379
2 x Dakafwerking | 1e verdieping | 27.9481 | 0.270233 | 0.0121514
Dakafwerking | 1e verdieping | 745.284 | 7.21701 | 0.324036
2 x Dakafwerking | 1e verdieping | 137.753 | 1.33115 | 0.0598927
Dakafwerking | 1e verdieping | 157.938 | 1.52617 | 0.0686687
Dakafwerking | 1e verdieping | 484.434 | 4.69106 | 0.210624
Dakafwerking | 1e verdieping | 109.37 | 1.05692 | 0.0475524
Dakafwerking | 1e verdieping | 39.2516 | 0.379445 | 0.0170659
Dakafwerking | 1e verdieping | 381.958 | 3.69629 | 0.166069
Dakafwerking | 1e verdieping | 177.005 | 1.71404 | 0.0769587
Dakafwerking | 1e verdieping | 130.425 | 1.26034 | 0.0567064
Dakafwerking | 1e verdieping | 186.321 | 1.80425 | 0.0810091
Dakafwerking | 1e verdieping | 139.741 | 1.35035 | 0.0607568
2 x Dakafwerking | 1e verdieping | 204.953 | 1.98063 | 0.08911
Dakafwerking | 1e verdieping | 118.003 | 1.14053 | 0.0513058
Dakafwerking | 1e verdieping | 102.166 | 0.987515 | 0.0444199
Dakafwerking | 1e verdieping | 1080.66 | 10.4529 | 0.469851
Dakafwerking | 1e verdieping | 51.0829 | 0.493757 | 0.02221
Dakafwerking | 1e verdieping | 558.958 | 5.41271 | 0.243025
Dakafwerking | 1e verdieping | 18.6319 | 0.180424 | 0.00810084
Dakafwerking | 1e verdieping | 149.056 | 1.44178 | 0.064807
Dakafwerking | 1e verdieping | 83.9997 | 0.811794 | 0.0365216
Dakafwerking | 1e verdieping | 93.1601 | 0.90111 | 0.0405044
Dakafwerking | 1e verdieping | 242.216 | 2.34289 | 0.105311
Dakafwerking | 1e verdieping | 372.64 | 3.60444 | 0.162018
Dakafwerking | 1e verdieping | 707.194 | 6.83543 | 0.307476
Dakafwerking | 1e verdieping | 428.538 | 4.14512 | 0.186321
Dakafwerking | 1e verdieping | 18.6321 | 0.180223 | 0.00810091
Dakafwerking | 1e verdieping | 92.8499 | 0.899119 | 0.0403695
Dakafwerking | 1e verdieping | 37.2642 | 0.360243 | 0.0162018
Dakafwerking | 1e verdieping | 223.585 | 2.16267 | 0.0972109
Dakafwerking | 1e verdieping | 149.038 | 1.44018 | 0.064799
4 x Dakafwerking | Dak | 83.8444 | 0.810699 | 0.0364541
Dakafwerking | Dak | 594.365 | 5.75557 | 0.258419
2 x Dakafwerking | Dak | 308.672 | 2.98254 | 0.134205
Dakafwerking | Dak | 631.628 | 6.11561 | 0.274621

# IfcBuildingElementProxy: Tekst 3D 21 (5)
In: Begane grond
AC_Pset_RenovationAndPhasing - Renovation Status: Existing
Name | Component, Component Volume (Net) (m3) = Component, Component Volume (Gross) (m3)
3d Tekst | 0.0014163
3d Tekst | 0.00123577
3d Tekst | 0.0012096
3d Tekst | 0.000688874
3d Tekst | 0.000627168

# IfcBuildingElementProxy: Tekst 3D 25 (11)
In: Begane grond
AC_Pset_RenovationAndPhasing - Renovation Status: Existing
Name | Component, Component Volume (Net) (m3) = Component, Component Volume (Gross) (m3) | Classification
tafel | 0.00235911
betontrap | 0.00190873 | 74 Vaste sanitaire voorzieningen (NL/SfB (2 cijfers)); 74 VASTE SANITAIRE VOORZIENINGEN (EcoQuaestor)
betontrap | 0.0390564 | 74 Vaste sanitaire voorzieningen (NL/SfB (2 cijfers)); 74 VASTE SANITAIRE VOORZIENINGEN (EcoQuaestor)
betontrap | 0.000549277 | 74 Vaste sanitaire voorzieningen (NL/SfB (2 cijfers)); 74 VASTE SANITAIRE VOORZIENINGEN (EcoQuaestor)
2 x betontrap | 0.00211341 | 74 Vaste sanitaire voorzieningen (NL/SfB (2 cijfers)); 74 VASTE SANITAIRE VOORZIENINGEN (EcoQuaestor)
betontrap | 0.00106374 | 74 Vaste sanitaire voorzieningen (NL/SfB (2 cijfers)); 74 VASTE SANITAIRE VOORZIENINGEN (EcoQuaestor)
betontrap | 0.00342468 | 74 Vaste sanitaire voorzieningen (NL/SfB (2 cijfers)); 74 VASTE SANITAIRE VOORZIENINGEN (EcoQuaestor)
tafel | 0.0047159
tafel | 0.00419807
tafel | 0.00233654

# IfcBuildingElementProxy: Trap buiten 1250 x 947 (4)
In: Begane grond
Classification: 45 Plafondafwerkingen (NL/SfB (2 cijfers)); 45 PLAFONDAFWERKINGEN (EcoQuaestor)
AC_Pset_RenovationAndPhasing - Renovation Status: Existing

# IfcBuildingElementProxy: U Profiel kolom 25 (316)
In: 1e verdieping
Material: Metaal - Staal AFW
AC_Pset_RenovationAndPhasing - Renovation Status: Existing
Material Properties - Metaal - Staal AFW, ThermalConductivity: 52; Metaal - Staal AFW, SpecificHeatCapacity: 530 J/kg/K; Metaal - Staal AFW, MassDensity: 7950 kg/m3; Metaal - Staal AFW, Embodied Energy: 25 (MJ/kg); Metaal - Staal AFW, Embodied Carbon: 1.91 (kgCO₂/kg); Metaal - Staal AFW, Name: Metaal - Staal AFW; Metaal - Staal AFW, Participates in Collision Detection: yes
Name | Metaal - Staal AFW, Mass (kg) | Metaal - Staal AFW, Component Volume (Net) (m3) = Metaal - Staal AFW, Component Volume (Gross) (m3)
178 x tafel | 3.11763 | 0.000392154
138 x tafel | 1.42148 | 0.000178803

# IfcBuildingElementProxy: Vloerput rechthoekig 25 (28)
In: Begane grond
AC_Pset_RenovationAndPhasing - Renovation Status: Existing
Component Quantities - Component, Component Volume (Net): 0.000569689 m3; Component, Component Volume (Gross): 0.000569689 m3

# IfcBuildingElementProxy: _Dichte arcering 3 (27)
In: Begane grond
Classification: 72 Vaste inrichting voor gebruiksruimten (NL/SfB (2 cijfers)); Material: _Dichte arcering
AC_Pset_RenovationAndPhasing - Renovation Status: Existing
Material Properties - _Dichte arcering, ThermalConductivity: 0.5; _Dichte arcering, SpecificHeatCapacity: 840 J/kg/K; _Dichte arcering, MassDensity: 1300 kg/m3; _Dichte arcering, Embodied Energy: 0.75 (MJ/kg); _Dichte arcering, Embodied Carbon: 0.1 (kgCO₂/kg); _Dichte arcering, Name: _Dichte arcering; _Dichte arcering, Participates in Collision Detection: yes
Component Quantities - _Dichte arcering, Component Thickness: 3 mm; _Dichte arcering, Rectangular Component Height: 100 mm; _Dichte arcering, Rectangular Component Width: 3 mm; _Dichte arcering, Component Cross Section Area: 0.0003 m2
Name | _Dichte arcering, Mass (kg) | _Dichte arcering, Projected Component Area (Net) (m2) = _Dichte arcering, Projected Component Area (Gross) (m2) | _Dichte arcering, Component Volume (Net) (m3) = _Dichte arcering, Component Volume (Gross) (m3)
wandtegelwerk | 0.63492 | 0.1628 | 0.0004884
wandtegelwerk | 1.30806 | 0.3354 | 0.0010062
wandtegelwerk | 1.08965 | 0.279398 | 0.000838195
wandtegelwerk | 1.11082 | 0.284826 | 0.000854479
wandtegelwerk | 0.05265 | 0.0135 | 0.0000405
wandtegelwerk | 0.197237 | 0.0505736 | 0.000151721
6 x wandtegelwerk | 0.429 | 0.11 | 0.00033
3 x wandtegelwerk | 0.40326 | 0.1034 | 0.0003102
wandtegelwerk | 0.446163 | 0.114401 | 0.000343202
3 x wandtegelwerk | 0.2418 | 0.062 | 0.000186
wandtegelwerk | 0.0858 | 0.022 | 0.000066
wandtegelwerk | 0.07683 | 0.0197 | 0.0000591
wandtegelwerk | 1.55766 | 0.399401 | 0.0011982
wandtegelwerk | 0.31941 | 0.0819 | 0.0002457
wandtegelwerk | 0.24999 | 0.0641 | 0.0001923
wandtegelwerk | 0.13884 | 0.0356 | 0.0001068
wandtegelwerk | 0.88686 | 0.2274 | 0.0006822
wandtegelwerk | 0.25077 | 0.0643 | 0.0001929

# IfcBuildingElementProxy: _Dichte arcering 5 (12)
In: Begane grond
Material: _Dichte arcering
AC_Pset_RenovationAndPhasing - Renovation Status: Existing
Material Properties - _Dichte arcering, ThermalConductivity: 0.5; _Dichte arcering, SpecificHeatCapacity: 840 J/kg/K; _Dichte arcering, MassDensity: 1300 kg/m3; _Dichte arcering, Embodied Energy: 0.75 (MJ/kg); _Dichte arcering, Embodied Carbon: 0.1 (kgCO₂/kg); _Dichte arcering, Name: _Dichte arcering; _Dichte arcering, Participates in Collision Detection: yes
Component Quantities - _Dichte arcering, Component Thickness: 5 mm
Name | _Dichte arcering, Mass (kg) | _Dichte arcering, Projected Component Area (Net) (m2) = _Dichte arcering, Projected Component Area (Gross) (m2) | _Dichte arcering, Component Volume (Net) (m3) = _Dichte arcering, Component Volume (Gross) (m3)
Eternal wood | 1914.77 | 294.58 | 1.4729
Eternal wood | 135.201 | 20.8001 | 0.104001
Eternal wood | 40.5171 | 6.2334 | 0.031167
Eternal wood | 237.38 | 36.52 | 0.1826
Eternal wood | 39.1594 | 6.02453 | 0.0301227
Eternal wood | 368.726 | 56.7271 | 0.283635
Eternal wood | 166.749 | 25.6536 | 0.128268
Eternal wood | 4101.63 | 631.019 | 3.1551
Eternal wood | 43.4652 | 6.68695 | 0.0334348
Sportvloer | 1980.36 | 304.672 | 1.52336
Eternal wood | 413.063 | 63.5481 | 0.317741
Eternal wood | 1319.57 | 203.011 | 1.01505

# IfcBuildingElementProxy: _Dichte arcering 50 (2)
In: Begane grond
Material: _Dichte arcering
AC_Pset_RenovationAndPhasing - Renovation Status: Existing
Material Properties - _Dichte arcering, ThermalConductivity: 0.5; _Dichte arcering, SpecificHeatCapacity: 840 J/kg/K; _Dichte arcering, MassDensity: 1300 kg/m3; _Dichte arcering, Embodied Energy: 0.75 (MJ/kg); _Dichte arcering, Embodied Carbon: 0.1 (kgCO₂/kg); _Dichte arcering, Name: _Dichte arcering; _Dichte arcering, Participates in Collision Detection: yes
Component Quantities - _Dichte arcering, Component Thickness: 50 mm
Name | Classification | _Dichte arcering, Mass (kg) | _Dichte arcering, Projected Component Area (Net) (m2) = _Dichte arcering, Projected Component Area (Gross) (m2) | _Dichte arcering, Component Volume (Net) (m3) = _Dichte arcering, Component Volume (Gross) (m3)
keuken blad |  (NL/SfB (2 cijfers)); Bouwkundige elementen (ARCHICAD Classification NED) | 285.283 | 4.38898 | 0.219449
Vaste inrichting | 27 DAKEN (NL/SfB (4 cijfers)) | 67.0472 | 1.0315 | 0.0515748

# IfcBuildingElementProxy: _Dichte arcering 60, balie hoog_door derden
In: Begane grond
Classification:  (NL/SfB (2 cijfers)); Bouwkundige elementen (ARCHICAD Classification NED); Material: _Dichte arcering
AC_Pset_RenovationAndPhasing - Renovation Status: Existing
Material Properties - _Dichte arcering, ThermalConductivity: 0.5; _Dichte arcering, SpecificHeatCapacity: 840 J/kg/K; _Dichte arcering, MassDensity: 1300 kg/m3; _Dichte arcering, Embodied Energy: 0.75 (MJ/kg); _Dichte arcering, Embodied Carbon: 0.1 (kgCO₂/kg); _Dichte arcering, Name: _Dichte arcering; _Dichte arcering, Participates in Collision Detection: yes
Component Quantities - _Dichte arcering, Mass: 229.787 kg; _Dichte arcering, Projected Component Area (Net): 2.94599 m2; _Dichte arcering, Projected Component Area (Gross): 2.94599 m2; _Dichte arcering, Component Thickness: 60 mm; _Dichte arcering, Component Volume (Net): 0.176759 m3; _Dichte arcering, Component Volume (Gross): 0.176759 m3

# IfcBuildingElementProxy: afdekband 255 255 x 95 (7)
In: Begane grond
Classification: 45 Plafondafwerkingen (NL/SfB (2 cijfers)); 45 PLAFONDAFWERKINGEN (EcoQuaestor); Material: Beton gewapend prefab
AC_Pset_RenovationAndPhasing - Renovation Status: Existing
Material Properties - Beton gewapend prefab, ThermalConductivity: 2.5; Beton gewapend prefab, SpecificHeatCapacity: 1000 J/kg/K; Beton gewapend prefab, MassDensity: 2400 kg/m3; Beton gewapend prefab, Embodied Energy: 2.33 (MJ/kg); Beton gewapend prefab, Embodied Carbon: 0.242 (kgCO₂/kg); Beton gewapend prefab, Name: Beton gewapend prefab; Beton gewapend prefab, Participates in Collision Detection: yes
Component Quantities - Beton gewapend prefab, Component Cross Section Area: 0.0191618 m2
Name | Beton gewapend prefab, Mass (kg) | Beton gewapend prefab, Component Volume (Net) (m3) = Beton gewapend prefab, Component Volume (Gross) (m3)
Afdekband | 635.79 | 0.264912
Afdekband | 909.834 | 0.379098
Afdekband | 596.853 | 0.248689
Afdekband | 732.277 | 0.305115
Afdekband | 1053.76 | 0.439067
Afdekband | 283.248 | 0.11802
Afdekband | 132.375 | 0.0551563

# IfcBuildingElementProxy: afdekband 480 480 x 122 (8)
In: Begane grond
Material: Beton gewapend prefab
AC_Pset_RenovationAndPhasing - Renovation Status: Existing
Material Properties - Beton gewapend prefab, ThermalConductivity: 2.5; Beton gewapend prefab, SpecificHeatCapacity: 1000 J/kg/K; Beton gewapend prefab, MassDensity: 2400 kg/m3; Beton gewapend prefab, Embodied Energy: 2.33 (MJ/kg); Beton gewapend prefab, Embodied Carbon: 0.242 (kgCO₂/kg); Beton gewapend prefab, Name: Beton gewapend prefab; Beton gewapend prefab, Participates in Collision Detection: yes
Component Quantities - Beton gewapend prefab, Mass: 144.624 kg; Beton gewapend prefab, Component Cross Section Area: 0.0481787 m2; Beton gewapend prefab, Component Volume (Net): 0.0602602 m3; Beton gewapend prefab, Component Volume (Gross): 0.0602602 m3

# IfcBuildingElementProxy: keerwand h1500 970 x 1815 (7)
In: Begane grond
Classification: 45 Plafondafwerkingen (NL/SfB (2 cijfers)); 45 PLAFONDAFWERKINGEN (EcoQuaestor)
AC_Pset_RenovationAndPhasing - Renovation Status: Existing

# IfcBuildingElementProxy: keerwand h1750 1270 x 2050 (8)
In: Begane grond
Classification: 45 Plafondafwerkingen (NL/SfB (2 cijfers)); 45 PLAFONDAFWERKINGEN (EcoQuaestor)
AC_Pset_RenovationAndPhasing - Renovation Status: Existing

# IfcBuildingElementProxy: ladderboring 730 x 160 (4)
In: 1e verdieping
Classification: 28 HOOFDDRAAGCONSTRUCTIES (EcoQuaestor); 28 Hoofddraagconstructies (NL/SfB (2 cijfers)); Material: Metaal - RVS
AC_Pset_RenovationAndPhasing - Renovation Status: Existing
Material Properties - Metaal - RVS, ThermalConductivity: 17; Metaal - RVS, SpecificHeatCapacity: 460 J/kg/K; Metaal - RVS, MassDensity: 7900 kg/m3; Metaal - RVS, Embodied Energy: 56.7 (MJ/kg); Metaal - RVS, Embodied Carbon: 6.15 (kgCO₂/kg); Metaal - RVS, Name: Metaal - RVS; Metaal - RVS, Participates in Collision Detection: yes
Component Quantities - Metaal - RVS, Mass: 3.28424 kg; Metaal - RVS, Component Cross Section Area: 0.00519659 m2; Metaal - RVS, Component Volume (Net): 0.000415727 m3; Metaal - RVS, Component Volume (Gross): 0.000415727 m3

# IfcBuildingElementProxy: plafondhaak (374)
In: Begane grond
Pset_FireRatingProperties - FireResistanceRating: WBDBO (min)
Pset_QuantityTakeOff - LocalContext: Code; Reference: Omschrijving
AC_Pset_RenovationAndPhasing - Renovation Status: Existing

# IfcColumn: 285*285 (2)
In: Begane grond
Description: 285*285; Classification: Kolom (ARCHICAD Classification); Material: CONCRETE/C30/37
Default - Stortmethode: Insitu; NL-SfB_DESCRIPTION: Kolom-/Liggerconstructie insitu; NL-SfB_NUMBERCODE: 28.11.41; IS_EXTERNAL: Nee; LOAD_BEARING: Ondersteuning; FIRE_RATING: R60; IFC_CLASS_REF_CODE: 28.11.41 ; Kolom-/Liggerconstructie insitu; IFC_BUILDING_STOREY: Undefined; IFC_BUILDING: Undefined; MATERIAL: C30/37; NAME: KOLOM
Tekla Common - Bottom elevation: -0.500; Top elevation: +0.460; Phase: 1; Class: 3
Tekla Quantity - Weight: 187.14 kg; Volume: 0.078 m3; Gross footprint area: 0.081 m2; Area per tons: 6.716 m2; Net surface area: 1.257 m2; Height: 285 mm; Width: 285 mm; Length: 960 mm
Pset_ColumnCommon - FireRating: R60; Reference: M0(?); Slope: 90 deg; LoadBearing: yes; IsExternal: no
CPset_Phasing - Renovation Phase: Bestaand
AC_Pset_RenovationAndPhasing - Renovation Status: Existing
Material Properties - CONCRETE/C30/37, ThermalConductivity: 2.3; CONCRETE/C30/37, SpecificHeatCapacity: 1000 J/kg/K; CONCRETE/C30/37, MassDensity: 2300 kg/m3; CONCRETE/C30/37, Embodied Energy: 1.92 (MJ/kg); CONCRETE/C30/37, Embodied Carbon: 0.198 (kgCO₂/kg); CONCRETE/C30/37, Name: CONCRETE/C30/37; CONCRETE/C30/37, Participates in Collision Detection: yes
BaseQuantities - Length: 960 mm; Width: 285 mm; Depth: 285 mm; CrossSectionArea: 0.081225 m2; OuterSurfaceArea: 1.0944 m2; TotalSurfaceArea: 1.25685 m2; GrossSurfaceArea: 1.25685 m2; GrossVolume: 0.077976 m3; NetVolume: 0.077976 m3
Component Quantities - CONCRETE/C30/37, Mass: 179.345 kg; CONCRETE/C30/37, Component Thickness: 285 mm; CONCRETE/C30/37, Rectangular Component Height: 285 mm; CONCRETE/C30/37, Rectangular Component Width: 285 mm; CONCRETE/C30/37, Component Cross Section Area: 0.081225 m2; CONCRETE/C30/37, Component Volume (Net): 0.077976 m3; CONCRETE/C30/37, Component Volume (Gross): 0.077976 m3

# IfcColumn: 300*410 (23)
In: Begane grond
Description: 300*410; Classification: Kolom (ARCHICAD Classification); Material: CONCRETE/C30/37
Default - Stortmethode: Insitu; NL-SfB_DESCRIPTION: Kolom-/Liggerconstructie insitu; NL-SfB_NUMBERCODE: 28.11.41; IS_EXTERNAL: Nee; LOAD_BEARING: Ondersteuning; FIRE_RATING: R60; IFC_CLASS_REF_CODE: 28.11.41 ; Kolom-/Liggerconstructie insitu; IFC_BUILDING_STOREY: Undefined; IFC_BUILDING: Undefined; MATERIAL: C30/37
Tekla Common - Phase: 1; Class: 3
Tekla Quantity - Weight: 109.22 kg; Volume: 0.046 m3; Gross footprint area: 0.123 m2; Area per tons: 7.063 m2; Net surface area: 0.771 m2; Height: 410 mm; Width: 300 mm; Length: 370 mm
Pset_ColumnCommon - FireRating: R60; Slope: 90 deg; LoadBearing: yes; IsExternal: no
CPset_Phasing - Renovation Phase: Bestaand
AC_Pset_RenovationAndPhasing - Renovation Status: Existing
Material Properties - CONCRETE/C30/37, ThermalConductivity: 2.3; CONCRETE/C30/37, SpecificHeatCapacity: 1000 J/kg/K; CONCRETE/C30/37, MassDensity: 2300 kg/m3; CONCRETE/C30/37, Embodied Energy: 1.92 (MJ/kg); CONCRETE/C30/37, Embodied Carbon: 0.198 (kgCO₂/kg); CONCRETE/C30/37, Name: CONCRETE/C30/37; CONCRETE/C30/37, Participates in Collision Detection: yes
BaseQuantities - Length: 370 mm; Width: 300 mm; Depth: 410 mm; CrossSectionArea: 0.123 m2; OuterSurfaceArea: 0.5254 m2; TotalSurfaceArea: 0.7714 m2; GrossSurfaceArea: 0.7714 m2; GrossVolume: 0.04551 m3; NetVolume: 0.04551 m3
Component Quantities - CONCRETE/C30/37, Mass: 104.673 kg; CONCRETE/C30/37, Component Thickness: 300 mm; CONCRETE/C30/37, Rectangular Component Height: 410 mm; CONCRETE/C30/37, Rectangular Component Width: 300 mm; CONCRETE/C30/37, Component Cross Section Area: 0.123 m2; CONCRETE/C30/37, Component Volume (Net): 0.04551 m3; CONCRETE/C30/37, Component Volume (Gross): 0.04551 m3
Name | NAME | Bottom elevation | Top elevation | Reference
2 x BETONOPSTORT | BETONOPSTORT | +0.460 | +0.830 | W0(?)
21 x KOLOM | KOLOM | -0.440 | -0.070 | M0(?)

# IfcColumn: B244.5/6.3 (6)
In: Begane grond
Description: B244.5/6.3; Classification: Kolom (ARCHICAD Classification); Material: STEEL/S275
Default - NL-SfB_DESCRIPTION: Kolom-/Liggerconstructie staal; NL-SfB_NUMBERCODE: 28.11.21; IS_EXTERNAL: Nee; LOAD_BEARING: Ondersteuning; FIRE_RATING: R0; IFC_CLASS_REF_CODE: 28.11.21 ; Kolom-/Liggerconstructie staal; IFC_BUILDING_STOREY: Undefined; IFC_BUILDING: Undefined; MATERIAL: S275; NAME: KOLOM
Tekla Common - Phase: 1; Class: 5
Pset_ColumnCommon - FireRating: R0; Reference: SKK0(?); Slope: 90 deg; LoadBearing: yes; IsExternal: no
Tekla Quantity - Gross footprint area: 0.005 m2; Area per tons: 20.418 m2; Height: 244.5 mm; Width: 244.5 mm
CPset_Phasing - Renovation Phase: Bestaand
AC_Pset_RenovationAndPhasing - Renovation Status: Existing
Material Properties - STEEL/S275, ThermalConductivity: 2.3; STEEL/S275, SpecificHeatCapacity: 1000 J/kg/K; STEEL/S275, MassDensity: 2300 kg/m3; STEEL/S275, Embodied Energy: 1.92 (MJ/kg); STEEL/S275, Embodied Carbon: 0.198 (kgCO₂/kg); STEEL/S275, Name: STEEL/S275; STEEL/S275, Participates in Collision Detection: yes
BaseQuantities - CrossSectionArea: 0.00471446 m2
Component Quantities - STEEL/S275, Component Cross Section Area: 0.00471446 m2
Name | Bottom elevation | Top elevation | Weight (kg) | Volume (m3) | Net surface area (m2) | Tekla Quantity, Length (mm) | BaseQuantities, Length (mm) | OuterSurfaceArea (m2) | TotalSurfaceArea (m2) = GrossSurfaceArea (m2) | GrossVolume (m3) = NetVolume (m3) = STEEL/S275, Component Volume (Net) (m3) = STEEL/S275, Component Volume (Gross) (m3) | STEEL/S275, Mass (kg)
KOLOM | +0.460 | +4.851 | 165.58 | 0.021 | 3.37 | 4390.7 | 4390.67 | 6.52544 | 6.5323 | 0.0207219 | 47.6604
2 x KOLOM | -0.100 | +3.650 | 141.42 | 0.019 | 2.879 | 3750 | 3750 | 5.59766 | 5.60714 | 0.0177736 | 40.8793
3 x KOLOM | -0.100 | +3.680 | 142.55 | 0.019 | 2.902 | 3780 | 3780 | 5.64244 | 5.65192 | 0.0179158 | 41.2063

# IfcColumn: KW120/10 (2)
In: Begane grond
Description: KW120/10; Classification: Kolom (ARCHICAD Classification); Material: STEEL/S275
Default - NL-SfB_DESCRIPTION: Kolom-/Liggerconstructie staal; NL-SfB_NUMBERCODE: 28.11.21; IS_EXTERNAL: Nee; LOAD_BEARING: Ondersteuning; FIRE_RATING: R0; IFC_CLASS_REF_CODE: 28.11.21 ; Kolom-/Liggerconstructie staal; IFC_BUILDING_STOREY: Undefined; IFC_BUILDING: Undefined; MATERIAL: S275; NAME: KOLOM
Tekla Common - Bottom elevation: +0.460; Top elevation: +4.851; Phase: 1; Class: 5
Tekla Quantity - Weight: 150.69 kg; Volume: 0.019 m3; Gross footprint area: 0.004 m2; Area per tons: 13.228 m2; Net surface area: 2.112 m2; Height: 120 mm; Width: 120 mm; Length: 4390.7 mm
Pset_ColumnCommon - FireRating: R0; Reference: SKK0(?); Slope: 90 deg; LoadBearing: yes; IsExternal: no
CPset_Phasing - Renovation Phase: Bestaand
AC_Pset_RenovationAndPhasing - Renovation Status: Existing
Material Properties - STEEL/S275, ThermalConductivity: 2.3; STEEL/S275, SpecificHeatCapacity: 1000 J/kg/K; STEEL/S275, MassDensity: 2300 kg/m3; STEEL/S275, Embodied Energy: 1.92 (MJ/kg); STEEL/S275, Embodied Carbon: 0.198 (kgCO₂/kg); STEEL/S275, Name: STEEL/S275; STEEL/S275, Participates in Collision Detection: yes
BaseQuantities - Length: 4390.67 mm; CrossSectionArea: 0.00422832 m2
Component Quantities - STEEL/S275, Component Cross Section Area: 0.00422832 m2
Name | OuterSurfaceArea (m2) | TotalSurfaceArea (m2) = GrossSurfaceArea (m2) | GrossVolume (m3) = NetVolume (m3) = STEEL/S275, Component Volume (Net) (m3) = STEEL/S275, Component Volume (Gross) (m3) | STEEL/S275, Mass (kg)
KOLOM | 3.70399 | 3.7124 | 0.0184556 | 42.4479
KOLOM | 3.70393 | 3.71234 | 0.0184553 | 42.4472

# IfcColumn: KW140/10 (20)
In: Begane grond
Description: KW140/10; Classification: Kolom (ARCHICAD Classification); Material: STEEL/S275
Default - NL-SfB_DESCRIPTION: Kolom-/Liggerconstructie staal; NL-SfB_NUMBERCODE: 28.11.21; IS_EXTERNAL: Nee; LOAD_BEARING: Ondersteuning; FIRE_RATING: R30; IFC_CLASS_REF_CODE: 28.11.21 ; Kolom-/Liggerconstructie staal; IFC_BUILDING_STOREY: Undefined; IFC_BUILDING: Undefined; MATERIAL: S275; NAME: KOLOM
Pset_ColumnCommon - FireRating: R30; Reference: skK0(?); Slope: 90 deg; LoadBearing: yes; IsExternal: no
Tekla Common - Bottom elevation: -0.030; Phase: 1; Class: 5
Tekla Quantity - Volume: 0.017 m3; Gross footprint area: 0.005 m2; Area per tons: 13.114 m2; Height: 140 mm; Width: 140 mm
CPset_Phasing - Renovation Phase: Bestaand
AC_Pset_RenovationAndPhasing - Renovation Status: Existing
Material Properties - STEEL/S275, ThermalConductivity: 2.3; STEEL/S275, SpecificHeatCapacity: 1000 J/kg/K; STEEL/S275, MassDensity: 2300 kg/m3; STEEL/S275, Embodied Energy: 1.92 (MJ/kg); STEEL/S275, Embodied Carbon: 0.198 (kgCO₂/kg); STEEL/S275, Name: STEEL/S275; STEEL/S275, Participates in Collision Detection: yes
BaseQuantities - CrossSectionArea: 0.00502832 m2
Component Quantities - STEEL/S275, Component Cross Section Area: 0.00502832 m2
Name | Top elevation | Weight (kg) | Net surface area (m2) | Tekla Quantity, Length (mm) = BaseQuantities, Length (mm) | OuterSurfaceArea (m2) | TotalSurfaceArea (m2) = GrossSurfaceArea (m2) | GrossVolume (m3) = NetVolume (m3) = STEEL/S275, Component Volume (Net) (m3) = STEEL/S275, Component Volume (Gross) (m3) | STEEL/S275, Mass (kg)
16 x KOLOM | +3.304 | 135.76 | 1.873 | 3334 | 3.34663 | 3.35164 | 0.0166843 | 38.3739
4 x KOLOM | +3.309 | 135.96 | 1.875 | 3339 | 3.35165 | 3.35666 | 0.0167093 | 38.4314

# IfcColumn: KW180/10 (19)
In: Begane grond
Description: KW180/10; Classification: Kolom (ARCHICAD Classification); Material: STEEL/S275
Default - NL-SfB_DESCRIPTION: Kolom-/Liggerconstructie staal; NL-SfB_NUMBERCODE: 28.11.21; IS_EXTERNAL: Nee; LOAD_BEARING: Ondersteuning; FIRE_RATING: R30; IFC_CLASS_REF_CODE: 28.11.21 ; Kolom-/Liggerconstructie staal; IFC_BUILDING_STOREY: Undefined; IFC_BUILDING: Undefined; MATERIAL: S275; NAME: KOLOM
Tekla Common - Phase: 1; Class: 5
Tekla Quantity - Gross footprint area: 0.007 m2; Area per tons: 12.967 m2; Height: 180 mm; Width: 180 mm
Pset_ColumnCommon - FireRating: R30; Slope: 90 deg; LoadBearing: yes; IsExternal: no
CPset_Phasing - Renovation Phase: Bestaand
AC_Pset_RenovationAndPhasing - Renovation Status: Existing
Material Properties - STEEL/S275, ThermalConductivity: 2.3; STEEL/S275, SpecificHeatCapacity: 1000 J/kg/K; STEEL/S275, MassDensity: 2300 kg/m3; STEEL/S275, Embodied Energy: 1.92 (MJ/kg); STEEL/S275, Embodied Carbon: 0.198 (kgCO₂/kg); STEEL/S275, Name: STEEL/S275; STEEL/S275, Participates in Collision Detection: yes
BaseQuantities - CrossSectionArea: 0.00662832 m2
Component Quantities - STEEL/S275, Component Cross Section Area: 0.00662832 m2
Name | Bottom elevation | Top elevation | Weight (kg) | Volume (m3) | Net surface area (m2) | Tekla Quantity, Length (mm) | Reference | BaseQuantities, Length (mm) | OuterSurfaceArea (m2) | TotalSurfaceArea (m2) = GrossSurfaceArea (m2) | GrossVolume (m3) = NetVolume (m3) = STEEL/S275, Component Volume (Net) (m3) = STEEL/S275, Component Volume (Gross) (m3) | STEEL/S275, Mass (kg)
3 x KOLOM | +0.870 | +4.247 | 180.75 | 0.023 | 2.439 | 3377.3 | skK0(?) | 3375 | 4.46779 | 4.46779 | 0.0222895 | 51.2658
KOLOM | -0.050 | +6.548 | 353.12 | 0.043 | 4.758 | 6598 | skK0(?) | 6598 | 8.73436 | 8.74757 | 0.0435751 | 100.223
KOLOM | -0.050 | +6.700 | 361.26 | 0.045 | 4.867 | 6750 | skK0(?) | 6750 | 8.91972 | 8.92971 | 0.0445042 | 102.36
3 x KOLOM | -0.050 | +6.700 | 361.26 | 0.045 | 4.867 | 6750 | SKK0(?) | 6750 | 8.91974 | 8.92973 | 0.0445005 | 102.351
3 x KOLOM | -0.050 | +6.700 | 361.26 | 0.045 | 4.867 | 6750 | skK0(?) | 6750 | 8.91974 | 8.92973 | 0.0445005 | 102.351
KOLOM | -0.050 | +6.700 | 361.26 | 0.045 | 4.867 | 6750 | skK0(?) | 6750 | 8.91975 | 8.92975 | 0.0444976 | 102.344
KOLOM | -0.050 | +6.700 | 361.26 | 0.045 | 4.867 | 6750 | skK0(?) | 6750 | 8.91799 | 8.92798 | 0.0444917 | 102.331
KOLOM | +0.869 | +4.247 | 180.8 | 0.023 | 2.439 | 3378.3 | skK0(?) | 3376 | 4.46911 | 4.46911 | 0.0222961 | 51.281
2 x KOLOM | +0.870 | +4.100 | 172.87 | 0.021 | 2.333 | 3230 | skK0(?) | 3230 | 4.27584 | 4.28244 | 0.0213319 | 49.0633
KOLOM | -0.050 | +6.700 | 361.26 | 0.045 | 4.867 | 6750 | SKK0(?) | 6750 | 8.91976 | 8.92975 | 0.0444964 | 102.342
KOLOM | -0.050 | +6.700 | 361.26 | 0.045 | 4.867 | 6750 | skK0(?) | 6750 | 8.91838 | 8.92837 | 0.0444936 | 102.335
KOLOM | -0.050 | +6.700 | 361.26 | 0.045 | 4.867 | 6750 | SKK0(?) | 6750 | 8.91972 | 8.92972 | 0.0445038 | 102.359

# IfcColumn: KW180/12.5, KOLOM
In: Begane grond
Description: KW180/12.5; Classification: Kolom (ARCHICAD Classification); Material: STEEL/S275
Default - NL-SfB_DESCRIPTION: Kolom-/Liggerconstructie staal; NL-SfB_NUMBERCODE: 28.11.21; IS_EXTERNAL: Nee; LOAD_BEARING: Ondersteuning; FIRE_RATING: R30; IFC_CLASS_REF_CODE: 28.11.21 ; Kolom-/Liggerconstructie staal; IFC_BUILDING_STOREY: Undefined; IFC_BUILDING: Undefined; MATERIAL: S275; NAME: KOLOM
Tekla Common - Bottom elevation: -0.050; Top elevation: +6.700; Phase: 1; Class: 5
Pset_ColumnCommon - FireRating: R30; Reference: SKK0(?); Slope: 90 deg; LoadBearing: yes; IsExternal: no
Tekla Quantity - Weight: 443.34 kg; Volume: 0.055 m3; Gross footprint area: 0.008 m2; Area per tons: 10.475 m2; Net surface area: 4.869 m2; Height: 180 mm; Width: 180 mm; Length: 6750 mm
CPset_Phasing - Renovation Phase: Bestaand
AC_Pset_RenovationAndPhasing - Renovation Status: Existing
Material Properties - STEEL/S275, ThermalConductivity: 2.3; STEEL/S275, SpecificHeatCapacity: 1000 J/kg/K; STEEL/S275, MassDensity: 2300 kg/m3; STEEL/S275, Embodied Energy: 1.92 (MJ/kg); STEEL/S275, Embodied Carbon: 0.198 (kgCO₂/kg); STEEL/S275, Name: STEEL/S275; STEEL/S275, Participates in Collision Detection: yes
BaseQuantities - Length: 6750 mm; CrossSectionArea: 0.00810567 m2; OuterSurfaceArea: 8.71739 m2; TotalSurfaceArea: 8.72875 m2; GrossSurfaceArea: 8.72875 m2; GrossVolume: 0.0543476 m3; NetVolume: 0.0543476 m3
Component Quantities - STEEL/S275, Mass: 125 kg; STEEL/S275, Component Cross Section Area: 0.00810567 m2; STEEL/S275, Component Volume (Net): 0.0543476 m3; STEEL/S275, Component Volume (Gross): 0.0543476 m3

# IfcColumn: KW80/4 (38)
In: Begane grond
Description: KW80/4; Classification: Kolom (ARCHICAD Classification); Material: STEEL/S235
Default - NL-SfB_DESCRIPTION: Kolom-/Liggerconstructie staal; NL-SfB_NUMBERCODE: 28.11.21; IS_EXTERNAL: Nee; LOAD_BEARING: Ondersteuning; FIRE_RATING: R0; IFC_CLASS_REF_CODE: 28.11.21 ; Kolom-/Liggerconstructie staal; IFC_BUILDING_STOREY: Undefined; IFC_BUILDING: Undefined; MATERIAL: S235; NAME: KOLOM
Tekla Common - Finish: schilderen/bekleden; Top elevation: +6.288; Phase: 1; Class: 5
Tekla Quantity - Volume: 0.002 m3; Gross footprint area: 0.001 m2; Area per tons: 32.292 m2; Height: 80 mm; Width: 80 mm
Pset_ColumnCommon - FireRating: R0; Reference: SK0(?); Slope: 90 deg; LoadBearing: yes; IsExternal: no
CPset_Phasing - Renovation Phase: Bestaand
AC_Pset_RenovationAndPhasing - Renovation Status: Existing
Material Properties - STEEL/S235, ThermalConductivity: 2.3; STEEL/S235, SpecificHeatCapacity: 1000 J/kg/K; STEEL/S235, MassDensity: 2300 kg/m3; STEEL/S235, Embodied Energy: 1.92 (MJ/kg); STEEL/S235, Embodied Carbon: 0.198 (kgCO₂/kg); STEEL/S235, Name: STEEL/S235; STEEL/S235, Participates in Collision Detection: yes
BaseQuantities - CrossSectionArea: 0.00118853 m2
Component Quantities - STEEL/S235, Component Cross Section Area: 0.00118853 m2
Name | Bottom elevation | Weight (kg) | Net surface area (m2) | Tekla Quantity, Length (mm) | BaseQuantities, Length (mm) | OuterSurfaceArea (m2) | TotalSurfaceArea (m2) = GrossSurfaceArea (m2) | GrossVolume (m3) = NetVolume (m3) = STEEL/S235, Component Volume (Net) (m3) = STEEL/S235, Component Volume (Gross) (m3) | STEEL/S235, Mass (kg)
9 x KOLOM | +4.239 | 19.67 | 0.657 | 2049.4 | 2049.38 | 1.21525 | 1.21761 | 0.00241521 | 5.55499
29 x KOLOM | +4.829 | 14.01 | 0.468 | 1459.4 | 1459.38 | 0.865388 | 0.867745 | 0.00171989 | 3.95575

# IfcColumn: UNP200 (3)
In: Begane grond
Description: UNP200; Classification: Kolom (ARCHICAD Classification); Material: STEEL/S235
Pset_ColumnCommon - FireRating: R0; Reference: SKK0(?); Slope: 90 deg; LoadBearing: yes; IsExternal: no
Default - NL-SfB_DESCRIPTION: Kolom-/Liggerconstructie staal; NL-SfB_NUMBERCODE: 28.11.21; IS_EXTERNAL: Nee; LOAD_BEARING: Ondersteuning; FIRE_RATING: R0; IFC_CLASS_REF_CODE: 28.11.21 ; Kolom-/Liggerconstructie staal; IFC_BUILDING_STOREY: Undefined; IFC_BUILDING: Undefined; MATERIAL: S235; NAME: KOLOM
Tekla Common - Bottom elevation: +3.580; Top elevation: +4.851; Phase: 1; Class: 5
Tekla Quantity - Weight: 32.72 kg; Volume: 0.004 m3; Gross footprint area: 0.003 m2; Area per tons: 25.637 m2; Net surface area: 0.861 m2; Height: 200 mm; Width: 75 mm; Length: 1270.8 mm
CPset_Phasing - Renovation Phase: Bestaand
AC_Pset_RenovationAndPhasing - Renovation Status: Existing
Material Properties - STEEL/S235, ThermalConductivity: 2.3; STEEL/S235, SpecificHeatCapacity: 1000 J/kg/K; STEEL/S235, MassDensity: 2300 kg/m3; STEEL/S235, Embodied Energy: 1.92 (MJ/kg); STEEL/S235, Embodied Carbon: 0.198 (kgCO₂/kg); STEEL/S235, Name: STEEL/S235; STEEL/S235, Participates in Collision Detection: yes
BaseQuantities - Length: 1270.81 mm; CrossSectionArea: 0.00321849 m2; OuterSurfaceArea: 0.837648 m2; TotalSurfaceArea: 0.844111 m2; GrossSurfaceArea: 0.844111 m2; GrossVolume: 0.00410652 m3; NetVolume: 0.00410652 m3
Component Quantities - STEEL/S235, Mass: 9.44499 kg; STEEL/S235, Component Cross Section Area: 0.00321849 m2; STEEL/S235, Component Volume (Net): 0.00410652 m3; STEEL/S235, Component Volume (Gross): 0.00410652 m3

# IfcColumn: Ø168.3*16, KOLOM
In: Begane grond
Description: Ø168.3*16; Classification: Kolom (ARCHICAD Classification); Material: STEEL/S355
Pset_ColumnCommon - FireRating: R30; Reference: skK0(?); Slope: 90 deg; LoadBearing: yes; IsExternal: no
Default - NL-SfB_DESCRIPTION: Kolom-/Liggerconstructie staal; NL-SfB_NUMBERCODE: 28.11.21; IS_EXTERNAL: Nee; LOAD_BEARING: Ondersteuning; FIRE_RATING: R30; IFC_CLASS_REF_CODE: 28.11.21 ; Kolom-/Liggerconstructie staal; IFC_BUILDING_STOREY: Undefined; IFC_BUILDING: Undefined; MATERIAL: S355; NAME: KOLOM
Tekla Common - Bottom elevation: -0.030; Top elevation: +3.304; Phase: 1; Class: 5
Tekla Quantity - Weight: 201.86 kg; Volume: 0.025 m3; Gross footprint area: 0.008 m2; Area per tons: 8.749 m2; Net surface area: 1.766 m2; Height: 168.3 mm; Width: 168.3 mm; Length: 3334 mm
CPset_Phasing - Renovation Phase: Bestaand
AC_Pset_RenovationAndPhasing - Renovation Status: Existing
Material Properties - STEEL/S355, ThermalConductivity: 2.3; STEEL/S355, SpecificHeatCapacity: 1000 J/kg/K; STEEL/S355, MassDensity: 2300 kg/m3; STEEL/S355, Embodied Energy: 1.92 (MJ/kg); STEEL/S355, Embodied Carbon: 0.198 (kgCO₂/kg); STEEL/S355, Name: STEEL/S355; STEEL/S355, Participates in Collision Detection: yes
BaseQuantities - Length: 3334 mm; CrossSectionArea: 0.00765543 m2; OuterSurfaceArea: 3.17855 m2; TotalSurfaceArea: 3.18615 m2; GrossSurfaceArea: 3.18615 m2; GrossVolume: 0.0253153 m3; NetVolume: 0.0253153 m3
Component Quantities - STEEL/S355, Mass: 58.2251 kg; STEEL/S355, Component Cross Section Area: 0.00765543 m2; STEEL/S355, Component Volume (Net): 0.0253153 m3; STEEL/S355, Component Volume (Gross): 0.0253153 m3

# IfcCovering: 23 BG vloer clubgebouw 452
In: Begane grond
Type - PredefinedType: ROOFING
Classification: Dakafwerking (ARCHICAD Classification); 47 Dakafwerkingen (NL/SfB (4 cijfers))
Pset_CoveringCommon - Material: 23 BG vloer clubgebouw
CPset_Phasing - Renovation Phase: Bestaand
AC_Pset_RenovationAndPhasing - Renovation Status: Existing
BaseQuantities - GrossArea: 556.69 m2; NetArea: 533.954 m2

# IfcCovering: 23 BG vloer gymzaal 730 (2)
In: Begane grond
Type - PredefinedType: ROOFING
Classification: Dakafwerking (ARCHICAD Classification); 47 Dakafwerkingen (NL/SfB (4 cijfers))
Pset_CoveringCommon - Material: 23 BG vloer gymzaal
CPset_Phasing - Renovation Phase: Bestaand
AC_Pset_RenovationAndPhasing - Renovation Status: Existing
Name | GrossArea (m2) | NetArea (m2)
 | 321.323 | 321.323
 | 22.4651 | 21.0657

# IfcCovering: 23 BG vloer school 452
In: Begane grond
Type - PredefinedType: ROOFING
Classification: Dakafwerking (ARCHICAD Classification); 47 Dakafwerkingen (NL/SfB (4 cijfers))
Pset_CoveringCommon - Material: 23 BG vloer school
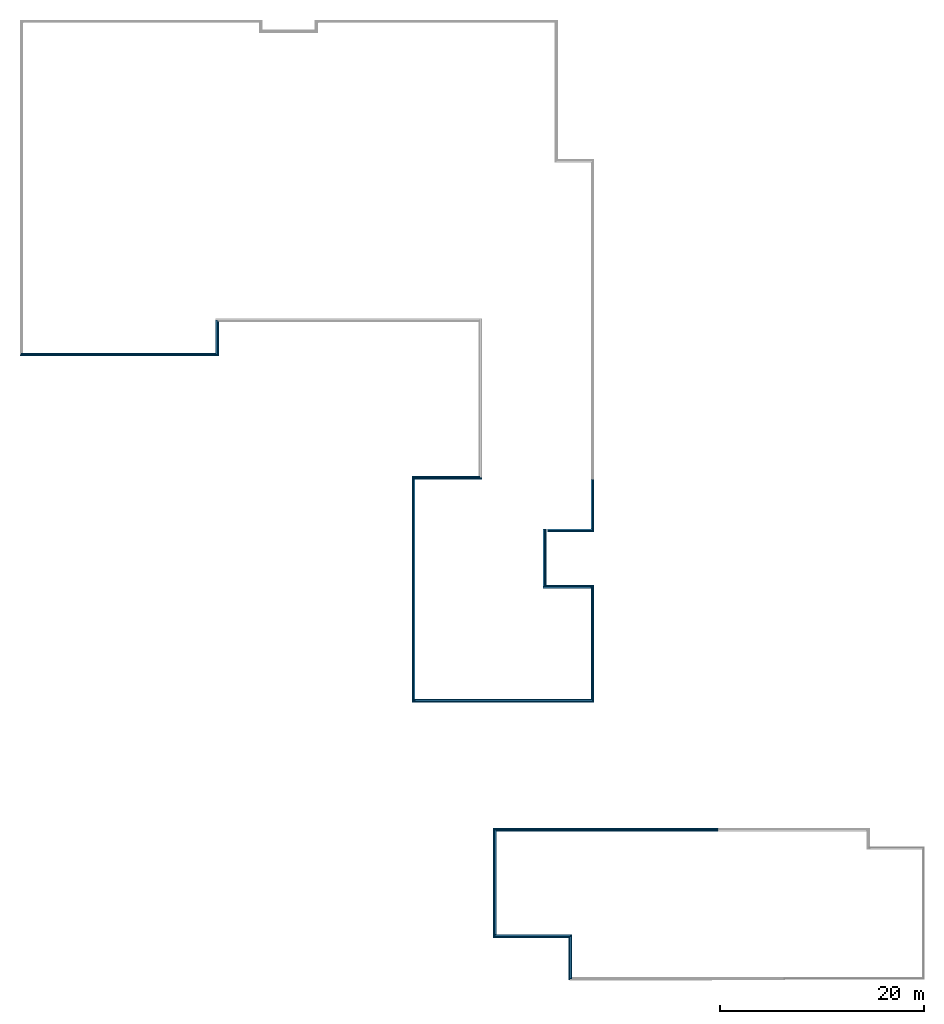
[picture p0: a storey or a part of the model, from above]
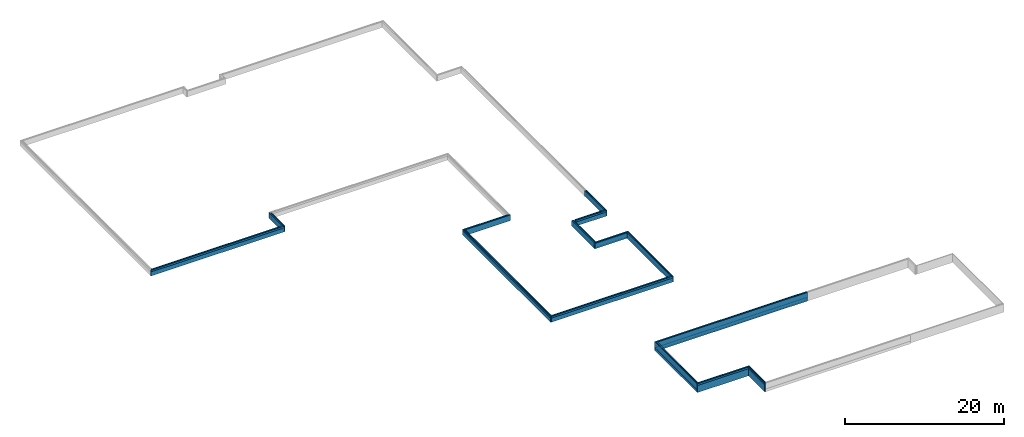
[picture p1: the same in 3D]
Properties of the parts of a building model (IFC2X3), part 15 of 19

# IfcCovering: 23 BG vloer school 452
CPset_Phasing - Renovation Phase: Bestaand
AC_Pset_RenovationAndPhasing - Renovation Status: Existing
BaseQuantities - GrossArea: 1789.55 m2; NetArea: 1742.58 m2

# IfcCovering: 23 vloerluik 70 (5)
In: Begane grond
Type - PredefinedType: ROOFING
Classification: Dakafwerking (ARCHICAD Classification); 47 Dakafwerkingen (NL/SfB (4 cijfers))
Pset_CoveringCommon - Material: 23 vloerluik
CPset_Phasing - Renovation Phase: Bestaand
AC_Pset_RenovationAndPhasing - Renovation Status: Existing
BaseQuantities - GrossArea: 0.48 m2; NetArea: 0.48 m2

# IfcCovering: 27 Dakvloer Clubgebouw - KP 200+50 200, Dakvloer
In: 1e verdieping
Type - PredefinedType: ROOFING
Classification: Dakafwerking (ARCHICAD Classification); 47 Dakafwerkingen (NL/SfB (4 cijfers))
Pset_CoveringCommon - Material: 27 Dakvloer Clubgebouw - KP 200+50
CPset_Phasing - Renovation Phase: Bestaand
AC_Pset_RenovationAndPhasing - Renovation Status: Existing
BaseQuantities - GrossArea: 430.604 m2; NetArea: 430.604 m2

# IfcCovering: 27 Dakvloer gymzaal - perfo staalplaat 163, Dakvloer
In: 1e verdieping
Type - PredefinedType: ROOFING
Classification: Dakafwerking (ARCHICAD Classification); 47 Dakafwerkingen (NL/SfB (4 cijfers))
Pset_CoveringCommon - Material: 27 Dakvloer gymzaal - perfo staalplaat
CPset_Phasing - Renovation Phase: Bestaand
AC_Pset_RenovationAndPhasing - Renovation Status: Existing
BaseQuantities - GrossArea: 267.053 m2; NetArea: 267.053 m2

# IfcCovering: 27 Dakvloer kantine - perfo staalplaat 163, Dakvloer
In: 1e verdieping
Type - PredefinedType: ROOFING
Classification: Dakafwerking (ARCHICAD Classification); 47 Dakafwerkingen (NL/SfB (4 cijfers))
Pset_CoveringCommon - Material: 27 Dakvloer kantine - perfo staalplaat
CPset_Phasing - Renovation Phase: Bestaand
AC_Pset_RenovationAndPhasing - Renovation Status: Existing
BaseQuantities - GrossArea: 129.57 m2; NetArea: 129.57 m2

# IfcCovering: 27 Dakvloer opslag - KP 200+50 200, Dakvloer
In: 1e verdieping
Type - PredefinedType: ROOFING
Classification: Dakafwerking (ARCHICAD Classification); 47 Dakafwerkingen (NL/SfB (4 cijfers))
Pset_CoveringCommon - Material: 27 Dakvloer opslag - KP 200+50
CPset_Phasing - Renovation Phase: Bestaand
AC_Pset_RenovationAndPhasing - Renovation Status: Existing
BaseQuantities - GrossArea: 49.9881 m2; NetArea: 49.9881 m2

# IfcCovering: 27 Dakvloer school_KP 200+50mm 250, Dakvloer
In: 1e verdieping
Type - PredefinedType: ROOFING
Classification: Dakafwerking (ARCHICAD Classification); 47 Dakafwerkingen (NL/SfB (4 cijfers))
Pset_CoveringCommon - Material: 27 Dakvloer school_KP 200+50mm
CPset_Phasing - Renovation Phase: Bestaand
AC_Pset_RenovationAndPhasing - Renovation Status: Existing
BaseQuantities - GrossArea: 1789.55 m2; NetArea: 1775.96 m2

# IfcCovering: ALG - ALGEMEEN 13 (3)
In: Begane grond
Type - PredefinedType: ROOFING
Classification: Dakafwerking (ARCHICAD Classification); 47 Dakafwerkingen (NL/SfB (4 cijfers)); Material: ALG - ALGEMEEN
Pset_CoveringCommon - Material: ALG - ALGEMEEN
CPset_Phasing - Renovation Phase: Bestaand
AC_Pset_RenovationAndPhasing - Renovation Status: Existing
Material Properties - ALG - ALGEMEEN, ThermalConductivity: 0.27; ALG - ALGEMEEN, SpecificHeatCapacity: 840 J/kg/K; ALG - ALGEMEEN, MassDensity: 800 kg/m3; ALG - ALGEMEEN, Embodied Energy: 2 (MJ/kg); ALG - ALGEMEEN, Embodied Carbon: 0.13 (kgCO₂/kg); ALG - ALGEMEEN, Name: ALG - ALGEMEEN; ALG - ALGEMEEN, Participates in Collision Detection: yes
BaseQuantities - GrossArea: 0.203934 m2; NetArea: 0.203934 m2
Component Quantities - ALG - ALGEMEEN, Mass: 2.12092 kg; ALG - ALGEMEEN, Projected Component Area (Net): 0.203934 m2; ALG - ALGEMEEN, Projected Component Area (Gross): 0.203934 m2; ALG - ALGEMEEN, Component Thickness: 13 mm; ALG - ALGEMEEN, Component Volume (Net): 0.00265115 m3; ALG - ALGEMEEN, Component Volume (Gross): 0.00265115 m3

# IfcCovering: ALG - ALGEMEEN 1800, patchkast cf inst. adv.
In: Begane grond
Type - PredefinedType: ROOFING
Classification: Dakafwerking (ARCHICAD Classification); 47 Dakafwerkingen (NL/SfB (4 cijfers)); Material: ALG - ALGEMEEN
Pset_CoveringCommon - Material: ALG - ALGEMEEN
CPset_Phasing - Renovation Phase: Bestaand
AC_Pset_RenovationAndPhasing - Renovation Status: Existing
Material Properties - ALG - ALGEMEEN, ThermalConductivity: 0.27; ALG - ALGEMEEN, SpecificHeatCapacity: 840 J/kg/K; ALG - ALGEMEEN, MassDensity: 800 kg/m3; ALG - ALGEMEEN, Embodied Energy: 2 (MJ/kg); ALG - ALGEMEEN, Embodied Carbon: 0.13 (kgCO₂/kg); ALG - ALGEMEEN, Name: ALG - ALGEMEEN; ALG - ALGEMEEN, Participates in Collision Detection: yes
BaseQuantities - GrossArea: 0.49 m2; NetArea: 0.49 m2
Component Quantities - ALG - ALGEMEEN, Mass: 705.6 kg; ALG - ALGEMEEN, Projected Component Area (Net): 0.49 m2; ALG - ALGEMEEN, Projected Component Area (Gross): 0.49 m2; ALG - ALGEMEEN, Component Thickness: 1800 mm; ALG - ALGEMEEN, Component Volume (Net): 0.882 m3; ALG - ALGEMEEN, Component Volume (Gross): 0.882 m3

# IfcCovering: ALG - ALGEMEEN 20 (113)
In: Begane grond
Type - PredefinedType: ROOFING
Classification: Dakafwerking (ARCHICAD Classification); 47 Dakafwerkingen (NL/SfB (4 cijfers)); Material: ALG - ALGEMEEN
Pset_CoveringCommon - Material: ALG - ALGEMEEN
CPset_Phasing - Renovation Phase: Bestaand
AC_Pset_RenovationAndPhasing - Renovation Status: Existing
Material Properties - ALG - ALGEMEEN, ThermalConductivity: 0.27; ALG - ALGEMEEN, SpecificHeatCapacity: 840 J/kg/K; ALG - ALGEMEEN, MassDensity: 800 kg/m3; ALG - ALGEMEEN, Embodied Energy: 2 (MJ/kg); ALG - ALGEMEEN, Embodied Carbon: 0.13 (kgCO₂/kg); ALG - ALGEMEEN, Name: ALG - ALGEMEEN; ALG - ALGEMEEN, Participates in Collision Detection: yes
Component Quantities - ALG - ALGEMEEN, Component Thickness: 20 mm
Name | GrossArea (m2) = ALG - ALGEMEEN, Projected Component Area (Gross) (m2) | NetArea (m2) = ALG - ALGEMEEN, Projected Component Area (Net) (m2) | ALG - ALGEMEEN, Mass (kg) | ALG - ALGEMEEN, Component Volume (Net) (m3) | ALG - ALGEMEEN, Component Volume (Gross) (m3)
 | 12.4701 | 12.4701 | 199.521 | 0.249401 | 0.249401
 | 12.7658 | 12.7658 | 204.253 | 0.255317 | 0.255317
 | 54.0099 | 54.0099 | 864.159 | 1.0802 | 1.0802
 | 9.97492 | 9.97492 | 159.599 | 0.199498 | 0.199498
 | 37.2674 | 37.2674 | 596.279 | 0.745349 | 0.745349
 | 35.8248 | 35.8248 | 573.196 | 0.716495 | 0.716495
2 x  | 1.29 | 1.29 | 20.64 | 0.0258 | 0.0258
 | 24.4228 | 24.4228 | 390.764 | 0.488455 | 0.488455
 | 9.33973 | 9.33973 | 149.436 | 0.186795 | 0.186795
 | 7.64856 | 7.64856 | 122.377 | 0.152971 | 0.152971
 | 62.8416 | 62.8416 | 1005.47 | 1.25683 | 1.25683
 | 5.90002 | 5.90002 | 94.4003 | 0.118 | 0.118
 | 1.155 | 1.155 | 18.48 | 0.0231 | 0.0231
7 x  | 1.1374 | 1.1374 | 18.1984 | 0.022748 | 0.022748
 | 5.41763 | 5.41763 | 86.6821 | 0.108353 | 0.108353
 | 9.63862 | 9.63862 | 154.218 | 0.192772 | 0.192772
 | 115.106 | 111.711 | 1787.38 | 2.23422 | 2.30212
 | 53.7255 | 53.7255 | 859.608 | 1.07451 | 1.07451
 | 9.46515 | 9.46515 | 151.442 | 0.189303 | 0.189303
 | 8.88207 | 8.88207 | 142.113 | 0.177641 | 0.177641
 | 2.91371 | 2.91371 | 46.6193 | 0.0582742 | 0.0582742
 | 54.3399 | 54.3399 | 869.439 | 1.0868 | 1.0868
 | 36.4609 | 36.4609 | 583.375 | 0.729219 | 0.729219
 | 24.4252 | 24.4252 | 390.804 | 0.488504 | 0.488504
 | 53.8677 | 53.8677 | 861.884 | 1.07735 | 1.07735
 | 53.5495 | 53.5495 | 856.793 | 1.07099 | 1.07099
 | 24.4256 | 24.4256 | 390.81 | 0.488512 | 0.488512
 | 128.199 | 124.802 | 1996.84 | 2.49604 | 2.56398
 | 54.112 | 54.112 | 865.792 | 1.08224 | 1.08224
 | 5.99267 | 5.99267 | 95.8827 | 0.119853 | 0.119853
 | 13.1208 | 13.1208 | 209.933 | 0.262416 | 0.262416
2 x  | 53.676 | 53.676 | 858.816 | 1.07352 | 1.07352
 | 56.1921 | 56.1921 | 899.073 | 1.12384 | 1.12384
 | 52.1743 | 52.1743 | 834.789 | 1.04349 | 1.04349
 | 52.9305 | 52.9305 | 846.888 | 1.05861 | 1.05861
 | 81.8192 | 78.4242 | 1254.79 | 1.56848 | 1.63638
 | 6.67896 | 6.67896 | 106.863 | 0.133579 | 0.133579
 | 14.3519 | 14.3519 | 229.631 | 0.287039 | 0.287039
 | 36.5161 | 36.5161 | 584.257 | 0.730321 | 0.730321
 | 84.5826 | 81.1861 | 1298.98 | 1.62372 | 1.69165
 | 1.3504 | 1.3504 | 21.6064 | 0.027008 | 0.027008
2 x  | 2.66001 | 2.66001 | 42.5601 | 0.0532001 | 0.0532001
 | 23.28 | 23.28 | 372.48 | 0.4656 | 0.4656
 | 7.82 | 7.82 | 125.12 | 0.1564 | 0.1564
 | 1.29074 | 1.29074 | 20.6519 | 0.0258148 | 0.0258148
 | 10.4116 | 10.4116 | 166.585 | 0.208231 | 0.208231
 | 16.2995 | 16.2995 | 260.792 | 0.32599 | 0.32599
 | 35.8275 | 35.8275 | 573.24 | 0.716551 | 0.716551
 | 5.3591 | 5.3591 | 85.7456 | 0.107182 | 0.107182
 | 9.35587 | 9.35587 | 149.694 | 0.187117 | 0.187117
 | 9.17076 | 9.17076 | 146.732 | 0.183415 | 0.183415
 | 7.80484 | 7.80484 | 124.877 | 0.156097 | 0.156097
 | 9.40481 | 9.40481 | 150.477 | 0.188096 | 0.188096
 | 40.5449 | 40.5449 | 648.719 | 0.810898 | 0.810898
 | 4.68307 | 4.68307 | 74.9291 | 0.0936614 | 0.0936614
 | 51.1786 | 51.1786 | 818.858 | 1.02357 | 1.02357
 | 9.48986 | 9.48986 | 151.838 | 0.189797 | 0.189797
 | 14.7827 | 14.7827 | 236.523 | 0.295654 | 0.295654
2 x  | 1.72725 | 1.72725 | 27.6359 | 0.0345449 | 0.0345449
 | 11.8126 | 11.8126 | 189.002 | 0.236252 | 0.236252
 | 1.29004 | 1.29004 | 20.6406 | 0.0258007 | 0.0258007
 | 9.97514 | 9.97514 | 159.602 | 0.199503 | 0.199503
 | 31.2025 | 31.2025 | 499.241 | 0.624051 | 0.624051
 | 17.4159 | 17.4159 | 278.654 | 0.348317 | 0.348317
2 x  | 1.344 | 1.344 | 21.504 | 0.02688 | 0.02688
2 x  | 2.73424 | 2.73424 | 43.7478 | 0.0546848 | 0.0546848
 | 2.74726 | 2.74726 | 43.9562 | 0.0549452 | 0.0549452
 | 7.41428 | 7.41428 | 118.628 | 0.148286 | 0.148286
 | 7.26189 | 7.26189 | 116.19 | 0.145238 | 0.145238
 | 7.276 | 7.276 | 116.416 | 0.14552 | 0.14552
2 x  | 1.48 | 1.48 | 23.68 | 0.0296 | 0.0296
 | 36.3599 | 36.3599 | 581.759 | 0.727199 | 0.727199
 | 4.9952 | 4.9952 | 79.9232 | 0.099904 | 0.099904
 | 46.5792 | 46.5792 | 745.267 | 0.931584 | 0.931584
 | 1.76401 | 1.76401 | 28.2241 | 0.0352801 | 0.0352801
 | 1.764 | 1.764 | 28.2241 | 0.0352801 | 0.0352801
 | 1.22003 | 1.22003 | 19.5205 | 0.0244007 | 0.0244007
 | 1.22245 | 1.22245 | 19.5591 | 0.0244489 | 0.0244489
 | 1.44767 | 1.44767 | 23.1628 | 0.0289535 | 0.0289535
 | 1.44758 | 1.44758 | 23.1613 | 0.0289516 | 0.0289516
 | 2.28896 | 2.28896 | 36.6233 | 0.0457791 | 0.0457791
 | 82.7012 | 82.7012 | 1323.22 | 1.65402 | 1.65402
18 x Bankjes | 0.01732 | 0.01732 | 0.27712 | 0.0003464 | 0.0003464

# IfcCovering: ALG - ALGEMEEN 40 (2)
In: Begane grond
Type - PredefinedType: ROOFING
Classification: Dakafwerking (ARCHICAD Classification); 47 Dakafwerkingen (NL/SfB (4 cijfers)); Material: ALG - ALGEMEEN
Pset_CoveringCommon - Material: ALG - ALGEMEEN
CPset_Phasing - Renovation Phase: Bestaand
AC_Pset_RenovationAndPhasing - Renovation Status: Existing
Material Properties - ALG - ALGEMEEN, ThermalConductivity: 0.27; ALG - ALGEMEEN, SpecificHeatCapacity: 840 J/kg/K; ALG - ALGEMEEN, MassDensity: 800 kg/m3; ALG - ALGEMEEN, Embodied Energy: 2 (MJ/kg); ALG - ALGEMEEN, Embodied Carbon: 0.13 (kgCO₂/kg); ALG - ALGEMEEN, Name: ALG - ALGEMEEN; ALG - ALGEMEEN, Participates in Collision Detection: yes
Component Quantities - ALG - ALGEMEEN, Component Thickness: 40 mm
Name | GrossArea (m2) = NetArea (m2) = ALG - ALGEMEEN, Projected Component Area (Net) (m2) = ALG - ALGEMEEN, Projected Component Area (Gross) (m2) | ALG - ALGEMEEN, Mass (kg) | ALG - ALGEMEEN, Component Volume (Net) (m3) = ALG - ALGEMEEN, Component Volume (Gross) (m3)
 | 12.6 | 403.2 | 0.504
 | 21.6 | 691.2 | 0.864

# IfcCovering: ALG - ALGEMEEN 5 (67)
Type - PredefinedType: ROOFING
Classification: Dakafwerking (ARCHICAD Classification); 47 Dakafwerkingen (NL/SfB (4 cijfers)); Material: ALG - ALGEMEEN
Pset_CoveringCommon - Material: ALG - ALGEMEEN
CPset_Phasing - Renovation Phase: Bestaand
AC_Pset_RenovationAndPhasing - Renovation Status: Existing
Material Properties - ALG - ALGEMEEN, ThermalConductivity: 0.27; ALG - ALGEMEEN, SpecificHeatCapacity: 840 J/kg/K; ALG - ALGEMEEN, MassDensity: 800 kg/m3; ALG - ALGEMEEN, Embodied Energy: 2 (MJ/kg); ALG - ALGEMEEN, Embodied Carbon: 0.13 (kgCO₂/kg); ALG - ALGEMEEN, Name: ALG - ALGEMEEN; ALG - ALGEMEEN, Participates in Collision Detection: yes
Component Quantities - ALG - ALGEMEEN, Component Thickness: 5 mm
Name | In | GrossArea (m2) = NetArea (m2) = ALG - ALGEMEEN, Projected Component Area (Net) (m2) = ALG - ALGEMEEN, Projected Component Area (Gross) (m2) | ALG - ALGEMEEN, Mass (kg) | ALG - ALGEMEEN, Component Volume (Net) (m3) = ALG - ALGEMEEN, Component Volume (Gross) (m3)
sanitaire ruimte | Begane grond | 17.8892 | 71.5567 | 0.0894459
Schoonloopmat | Begane grond | 8.34544 | 33.3818 | 0.0417272
Schoonloopmat | Begane grond | 23.5704 | 94.2817 | 0.117852
Tapijt | Begane grond | 17.4156 | 69.6624 | 0.087078
2 x sanitaire ruimte | Begane grond | 1.6132 | 6.4528 | 0.008066
Tapijt | Begane grond | 13.1208 | 52.4832 | 0.065604
sanitaire ruimte | Begane grond | 7.64856 | 30.5943 | 0.0382428
sanitaire ruimte | Begane grond | 5.08412 | 20.3365 | 0.0254206
2 x sanitaire ruimte | Begane grond | 4.60351 | 18.414 | 0.0230176
Schoonloopmat | Begane grond | 9.9974 | 39.9896 | 0.049987
Tapijt | Begane grond | 12.76 | 51.0401 | 0.0638002
sanitaire ruimte | Begane grond | 6.14876 | 24.595 | 0.0307438
Schoonloopmat | Begane grond | 6.21791 | 24.8716 | 0.0310895
Tapijt | Begane grond | 14.3519 | 57.4078 | 0.0717597
Tapijt | Begane grond | 12.4701 | 49.8803 | 0.0623504
sanitaire ruimte | Begane grond | 9.33973 | 37.3589 | 0.0466986
sanitaire ruimte | Begane grond | 13.3545 | 53.418 | 0.0667725
sanitaire ruimte | Begane grond | 14.3953 | 57.5812 | 0.0719765
sanitaire ruimte | Begane grond | 4.57527 | 18.3011 | 0.0228763
sanitaire ruimte | Begane grond | 4.8796 | 19.5184 | 0.024398
sanitaire ruimte | Begane grond | 3.6322 | 14.5288 | 0.018161
sanitaire ruimte | Begane grond | 9.63862 | 38.5545 | 0.0481931
Schoonloopmat | Begane grond | 9.37817 | 37.5127 | 0.0468908
sanitaire ruimte | Begane grond | 16.2991 | 65.1964 | 0.0814955
sanitaire ruimte | Begane grond | 17.6294 | 70.5174 | 0.0881468
sanitaire ruimte | Begane grond | 5.359 | 21.436 | 0.026795
sanitaire ruimte | Begane grond | 11.0566 | 44.2265 | 0.0552832
sanitaire ruimte | Begane grond | 10.8716 | 43.4865 | 0.0543581
sanitaire ruimte | Begane grond | 10.5797 | 42.3189 | 0.0528986
sanitaire ruimte | Begane grond | 11.987 | 47.9478 | 0.0599348
sanitaire ruimte | Begane grond | 40.5449 | 162.18 | 0.202725
sanitaire ruimte | Begane grond | 4.68307 | 18.7323 | 0.0234153
sanitaire ruimte | Begane grond | 51.596 | 206.384 | 0.25798
sanitaire ruimte | Begane grond | 129.643 | 518.574 | 0.648217
sanitaire ruimte | Begane grond | 9.48981 | 37.9593 | 0.0474491
sanitaire ruimte | Begane grond | 14.7827 | 59.1308 | 0.0739135
2 x sanitaire ruimte | Begane grond | 1.72725 | 6.90898 | 0.00863623
Vloercoating | Begane grond | 14.883 | 59.5321 | 0.0744151
sanitaire ruimte | Begane grond | 12.1239 | 48.4957 | 0.0606196
sanitaire ruimte | Begane grond | 1.29004 | 5.16015 | 0.00645018
sanitaire ruimte | Begane grond | 1.29 | 5.16 | 0.00645
sanitaire ruimte | Begane grond | 9.97514 | 39.9005 | 0.0498757
sanitaire ruimte | Begane grond | 9.97498 | 39.8999 | 0.0498749
sanitaire ruimte | Begane grond | 1.29003 | 5.16013 | 0.00645017
sanitaire ruimte | Begane grond | 1.28999 | 5.15998 | 0.00644997
sanitaire ruimte | Begane grond | 27.675 | 110.7 | 0.138375
sanitaire ruimte | Begane grond | 8.15128 | 32.6051 | 0.0407564
2 x sanitaire ruimte | Begane grond | 19.785 | 79.14 | 0.098925
2 x sanitaire ruimte | Begane grond | 4.64063 | 18.5625 | 0.0232031
sanitaire ruimte | Begane grond | 26.5493 | 106.197 | 0.132746
Vloercoating | Begane grond | 0.99 | 3.96 | 0.00495
Vloercoating | Begane grond | 3.54355 | 14.1742 | 0.0177178
Tapijt | Begane grond | 14.7189 | 58.8755 | 0.0735944
Tapijt | Begane grond | 31.2025 | 124.81 | 0.156013
Vloercoating | Begane grond | 1.11601 | 4.46404 | 0.00558005
sanitaire ruimte | Begane grond | 27.6744 | 110.698 | 0.138372
sanitaire ruimte | Begane grond | 8.15225 | 32.609 | 0.0407612
2 x sanitaire ruimte | Begane grond | 9.8265 | 39.306 | 0.0491325
sanitaire ruimte | Begane grond | 26.5493 | 106.197 | 0.132747
Vloercoating | Begane grond | 19.7063 | 78.8253 | 0.0985317
Dakvloer | 1e verdieping | 129.57 | 518.279 | 0.647848

# IfcCovering: ALG - ALGEMEEN 50, Dakafwerking
In: Begane grond
Type - PredefinedType: ROOFING
Classification: Dakafwerking (ARCHICAD Classification); 47 Dakafwerkingen (NL/SfB (4 cijfers)); Material: ALG - ALGEMEEN
Pset_CoveringCommon - Material: ALG - ALGEMEEN
CPset_Phasing - Renovation Phase: Bestaand
AC_Pset_RenovationAndPhasing - Renovation Status: Existing
Material Properties - ALG - ALGEMEEN, ThermalConductivity: 0.27; ALG - ALGEMEEN, SpecificHeatCapacity: 840 J/kg/K; ALG - ALGEMEEN, MassDensity: 800 kg/m3; ALG - ALGEMEEN, Embodied Energy: 2 (MJ/kg); ALG - ALGEMEEN, Embodied Carbon: 0.13 (kgCO₂/kg); ALG - ALGEMEEN, Name: ALG - ALGEMEEN; ALG - ALGEMEEN, Participates in Collision Detection: yes
BaseQuantities - GrossArea: 0.55 m2; NetArea: 0.5445 m2
Component Quantities - ALG - ALGEMEEN, Mass: 21.78 kg; ALG - ALGEMEEN, Projected Component Area (Net): 0.5445 m2; ALG - ALGEMEEN, Projected Component Area (Gross): 0.5445 m2; ALG - ALGEMEEN, Component Thickness: 50 mm; ALG - ALGEMEEN, Component Volume (Net): 0.027225 m3; ALG - ALGEMEEN, Component Volume (Gross): 0.027225 m3

# IfcCovering: ALG - ALGEMEEN 600 (5)
In: Begane grond
Type - PredefinedType: ROOFING
Classification: Dakafwerking (ARCHICAD Classification); 47 Dakafwerkingen (NL/SfB (4 cijfers)); Material: ALG - ALGEMEEN
Pset_CoveringCommon - Material: ALG - ALGEMEEN
CPset_Phasing - Renovation Phase: Bestaand
AC_Pset_RenovationAndPhasing - Renovation Status: Existing
Material Properties - ALG - ALGEMEEN, ThermalConductivity: 0.27; ALG - ALGEMEEN, SpecificHeatCapacity: 840 J/kg/K; ALG - ALGEMEEN, MassDensity: 800 kg/m3; ALG - ALGEMEEN, Embodied Energy: 2 (MJ/kg); ALG - ALGEMEEN, Embodied Carbon: 0.13 (kgCO₂/kg); ALG - ALGEMEEN, Name: ALG - ALGEMEEN; ALG - ALGEMEEN, Participates in Collision Detection: yes
Component Quantities - ALG - ALGEMEEN, Component Thickness: 600 mm
Name | GrossArea (m2) | NetArea (m2) = ALG - ALGEMEEN, Projected Component Area (Net) (m2) = ALG - ALGEMEEN, Projected Component Area (Gross) (m2) | ALG - ALGEMEEN, Mass (kg) | ALG - ALGEMEEN, Component Volume (Net) (m3) = ALG - ALGEMEEN, Component Volume (Gross) (m3)
2 x LK cf inst. adv. | 0.249634 | 0.249634 | 119.825 | 0.149781
lestijden/geluid cf inst. adv. | 0.25 | 0.25 | 120 | 0.15
LK cf inst. adv. | 0.249634 | 0.249619 | 119.817 | 0.149772
LK cf inst. adv. | 0.248202 | 0.248202 | 119.137 | 0.148921

# IfcCovering: Hout - MDF binnenzijde 10 (2)
In: Begane grond
Type - PredefinedType: ROOFING
Classification: Dakafwerking (ARCHICAD Classification); 47 Dakafwerkingen (NL/SfB (4 cijfers)); Material: Hout - MDF binnenzijde
Pset_CoveringCommon - Material: Hout - MDF binnenzijde
CPset_Phasing - Renovation Phase: Bestaand
AC_Pset_RenovationAndPhasing - Renovation Status: Existing
Material Properties - Hout - MDF binnenzijde, ThermalConductivity: 0.24; Hout - MDF binnenzijde, SpecificHeatCapacity: 1600 J/kg/K; Hout - MDF binnenzijde, MassDensity: 1000 kg/m3; Hout - MDF binnenzijde, Embodied Energy: 16.8 (MJ/kg); Hout - MDF binnenzijde, Embodied Carbon: 0.87 (kgCO₂/kg); Hout - MDF binnenzijde, Name: Hout - MDF binnenzijde; Hout - MDF binnenzijde, Participates in Collision Detection: yes
BaseQuantities - GrossArea: 0.187 m2; NetArea: 0.017 m2
Component Quantities - Hout - MDF binnenzijde, Mass: 0.17 kg; Hout - MDF binnenzijde, Projected Component Area (Net): 0.017 m2; Hout - MDF binnenzijde, Projected Component Area (Gross): 0.017 m2; Hout - MDF binnenzijde, Component Thickness: 10 mm; Hout - MDF binnenzijde, Component Volume (Net): 0.00017 m3; Hout - MDF binnenzijde, Component Volume (Gross): 0.00017 m3

# IfcCovering: Hout - MDF binnenzijde 20
In: Begane grond
Type - PredefinedType: ROOFING
Classification: Dakafwerking (ARCHICAD Classification); 47 Dakafwerkingen (NL/SfB (4 cijfers)); Material: Hout - MDF binnenzijde
Pset_CoveringCommon - Material: Hout - MDF binnenzijde
CPset_Phasing - Renovation Phase: Bestaand
AC_Pset_RenovationAndPhasing - Renovation Status: Existing
Material Properties - Hout - MDF binnenzijde, ThermalConductivity: 0.24; Hout - MDF binnenzijde, SpecificHeatCapacity: 1600 J/kg/K; Hout - MDF binnenzijde, MassDensity: 1000 kg/m3; Hout - MDF binnenzijde, Embodied Energy: 16.8 (MJ/kg); Hout - MDF binnenzijde, Embodied Carbon: 0.87 (kgCO₂/kg); Hout - MDF binnenzijde, Name: Hout - MDF binnenzijde; Hout - MDF binnenzijde, Participates in Collision Detection: yes
BaseQuantities - GrossArea: 0.3776 m2; NetArea: 0.3776 m2
Component Quantities - Hout - MDF binnenzijde, Mass: 7.552 kg; Hout - MDF binnenzijde, Projected Component Area (Net): 0.3776 m2; Hout - MDF binnenzijde, Projected Component Area (Gross): 0.3776 m2; Hout - MDF binnenzijde, Component Thickness: 20 mm; Hout - MDF binnenzijde, Component Volume (Net): 0.007552 m3; Hout - MDF binnenzijde, Component Volume (Gross): 0.007552 m3

# IfcCovering: Hout - gevel 15 (5)
In: 1e verdieping
Type - PredefinedType: ROOFING
Classification: Dakafwerking (ARCHICAD Classification); 47 Dakafwerkingen (NL/SfB (4 cijfers)); Material: Hout - gevel
Pset_CoveringCommon - Material: Hout - gevel
CPset_Phasing - Renovation Phase: Bestaand
AC_Pset_RenovationAndPhasing - Renovation Status: Existing
Material Properties - Hout - gevel, ThermalConductivity: 0.14; Hout - gevel, SpecificHeatCapacity: 1880 J/kg/K; Hout - gevel, MassDensity: 550 kg/m3; Hout - gevel, Embodied Energy: 7.4 (MJ/kg); Hout - gevel, Embodied Carbon: 0.19 (kgCO₂/kg); Hout - gevel, Name: Hout - gevel; Hout - gevel, Participates in Collision Detection: yes
Component Quantities - Hout - gevel, Component Thickness: 15 mm
Name | GrossArea (m2) | NetArea (m2) = Hout - gevel, Projected Component Area (Net) (m2) = Hout - gevel, Projected Component Area (Gross) (m2) | Hout - gevel, Mass (kg) | Hout - gevel, Component Volume (Net) (m3) = Hout - gevel, Component Volume (Gross) (m3)
 | 143.451 | 142.949 | 1179.33 | 2.14423
 | 1.49519 | 1.41156 | 11.6454 | 0.0211734
 | 136.708 | 136.708 | 1127.84 | 2.05062
 | 0.3819 | 0.3819 | 3.15068 | 0.0057285
 | 4.8348 | 4.65738 | 38.4234 | 0.0698607

# IfcCovering: Hout - gevel 950 (3)
In: Begane grond
Type - PredefinedType: ROOFING
Classification: Dakafwerking (ARCHICAD Classification); 47 Dakafwerkingen (NL/SfB (4 cijfers)); Material: Hout - gevel
Pset_CoveringCommon - Material: Hout - gevel
CPset_Phasing - Renovation Phase: Bestaand
AC_Pset_RenovationAndPhasing - Renovation Status: Existing
Material Properties - Hout - gevel, ThermalConductivity: 0.14; Hout - gevel, SpecificHeatCapacity: 1880 J/kg/K; Hout - gevel, MassDensity: 550 kg/m3; Hout - gevel, Embodied Energy: 7.4 (MJ/kg); Hout - gevel, Embodied Carbon: 0.19 (kgCO₂/kg); Hout - gevel, Name: Hout - gevel; Hout - gevel, Participates in Collision Detection: yes
Component Quantities - Hout - gevel, Component Thickness: 950 mm
Name | GrossArea (m2) | NetArea (m2) = Hout - gevel, Projected Component Area (Net) (m2) = Hout - gevel, Projected Component Area (Gross) (m2) | Hout - gevel, Mass (kg) | Hout - gevel, Component Volume (Net) (m3) = Hout - gevel, Component Volume (Gross) (m3)
 | 5.259 | 5.259 | 2747.83 | 4.99605
 | 2.43009 | 2.43006 | 1269.71 | 2.30856
 | 2.42988 | 2.42988 | 1269.61 | 2.30839

# IfcCovering: Hout geperforeerde plaat 20 (5)
In: Begane grond
Type - PredefinedType: ROOFING
Classification: Dakafwerking (ARCHICAD Classification); 47 Dakafwerkingen (NL/SfB (4 cijfers)); Material: Hout geperforeerde plaat
Pset_CoveringCommon - Material: Hout geperforeerde plaat
CPset_Phasing - Renovation Phase: Bestaand
AC_Pset_RenovationAndPhasing - Renovation Status: Existing
Material Properties - Hout geperforeerde plaat, ThermalConductivity: 0.14; Hout geperforeerde plaat, SpecificHeatCapacity: 1880 J/kg/K; Hout geperforeerde plaat, MassDensity: 550 kg/m3; Hout geperforeerde plaat, Embodied Energy: 7.4 (MJ/kg); Hout geperforeerde plaat, Embodied Carbon: 0.19 (kgCO₂/kg); Hout geperforeerde plaat, Name: Hout geperforeerde plaat; Hout geperforeerde plaat, Participates in Collision Detection: yes
Component Quantities - Hout geperforeerde plaat, Component Thickness: 20 mm
Name | GrossArea (m2) | NetArea (m2) = Hout geperforeerde plaat, Projected Component Area (Net) (m2) = Hout geperforeerde plaat, Projected Component Area (Gross) (m2) | Hout geperforeerde plaat, Mass (kg) | Hout geperforeerde plaat, Component Volume (Net) (m3) = Hout geperforeerde plaat, Component Volume (Gross) (m3)
 | 2.95127 | 2.93692 | 32.3061 | 0.0587384
 | 1.96268 | 1.96268 | 21.5894 | 0.0392535
 | 2.24477 | 2.24477 | 24.6925 | 0.0448954
 | 3.14378 | 3.14378 | 34.5815 | 0.0628755
 | 6.36323 | 6.36323 | 69.9955 | 0.127265

# IfcCovering: Tegels - Bestrating 100 (2)
In: Begane grond
Type - PredefinedType: ROOFING
Classification: Dakafwerking (ARCHICAD Classification); 47 Dakafwerkingen (NL/SfB (4 cijfers)); Material: Tegels - Bestrating
Pset_CoveringCommon - Material: Tegels - Bestrating
CPset_Phasing - Renovation Phase: Bestaand
AC_Pset_RenovationAndPhasing - Renovation Status: Existing
Material Properties - Tegels - Bestrating, ThermalConductivity: 1.3; Tegels - Bestrating, SpecificHeatCapacity: 840 J/kg/K; Tegels - Bestrating, MassDensity: 2300 kg/m3; Tegels - Bestrating, Embodied Energy: 10 (MJ/kg); Tegels - Bestrating, Embodied Carbon: 0.7 (kgCO₂/kg); Tegels - Bestrating, Name: Tegels - Bestrating; Tegels - Bestrating, Participates in Collision Detection: yes
Component Quantities - Tegels - Bestrating, Component Thickness: 100 mm
Name | GrossArea (m2) | NetArea (m2) | Tegels - Bestrating, Mass (kg) | Tegels - Bestrating, Projected Component Area (Net) (m2) = Tegels - Bestrating, Projected Component Area (Gross) (m2) | Tegels - Bestrating, Component Volume (Net) (m3) = Tegels - Bestrating, Component Volume (Gross) (m3)
vloeren terras | 38.2196 | 38.2196 | 8790.51 | 38.2196 | 3.82196
vloeren terras | 131.621 | 131.27 | 30187.7 | 131.289 | 13.1251

# IfcDistributionElement: Brandslang haspelkast 25 (5)
In: Begane grond
Classification: Installaties (ARCHICAD Classification); 65 Beveiliging (NL/SfB (4 cijfers))
CPset_Phasing - Renovation Phase: Bestaand
AC_Pset_RenovationAndPhasing - Renovation Status: Existing
Component Quantities - Component, Component Volume (Net): 0.0384999 m3; Component, Component Volume (Gross): 0.0384999 m3

# IfcDistributionElement: Douche armatuur 25 (3)
In: Begane grond
Classification: 74 Vaste sanitaire voorzieningen (NL/SfB (4 cijfers)); Installaties (ARCHICAD Classification)
CPset_Phasing - Renovation Phase: Bestaand
AC_Pset_RenovationAndPhasing - Renovation Status: Existing
Component Quantities - Component, Component Volume (Net): 0.00195224 m3; Component, Component Volume (Gross): 0.00195224 m3

# IfcDistributionElement: Droger 25, hart
In: KC
Classification: 74 Vaste sanitaire voorzieningen (NL/SfB (4 cijfers)); Installaties (ARCHICAD Classification)
CPset_Phasing - Renovation Phase: Bestaand
AC_Pset_RenovationAndPhasing - Renovation Status: Existing
Component Quantities - Component, Component Volume (Net): 0.0187356 m3; Component, Component Volume (Gross): 0.0187356 m3

# IfcDistributionElement: Invalidentoilet 25 (3)
In: Begane grond
Classification: 74 Vaste sanitaire voorzieningen (NL/SfB (4 cijfers)); Installaties (ARCHICAD Classification)
CPset_Phasing - Renovation Phase: Bestaand
AC_Pset_RenovationAndPhasing - Renovation Status: Existing
Component Quantities - Component, Component Volume (Net): 0.0171895 m3; Component, Component Volume (Gross): 0.0171895 m3

# IfcDistributionElement: Kraan 25 (4)
In: Begane grond
Classification: 74 Vaste sanitaire voorzieningen (NL/SfB (4 cijfers)); Installaties (ARCHICAD Classification)
CPset_Phasing - Renovation Phase: Bestaand
AC_Pset_RenovationAndPhasing - Renovation Status: Existing
Component Quantities - Component, Component Volume (Net): 0.000352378 m3; Component, Component Volume (Gross): 0.000352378 m3

# IfcDistributionElement: Toilet 25 (26)
In: Begane grond
CPset_Phasing - Renovation Phase: Bestaand
AC_Pset_RenovationAndPhasing - Renovation Status: Existing
Name | Classification | Component, Component Volume (Net) (m3) = Component, Component Volume (Gross) (m3)
6 x Geberit 300 Toilet | 74 Vaste sanitaire voorzieningen (NL/SfB (4 cijfers)); Installaties (ARCHICAD Classification); 74 Vaste sanitaire voorzieningen (NL/SfB (2 cijfers)); 74 VASTE SANITAIRE VOORZIENINGEN (EcoQuaestor) | 0.0077401
9 x Geberit 300 Toilet | 74 Vaste sanitaire voorzieningen (NL/SfB (4 cijfers)); Installaties (ARCHICAD Classification) | 0.0100329
4 x Geberit 300 Toilet | 74 Vaste sanitaire voorzieningen (NL/SfB (4 cijfers)); Installaties (ARCHICAD Classification); 74 Vaste sanitaire voorzieningen (NL/SfB (2 cijfers)); 74 VASTE SANITAIRE VOORZIENINGEN (EcoQuaestor) | 0.0103977
7 x Geberit 300 Toilet | 74 Vaste sanitaire voorzieningen (NL/SfB (4 cijfers)); Installaties (ARCHICAD Classification); 74 Vaste sanitaire voorzieningen (NL/SfB (2 cijfers)); 74 VASTE SANITAIRE VOORZIENINGEN (EcoQuaestor) | 0.00835087

# IfcDistributionElement: Uitstortgootsteen 25 (3)
Classification: 74 Vaste sanitaire voorzieningen (NL/SfB (4 cijfers)); Installaties (ARCHICAD Classification)
CPset_Phasing - Renovation Phase: Bestaand
AC_Pset_RenovationAndPhasing - Renovation Status: Existing
Component Quantities - Component, Component Volume (Net): 0.0443912 m3; Component, Component Volume (Gross): 0.0443912 m3
Name | In
Uitstortgootsteen 365x460mm | KANT
Uitstortgootsteen 365x460mm | KC
Uitstortgootsteen 365x460mm | GYM

# IfcDistributionElement: Urinoir 25 (3)
In: Begane grond
Classification: 74 Vaste sanitaire voorzieningen (NL/SfB (4 cijfers)); Installaties (ARCHICAD Classification)
CPset_Phasing - Renovation Phase: Bestaand
AC_Pset_RenovationAndPhasing - Renovation Status: Existing
Component Quantities - Component, Component Volume (Net): 0 m3; Component, Component Volume (Gross): 0 m3

# IfcDistributionElement: Vaatwasser inbouw 25 (3)
Classification: 74 Vaste sanitaire voorzieningen (NL/SfB (4 cijfers)); Installaties (ARCHICAD Classification)
CPset_Phasing - Renovation Phase: Bestaand
AC_Pset_RenovationAndPhasing - Renovation Status: Existing
Name | In | Component, Component Volume (Net) (m3) = Component, Component Volume (Gross) (m3)
2 x Aanrechtblok KDV | KC | 0.0948346
Aanrechtblok KDV | KDV/ POV | 0.0928866

# IfcDistributionElement: Wasbak 2 25 KM (3)
In: Begane grond
Classification: 74 Vaste sanitaire voorzieningen (NL/SfB (4 cijfers)); Installaties (ARCHICAD Classification)
CPset_Phasing - Renovation Phase: Bestaand
AC_Pset_RenovationAndPhasing - Renovation Status: Existing
Component Quantities - Component, Component Volume (Net): 0.0000128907 m3; Component, Component Volume (Gross): 0.0000128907 m3

# IfcDistributionElement: Wasbak 25 (23)
In: Begane grond
Classification: 74 Vaste sanitaire voorzieningen (NL/SfB (4 cijfers)); Installaties (ARCHICAD Classification)
CPset_Phasing - Renovation Phase: Bestaand
AC_Pset_RenovationAndPhasing - Renovation Status: Existing
Component Quantities - Component, Component Volume (Net): 0.000197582 m3; Component, Component Volume (Gross): 0.000197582 m3

# IfcDistributionElement: Wasbak meervoudig 25 (2)
In: Begane grond
Classification: 74 Vaste sanitaire voorzieningen (NL/SfB (4 cijfers)); Installaties (ARCHICAD Classification)
CPset_Phasing - Renovation Phase: Bestaand
AC_Pset_RenovationAndPhasing - Renovation Status: Existing
Component Quantities - Component, Component Volume (Net): 0.0087 m3; Component, Component Volume (Gross): 0.0087 m3

# IfcDistributionElement: Wasmachine 25, hart
In: KC
Classification: 74 Vaste sanitaire voorzieningen (NL/SfB (4 cijfers)); Installaties (ARCHICAD Classification)
CPset_Phasing - Renovation Phase: Bestaand
AC_Pset_RenovationAndPhasing - Renovation Status: Existing
Component Quantities - Component, Component Volume (Net): 0.0504689 m3; Component, Component Volume (Gross): 0.0504689 m3

# IfcDistributionElement: Zonnepaneel 25 (148)
Classification: 74 Vaste sanitaire voorzieningen (NL/SfB (4 cijfers)); Installaties (ARCHICAD Classification)
CPset_Phasing - Renovation Phase: Bestaand
AC_Pset_RenovationAndPhasing - Renovation Status: Existing
Name | In | Component, Component Volume (Net) (m3) = Component, Component Volume (Gross) (m3)
2 x PV-panelen | 1e verdieping | 0.0446284
2 x PV-panelen | 1e verdieping | 0.357028
78 x PV-panelen | 1e verdieping | 0.0892569
6 x PV-panelen | 1e verdieping | 0.267771
32 x PV-panelen | 1e verdieping | 0.133885
4 x PV-panelen | 1e verdieping | 0.178514
4 x PV-panelen | 1e verdieping | 0.535541
12 x PV-panelen | 1e verdieping | 0.223142
2 x PV-panelen | Dak | 0.446284
6 x PV-panelen | Dak | 0.401656

# IfcDoor: D1 25, b1.18
In: Begane grond
Type - OperationType: DOUBLE_SWING_RIGHT; ParameterTakesPrecedence: no; Sizeable: no
Type - Door Lining Properties - LiningDepth: 114 mm; LiningThickness: 67 mm; LiningOffset: -100 mm
Type - Door Panel Properties - Panel 1 - PanelDepth: 40 mm; PanelOperation: DOUBLE_ACTING; PanelWidth: 1; PanelPosition: MIDDLE
OverallHeight: 2377 mm; OverallWidth: 1118 mm; Classification: Deur (ARCHICAD Classification); 32 Binnenwandopeningen (NL/SfB (4 cijfers))
Pset_DoorCommon - AcousticRating: ---; GlazingAreaFraction: 0.67768; IsExternal: no
Material - Frame / Draaiend deel: arcering (01); Deurblad: arcering (02); Onderdorpel: %; Stofdorpel: arcering (01); Vensterbank: arcering (01); Ventilatierooster: %; Spouwlat: Naaldhout (01); Rollaag / Latei: arcering (01); Afwerking dagkant buiten: arcering (01); Afwerking dagkant binnen: arcering (01); Zonwering - behuizing: arcering (01); Zonwering - isolatie: Isolatie ruit; Glas: Glas - algemeen exterieur
Pset_FireRatingProperties - FireResistanceRating: ---
CPset_Phasing - Renovation Phase: Bestaand
AC_Pset_RenovationAndPhasing - Renovation Status: Existing
BaseQuantities - Height: 2377 mm; Width: 1118 mm; Perimeter: 6990 mm; Area: 2.65749 m2; Volume: 0.107916 m3; Depth: 200 mm; NetVolume: 0.107916 m3
Component Quantities - Component, Component Volume (Net): 0.107916 m3; Component, Component Volume (Gross): 0.107916 m3

# IfcDoor: D1 25, b1.15-sp
In: Begane grond
Type - OperationType: SINGLE_SWING_LEFT; ParameterTakesPrecedence: no; Sizeable: no
Type - Door Lining Properties - LiningDepth: 114 mm; LiningThickness: 67 mm; LiningOffset: -100 mm
Type - Door Panel Properties - Panel 1 - PanelDepth: 40 mm; PanelOperation: SWINGING; PanelWidth: 1; PanelPosition: MIDDLE
OverallHeight: 2377 mm; OverallWidth: 1034 mm; Classification: Deur (ARCHICAD Classification); 32 Binnenwandopeningen (NL/SfB (4 cijfers))
Pset_DoorCommon - AcousticRating: ---; IsExternal: no
Material - Frame / Draaiend deel: arcering (01); Deurblad: arcering (02); Onderdorpel: %; Stofdorpel: arcering (01); Vensterbank: arcering (01); Ventilatierooster: %; Spouwlat: Naaldhout (01); Rollaag / Latei: arcering (01); Afwerking dagkant buiten: arcering (01); Afwerking dagkant binnen: arcering (01); Zonwering - behuizing: arcering (01); Zonwering - isolatie: Isolatie ruit; Glas: Glas - algemeen exterieur
Pset_FireRatingProperties - FireResistanceRating: ---
CPset_Phasing - Renovation Phase: Bestaand
AC_Pset_RenovationAndPhasing - Renovation Status: Existing
BaseQuantities - Height: 2377 mm; Width: 1034 mm; Perimeter: 6822 mm; Area: 2.45782 m2; Volume: 0.12662 m3; Depth: 200 mm; NetVolume: 0.12662 m3
Component Quantities - Component, Component Volume (Net): 0.12662 m3; Component, Component Volume (Gross): 0.12662 m3

# IfcDoor: D1 25 (3)
In: Begane grond
Type - OperationType: SINGLE_SWING_LEFT; ParameterTakesPrecedence: no; Sizeable: no
Type - Door Lining Properties - LiningDepth: 114 mm; LiningThickness: 67 mm; LiningOffset: -114 mm
Type - Door Panel Properties - Panel 1 - PanelDepth: 40 mm; PanelOperation: SWINGING; PanelWidth: 1; PanelPosition: MIDDLE
OverallHeight: 2377 mm; OverallWidth: 1034 mm; Classification: Deur (ARCHICAD Classification); 32 Binnenwandopeningen (NL/SfB (4 cijfers))
Pset_DoorCommon - IsExternal: no
Material - Frame / Draaiend deel: arcering (01); Deurblad: arcering (02); Onderdorpel: %; Stofdorpel: arcering (01); Vensterbank: arcering (01); Ventilatierooster: %; Spouwlat: Naaldhout (01); Rollaag / Latei: arcering (01); Afwerking dagkant buiten: arcering (01); Afwerking dagkant binnen: arcering (01); Zonwering - behuizing: arcering (01); Zonwering - isolatie: Isolatie ruit; Glas: Glas - algemeen exterieur
Pset_FireRatingProperties - FireResistanceRating: ---
CPset_Phasing - Renovation Phase: Bestaand
AC_Pset_RenovationAndPhasing - Renovation Status: Existing
BaseQuantities - Height: 2377 mm; Width: 1034 mm; Perimeter: 6822 mm; Area: 2.45782 m2; Depth: 100 mm
Name | AcousticRating | Volume (m3) = NetVolume (m3) = Component, Component Volume (Net) (m3) = Component, Component Volume (Gross) (m3)
b1.05g | valdorpel | 0.075622 | Pset_DoorCommon - GlazingAreaFraction: 1.27496
b1.01-sp | --- | 0.12662
b1.13-sp | --- | 0.12662

# IfcDoor: D1 25 (6)
In: Begane grond
Type - OperationType: SINGLE_SWING_LEFT; ParameterTakesPrecedence: no; Sizeable: no
Type - Door Lining Properties - LiningDepth: 114 mm; LiningThickness: 67 mm; LiningOffset: -14 mm
Type - Door Panel Properties - Panel 1 - PanelDepth: 40 mm; PanelOperation: SWINGING; PanelWidth: 1; PanelPosition: MIDDLE
OverallHeight: 2377 mm; Classification: Deur (ARCHICAD Classification); 32 Binnenwandopeningen (NL/SfB (4 cijfers))
Pset_DoorCommon - AcousticRating: ---; IsExternal: no
Material - Frame / Draaiend deel: arcering (01); Deurblad: arcering (02); Onderdorpel: %; Stofdorpel: arcering (01); Vensterbank: arcering (01); Ventilatierooster: %; Spouwlat: Naaldhout (01); Rollaag / Latei: arcering (01); Afwerking dagkant buiten: arcering (01); Afwerking dagkant binnen: arcering (01); Zonwering - behuizing: arcering (01); Zonwering - isolatie: Isolatie ruit; Glas: Glas - algemeen exterieur
Pset_FireRatingProperties - FireResistanceRating: ---
CPset_Phasing - Renovation Phase: Bestaand
AC_Pset_RenovationAndPhasing - Renovation Status: Existing
BaseQuantities - Height: 2377 mm; Depth: 100 mm
Name | OverallWidth (mm) = Width (mm) | Perimeter (mm) | Area (m2) | Volume (m3) = NetVolume (m3) = Component, Component Volume (Net) (m3) = Component, Component Volume (Gross) (m3)
b1.01-sp | 1034 | 6822 | 2.45782 | 0.12662
b1.13-sp | 1034 | 6822 | 2.45782 | 0.12662
2 x b1.11-sp | 934 | 6622 | 2.22012 | 0.116616
b1.07-sp | 984 | 6722 | 2.33897 | 0.0740941 | Pset_DoorCommon - GlazingAreaFraction: 1.18811
b1.09-sp | 984 | 6722 | 2.33897 | 0.121618

# IfcDoor: D1 25, b1.16
In: Begane grond
Type - OperationType: SINGLE_SWING_LEFT; ParameterTakesPrecedence: no; Sizeable: no
Type - Door Lining Properties - LiningDepth: 114 mm; LiningThickness: 67 mm; LiningOffset: -200 mm
Type - Door Panel Properties - Panel 1 - PanelDepth: 40 mm; PanelOperation: SWINGING; PanelWidth: 1; PanelPosition: MIDDLE
OverallHeight: 2377 mm; OverallWidth: 1133.98 mm; Classification: Deur (ARCHICAD Classification); 32 Binnenwandopeningen (NL/SfB (4 cijfers))
Pset_DoorCommon - AcousticRating: ---; IsExternal: no
Material - Frame / Draaiend deel: arcering (01); Deurblad: arcering (02); Onderdorpel: %; Stofdorpel: arcering (01); Vensterbank: arcering (01); Ventilatierooster: %; Spouwlat: Naaldhout (01); Rollaag / Latei: arcering (01); Afwerking dagkant buiten: arcering (01); Afwerking dagkant binnen: arcering (01); Zonwering - behuizing: arcering (01); Zonwering - isolatie: Isolatie ruit; Glas: Glas - algemeen exterieur
Pset_FireRatingProperties - FireResistanceRating: ---
CPset_Phasing - Renovation Phase: Bestaand
AC_Pset_RenovationAndPhasing - Renovation Status: Existing
BaseQuantities - Height: 2377 mm; Width: 1133.98 mm; Perimeter: 7021.96 mm; Area: 2.69547 m2; Volume: 0.136622 m3; Depth: 200 mm; NetVolume: 0.136622 m3
Component Quantities - Component, Component Volume (Net): 0.136622 m3; Component, Component Volume (Gross): 0.136622 m3

# IfcDoor: D1 25 (2)
In: Begane grond
Type - OperationType: SINGLE_SWING_LEFT; ParameterTakesPrecedence: no; Sizeable: no
Type - Door Lining Properties - LiningDepth: 114 mm; LiningThickness: 67 mm; LiningOffset: -50 mm
Type - Door Panel Properties - Panel 1 - PanelDepth: 40 mm; PanelOperation: SWINGING; PanelWidth: 1; PanelPosition: MIDDLE
OverallHeight: 2377 mm; OverallWidth: 1034 mm; Classification: Deur (ARCHICAD Classification); 32 Binnenwandopeningen (NL/SfB (4 cijfers))
Pset_DoorCommon - AcousticRating: ---; IsExternal: no
Material - Frame / Draaiend deel: arcering (01); Deurblad: arcering (02); Onderdorpel: %; Stofdorpel: arcering (01); Vensterbank: arcering (01); Ventilatierooster: %; Spouwlat: Naaldhout (01); Rollaag / Latei: arcering (01); Afwerking dagkant buiten: arcering (01); Afwerking dagkant binnen: arcering (01); Zonwering - behuizing: arcering (01); Zonwering - isolatie: Isolatie ruit; Glas: Glas - algemeen exterieur
Pset_FireRatingProperties - FireResistanceRating: ---
CPset_Phasing - Renovation Phase: Bestaand
AC_Pset_RenovationAndPhasing - Renovation Status: Existing
BaseQuantities - Height: 2377 mm; Width: 1034 mm; Perimeter: 6822 mm; Area: 2.45782 m2; Volume: 0.12662 m3; Depth: 100 mm; NetVolume: 0.12662 m3
Component Quantities - Component, Component Volume (Net): 0.12662 m3; Component, Component Volume (Gross): 0.12662 m3

# IfcDoor: D1 25 (4)
In: Begane grond
Type - OperationType: SINGLE_SWING_LEFT; ParameterTakesPrecedence: no; Sizeable: no
Type - Door Lining Properties - LiningDepth: 114 mm; LiningThickness: 67 mm; LiningOffset: -64 mm
Type - Door Panel Properties - Panel 1 - PanelDepth: 40 mm; PanelOperation: SWINGING; PanelWidth: 1; PanelPosition: MIDDLE
OverallHeight: 2377 mm; OverallWidth: 1034 mm; Classification: Deur (ARCHICAD Classification); 32 Binnenwandopeningen (NL/SfB (4 cijfers))
Pset_DoorCommon - AcousticRating: ---; IsExternal: no
Material - Frame / Draaiend deel: arcering (01); Deurblad: arcering (02); Onderdorpel: %; Stofdorpel: arcering (01); Vensterbank: arcering (01); Ventilatierooster: %; Spouwlat: Naaldhout (01); Rollaag / Latei: arcering (01); Afwerking dagkant buiten: arcering (01); Afwerking dagkant binnen: arcering (01); Zonwering - behuizing: arcering (01); Zonwering - isolatie: Isolatie ruit; Glas: Glas - algemeen exterieur
Pset_FireRatingProperties - FireResistanceRating: ---
CPset_Phasing - Renovation Phase: Bestaand
AC_Pset_RenovationAndPhasing - Renovation Status: Existing
BaseQuantities - Height: 2377 mm; Width: 1034 mm; Perimeter: 6822 mm; Area: 2.45782 m2; Volume: 0.12662 m3; Depth: 100 mm; NetVolume: 0.12662 m3
Component Quantities - Component, Component Volume (Net): 0.12662 m3; Component, Component Volume (Gross): 0.12662 m3

# IfcDoor: D1 25 (7)
In: Begane grond
Type - OperationType: SINGLE_SWING_LEFT; ParameterTakesPrecedence: no; Sizeable: no
Type - Door Lining Properties - LiningDepth: 114 mm; LiningThickness: 67 mm; LiningOffset: 0 mm
Type - Door Panel Properties - Panel 1 - PanelDepth: 40 mm; PanelOperation: SWINGING; PanelWidth: 1; PanelPosition: MIDDLE
OverallHeight: 2377 mm; Classification: Deur (ARCHICAD Classification); 32 Binnenwandopeningen (NL/SfB (4 cijfers))
Pset_DoorCommon - IsExternal: no
Material - Frame / Draaiend deel: arcering (01); Deurblad: arcering (02); Onderdorpel: %; Stofdorpel: arcering (01); Vensterbank: arcering (01); Ventilatierooster: %; Spouwlat: Naaldhout (01); Rollaag / Latei: arcering (01); Afwerking dagkant buiten: arcering (01); Afwerking dagkant binnen: arcering (01); Zonwering - behuizing: arcering (01); Zonwering - isolatie: Isolatie ruit; Glas: Glas - algemeen exterieur
Pset_FireRatingProperties - FireResistanceRating: ---
CPset_Phasing - Renovation Phase: Bestaand
AC_Pset_RenovationAndPhasing - Renovation Status: Existing
BaseQuantities - Height: 2377 mm; Depth: 100 mm
Name | OverallWidth (mm) = Width (mm) | AcousticRating | Perimeter (mm) | Area (m2) | Volume (m3) = NetVolume (m3) = Component, Component Volume (Net) (m3) = Component, Component Volume (Gross) (m3)
b1.08g-sp | 984 | valdorpel | 6722 | 2.33897 | 0.11791 | Pset_DoorCommon - GlazingAreaFraction: 0.0902879
b1.04-sp | 1034 | --- | 6822 | 2.45782 | 0.075622 | Pset_DoorCommon - GlazingAreaFraction: 1.27496
3 x b1.01-sp | 1034 | --- | 6822 | 2.45782 | 0.12662
b1.12-sp | 984 | --- | 6722 | 2.33897 | 0.121618
b1.13-sp | 1034 | --- | 6822 | 2.45782 | 0.12662

# IfcDoor: D1 25, b1.14
In: Begane grond
Type - OperationType: SINGLE_SWING_LEFT; ParameterTakesPrecedence: no; Sizeable: no
Type - Door Lining Properties - LiningDepth: 114 mm; LiningThickness: 67 mm; LiningOffset: 36 mm
Type - Door Panel Properties - Panel 1 - PanelDepth: 40 mm; PanelOperation: SWINGING; PanelWidth: 1; PanelPosition: MIDDLE
OverallHeight: 2377 mm; OverallWidth: 1034 mm; Classification: Deur (ARCHICAD Classification); 32 Binnenwandopeningen (NL/SfB (4 cijfers))
Pset_DoorCommon - AcousticRating: ---; IsExternal: no
Material - Frame / Draaiend deel: arcering (01); Deurblad: arcering (02); Onderdorpel: %; Stofdorpel: arcering (01); Vensterbank: arcering (01); Ventilatierooster: %; Spouwlat: Naaldhout (01); Rollaag / Latei: arcering (01); Afwerking dagkant buiten: arcering (01); Afwerking dagkant binnen: arcering (01); Zonwering - behuizing: arcering (01); Zonwering - isolatie: Isolatie ruit; Glas: Glas - algemeen exterieur
Pset_FireRatingProperties - FireResistanceRating: ---
CPset_Phasing - Renovation Phase: Bestaand
AC_Pset_RenovationAndPhasing - Renovation Status: Existing
BaseQuantities - Height: 2377 mm; Width: 1034 mm; Perimeter: 6822 mm; Area: 2.45782 m2; Volume: 0.12662 m3; Depth: 150 mm; NetVolume: 0.12662 m3
Component Quantities - Component, Component Volume (Net): 0.12662 m3; Component, Component Volume (Gross): 0.12662 m3

# IfcDoor: D1 25, b1.17
In: Begane grond
Type - OperationType: SINGLE_SWING_LEFT; ParameterTakesPrecedence: no; Sizeable: no
Type - Door Lining Properties - LiningDepth: 120 mm; LiningThickness: 67 mm; LiningOffset: -56 mm
Type - Door Panel Properties - Panel 1 - PanelDepth: 40 mm; PanelOperation: SWINGING; PanelWidth: 1; PanelPosition: MIDDLE
OverallHeight: 2377 mm; OverallWidth: 1034 mm; Classification: Deur (ARCHICAD Classification); 32 Binnenwandopeningen (NL/SfB (4 cijfers))
Pset_DoorCommon - AcousticRating: ---; GlazingAreaFraction: 1.204; IsExternal: no
Material - Frame / Draaiend deel: arcering (01); Deurblad: arcering (02); Onderdorpel: %; Stofdorpel: arcering (01); Vensterbank: arcering (01); Ventilatierooster: %; Spouwlat: Naaldhout (01); Rollaag / Latei: arcering (01); Afwerking dagkant buiten: arcering (01); Afwerking dagkant binnen: arcering (01); Zonwering - behuizing: arcering (01); Zonwering - isolatie: Isolatie ruit; Glas: Glas - algemeen exterieur
Pset_FireRatingProperties - FireResistanceRating: ---
CPset_Phasing - Renovation Phase: Bestaand
AC_Pset_RenovationAndPhasing - Renovation Status: Existing
BaseQuantities - Height: 2377 mm; Width: 1034 mm; Perimeter: 6822 mm; Area: 2.45782 m2; Volume: 0.0807332 m3; Depth: 100 mm; NetVolume: 0.0807332 m3
Component Quantities - Component, Component Volume (Net): 0.0807332 m3; Component, Component Volume (Gross): 0.0807332 m3

# IfcDoor: D1 25 (5)
In: Begane grond
Type - OperationType: SINGLE_SWING_RIGHT; ParameterTakesPrecedence: no; Sizeable: no
Type - Door Lining Properties - LiningDepth: 114 mm; LiningThickness: 67 mm; LiningOffset: -100 mm
Type - Door Panel Properties - Panel 1 - PanelDepth: 40 mm; PanelOperation: SWINGING; PanelWidth: 1; PanelPosition: MIDDLE
OverallHeight: 2377 mm; OverallWidth: 1034 mm; Classification: Deur (ARCHICAD Classification); 32 Binnenwandopeningen (NL/SfB (4 cijfers))
Pset_DoorCommon - AcousticRating: ---; IsExternal: no
Material - Frame / Draaiend deel: arcering (01); Deurblad: arcering (02); Onderdorpel: %; Stofdorpel: arcering (01); Vensterbank: arcering (01); Ventilatierooster: %; Spouwlat: Naaldhout (01); Rollaag / Latei: arcering (01); Afwerking dagkant buiten: arcering (01); Afwerking dagkant binnen: arcering (01); Zonwering - behuizing: arcering (01); Zonwering - isolatie: Isolatie ruit; Glas: Glas - algemeen exterieur
Pset_FireRatingProperties - FireResistanceRating: ---
CPset_Phasing - Renovation Phase: Bestaand
AC_Pset_RenovationAndPhasing - Renovation Status: Existing
BaseQuantities - Height: 2377 mm; Width: 1034 mm; Perimeter: 6822 mm; Area: 2.45782 m2
Name | Volume (m3) = NetVolume (m3) = Component, Component Volume (Net) (m3) = Component, Component Volume (Gross) (m3) | Depth (mm)
b1.04 | 0.075622 | 100 | Pset_DoorCommon - GlazingAreaFraction: 1.27496
2 x b1.01 | 0.12662 | 100
b1.15 | 0.12662 | 200
b1.13 | 0.12662 | 100

# IfcDoor: D1 25, b1.06g
In: Begane grond
Type - OperationType: SINGLE_SWING_RIGHT; ParameterTakesPrecedence: no; Sizeable: no
Type - Door Lining Properties - LiningDepth: 114 mm; LiningThickness: 67 mm; LiningOffset: -107 mm
Type - Door Panel Properties - Panel 1 - PanelDepth: 40 mm; PanelOperation: SWINGING; PanelWidth: 1; PanelPosition: MIDDLE
OverallHeight: 2377 mm; OverallWidth: 1034 mm; Classification: Deur (ARCHICAD Classification); 32 Binnenwandopeningen (NL/SfB (4 cijfers))
Pset_DoorCommon - AcousticRating: valdorpel; GlazingAreaFraction: 1.27496; IsExternal: no
Material - Frame / Draaiend deel: arcering (01); Deurblad: arcering (02); Onderdorpel: %; Stofdorpel: arcering (01); Vensterbank: arcering (01); Ventilatierooster: %; Spouwlat: Naaldhout (01); Rollaag / Latei: arcering (01); Afwerking dagkant buiten: arcering (01); Afwerking dagkant binnen: arcering (01); Zonwering - behuizing: arcering (01); Zonwering - isolatie: Isolatie ruit; Glas: Glas - algemeen exterieur
Pset_FireRatingProperties - FireResistanceRating: ---
CPset_Phasing - Renovation Phase: Bestaand
AC_Pset_RenovationAndPhasing - Renovation Status: Existing
BaseQuantities - Height: 2377 mm; Width: 1034 mm; Perimeter: 6822 mm; Area: 2.45782 m2; Volume: 0.075622 m3; Depth: 200 mm; NetVolume: 0.075622 m3
Component Quantities - Component, Component Volume (Net): 0.075622 m3; Component, Component Volume (Gross): 0.075622 m3

# IfcDoor: D1 25 (10)
In: Begane grond
Type - OperationType: SINGLE_SWING_RIGHT; ParameterTakesPrecedence: no; Sizeable: no
Type - Door Lining Properties - LiningDepth: 114 mm; LiningThickness: 67 mm; LiningOffset: -114 mm
Type - Door Panel Properties - Panel 1 - PanelDepth: 40 mm; PanelOperation: SWINGING; PanelWidth: 1; PanelPosition: MIDDLE
OverallHeight: 2377 mm; OverallWidth: 1034 mm; Classification: Deur (ARCHICAD Classification); 32 Binnenwandopeningen (NL/SfB (4 cijfers))
Pset_DoorCommon - AcousticRating: ---; IsExternal: no
Material - Frame / Draaiend deel: arcering (01); Deurblad: arcering (02); Onderdorpel: %; Stofdorpel: arcering (01); Vensterbank: arcering (01); Ventilatierooster: %; Spouwlat: Naaldhout (01); Rollaag / Latei: arcering (01); Afwerking dagkant buiten: arcering (01); Afwerking dagkant binnen: arcering (01); Zonwering - behuizing: arcering (01); Zonwering - isolatie: Isolatie ruit; Glas: Glas - algemeen exterieur
Pset_FireRatingProperties - FireResistanceRating: ---
CPset_Phasing - Renovation Phase: Bestaand
AC_Pset_RenovationAndPhasing - Renovation Status: Existing
BaseQuantities - Height: 2377 mm; Width: 1034 mm; Perimeter: 6822 mm; Area: 2.45782 m2; Volume: 0.12662 m3; NetVolume: 0.12662 m3
Component Quantities - Component, Component Volume (Net): 0.12662 m3; Component, Component Volume (Gross): 0.12662 m3
Name | Depth (mm)
4 x b1.10 | 200
4 x b1.01 | 100
2 x b1.15 | 200

# IfcDoor: D1 25 (8)
In: Begane grond
Type - OperationType: SINGLE_SWING_RIGHT; ParameterTakesPrecedence: no; Sizeable: no
Type - Door Lining Properties - LiningDepth: 114 mm; LiningThickness: 67 mm; LiningOffset: -14 mm
Type - Door Panel Properties - Panel 1 - PanelDepth: 40 mm; PanelOperation: SWINGING; PanelWidth: 1; PanelPosition: MIDDLE
OverallHeight: 2377 mm; Classification: Deur (ARCHICAD Classification); 32 Binnenwandopeningen (NL/SfB (4 cijfers))
Pset_DoorCommon - IsExternal: no
Material - Frame / Draaiend deel: arcering (01); Deurblad: arcering (02); Onderdorpel: %; Stofdorpel: arcering (01); Vensterbank: arcering (01); Ventilatierooster: %; Spouwlat: Naaldhout (01); Rollaag / Latei: arcering (01); Afwerking dagkant buiten: arcering (01); Afwerking dagkant binnen: arcering (01); Zonwering - behuizing: arcering (01); Zonwering - isolatie: Isolatie ruit; Glas: Glas - algemeen exterieur
Pset_FireRatingProperties - FireResistanceRating: ---
CPset_Phasing - Renovation Phase: Bestaand
AC_Pset_RenovationAndPhasing - Renovation Status: Existing
BaseQuantities - Height: 2377 mm
Name | OverallWidth (mm) = Width (mm) | AcousticRating | Perimeter (mm) | Area (m2) | Volume (m3) = NetVolume (m3) = Component, Component Volume (Net) (m3) = Component, Component Volume (Gross) (m3) | Depth (mm)
b1.08g | 984 | valdorpel | 6722 | 2.33897 | 0.11791 | 100 | Pset_DoorCommon - GlazingAreaFraction: 0.0902879
b1.07 | 984 | --- | 6722 | 2.33897 | 0.0740941 | 100 | Pset_DoorCommon - GlazingAreaFraction: 1.18811
b1.09 | 984 | --- | 6722 | 2.33897 | 0.121618 | 100
b1.01 | 1034 | --- | 6822 | 2.45782 | 0.12662 | 100
2 x b1.11 | 934 | --- | 6622 | 2.22012 | 0.116616 | 100
b1.02 | 1034 | --- | 6822 | 2.45782 | 0.12662 | 200
b1.04 | 1034 | --- | 6822 | 2.45782 | 0.075622 | 100 | Pset_DoorCommon - GlazingAreaFraction: 1.27496

# IfcDoor: D1 25, b1.03
In: Begane grond
Type - OperationType: SINGLE_SWING_RIGHT; ParameterTakesPrecedence: no; Sizeable: no
Type - Door Lining Properties - LiningDepth: 114 mm; LiningThickness: 67 mm; LiningOffset: -214 mm
Type - Door Panel Properties - Panel 1 - PanelDepth: 40 mm; PanelOperation: SWINGING; PanelWidth: 1; PanelPosition: MIDDLE
OverallHeight: 2377 mm; OverallWidth: 1034 mm; Classification: Deur (ARCHICAD Classification); 32 Binnenwandopeningen (NL/SfB (4 cijfers))
Pset_DoorCommon - AcousticRating: ---; IsExternal: no
Material - Frame / Draaiend deel: arcering (01); Deurblad: arcering (02); Onderdorpel: %; Stofdorpel: arcering (01); Vensterbank: arcering (01); Ventilatierooster: %; Spouwlat: Naaldhout (01); Rollaag / Latei: arcering (01); Afwerking dagkant buiten: arcering (01); Afwerking dagkant binnen: arcering (01); Zonwering - behuizing: arcering (01); Zonwering - isolatie: Isolatie ruit; Glas: Glas - algemeen exterieur
Pset_FireRatingProperties - FireResistanceRating: ---
CPset_Phasing - Renovation Phase: Bestaand
AC_Pset_RenovationAndPhasing - Renovation Status: Existing
BaseQuantities - Height: 2377 mm; Width: 1034 mm; Perimeter: 6822 mm; Area: 2.45782 m2; Volume: 0.12662 m3; Depth: 214 mm; NetVolume: 0.12662 m3
Component Quantities - Component, Component Volume (Net): 0.12662 m3; Component, Component Volume (Gross): 0.12662 m3

# IfcDoor: D1 25, b1.13
In: Begane grond
Type - OperationType: SINGLE_SWING_RIGHT; ParameterTakesPrecedence: no; Sizeable: no
Type - Door Lining Properties - LiningDepth: 114 mm; LiningThickness: 67 mm; LiningOffset: -50 mm
Type - Door Panel Properties - Panel 1 - PanelDepth: 40 mm; PanelOperation: SWINGING; PanelWidth: 1; PanelPosition: MIDDLE
OverallHeight: 2377 mm; OverallWidth: 1034 mm; Classification: Deur (ARCHICAD Classification); 32 Binnenwandopeningen (NL/SfB (4 cijfers))
Pset_DoorCommon - AcousticRating: ---; IsExternal: no
Material - Frame / Draaiend deel: arcering (01); Deurblad: arcering (02); Onderdorpel: %; Stofdorpel: arcering (01); Vensterbank: arcering (01); Ventilatierooster: %; Spouwlat: Naaldhout (01); Rollaag / Latei: arcering (01); Afwerking dagkant buiten: arcering (01); Afwerking dagkant binnen: arcering (01); Zonwering - behuizing: arcering (01); Zonwering - isolatie: Isolatie ruit; Glas: Glas - algemeen exterieur
Pset_FireRatingProperties - FireResistanceRating: ---
CPset_Phasing - Renovation Phase: Bestaand
AC_Pset_RenovationAndPhasing - Renovation Status: Existing
BaseQuantities - Height: 2377 mm; Width: 1034 mm; Perimeter: 6822 mm; Area: 2.45782 m2; Volume: 0.12662 m3; Depth: 100 mm; NetVolume: 0.12662 m3
Component Quantities - Component, Component Volume (Net): 0.12662 m3; Component, Component Volume (Gross): 0.12662 m3

# IfcDoor: D1 25 (6)
In: Begane grond
Type - OperationType: SINGLE_SWING_RIGHT; ParameterTakesPrecedence: no; Sizeable: no
Type - Door Lining Properties - LiningDepth: 114 mm; LiningThickness: 67 mm; LiningOffset: -64 mm
Type - Door Panel Properties - Panel 1 - PanelDepth: 40 mm; PanelOperation: SWINGING; PanelWidth: 1; PanelPosition: MIDDLE
OverallHeight: 2377 mm; OverallWidth: 1034 mm; Classification: Deur (ARCHICAD Classification); 32 Binnenwandopeningen (NL/SfB (4 cijfers))
Pset_DoorCommon - AcousticRating: ---; IsExternal: no
Material - Frame / Draaiend deel: arcering (01); Deurblad: arcering (02); Onderdorpel: %; Stofdorpel: arcering (01); Vensterbank: arcering (01); Ventilatierooster: %; Spouwlat: Naaldhout (01); Rollaag / Latei: arcering (01); Afwerking dagkant buiten: arcering (01); Afwerking dagkant binnen: arcering (01); Zonwering - behuizing: arcering (01); Zonwering - isolatie: Isolatie ruit; Glas: Glas - algemeen exterieur
Pset_FireRatingProperties - FireResistanceRating: ---
CPset_Phasing - Renovation Phase: Bestaand
AC_Pset_RenovationAndPhasing - Renovation Status: Existing
BaseQuantities - Height: 2377 mm; Width: 1034 mm; Perimeter: 6822 mm; Area: 2.45782 m2; Volume: 0.12662 m3; Depth: 100 mm; NetVolume: 0.12662 m3
Component Quantities - Component, Component Volume (Net): 0.12662 m3; Component, Component Volume (Gross): 0.12662 m3

# IfcDoor: D1 25 (10)
In: Begane grond
Type - OperationType: SINGLE_SWING_RIGHT; ParameterTakesPrecedence: no; Sizeable: no
Type - Door Lining Properties - LiningDepth: 114 mm; LiningThickness: 67 mm; LiningOffset: 0 mm
Type - Door Panel Properties - Panel 1 - PanelDepth: 40 mm; PanelOperation: SWINGING; PanelWidth: 1; PanelPosition: MIDDLE
OverallHeight: 2377 mm; Classification: Deur (ARCHICAD Classification); 32 Binnenwandopeningen (NL/SfB (4 cijfers))
Pset_DoorCommon - AcousticRating: ---; IsExternal: no
Material - Frame / Draaiend deel: arcering (01); Deurblad: arcering (02); Onderdorpel: %; Stofdorpel: arcering (01); Vensterbank: arcering (01); Ventilatierooster: %; Spouwlat: Naaldhout (01); Rollaag / Latei: arcering (01); Afwerking dagkant buiten: arcering (01); Afwerking dagkant binnen: arcering (01); Zonwering - behuizing: arcering (01); Zonwering - isolatie: Isolatie ruit; Glas: Glas - algemeen exterieur
Pset_FireRatingProperties - FireResistanceRating: ---
CPset_Phasing - Renovation Phase: Bestaand
AC_Pset_RenovationAndPhasing - Renovation Status: Existing
BaseQuantities - Height: 2377 mm
Name | OverallWidth (mm) | Width (mm) | Perimeter (mm) | Area (m2) | Volume (m3) = NetVolume (m3) = Component, Component Volume (Net) (m3) = Component, Component Volume (Gross) (m3) | Depth (mm)
7 x b1.01 | 1034 | 1034 | 6822 | 2.45782 | 0.12662 | 100
b1.01 | 1034 | 1008 | 6770 | 2.39602 | 0.12662 | 100
b1.12 | 984 | 984 | 6722 | 2.33897 | 0.121618 | 100
b1.15 | 1034 | 1034 | 6822 | 2.45782 | 0.12662 | 200

# IfcDoor: D1 25, b1.14-sp
In: Begane grond
Type - OperationType: SINGLE_SWING_RIGHT; ParameterTakesPrecedence: no; Sizeable: no
Type - Door Lining Properties - LiningDepth: 114 mm; LiningThickness: 67 mm; LiningOffset: 36 mm
Type - Door Panel Properties - Panel 1 - PanelDepth: 40 mm; PanelOperation: SWINGING; PanelWidth: 1; PanelPosition: MIDDLE
OverallHeight: 2377 mm; OverallWidth: 1034 mm; Classification: Deur (ARCHICAD Classification); 32 Binnenwandopeningen (NL/SfB (4 cijfers))
Pset_DoorCommon - AcousticRating: ---; IsExternal: no
Material - Frame / Draaiend deel: arcering (01); Deurblad: arcering (02); Onderdorpel: %; Stofdorpel: arcering (01); Vensterbank: arcering (01); Ventilatierooster: %; Spouwlat: Naaldhout (01); Rollaag / Latei: arcering (01); Afwerking dagkant buiten: arcering (01); Afwerking dagkant binnen: arcering (01); Zonwering - behuizing: arcering (01); Zonwering - isolatie: Isolatie ruit; Glas: Glas - algemeen exterieur
Pset_FireRatingProperties - FireResistanceRating: ---
CPset_Phasing - Renovation Phase: Bestaand
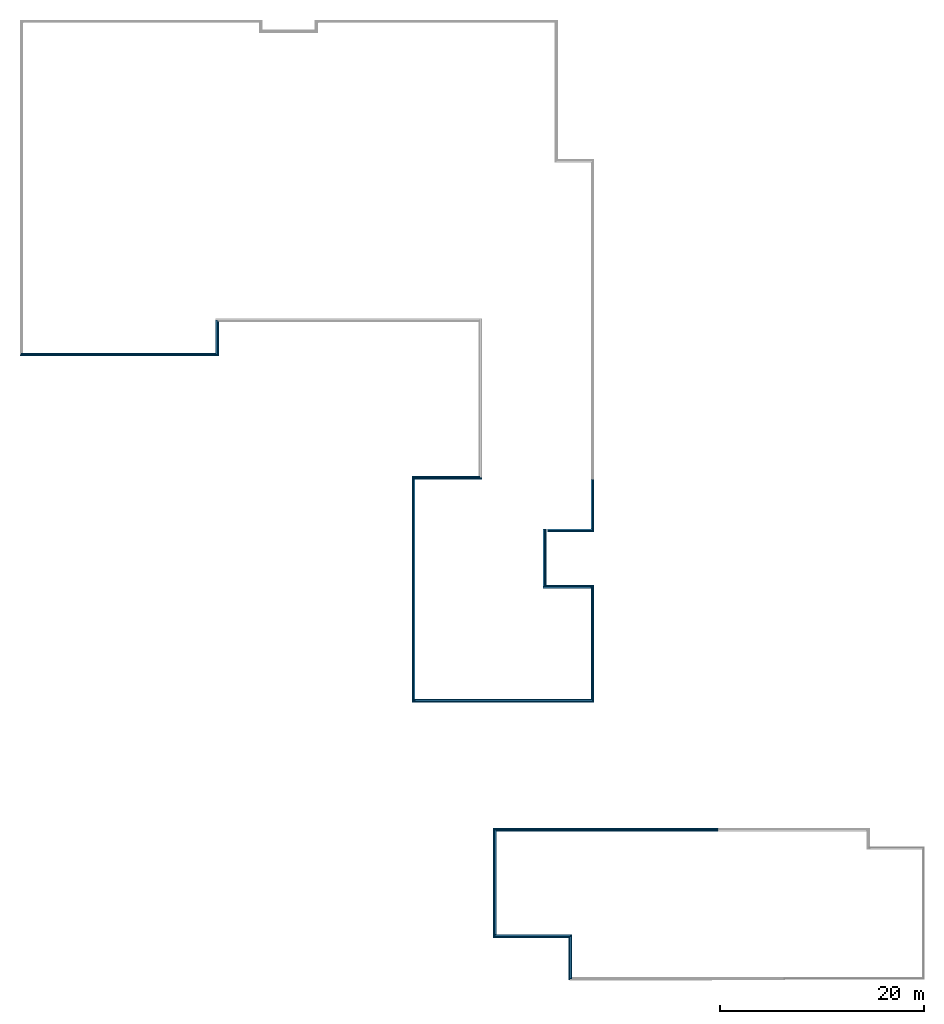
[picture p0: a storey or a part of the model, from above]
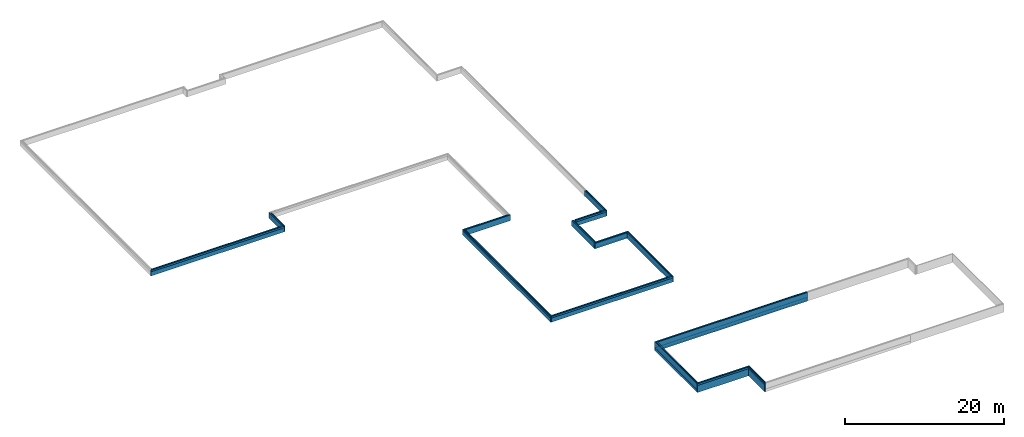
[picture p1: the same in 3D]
Properties of the parts of a building model (IFC2X3), part 16 of 19

# IfcDoor: D1 25, b1.14-sp
AC_Pset_RenovationAndPhasing - Renovation Status: Existing
BaseQuantities - Height: 2377 mm; Width: 1034 mm; Perimeter: 6822 mm; Area: 2.45782 m2; Volume: 0.12662 m3; Depth: 150 mm; NetVolume: 0.12662 m3
Component Quantities - Component, Component Volume (Net): 0.12662 m3; Component, Component Volume (Gross): 0.12662 m3

# IfcDoor: D1 bl 25, Merk DF
In: Begane grond
Type - OperationType: SINGLE_SWING_LEFT; ParameterTakesPrecedence: no; Sizeable: no
Type - Door Lining Properties - LiningDepth: 68 mm; LiningThickness: 76 mm; TransomThickness: 76 mm; TransomOffset: 2350 mm; LiningOffset: 18 mm
Type - Door Panel Properties - Panel 1 - PanelDepth: 63 mm; PanelOperation: SWINGING; PanelWidth: 1; PanelPosition: MIDDLE
OverallHeight: 2815 mm; OverallWidth: 1200 mm; Classification: Deur (ARCHICAD Classification); 31 Buitenwandopeningen (NL/SfB (4 cijfers))
Pset_DoorCommon - GlazingAreaFraction: 2.23226; IsExternal: yes
Material - Frame / Draaiend deel: arcering (01); Deurblad: arcering (02); Onderdorpel: %; Stofdorpel: arcering (01); Vensterbank: arcering (01); Ventilatierooster: %; Spouwlat: Naaldhout (01); Rollaag / Latei: arcering (01); Afwerking dagkant buiten: arcering (01); Afwerking dagkant binnen: arcering (01); Zonwering - behuizing: arcering (01); Zonwering - isolatie: Isolatie ruit; Glas: Glas - algemeen exterieur
CPset_Phasing - Renovation Phase: Bestaand
AC_Pset_RenovationAndPhasing - Renovation Status: Existing
BaseQuantities - Height: 2780 mm; Width: 1200 mm; Perimeter: 7960 mm; Area: 3.336 m2; Volume: 0.0896562 m3; Depth: 460 mm; NetVolume: 0.0896562 m3
Component Quantities - Component, Component Volume (Net): 0.0896562 m3; Component, Component Volume (Gross): 0.0896562 m3

# IfcDoor: D1 bl zl1-b 25 (2)
In: Begane grond
Type - OperationType: SINGLE_SWING_LEFT; ParameterTakesPrecedence: no; Sizeable: no
Type - Door Panel Properties - Panel 1 - PanelDepth: 40 mm; PanelOperation: SWINGING; PanelWidth: 1; PanelPosition: MIDDLE
OverallHeight: 2800 mm; Classification: Deur (ARCHICAD Classification); 32 Binnenwandopeningen (NL/SfB (4 cijfers))
Pset_DoorCommon - AcousticRating: ---; IsExternal: no
Material - Frame / Draaiend deel: arcering (01); Deurblad: arcering (02); Onderdorpel: %; Stofdorpel: arcering (01); Vensterbank: arcering (01); Ventilatierooster: %; Spouwlat: Naaldhout (01); Rollaag / Latei: arcering (01); Afwerking dagkant buiten: arcering (01); Afwerking dagkant binnen: arcering (01); Zonwering - behuizing: arcering (01); Zonwering - isolatie: Isolatie ruit; Glas: Glas - algemeen exterieur
Pset_FireRatingProperties - FireResistanceRating: 30 minuten brandwerend en zelfsluitend
CPset_Phasing - Renovation Phase: Bestaand
AC_Pset_RenovationAndPhasing - Renovation Status: Existing
BaseQuantities - Height: 2800 mm; Depth: 100 mm
Name | OverallWidth (mm) | GlazingAreaFraction | Width (mm) | Perimeter (mm) | Area (m2) | Volume (m3) = NetVolume (m3) = Component, Component Volume (Net) (m3) = Component, Component Volume (Gross) (m3)
b1.22B | 2000 | 3.8106 | 1998 | 9596 | 5.5944 | 0.140527
b1.20B | 1800 | 3.29539 | 1800 | 9199.99 | 5.03999 | 0.135419

# IfcDoor: D1 bl zl1-b 25 (3)
In: Begane grond
Type - OperationType: SINGLE_SWING_LEFT; ParameterTakesPrecedence: no; Sizeable: no
Type - Door Panel Properties - Panel 1 - PanelDepth: 63 mm; PanelOperation: SWINGING; PanelWidth: 1; PanelPosition: MIDDLE
OverallHeight: 2815 mm; OverallWidth: 2010 mm; Classification: Deur (ARCHICAD Classification); 31 Buitenwandopeningen (NL/SfB (4 cijfers))
Pset_DoorCommon - GlazingAreaFraction: 3.82703; IsExternal: yes
Material - Frame / Draaiend deel: arcering (01); Deurblad: arcering (02); Onderdorpel: %; Stofdorpel: arcering (01); Vensterbank: arcering (01); Ventilatierooster: %; Spouwlat: Naaldhout (01); Rollaag / Latei: arcering (01); Afwerking dagkant buiten: arcering (01); Afwerking dagkant binnen: arcering (01); Zonwering - behuizing: arcering (01); Zonwering - isolatie: Isolatie ruit; Glas: Glas - algemeen exterieur
Pset_FireRatingProperties - FireResistanceRating: --
CPset_Phasing - Renovation Phase: Bestaand
AC_Pset_RenovationAndPhasing - Renovation Status: Existing
BaseQuantities - Height: 2780 mm; Width: 2010 mm; Perimeter: 9580 mm; Area: 5.5878 m2
Name | Volume (m3) = NetVolume (m3) = Component, Component Volume (Net) (m3) = Component, Component Volume (Gross) (m3) | Depth (mm)
Merk DA-sp | 0.150834 | 312
2 x Merk DA-sp | 0.147755 | 436

# IfcDoor: D1 bl zl1-b 25 (2)
In: Begane grond
Type - OperationType: SINGLE_SWING_RIGHT; ParameterTakesPrecedence: no; Sizeable: no
Type - Door Panel Properties - Panel 1 - PanelDepth: 40 mm; PanelOperation: SWINGING; PanelWidth: 1; PanelPosition: MIDDLE
OverallHeight: 2800 mm; OverallWidth: 1800 mm; Classification: Deur (ARCHICAD Classification); 32 Binnenwandopeningen (NL/SfB (4 cijfers))
Pset_DoorCommon - AcousticRating: ---; GlazingAreaFraction: 3.29539; IsExternal: no
Material - Frame / Draaiend deel: arcering (01); Deurblad: arcering (02); Onderdorpel: %; Stofdorpel: arcering (01); Vensterbank: arcering (01); Ventilatierooster: %; Spouwlat: Naaldhout (01); Rollaag / Latei: arcering (01); Afwerking dagkant buiten: arcering (01); Afwerking dagkant binnen: arcering (01); Zonwering - behuizing: arcering (01); Zonwering - isolatie: Isolatie ruit; Glas: Glas - algemeen exterieur
CPset_Phasing - Renovation Phase: Bestaand
AC_Pset_RenovationAndPhasing - Renovation Status: Existing
BaseQuantities - Height: 2800 mm; Width: 1800 mm; Perimeter: 9199.99 mm; Area: 5.03999 m2; Volume: 0.135419 m3; NetVolume: 0.135419 m3
Component Quantities - Component, Component Volume (Net): 0.135419 m3; Component, Component Volume (Gross): 0.135419 m3
Name | FireResistanceRating | Depth (mm)
b1.21B | 30 minuten brandwerend en zelfsluitend | 200
b1.19 | --- | 100

# IfcDoor: D1 bl zl1-b 25 (10)
In: Begane grond
Type - OperationType: SINGLE_SWING_RIGHT; ParameterTakesPrecedence: no; Sizeable: no
Type - Door Panel Properties - Panel 1 - PanelDepth: 63 mm; PanelOperation: SWINGING; PanelWidth: 1; PanelPosition: MIDDLE
OverallHeight: 2815 mm; OverallWidth: 2010 mm; Classification: Deur (ARCHICAD Classification); 31 Buitenwandopeningen (NL/SfB (4 cijfers))
Pset_DoorCommon - GlazingAreaFraction: 3.82703; IsExternal: yes
Material - Frame / Draaiend deel: arcering (01); Deurblad: arcering (02); Onderdorpel: %; Stofdorpel: arcering (01); Vensterbank: arcering (01); Ventilatierooster: %; Spouwlat: Naaldhout (01); Rollaag / Latei: arcering (01); Afwerking dagkant buiten: arcering (01); Afwerking dagkant binnen: arcering (01); Zonwering - behuizing: arcering (01); Zonwering - isolatie: Isolatie ruit; Glas: Glas - algemeen exterieur
Pset_FireRatingProperties - FireResistanceRating: --
CPset_Phasing - Renovation Phase: Bestaand
AC_Pset_RenovationAndPhasing - Renovation Status: Existing
BaseQuantities - Height: 2780 mm; Width: 2010 mm; Perimeter: 9580 mm; Area: 5.5878 m2; Volume: 0.147755 m3; NetVolume: 0.147755 m3
Component Quantities - Component, Component Volume (Net): 0.147755 m3; Component, Component Volume (Gross): 0.147755 m3
Name | Depth (mm)
6 x Merk DA-n | 436
2 x Merk DA | 436
2 x Merk DA | 500

# IfcDoor: D1 zl1-b 25 (2)
In: Begane grond
Type - OperationType: SINGLE_SWING_LEFT; ParameterTakesPrecedence: no; Sizeable: no
Type - Door Panel Properties - Panel 1 - PanelDepth: 40 mm; PanelOperation: SWINGING; PanelWidth: 1; PanelPosition: MIDDLE
OverallHeight: 2377 mm; OverallWidth: 2140 mm; Classification: Deur (ARCHICAD Classification); 32 Binnenwandopeningen (NL/SfB (4 cijfers))
Pset_DoorCommon - AcousticRating: valdorpel; GlazingAreaFraction: 3.50325; IsExternal: no
Material - Frame / Draaiend deel: arcering (01); Deurblad: arcering (02); Onderdorpel: %; Stofdorpel: arcering (01); Vensterbank: arcering (01); Ventilatierooster: %; Spouwlat: Naaldhout (01); Rollaag / Latei: arcering (01); Afwerking dagkant buiten: arcering (01); Afwerking dagkant binnen: arcering (01); Zonwering - behuizing: arcering (01); Zonwering - isolatie: Isolatie ruit; Glas: Glas - algemeen exterieur
Pset_FireRatingProperties - FireResistanceRating: ---
CPset_Phasing - Renovation Phase: Bestaand
AC_Pset_RenovationAndPhasing - Renovation Status: Existing
BaseQuantities - Height: 2377 mm; Width: 2140 mm; Perimeter: 9034 mm; Area: 5.08678 m2; Volume: 0.117059 m3; Depth: 100 mm; NetVolume: 0.117059 m3
Component Quantities - Component, Component Volume (Net): 0.117059 m3; Component, Component Volume (Gross): 0.117059 m3

# IfcDoor: D1 zl1-b 25 (2)
In: Begane grond
Type - OperationType: SINGLE_SWING_LEFT; ParameterTakesPrecedence: no; Sizeable: no
Type - Door Panel Properties - Panel 1 - PanelDepth: 63 mm; PanelOperation: SWINGING; PanelWidth: 1; PanelPosition: MIDDLE
OverallHeight: 2645 mm; OverallWidth: 1750 mm; Classification: Deur (ARCHICAD Classification); 31 Buitenwandopeningen (NL/SfB (4 cijfers))
Pset_DoorCommon - GlazingAreaFraction: 3.20742; IsExternal: yes
Material - Frame / Draaiend deel: arcering (01); Deurblad: arcering (02); Onderdorpel: %; Stofdorpel: arcering (01); Vensterbank: arcering (01); Ventilatierooster: %; Spouwlat: Naaldhout (01); Rollaag / Latei: arcering (01); Afwerking dagkant buiten: arcering (01); Afwerking dagkant binnen: arcering (01); Zonwering - behuizing: arcering (01); Zonwering - isolatie: Isolatie ruit; Glas: Glas - algemeen exterieur
CPset_Phasing - Renovation Phase: Bestaand
AC_Pset_RenovationAndPhasing - Renovation Status: Existing
BaseQuantities - Height: 2610 mm; Width: 1750 mm; Perimeter: 8720 mm; Area: 4.5675 m2; Volume: 0.115758 m3; NetVolume: 0.115758 m3
Component Quantities - Component, Component Volume (Net): 0.115758 m3; Component, Component Volume (Gross): 0.115758 m3
Name | Depth (mm)
Merk DJ | 396
Merk DK | 436

# IfcDoor: D1 zl1-b 25 (6)
In: Begane grond
Type - OperationType: SINGLE_SWING_RIGHT; ParameterTakesPrecedence: no; Sizeable: no
Type - Door Panel Properties - Panel 1 - PanelDepth: 40 mm; PanelOperation: SWINGING; PanelWidth: 1; PanelPosition: MIDDLE
Classification: Deur (ARCHICAD Classification); 32 Binnenwandopeningen (NL/SfB (4 cijfers))
Pset_DoorCommon - IsExternal: no
Material - Frame / Draaiend deel: arcering (01); Deurblad: arcering (02); Onderdorpel: %; Stofdorpel: arcering (01); Vensterbank: arcering (01); Ventilatierooster: %; Spouwlat: Naaldhout (01); Rollaag / Latei: arcering (01); Afwerking dagkant buiten: arcering (01); Afwerking dagkant binnen: arcering (01); Zonwering - behuizing: arcering (01); Zonwering - isolatie: Isolatie ruit; Glas: Glas - algemeen exterieur
CPset_Phasing - Renovation Phase: Bestaand
AC_Pset_RenovationAndPhasing - Renovation Status: Existing
Name | OverallHeight (mm) = Height (mm) | OverallWidth (mm) = Width (mm) | AcousticRating | GlazingAreaFraction | FireResistanceRating | Perimeter (mm) | Area (m2) | Volume (m3) = NetVolume (m3) = Component, Component Volume (Net) (m3) = Component, Component Volume (Gross) (m3) | Depth (mm)
2 x b1.25Bg | 2377 | 2500 | valdorpel | 4.31073 | 30 minuten brandwerend en zelfsluitend | 9754 | 5.9425 | 0.122558 | 214
3 x b1.23g | 2377 | 2000 | valdorpel | 3.23983 | --- | 8754 | 4.754 | 0.113392 | 100
b1.26 | 2600 | 1850 | --- | 3.17836 | --- | 8900 | 4.81 | 0.119804 | 100

# IfcDoor: D2 25, b2.10
In: Begane grond
Type - OperationType: DOUBLE_DOOR_SINGLE_SWING; ParameterTakesPrecedence: no; Sizeable: no
Type - Door Lining Properties - LiningDepth: 114 mm; LiningThickness: 67 mm; LiningOffset: -100 mm
Type - Door Panel Properties - Panel 1 - PanelDepth: 40 mm; PanelOperation: SWINGING; PanelWidth: 0.510204; PanelPosition: LEFT
Type - Door Panel Properties - Panel 2 - PanelDepth: 40 mm; PanelOperation: SWINGING; PanelWidth: 0.510204; PanelPosition: RIGHT
OverallHeight: 2377 mm; OverallWidth: 1800 mm; Classification: Deur (ARCHICAD Classification); 32 Binnenwandopeningen (NL/SfB (4 cijfers))
Pset_DoorCommon - AcousticRating: ---; IsExternal: no
Material - Frame / Draaiend deel: arcering (01); Deurblad: arcering (02); Onderdorpel: %; Stofdorpel: arcering (01); Vensterbank: arcering (01); Ventilatierooster: %; Spouwlat: Naaldhout (01); Rollaag / Latei: arcering (01); Afwerking dagkant buiten: arcering (01); Afwerking dagkant binnen: arcering (01); Zonwering - behuizing: arcering (01); Zonwering - isolatie: Isolatie ruit; Glas: Glas - algemeen exterieur
Pset_FireRatingProperties - FireResistanceRating: ---
CPset_Phasing - Renovation Phase: Bestaand
AC_Pset_RenovationAndPhasing - Renovation Status: Existing
BaseQuantities - Height: 2377 mm; Width: 1800 mm; Perimeter: 8354 mm; Area: 4.2786 m2; Volume: 0.203249 m3; Depth: 200 mm; NetVolume: 0.203249 m3
Component Quantities - Component, Component Volume (Net): 0.203249 m3; Component, Component Volume (Gross): 0.203249 m3

# IfcDoor: D2 25, b2.11
In: Begane grond
Type - OperationType: DOUBLE_DOOR_SINGLE_SWING; ParameterTakesPrecedence: no; Sizeable: no
Type - Door Lining Properties - LiningDepth: 114 mm; LiningThickness: 67 mm; LiningOffset: -114 mm
Type - Door Panel Properties - Panel 1 - PanelDepth: 40 mm; PanelOperation: SWINGING; PanelWidth: 0.510204; PanelPosition: LEFT
Type - Door Panel Properties - Panel 2 - PanelDepth: 40 mm; PanelOperation: SWINGING; PanelWidth: 0.510204; PanelPosition: RIGHT
OverallHeight: 2377 mm; OverallWidth: 1800 mm; Classification: Deur (ARCHICAD Classification); 32 Binnenwandopeningen (NL/SfB (4 cijfers))
Pset_DoorCommon - AcousticRating: ---; IsExternal: no
Material - Frame / Draaiend deel: arcering (01); Deurblad: arcering (02); Onderdorpel: %; Stofdorpel: arcering (01); Vensterbank: arcering (01); Ventilatierooster: %; Spouwlat: Naaldhout (01); Rollaag / Latei: arcering (01); Afwerking dagkant buiten: arcering (01); Afwerking dagkant binnen: arcering (01); Zonwering - behuizing: arcering (01); Zonwering - isolatie: Isolatie ruit; Glas: Glas - algemeen exterieur
Pset_FireRatingProperties - FireResistanceRating: ---
CPset_Phasing - Renovation Phase: Bestaand
AC_Pset_RenovationAndPhasing - Renovation Status: Existing
BaseQuantities - Height: 2377 mm; Width: 1800 mm; Perimeter: 8354 mm; Area: 4.2786 m2; Volume: 0.203249 m3; Depth: 200 mm; NetVolume: 0.203249 m3
Component Quantities - Component, Component Volume (Net): 0.203249 m3; Component, Component Volume (Gross): 0.203249 m3

# IfcDoor: D2 25, b2.12
In: Begane grond
Type - OperationType: DOUBLE_DOOR_SINGLE_SWING; ParameterTakesPrecedence: no; Sizeable: no
Type - Door Lining Properties - LiningDepth: 114 mm; LiningThickness: 67 mm; LiningOffset: -14 mm
Type - Door Panel Properties - Panel 1 - PanelDepth: 40 mm; PanelOperation: SWINGING; PanelWidth: 0.508228; PanelPosition: LEFT
Type - Door Panel Properties - Panel 2 - PanelDepth: 40 mm; PanelOperation: SWINGING; PanelWidth: 0.508228; PanelPosition: RIGHT
OverallHeight: 2377 mm; OverallWidth: 2200 mm; Classification: Deur (ARCHICAD Classification); 32 Binnenwandopeningen (NL/SfB (4 cijfers))
Pset_DoorCommon - AcousticRating: ---; IsExternal: no
Material - Frame / Draaiend deel: arcering (01); Deurblad: arcering (02); Onderdorpel: %; Stofdorpel: arcering (01); Vensterbank: arcering (01); Ventilatierooster: %; Spouwlat: Naaldhout (01); Rollaag / Latei: arcering (01); Afwerking dagkant buiten: arcering (01); Afwerking dagkant binnen: arcering (01); Zonwering - behuizing: arcering (01); Zonwering - isolatie: Isolatie ruit; Glas: Glas - algemeen exterieur
Pset_FireRatingProperties - FireResistanceRating: ---
CPset_Phasing - Renovation Phase: Bestaand
AC_Pset_RenovationAndPhasing - Renovation Status: Existing
BaseQuantities - Height: 2377 mm; Width: 2200 mm; Perimeter: 9154 mm; Area: 5.2294 m2; Volume: 0.243265 m3; Depth: 100 mm; NetVolume: 0.243265 m3
Component Quantities - Component, Component Volume (Net): 0.243265 m3; Component, Component Volume (Gross): 0.243265 m3

# IfcDoor: D2 25, b2.08
In: Begane grond
Type - OperationType: DOUBLE_DOOR_SINGLE_SWING; ParameterTakesPrecedence: no; Sizeable: no
Type - Door Lining Properties - LiningDepth: 114 mm; LiningThickness: 67 mm; LiningOffset: -64 mm
Type - Door Panel Properties - Panel 1 - PanelDepth: 40 mm; PanelOperation: SWINGING; PanelWidth: 0.508228; PanelPosition: LEFT
Type - Door Panel Properties - Panel 2 - PanelDepth: 40 mm; PanelOperation: SWINGING; PanelWidth: 0.508228; PanelPosition: RIGHT
OverallHeight: 2377 mm; OverallWidth: 2200 mm; Classification: Deur (ARCHICAD Classification); 32 Binnenwandopeningen (NL/SfB (4 cijfers))
Pset_DoorCommon - AcousticRating: ---; IsExternal: no
Material - Frame / Draaiend deel: arcering (01); Deurblad: arcering (02); Onderdorpel: %; Stofdorpel: arcering (01); Vensterbank: arcering (01); Ventilatierooster: %; Spouwlat: Naaldhout (01); Rollaag / Latei: arcering (01); Afwerking dagkant buiten: arcering (01); Afwerking dagkant binnen: arcering (01); Zonwering - behuizing: arcering (01); Zonwering - isolatie: Isolatie ruit; Glas: Glas - algemeen exterieur
Pset_FireRatingProperties - FireResistanceRating: ---
CPset_Phasing - Renovation Phase: Bestaand
AC_Pset_RenovationAndPhasing - Renovation Status: Existing
BaseQuantities - Height: 2377 mm; Width: 2200 mm; Perimeter: 9154 mm; Area: 5.2294 m2; Volume: 0.243265 m3; Depth: 100 mm; NetVolume: 0.243265 m3
Component Quantities - Component, Component Volume (Net): 0.243265 m3; Component, Component Volume (Gross): 0.243265 m3

# IfcDoor: D2 25, b2.07
In: Begane grond
Type - OperationType: DOUBLE_DOOR_SINGLE_SWING; ParameterTakesPrecedence: no; Sizeable: no
Type - Door Lining Properties - LiningDepth: 114 mm; LiningThickness: 67 mm; LiningOffset: -7 mm
Type - Door Panel Properties - Panel 1 - PanelDepth: 40 mm; PanelOperation: SWINGING; PanelWidth: 0.509626; PanelPosition: LEFT
Type - Door Panel Properties - Panel 2 - PanelDepth: 40 mm; PanelOperation: SWINGING; PanelWidth: 0.509626; PanelPosition: RIGHT
OverallHeight: 2377 mm; OverallWidth: 1900 mm; Classification: Deur (ARCHICAD Classification); 32 Binnenwandopeningen (NL/SfB (4 cijfers))
Pset_DoorCommon - AcousticRating: ---; GlazingAreaFraction: 2.4318; IsExternal: no
Material - Frame / Draaiend deel: arcering (01); Deurblad: arcering (02); Onderdorpel: %; Stofdorpel: arcering (01); Vensterbank: arcering (01); Ventilatierooster: %; Spouwlat: Naaldhout (01); Rollaag / Latei: arcering (01); Afwerking dagkant buiten: arcering (01); Afwerking dagkant binnen: arcering (01); Zonwering - behuizing: arcering (01); Zonwering - isolatie: Isolatie ruit; Glas: Glas - algemeen exterieur
Pset_FireRatingProperties - FireResistanceRating: ---
CPset_Phasing - Renovation Phase: Bestaand
AC_Pset_RenovationAndPhasing - Renovation Status: Existing
BaseQuantities - Height: 2377 mm; Width: 1900 mm; Perimeter: 8554 mm; Area: 4.5163 m2; Volume: 0.115981 m3; Depth: 200 mm; NetVolume: 0.115981 m3
Component Quantities - Component, Component Volume (Net): 0.115981 m3; Component, Component Volume (Gross): 0.115981 m3

# IfcDoor: D2 25, b2.10
In: Begane grond
Type - OperationType: DOUBLE_DOOR_SINGLE_SWING; ParameterTakesPrecedence: no; Sizeable: no
Type - Door Lining Properties - LiningDepth: 114 mm; LiningThickness: 67 mm; LiningOffset: -8 mm
Type - Door Panel Properties - Panel 1 - PanelDepth: 40 mm; PanelOperation: SWINGING; PanelWidth: 0.510204; PanelPosition: RIGHT
Type - Door Panel Properties - Panel 2 - PanelDepth: 40 mm; PanelOperation: SWINGING; PanelWidth: 0.510204; PanelPosition: LEFT
OverallHeight: 2377 mm; OverallWidth: 1800 mm; Classification: Deur (ARCHICAD Classification); 32 Binnenwandopeningen (NL/SfB (4 cijfers))
Pset_DoorCommon - AcousticRating: ---; IsExternal: no
Material - Frame / Draaiend deel: arcering (01); Deurblad: arcering (02); Onderdorpel: %; Stofdorpel: arcering (01); Vensterbank: arcering (01); Ventilatierooster: %; Spouwlat: Naaldhout (01); Rollaag / Latei: arcering (01); Afwerking dagkant buiten: arcering (01); Afwerking dagkant binnen: arcering (01); Zonwering - behuizing: arcering (01); Zonwering - isolatie: Isolatie ruit; Glas: Glas - algemeen exterieur
Pset_FireRatingProperties - FireResistanceRating: ---
CPset_Phasing - Renovation Phase: Bestaand
AC_Pset_RenovationAndPhasing - Renovation Status: Existing
BaseQuantities - Height: 2377 mm; Width: 1800 mm; Perimeter: 8354 mm; Area: 4.2786 m2; Volume: 0.203249 m3; Depth: 200 mm; NetVolume: 0.203249 m3
Component Quantities - Component, Component Volume (Net): 0.203249 m3; Component, Component Volume (Gross): 0.203249 m3

# IfcDoor: D2 25, b2.09
In: Begane grond
Type - OperationType: DOUBLE_DOOR_SINGLE_SWING; ParameterTakesPrecedence: no; Sizeable: no
Type - Door Lining Properties - LiningDepth: 114 mm; LiningThickness: 67 mm; LiningOffset: 0 mm
Type - Door Panel Properties - Panel 1 - PanelDepth: 40 mm; PanelOperation: SWINGING; PanelWidth: 0.510204; PanelPosition: LEFT
Type - Door Panel Properties - Panel 2 - PanelDepth: 40 mm; PanelOperation: SWINGING; PanelWidth: 0.510204; PanelPosition: RIGHT
OverallHeight: 2377 mm; OverallWidth: 1800 mm; Classification: Deur (ARCHICAD Classification); 32 Binnenwandopeningen (NL/SfB (4 cijfers))
Pset_DoorCommon - AcousticRating: ---; IsExternal: no
Material - Frame / Draaiend deel: arcering (01); Deurblad: arcering (02); Onderdorpel: %; Stofdorpel: arcering (01); Vensterbank: arcering (01); Ventilatierooster: %; Spouwlat: Naaldhout (01); Rollaag / Latei: arcering (01); Afwerking dagkant buiten: arcering (01); Afwerking dagkant binnen: arcering (01); Zonwering - behuizing: arcering (01); Zonwering - isolatie: Isolatie ruit; Glas: Glas - algemeen exterieur
Pset_FireRatingProperties - FireResistanceRating: ---
CPset_Phasing - Renovation Phase: Bestaand
AC_Pset_RenovationAndPhasing - Renovation Status: Existing
BaseQuantities - Height: 2377 mm; Width: 1800 mm; Perimeter: 8354 mm; Area: 4.2786 m2; Volume: 0.203249 m3; Depth: 100 mm; NetVolume: 0.203249 m3
Component Quantities - Component, Component Volume (Net): 0.203249 m3; Component, Component Volume (Gross): 0.203249 m3

# IfcDoor: D2 25, m.01
In: Begane grond
Type - OperationType: DOUBLE_DOOR_SINGLE_SWING; ParameterTakesPrecedence: no; Sizeable: no
Type - Door Lining Properties - LiningDepth: 285 mm; LiningThickness: 90 mm; LiningOffset: -115 mm
Type - Door Panel Properties - Panel 1 - PanelDepth: 100 mm; PanelOperation: SWINGING; PanelWidth: 0.512376; PanelPosition: LEFT
Type - Door Panel Properties - Panel 2 - PanelDepth: 100 mm; PanelOperation: SWINGING; PanelWidth: 0.512376; PanelPosition: RIGHT
OverallHeight: 2400 mm; OverallWidth: 2200 mm; Classification: Deur (ARCHICAD Classification); 32 Binnenwandopeningen (NL/SfB (4 cijfers))
Pset_DoorCommon - AcousticRating: 55 dB; IsExternal: no
Material - Frame / Draaiend deel: arcering (01); Deurblad: arcering (02); Onderdorpel: %; Stofdorpel: arcering (01); Vensterbank: arcering (01); Ventilatierooster: %; Spouwlat: Naaldhout (01); Rollaag / Latei: arcering (01); Afwerking dagkant buiten: arcering (01); Afwerking dagkant binnen: arcering (01); Zonwering - behuizing: arcering (01); Zonwering - isolatie: Isolatie ruit; Glas: Glas - algemeen exterieur
Pset_FireRatingProperties - FireResistanceRating: Zelfsluitend
CPset_Phasing - Renovation Phase: Bestaand
AC_Pset_RenovationAndPhasing - Renovation Status: Existing
BaseQuantities - Height: 2400 mm; Width: 2200 mm; Perimeter: 9200 mm; Area: 5.28 m2; Volume: 0.641828 m3; Depth: 255 mm; NetVolume: 0.641828 m3
Component Quantities - Component, Component Volume (Net): 0.641828 m3; Component, Component Volume (Gross): 0.641828 m3

# IfcDoor: D2 25 (2)
In: Begane grond
Type - OperationType: DOUBLE_DOOR_SINGLE_SWING; ParameterTakesPrecedence: no; Sizeable: no
Type - Door Lining Properties - LiningDepth: 68 mm; LiningThickness: 76 mm; LiningOffset: -86 mm
Type - Door Panel Properties - Panel 1 - PanelDepth: 63 mm; PanelOperation: SWINGING; PanelWidth: 0.512207; PanelPosition: RIGHT
Type - Door Panel Properties - Panel 2 - PanelDepth: 63 mm; PanelOperation: SWINGING; PanelWidth: 0.512207; PanelPosition: LEFT
OverallHeight: 2645 mm; OverallWidth: 2200 mm; Classification: Deur (ARCHICAD Classification); 31 Buitenwandopeningen (NL/SfB (4 cijfers))
Pset_DoorCommon - IsExternal: yes
Material - Frame / Draaiend deel: arcering (01); Deurblad: arcering (02); Onderdorpel: %; Stofdorpel: arcering (01); Vensterbank: arcering (01); Ventilatierooster: %; Spouwlat: Naaldhout (01); Rollaag / Latei: arcering (01); Afwerking dagkant buiten: arcering (01); Afwerking dagkant binnen: arcering (01); Zonwering - behuizing: arcering (01); Zonwering - isolatie: Isolatie ruit; Glas: Glas - algemeen exterieur
CPset_Phasing - Renovation Phase: Bestaand
AC_Pset_RenovationAndPhasing - Renovation Status: Existing
BaseQuantities - Height: 2610 mm; Width: 2200 mm; Perimeter: 9620 mm; Area: 5.742 m2; Volume: 0.397251 m3; Depth: 436 mm; NetVolume: 0.397251 m3
Component Quantities - Component, Component Volume (Net): 0.397251 m3; Component, Component Volume (Gross): 0.397251 m3
Name
Merk DL
Merk DM

# IfcDoor: D2 25 (2)
In: Begane grond
Type - OperationType: DOUBLE_DOOR_SINGLE_SWING; ParameterTakesPrecedence: no; Sizeable: no
Type - Door Lining Properties - LiningDepth: 68 mm; LiningThickness: 76 mm; LiningOffset: 18 mm
Type - Door Panel Properties - Panel 1 - PanelDepth: 63 mm; PanelOperation: SWINGING; PanelWidth: 0.513528; PanelPosition: RIGHT
Type - Door Panel Properties - Panel 2 - PanelDepth: 63 mm; PanelOperation: SWINGING; PanelWidth: 0.513528; PanelPosition: LEFT
OverallHeight: 2665 mm; OverallWidth: 2000 mm; Classification: Deur (ARCHICAD Classification); 31 Buitenwandopeningen (NL/SfB (4 cijfers))
Pset_DoorCommon - GlazingAreaFraction: 3.51547; IsExternal: yes
Material - Frame / Draaiend deel: arcering (01); Deurblad: arcering (02); Onderdorpel: %; Stofdorpel: arcering (01); Vensterbank: arcering (01); Ventilatierooster: %; Spouwlat: Naaldhout (01); Rollaag / Latei: arcering (01); Afwerking dagkant buiten: arcering (01); Afwerking dagkant binnen: arcering (01); Zonwering - behuizing: arcering (01); Zonwering - isolatie: Isolatie ruit; Glas: Glas - algemeen exterieur
CPset_Phasing - Renovation Phase: Bestaand
AC_Pset_RenovationAndPhasing - Renovation Status: Existing
BaseQuantities - Height: 2665 mm; Width: 2000 mm; Perimeter: 9330 mm; Area: 5.33 m2; Volume: 0.117043 m3; Depth: 205 mm; NetVolume: 0.117043 m3
Component Quantities - Component, Component Volume (Net): 0.117043 m3; Component, Component Volume (Gross): 0.117043 m3
Name
Merk DN
Merk DN-sp

# IfcDoor: D2 25, Merk DI
In: Begane grond
Type - OperationType: DOUBLE_DOOR_SINGLE_SWING; ParameterTakesPrecedence: no; Sizeable: no
Type - Door Lining Properties - LiningDepth: 68 mm; LiningThickness: 76 mm; LiningOffset: 18 mm
Type - Door Panel Properties - Panel 1 - PanelDepth: 63 mm; PanelOperation: SWINGING; PanelWidth: 0.514302; PanelPosition: LEFT
Type - Door Panel Properties - Panel 2 - PanelDepth: 63 mm; PanelOperation: SWINGING; PanelWidth: 0.514302; PanelPosition: RIGHT
OverallHeight: 2815 mm; OverallWidth: 1900 mm; Classification: Deur (ARCHICAD Classification); 32 Binnenwandopeningen (NL/SfB (4 cijfers))
Pset_DoorCommon - IsExternal: no
Material - Frame / Draaiend deel: arcering (01); Deurblad: arcering (02); Onderdorpel: %; Stofdorpel: arcering (01); Vensterbank: arcering (01); Ventilatierooster: %; Spouwlat: Naaldhout (01); Rollaag / Latei: arcering (01); Afwerking dagkant buiten: arcering (01); Afwerking dagkant binnen: arcering (01); Zonwering - behuizing: arcering (01); Zonwering - isolatie: Isolatie ruit; Glas: Glas - algemeen exterieur
CPset_Phasing - Renovation Phase: Bestaand
AC_Pset_RenovationAndPhasing - Renovation Status: Existing
BaseQuantities - Height: 2780 mm; Width: 1900 mm; Perimeter: 9360 mm; Area: 5.282 m2; Volume: 0.339759 m3; Depth: 436 mm; NetVolume: 0.339759 m3
Component Quantities - Component, Component Volume (Net): 0.339759 m3; Component, Component Volume (Gross): 0.339759 m3

# IfcDoor: D2 25, Merk DC
In: Begane grond
Type - OperationType: DOUBLE_DOOR_SINGLE_SWING; ParameterTakesPrecedence: no; Sizeable: no
Type - Door Lining Properties - LiningDepth: 68 mm; LiningThickness: 76 mm; LiningOffset: 218 mm
Type - Door Panel Properties - Panel 1 - PanelDepth: 63 mm; PanelOperation: SWINGING; PanelWidth: 0.512207; PanelPosition: RIGHT
Type - Door Panel Properties - Panel 2 - PanelDepth: 63 mm; PanelOperation: SWINGING; PanelWidth: 0.512207; PanelPosition: LEFT
OverallHeight: 2815 mm; OverallWidth: 2200 mm; Classification: Deur (ARCHICAD Classification); 31 Buitenwandopeningen (NL/SfB (4 cijfers))
Pset_DoorCommon - IsExternal: yes
Material - Frame / Draaiend deel: arcering (01); Deurblad: arcering (02); Onderdorpel: %; Stofdorpel: arcering (01); Vensterbank: arcering (01); Ventilatierooster: %; Spouwlat: Naaldhout (01); Rollaag / Latei: arcering (01); Afwerking dagkant buiten: arcering (01); Afwerking dagkant binnen: arcering (01); Zonwering - behuizing: arcering (01); Zonwering - isolatie: Isolatie ruit; Glas: Glas - algemeen exterieur
CPset_Phasing - Renovation Phase: Bestaand
AC_Pset_RenovationAndPhasing - Renovation Status: Existing
BaseQuantities - Height: 2780 mm; Width: 2200 mm; Perimeter: 9960 mm; Area: 6.116 m2; Volume: 0.39816 m3; Depth: 460 mm; NetVolume: 0.39816 m3
Component Quantities - Component, Component Volume (Net): 0.39816 m3; Component, Component Volume (Gross): 0.39816 m3

# IfcDoor: D2 bl 25, b2.03
In: Begane grond
Type - OperationType: DOUBLE_DOOR_SINGLE_SWING; ParameterTakesPrecedence: no; Sizeable: no
Type - Door Lining Properties - LiningDepth: 114 mm; LiningThickness: 67 mm; TransomThickness: 90 mm; TransomOffset: 2310 mm; LiningOffset: -1.38778e-14 mm
Type - Door Panel Properties - Panel 1 - PanelDepth: 40 mm; PanelOperation: SWINGING; PanelWidth: 0.375134; PanelPosition: LEFT
Type - Door Panel Properties - Panel 2 - PanelDepth: 40 mm; PanelOperation: SWINGING; PanelWidth: 0.643087; PanelPosition: RIGHT
OverallHeight: 2800 mm; OverallWidth: 2000 mm; Classification: Deur (ARCHICAD Classification); 32 Binnenwandopeningen (NL/SfB (4 cijfers))
Pset_DoorCommon - AcousticRating: ---; GlazingAreaFraction: 3.22688; IsExternal: no
Material - Frame / Draaiend deel: arcering (01); Deurblad: arcering (02); Onderdorpel: %; Stofdorpel: arcering (01); Vensterbank: arcering (01); Ventilatierooster: %; Spouwlat: Naaldhout (01); Rollaag / Latei: arcering (01); Afwerking dagkant buiten: arcering (01); Afwerking dagkant binnen: arcering (01); Zonwering - behuizing: arcering (01); Zonwering - isolatie: Isolatie ruit; Glas: Glas - algemeen exterieur
Pset_FireRatingProperties - FireResistanceRating: ---
CPset_Phasing - Renovation Phase: Bestaand
AC_Pset_RenovationAndPhasing - Renovation Status: Existing
BaseQuantities - Height: 2800 mm; Width: 2000 mm; Perimeter: 9600 mm; Area: 5.6 m2; Volume: 0.144644 m3; Depth: 150 mm; NetVolume: 0.144644 m3
Component Quantities - Component, Component Volume (Net): 0.144644 m3; Component, Component Volume (Gross): 0.144644 m3

# IfcDoor: D2 bl 25, b2.06
In: Begane grond
Type - OperationType: DOUBLE_DOOR_SINGLE_SWING; ParameterTakesPrecedence: no; Sizeable: no
Type - Door Lining Properties - LiningDepth: 114 mm; LiningThickness: 67 mm; TransomThickness: 90 mm; TransomOffset: 2310 mm; LiningOffset: -100 mm
Type - Door Panel Properties - Panel 1 - PanelDepth: 40 mm; PanelOperation: SWINGING; PanelWidth: 0.508228; PanelPosition: LEFT
Type - Door Panel Properties - Panel 2 - PanelDepth: 40 mm; PanelOperation: SWINGING; PanelWidth: 0.508228; PanelPosition: RIGHT
OverallHeight: 2800 mm; OverallWidth: 2200 mm; Classification: Deur (ARCHICAD Classification); 32 Binnenwandopeningen (NL/SfB (4 cijfers))
Pset_DoorCommon - AcousticRating: ---; GlazingAreaFraction: 3.64088; IsExternal: no
Material - Frame / Draaiend deel: arcering (01); Deurblad: arcering (02); Onderdorpel: %; Stofdorpel: arcering (01); Vensterbank: arcering (01); Ventilatierooster: %; Spouwlat: Naaldhout (01); Rollaag / Latei: arcering (01); Afwerking dagkant buiten: arcering (01); Afwerking dagkant binnen: arcering (01); Zonwering - behuizing: arcering (01); Zonwering - isolatie: Isolatie ruit; Glas: Glas - algemeen exterieur
Pset_FireRatingProperties - FireResistanceRating: Zelfsluitend
CPset_Phasing - Renovation Phase: Bestaand
AC_Pset_RenovationAndPhasing - Renovation Status: Existing
BaseQuantities - Height: 2800 mm; Width: 2200 mm; Perimeter: 10000 mm; Area: 6.16 m2; Volume: 0.152807 m3; Depth: 100 mm; NetVolume: 0.152807 m3
Component Quantities - Component, Component Volume (Net): 0.152807 m3; Component, Component Volume (Gross): 0.152807 m3

# IfcDoor: D2 bl 25, b2.05
In: Begane grond
Type - OperationType: DOUBLE_DOOR_SINGLE_SWING; ParameterTakesPrecedence: no; Sizeable: no
Type - Door Lining Properties - LiningDepth: 114 mm; LiningThickness: 67 mm; TransomThickness: 90 mm; TransomOffset: 2310 mm; LiningOffset: -114 mm
Type - Door Panel Properties - Panel 1 - PanelDepth: 40 mm; PanelOperation: SWINGING; PanelWidth: 0.508873; PanelPosition: RIGHT
Type - Door Panel Properties - Panel 2 - PanelDepth: 40 mm; PanelOperation: SWINGING; PanelWidth: 0.508873; PanelPosition: LEFT
OverallHeight: 2800 mm; OverallWidth: 2050 mm; Classification: Deur (ARCHICAD Classification); 32 Binnenwandopeningen (NL/SfB (4 cijfers))
Pset_DoorCommon - AcousticRating: ---; GlazingAreaFraction: 3.33037; IsExternal: no
Material - Frame / Draaiend deel: arcering (01); Deurblad: arcering (02); Onderdorpel: %; Stofdorpel: arcering (01); Vensterbank: arcering (01); Ventilatierooster: %; Spouwlat: Naaldhout (01); Rollaag / Latei: arcering (01); Afwerking dagkant buiten: arcering (01); Afwerking dagkant binnen: arcering (01); Zonwering - behuizing: arcering (01); Zonwering - isolatie: Isolatie ruit; Glas: Glas - algemeen exterieur
Pset_FireRatingProperties - FireResistanceRating: Zelfsluitend
CPset_Phasing - Renovation Phase: Bestaand
AC_Pset_RenovationAndPhasing - Renovation Status: Existing
BaseQuantities - Height: 2800 mm; Width: 2050 mm; Perimeter: 9700 mm; Area: 5.73999 m2; Volume: 0.146685 m3; Depth: 100 mm; NetVolume: 0.146685 m3
Component Quantities - Component, Component Volume (Net): 0.146685 m3; Component, Component Volume (Gross): 0.146685 m3

# IfcDoor: D2 bl 25, b2.04
In: Begane grond
Type - OperationType: DOUBLE_DOOR_SINGLE_SWING; ParameterTakesPrecedence: no; Sizeable: no
Type - Door Lining Properties - LiningDepth: 114 mm; LiningThickness: 67 mm; TransomThickness: 90 mm; TransomOffset: 2310 mm; LiningOffset: -14 mm
Type - Door Panel Properties - Panel 1 - PanelDepth: 40 mm; PanelOperation: SWINGING; PanelWidth: 0.508873; PanelPosition: LEFT
Type - Door Panel Properties - Panel 2 - PanelDepth: 40 mm; PanelOperation: SWINGING; PanelWidth: 0.508873; PanelPosition: RIGHT
OverallHeight: 2800 mm; OverallWidth: 2050 mm; Classification: Deur (ARCHICAD Classification); 32 Binnenwandopeningen (NL/SfB (4 cijfers))
Pset_DoorCommon - AcousticRating: ---; GlazingAreaFraction: 3.33038; IsExternal: no
Material - Frame / Draaiend deel: arcering (01); Deurblad: arcering (02); Onderdorpel: %; Stofdorpel: arcering (01); Vensterbank: arcering (01); Ventilatierooster: %; Spouwlat: Naaldhout (01); Rollaag / Latei: arcering (01); Afwerking dagkant buiten: arcering (01); Afwerking dagkant binnen: arcering (01); Zonwering - behuizing: arcering (01); Zonwering - isolatie: Isolatie ruit; Glas: Glas - algemeen exterieur
Pset_FireRatingProperties - FireResistanceRating: Zelfsluitend
CPset_Phasing - Renovation Phase: Bestaand
AC_Pset_RenovationAndPhasing - Renovation Status: Existing
BaseQuantities - Height: 2800 mm; Width: 2050 mm; Perimeter: 9700 mm; Area: 5.74 m2; Volume: 0.146685 m3; Depth: 100 mm; NetVolume: 0.146685 m3
Component Quantities - Component, Component Volume (Net): 0.146685 m3; Component, Component Volume (Gross): 0.146685 m3

# IfcDoor: D2 bl 25 (2)
In: Begane grond
Type - OperationType: DOUBLE_DOOR_SINGLE_SWING; ParameterTakesPrecedence: no; Sizeable: no
Type - Door Lining Properties - LiningDepth: 114 mm; LiningThickness: 67 mm; TransomThickness: 90 mm; TransomOffset: 2310 mm; LiningOffset: -50 mm
Type - Door Panel Properties - Panel 1 - PanelDepth: 40 mm; PanelOperation: SWINGING; PanelWidth: 0.50911; PanelPosition: RIGHT
Type - Door Panel Properties - Panel 2 - PanelDepth: 40 mm; PanelOperation: SWINGING; PanelWidth: 0.50911; PanelPosition: LEFT
OverallHeight: 2800 mm; OverallWidth: 2000 mm; Classification: Deur (ARCHICAD Classification); 32 Binnenwandopeningen (NL/SfB (4 cijfers))
Pset_DoorCommon - AcousticRating: ---; GlazingAreaFraction: 3.22688; IsExternal: no
Material - Frame / Draaiend deel: arcering (01); Deurblad: arcering (02); Onderdorpel: %; Stofdorpel: arcering (01); Vensterbank: arcering (01); Ventilatierooster: %; Spouwlat: Naaldhout (01); Rollaag / Latei: arcering (01); Afwerking dagkant buiten: arcering (01); Afwerking dagkant binnen: arcering (01); Zonwering - behuizing: arcering (01); Zonwering - isolatie: Isolatie ruit; Glas: Glas - algemeen exterieur
CPset_Phasing - Renovation Phase: Bestaand
AC_Pset_RenovationAndPhasing - Renovation Status: Existing
BaseQuantities - Height: 2800 mm; Volume: 0.144644 m3; Depth: 100 mm; NetVolume: 0.144644 m3
Component Quantities - Component, Component Volume (Net): 0.144644 m3; Component, Component Volume (Gross): 0.144644 m3
Name | FireResistanceRating | Width (mm) | Perimeter (mm) | Area (m2)
b2.02 | Zelfsluitend | 2000 | 9600 | 5.6
b2.01 | --- | 1998 | 9596 | 5.5944

# IfcDoor: D2 bl 25 (2)
In: Begane grond
Type - OperationType: DOUBLE_DOOR_SINGLE_SWING; ParameterTakesPrecedence: no; Sizeable: no
Type - Door Lining Properties - LiningDepth: 68 mm; LiningThickness: 76 mm; TransomThickness: 76 mm; TransomOffset: 2350 mm; LiningOffset: 18 mm
Type - Door Panel Properties - Panel 1 - PanelDepth: 63 mm; PanelOperation: SWINGING; PanelWidth: 0.512207; PanelPosition: RIGHT
Type - Door Panel Properties - Panel 2 - PanelDepth: 63 mm; PanelOperation: SWINGING; PanelWidth: 0.512207; PanelPosition: LEFT
OverallHeight: 2815 mm; OverallWidth: 2200 mm; Classification: Deur (ARCHICAD Classification); 31 Buitenwandopeningen (NL/SfB (4 cijfers))
Pset_DoorCommon - GlazingAreaFraction: 4.23792; IsExternal: yes
Material - Frame / Draaiend deel: arcering (01); Deurblad: arcering (02); Onderdorpel: %; Stofdorpel: arcering (01); Vensterbank: arcering (01); Ventilatierooster: %; Spouwlat: Naaldhout (01); Rollaag / Latei: arcering (01); Afwerking dagkant buiten: arcering (01); Afwerking dagkant binnen: arcering (01); Zonwering - behuizing: arcering (01); Zonwering - isolatie: Isolatie ruit; Glas: Glas - algemeen exterieur
Pset_FireRatingProperties - FireResistanceRating: Zelfsluitend
CPset_Phasing - Renovation Phase: Bestaand
AC_Pset_RenovationAndPhasing - Renovation Status: Existing
BaseQuantities - Height: 2780 mm; Width: 2200 mm; Perimeter: 9960 mm; Area: 6.116 m2; Volume: 0.153441 m3; Depth: 460 mm; NetVolume: 0.153441 m3
Component Quantities - Component, Component Volume (Net): 0.153441 m3; Component, Component Volume (Gross): 0.153441 m3
Name
Merk DE
Merk DD

# IfcDoor: D2 bl 25 (2)
In: Begane grond
Type - OperationType: DOUBLE_DOOR_SINGLE_SWING; ParameterTakesPrecedence: no; Sizeable: no
Type - Door Lining Properties - LiningDepth: 68 mm; LiningThickness: 76 mm; TransomThickness: 76 mm; TransomOffset: 2350 mm; LiningOffset: 18 mm
Type - Door Panel Properties - Panel 1 - PanelDepth: 63 mm; PanelOperation: SWINGING; PanelWidth: 0.513172; PanelPosition: RIGHT
Type - Door Panel Properties - Panel 2 - PanelDepth: 63 mm; PanelOperation: SWINGING; PanelWidth: 0.513172; PanelPosition: LEFT
OverallHeight: 2815 mm; OverallWidth: 2050 mm; Classification: Deur (ARCHICAD Classification); 31 Buitenwandopeningen (NL/SfB (4 cijfers))
Pset_DoorCommon - IsExternal: yes
Material - Frame / Draaiend deel: arcering (01); Deurblad: arcering (02); Onderdorpel: %; Stofdorpel: arcering (01); Vensterbank: arcering (01); Ventilatierooster: %; Spouwlat: Naaldhout (01); Rollaag / Latei: arcering (01); Afwerking dagkant buiten: arcering (01); Afwerking dagkant binnen: arcering (01); Zonwering - behuizing: arcering (01); Zonwering - isolatie: Isolatie ruit; Glas: Glas - algemeen exterieur
Pset_FireRatingProperties - FireResistanceRating: Zelfsluitend
CPset_Phasing - Renovation Phase: Bestaand
AC_Pset_RenovationAndPhasing - Renovation Status: Existing
BaseQuantities - Height: 2780 mm; Width: 2050 mm; Perimeter: 9660 mm; Volume: 0.14828 m3; NetVolume: 0.14828 m3
Component Quantities - Component, Component Volume (Net): 0.14828 m3; Component, Component Volume (Gross): 0.14828 m3
Name | GlazingAreaFraction | Area (m2) | Depth (mm)
Merk DG | 3.86712 | 5.699 | 396
Merk DB | 3.86711 | 5.69899 | 460

# IfcDoor: D2 bl 25 (2)
In: Begane grond
Type - OperationType: DOUBLE_DOOR_SINGLE_SWING; ParameterTakesPrecedence: no; Sizeable: no
Type - Door Lining Properties - LiningDepth: 68 mm; LiningThickness: 76 mm; TransomThickness: 76 mm; TransomOffset: 2350 mm; LiningOffset: 197 mm
Type - Door Panel Properties - Panel 1 - PanelDepth: 63 mm; PanelOperation: SWINGING; PanelWidth: 0.512207; PanelPosition: LEFT
Type - Door Panel Properties - Panel 2 - PanelDepth: 63 mm; PanelOperation: SWINGING; PanelWidth: 0.512207; PanelPosition: RIGHT
OverallHeight: 2815 mm; OverallWidth: 2200 mm; Classification: Deur (ARCHICAD Classification); 31 Buitenwandopeningen (NL/SfB (4 cijfers))
Pset_DoorCommon - GlazingAreaFraction: 4.23792; IsExternal: yes
Material - Frame / Draaiend deel: arcering (01); Deurblad: arcering (02); Onderdorpel: %; Stofdorpel: arcering (01); Vensterbank: arcering (01); Ventilatierooster: %; Spouwlat: Naaldhout (01); Rollaag / Latei: arcering (01); Afwerking dagkant buiten: arcering (01); Afwerking dagkant binnen: arcering (01); Zonwering - behuizing: arcering (01); Zonwering - isolatie: Isolatie ruit; Glas: Glas - algemeen exterieur
Pset_FireRatingProperties - FireResistanceRating: Zelfsluitend
CPset_Phasing - Renovation Phase: Bestaand
AC_Pset_RenovationAndPhasing - Renovation Status: Existing
BaseQuantities - Height: 2780 mm; Width: 2200 mm; Perimeter: 9960 mm; Area: 6.116 m2; Volume: 0.153441 m3; Depth: 340 mm; NetVolume: 0.153441 m3
Component Quantities - Component, Component Volume (Net): 0.153441 m3; Component, Component Volume (Gross): 0.153441 m3

# IfcFurnishingElement: Kookplaat inbouw 25, Keuken
In: Begane grond
Classification: 73 Vaste keukenvoorzieningen (NL/SfB (4 cijfers)); Inrichting (ARCHICAD Classification)
CPset_Phasing - Renovation Phase: Bestaand
AC_Pset_RenovationAndPhasing - Renovation Status: Existing
Component Quantities - Component, Component Volume (Net): 0.0077731 m3; Component, Component Volume (Gross): 0.0077731 m3

# IfcFurnishingElement: Onderkast recht 25 (24)
Classification: 73 Vaste keukenvoorzieningen (NL/SfB (4 cijfers)); Inrichting (ARCHICAD Classification)
CPset_Phasing - Renovation Phase: Bestaand
AC_Pset_RenovationAndPhasing - Renovation Status: Existing
Name | In | Component, Component Volume (Net) (m3) = Component, Component Volume (Gross) (m3)
2 x verschoontafel KDV | KDV/ POV | 0.234119
verschoontafel KDV | KDV/ POV | 0.0851888
douchecabines | BS | 0.0739357
douchecabines | BS | 0.0757156
Keuken | KC | 0.188598
douchecabines | KC | 0.079116
douchecabines | KC | 0.0843759
2 x douchecabines | KC | 0.0948682
2 x douchecabines | BS | 0.109371
2 x douchecabines | BS | 0.0454538
douchecabines | BS | 0.0518608
douchecabines | BS | 0.0739397
2 x douchecabines | BS | 0.0757196
douchecabines | BS | 0.0704597
douchecabines | KDV/ POV | 0.0812688
2 x douchecabines | KDV/ POV | 0.0728112
2 x douchecabines | KDV/ POV | 0.0973973

# IfcFurnishingElement: Sanitaire wanden 25 (11)
In: Begane grond
Classification: 74 Vaste sanitaire voorzieningen (NL/SfB (4 cijfers)); Inrichting (ARCHICAD Classification)
CPset_Phasing - Renovation Phase: Bestaand
AC_Pset_RenovationAndPhasing - Renovation Status: Existing
Name | Component, Component Volume (Net) (m3) = Component, Component Volume (Gross) (m3)
sanitaire scheidingswanden | 0.0419507
sanitaire scheidingswanden | 0.0251533
sanitaire scheidingswanden | 0.0252099
sanitaire scheidingswanden | 0.0943369
2 x douchecabines | 0.0329842
2 x douchecabines | 0.0832487
2 x douchecabines | 0.033364
sanitaire scheidingswanden | 0.019378

# IfcFurnishingElement: Scheidingwanden 25 (7)
In: Begane grond
Classification: 74 Vaste sanitaire voorzieningen (NL/SfB (4 cijfers)); Inrichting (ARCHICAD Classification)
CPset_Phasing - Renovation Phase: Bestaand
AC_Pset_RenovationAndPhasing - Renovation Status: Existing
Name | Component, Component Volume (Net) (m3) = Component, Component Volume (Gross) (m3)
Urinoir | 0.033
douchecabines | 0.0153725
5 x douchecabines | 0.015158

# IfcMember: L60/6 (16)
In: Begane grond
Description: L60/6; Classification: Onderdeel (ARCHICAD Classification); Material: STEEL/S235
Pset_MemberCommon - FireRating: R30; Reference: MLO0(?); IsExternal: no
Tekla Common - Phase: 1; Class: 13
Tekla Quantity - Gross footprint area: 0 m2; Area per tons: 43.428 m2; Height: 60 mm; Width: 60 mm
CPset_Phasing - Renovation Phase: Bestaand
AC_Pset_RenovationAndPhasing - Renovation Status: Existing
Material Properties - STEEL/S235, ThermalConductivity: 2.3; STEEL/S235, SpecificHeatCapacity: 1000 J/kg/K; STEEL/S235, MassDensity: 2300 kg/m3; STEEL/S235, Embodied Energy: 1.92 (MJ/kg); STEEL/S235, Embodied Carbon: 0.198 (kgCO₂/kg); STEEL/S235, Name: STEEL/S235; STEEL/S235, Participates in Collision Detection: yes
Name | LoadBearing | Bottom elevation | Top elevation | Weight (kg) | Volume (m3) | Net surface area (m2) | Length (mm) | STEEL/S235, Mass (kg) | STEEL/S235, Component Volume (Net) (m3) = STEEL/S235, Component Volume (Gross) (m3)
2 x WINDVERBAND | no | +2.810 | +6.400 | 37.87 | 0.005 | 1.646 | 6851.9 | 10.8977 | 0.00473814
2 x WINDVERBAND | yes | +0.076 | +2.690 | 35.11 | 0.004 | 1.526 | 6352.3 | 10.1032 | 0.00439269
2 x WINDVERBAND | yes | +0.086 | +2.690 | 31.05 | 0.004 | 1.35 | 5618.3 | 8.93578 | 0.00388512
2 x WINDVERBAND | no | +2.810 | +6.400 | 37.88 | 0.005 | 1.646 | 6853.6 | 10.9004 | 0.00473932
2 x WINDVERBAND | no | +2.810 | +6.386 | 34.05 | 0.004 | 1.48 | 6160.9 | 9.79869 | 0.0042603
2 x WINDVERBAND | yes | +0.086 | +2.690 | 31.05 | 0.004 | 1.35 | 5618.3 | 8.93573 | 0.0038851
2 x WINDVERBAND | no | +2.810 | +6.386 | 34.05 | 0.004 | 1.48 | 6160.9 | 9.79864 | 0.00426028
2 x WINDVERBAND | yes | +0.076 | +2.690 | 35.11 | 0.004 | 1.526 | 6354.1 | 10.1061 | 0.00439394

# IfcOpeningElement (347)
In: Begane grond
Name | Depth (mm) | Height (mm) | Width (mm) | Area (m2) | Volume (m3)
14 x b1.01 | 100 | 2377 | 1034 | 2.45782 | 0.12662
b1.08g | 100 | 2377 | 984 | 2.33897 | 0.11791
b1.08g-sp | 100 | 2377 | 984 | 2.33897 | 0.11791
5 x s.02 | 100 | 2400 | 3000 | 7.2 | 0.23336
2 x b0.03B | 214 | 1177 | 1700 | 2.0009 | 0.0419021
2 x b1.25Bg | 214 | 2377 | 2500 | 5.9425 | 0.122558
wandopening | 200 | 2970 | 9320 | 27.6804 | 0
2 x b1.04 | 100 | 2377 | 1034 | 2.45782 | 0.075622
b2.07 | 200 | 2377 | 1900 | 4.5163 | 0.115981
4 x Merk AE | 205 | 2665 | 1976.67 | 5.26782 | 0.075868
2 x Merk AF | 205 | 2665 | 1981.7 | 5.28123 | 0.0759196
3 x b1.23g | 100 | 2377 | 2000 | 4.754 | 0.113392
b2.02 | 100 | 2800 | 2000 | 5.6 | 0.144644
b1.05g | 100 | 2377 | 1034 | 2.45782 | 0.075622
b2.09 | 100 | 2377 | 1800 | 4.2786 | 0.203249
4 x nis tbv luifel | 486 | 0 | 0 | 0 | 0
s.07 | 200 | 2330 | 2800 | 6.524 | 0.10333
2 x s.04 | 200 | 2400 | 4400 | 10.56 | 0.287901
2 x s.04-sp | 200 | 2400 | 4400 | 10.56 | 0.287901
 | 600 | 2600 | 3600 | 9.36 | 0
2 x b0.01 | 100 | 1177 | 673.96 | 0.793251 | 0.0262283
b1.04-sp | 100 | 2377 | 1034 | 2.45782 | 0.075622
b1.07 | 100 | 2377 | 984 | 2.33897 | 0.0740941
3 x nis tbv luifel | 436 | 1350 | 2750.02 | 3.71252 | 0
11 x nis tbv luifel | 436 | 0 | 0 | 0 | 0
4 x b1.10 | 200 | 2377 | 1034 | 2.45782 | 0.12662
b2.11 | 200 | 2377 | 1800 | 4.2786 | 0.203249
2 x Merk AD | 205 | 2665 | 1500 | 3.9975 | 0.0361903
Merk DN | 205 | 2665 | 2000 | 5.33 | 0.117043
2 x nis tbv luifel | 396 | 0 | 0 | 0 | 0
Merk DJ | 396 | 2610 | 1750 | 4.5675 | 0.115758
s.06 | 100 | 2330 | 2570 | 5.9881 | 0.0972466
s.01 | 100 | 2400 | 4400 | 10.56 | 0.287901
s.05 | 100 | 2330 | 2800 | 6.524 | 0.10333
b1.09 | 100 | 2377 | 984 | 2.33897 | 0.121618
5 x Merk AA | 436 | 2780 | 2010 | 5.5878 | 0.143672
7 x Merk AA-sp | 436 | 2780 | 2010 | 5.5878 | 0.143672
6 x Merk DA-n | 436 | 2780 | 2010 | 5.5878 | 0.147755
5 x b1.01-sp | 100 | 2377 | 1034 | 2.45782 | 0.12662
b1.01 | 100 | 2377 | 1008 | 2.39602 | 0.12662
4 x b1.15 | 200 | 2377 | 1034 | 2.45782 | 0.12662
b1.15-sp | 200 | 2377 | 1034 | 2.45782 | 0.12662
b1.18 | 200 | 2377 | 1118 | 2.65749 | 0.107916
2 x Merk AG | 205 | 2665 | 2642.5 | 7.04226 | 0.0826492
Merk AI | 205 | 2665 | 891.188 | 2.37502 | 0.0347577
2 x Merk AH | 205 | 2665 | 2425 | 6.46263 | 0.0804342
Merk DN-sp | 205 | 2665 | 2000 | 5.33 | 0.117043
b1.21B | 200 | 2800 | 1800 | 5.03999 | 0.135419
b0.02g | 200 | 1157 | 6300 | 7.2891 | 0.132858
b1.06g | 200 | 2377 | 1034 | 2.45782 | 0.075622
b2.06 | 100 | 2800 | 2200 | 6.16 | 0.152807
b2.05 | 100 | 2800 | 2050 | 5.73999 | 0.146685
2 x b1.24g | 100 | 2377 | 2140 | 5.08678 | 0.117059
wandopening | 100 | 2800 | 1600 | 4.48 | 0
3 x nis tbv luifel | 340 | 0 | 0 | 0 | 0
2 x Merk DH | 340 | 2780 | 2200 | 6.116 | 0.153441
6 x  | 0 | 2510 | 640 | 1.6064 | 0 | Classification: 32 Binnenwandopeningen (NL/SfB (4 cijfers)); Lege opening (ARCHICAD Classification); CPset_Phasing - Renovation Phase: Bestaand; AC_Pset_RenovationAndPhasing - Renovation Status: Existing
3 x Merk AB | 460 | 2030 | 2010 | 4.0803 | 0.0778911
Merk DE | 460 | 2780 | 2200 | 6.116 | 0.153441
Merk DF | 460 | 2780 | 1200 | 3.336 | 0.0896562
opening | 214 | 2377 | 1680 | 3.99336 | 0
b1.03 | 214 | 2377 | 1034 | 2.45782 | 0.12662
2 x Merk DA | 436 | 2780 | 2010 | 5.5878 | 0.147755
b2.01 | 100 | 2800 | 1998 | 5.5944 | 0.144644
Merk AC | 312 | 2030 | 2010 | 4.0803 | 0.0983694
Merk DA-sp | 312 | 2780 | 2010 | 5.5878 | 0.150834
wandopening | 100 | 3270 | 8650.01 | 28.2855 | 0
2 x Merk DA-sp | 436 | 2780 | 2010 | 5.5878 | 0.147755
Merk AC-sp | 396 | 2030 | 2010 | 4.0803 | 0.0983534
Merk DG | 396 | 2780 | 2050 | 5.699 | 0.14828
3 x Merk AA | 500 | 2780 | 2010 | 5.5878 | 0.143672
2 x Merk AA-sp | 500 | 2780 | 2010 | 5.5878 | 0.143672
nis tbv luifel | 500 | 0 | 0 | 0 | 0
2 x Merk DA | 500 | 2780 | 2010 | 5.5878 | 0.147755
s.08 | 200 | 2330 | 2570 | 5.9881 | 0.0972466
b2.04 | 100 | 2800 | 2050 | 5.74 | 0.146685
b1.22B | 100 | 2800 | 1998 | 5.5944 | 0.140527
Merk AB-sp | 460 | 2030 | 2010 | 4.0803 | 0.0778911
Merk DB | 460 | 2780 | 2050 | 5.69899 | 0.14828
Merk DD | 460 | 2780 | 2200 | 6.116 | 0.153441
Merk DC | 460 | 2780 | 2200 | 6.116 | 0.39816
s.03 | 200 | 2400 | 3000 | 7.2 | 0.23336
b2.08 | 100 | 2377 | 2200 | 5.2294 | 0.243265
2 x b2.10 | 200 | 2377 | 1800 | 4.2786 | 0.203249
Merk-x | 150 | 1250 | 1100 | 1.375 | 0
9 x b1.13-sp | 100 | 2377 | 1034 | 2.45782 | 0.12662
b1.14 | 150 | 2377 | 1034 | 2.45782 | 0.12662
b1.14-sp | 150 | 2377 | 1034 | 2.45782 | 0.12662
8 x b1.13 | 100 | 2377 | 1034 | 2.45782 | 0.12662
b1.12-sp | 100 | 2377 | 984 | 2.33897 | 0.121618
b1.12 | 100 | 2377 | 984 | 2.33897 | 0.121618
b2.12 | 100 | 2377 | 2200 | 5.2294 | 0.243265
b0.04 | 100 | 1577 | 973.248 | 1.53481 | 0.048731
b1.17 | 100 | 2377 | 1034 | 2.45782 | 0.0807332
2 x b1.11-sp | 100 | 2377 | 934 | 2.22012 | 0.116616
2 x b1.11 | 100 | 2377 | 934 | 2.22012 | 0.116616
b1.26 | 100 | 2600 | 1850 | 4.81 | 0.119804
b2.03 | 150 | 2800 | 2000 | 5.6 | 0.144644
b1.16 | 200 | 2377 | 1133.98 | 2.69547 | 0.136622
b1.20B | 100 | 2800 | 1800 | 5.03999 | 0.135419
Merk DK | 436 | 2610 | 1750 | 4.5675 | 0.115758
Merk DL | 436 | 2610 | 2200 | 5.742 | 0.397251
Merk DM | 436 | 2610 | 2200 | 5.742 | 0.397251
06 inbouwnis tbv bering klimtouwen | 70 | 2510 | 640 | 1.6064 | 0.112448 | Classification: 32 Binnenwandopeningen (NL/SfB (4 cijfers)); Lege opening (ARCHICAD Classification); CPset_Phasing - Renovation Phase: Bestaand; AC_Pset_RenovationAndPhasing - Renovation Status: Existing
b1.02 | 200 | 2377 | 1034 | 2.45782 | 0.12662
10 x Merk-x | 5 | 1350 | 1034 | 1.3959 | 0
33 x nis tbv luifel | 5 | 0 | 0 | 0 | 0.0027
2 x Merk-x | 5 | 1350 | 1026 | 1.3851 | 0
b1.07-sp | 100 | 2377 | 984 | 2.33897 | 0.0740941
4 x Merk-x | 5 | 2377 | 931.143 | 2.21333 | 0
5 x Merk-x | 5 | 2377 | 1034 | 2.45782 | 0
2 x Merk-x | 5 | 2377 | 1100 | 2.6147 | 0
3 x Merk-x | 5 | 1250 | 1100 | 1.375 | 0
Merk DI | 436 | 2780 | 1900 | 5.282 | 0.339759
2 x b0.05g | 255 | 2400 | 350 | 0.84 | 0.039962
m.01 | 255 | 2400 | 2200 | 5.28 | 0.641828
7 x raam panelenwand | 102 | 2020 | 857 | 1.73114 | 0.00117218
Merk-x | 5 | 927 | 1026 | 0.951102 | 0
2 x Merk-x | 5 | 2367 | 1034 | 2.44748 | 0
Merk-x - geluidwerend | 5 | 2377 | 984 | 2.33897 | 0
Merk-x - geluidwerend | 5 | 2377 | 981.623 | 2.33332 | 0
7 x Merk-x | 5 | 927 | 1018 | 0.943686 | 0
12 x Merk-x | 5 | 927 | 1034 | 0.958518 | 0
Merk-x | 5 | 927 | 1026 | 0.951103 | 0
Merk-x | 5 | 2277 | 1034 | 2.35442 | 0
4 x  | 5 | 2377 | 984 | 2.33897 | 0
Merk-x | 5 | 2377 | 1026 | 2.4388 | 0
b1.19 | 100 | 2800 | 1800 | 5.03999 | 0.135419
 | 5 | 2377 | 1031 | 2.45069 | 0
 | 5 | 2377 | 1026 | 2.43881 | 0
 | 5 | 2377 | 1031 | 2.45068 | 0
b1.09-sp | 100 | 2377 | 984 | 2.33897 | 0.121618
Merk-x | 5 | 2599.4 | 1845 | 4.79589 | 0
3 x  | 5 | 2377 | 1018.04 | 2.41987 | 0
 | 5 | 2377 | 1014 | 2.41028 | 0
2 x b2.10 | 5 | 2377 | 1800 | 4.2786 | 0
b2.10 | 5 | 2377 | 1034 | 2.45782 | 0
6 x raam panelenwand | 102 | 2320 | 925 | 2.146 | 0.00132233
12 x  | 19 | 60 | 120 | 0.0056186 | 0
 | 410 | 1049 | 5719.99 | 6.00027 | 0

# IfcRailing: Railing Type (4)
In: Begane grond
Classification: Reling (ARCHICAD Classification); 34 Balustrades en leuningen (NL/SfB (4 cijfers))
CPset_Phasing - Renovation Phase: Bestaand
AC_Pset_RenovationAndPhasing - Renovation Status: Existing
Pset_RailingCommon - IsExternal: no
Name | GrossVolume (m3) = NetVolume (m3) | Length (mm)
Reling-x | 0.0212525 | 15620.8
Reling-x | 0.0304517 | 22681.1
Reling-x | 0.0569849 | 45894
Reling-x | 0.0112902 | 8651.84

# IfcSlab: 160*4355, WAND-FUNDERING
In: Begane grond
Description: 160*4355; Classification: 47 Dakafwerkingen (NL/SfB (4 cijfers)); Vloer (ARCHICAD Classification); Material: CONCRETE/C30/37
Default - Stortmethode: Prefab; IS_EXTERNAL: Nee; LOAD_BEARING: Ondersteuning; FIRE_RATING: R30; IFC_BUILDING_STOREY: Undefined; IFC_BUILDING: Undefined; MATERIAL: C30/37; NAME: WAND-FUNDERING
Tekla Common - Bottom elevation: -0.430; Top elevation: -0.270; Phase: 1; Class: 1
Tekla Quantity - Weight: 7567.26 kg; Volume: 3.153 m3; Gross footprint area: 19.706 m2; Area per tons: 5.584 m2; Net surface area: 42.254 m2; Height: 4355 mm; Width: 160 mm; Length: 4525 mm
Pset_SlabCommon - Compartmentation: no; Combustible: no; FireRating: R30; Reference: 0(?); LoadBearing: yes; IsExternal: no
CPset_Phasing - Renovation Phase: Bestaand
AC_Pset_RenovationAndPhasing - Renovation Status: Existing
Material Properties - CONCRETE/C30/37, ThermalConductivity: 2.3; CONCRETE/C30/37, SpecificHeatCapacity: 1000 J/kg/K; CONCRETE/C30/37, MassDensity: 2300 kg/m3; CONCRETE/C30/37, Embodied Energy: 1.92 (MJ/kg); CONCRETE/C30/37, Embodied Carbon: 0.198 (kgCO₂/kg); CONCRETE/C30/37, Name: CONCRETE/C30/37; CONCRETE/C30/37, Participates in Collision Detection: yes
BaseQuantities - Width: 160 mm; Perimeter: 17760 mm; GrossArea: 19.7064 m2; NetArea: 19.7064 m2; GrossVolume: 3.15302 m3; NetVolume: 3.15302 m3
Component Quantities - CONCRETE/C30/37, Mass: 7251.95 kg; CONCRETE/C30/37, Projected Component Area (Net): 19.7064 m2; CONCRETE/C30/37, Projected Component Area (Gross): 19.7064 m2; CONCRETE/C30/37, Component Thickness: 160 mm; CONCRETE/C30/37, Component Volume (Net): 3.15302 m3; CONCRETE/C30/37, Component Volume (Gross): 3.15302 m3

# IfcWall: 022 dubbele gipsplaat 25 (9)
In: Begane grond
Type - PredefinedType: ELEMENTEDWALL
Classification: Samengestelde wand (ARCHICAD Classification); 21 Buitenwanden (NL/SfB (4 cijfers))
CPset_Phasing - Renovation Phase: Bestaand
AC_Pset_RenovationAndPhasing - Renovation Status: Existing
Pset_WallCommon - LoadBearing: yes; IsExternal: yes
BaseQuantities - Width: 25 mm
Name | Length (mm) | Height (mm) | GrossFootprintArea (m2) = NetFootprintArea (m2) | GrossSideArea (m2) = NetSideArea (m2) | GrossVolume (m3) = NetVolume (m3)
Koof | 1850 | 1199.2 | 0.04625 | 2.21853 | 0.0554632
2 x Koof | 4225 | 549.204 | 0.105938 | 2.32725 | 0.0581813
4 x Koof | 3025 | 549.204 | 0.0753125 | 1.65448 | 0.0413619
2 x Koof | 7225 | 549.204 | 0.180938 | 3.97486 | 0.0993716

# IfcWall: 21 Buitenwand mw - SAB binnendoos 340 (4)
In: Begane grond
Type - PredefinedType: ELEMENTEDWALL
Classification: Samengestelde wand (ARCHICAD Classification); 21 Buitenwanden (NL/SfB (4 cijfers))
CPset_Phasing - Renovation Phase: Bestaand
AC_Pset_RenovationAndPhasing - Renovation Status: Existing
Pset_WallCommon - LoadBearing: yes; IsExternal: yes
BaseQuantities - Height: 4255 mm; Width: 340 mm
Name | Length (mm) | GrossFootprintArea (m2) = NetFootprintArea (m2) | GrossSideArea (m2) | NetSideArea (m2) | GrossVolume (m3) | NetVolume (m3)
Buitenwand | 5757.01 | 2.006 | 22.7418 | 22.7418 | 7.79983 | 7.79983
Buitenwand | 21790 | 6.39784 | 92.7335 | 64.9498 | 31.7365 | 24.3925
Buitenwand | 6645.02 | 2.23429 | 28.0618 | 23.582 | 9.50691 | 8.61095
Buitenwand | 12620 | 4.26579 | 53.4854 | 44.6976 | 18.1509 | 16.3934

# IfcWall: 21 Buitenwand mw - binnenblad KZS 150mm 436 (4)
In: Begane grond
Type - PredefinedType: ELEMENTEDWALL
Classification: Samengestelde wand (ARCHICAD Classification); 21 Buitenwanden (NL/SfB (4 cijfers))
CPset_Phasing - Renovation Phase: Bestaand
AC_Pset_RenovationAndPhasing - Renovation Status: Existing
Pset_WallCommon - LoadBearing: yes; IsExternal: yes
BaseQuantities - Height: 4235 mm; Width: 436 mm
Name | Length (mm) | GrossFootprintArea (m2) = NetFootprintArea (m2) | GrossSideArea (m2) | NetSideArea (m2) | GrossVolume (m3) | NetVolume (m3)
Buitenwand | 23320 | 7.22156 | 89.5986 | 39.2664 | 40.309 | 22.1309
Buitenwand | 19200 | 5.95462 | 73.9698 | 32.2458 | 33.3149 | 18.2115
Buitenwand | 18922 | 5.81562 | 72.8689 | 31.2322 | 32.7786 | 17.6856
Buitenwand | 23250 | 7.22997 | 89.7043 | 39.4431 | 40.3121 | 22.1472

# IfcWall: 21 Buitenwand mw - binnenblad KZS 214mm 500, Buitenwand
In: Begane grond
Type - PredefinedType: ELEMENTEDWALL
Classification: Samengestelde wand (ARCHICAD Classification); 21 Buitenwanden (NL/SfB (4 cijfers))
CPset_Phasing - Renovation Phase: Bestaand
AC_Pset_RenovationAndPhasing - Renovation Status: Existing
Pset_WallCommon - LoadBearing: yes; IsExternal: yes
BaseQuantities - Length: 32466 mm; Height: 4235 mm; Width: 500 mm; GrossFootprintArea: 5.96814 m2; NetFootprintArea: 5.96814 m2; GrossSideArea: 124.631 m2; NetSideArea: 62.3272 m2; GrossVolume: 63.1712 m3; NetVolume: 38.7351 m3

# IfcWall: 21 Buitenwand mw - binnenblad betonsteen 150mm 436 (5)
In: Begane grond
Type - PredefinedType: ELEMENTEDWALL
Classification: Samengestelde wand (ARCHICAD Classification); 21 Buitenwanden (NL/SfB (4 cijfers))
CPset_Phasing - Renovation Phase: Bestaand
AC_Pset_RenovationAndPhasing - Renovation Status: Existing
Pset_WallCommon - LoadBearing: yes; IsExternal: yes
BaseQuantities - Width: 436 mm
Name | Length (mm) | Height (mm) | GrossFootprintArea (m2) = NetFootprintArea (m2) | GrossSideArea (m2) | NetSideArea (m2) | GrossVolume (m3) | NetVolume (m3)
Buitenwand | 10291 | 4065 | 4.5406 | 30.6026 | 29.4122 | 16.4532 | 15.3673
Buitenwand | 4918 | 4235 | 2.1724 | 21.1453 | 17.64 | 9.20009 | 8.50586
Buitenwand | 20898 | 4065 | 9.1146 | 75.8131 | 47.7651 | 34.0358 | 28.7381
Buitenwand | 36416 | 4065 | 14.3691 | 131.996 | 76.5767 | 59.7228 | 44.7461
Buitenwand | 4597.99 | 4235 | 2.06596 | 18.9907 | 13.6041 | 8.4175 | 6.06818

# IfcWall: 21 Buitenwand mw - binnenblad betonsteen 200mm 486 (4)
In: Begane grond
Type - PredefinedType: ELEMENTEDWALL
Classification: Samengestelde wand (ARCHICAD Classification); 21 Buitenwanden (NL/SfB (4 cijfers))
CPset_Phasing - Renovation Phase: Bestaand
AC_Pset_RenovationAndPhasing - Renovation Status: Existing
Pset_WallCommon - LoadBearing: yes; IsExternal: yes
BaseQuantities - Height: 4235 mm; Width: 486 mm
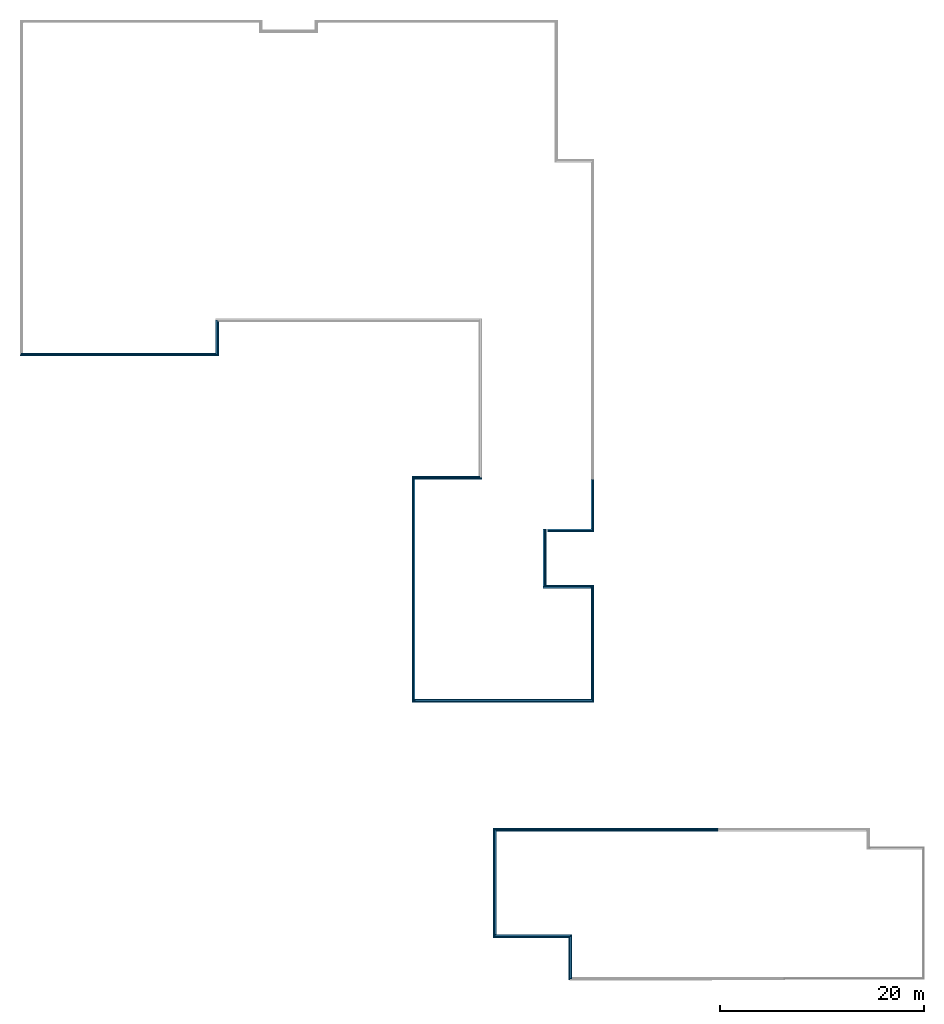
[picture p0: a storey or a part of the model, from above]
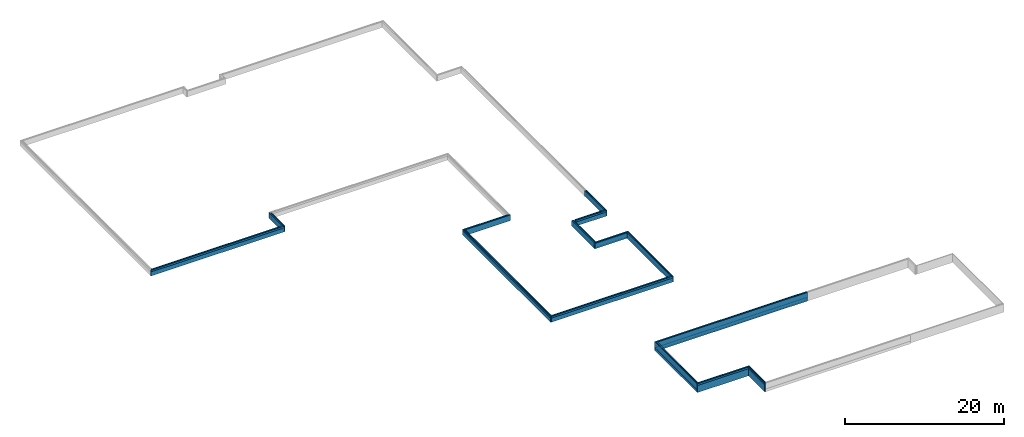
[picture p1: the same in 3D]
Properties of the parts of a building model (IFC2X3), part 17 of 19

# IfcWall: 21 Buitenwand mw - binnenblad betonsteen 200mm 486 (4)
Name | Length (mm) | GrossFootprintArea (m2) = NetFootprintArea (m2) | GrossSideArea (m2) | NetSideArea (m2) | GrossVolume (m3) | NetVolume (m3)
Buitenwand | 4608 | 2.32637 | 17.5654 | 17.5654 | 8.8183 | 8.80147
Buitenwand | 11890 | 5.77854 | 45.8062 | 37.6913 | 22.653 | 21.03
Buitenwand | 10965 | 5.329 | 40.6417 | 21.5437 | 20.1656 | 16.3459
Buitenwand | 4777.99 | 2.28521 | 17.5509 | 9.61629 | 8.68994 | 7.10302

# IfcWall: 21 Gevelplaat - binnenblad betonsteen 150 396 (3)
In: Begane grond
Type - PredefinedType: ELEMENTEDWALL
Classification: Samengestelde wand (ARCHICAD Classification); 21 Buitenwanden (NL/SfB (4 cijfers))
CPset_Phasing - Renovation Phase: Bestaand
AC_Pset_RenovationAndPhasing - Renovation Status: Existing
Pset_WallCommon - LoadBearing: yes; IsExternal: yes
BaseQuantities - Height: 4065 mm; Width: 396 mm
Name | Length (mm) | GrossFootprintArea (m2) = NetFootprintArea (m2) | GrossSideArea (m2) | NetSideArea (m2) | GrossVolume (m3) | NetVolume (m3)
Buitenwand | 7420 | 1.46975 | 26.5926 | 20.9747 | 10.8686 | 8.78973
Buitenwand | 4145 | 1.60735 | 14.8415 | 14.8415 | 5.99246 | 5.99246
Buitenwand | 1765.5 | 0.71772 | 6.50178 | 5.29893 | 2.65813 | 2.45606

# IfcWall: 21 Gevelplaat - binnenblad_KZS 150mm 396 (2)
In: Begane grond
Type - PredefinedType: ELEMENTEDWALL
Classification: Samengestelde wand (ARCHICAD Classification); 21 Buitenwanden (NL/SfB (4 cijfers))
CPset_Phasing - Renovation Phase: Bestaand
AC_Pset_RenovationAndPhasing - Renovation Status: Existing
Pset_WallCommon - LoadBearing: yes; IsExternal: yes
BaseQuantities - Height: 4235 mm; Width: 396 mm
Name | Length (mm) | GrossFootprintArea (m2) = NetFootprintArea (m2) | GrossSideArea (m2) | NetSideArea (m2) | GrossVolume (m3) | NetVolume (m3)
Buitenwand | 5640.03 | 1.83628 | 21.4643 | 11.4884 | 8.84972 | 4.89878
Buitenwand | 959.999 | 0.323587 | 3.23404 | 3.23404 | 1.27974 | 1.27974

# IfcWall: 21 Gevelplaat - binnenblad_KZS 214mm 460 (5)
In: Begane grond
Type - PredefinedType: ELEMENTEDWALL
Classification: Samengestelde wand (ARCHICAD Classification); 21 Buitenwanden (NL/SfB (4 cijfers))
CPset_Phasing - Renovation Phase: Bestaand
AC_Pset_RenovationAndPhasing - Renovation Status: Existing
Pset_WallCommon - LoadBearing: yes; IsExternal: yes
BaseQuantities - Height: 4235 mm; Width: 460 mm
Name | Length (mm) | GrossFootprintArea (m2) = NetFootprintArea (m2) | GrossSideArea (m2) | NetSideArea (m2) | GrossVolume (m3) | NetVolume (m3)
Buitenwand | 3422 | 1.49543 | 12.1714 | 12.1714 | 5.8205 | 5.8205
Buitenwand | 3524 | 1.61986 | 13.6484 | 13.6484 | 6.26881 | 6.26881
Buitenwand | 15559 | 6.4365 | 59.4818 | 45.6678 | 27.6064 | 21.2704
Buitenwand | 26018 | 11.1876 | 100.33 | 69.6441 | 46.6614 | 32.5962
Buitenwand | 960 | 0.438348 | 3.75455 | 3.75455 | 1.67796 | 1.67796

# IfcWall: 21 Gevelplaat - hsb 312, Buitenwand
In: Begane grond
Type - PredefinedType: ELEMENTEDWALL
Classification: Samengestelde wand (ARCHICAD Classification); 21 Buitenwanden (NL/SfB (4 cijfers))
CPset_Phasing - Renovation Phase: Bestaand
AC_Pset_RenovationAndPhasing - Renovation Status: Existing
Pset_WallCommon - LoadBearing: yes; IsExternal: yes
BaseQuantities - Length: 13688 mm; Height: 4235 mm; Width: 312 mm; GrossFootprintArea: 3.86591 m2; NetFootprintArea: 3.86591 m2; GrossSideArea: 52.2809 m2; NetSideArea: 42.4182 m2; GrossVolume: 17.4744 m3; NetVolume: 14.3789 m3

# IfcWall: 21 Hout grof - SAB binnendoos 340 (4)
In: 1e verdieping
Type - PredefinedType: ELEMENTEDWALL
Classification: Samengestelde wand (ARCHICAD Classification); 21 Buitenwanden (NL/SfB (4 cijfers))
CPset_Phasing - Renovation Phase: Bestaand
AC_Pset_RenovationAndPhasing - Renovation Status: Existing
Pset_WallCommon - LoadBearing: yes; IsExternal: yes
BaseQuantities - Height: 3215 mm; Width: 340 mm
Name | Length (mm) | GrossFootprintArea (m2) = NetFootprintArea (m2) | GrossSideArea (m2) = NetSideArea (m2) | GrossVolume (m3) = NetVolume (m3)
Buitenwand | 21790 | 7.45745 | 70.0678 | 23.9757
2 x Buitenwand | 12790 | 4.3486 | 41.0974 | 13.9808
Buitenwand | 21790 | 7.35976 | 69.997 | 23.6616

# IfcWall: 21 Hout grof - schijngevel 18 (7)
Type - PredefinedType: ELEMENTEDWALL
Classification: Samengestelde wand (ARCHICAD Classification); 21 Buitenwanden (NL/SfB (4 cijfers)); Material: Hout - gevel opengewerkt
CPset_Phasing - Renovation Phase: Bestaand
AC_Pset_RenovationAndPhasing - Renovation Status: Existing
Pset_WallCommon - LoadBearing: yes; IsExternal: yes
Material Properties - Hout - gevel opengewerkt, ThermalConductivity: 0.14; Hout - gevel opengewerkt, SpecificHeatCapacity: 1880 J/kg/K; Hout - gevel opengewerkt, MassDensity: 550 kg/m3; Hout - gevel opengewerkt, Embodied Energy: 7.4 (MJ/kg); Hout - gevel opengewerkt, Embodied Carbon: 0.19 (kgCO₂/kg); Hout - gevel opengewerkt, Name: Hout - gevel opengewerkt; Hout - gevel opengewerkt, Participates in Collision Detection: yes
BaseQuantities - Width: 18 mm
Component Quantities - Hout - gevel opengewerkt, Component Thickness: 18 mm; Hout - gevel opengewerkt, Rectangular Component Width: 18 mm
Name | In | Length (mm) | Height (mm) = Hout - gevel opengewerkt, Rectangular Component Height (mm) | GrossFootprintArea (m2) = NetFootprintArea (m2) | GrossSideArea (m2) = NetSideArea (m2) = Hout - gevel opengewerkt, Projected Component Area (Net) (m2) = Hout - gevel opengewerkt, Projected Component Area (Gross) (m2) | GrossVolume (m3) = NetVolume (m3) = Hout - gevel opengewerkt, Component Volume (Net) (m3) = Hout - gevel opengewerkt, Component Volume (Gross) (m3) | Hout - gevel opengewerkt, Mass (kg) | Hout - gevel opengewerkt, Component Cross Section Area (m2)
Buitenwand | 1e verdieping | 13054 | 1480 | 0.235296 | 19.3465 | 0.348237 | 191.53 | 0.0266399
Buitenwand | 1e verdieping | 14204 | 1480 | 0.255672 | 21.0219 | 0.378393 | 208.116 | 0.0266399
Buitenwand | 1e verdieping | 5727 | 1480 | 0.102924 | 8.46261 | 0.152327 | 83.7799 | 0.0266399
Buitenwand | 1e verdieping | 9330.31 | 1835 | 0.168107 | 16.9715 | 0.305486 | 168.017 | 0.03303
Buitenwand | 1e verdieping | 890 | 1835 | 0.01602 | 1.63315 | 0.0293967 | 16.1682 | 0.03303
Buitenwand | Dak | 2813.69 | 1835 | 0.0504844 | 5.1466 | 0.0926388 | 50.9513 | 0.03303
Buitenwand | Dak | 8477 | 1835 | 0.152748 | 15.5238 | 0.279428 | 153.686 | 0.03303

# IfcWall: 21 Isolatie onder mv & waterkering 145 (3)
In: Fundering
Type - PredefinedType: ELEMENTEDWALL
Classification: Samengestelde wand (ARCHICAD Classification); 21 Buitenwanden (NL/SfB (4 cijfers))
CPset_Phasing - Renovation Phase: Bestaand
AC_Pset_RenovationAndPhasing - Renovation Status: Existing
Pset_WallCommon - LoadBearing: yes; IsExternal: yes
BaseQuantities - Height: 1320 mm; Width: 145 mm
Name | Length (mm) | GrossFootprintArea (m2) = NetFootprintArea (m2) | GrossSideArea (m2) = NetSideArea (m2) | GrossVolume (m3) = NetVolume (m3)
Buitenwand ondermaaiveld | 12645 | 1.83353 | 16.4595 | 2.38394
Buitenwand ondermaaiveld | 5379.5 | 0.74948 | 6.90888 | 0.989314
Buitenwand ondermaaiveld | 13572.5 | 1.97783 | 17.6657 | 2.57027

# IfcWall: 21 SAB binnendoos - excl buitenplaat 205 (6)
In: Begane grond
Type - PredefinedType: ELEMENTEDWALL
Classification: Samengestelde wand (ARCHICAD Classification); 21 Buitenwanden (NL/SfB (4 cijfers))
CPset_Phasing - Renovation Phase: Bestaand
AC_Pset_RenovationAndPhasing - Renovation Status: Existing
Pset_WallCommon - LoadBearing: yes; IsExternal: yes
BaseQuantities - Width: 205 mm
Name | Length (mm) | Height (mm) | GrossFootprintArea (m2) = NetFootprintArea (m2) | GrossSideArea (m2) | NetSideArea (m2) | GrossVolume (m3) | NetVolume (m3)
SAB binnendoos | 10529 | 1385 | 2.17894 | 13.5318 | 13.5318 | 2.853 | 2.853
Buitenwand | 12705 | 4630 | 1.0824 | 57.7291 | 25.294 | 11.8358 | 5.16066
Buitenwand | 5504.5 | 4630 | 0.562005 | 24.4712 | 10.9812 | 5.10555 | 2.33464
Buitenwand | 13593.7 | 4630 | 1.16057 | 62.33 | 26.7787 | 12.7322 | 5.41701
Buitenwand | 5011 | 1385 | 0.462435 | 4.23946 | 4.23946 | 0.769291 | 0.769291
SAB binnendoos | 6314.99 | 1385 | 0.157084 | 5.92666 | 5.92666 | 0.825698 | 0.825698

# IfcWall: 21 Spouwisolatie - excl buitenblad 136 (3)
In: 1e verdieping
Type - PredefinedType: ELEMENTEDWALL
Classification: Samengestelde wand (ARCHICAD Classification); 21 Buitenwanden (NL/SfB (4 cijfers))
CPset_Phasing - Renovation Phase: Bestaand
AC_Pset_RenovationAndPhasing - Renovation Status: Existing
Pset_WallCommon - LoadBearing: yes; IsExternal: yes
BaseQuantities - Width: 136 mm
Name | Length (mm) | Height (mm) | GrossFootprintArea (m2) = NetFootprintArea (m2) | GrossSideArea (m2) = NetSideArea (m2) | GrossVolume (m3) = NetVolume (m3)
Buitenwand | 5078.37 | 924.998 | 0.699162 | 4.29516 | 0.646792
Buitenwand | 7741 | 1019 | 1.05278 | 7.72335 | 1.05038
Buitenwand | 7916 | 924.998 | 1.06798 | 7.2617 | 0.987883

# IfcWall: 21 buitenwand onder maaiveld & isolatie 286 x 1330 (4)
In: Fundering
Type - PredefinedType: ELEMENTEDWALL
Classification: Samengestelde wand (ARCHICAD Classification); 21 Buitenwanden (NL/SfB (4 cijfers))
CPset_Phasing - Renovation Phase: Bestaand
AC_Pset_RenovationAndPhasing - Renovation Status: Existing
Pset_WallCommon - LoadBearing: yes; IsExternal: yes
BaseQuantities - Height: 1330 mm; Width: 286 mm
Name | Length (mm) | GrossFootprintArea (m2) = NetFootprintArea (m2) | GrossSideArea (m2) = NetSideArea (m2) | GrossVolume (m3) = NetVolume (m3)
Buitenwand ondermaaiveld | 4125 | 1.17975 | 5.48625 | 1.56907
Buitenwand ondermaaiveld | 7400 | 2.14812 | 10.0016 | 2.85699
Buitenwand ondermaaiveld | 1870.5 | 0.571556 | 2.67729 | 0.76017
Buitenwand ondermaaiveld | 14673 | 4.18063 | 19.4486 | 5.56023

# IfcWall: 21 buitenwand onder maaiveld & isolatie 286 x 870 (21)
In: Fundering
Type - PredefinedType: ELEMENTEDWALL
Classification: Samengestelde wand (ARCHICAD Classification); 21 Buitenwanden (NL/SfB (4 cijfers))
CPset_Phasing - Renovation Phase: Bestaand
AC_Pset_RenovationAndPhasing - Renovation Status: Existing
Pset_WallCommon - LoadBearing: yes; IsExternal: yes
BaseQuantities - Height: 870 mm; Width: 286 mm
Name | Length (mm) | GrossFootprintArea (m2) = NetFootprintArea (m2) | GrossSideArea (m2) = NetSideArea (m2) | GrossVolume (m3) = NetVolume (m3)
Buitenwand ondermaaiveld | 17525 | 5.01215 | 15.2642 | 4.36057
Buitenwand ondermaaiveld | 11165 | 3.19319 | 9.73096 | 2.77808
Buitenwand ondermaaiveld | 4681 | 1.33877 | 4.07247 | 1.16473
Buitenwand ondermaaiveld | 21844 | 6.27911 | 19.1261 | 5.46282
Buitenwand ondermaaiveld | 6529.02 | 1.8673 | 5.68025 | 1.62455
Buitenwand ondermaaiveld | 5657.01 | 1.60205 | 4.8607 | 1.39378
Buitenwand ondermaaiveld | 15435 | 4.41441 | 13.4111 | 3.84054
Buitenwand ondermaaiveld | 25764 | 7.36851 | 22.3973 | 6.41061
Buitenwand ondermaaiveld | 3370 | 0.963819 | 2.9319 | 0.838523
Buitenwand ondermaaiveld | 19156 | 5.47862 | 16.6831 | 4.7664
Buitenwand ondermaaiveld | 32616 | 9.32817 | 28.3933 | 8.11551
Buitenwand ondermaaiveld | 23452 | 6.70727 | 20.4206 | 5.83532
Buitenwand ondermaaiveld | 939.999 | 0.26884 | 0.817799 | 0.23389
Buitenwand ondermaaiveld | 5418.03 | 1.54956 | 4.69629 | 1.34812
Buitenwand ondermaaiveld | 940 | 0.26884 | 0.8178 | 0.233891
Buitenwand ondermaaiveld | 23496 | 6.71986 | 20.4589 | 5.84627
Buitenwand ondermaaiveld | 13636 | 3.89989 | 11.8633 | 3.39291
Buitenwand ondermaaiveld | 3550 | 1.0153 | 3.0885 | 0.883311
Buitenwand ondermaaiveld | 31217 | 8.91221 | 27.1153 | 7.75362
Buitenwand ondermaaiveld | 4397.94 | 1.27367 | 3.88711 | 1.10809
Buitenwand ondermaaiveld | 4993.01 | 1.41214 | 4.30042 | 1.22856

# IfcWall: 21 buitenwand onder+boven maaiveld & isolatie 286 x 1330 (3)
In: Fundering
Type - PredefinedType: ELEMENTEDWALL
Classification: Samengestelde wand (ARCHICAD Classification); 21 Buitenwanden (NL/SfB (4 cijfers))
CPset_Phasing - Renovation Phase: Bestaand
AC_Pset_RenovationAndPhasing - Renovation Status: Existing
Pset_WallCommon - LoadBearing: yes; IsExternal: yes
BaseQuantities - Height: 1330 mm; Width: 286 mm
Name | Length (mm) | GrossFootprintArea (m2) = NetFootprintArea (m2) | GrossSideArea (m2) = NetSideArea (m2) | GrossVolume (m3) = NetVolume (m3)
Buitenwand ondermaaiveld | 10461 | 2.99185 | 13.9397 | 3.97916
Buitenwand ondermaaiveld | 21913 | 6.25125 | 29.0778 | 8.31417
Buitenwand ondermaaiveld | 20993 | 5.98814 | 27.8542 | 7.96423

# IfcWall: 22 Akkoestische wandafwerking 70 (18)
In: Begane grond
Type - PredefinedType: ELEMENTEDWALL
Classification: Samengestelde wand (ARCHICAD Classification); 21 Buitenwanden (NL/SfB (4 cijfers))
CPset_Phasing - Renovation Phase: Bestaand
AC_Pset_RenovationAndPhasing - Renovation Status: Existing
Pset_WallCommon - LoadBearing: yes; IsExternal: yes
BaseQuantities - Width: 70 mm
Name | Length (mm) | Height (mm) | GrossFootprintArea (m2) = NetFootprintArea (m2) | GrossSideArea (m2) | NetSideArea (m2) | GrossVolume (m3) | NetVolume (m3)
akkoestische beplating | 6504.02 | 2780 | 0.458182 | 18.1785 | 18.1785 | 1.27374 | 1.27374
akkoestische beplating | 2884.98 | 2780 | 0.201949 | 8.02026 | 8.02026 | 0.561418 | 0.561418
akkoestische beplating | 12273.4 | 2780 | 0.860587 | 34.1478 | 34.1478 | 2.39243 | 2.39243
akkoestische beplating | 35 | 2780 | 0.0017405 | 0.08201 | 0.08201 | 0.00483859 | 0.00483859
3 x akkoestische beplating | 252.001 | 2780 | 0.0161901 | 0.672762 | 0.672762 | 0.0450084 | 0.0450084
akkoestische beplating | 10880 | 2780 | 0.719702 | 30.3855 | 28.7791 | 2.12532 | 2.01287
akkoestische beplating | 252.001 | 2780 | 0.0190901 | 0.770062 | 0.770062 | 0.0530704 | 0.0530704
akkoestische beplating | 2885 | 2780 | 0.19905 | 7.923 | 7.923 | 0.553359 | 0.553359
akkoestische beplating | 231.007 | 2780 | 0.0151005 | 0.611619 | 0.611619 | 0.0419793 | 0.0419793
akkoestische beplating | 3575.98 | 2780 | 0.250318 | 9.94122 | 9.94122 | 0.695885 | 0.695885
akkoestische beplating | 232.852 | 2780 | 0.0122005 | 0.514319 | 0.514319 | 0.0339173 | 0.0339173
akkoestische beplating | 10635 | 2780 | 0.744451 | 29.5653 | 29.5653 | 2.06957 | 2.06957
akkoestische beplating | 198.38 | 2800 | 0.0163366 | 0.528364 | 0.528364 | 0.0349005 | 0.0349005
akkoestische beplating | 5280 | 1170 | 0.38155 | 6.28994 | 6.28994 | 0.441147 | 0.441147
akkoestische beplating | 12160 | 1170 | 0.851201 | 14.0026 | 14.0026 | 0.969024 | 0.969024
akkoestische beplating | 13330 | 1170 | 0.942149 | 15.5762 | 15.5762 | 1.09067 | 1.09067

# IfcWall: 22 Binnenwand C_betonblok 150mm 150 (8)
Type - PredefinedType: ELEMENTEDWALL
Classification: Samengestelde wand (ARCHICAD Classification); 21 Buitenwanden (NL/SfB (4 cijfers)); Material: Steen - Betonblok C 150
CPset_Phasing - Renovation Phase: Bestaand
AC_Pset_RenovationAndPhasing - Renovation Status: Existing
Pset_WallCommon - LoadBearing: yes; IsExternal: yes
Material Properties - Steen - Betonblok C 150, ThermalConductivity: 0.75; Steen - Betonblok C 150, SpecificHeatCapacity: 840 J/kg/K; Steen - Betonblok C 150, MassDensity: 1600 kg/m3; Steen - Betonblok C 150, Embodied Energy: 0.83 (MJ/kg); Steen - Betonblok C 150, Embodied Carbon: 0.1 (kgCO₂/kg); Steen - Betonblok C 150, Name: Steen - Betonblok C 150; Steen - Betonblok C 150, Participates in Collision Detection: yes
BaseQuantities - Width: 150 mm
Component Quantities - Steen - Betonblok C 150, Component Thickness: 150 mm; Steen - Betonblok C 150, Rectangular Component Width: 150 mm
Name | In | Length (mm) | Height (mm) = Steen - Betonblok C 150, Rectangular Component Height (mm) | GrossFootprintArea (m2) = NetFootprintArea (m2) | GrossSideArea (m2) = Steen - Betonblok C 150, Projected Component Area (Gross) (m2) | NetSideArea (m2) = Steen - Betonblok C 150, Projected Component Area (Net) (m2) | GrossVolume (m3) = Steen - Betonblok C 150, Component Volume (Gross) (m3) | NetVolume (m3) = Steen - Betonblok C 150, Component Volume (Net) (m3) | Steen - Betonblok C 150, Mass (kg) | Steen - Betonblok C 150, Component Cross Section Area (m2)
 | Begane grond | 5200 | 3190 | 0.765 | 16.269 | 14.894 | 2.44035 | 2.2341 | 3574.56 | 0.4785
Binennwand | Begane grond | 9875 | 3190 | 1.17105 | 31.5012 | 26.4408 | 4.72519 | 3.96613 | 6345.8 | 0.4785
Betonsteen 150mm | Begane grond | 10496 | 3470 | 1.2744 | 36.421 | 30.681 | 5.46316 | 4.60216 | 7363.45 | 0.5205
 | Begane grond | 5350 | 3190 | 0.8025 | 17.0665 | 17.0665 | 2.55997 | 2.55997 | 4095.96 | 0.4785
Betonsteen 150mm | Begane grond | 4579.99 | 3861 | 0.698249 | 17.9729 | 17.9729 | 2.69594 | 2.69594 | 4313.5 | 0.57915
Betonsteen 150mm | Begane grond | 4750 | 3861 | 0.70125 | 18.0502 | 18.0502 | 2.70753 | 2.70753 | 4332.04 | 0.57915
 | 1e verdieping | 7300 | 480 | 1.08 | 3.456 | 3.456 | 0.5184 | 0.5184 | 829.44 | 0.072
 | 1e verdieping | 5200 | 480 | 0.765 | 2.28157 | 2.28157 | 0.332152 | 0.332152 | 531.443 | 0.072

# IfcWall: 22 Binnenwand C_betonblok 200mm 200 (6)
Type - PredefinedType: ELEMENTEDWALL
Classification: Samengestelde wand (ARCHICAD Classification); 21 Buitenwanden (NL/SfB (4 cijfers)); Material: Steen - Betonblok C 200
CPset_Phasing - Renovation Phase: Bestaand
AC_Pset_RenovationAndPhasing - Renovation Status: Existing
Pset_WallCommon - LoadBearing: yes; IsExternal: yes
Material Properties - Steen - Betonblok C 200, ThermalConductivity: 0.75; Steen - Betonblok C 200, SpecificHeatCapacity: 840 J/kg/K; Steen - Betonblok C 200, MassDensity: 1600 kg/m3; Steen - Betonblok C 200, Embodied Energy: 0.83 (MJ/kg); Steen - Betonblok C 200, Embodied Carbon: 0.1 (kgCO₂/kg); Steen - Betonblok C 200, Name: Steen - Betonblok C 200; Steen - Betonblok C 200, Participates in Collision Detection: yes
BaseQuantities - Width: 200 mm
Component Quantities - Steen - Betonblok C 200, Component Thickness: 200 mm; Steen - Betonblok C 200, Rectangular Component Width: 200 mm
Name | In | Length (mm) | Height (mm) = Steen - Betonblok C 200, Rectangular Component Height (mm) | GrossFootprintArea (m2) = NetFootprintArea (m2) | GrossSideArea (m2) = Steen - Betonblok C 200, Projected Component Area (Gross) (m2) | NetSideArea (m2) = Steen - Betonblok C 200, Projected Component Area (Net) (m2) | GrossVolume (m3) = Steen - Betonblok C 200, Component Volume (Gross) (m3) | NetVolume (m3) = Steen - Betonblok C 200, Component Volume (Net) (m3) | Steen - Betonblok C 200, Mass (kg) | Steen - Betonblok C 200, Component Cross Section Area (m2)
Betonsteen 150mm | Begane grond | 11640 | 3470 | 1.1208 | 40.0438 | 25.5184 | 8.00876 | 5.10368 | 8165.89 | 0.694
 | Begane grond | 8125.02 | 3190 | 1.0028 | 26.1581 | 18.3619 | 5.23161 | 3.67238 | 5875.81 | 0.638
KZS 214mm | Begane grond | 8395.98 | 3470 | 1.6992 | 29.481 | 29.481 | 5.89621 | 5.89621 | 9433.93 | 0.694
 | Begane grond | 1550 | 3190 | 0.103199 | 4.94449 | 2.41429 | 0.988898 | 0.482858 | 772.573 | 0.638
 | Begane grond | 19050 | 3190 | 3.1796 | 60.929 | 53.0937 | 12.1858 | 10.6187 | 16990 | 0.638
 | 1e verdieping | 8049.98 | 480 | 1.64 | 3.91742 | 3.91742 | 0.783485 | 0.783485 | 1253.58 | 0.096

# IfcWall: 22 Binnenwand NC_betonblok 100mm 100 (65)
In: Begane grond
Type - PredefinedType: ELEMENTEDWALL
Classification: Samengestelde wand (ARCHICAD Classification); 21 Buitenwanden (NL/SfB (4 cijfers)); Material: Steen - Betonblok C
CPset_Phasing - Renovation Phase: Bestaand
AC_Pset_RenovationAndPhasing - Renovation Status: Existing
Pset_WallCommon - LoadBearing: yes; IsExternal: yes
Material Properties - Steen - Betonblok C, ThermalConductivity: 0.75; Steen - Betonblok C, SpecificHeatCapacity: 840 J/kg/K; Steen - Betonblok C, MassDensity: 1600 kg/m3; Steen - Betonblok C, Embodied Energy: 0.83 (MJ/kg); Steen - Betonblok C, Embodied Carbon: 0.1 (kgCO₂/kg); Steen - Betonblok C, Name: Steen - Betonblok C; Steen - Betonblok C, Participates in Collision Detection: yes
BaseQuantities - Width: 100 mm
Component Quantities - Steen - Betonblok C, Component Thickness: 100 mm; Steen - Betonblok C, Rectangular Component Width: 100 mm
Name | Length (mm) | Height (mm) | GrossFootprintArea (m2) = NetFootprintArea (m2) | GrossSideArea (m2) = Steen - Betonblok C, Projected Component Area (Gross) (m2) | NetSideArea (m2) = Steen - Betonblok C, Projected Component Area (Net) (m2) | GrossVolume (m3) = Steen - Betonblok C, Component Volume (Gross) (m3) | NetVolume (m3) = Steen - Betonblok C, Component Volume (Net) (m3) | Steen - Betonblok C, Mass (kg) | Steen - Betonblok C, Rectangular Component Height (mm) | Steen - Betonblok C, Component Cross Section Area (m2)
Betonsteen 150mm | 600 | 3470 | 0.065 | 2.2555 | 2.2555 | 0.22555 | 0.22555 | 360.88 | 3470 | 0.347
Betonsteen 150mm | 5350.07 | 3470 | 0.525007 | 18.2178 | 18.2178 | 1.82178 | 1.82178 | 2914.84 | 3470 | 0.347
2 x Betonsteen 150mm | 4845.98 | 3470 | 0.386198 | 16.8156 | 14.4077 | 1.68156 | 1.44077 | 2305.23 | 3470 | 0.347
Betonsteen 150mm | 4915 | 3470 | 0.484 | 16.7948 | 16.7948 | 1.67948 | 1.67948 | 2687.17 | 3470 | 0.347
2 x Betonsteen 150mm | 2350 | 3470 | 0.235 | 8.1545 | 8.1545 | 0.81545 | 0.81545 | 1304.72 | 3470 | 0.347
2 x Binnenwand | 1140 | 3470 | 0.119 | 4.1293 | 4.1293 | 0.41293 | 0.41293 | 660.688 | 3470 | 0.347
2 x Binnenwand | 1000 | 3190 | 0.1 | 3.19 | 3.19 | 0.319 | 0.319 | 510.4 | 3190 | 0.319
Binnenwand | 550 | 3190 | 0.06 | 1.914 | 1.914 | 0.1914 | 0.1914 | 306.24 | 3190 | 0.319
Binnenwand | 2250 | 3190 | 0.22 | 7.018 | 7.018 | 0.7018 | 0.7018 | 1122.88 | 3190 | 0.319
2 x Binnenwand | 1750 | 3470 | 0.17 | 5.899 | 5.899 | 0.5899 | 0.5899 | 943.84 | 3470 | 0.347
Binnenwand | 1875 | 3190 | 0.1875 | 5.98125 | 5.98125 | 0.598125 | 0.598125 | 957 | 3190 | 0.319
Binnenwand | 6749.9 | 3190 | 0.46819 | 21.5322 | 16.4718 | 2.15322 | 1.64718 | 2635.48 | 3190 | 0.319
Binnenwand | 6849.9 | 3190 | 0.67499 | 21.5322 | 21.5322 | 2.15322 | 2.15322 | 3445.15 | 3190 | 0.319
Binnenwand | 6750 | 3190 | 0.675 | 21.5325 | 21.5325 | 2.15325 | 2.15325 | 3445.2 | 3190 | 0.319
Binnenwand | 3949.98 | 3190 | 0.394998 | 12.6004 | 12.6004 | 1.26004 | 1.26004 | 2016.07 | 3190 | 0.319
Binnenwand | 6749.99 | 3190 | 0.674999 | 21.5325 | 21.5325 | 2.15325 | 2.15325 | 3445.2 | 3190 | 0.319
Binnenwand | 3649.98 | 3190 | 0.261598 | 11.6435 | 9.11325 | 1.16435 | 0.911325 | 1458.12 | 3190 | 0.319
Binnenwand | 1552.71 | 3190 | 0.155271 | 4.95314 | 4.95314 | 0.495314 | 0.495314 | 792.502 | 3190 | 0.319
Binnenwand | 5099.99 | 3190 | 0.509999 | 16.269 | 16.269 | 1.6269 | 1.6269 | 2603.03 | 3190 | 0.319
2 x Binnenwand | 1450 | 3190 | 0.15 | 4.78499 | 4.78499 | 0.478499 | 0.478499 | 765.599 | 3190 | 0.319
2 x Binnenwand | 5099.95 | 3190 | 0.509995 | 16.2688 | 16.2688 | 1.62688 | 1.62688 | 2603.02 | 3190 | 0.319
2 x Binnenwand | 1084 | 743 | 0 | 3.29847 | 0.768263 | 0.329847 | 0.0768263 | 122.922 | 3190 | 0.319
Binnenwand | 2170 | 3190 | 0.0102 | 6.9223 | 1.8619 | 0.69223 | 0.18619 | 297.905 | 3190 | 0.319
Binnenwand | 1399.99 | 3190 | 0.139999 | 4.46598 | 4.46598 | 0.446598 | 0.446598 | 714.557 | 3190 | 0.319
2 x Binnenwand | 5100 | 3190 | 0.51 | 16.269 | 16.269 | 1.6269 | 1.6269 | 2603.04 | 3190 | 0.319
Binnenwand | 749.975 | 3190 | 0.0749975 | 2.39242 | 2.39242 | 0.239242 | 0.239242 | 382.787 | 3190 | 0.319
Binnenwand | 2400 | 3190 | 0.1366 | 7.656 | 5.1258 | 0.7656 | 0.51258 | 820.128 | 3190 | 0.319
Binnenwand | 2550 | 3190 | 0.255 | 8.1345 | 8.1345 | 0.81345 | 0.81345 | 1301.52 | 3190 | 0.319
Binnenwand | 2570 | 3190 | 0.267 | 8.51729 | 8.51729 | 0.851729 | 0.851729 | 1362.77 | 3190 | 0.319
Binnenwand | 549.997 | 3190 | 0.0499997 | 1.59499 | 1.59499 | 0.159499 | 0.159499 | 255.198 | 3190 | 0.319
Binnenwand | 2374.86 | 3190 | 0.242486 | 7.73531 | 7.73531 | 0.773531 | 0.773531 | 1237.65 | 3190 | 0.319
Binnenwand | 1630 | 3190 | 0.163 | 5.19969 | 5.19969 | 0.519969 | 0.519969 | 831.95 | 3190 | 0.319
Binnenwand | 799.999 | 3190 | 0.0799999 | 2.552 | 2.552 | 0.2552 | 0.2552 | 408.319 | 3190 | 0.319
Binnenwand | 6849.91 | 3190 | 0.1548 | 21.5325 | 8.8032 | 2.15325 | 0.88032 | 1408.51 | 3190 | 0.319
Binnenwand | 8080 | 3190 | 0.798 | 25.4562 | 25.4562 | 2.54562 | 2.54562 | 4072.99 | 3190 | 0.319
Binnenwand | 6749.91 | 3190 | 0.674989 | 21.5322 | 21.5322 | 2.15322 | 2.15322 | 3445.15 | 3190 | 0.319
Binnenwand | 1023.25 | 3190 | 0.0973248 | 3.10466 | 1.56985 | 0.310466 | 0.156985 | 251.176 | 3190 | 0.319
Binnenwand | 800.46 | 3190 | 0.080046 | 2.55347 | 2.55347 | 0.255347 | 0.255347 | 408.555 | 3190 | 0.319
Binnenwand | 19047.3 | 3190 | 1.28933 | 60.9203 | 45.7391 | 6.09203 | 4.57391 | 7318.26 | 3190 | 0.319
Binnenwand | 2100 | 3190 | 0.1066 | 6.699 | 4.1688 | 0.6699 | 0.41688 | 667.008 | 3190 | 0.319
Binnenwand | 3475.05 | 3190 | 0.145705 | 10.6067 | 6.03587 | 1.06068 | 0.603587 | 965.739 | 3190 | 0.319
Binnenwand | 800.004 | 3190 | 0.0800004 | 2.55201 | 2.55201 | 0.255201 | 0.255201 | 408.322 | 3190 | 0.319
Binnenwand | 800 | 3190 | 0.08 | 2.552 | 2.552 | 0.2552 | 0.2552 | 408.32 | 3190 | 0.319
Binnenwand | 2650.04 | 3190 | 0.255004 | 8.13463 | 8.13463 | 0.813463 | 0.813463 | 1301.54 | 3190 | 0.319
Binnenwand | 3374.85 | 3190 | 0.150685 | 10.7658 | 6.19478 | 1.07658 | 0.619478 | 991.165 | 3190 | 0.319
Binnenwand | 2050 | 3190 | 0.00999982 | 6.2205 | 1.281 | 0.62205 | 0.1281 | 204.959 | 3190 | 0.319
Binnenwand | 3900 | 3190 | 0.1732 | 12.122 | 7.06161 | 1.2122 | 0.706161 | 1129.86 | 3190 | 0.319
Binnenwand | 2475.04 | 3190 | 0.232503 | 7.41686 | 7.41686 | 0.741686 | 0.741686 | 1186.7 | 3190 | 0.319
Binnenwand | 549.997 | 3190 | 0.0599997 | 1.91399 | 1.91399 | 0.191399 | 0.191399 | 306.238 | 3190 | 0.319
Betonsteen 150mm | 1900 | 3470 | 0.19 | 6.593 | 6.593 | 0.6593 | 0.6593 | 1054.88 | 3470 | 0.347
Betonsteen 150mm | 600 | 3470 | 0.055 | 1.9085 | 1.9085 | 0.19085 | 0.19085 | 305.36 | 3470 | 0.347
Betonsteen 150mm | 2295.98 | 3470 | 0.229598 | 7.96705 | 7.96705 | 0.796705 | 0.796705 | 1274.73 | 3470 | 0.347
2 x Binnenwand | 3350 | 3190 | 0.335 | 10.6865 | 10.6865 | 1.06865 | 1.06865 | 1709.84 | 3190 | 0.319
2 x Binnenwand | 3374.96 | 3190 | 0.332496 | 10.6066 | 10.6066 | 1.06066 | 1.06066 | 1697.06 | 3190 | 0.319

# IfcWall: 22 Dubbele gipsplaat 25 (19)
In: Begane grond
Type - PredefinedType: ELEMENTEDWALL
Classification: Samengestelde wand (ARCHICAD Classification); 21 Buitenwanden (NL/SfB (4 cijfers))
CPset_Phasing - Renovation Phase: Bestaand
AC_Pset_RenovationAndPhasing - Renovation Status: Existing
Pset_WallCommon - LoadBearing: yes; IsExternal: yes
BaseQuantities - Width: 25 mm
Name | Length (mm) | Height (mm) | GrossFootprintArea (m2) = NetFootprintArea (m2) | GrossSideArea (m2) = NetSideArea (m2) | GrossVolume (m3) = NetVolume (m3)
Koof | 9457.68 | 585 | 0.236442 | 5.53274 | 0.138319
2 x Binnenwand | 122.5 | 3400 | 0.00321875 | 0.43775 | 0.0109438
Koof | 8650.14 | 600 | 0.216254 | 5.19009 | 0.129752
Metalstud 100mm | 181.992 | 3390 | 0.00470606 | 0.638142 | 0.0159536
Koof | 3699.99 | 520 | 0.0924998 | 1.924 | 0.0480999
Binnenwand | 172.5 | 3400 | 0.00290625 | 0.39525 | 0.00988125
Binnenwand | 1180.74 | 3400 | 0.0276434 | 3.75951 | 0.0939877
Binnenwand | 172.5 | 3400 | 0.0030625 | 0.4165 | 0.0104125
Binnenwand | 1180.74 | 3400 | 0.0279559 | 3.80201 | 0.0950502
Binnenwand | 1087.5 | 3190 | 0.0248438 | 3.17006 | 0.0792516
Binnenwand | 172.5 | 3190 | 0.00415625 | 0.530338 | 0.0132584
Metalstud 100mm | 162.503 | 3390 | 0.00390632 | 0.529697 | 0.0132424
Binnenwand | 50 | 3400 | 0.00015625 | 0.02125 | 0.00053125 | Material: Gipsplaat; Material Properties - Gipsplaat, ThermalConductivity: 0.23; Gipsplaat, SpecificHeatCapacity: 840 J/kg/K; Gipsplaat, MassDensity: 800 kg/m3; Gipsplaat, Embodied Energy: 6.75 (MJ/kg); Gipsplaat, Embodied Carbon: 0.38 (kgCO₂/kg); Gipsplaat, Name: Gipsplaat; Gipsplaat, Participates in Collision Detection: yes; Component Quantities - Gipsplaat, Mass: 0.425 kg; Gipsplaat, Projected Component Area (Net): 0.0425 m2; Gipsplaat, Projected Component Area (Gross): 0.0425 m2; Gipsplaat, Component Thickness: 12.5 mm; Gipsplaat, Rectangular Component Height: 3400 mm; Gipsplaat, Rectangular Component Width: 12.5 mm; Gipsplaat, Component Cross Section Area: 0.0425 m2; Gipsplaat, Component Volume (Net): 0.00053125 m3; Gipsplaat, Component Volume (Gross): 0.00053125 m3
Binnenwand | 13 | 3400 | 0.00049375 | 0.06715 | 0.00167875
Binnenwand | 175 | 3400 | 0.004375 | 0.595 | 0.014875
Binnenwand | 13 | 3400 | 0.00018125 | 0.02465 | 0.00061625
omtimmering | 137.5 | 3190 | 0.00328125 | 0.418687 | 0.0104672
omtimmering | 137.5 | 3190 | 0.00359375 | 0.458562 | 0.0114641

# IfcWall: 22 Metalstud 100mm 100 (70)
In: Begane grond
Type - PredefinedType: ELEMENTEDWALL
Classification: Samengestelde wand (ARCHICAD Classification); 21 Buitenwanden (NL/SfB (4 cijfers))
CPset_Phasing - Renovation Phase: Bestaand
AC_Pset_RenovationAndPhasing - Renovation Status: Existing
Pset_WallCommon - LoadBearing: yes; IsExternal: yes
BaseQuantities - Width: 100 mm
Name | Length (mm) | Height (mm) | GrossFootprintArea (m2) = NetFootprintArea (m2) | GrossSideArea (m2) | NetSideArea (m2) | GrossVolume (m3) | NetVolume (m3)
Binnenwand | 1055 | 3400 | 0.00522513 | 3.587 | 1.12919 | 0.369325 | 0.123544
Metalstud 100mm | 8240.76 | 3470 | 0.614835 | 28.0878 | 23.2722 | 2.81638 | 2.33481
Binnenwand | 7599.99 | 3470 | 0.461561 | 26.372 | 18.962 | 2.64262 | 1.90162
2 x Binnenwand | 1050 | 3400 | 0.004725 | 3.57 | 1.11218 | 0.367625 | 0.121843
Metalstud 100mm | 7504.04 | 3400 | 0.751966 | 25.2375 | 25.2375 | 2.55668 | 2.55668
2 x Binnenwand | 4204.04 | 3400 | 0.416029 | 13.8262 | 13.8262 | 1.4145 | 1.4145
3 x Binnenwand | 7100 | 3470 | 0.411563 | 24.63 | 17.22 | 2.4683 | 1.7273
Metalstud 100mm | 4850 | 3400 | 0.3816 | 16.2562 | 13.7984 | 1.649 | 1.40322
Metalstud 100mm | 2641.51 | 3400 | 0.262119 | 8.85362 | 8.85362 | 0.891206 | 0.891206
Metalstud 100mm | 2900 | 3470 | 0.0965625 | 10.054 | 5.15996 | 1.02764 | 0.538243
Metalstud 100mm | 2214 | 600 | 0 | 6.94 | 1.2 | 0.694 | 0.12
Metalstud 100mm | 6260 | 3470 | 0.335413 | 21.4258 | 14.491 | 2.14611 | 1.45263
Metalstud 100mm | 6160 | 3470 | 0.616001 | 21.2381 | 21.2381 | 2.1367 | 2.1367
Metalstud 100mm | 3786.06 | 3470 | 0.378602 | 13.1244 | 13.1244 | 1.31375 | 1.31375
Binnenwand | 1320 | 3400 | 0.132313 | 4.2755 | 4.2755 | 0.449863 | 0.449863
Binnenwand | 7554.04 | 3400 | 0.753373 | 25.2587 | 25.2587 | 2.56147 | 2.56147
Metalstud 100mm | 386.001 | 3470 | 0.0401626 | 1.36111 | 1.36111 | 0.139364 | 0.139364
Metalstud 100mm | 1370 | 3400 | 0.138719 | 4.573 | 4.573 | 0.471644 | 0.471644
Metalstud 100mm | 429 | 3470 | 0.0401626 | 1.36111 | 1.36111 | 0.139364 | 0.139364
Metalstud 100mm | 4319.96 | 3470 | 0.227071 | 14.8384 | 9.10715 | 1.48818 | 0.915053
Metalstud 100mm | 21831 | 3470 | 1.70845 | 73.7486 | 50.2844 | 7.42684 | 5.08042
Metalstud 100mm | 1855.02 | 3470 | 0.185751 | 6.32407 | 6.32407 | 0.644555 | 0.644555
Metalstud 100mm | 4410 | 3400 | 0.0465625 | 14.6412 | 4.87172 | 1.53538 | 0.558437
Metalstud 100mm | 1100 | 3400 | 0.0050374 | 3.71875 | 1.26093 | 0.368687 | 0.122905
Binnenwand | 3426 | 3400 | 0.0188564 | 10.5808 | 3.32625 | 1.08117 | 0.361652
Metalstud 100mm | 1650 | 3470 | 0.161875 | 5.68212 | 5.68212 | 0.561706 | 0.561706
Binnenwand | 3250 | 3400 | 0.2216 | 10.8163 | 8.35843 | 1.105 | 0.859218
Metalstud 100mm | 3154.04 | 3470 | 0.318529 | 10.9445 | 10.9445 | 1.10529 | 1.10529
Metalstud 100mm | 12063.9 | 3400 | 1.19421 | 39.8854 | 39.8854 | 4.05733 | 4.05733
Metalstud 100mm | 3250 | 3400 | 0.22332 | 10.965 | 8.50871 | 1.11084 | 0.865064
Metalstud 100mm | 17864 | 3470 | 0.960685 | 60.1058 | 38.0797 | 6.08349 | 3.88089
Binnenwand | 7100.01 | 3470 | 0.411563 | 24.6301 | 17.2201 | 2.4683 | 1.7273
Metalstud 100mm | 2048.22 | 3470 | 0.00658475 | 7.12902 | 1.39476 | 0.716155 | 0.142729
Binnenwand | 4204.04 | 3400 | 0.417122 | 13.7412 | 13.7412 | 1.41772 | 1.41772
Metalstud 100mm | 8750.01 | 3470 | 0.0125 | 30.3173 | 2.03181 | 3.04233 | 0.213775
Metalstud 100mm | 3629.99 | 3400 | 0.262099 | 12.3255 | 9.86765 | 1.24077 | 0.99499
Metalstud 100mm | 2101.03 | 3400 | 0.206978 | 6.99475 | 6.99475 | 0.703725 | 0.703725
Metalstud 100mm | 4267.49 | 3470 | 0.429562 | 14.8143 | 14.8143 | 1.48832 | 1.48832
Metalstud 100mm | 3500.14 | 3470 | 0.351577 | 12.1455 | 12.1455 | 1.21997 | 1.21997
Metalstud 100mm | 3579.99 | 3400 | 0.360655 | 11.9482 | 11.9482 | 1.22453 | 1.22453
Metalstud 100mm | 2160 | 3470 | 0.005125 | 7.4872 | 2.25062 | 0.759439 | 0.235781
Binnenwand | 4797.76 | 3400 | 0.475244 | 15.9511 | 15.9511 | 1.61583 | 1.61583
Metalstud 100mm | 3249.99 | 3470 | 0.324374 | 11.2186 | 11.2186 | 1.1239 | 1.1239
Metalstud 100mm | 4050.01 | 3470 | 0.406807 | 13.9613 | 13.9613 | 1.41162 | 1.41162
Metalstud 100mm | 4000 | 3470 | 0.398906 | 13.5547 | 13.5547 | 1.38421 | 1.38421
Metalstud 100mm | 4104.04 | 3400 | 0.310754 | 13.7412 | 11.2834 | 1.40812 | 1.16234
Binnenwand | 3136.97 | 3400 | 0.205199 | 10.3649 | 7.90704 | 1.04924 | 0.803454
2 x Metalstud 100mm | 3786 | 3470 | 0.380163 | 13.1374 | 13.1374 | 1.31916 | 1.31916
3 x Binnenwand | 1320 | 3400 | 0.132312 | 4.2755 | 4.2755 | 0.449863 | 0.449863
Metalstud 100mm | 2500 | 3470 | 0.0465622 | 8.67499 | 2.79149 | 0.872921 | 0.284571
Metalstud 100mm | 3102.11 | 3470 | 0.113336 | 10.7643 | 5.87032 | 1.08728 | 0.597876
Metalstud 100mm | 1998 | 600 | 0 | 6.93306 | 1.1988 | 0.693306 | 0.11988
Metalstud 100mm | 6185.99 | 3470 | 0.321761 | 21.4495 | 14.0253 | 2.16719 | 1.42477
Metalstud 100mm | 1320 | 3400 | 0.132313 | 4.2755 | 4.2755 | 0.449863 | 0.449863
Metalstud 100mm | 3786 | 3470 | 0.1586 | 13.0073 | 7.6239 | 1.31374 | 0.775402
Metalstud 100mm | 550 | 3470 | 0.055 | 1.88681 | 1.88681 | 0.19085 | 0.19085
Metalstud 100mm | 6046 | 3470 | 0.6046 | 20.8415 | 20.8415 | 2.09704 | 2.09704
Metalstud 100mm | 2282.02 | 3470 | 0.229764 | 7.94029 | 7.94029 | 0.797282 | 0.797282
Metalstud 100mm | 2620 | 3400 | 0.088563 | 8.89896 | 3.85897 | 0.911683 | 0.407685
Metalstud 100mm | 2900 | 3390 | 0.29 | 9.70388 | 9.70388 | 0.982991 | 0.982991
Metalstud 100mm | 3405 | 3400 | 0.0271751 | 11.025 | 3.65157 | 1.13329 | 0.395943
Metalstud 100mm | 4369.96 | 3470 | 0.230407 | 14.7734 | 9.04209 | 1.49976 | 0.926629
Metalstud 100mm | 2620 | 3400 | 0.0901252 | 8.89895 | 3.85896 | 0.916995 | 0.412996

# IfcWall: 22 Metalstud 200mm 200 (12)
In: Begane grond
Type - PredefinedType: ELEMENTEDWALL
Classification: Samengestelde wand (ARCHICAD Classification); 21 Buitenwanden (NL/SfB (4 cijfers))
CPset_Phasing - Renovation Phase: Bestaand
AC_Pset_RenovationAndPhasing - Renovation Status: Existing
Pset_WallCommon - LoadBearing: yes; IsExternal: yes
BaseQuantities - Width: 200 mm
Name | Length (mm) | Height (mm) | GrossFootprintArea (m2) = NetFootprintArea (m2) | GrossSideArea (m2) | NetSideArea (m2) | GrossVolume (m3) | NetVolume (m3)
Metalstud 100mm | 12082 | 3390 | 0.566464 | 40.8163 | 13.1359 | 8.1874 | 2.65132
Metalstud 100mm | 3762.02 | 3470 | 0.364632 | 13.0542 | 8.40491 | 2.58387 | 1.65401
Metalstud 100mm | 26106 | 3390 | 3.43532 | 87.7392 | 59.4316 | 17.5607 | 11.8992
Metalstud 100mm | 2600.06 | 3400 | 0.166731 | 8.70444 | 3.66445 | 1.78459 | 0.776597
Metalstud 100mm | 10479 | 3390 | 1.8865 | 35.3825 | 25.5632 | 7.09626 | 5.1324
Metalstud 100mm | 22971 | 3470 | 2.81516 | 77.2278 | 49.4676 | 15.4604 | 9.90838
Binnenwand | 7599.99 | 3390 | 0.914713 | 25.764 | 18.354 | 5.13488 | 3.65288
Metalstud 100mm | 9747.33 | 3390 | 1.564 | 32.4476 | 28.043 | 6.52237 | 5.64145
Metalstud 100mm | 3836 | 3470 | 0.75379 | 13.2892 | 13.2892 | 2.61565 | 2.61565
Metalstud 100mm | 8634.94 | 3400 | 1.1455 | 29.1568 | 22.4204 | 5.81208 | 4.4648
Metalstud 100mm | 563.91 | 3400 | 0.112782 | 1.90129 | 1.90129 | 0.378068 | 0.378068
Metalstud 100mm | 2135 | 3390 | 0.432937 | 7.19615 | 7.19615 | 1.42055 | 1.42055

# IfcWall: 22 Metalstud 255mm 255 (2)
In: Begane grond
Type - PredefinedType: ELEMENTEDWALL
Classification: Samengestelde wand (ARCHICAD Classification); 21 Buitenwanden (NL/SfB (4 cijfers))
CPset_Phasing - Renovation Phase: Bestaand
AC_Pset_RenovationAndPhasing - Renovation Status: Existing
Pset_WallCommon - LoadBearing: yes; IsExternal: yes
BaseQuantities - Width: 255 mm
Name | Length (mm) | Height (mm) | GrossFootprintArea (m2) = NetFootprintArea (m2) | GrossSideArea (m2) | NetSideArea (m2) | GrossVolume (m3) | NetVolume (m3)
Binnenwand | 7192.5 | 3470 | 1.84285 | 24.8352 | 24.8352 | 6.39034 | 6.39034
Binnenwand | 7512.4 | 3390 | 1.43112 | 25.2998 | 19.0016 | 6.44247 | 4.83636

# IfcWall: 22 Metalstud 75_enkelzijdig 75 (16)
In: Begane grond
Type - PredefinedType: ELEMENTEDWALL
Classification: Samengestelde wand (ARCHICAD Classification); 21 Buitenwanden (NL/SfB (4 cijfers))
CPset_Phasing - Renovation Phase: Bestaand
AC_Pset_RenovationAndPhasing - Renovation Status: Existing
Pset_WallCommon - LoadBearing: yes; IsExternal: yes
BaseQuantities - Width: 75 mm
Name | Length (mm) | Height (mm) | GrossFootprintArea (m2) = NetFootprintArea (m2) | GrossSideArea (m2) = NetSideArea (m2) | GrossVolume (m3) = NetVolume (m3)
Binnenwand | 8133.76 | 3470 | 0.605344 | 27.9639 | 2.10054
Binnenwand | 1050 | 3400 | 0.0815625 | 3.655 | 0.277313
Binnenwand | 2295.98 | 3400 | 0.172198 | 7.80633 | 0.585475
Binnenwand | 2300.02 | 3190 | 0.172501 | 7.33706 | 0.550279
Binnenwand | 2168 | 3190 | 0.1551 | 6.59692 | 0.494769
Binnenwand | 1049.98 | 3190 | 0.0787485 | 3.34944 | 0.251208
Binnenwand | 1049.95 | 3190 | 0.0787459 | 3.34933 | 0.251199
Binnenwand | 2550 | 3190 | 0.18375 | 7.8155 | 0.586163
Binnenwand | 275 | 3470 | 0.020625 | 1.01931 | 0.0715688
2 x Binnenwand | 582.5 | 3470 | 0.0465 | 2.1514 | 0.161355
Binnenwand | 182.5 | 3470 | 0.0136875 | 0.654963 | 0.0474956
Binnenwand | 582.5 | 3470 | 0.0436875 | 2.04296 | 0.151596
Metalstud 100mm | 962.5 | 3400 | 0.075 | 3.32 | 0.249
Metalstud 100mm | 227.556 | 3400 | 0.0156604 | 0.74594 | 0.052833
Binnenwand | 1050 | 3190 | 0.07875 | 3.3495 | 0.251213

# IfcWall: 22 Metalstud 75_enkelzijdig_Ref tpv gips 75 (11)
In: Begane grond
Type - PredefinedType: ELEMENTEDWALL
Classification: Samengestelde wand (ARCHICAD Classification); 21 Buitenwanden (NL/SfB (4 cijfers))
CPset_Phasing - Renovation Phase: Bestaand
AC_Pset_RenovationAndPhasing - Renovation Status: Existing
Pset_WallCommon - LoadBearing: yes; IsExternal: yes
BaseQuantities - Width: 75 mm
Name | Length (mm) | Height (mm) | GrossFootprintArea (m2) = NetFootprintArea (m2) | GrossSideArea (m2) = NetSideArea (m2) | GrossVolume (m3) = NetVolume (m3)
2 x Binnenwand | 1050 | 3400 | 0.0815625 | 3.655 | 0.277313
2 x Binnenwand | 2230 | 3400 | 0.170062 | 7.667 | 0.578213
2 x Binnenwand | 1090 | 3480 | 0.08175 | 3.7932 | 0.28449
2 x Binnenwand | 1320 | 3320 | 0.100406 | 4.36165 | 0.333349
Binnenwand | 1055 | 3400 | 0.0819376 | 3.672 | 0.278588
Metalstud 100mm | 2800 | 3400 | 0.211406 | 9.4495 | 0.706356
Metalstud 100mm | 7936 | 3400 | 0.564732 | 25.3029 | 1.91836

# IfcWall: 300*500 (16)
In: Begane grond
Description: 300*500; Classification: 22.1 niet constructief (NL/SfB (4 cijfers)); Wand (ARCHICAD Classification); Material: CONCRETE/C30/37
Default - Stortmethode: Insitu; NL-SfB_DESCRIPTION: Funderingsmuur insitu; NL-SfB_NUMBERCODE: 16.14.41; IS_EXTERNAL: Nee; LOAD_BEARING: Ondersteuning; FIRE_RATING: R0; IFC_CLASS_REF_CODE: 16.14.41 ; Funderingsmuur insitu; IFC_BUILDING_STOREY: Undefined; IFC_BUILDING: XXXX Gebouw; MATERIAL: C30/37; NAME: WAND-FUNDERING
Pset_WallCommon - ExtendToStructure: no; Compartmentation: no; Combustible: no; FireRating: R0; Reference: W0(?); LoadBearing: yes; IsExternal: no
Tekla Common - Bottom elevation: -0.940; Top elevation: -0.440; Phase: 1; Class: 3
Tekla Quantity - Height: 500 mm; Width: 300 mm
CPset_Phasing - Renovation Phase: Bestaand
AC_Pset_RenovationAndPhasing - Renovation Status: Existing
Material Properties - CONCRETE/C30/37, ThermalConductivity: 2.3; CONCRETE/C30/37, SpecificHeatCapacity: 1000 J/kg/K; CONCRETE/C30/37, MassDensity: 2300 kg/m3; CONCRETE/C30/37, Embodied Energy: 1.92 (MJ/kg); CONCRETE/C30/37, Embodied Carbon: 0.198 (kgCO₂/kg); CONCRETE/C30/37, Name: CONCRETE/C30/37; CONCRETE/C30/37, Participates in Collision Detection: yes
BaseQuantities - Height: 500 mm; Width: 300 mm
Component Quantities - CONCRETE/C30/37, Component Thickness: 300 mm; CONCRETE/C30/37, Rectangular Component Height: 500 mm; CONCRETE/C30/37, Rectangular Component Width: 300 mm; CONCRETE/C30/37, Component Cross Section Area: 0.15 m2
Name | Weight (kg) | Volume (m3) | Gross footprint area (m2) | Area per tons (m2) | Net surface area (m2) | Tekla Quantity, Length (mm) | BaseQuantities, Length (mm) | GrossFootprintArea (m2) = NetFootprintArea (m2) | GrossSideArea (m2) = NetSideArea (m2) = CONCRETE/C30/37, Projected Component Area (Net) (m2) = CONCRETE/C30/37, Projected Component Area (Gross) (m2) | GrossVolume (m3) = NetVolume (m3) = CONCRETE/C30/37, Component Volume (Net) (m3) = CONCRETE/C30/37, Component Volume (Gross) (m3) | CONCRETE/C30/37, Mass (kg)
WAND-FUNDERING | 9381.6 | 3.909 | 7.818 | 4.476 | 41.996 | 26060 | 26060 | 7.818 | 13.03 | 3.909 | 8990.7
WAND-FUNDERING | 6570 | 2.737 | 5.475 | 4.49 | 29.5 | 18250 | 18250 | 5.475 | 9.125 | 2.7375 | 6296.25
WAND-FUNDERING | 10636.6 | 4.432 | 8.864 | 4.473 | 47.574 | 29546 | 29546 | 8.86381 | 14.773 | 4.4319 | 10193.4
WAND-FUNDERING | 1213.2 | 0.506 | 1.011 | 4.692 | 5.692 | 3370 | 3370 | 1.011 | 1.685 | 0.5055 | 1162.65
WAND-FUNDERING | 6685.2 | 2.785 | 5.571 | 4.489 | 30.012 | 18570 | 18570 | 5.571 | 9.285 | 2.7855 | 6406.65
WAND-FUNDERING | 18525.6 | 7.719 | 15.438 | 4.461 | 82.636 | 51460 | 51460 | 15.438 | 25.73 | 7.719 | 17753.7
WAND-FUNDERING | 2120.4 | 0.883 | 1.767 | 4.586 | 9.724 | 5890 | 5890 | 1.767 | 2.945 | 0.883499 | 2032.05
WAND-FUNDERING | 2145.6 | 0.894 | 1.788 | 4.584 | 9.836 | 5960 | 5960 | 1.788 | 2.98 | 0.894 | 2056.2
WAND-FUNDERING | 8224.55 | 3.427 | 6.854 | 4.481 | 36.854 | 22846 | 22846 | 6.8538 | 11.423 | 3.4269 | 7881.86
WAND-FUNDERING | 338.4 | 0.141 | 0.282 | 5.331 | 1.804 | 940 | 940.004 | 0.282001 | 0.470002 | 0.141001 | 324.302
WAND-FUNDERING | 2161.45 | 0.901 | 1.801 | 4.583 | 9.906 | 6004 | 6004.02 | 1.8012 | 3.00201 | 0.900602 | 2071.39
WAND-FUNDERING | 338.4 | 0.141 | 0.282 | 5.331 | 1.804 | 940 | 940.005 | 0.282001 | 0.470002 | 0.141001 | 324.302
WAND-FUNDERING | 8247.6 | 3.437 | 6.873 | 4.481 | 36.956 | 22910 | 22910 | 6.873 | 11.455 | 3.4365 | 7903.95
WAND-FUNDERING | 4800.96 | 2 | 4.001 | 4.507 | 21.638 | 13336 | 13336 | 4.0008 | 6.66799 | 2.0004 | 4600.92
WAND-FUNDERING | 6784.2 | 2.827 | 5.653 | 4.489 | 30.452 | 18845 | 18845 | 5.6535 | 9.4225 | 2.82675 | 6501.52
WAND-FUNDERING | 4233.6 | 1.764 | 3.528 | 4.515 | 19.116 | 11760 | 11760 | 3.528 | 5.88 | 1.764 | 4057.2

# IfcWall: 300*670 (9)
In: Begane grond
Description: 300*670; Classification: 22.1 niet constructief (NL/SfB (4 cijfers)); Wand (ARCHICAD Classification); Material: CONCRETE/C30/37
Default - Stortmethode: Insitu; IS_EXTERNAL: Nee; LOAD_BEARING: Ondersteuning; FIRE_RATING: R0; IFC_BUILDING_STOREY: Undefined; MATERIAL: C30/37; NAME: WAND-FUNDERING
Pset_WallCommon - ExtendToStructure: no; Compartmentation: no; Combustible: no; FireRating: R0; Reference: W0(?); LoadBearing: yes; IsExternal: no
Tekla Common - Bottom elevation: -0.940; Top elevation: -0.270; Phase: 1; Class: 3
Tekla Quantity - Height: 670 mm; Width: 300 mm
CPset_Phasing - Renovation Phase: Bestaand
AC_Pset_RenovationAndPhasing - Renovation Status: Existing
Material Properties - CONCRETE/C30/37, ThermalConductivity: 2.3; CONCRETE/C30/37, SpecificHeatCapacity: 1000 J/kg/K; CONCRETE/C30/37, MassDensity: 2300 kg/m3; CONCRETE/C30/37, Embodied Energy: 1.92 (MJ/kg); CONCRETE/C30/37, Embodied Carbon: 0.198 (kgCO₂/kg); CONCRETE/C30/37, Name: CONCRETE/C30/37; CONCRETE/C30/37, Participates in Collision Detection: yes
BaseQuantities - Height: 670 mm; Width: 300 mm
Component Quantities - CONCRETE/C30/37, Component Thickness: 300 mm; CONCRETE/C30/37, Rectangular Component Height: 670 mm; CONCRETE/C30/37, Rectangular Component Width: 300 mm; CONCRETE/C30/37, Component Cross Section Area: 0.201 m2
Name | NL-SfB_DESCRIPTION | NL-SfB_NUMBERCODE | IFC_CLASS_REF_CODE | IFC_BUILDING | Weight (kg) | Volume (m3) | Gross footprint area (m2) | Area per tons (m2) | Net surface area (m2) | Tekla Quantity, Length (mm) | BaseQuantities, Length (mm) | GrossFootprintArea (m2) = NetFootprintArea (m2) | GrossSideArea (m2) = NetSideArea (m2) | GrossVolume (m3) = NetVolume (m3) = CONCRETE/C30/37, Component Volume (Net) (m3) | CONCRETE/C30/37, Mass (kg) | CONCRETE/C30/37, Projected Component Area (Net) (m2) | CONCRETE/C30/37, Projected Component Area (Gross) (m2) | CONCRETE/C30/37, Component Volume (Gross) (m3)
WAND-FUNDERING | Funderingsmuur insitu | 16.14.41 | 16.14.41 ; Funderingsmuur insitu | XXXX Gebouw | 10399.6 | 4.333 | 6.467 | 4.061 | 42.225 | 21558 | 21558 | 6.4674 | 14.4439 | 4.33316 | 9966.26 | 14.4439 | 14.4439 | 4.33316
WAND-FUNDERING | Funderingsmuur insitu | 16.14.41 | 16.14.41 ; Funderingsmuur insitu | XXXX Gebouw | 8171.37 | 3.405 | 5.082 | 4.071 | 33.264 | 16939 | 16939 | 5.0817 | 11.3491 | 3.40474 | 7830.9 | 11.3491 | 11.3491 | 3.40474
WAND-FUNDERING | Funderingsmuur insitu | 16.14.41 | 16.14.41 ; Funderingsmuur insitu | XXXX Gebouw | 3159.26 | 1.316 | 1.965 | 4.149 | 13.107 | 6549 | 6549.04 | 1.96471 | 3.84309 | 1.21459 | 2793.55 | 4.38786 | 4.38786 | 1.21459
WAND-FUNDERING | Funderingsmuur insitu | 16.14.41 | 16.14.41 ; Funderingsmuur insitu | XXXX Gebouw | 4958.59 | 2.066 | 3.083 | 4.103 | 20.343 | 10279 | 10279 | 3.0837 | 6.88693 | 2.06608 | 4751.98 | 6.88693 | 6.88693 | 2.06608
WAND-FUNDERING | Funderingsmuur insitu | 16.14.41 | 16.14.41 ; Funderingsmuur insitu | XXXX Gebouw | 2255.22 | 0.94 | 1.402 | 4.2 | 9.472 | 4675 | 4675 | 1.4025 | 3.13225 | 0.939675 | 2161.25 | 3.13225 | 3.13225 | 0.939675
WAND-FUNDERING | Funderingsmuur insitu | 16.14.41 | 16.14.41 ; Funderingsmuur insitu | XXXX Gebouw | 4224.75 | 1.76 | 0.828 | 4.677 | 19.758 | 10390 | 10390 | 3.11699 | 6.42381 | 1.70984 | 3932.64 | 6.80651 | 6.96129 | 1.92902
WAND-FUNDERING | Funderingsmuur insitu | 16.14.41 | 16.14.41 ; Funderingsmuur insitu | XXXX Gebouw | 10158.9 | 4.233 | 6.318 | 4.061 | 41.256 | 21059 | 21059 | 6.3177 | 12.4649 | 3.73947 | 8600.77 | 12.4649 | 12.4649 | 3.73947
WAND-FUNDERING | Balkenfundering insitu | 16.12.41 | 16.12.41 ; Balkenfundering insitu | Undefined | 2258.12 | 0.941 | 1.404 | 4.2 | 9.483 | 4681 | 4681.02 | 1.40431 | 3.13628 | 0.940885 | 2164.04 | 3.13628 | 3.13628 | 0.940885
WAND-FUNDERING | Balkenfundering insitu | 16.12.41 | 16.12.41 ; Balkenfundering insitu | Undefined | 2185.27 | 0.911 | 1.359 | 4.206 | 9.19 | 4530 | 4530 | 1.314 | 2.9346 | 0.88038 | 2024.87 | 2.9346 | 2.9346 | 0.88038

# IfcWall: 300*960 (8)
In: Begane grond
Description: 300*960; Classification: 22.1 niet constructief (NL/SfB (4 cijfers)); Wand (ARCHICAD Classification); Material: CONCRETE/C30/37
Tekla Common - Bottom elevation: -0.500; Top elevation: +0.460; Phase: 1; Class: 3
Default - Stortmethode: Insitu; NL-SfB_DESCRIPTION: Funderingsmuur insitu; NL-SfB_NUMBERCODE: 16.14.41; IS_EXTERNAL: Nee; LOAD_BEARING: Ondersteuning; FIRE_RATING: R0; IFC_CLASS_REF_CODE: 16.14.41 ; Funderingsmuur insitu; IFC_BUILDING_STOREY: Undefined; IFC_BUILDING: XXXX Gebouw; MATERIAL: C30/37; NAME: WAND-FUNDERING
Pset_WallCommon - ExtendToStructure: no; Compartmentation: no; Combustible: no; FireRating: R0; Reference: W0(?); LoadBearing: yes; IsExternal: no
Tekla Quantity - Height: 960 mm; Width: 300 mm
CPset_Phasing - Renovation Phase: Bestaand
AC_Pset_RenovationAndPhasing - Renovation Status: Existing
Material Properties - CONCRETE/C30/37, ThermalConductivity: 2.3; CONCRETE/C30/37, SpecificHeatCapacity: 1000 J/kg/K; CONCRETE/C30/37, MassDensity: 2300 kg/m3; CONCRETE/C30/37, Embodied Energy: 1.92 (MJ/kg); CONCRETE/C30/37, Embodied Carbon: 0.198 (kgCO₂/kg); CONCRETE/C30/37, Name: CONCRETE/C30/37; CONCRETE/C30/37, Participates in Collision Detection: yes
BaseQuantities - Height: 960 mm; Width: 300 mm
Component Quantities - CONCRETE/C30/37, Component Thickness: 300 mm; CONCRETE/C30/37, Rectangular Component Height: 960 mm; CONCRETE/C30/37, Rectangular Component Width: 300 mm; CONCRETE/C30/37, Component Cross Section Area: 0.288 m2
Name | Weight (kg) | Volume (m3) | Gross footprint area (m2) | Area per tons (m2) | Net surface area (m2) | Tekla Quantity, Length (mm) | BaseQuantities, Length (mm) | GrossFootprintArea (m2) = NetFootprintArea (m2) | GrossSideArea (m2) = NetSideArea (m2) | GrossVolume (m3) = NetVolume (m3) = CONCRETE/C30/37, Component Volume (Net) (m3) = CONCRETE/C30/37, Component Volume (Gross) (m3) | CONCRETE/C30/37, Mass (kg) | CONCRETE/C30/37, Projected Component Area (Net) (m2) = CONCRETE/C30/37, Projected Component Area (Gross) (m2)
WAND-FUNDERING | 24900.5 | 10.375 | 10.808 | 3.67 | 91.359 | 36025 | 36025 | 10.8075 | 34.584 | 10.3752 | 23863 | 34.584
WAND-FUNDERING | 1244.16 | 0.518 | 0.54 | 4.109 | 5.112 | 1800 | 1800 | 0.54 | 1.728 | 0.5184 | 1192.32 | 1.728
WAND-FUNDERING | 6825.6 | 2.844 | 2.962 | 3.73 | 25.461 | 9875 | 9875 | 2.9625 | 9.48 | 2.844 | 6541.2 | 9.48
WAND-FUNDERING | 5114.88 | 2.131 | 2.22 | 3.758 | 19.224 | 7400 | 7400 | 2.18287 | 6.996 | 2.09556 | 4819.79 | 7.104
WAND-FUNDERING | 2851.2 | 1.188 | 1.238 | 3.848 | 10.971 | 4125 | 4275 | 1.2375 | 3.96 | 1.188 | 2732.4 | 3.96
WAND-FUNDERING | 23535.4 | 9.806 | 10.215 | 3.67 | 86.382 | 34050 | 33900 | 10.125 | 32.331 | 9.71392 | 22342 | 32.4
WAND-FUNDERING | 3749.76 | 1.562 | 1.628 | 3.799 | 14.247 | 5425 | 5425 | 1.6275 | 5.208 | 1.5624 | 3593.52 | 5.208
WAND-FUNDERING | 8432.64 | 3.514 | 3.66 | 3.714 | 31.32 | 12200 | 12200 | 3.66 | 11.643 | 3.50752 | 8067.29 | 11.712

# IfcWall: 320*500 (4)
In: Begane grond
Description: 320*500; Classification: 22.1 niet constructief (NL/SfB (4 cijfers)); Wand (ARCHICAD Classification); Material: CONCRETE/C30/37
Default - Stortmethode: Insitu; NL-SfB_DESCRIPTION: Funderingsmuur insitu; NL-SfB_NUMBERCODE: 16.14.41; IS_EXTERNAL: Nee; LOAD_BEARING: Ondersteuning; FIRE_RATING: R0; IFC_CLASS_REF_CODE: 16.14.41 ; Funderingsmuur insitu; IFC_BUILDING_STOREY: Undefined; IFC_BUILDING: XXXX Gebouw; MATERIAL: C30/37; NAME: WAND-FUNDERING
Pset_WallCommon - ExtendToStructure: no; Compartmentation: no; Combustible: no; FireRating: R0; Reference: W0(?); LoadBearing: yes; IsExternal: no
Tekla Common - Bottom elevation: -0.940; Top elevation: -0.440; Phase: 1; Class: 3
Tekla Quantity - Height: 500 mm; Width: 320 mm
CPset_Phasing - Renovation Phase: Bestaand
AC_Pset_RenovationAndPhasing - Renovation Status: Existing
Material Properties - CONCRETE/C30/37, ThermalConductivity: 2.3; CONCRETE/C30/37, SpecificHeatCapacity: 1000 J/kg/K; CONCRETE/C30/37, MassDensity: 2300 kg/m3; CONCRETE/C30/37, Embodied Energy: 1.92 (MJ/kg); CONCRETE/C30/37, Embodied Carbon: 0.198 (kgCO₂/kg); CONCRETE/C30/37, Name: CONCRETE/C30/37; CONCRETE/C30/37, Participates in Collision Detection: yes
BaseQuantities - Height: 500 mm; Width: 320 mm
Component Quantities - CONCRETE/C30/37, Component Thickness: 320 mm; CONCRETE/C30/37, Rectangular Component Height: 500 mm; CONCRETE/C30/37, Rectangular Component Width: 320 mm; CONCRETE/C30/37, Component Cross Section Area: 0.16 m2
Name | Weight (kg) | Volume (m3) | Gross footprint area (m2) | Area per tons (m2) | Net surface area (m2) | Tekla Quantity, Length (mm) = BaseQuantities, Length (mm) | GrossFootprintArea (m2) = NetFootprintArea (m2) | GrossSideArea (m2) = NetSideArea (m2) | GrossVolume (m3) = NetVolume (m3) = CONCRETE/C30/37, Component Volume (Net) (m3) = CONCRETE/C30/37, Component Volume (Gross) (m3) | CONCRETE/C30/37, Mass (kg) | CONCRETE/C30/37, Projected Component Area (Net) (m2) = CONCRETE/C30/37, Projected Component Area (Gross) (m2)
WAND-FUNDERING | 2261.76 | 0.942 | 1.885 | 4.412 | 9.98 | 5890 | 1.8848 | 2.945 | 0.942399 | 2167.52 | 2.945
WAND-FUNDERING | 6036.87 | 2.515 | 5.031 | 4.324 | 26.102 | 15721 | 5.03072 | 7.8605 | 2.51536 | 5785.33 | 7.8605
WAND-FUNDERING | 10241.3 | 4.267 | 8.534 | 4.302 | 44.059 | 26670 | 8.432 | 13.175 | 4.216 | 9696.8 | 13.175
WAND-FUNDERING | 12299.5 | 5.125 | 10.25 | 4.297 | 52.849 | 32030 | 10.2496 | 15.9684 | 5.10486 | 11741.2 | 16.015

# IfcWall: 339*500, WAND-FUNDERING
In: Begane grond
Description: 339*500; Classification: 22.1 niet constructief (NL/SfB (4 cijfers)); Wand (ARCHICAD Classification); Material: CONCRETE/C30/37
Default - Stortmethode: Insitu; NL-SfB_DESCRIPTION: Funderingsmuur insitu; NL-SfB_NUMBERCODE: 16.14.41; IS_EXTERNAL: Nee; LOAD_BEARING: Ondersteuning; FIRE_RATING: R0; IFC_CLASS_REF_CODE: 16.14.41 ; Funderingsmuur insitu; IFC_BUILDING_STOREY: Undefined; IFC_BUILDING: XXXX Gebouw; MATERIAL: C30/37; NAME: WAND-FUNDERING
Pset_WallCommon - ExtendToStructure: no; Compartmentation: no; Combustible: no; FireRating: R0; Reference: W0(?); LoadBearing: yes; IsExternal: no
Tekla Common - Bottom elevation: -0.940; Top elevation: -0.440; Phase: 1; Class: 3
Tekla Quantity - Weight: 1566.23 kg; Volume: 0.653 m3; Gross footprint area: 1.305 m2; Area per tons: 4.341 m2; Net surface area: 6.799 m2; Height: 500 mm; Width: 339 mm; Length: 3850 mm
CPset_Phasing - Renovation Phase: Bestaand
AC_Pset_RenovationAndPhasing - Renovation Status: Existing
Material Properties - CONCRETE/C30/37, ThermalConductivity: 2.3; CONCRETE/C30/37, SpecificHeatCapacity: 1000 J/kg/K; CONCRETE/C30/37, MassDensity: 2300 kg/m3; CONCRETE/C30/37, Embodied Energy: 1.92 (MJ/kg); CONCRETE/C30/37, Embodied Carbon: 0.198 (kgCO₂/kg); CONCRETE/C30/37, Name: CONCRETE/C30/37; CONCRETE/C30/37, Participates in Collision Detection: yes
BaseQuantities - Length: 3850 mm; Height: 500 mm; Width: 339.01 mm; GrossFootprintArea: 1.30519 m2; NetFootprintArea: 1.30519 m2; GrossSideArea: 1.925 m2; NetSideArea: 1.925 m2; GrossVolume: 0.652594 m3; NetVolume: 0.652594 m3
Component Quantities - CONCRETE/C30/37, Mass: 1500.97 kg; CONCRETE/C30/37, Projected Component Area (Net): 1.925 m2; CONCRETE/C30/37, Projected Component Area (Gross): 1.925 m2; CONCRETE/C30/37, Component Thickness: 339.01 mm; CONCRETE/C30/37, Rectangular Component Height: 500 mm; CONCRETE/C30/37, Rectangular Component Width: 339.01 mm; CONCRETE/C30/37, Component Cross Section Area: 0.169505 m2; CONCRETE/C30/37, Component Volume (Net): 0.652594 m3; CONCRETE/C30/37, Component Volume (Gross): 0.652594 m3

# IfcWall: 400*960 (4)
In: Begane grond
Description: 400*960; Classification: 22.1 niet constructief (NL/SfB (4 cijfers)); Wand (ARCHICAD Classification); Material: CONCRETE/C30/37
Tekla Common - Bottom elevation: -0.500; Top elevation: +0.460; Phase: 1; Class: 3
Default - Stortmethode: Insitu; NL-SfB_DESCRIPTION: Funderingsmuur insitu; NL-SfB_NUMBERCODE: 16.14.41; IS_EXTERNAL: Nee; LOAD_BEARING: Ondersteuning; FIRE_RATING: R0; IFC_CLASS_REF_CODE: 16.14.41 ; Funderingsmuur insitu; IFC_BUILDING_STOREY: Undefined; IFC_BUILDING: XXXX Gebouw; MATERIAL: C30/37; NAME: WAND-FUNDERING
Pset_WallCommon - ExtendToStructure: no; Compartmentation: no; Combustible: no; FireRating: R0; Reference: W0(?); LoadBearing: yes; IsExternal: no
Tekla Quantity - Height: 960 mm; Width: 400 mm
CPset_Phasing - Renovation Phase: Bestaand
AC_Pset_RenovationAndPhasing - Renovation Status: Existing
Material Properties - CONCRETE/C30/37, ThermalConductivity: 2.3; CONCRETE/C30/37, SpecificHeatCapacity: 1000 J/kg/K; CONCRETE/C30/37, MassDensity: 2300 kg/m3; CONCRETE/C30/37, Embodied Energy: 1.92 (MJ/kg); CONCRETE/C30/37, Embodied Carbon: 0.198 (kgCO₂/kg); CONCRETE/C30/37, Name: CONCRETE/C30/37; CONCRETE/C30/37, Participates in Collision Detection: yes
BaseQuantities - Height: 960 mm; Width: 400 mm
Component Quantities - CONCRETE/C30/37, Component Thickness: 400 mm; CONCRETE/C30/37, Rectangular Component Height: 960 mm; CONCRETE/C30/37, Rectangular Component Width: 400 mm; CONCRETE/C30/37, Component Cross Section Area: 0.384 m2
Name | Weight (kg) | Volume (m3) | Gross footprint area (m2) | Area per tons (m2) | Net surface area (m2) | Tekla Quantity, Length (mm) | BaseQuantities, Length (mm) | GrossFootprintArea (m2) = NetFootprintArea (m2) | GrossSideArea (m2) = NetSideArea (m2) = CONCRETE/C30/37, Projected Component Area (Net) (m2) | GrossVolume (m3) = NetVolume (m3) = CONCRETE/C30/37, Component Volume (Net) (m3) | CONCRETE/C30/37, Mass (kg) | CONCRETE/C30/37, Projected Component Area (Gross) (m2) | CONCRETE/C30/37, Component Volume (Gross) (m3)
WAND-FUNDERING | 7902.72 | 3.293 | 3.43 | 3.146 | 24.86 | 9575 | 9575 | 3.43 | 8.232 | 3.2928 | 7573.44 | 9.192 | 3.6768
WAND-FUNDERING | 6312.96 | 2.63 | 2.74 | 3.073 | 19.4 | 6850 | 6850 | 2.74 | 6.576 | 2.6304 | 6049.92 | 6.576 | 2.6304
WAND-FUNDERING | 4331.52 | 1.805 | 1.88 | 3.129 | 13.552 | 4700 | 4900 | 1.88 | 4.512 | 1.8048 | 4151.04 | 4.512 | 1.8048
WAND-FUNDERING | 25758.7 | 10.733 | 11.18 | 3.071 | 79.096 | 30950 | 30750 | 11.02 | 26.448 | 10.5792 | 24332.1 | 29.328 | 11.7312

# IfcWall: 450*500 (5)
In: Begane grond
Description: 450*500; Classification: 22.1 niet constructief (NL/SfB (4 cijfers)); Wand (ARCHICAD Classification); Material: CONCRETE/C30/37
Default - Stortmethode: Insitu; NL-SfB_DESCRIPTION: Funderingsmuur insitu; NL-SfB_NUMBERCODE: 16.14.41; IS_EXTERNAL: Nee; LOAD_BEARING: Ondersteuning; FIRE_RATING: R0; IFC_CLASS_REF_CODE: 16.14.41 ; Funderingsmuur insitu; IFC_BUILDING_STOREY: Undefined; IFC_BUILDING: XXXX Gebouw; MATERIAL: C30/37; NAME: WAND-FUNDERING
Pset_WallCommon - ExtendToStructure: no; Compartmentation: no; Combustible: no; FireRating: R0; Reference: W0(?); LoadBearing: yes; IsExternal: no
Tekla Common - Bottom elevation: -0.940; Top elevation: -0.440; Phase: 1; Class: 3
Tekla Quantity - Height: 500 mm; Width: 450 mm
CPset_Phasing - Renovation Phase: Bestaand
AC_Pset_RenovationAndPhasing - Renovation Status: Existing
Material Properties - CONCRETE/C30/37, ThermalConductivity: 2.3; CONCRETE/C30/37, SpecificHeatCapacity: 1000 J/kg/K; CONCRETE/C30/37, MassDensity: 2300 kg/m3; CONCRETE/C30/37, Embodied Energy: 1.92 (MJ/kg); CONCRETE/C30/37, Embodied Carbon: 0.198 (kgCO₂/kg); CONCRETE/C30/37, Name: CONCRETE/C30/37; CONCRETE/C30/37, Participates in Collision Detection: yes
BaseQuantities - Height: 500 mm; Width: 450 mm
Component Quantities - CONCRETE/C30/37, Component Thickness: 450 mm; CONCRETE/C30/37, Rectangular Component Height: 500 mm; CONCRETE/C30/37, Rectangular Component Width: 450 mm; CONCRETE/C30/37, Component Cross Section Area: 0.225 m2
Name | Weight (kg) | Volume (m3) | Gross footprint area (m2) | Area per tons (m2) | Net surface area (m2) | Tekla Quantity, Length (mm) | BaseQuantities, Length (mm) | GrossFootprintArea (m2) = NetFootprintArea (m2) | GrossSideArea (m2) = NetSideArea (m2) = CONCRETE/C30/37, Projected Component Area (Net) (m2) = CONCRETE/C30/37, Projected Component Area (Gross) (m2) | GrossVolume (m3) = NetVolume (m3) = CONCRETE/C30/37, Component Volume (Net) (m3) = CONCRETE/C30/37, Component Volume (Gross) (m3) | CONCRETE/C30/37, Mass (kg)
WAND-FUNDERING | 6373.62 | 2.656 | 5.311 | 3.589 | 22.876 | 11803 | 11803 | 5.1426 | 5.714 | 2.5713 | 5913.99
WAND-FUNDERING | 14472 | 6.03 | 12.06 | 3.55 | 51.37 | 26800 | 26800 | 12.06 | 13.4 | 6.03 | 13869
WAND-FUNDERING | 4246.55 | 1.769 | 3.539 | 3.624 | 15.392 | 7864 | 7864.01 | 3.5388 | 3.932 | 1.7694 | 4069.62
WAND-FUNDERING | 10336.1 | 4.307 | 8.613 | 3.562 | 36.818 | 19141 | 19141 | 8.61346 | 9.57051 | 4.30673 | 9905.47
WAND-FUNDERING | 4478.75 | 1.866 | 3.732 | 3.619 | 16.209 | 8294 | 8293.99 | 3.7323 | 4.14699 | 1.86615 | 4292.14

# IfcWall: AFW - Wandtegelwerk 5 (431)
In: Begane grond
Type - PredefinedType: ELEMENTEDWALL
Classification: Samengestelde wand (ARCHICAD Classification); 21 Buitenwanden (NL/SfB (4 cijfers)); Material: AFW - Wandtegelwerk
CPset_Phasing - Renovation Phase: Bestaand
AC_Pset_RenovationAndPhasing - Renovation Status: Existing
Pset_WallCommon - LoadBearing: yes; IsExternal: yes
Material Properties - AFW - Wandtegelwerk, ThermalConductivity: 0.14; AFW - Wandtegelwerk, SpecificHeatCapacity: 1880 J/kg/K; AFW - Wandtegelwerk, MassDensity: 600 kg/m3; AFW - Wandtegelwerk, Embodied Energy: 14.5 (MJ/kg); AFW - Wandtegelwerk, Embodied Carbon: 0.52 (kgCO₂/kg); AFW - Wandtegelwerk, Name: AFW - Wandtegelwerk; AFW - Wandtegelwerk, Participates in Collision Detection: yes
BaseQuantities - Width: 5 mm
Component Quantities - AFW - Wandtegelwerk, Component Thickness: 5 mm; AFW - Wandtegelwerk, Rectangular Component Width: 5 mm
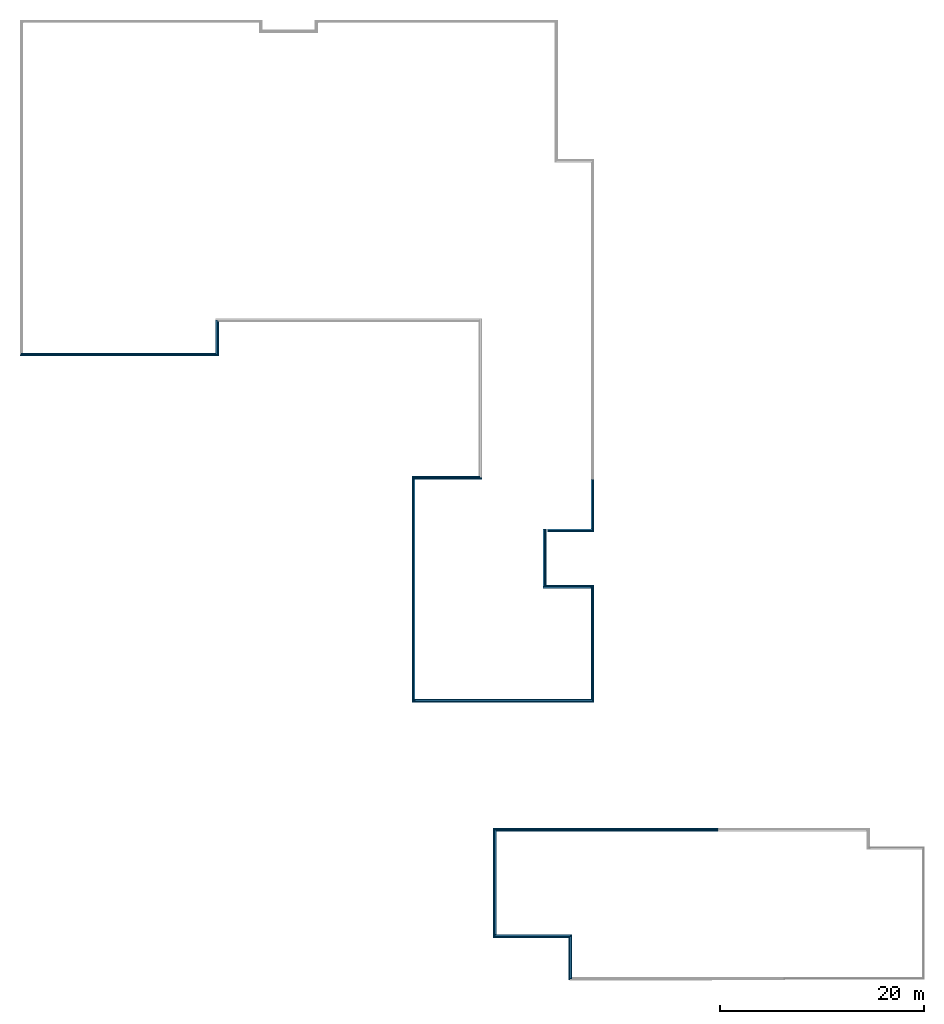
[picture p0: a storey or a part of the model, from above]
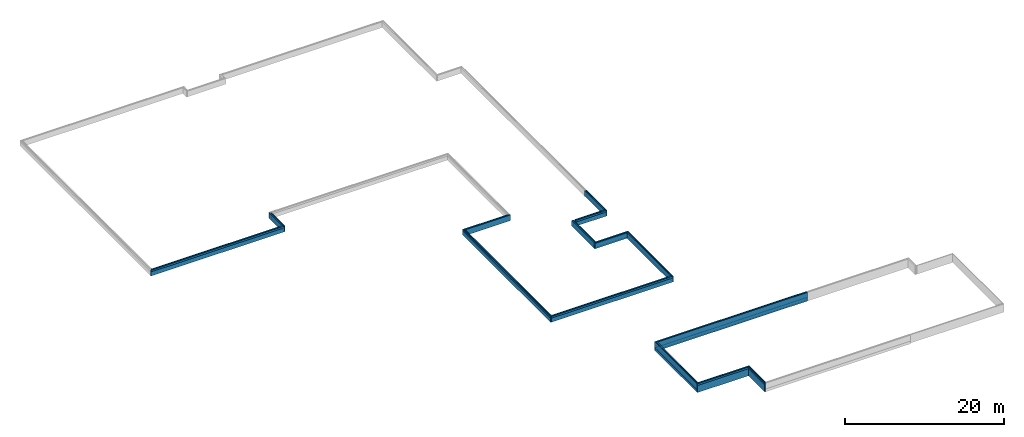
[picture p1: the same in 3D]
Properties of the parts of a building model (IFC2X3), part 18 of 19

# IfcWall: AFW - Wandtegelwerk 5 (431)
Name | Length (mm) | Height (mm) | GrossFootprintArea (m2) = NetFootprintArea (m2) | GrossSideArea (m2) = AFW - Wandtegelwerk, Projected Component Area (Gross) (m2) | NetSideArea (m2) | GrossVolume (m3) = AFW - Wandtegelwerk, Component Volume (Gross) (m3) | NetVolume (m3) = AFW - Wandtegelwerk, Component Volume (Net) (m3) | AFW - Wandtegelwerk, Mass (kg) | AFW - Wandtegelwerk, Projected Component Area (Net) (m2) | AFW - Wandtegelwerk, Rectangular Component Height (mm) | AFW - Wandtegelwerk, Component Cross Section Area (m2)
8 x Wandtegelwerk | 1089 | 1350 | 0.00547 | 1.4769 | 1.4769 | 0.0073845 | 0.0073845 | 4.4307 | 1.4769 | 1350 | 0.00675
7 x Wandtegelwerk | 1023 | 1350 | 0.005115 | 1.38105 | 1.38105 | 0.00690525 | 0.00690525 | 4.14315 | 1.38105 | 1350 | 0.00675
8 x Wandtegelwerk | 1089 | 1350 | 0.005445 | 1.47015 | 1.47015 | 0.00735075 | 0.00735075 | 4.41045 | 1.47015 | 1350 | 0.00675
2 x Wandtegelwerk | 1800 | 1350 | 0.009 | 2.43 | 2.43 | 0.01215 | 0.01215 | 7.29 | 2.43 | 1350 | 0.00675
3 x Wandtegelwerk | 1269 | 1350 | 0.00637 | 1.7199 | 1.7199 | 0.0085995 | 0.0085995 | 5.1597 | 1.7199 | 1350 | 0.00675
Wandtegelwerk | 1044 | 1350 | 0.00522001 | 1.4094 | 1.4094 | 0.00704701 | 0.00704701 | 4.22821 | 1.4094 | 1350 | 0.00675
2 x Wandtegelwerk | 1269 | 1350 | 0.006345 | 1.71315 | 1.71315 | 0.00856575 | 0.00856575 | 5.13945 | 1.71315 | 1350 | 0.00675
2 x Wandtegelwerk | 1044 | 1350 | 0.0000250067 | 1.40265 | 0.0067518 | 0.00701326 | 0.000033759 | 0.0202554 | 0.0067518 | 1350 | 0.00675
3 x Wandtegelwerk | 1039 | 1350 | 0.005195 | 1.40265 | 1.40265 | 0.00701325 | 0.00701325 | 4.20795 | 1.40265 | 1350 | 0.00675
Wandtegelwerk | 1269 | 1350 | 0.0063449 | 1.71315 | 1.70977 | 0.00856575 | 0.00856561 | 5.13937 | 1.71315 | 1350 | 0.00675
Wandtegelwerk | 1039 | 1350 | 1.02084e-07 | 1.3959 | 0.0000275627 | 0.0069795 | 1.37814e-07 | 0.0000826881 | 0.0000275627 | 1350 | 0.00675
3 x Wandtegelwerk | 2593.04 | 1350 | 0.0129902 | 3.50735 | 3.50735 | 0.0175367 | 0.0175367 | 10.522 | 3.50735 | 1350 | 0.00675
Wandtegelwerk | 1044 | 1350 | 0.0000500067 | 1.4094 | 0.0135018 | 0.00704701 | 0.000067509 | 0.0405054 | 0.0135018 | 1350 | 0.00675
2 x Wandtegelwerk | 2593.04 | 1350 | 0.0129652 | 3.5006 | 3.5006 | 0.017503 | 0.017503 | 10.5018 | 3.5006 | 1350 | 0.00675
2 x Wandtegelwerk | 1039 | 1350 | 0.000025 | 1.40265 | 0.00675 | 0.00701325 | 0.00003375 | 0.02025 | 0.00675 | 1350 | 0.00675
Wandtegelwerk | 2593.04 | 1350 | 0.0129651 | 3.5006 | 3.49722 | 0.017503 | 0.0175029 | 10.5017 | 3.5006 | 1350 | 0.00675
Wandtegelwerk | 1039 | 1350 | 1.02088e-07 | 1.3959 | 0.0000275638 | 0.0069795 | 1.37819e-07 | 0.0000826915 | 0.0000275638 | 1350 | 0.00675
Wandtegelwerk | 2229 | 1350 | 0.01117 | 3.0159 | 3.0159 | 0.0150795 | 0.0150795 | 9.0477 | 3.0159 | 1350 | 0.00675
Wandtegelwerk | 2219 | 1350 | 0.011095 | 2.99565 | 2.99565 | 0.0149782 | 0.0149782 | 8.98695 | 2.99565 | 1350 | 0.00675
Wandtegelwerk | 2229 | 1350 | 0.011145 | 3.00915 | 3.00915 | 0.0150457 | 0.0150457 | 9.02745 | 3.00915 | 1350 | 0.00675
Wandtegelwerk | 2219 | 1350 | 0.0059 | 2.9889 | 1.593 | 0.0149445 | 0.007965 | 4.779 | 1.593 | 1350 | 0.00675
Wandtegelwerk | 135 | 1350 | 0.0007 | 0.189 | 0.189 | 0.000945 | 0.000945 | 0.567 | 0.189 | 1350 | 0.00675
Wandtegelwerk | 3344 | 1350 | 0.01672 | 4.5144 | 4.5144 | 0.022572 | 0.022572 | 13.5432 | 4.5144 | 1350 | 0.00675
Wandtegelwerk | 2786.52 | 1350 | 0.0139451 | 3.76517 | 3.76517 | 0.0188259 | 0.0188259 | 11.2955 | 3.76517 | 1350 | 0.00675
Wandtegelwerk | 2843.26 | 1350 | 0.0141913 | 3.83166 | 3.83166 | 0.0191583 | 0.0191583 | 11.495 | 3.83166 | 1350 | 0.00675
Wandtegelwerk | 1039 | 1350 | 0.0000399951 | 1.3959 | 0.0107987 | 0.0069795 | 0.0000539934 | 0.032396 | 0.0107987 | 1350 | 0.00675
3 x Wandtegelwerk | 1200 | 2250 | 0.006 | 2.7 | 2.7 | 0.0135 | 0.0135 | 8.1 | 2.7 | 2250 | 0.01125
2 x Wandtegelwerk | 620 | 1350 | 0.003125 | 0.84375 | 0.84375 | 0.00421875 | 0.00421875 | 2.53125 | 0.84375 | 1350 | 0.00675
Wandtegelwerk | 3989.01 | 1350 | 0.01997 | 5.39191 | 5.39191 | 0.0269595 | 0.0269595 | 16.1757 | 5.39191 | 1350 | 0.00675
Wandtegelwerk | 2489 | 1350 | 0.007275 | 3.36015 | 1.96425 | 0.0168007 | 0.00982125 | 5.89275 | 1.96425 | 1350 | 0.00675
Wandtegelwerk | 1139.01 | 1350 | 0.00567003 | 1.53091 | 1.53091 | 0.00765455 | 0.00765455 | 4.59273 | 1.53091 | 1350 | 0.00675
Wandtegelwerk | 1869 | 1350 | 0.004175 | 2.52315 | 1.12725 | 0.0126157 | 0.00563625 | 3.38175 | 1.12725 | 1350 | 0.00675
Wandtegelwerk | 2269 | 1350 | 0.011345 | 3.06315 | 3.06315 | 0.0153157 | 0.0153157 | 9.18945 | 3.06315 | 1350 | 0.00675
Wandtegelwerk | 361 | 1350 | 0.00178 | 0.4806 | 0.4806 | 0.002403 | 0.002403 | 1.4418 | 0.4806 | 1350 | 0.00675
Wandtegelwerk | 220 | 1350 | 0.0011 | 0.297 | 0.297 | 0.001485 | 0.001485 | 0.891 | 0.297 | 1350 | 0.00675
Wandtegelwerk | 620 | 1350 | 0.003075 | 0.83025 | 0.83025 | 0.00415125 | 0.00415125 | 2.49075 | 0.83025 | 1350 | 0.00675
10 x Wandtegelwerk | 1200 | 2100 | 0.006 | 2.52 | 2.52 | 0.0126 | 0.0126 | 7.56 | 2.52 | 2100 | 0.0105
Wandtegelwerk | 1000 | 1500 | 0.005 | 1.5 | 1.5 | 0.0075 | 0.0075 | 4.5 | 1.5 | 1500 | 0.0075
2 x Wandtegelwerk | 1079 | 3000 | 0.00542 | 3.252 | 3.252 | 0.01626 | 0.01626 | 9.756 | 3.252 | 3000 | 0.015
Wandtegelwerk | 2284.98 | 3000 | 0.0114499 | 6.86994 | 6.86994 | 0.0343497 | 0.0343497 | 20.6098 | 6.86994 | 3000 | 0.015
2 x Wandtegelwerk | 5039 | 3000 | 0.02522 | 15.132 | 15.132 | 0.07566 | 0.07566 | 45.396 | 15.132 | 3000 | 0.015
Wandtegelwerk | 769.5 | 2850 | 0.00386 | 2.2002 | 2.2002 | 0.011001 | 0.011001 | 6.6006 | 2.2002 | 2850 | 0.01425
2 x Wandtegelwerk | 1864 | 2850 | 0.009345 | 5.32665 | 5.32665 | 0.0266333 | 0.0266333 | 15.98 | 5.32665 | 2850 | 0.01425
2 x Wandtegelwerk | 2464 | 2850 | 0.01232 | 7.0224 | 7.0224 | 0.035112 | 0.035112 | 21.0672 | 7.0224 | 2850 | 0.01425
2 x Wandtegelwerk | 1864 | 2850 | 0.009295 | 5.29815 | 5.29815 | 0.0264908 | 0.0264908 | 15.8945 | 5.29815 | 2850 | 0.01425
Wandtegelwerk | 769.496 | 2850 | 0.00385998 | 2.20019 | 2.20019 | 0.0110009 | 0.0110009 | 6.60056 | 2.20019 | 2850 | 0.01425
Wandtegelwerk | 1200 | 1500 | 0.00599802 | 1.79925 | 1.79925 | 0.00899499 | 0.00899499 | 5.397 | 1.79925 | 1500 | 0.0075
2 x Wandtegelwerk | 494.497 | 2850 | 0.00248498 | 1.41644 | 1.41644 | 0.00708221 | 0.00708221 | 4.24932 | 1.41644 | 2850 | 0.01425
2 x Wandtegelwerk | 3313.86 | 2850 | 0.0165943 | 9.45876 | 9.45876 | 0.0472938 | 0.0472938 | 28.3763 | 9.45876 | 2850 | 0.01425
2 x Wandtegelwerk | 2459 | 2850 | 0.012295 | 7.00814 | 7.00814 | 0.0350407 | 0.0350407 | 21.0244 | 7.00814 | 2850 | 0.01425
2 x Wandtegelwerk | 2313.86 | 2850 | 0.0115443 | 6.58026 | 6.58026 | 0.0329013 | 0.0329013 | 19.7408 | 6.58026 | 2850 | 0.01425
2 x Wandtegelwerk | 1000 | 2850 | 0.005025 | 2.86425 | 2.86425 | 0.0143213 | 0.0143213 | 8.59275 | 2.86425 | 2850 | 0.01425
2 x Wandtegelwerk | 959 | 2850 | 0.00477 | 2.7189 | 2.7189 | 0.0135945 | 0.0135945 | 8.1567 | 2.7189 | 2850 | 0.01425
4 x Wandtegelwerk | 1601.49 | 2850 | 0.00338925 | 4.57851 | 2.37112 | 0.0228925 | 0.0118556 | 7.11337 | 2.37707 | 2850 | 0.01425
8 x Wandtegelwerk | 788.999 | 2850 | 0.00394499 | 2.24865 | 2.24865 | 0.0112432 | 0.0112432 | 6.74594 | 2.24865 | 2850 | 0.01425
4 x Wandtegelwerk | 1601.49 | 2850 | 0.00798247 | 4.55001 | 4.55001 | 0.02275 | 0.02275 | 13.65 | 4.55001 | 2850 | 0.01425
Wandtegelwerk | 1399 | 2850 | 0.00701998 | 4.00139 | 4.00139 | 0.0200069 | 0.0200069 | 12.0042 | 4.00139 | 2850 | 0.01425
Wandtegelwerk | 1219.5 | 2850 | 0.006085 | 3.46845 | 3.46845 | 0.0173423 | 0.0173423 | 10.4054 | 3.46845 | 2850 | 0.01425
2 x Wandtegelwerk | 1402 | 2850 | 0.00700998 | 3.99569 | 3.99569 | 0.0199784 | 0.0199784 | 11.9871 | 3.99569 | 2850 | 0.01425
Wandtegelwerk | 1225 | 2850 | 0.006125 | 3.49125 | 3.49125 | 0.0174563 | 0.0174563 | 10.4738 | 3.49125 | 2850 | 0.01425
2 x Wandtegelwerk | 1049.95 | 2850 | 0.00524973 | 2.99234 | 2.99234 | 0.0149617 | 0.0149617 | 8.97703 | 2.99234 | 2850 | 0.01425
Wandtegelwerk | 2288.97 | 2850 | 0.00629987 | 6.53783 | 4.08001 | 0.0326891 | 0.0204 | 12.24 | 4.08001 | 2850 | 0.01425
2 x Wandtegelwerk | 2319.04 | 2850 | 0.0115952 | 6.60927 | 6.60927 | 0.0330463 | 0.0330463 | 19.8278 | 6.60927 | 2850 | 0.01425
Wandtegelwerk | 2288.97 | 2850 | 0.0114199 | 6.50933 | 6.50933 | 0.0325466 | 0.0325466 | 19.528 | 6.50933 | 2850 | 0.01425
Wandtegelwerk | 3639 | 2850 | 0.01272 | 9.25111 | 6.63641 | 0.0462555 | 0.033182 | 19.9092 | 6.63641 | 2850 | 0.01425
Wandtegelwerk | 4039 | 2850 | 0.020195 | 7.6741 | 7.6741 | 0.0383705 | 0.0383705 | 23.0223 | 7.6741 | 2850 | 0.01425
Wandtegelwerk | 4039 | 2850 | 0.020195 | 7.6741 | 6.29271 | 0.0383705 | 0.0314635 | 18.8781 | 6.29271 | 2850 | 0.01425
Wandtegelwerk | 3639 | 2850 | 0.0130001 | 9.23211 | 6.77429 | 0.0461605 | 0.0338714 | 20.3229 | 6.77429 | 2850 | 0.01425
Wandtegelwerk | 1033.65 | 2250 | 0.00511823 | 2.3032 | 2.3032 | 0.011516 | 0.011516 | 6.90961 | 2.3032 | 2250 | 0.01125
Wandtegelwerk | 1025.59 | 2250 | 0.00510297 | 2.29634 | 2.29634 | 0.0114817 | 0.0114817 | 6.88901 | 2.29634 | 2250 | 0.01125
2 x Wandtegelwerk | 1389 | 2850 | 0.00696999 | 3.9729 | 3.9729 | 0.0198645 | 0.0198645 | 11.9187 | 3.9729 | 2850 | 0.01425
2 x Wandtegelwerk | 1023.04 | 2850 | 0.00511518 | 2.91566 | 2.91566 | 0.0145783 | 0.0145783 | 8.74697 | 2.91566 | 2850 | 0.01425
2 x Wandtegelwerk | 1389 | 2850 | 0.00694499 | 3.95865 | 3.95865 | 0.0197932 | 0.0197932 | 11.8759 | 3.95865 | 2850 | 0.01425
2 x Wandtegelwerk | 1023.04 | 2850 | 0.00514018 | 2.92991 | 2.92991 | 0.0146495 | 0.0146495 | 8.78972 | 2.92991 | 2850 | 0.01425
Wandtegelwerk | 505.736 | 1350 | 0.00252868 | 0.682743 | 0.682743 | 0.00341372 | 0.00341372 | 2.04823 | 0.682743 | 1350 | 0.00675
Wandtegelwerk | 2651.52 | 1350 | 0.00811509 | 3.57617 | 2.19107 | 0.0178809 | 0.0109554 | 6.57322 | 2.19107 | 1350 | 0.00675
Wandtegelwerk | 135 | 1500 | 0.0007 | 0.21 | 0.21 | 0.00105 | 0.00105 | 0.63 | 0.21 | 1500 | 0.0075
Wandtegelwerk | 3349 | 1500 | 0.01677 | 5.031 | 5.031 | 0.025155 | 0.025155 | 15.093 | 5.031 | 1500 | 0.0075
Wandtegelwerk | 2789 | 1500 | 0.013945 | 4.1835 | 4.1835 | 0.0209175 | 0.0209175 | 12.5505 | 4.1835 | 1500 | 0.0075
Wandtegelwerk | 2843.26 | 1500 | 0.0141913 | 4.2574 | 4.2574 | 0.021287 | 0.021287 | 12.7722 | 4.2574 | 1500 | 0.0075
Wandtegelwerk | 505.736 | 1500 | 0.00252868 | 0.758604 | 0.758604 | 0.00379302 | 0.00379302 | 2.27581 | 0.758604 | 1500 | 0.0075
Wandtegelwerk | 2654 | 1500 | 0.008115 | 3.9735 | 3.0224 | 0.0198675 | 0.015112 | 9.06719 | 3.0224 | 1500 | 0.0075
8 x Wandtegelwerk | 1089 | 1500 | 0.00547 | 1.641 | 1.641 | 0.008205 | 0.008205 | 4.923 | 1.641 | 1500 | 0.0075
7 x Wandtegelwerk | 1023 | 1500 | 0.005115 | 1.5345 | 1.5345 | 0.0076725 | 0.0076725 | 4.6035 | 1.5345 | 1500 | 0.0075
8 x Wandtegelwerk | 1089 | 1500 | 0.005445 | 1.6335 | 1.6335 | 0.0081675 | 0.0081675 | 4.9005 | 1.6335 | 1500 | 0.0075
7 x Wandtegelwerk | 1023 | 573 | 0 | 1.527 | 0.583314 | 0.007635 | 0.00291657 | 1.74994 | 0.583314 | 1500 | 0.0075
3 x Wandtegelwerk | 1269 | 1500 | 0.00637 | 1.911 | 1.911 | 0.009555 | 0.009555 | 5.733 | 1.911 | 1500 | 0.0075
Wandtegelwerk | 1044 | 1500 | 0.00522001 | 1.566 | 1.566 | 0.00783001 | 0.00783001 | 4.69801 | 1.566 | 1500 | 0.0075
2 x Wandtegelwerk | 1269 | 1500 | 0.006345 | 1.9035 | 1.9035 | 0.0095175 | 0.0095175 | 5.7105 | 1.9035 | 1500 | 0.0075
2 x Wandtegelwerk | 1044 | 1500 | 0.0000250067 | 1.5585 | 0.599984 | 0.00779251 | 0.00299992 | 1.79995 | 0.599984 | 1500 | 0.0075
3 x Wandtegelwerk | 1039 | 1500 | 0.005195 | 1.5585 | 1.5585 | 0.0077925 | 0.0077925 | 4.6755 | 1.5585 | 1500 | 0.0075
Wandtegelwerk | 1269 | 1500 | 0.0063449 | 1.9035 | 1.90118 | 0.0095175 | 0.00951741 | 5.71044 | 1.9035 | 1500 | 0.0075
Wandtegelwerk | 1039 | 1500 | 1.02084e-07 | 1.551 | 0.592501 | 0.007755 | 0.0029625 | 1.7775 | 0.592501 | 1500 | 0.0075
2 x Wandtegelwerk | 1039 | 573 | 0 | 1.551 | 0.592482 | 0.007755 | 0.00296241 | 1.77745 | 0.592482 | 1500 | 0.0075
3 x Wandtegelwerk | 2593.04 | 1500 | 0.0129902 | 3.89705 | 3.89705 | 0.0194853 | 0.0194853 | 11.6912 | 3.89705 | 1500 | 0.0075
Wandtegelwerk | 1044 | 1500 | 0.0000500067 | 1.566 | 0.607484 | 0.00783001 | 0.00303742 | 1.82245 | 0.607484 | 1500 | 0.0075
2 x Wandtegelwerk | 2593.04 | 1500 | 0.0129652 | 3.88955 | 3.88955 | 0.0194478 | 0.0194478 | 11.6687 | 3.88955 | 1500 | 0.0075
2 x Wandtegelwerk | 1039 | 1500 | 0.000025 | 1.5585 | 0.599982 | 0.0077925 | 0.00299991 | 1.79995 | 0.599982 | 1500 | 0.0075
Wandtegelwerk | 2593.04 | 1500 | 0.0129651 | 3.88955 | 3.88724 | 0.0194478 | 0.0194477 | 11.6686 | 3.88955 | 1500 | 0.0075
Wandtegelwerk | 1039 | 1500 | 1.02088e-07 | 1.551 | 0.592501 | 0.007755 | 0.0029625 | 1.7775 | 0.592501 | 1500 | 0.0075
Wandtegelwerk | 2229 | 1500 | 0.01117 | 3.351 | 3.351 | 0.016755 | 0.016755 | 10.053 | 3.351 | 1500 | 0.0075
Wandtegelwerk | 2219 | 1500 | 0.011095 | 3.3285 | 3.3285 | 0.0166425 | 0.0166425 | 9.9855 | 3.3285 | 1500 | 0.0075
Wandtegelwerk | 2229 | 1500 | 0.011145 | 3.3435 | 3.3435 | 0.0167175 | 0.0167175 | 10.0305 | 3.3435 | 1500 | 0.0075
Wandtegelwerk | 2219 | 1500 | 0.0059 | 3.321 | 2.36248 | 0.016605 | 0.0118124 | 7.08745 | 2.36248 | 1500 | 0.0075
Wandtegelwerk | 1039 | 1500 | 0.0000399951 | 1.551 | 0.599897 | 0.007755 | 0.00299949 | 1.79969 | 0.599897 | 1500 | 0.0075
Wandtegelwerk | 1743.03 | 2850 | 0.00874014 | 4.98188 | 4.98188 | 0.0249094 | 0.0249094 | 14.9456 | 4.98188 | 2850 | 0.01425
Wandtegelwerk | 3074.99 | 2850 | 0.0153749 | 8.76371 | 8.76371 | 0.0438186 | 0.0438186 | 26.2911 | 8.76371 | 2850 | 0.01425
Wandtegelwerk | 1743.03 | 2850 | 0.00871514 | 4.96763 | 4.96763 | 0.0248381 | 0.0248381 | 14.9029 | 4.96763 | 2850 | 0.01425
Wandtegelwerk | 3074.99 | 2850 | 0.0101799 | 8.74946 | 6.39505 | 0.0437473 | 0.0319752 | 19.1851 | 6.39505 | 2850 | 0.01425
Wandtegelwerk | 1200 | 1350 | 0.006 | 1.62 | 1.62 | 0.0081 | 0.0081 | 4.86 | 1.62 | 1350 | 0.00675
2 x Wandtegelwerk | 620 | 1500 | 0.003125 | 0.9375 | 0.9375 | 0.0046875 | 0.0046875 | 2.8125 | 0.9375 | 1500 | 0.0075
Wandtegelwerk | 3989.01 | 1500 | 0.01997 | 5.99101 | 5.99101 | 0.0299551 | 0.0299551 | 17.973 | 5.99101 | 1500 | 0.0075
Wandtegelwerk | 2489 | 1500 | 0.007275 | 3.7335 | 2.77498 | 0.0186675 | 0.0138749 | 8.32495 | 2.77498 | 1500 | 0.0075
Wandtegelwerk | 1139.01 | 1500 | 0.00567003 | 1.70101 | 1.70101 | 0.00850505 | 0.00850505 | 5.10303 | 1.70101 | 1500 | 0.0075
Wandtegelwerk | 1869 | 1500 | 0.004175 | 2.8035 | 1.84498 | 0.0140175 | 0.00922491 | 5.53495 | 1.84498 | 1500 | 0.0075
Wandtegelwerk | 2269 | 1500 | 0.011345 | 3.4035 | 3.4035 | 0.0170175 | 0.0170175 | 10.2105 | 3.4035 | 1500 | 0.0075
Wandtegelwerk | 361 | 1500 | 0.00178 | 0.534 | 0.534 | 0.00267 | 0.00267 | 1.602 | 0.534 | 1500 | 0.0075
Wandtegelwerk | 220 | 1500 | 0.0011 | 0.33 | 0.33 | 0.00165 | 0.00165 | 0.99 | 0.33 | 1500 | 0.0075
Wandtegelwerk | 620 | 1500 | 0.003075 | 0.9225 | 0.9225 | 0.0046125 | 0.0046125 | 2.7675 | 0.9225 | 1500 | 0.0075
2 x Wandtegelwerk | 1469 | 3000 | 0.002425 | 4.407 | 2.06803 | 0.022035 | 0.0103402 | 6.2041 | 2.06803 | 3000 | 0.015
2 x Wandtegelwerk | 1079 | 3000 | 0.005395 | 3.237 | 3.237 | 0.016185 | 0.016185 | 9.711 | 3.237 | 3000 | 0.015
2 x Wandtegelwerk | 1469 | 3000 | 0.00732 | 4.392 | 4.392 | 0.02196 | 0.02196 | 13.176 | 4.392 | 3000 | 0.015
Wandtegelwerk | 1014 | 3000 | 0.00507 | 3.042 | 3.042 | 0.01521 | 0.01521 | 9.126 | 3.042 | 3000 | 0.015
Wandtegelwerk | 2934.98 | 3000 | 0.0146999 | 8.81994 | 8.81994 | 0.0440997 | 0.0440997 | 26.4598 | 8.81994 | 3000 | 0.015
Wandtegelwerk | 2809 | 3000 | 0.01402 | 8.412 | 8.412 | 0.04206 | 0.04206 | 25.236 | 8.412 | 3000 | 0.015
Wandtegelwerk | 650 | 3000 | 0.00325 | 1.95 | 1.95 | 0.00975 | 0.00975 | 5.85 | 1.95 | 3000 | 0.015
Wandtegelwerk | 1795 | 3000 | 0.00382 | 5.37 | 2.9312 | 0.02685 | 0.014656 | 8.79359 | 2.9312 | 3000 | 0.015
Wandtegelwerk | 1800 | 3000 | 0.009025 | 5.415 | 5.415 | 0.027075 | 0.027075 | 16.245 | 5.415 | 3000 | 0.015
2 x Wandtegelwerk | 2359 | 3000 | 0.011795 | 7.077 | 7.077 | 0.035385 | 0.035385 | 21.231 | 7.077 | 3000 | 0.015
Wandtegelwerk | 1169 | 3000 | 0.00582 | 3.492 | 3.492 | 0.01746 | 0.01746 | 10.476 | 3.492 | 3000 | 0.015
2 x Wandtegelwerk | 1295.5 | 3000 | 0.006465 | 3.879 | 3.879 | 0.019395 | 0.019395 | 11.637 | 3.879 | 3000 | 0.015
2 x Wandtegelwerk | 105.5 | 3000 | 0.00054 | 0.324 | 0.324 | 0.00162 | 0.00162 | 0.972 | 0.324 | 3000 | 0.015
Wandtegelwerk | 1797.5 | 3000 | 0.009 | 5.4 | 5.4 | 0.027 | 0.027 | 16.2 | 5.4 | 3000 | 0.015
Wandtegelwerk | 1171.5 | 3000 | 0.005845 | 3.507 | 3.507 | 0.017535 | 0.017535 | 10.521 | 3.507 | 3000 | 0.015
Wandtegelwerk | 794.504 | 2850 | 0.00396002 | 2.25721 | 2.25721 | 0.0112861 | 0.0112861 | 6.77164 | 2.25721 | 2850 | 0.01425
Wandtegelwerk | 794.5 | 2850 | 0.00396 | 2.2572 | 2.2572 | 0.011286 | 0.011286 | 6.7716 | 2.2572 | 2850 | 0.01425
2 x Wandtegelwerk | 105.5 | 2850 | 0.000515 | 0.29355 | 0.29355 | 0.00146775 | 0.00146775 | 0.88065 | 0.29355 | 2850 | 0.01425
4 x Wandtegelwerk | 1492 | 2850 | 0.00745999 | 4.2522 | 4.2522 | 0.021261 | 0.021261 | 12.7566 | 4.2522 | 2850 | 0.01425
Wandtegelwerk | 1168.97 | 2850 | 0.00584484 | 3.32406 | 3.32406 | 0.0166203 | 0.0166203 | 9.97218 | 3.32406 | 2850 | 0.01425
3 x Wandtegelwerk | 1168.97 | 2850 | 0.00584484 | 3.33156 | 3.33156 | 0.0166578 | 0.0166578 | 9.99468 | 3.33156 | 2850 | 0.01425
Wandtegelwerk | 1039 | 2850 | 0.00522002 | 2.97541 | 2.97541 | 0.014877 | 0.014877 | 8.92623 | 2.97541 | 2850 | 0.01425
Wandtegelwerk | 2169 | 2850 | 0.010845 | 6.18166 | 6.18166 | 0.0309083 | 0.0309083 | 18.545 | 6.18166 | 2850 | 0.01425
Wandtegelwerk | 2169 | 2850 | 0.0057025 | 6.18166 | 3.73691 | 0.0309083 | 0.0186845 | 11.2107 | 3.74285 | 2850 | 0.01425
Wandtegelwerk | 1039 | 2850 | 0.00517002 | 2.94691 | 2.94691 | 0.0147345 | 0.0147345 | 8.84073 | 2.94691 | 2850 | 0.01425
Wandtegelwerk | 1666.5 | 2850 | 0.00321497 | 4.75664 | 2.31783 | 0.0237832 | 0.0115892 | 6.95349 | 2.31783 | 2850 | 0.01425
2 x Wandtegelwerk | 1039 | 2850 | 0.005195 | 2.96115 | 2.96115 | 0.0148058 | 0.0148058 | 8.88345 | 2.96115 | 2850 | 0.01425
2 x Wandtegelwerk | 1666.5 | 2850 | 0.00831998 | 4.74239 | 4.74239 | 0.0237119 | 0.0237119 | 14.2272 | 4.74239 | 2850 | 0.01425
Wandtegelwerk | 1666.5 | 2850 | 0.0032025 | 4.75664 | 2.3119 | 0.0237832 | 0.0115595 | 6.93571 | 2.31785 | 2850 | 0.01425
Wandtegelwerk | 1396.5 | 2850 | 0.00699498 | 3.98714 | 3.98714 | 0.0199357 | 0.0199357 | 11.9614 | 3.98714 | 2850 | 0.01425
Wandtegelwerk | 1211.5 | 2850 | 0.001125 | 3.44565 | 1.10668 | 0.0172283 | 0.00553341 | 3.32005 | 1.10668 | 2850 | 0.01425
Wandtegelwerk | 1214.5 | 2850 | 0.001125 | 3.44565 | 1.10668 | 0.0172283 | 0.00553341 | 3.32005 | 1.10668 | 2850 | 0.01425
2 x Wandtegelwerk | 2150 | 3000 | 0.010725 | 6.43501 | 6.43501 | 0.032175 | 0.032175 | 19.305 | 6.43501 | 3000 | 0.015
Wandtegelwerk | 2239 | 2850 | 0.01122 | 6.3954 | 6.3954 | 0.031977 | 0.031977 | 19.1862 | 6.3954 | 2850 | 0.01425
2 x Wandtegelwerk | 744.475 | 2850 | 0.00370987 | 2.11463 | 2.11463 | 0.0105731 | 0.0105731 | 6.34388 | 2.11463 | 2850 | 0.01425
Wandtegelwerk | 644.5 | 150 | 0.003235 | 0.09705 | 0.09705 | 0.00048525 | 0.00048525 | 0.29115 | 0.09705 | 150 | 0.00075
Wandtegelwerk | 150 | 150 | 0.00075 | 0.0225 | 0.0225 | 0.0001125 | 0.0001125 | 0.0675 | 0.0225 | 150 | 0.00075
Wandtegelwerk | 155.5 | 150 | 0.000765 | 0.02295 | 0.02295 | 0.00011475 | 0.00011475 | 0.06885 | 0.02295 | 150 | 0.00075
Wandtegelwerk | 3344.5 | 150 | 0.016735 | 0.50205 | 0.50205 | 0.00251025 | 0.00251025 | 1.50615 | 0.50205 | 150 | 0.00075
2 x Wandtegelwerk | 3889 | 150 | 0.019445 | 0.58335 | 0.58335 | 0.00291675 | 0.00291675 | 1.75005 | 0.58335 | 150 | 0.00075
2 x Wandtegelwerk | 5039 | 150 | 0.025195 | 0.75585 | 0.75585 | 0.00377925 | 0.00377925 | 2.26755 | 0.75585 | 150 | 0.00075
Wandtegelwerk | 2710.5 | 150 | 0.01354 | 0.4062 | 0.4062 | 0.002031 | 0.002031 | 1.2186 | 0.4062 | 150 | 0.00075
Wandtegelwerk | 794.504 | 150 | 0.00398502 | 0.119551 | 0.119551 | 0.000597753 | 0.000597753 | 0.358652 | 0.119551 | 150 | 0.00075
Wandtegelwerk | 2760.5 | 150 | 0.01379 | 0.4137 | 0.4137 | 0.0020685 | 0.0020685 | 1.2411 | 0.4137 | 150 | 0.00075
Wandtegelwerk | 94.5 | 150 | 0.000485 | 0.01455 | 0.01455 | 0.00007275 | 0.00007275 | 0.04365 | 0.01455 | 150 | 0.00075
Wandtegelwerk | 3344.5 | 150 | 0.01671 | 0.501299 | 0.501299 | 0.0025065 | 0.0025065 | 1.5039 | 0.501299 | 150 | 0.00075
Wandtegelwerk | 1458.51 | 150 | 0.00730503 | 0.219151 | 0.219151 | 0.00109575 | 0.00109575 | 0.657453 | 0.219151 | 150 | 0.00075
Wandtegelwerk | 2419.54 | 150 | 0.0120852 | 0.362555 | 0.362555 | 0.00181278 | 0.00181278 | 1.08767 | 0.362555 | 150 | 0.00075
Wandtegelwerk | 3419.51 | 150 | 0.0171101 | 0.513302 | 0.513302 | 0.00256651 | 0.00256651 | 1.53991 | 0.513302 | 150 | 0.00075
5 x Wandtegelwerk | 4089 | 150 | 0.020445 | 0.61335 | 0.61335 | 0.00306675 | 0.00306675 | 1.84005 | 0.61335 | 150 | 0.00075
2 x Wandtegelwerk | 6739 | 150 | 0.033695 | 1.01085 | 1.01085 | 0.00505425 | 0.00505425 | 3.03255 | 1.01085 | 150 | 0.00075
Wandtegelwerk | 1596.49 | 150 | 0.00796997 | 0.239099 | 0.239099 | 0.0011955 | 0.0011955 | 0.717297 | 0.239099 | 150 | 0.00075
Wandtegelwerk | 2419.5 | 150 | 0.01211 | 0.3633 | 0.3633 | 0.0018165 | 0.0018165 | 1.0899 | 0.3633 | 150 | 0.00075
Wandtegelwerk | 1594.5 | 150 | 0.00796001 | 0.2388 | 0.2388 | 0.001194 | 0.001194 | 0.716401 | 0.2388 | 150 | 0.00075
Wandtegelwerk | 1460.5 | 150 | 0.007315 | 0.21945 | 0.21945 | 0.00109725 | 0.00109725 | 0.65835 | 0.21945 | 150 | 0.00075
Wandtegelwerk | 3419.53 | 150 | 0.0170852 | 0.512555 | 0.512555 | 0.00256278 | 0.00256278 | 1.53767 | 0.512555 | 150 | 0.00075
2 x Wandtegelwerk | 1457.05 | 150 | 0.00728523 | 0.218557 | 0.218557 | 0.00109278 | 0.00109278 | 0.65567 | 0.218557 | 150 | 0.00075
Wandtegelwerk | 1485.54 | 150 | 0.00744022 | 0.223207 | 0.223207 | 0.00111603 | 0.00111603 | 0.66962 | 0.223207 | 150 | 0.00075
4 x Wandtegelwerk | 2994.5 | 150 | 0.01496 | 0.4488 | 0.4488 | 0.002244 | 0.002244 | 1.3464 | 0.4488 | 150 | 0.00075
Wandtegelwerk | 794.456 | 150 | 0.00398478 | 0.119543 | 0.119543 | 0.000597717 | 0.000597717 | 0.35863 | 0.119543 | 150 | 0.00075
Wandtegelwerk | 794.463 | 150 | 0.00398481 | 0.119544 | 0.119544 | 0.000597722 | 0.000597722 | 0.358633 | 0.119544 | 150 | 0.00075
Wandtegelwerk | 1485.54 | 150 | 0.00744019 | 0.223206 | 0.223206 | 0.00111603 | 0.00111603 | 0.669617 | 0.223206 | 150 | 0.00075
Wandtegelwerk | 610.5 | 150 | 0.003065 | 0.09195 | 0.09195 | 0.00045975 | 0.00045975 | 0.27585 | 0.09195 | 150 | 0.00075
Wandtegelwerk | 135.5 | 150 | 0.000665 | 0.01995 | 0.01995 | 0.00009975 | 0.00009975 | 0.05985 | 0.01995 | 150 | 0.00075
Wandtegelwerk | 300 | 150 | 0.0015 | 0.045 | 0.045 | 0.000225 | 0.000225 | 0.135 | 0.045 | 150 | 0.00075
Wandtegelwerk | 740.999 | 150 | 0.00370499 | 0.11115 | 0.11115 | 0.000555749 | 0.000555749 | 0.333449 | 0.11115 | 150 | 0.00075
Wandtegelwerk | 365.96 | 150 | 0.0018298 | 0.0548939 | 0.0548939 | 0.00027447 | 0.00027447 | 0.164682 | 0.0548939 | 150 | 0.00075
Wandtegelwerk | 799.859 | 150 | 0.00399929 | 0.119979 | 0.119979 | 0.000599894 | 0.000599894 | 0.359936 | 0.119979 | 150 | 0.00075
Wandtegelwerk | 2390.99 | 150 | 0.011955 | 0.358649 | 0.358649 | 0.00179325 | 0.00179325 | 1.07595 | 0.358649 | 150 | 0.00075
Wandtegelwerk | 1491.04 | 150 | 0.00745522 | 0.223657 | 0.223657 | 0.00111828 | 0.00111828 | 0.67097 | 0.223657 | 150 | 0.00075
Wandtegelwerk | 1144.5 | 150 | 0.005735 | 0.17205 | 0.17205 | 0.00086025 | 0.00086025 | 0.51615 | 0.17205 | 150 | 0.00075
Wandtegelwerk | 4289 | 150 | 0.021445 | 0.64335 | 0.64335 | 0.00321675 | 0.00321675 | 1.93005 | 0.64335 | 150 | 0.00075
Wandtegelwerk | 944.5 | 150 | 0.00471 | 0.1413 | 0.1413 | 0.0007065 | 0.0007065 | 0.4239 | 0.1413 | 150 | 0.00075
Wandtegelwerk | 860.5 | 150 | 0.004315 | 0.12945 | 0.12945 | 0.00064725 | 0.00064725 | 0.38835 | 0.12945 | 150 | 0.00075
Wandtegelwerk | 1389 | 150 | 0.006945 | 0.20835 | 0.20835 | 0.00104175 | 0.00104175 | 0.62505 | 0.20835 | 150 | 0.00075
Wandtegelwerk | 860.498 | 150 | 0.00428999 | 0.1287 | 0.1287 | 0.000643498 | 0.000643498 | 0.386099 | 0.1287 | 150 | 0.00075
Wandtegelwerk | 1386.04 | 150 | 0.00693021 | 0.207906 | 0.207906 | 0.00103953 | 0.00103953 | 0.623719 | 0.207906 | 150 | 0.00075
Wandtegelwerk | 734.5 | 150 | 0.003685 | 0.11055 | 0.11055 | 0.00055275 | 0.00055275 | 0.33165 | 0.11055 | 150 | 0.00075
2 x Wandtegelwerk | 2589 | 150 | 0.012945 | 0.38835 | 0.38835 | 0.00194175 | 0.00194175 | 1.16505 | 0.38835 | 150 | 0.00075
Wandtegelwerk | 734.501 | 150 | 0.00366001 | 0.1098 | 0.1098 | 0.000549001 | 0.000549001 | 0.329401 | 0.1098 | 150 | 0.00075
Wandtegelwerk | 1870.5 | 150 | 0.009365 | 0.28095 | 0.28095 | 0.00140475 | 0.00140475 | 0.84285 | 0.28095 | 150 | 0.00075
Wandtegelwerk | 704.501 | 150 | 0.00351001 | 0.1053 | 0.1053 | 0.000526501 | 0.000526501 | 0.315901 | 0.1053 | 150 | 0.00075
2 x Wandtegelwerk | 460.5 | 150 | 0.002315 | 0.06945 | 0.06945 | 0.00034725 | 0.00034725 | 0.20835 | 0.06945 | 150 | 0.00075
2 x Wandtegelwerk | 2219 | 150 | 0.011095 | 0.33285 | 0.33285 | 0.00166425 | 0.00166425 | 0.99855 | 0.33285 | 150 | 0.00075
Wandtegelwerk | 2089 | 150 | 0.010445 | 0.31335 | 0.31335 | 0.00156675 | 0.00156675 | 0.94005 | 0.31335 | 150 | 0.00075
2 x Wandtegelwerk | 594.5 | 150 | 0.00296 | 0.0888 | 0.0888 | 0.000444 | 0.000444 | 0.2664 | 0.0888 | 150 | 0.00075
Wandtegelwerk | 430.5 | 150 | 0.00214 | 0.0642 | 0.0642 | 0.000321 | 0.000321 | 0.1926 | 0.0642 | 150 | 0.00075
Wandtegelwerk | 1705.5 | 150 | 0.00854 | 0.2562 | 0.2562 | 0.001281 | 0.001281 | 0.7686 | 0.2562 | 150 | 0.00075
Wandtegelwerk | 4620 | 150 | 0.0231 | 0.693 | 0.693 | 0.003465 | 0.003465 | 2.079 | 0.693 | 150 | 0.00075
Wandtegelwerk | 5600 | 150 | 0.028 | 0.84 | 0.84 | 0.0042 | 0.0042 | 2.52 | 0.84 | 150 | 0.00075
Wandtegelwerk | 5701.99 | 150 | 0.02851 | 0.855299 | 0.855299 | 0.0042765 | 0.0042765 | 2.5659 | 0.855299 | 150 | 0.00075
Wandtegelwerk | 2882.01 | 150 | 0.01441 | 0.432301 | 0.432301 | 0.00216151 | 0.00216151 | 1.2969 | 0.432301 | 150 | 0.00075
Wandtegelwerk | 2325 | 150 | 0.011625 | 0.34875 | 0.34875 | 0.00174375 | 0.00174375 | 1.04625 | 0.34875 | 150 | 0.00075
Wandtegelwerk | 2710.5 | 150 | 0.013565 | 0.40695 | 0.40695 | 0.00203475 | 0.00203475 | 1.22085 | 0.40695 | 150 | 0.00075
Wandtegelwerk | 8.59544 | 150 | 0.0000304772 | 0.000914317 | 0.000914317 | 0.00000457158 | 0.00000457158 | 0.00274295 | 0.000914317 | 150 | 0.00075
Wandtegelwerk | 330.409 | 150 | 0.00166455 | 0.0499364 | 0.0499364 | 0.000249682 | 0.000249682 | 0.149809 | 0.0499364 | 150 | 0.00075
Wandtegelwerk | 1075 | 150 | 0.005375 | 0.16125 | 0.16125 | 0.00080625 | 0.00080625 | 0.48375 | 0.16125 | 150 | 0.00075
Wandtegelwerk | 3083.5 | 150 | 0.015405 | 0.46215 | 0.46215 | 0.00231075 | 0.00231075 | 1.38645 | 0.46215 | 150 | 0.00075
Wandtegelwerk | 4335.11 | 150 | 0.0216755 | 0.650266 | 0.650266 | 0.00325133 | 0.00325133 | 1.9508 | 0.650266 | 150 | 0.00075
Wandtegelwerk | 1466 | 150 | 0.00733 | 0.2199 | 0.2199 | 0.0010995 | 0.0010995 | 0.6597 | 0.2199 | 150 | 0.00075
Wandtegelwerk | 2072 | 150 | 0.01036 | 0.3108 | 0.3108 | 0.001554 | 0.001554 | 0.9324 | 0.3108 | 150 | 0.00075
2 x Wandtegelwerk | 100 | 150 | 0.0005 | 0.015 | 0.015 | 0.000075 | 0.000075 | 0.045 | 0.015 | 150 | 0.00075
Wandtegelwerk | 1430 | 150 | 0.00715 | 0.2145 | 0.2145 | 0.0010725 | 0.0010725 | 0.6435 | 0.2145 | 150 | 0.00075
Wandtegelwerk | 397.986 | 150 | 0.00198993 | 0.0596978 | 0.0596978 | 0.000298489 | 0.000298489 | 0.179093 | 0.0596978 | 150 | 0.00075
Wandtegelwerk | 5089 | 150 | 0.02547 | 0.7641 | 0.7641 | 0.0038205 | 0.0038205 | 2.2923 | 0.7641 | 150 | 0.00075
Wandtegelwerk | 7939 | 150 | 0.039695 | 1.19085 | 1.19085 | 0.00595425 | 0.00595425 | 3.57255 | 1.19085 | 150 | 0.00075
3 x Wandtegelwerk | 5089 | 150 | 0.025445 | 0.76335 | 0.76335 | 0.00381675 | 0.00381675 | 2.29005 | 0.76335 | 150 | 0.00075
Wandtegelwerk | 3929.61 | 150 | 0.0196355 | 0.589066 | 0.589066 | 0.00294533 | 0.00294533 | 1.7672 | 0.589066 | 150 | 0.00075
Wandtegelwerk | 2975.39 | 150 | 0.0148645 | 0.445934 | 0.445934 | 0.00222967 | 0.00222967 | 1.3378 | 0.445934 | 150 | 0.00075
2 x Wandtegelwerk | 294.5 | 150 | 0.001485 | 0.04455 | 0.04455 | 0.00022275 | 0.00022275 | 0.13365 | 0.04455 | 150 | 0.00075
Wandtegelwerk | 3944.45 | 150 | 0.0197098 | 0.591293 | 0.591293 | 0.00295646 | 0.00295646 | 1.77388 | 0.591293 | 150 | 0.00075
Wandtegelwerk | 1060.5 | 150 | 0.005315 | 0.15945 | 0.15945 | 0.00079725 | 0.00079725 | 0.47835 | 0.15945 | 150 | 0.00075
Wandtegelwerk | 1589 | 150 | 0.007945 | 0.23835 | 0.23835 | 0.00119175 | 0.00119175 | 0.71505 | 0.23835 | 150 | 0.00075
Wandtegelwerk | 750 | 150 | 0.00375 | 0.1125 | 0.1125 | 0.0005625 | 0.0005625 | 0.3375 | 0.1125 | 150 | 0.00075
Wandtegelwerk | 105.451 | 150 | 0.000514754 | 0.0154426 | 0.0154426 | 0.0000772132 | 0.0000772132 | 0.0463279 | 0.0154426 | 150 | 0.00075
Wandtegelwerk | 616.025 | 150 | 0.00308013 | 0.0924038 | 0.0924038 | 0.000462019 | 0.000462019 | 0.277211 | 0.0924038 | 150 | 0.00075
Wandtegelwerk | 3597.48 | 150 | 0.0179749 | 0.539248 | 0.539248 | 0.00269624 | 0.00269624 | 1.61774 | 0.539248 | 150 | 0.00075
Wandtegelwerk | 830.5 | 150 | 0.004165 | 0.12495 | 0.12495 | 0.00062475 | 0.00062475 | 0.37485 | 0.12495 | 150 | 0.00075
2 x Wandtegelwerk | 3594.48 | 150 | 0.0179599 | 0.538798 | 0.538798 | 0.00269399 | 0.00269399 | 1.61639 | 0.538798 | 150 | 0.00075
Wandtegelwerk | 132.5 | 150 | 0.000675 | 0.02025 | 0.02025 | 0.00010125 | 0.00010125 | 0.06075 | 0.02025 | 150 | 0.00075
Wandtegelwerk | 185 | 150 | 0.000925 | 0.02775 | 0.02775 | 0.00013875 | 0.00013875 | 0.08325 | 0.02775 | 150 | 0.00075
Wandtegelwerk | 998 | 150 | 0.00499 | 0.1497 | 0.1497 | 0.0007485 | 0.0007485 | 0.4491 | 0.1497 | 150 | 0.00075
Wandtegelwerk | 3409.49 | 150 | 0.0170349 | 0.511048 | 0.511048 | 0.00255524 | 0.00255524 | 1.53314 | 0.511048 | 150 | 0.00075
2 x Wandtegelwerk | 3599.98 | 150 | 0.0179999 | 0.539998 | 0.539998 | 0.00269999 | 0.00269999 | 1.61999 | 0.539998 | 150 | 0.00075
Wandtegelwerk | 1130.5 | 150 | 0.005665 | 0.16995 | 0.16995 | 0.00084975 | 0.00084975 | 0.50985 | 0.16995 | 150 | 0.00075
Wandtegelwerk | 188.5 | 150 | 0.000955 | 0.02865 | 0.02865 | 0.00014325 | 0.00014325 | 0.08595 | 0.02865 | 150 | 0.00075
Wandtegelwerk | 3179 | 150 | 0.015895 | 0.47685 | 0.47685 | 0.00238425 | 0.00238425 | 1.43055 | 0.47685 | 150 | 0.00075
Wandtegelwerk | 1956.5 | 150 | 0.00977 | 0.2931 | 0.2931 | 0.0014655 | 0.0014655 | 0.8793 | 0.2931 | 150 | 0.00075
2 x Wandtegelwerk | 388.76 | 150 | 0.0019438 | 0.058314 | 0.058314 | 0.00029157 | 0.00029157 | 0.174942 | 0.058314 | 150 | 0.00075
2 x Wandtegelwerk | 3466.5 | 150 | 0.017345 | 0.52035 | 0.52035 | 0.00260175 | 0.00260175 | 1.56105 | 0.52035 | 150 | 0.00075
3 x Wandtegelwerk | 3239 | 150 | 0.016195 | 0.48585 | 0.48585 | 0.00242925 | 0.00242925 | 1.45755 | 0.48585 | 150 | 0.00075
Wandtegelwerk | 8084 | 150 | 0.04042 | 1.2126 | 1.2126 | 0.006063 | 0.006063 | 3.6378 | 1.2126 | 150 | 0.00075
2 x Wandtegelwerk | 2143.96 | 150 | 0.0107073 | 0.32122 | 0.32122 | 0.0016061 | 0.0016061 | 0.963659 | 0.32122 | 150 | 0.00075
Wandtegelwerk | 644.5 | 150 | 0.00321 | 0.0963 | 0.0963 | 0.0004815 | 0.0004815 | 0.2889 | 0.0963 | 150 | 0.00075
Wandtegelwerk | 8084 | 150 | 0.040445 | 1.21335 | 1.21335 | 0.00606675 | 0.00606675 | 3.64005 | 1.21335 | 150 | 0.00075
Wandtegelwerk | 2940.5 | 150 | 0.014715 | 0.44145 | 0.44145 | 0.00220725 | 0.00220725 | 1.32435 | 0.44145 | 150 | 0.00075
Wandtegelwerk | 1689 | 150 | 0.008445 | 0.25335 | 0.25335 | 0.00126675 | 0.00126675 | 0.76005 | 0.25335 | 150 | 0.00075
Wandtegelwerk | 2285 | 150 | 0.011425 | 0.34275 | 0.34275 | 0.00171375 | 0.00171375 | 1.02825 | 0.34275 | 150 | 0.00075
Wandtegelwerk | 666 | 150 | 0.00333 | 0.0999 | 0.0999 | 0.0004995 | 0.0004995 | 0.2997 | 0.0999 | 150 | 0.00075
Wandtegelwerk | 655.5 | 150 | 0.003265 | 0.09795 | 0.09795 | 0.00048975 | 0.00048975 | 0.29385 | 0.09795 | 150 | 0.00075
Wandtegelwerk | 1605.5 | 150 | 0.00804 | 0.2412 | 0.2412 | 0.001206 | 0.001206 | 0.7236 | 0.2412 | 150 | 0.00075
Wandtegelwerk | 5355.5 | 150 | 0.026765 | 0.80295 | 0.80295 | 0.00401475 | 0.00401475 | 2.40885 | 0.80295 | 150 | 0.00075
Wandtegelwerk | 315.996 | 150 | 0.00157998 | 0.0473994 | 0.0473994 | 0.000236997 | 0.000236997 | 0.142198 | 0.0473994 | 150 | 0.00075
Wandtegelwerk | 1896 | 150 | 0.00948 | 0.2844 | 0.2844 | 0.001422 | 0.001422 | 0.8532 | 0.2844 | 150 | 0.00075
Wandtegelwerk | 1711 | 150 | 0.00855499 | 0.25665 | 0.25665 | 0.00128325 | 0.00128325 | 0.769949 | 0.25665 | 150 | 0.00075
Wandtegelwerk | 1430.5 | 150 | 0.007165 | 0.21495 | 0.21495 | 0.00107475 | 0.00107475 | 0.64485 | 0.21495 | 150 | 0.00075
Wandtegelwerk | 5301.57 | 150 | 0.0264953 | 0.79486 | 0.79486 | 0.0039743 | 0.0039743 | 2.38458 | 0.79486 | 150 | 0.00075
Wandtegelwerk | 263 | 150 | 0.00129 | 0.0387 | 0.0387 | 0.0001935 | 0.0001935 | 0.1161 | 0.0387 | 150 | 0.00075
Wandtegelwerk | 605.5 | 150 | 0.00304 | 0.0912 | 0.0912 | 0.000456 | 0.000456 | 0.2736 | 0.0912 | 150 | 0.00075
Wandtegelwerk | 2300 | 150 | 0.0115 | 0.345 | 0.345 | 0.001725 | 0.001725 | 1.035 | 0.345 | 150 | 0.00075
Wandtegelwerk | 3019 | 150 | 0.015095 | 0.45285 | 0.45285 | 0.00226425 | 0.00226425 | 1.35855 | 0.45285 | 150 | 0.00075
Wandtegelwerk | 3619 | 150 | 0.018095 | 0.54285 | 0.54285 | 0.00271425 | 0.00271425 | 1.62855 | 0.54285 | 150 | 0.00075
Wandtegelwerk | 494.5 | 150 | 0.00246 | 0.0738 | 0.0738 | 0.000369 | 0.000369 | 0.2214 | 0.0738 | 150 | 0.00075
2 x Wandtegelwerk | 1023.04 | 473 | 0 | 2.90141 | 0.481531 | 0.014507 | 0.00240766 | 1.44459 | 0.481531 | 2850 | 0.01425
Wandtegelwerk | 1020.54 | 2850 | 0.000025 | 2.90891 | 0.489031 | 0.0145445 | 0.00244516 | 1.46709 | 0.489031 | 2850 | 0.01425
Wandtegelwerk | 1023.04 | 2850 | 0.0000201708 | 2.90141 | 0.491121 | 0.014507 | 0.0024556 | 1.47336 | 0.491121 | 2850 | 0.01425
Wandtegelwerk | 1560.5 | 150 | 0.00779 | 0.2337 | 0.2337 | 0.0011685 | 0.0011685 | 0.7011 | 0.2337 | 150 | 0.00075

# IfcWall: ALG - BINNENAFWERKING 10 (4)
In: Begane grond
Type - PredefinedType: ELEMENTEDWALL
Classification: Samengestelde wand (ARCHICAD Classification); 21 Buitenwanden (NL/SfB (4 cijfers)); Material: ALG - BINNENAFWERKING
CPset_Phasing - Renovation Phase: Bestaand
AC_Pset_RenovationAndPhasing - Renovation Status: Existing
Pset_WallCommon - LoadBearing: yes; IsExternal: yes
Material Properties - ALG - BINNENAFWERKING, ThermalConductivity: 0.27; ALG - BINNENAFWERKING, SpecificHeatCapacity: 840 J/kg/K; ALG - BINNENAFWERKING, MassDensity: 800 kg/m3; ALG - BINNENAFWERKING, Embodied Energy: 2 (MJ/kg); ALG - BINNENAFWERKING, Embodied Carbon: 0.13 (kgCO₂/kg); ALG - BINNENAFWERKING, Name: ALG - BINNENAFWERKING; ALG - BINNENAFWERKING, Participates in Collision Detection: yes
BaseQuantities - Width: 10 mm
Component Quantities - ALG - BINNENAFWERKING, Component Thickness: 10 mm; ALG - BINNENAFWERKING, Rectangular Component Width: 10 mm
Name | Length (mm) | Height (mm) = ALG - BINNENAFWERKING, Rectangular Component Height (mm) | GrossFootprintArea (m2) = NetFootprintArea (m2) | GrossSideArea (m2) = NetSideArea (m2) | GrossVolume (m3) = NetVolume (m3) = ALG - BINNENAFWERKING, Component Volume (Net) (m3) = ALG - BINNENAFWERKING, Component Volume (Gross) (m3) | ALG - BINNENAFWERKING, Mass (kg) | ALG - BINNENAFWERKING, Projected Component Area (Net) (m2) = ALG - BINNENAFWERKING, Projected Component Area (Gross) (m2) | ALG - BINNENAFWERKING, Component Cross Section Area (m2)
Wa | 1690.01 | 300 | 0.0167001 | 0.501003 | 0.00501003 | 4.00803 | 0.501003 | 0.003
Wa | 663.96 | 1200 | 0.0066995 | 0.798252 | 0.00798549 | 6.38839 | 0.799752 | 0.012
Wa | 1690.01 | 300 | 0.0167001 | 0.501002 | 0.00501002 | 4.00802 | 0.501002 | 0.003
Wa | 663.96 | 1200 | 0.00669982 | 0.798252 | 0.00798558 | 6.38847 | 0.799752 | 0.012

# IfcWall: ALG - BINNENAFWERKING 18 (2)
In: Begane grond
Type - PredefinedType: ELEMENTEDWALL
Classification: Samengestelde wand (ARCHICAD Classification); 21 Buitenwanden (NL/SfB (4 cijfers)); Material: ALG - BINNENAFWERKING
CPset_Phasing - Renovation Phase: Bestaand
AC_Pset_RenovationAndPhasing - Renovation Status: Existing
Pset_WallCommon - LoadBearing: yes; IsExternal: yes
Material Properties - ALG - BINNENAFWERKING, ThermalConductivity: 0.27; ALG - BINNENAFWERKING, SpecificHeatCapacity: 840 J/kg/K; ALG - BINNENAFWERKING, MassDensity: 800 kg/m3; ALG - BINNENAFWERKING, Embodied Energy: 2 (MJ/kg); ALG - BINNENAFWERKING, Embodied Carbon: 0.13 (kgCO₂/kg); ALG - BINNENAFWERKING, Name: ALG - BINNENAFWERKING; ALG - BINNENAFWERKING, Participates in Collision Detection: yes
BaseQuantities - Length: 149.987 mm; Height: 1250 mm; Width: 18 mm; GrossFootprintArea: 0.00269976 m2; NetFootprintArea: 0.00269976 m2; GrossSideArea: 0.187483 m2; NetSideArea: 0.187483 m2; GrossVolume: 0.0033747 m3; NetVolume: 0.0033747 m3
Component Quantities - ALG - BINNENAFWERKING, Mass: 2.69976 kg; ALG - BINNENAFWERKING, Projected Component Area (Net): 0.187483 m2; ALG - BINNENAFWERKING, Projected Component Area (Gross): 0.187483 m2; ALG - BINNENAFWERKING, Component Thickness: 18 mm; ALG - BINNENAFWERKING, Rectangular Component Height: 1250 mm; ALG - BINNENAFWERKING, Rectangular Component Width: 18 mm; ALG - BINNENAFWERKING, Component Cross Section Area: 0.0225 m2; ALG - BINNENAFWERKING, Component Volume (Net): 0.0033747 m3; ALG - BINNENAFWERKING, Component Volume (Gross): 0.0033747 m3

# IfcWall: ALG - BINNENAFWERKING 2 (24)
In: Begane grond
Type - PredefinedType: ELEMENTEDWALL
Classification: Samengestelde wand (ARCHICAD Classification); 21 Buitenwanden (NL/SfB (4 cijfers)); Material: ALG - BINNENAFWERKING
CPset_Phasing - Renovation Phase: Bestaand
AC_Pset_RenovationAndPhasing - Renovation Status: Existing
Pset_WallCommon - LoadBearing: yes; IsExternal: yes
Material Properties - ALG - BINNENAFWERKING, ThermalConductivity: 0.27; ALG - BINNENAFWERKING, SpecificHeatCapacity: 840 J/kg/K; ALG - BINNENAFWERKING, MassDensity: 800 kg/m3; ALG - BINNENAFWERKING, Embodied Energy: 2 (MJ/kg); ALG - BINNENAFWERKING, Embodied Carbon: 0.13 (kgCO₂/kg); ALG - BINNENAFWERKING, Name: ALG - BINNENAFWERKING; ALG - BINNENAFWERKING, Participates in Collision Detection: yes
BaseQuantities - Length: 1834.69 mm; Width: 2 mm; GrossFootprintArea: 0.00367463 m2; NetFootprintArea: 0.00367463 m2
Component Quantities - ALG - BINNENAFWERKING, Component Thickness: 2 mm; ALG - BINNENAFWERKING, Rectangular Component Width: 2 mm
Name | Height (mm) = ALG - BINNENAFWERKING, Rectangular Component Height (mm) | GrossSideArea (m2) = NetSideArea (m2) | GrossVolume (m3) = NetVolume (m3) = ALG - BINNENAFWERKING, Component Volume (Net) (m3) = ALG - BINNENAFWERKING, Component Volume (Gross) (m3) | ALG - BINNENAFWERKING, Mass (kg) | ALG - BINNENAFWERKING, Projected Component Area (Net) (m2) = ALG - BINNENAFWERKING, Projected Component Area (Gross) (m2) | ALG - BINNENAFWERKING, Component Cross Section Area (m2)
12 x Accentkleur | 1045 | 1.91999 | 0.00383999 | 3.07199 | 1.91725 | 0.00209
12 x Accentkleur | 1345 | 2.47119 | 0.00494238 | 3.9539 | 2.46766 | 0.00269

# IfcWall: ALG - BINNENAFWERKING 20 (2)
In: Begane grond
Type - PredefinedType: ELEMENTEDWALL
Classification: Samengestelde wand (ARCHICAD Classification); 21 Buitenwanden (NL/SfB (4 cijfers)); Material: ALG - BINNENAFWERKING
CPset_Phasing - Renovation Phase: Bestaand
AC_Pset_RenovationAndPhasing - Renovation Status: Existing
Pset_WallCommon - LoadBearing: yes; IsExternal: yes
Material Properties - ALG - BINNENAFWERKING, ThermalConductivity: 0.27; ALG - BINNENAFWERKING, SpecificHeatCapacity: 840 J/kg/K; ALG - BINNENAFWERKING, MassDensity: 800 kg/m3; ALG - BINNENAFWERKING, Embodied Energy: 2 (MJ/kg); ALG - BINNENAFWERKING, Embodied Carbon: 0.13 (kgCO₂/kg); ALG - BINNENAFWERKING, Name: ALG - BINNENAFWERKING; ALG - BINNENAFWERKING, Participates in Collision Detection: yes
BaseQuantities - Length: 700 mm; Height: 1477 mm; Width: 20 mm; GrossFootprintArea: 0.014 m2; NetFootprintArea: 0.014 m2; GrossSideArea: 1.021 m2; NetSideArea: 1.021 m2; GrossVolume: 0.02042 m3; NetVolume: 0.02042 m3
Component Quantities - ALG - BINNENAFWERKING, Mass: 16.336 kg; ALG - BINNENAFWERKING, Projected Component Area (Net): 1.021 m2; ALG - BINNENAFWERKING, Projected Component Area (Gross): 1.021 m2; ALG - BINNENAFWERKING, Component Thickness: 20 mm; ALG - BINNENAFWERKING, Rectangular Component Height: 1477 mm; ALG - BINNENAFWERKING, Rectangular Component Width: 20 mm; ALG - BINNENAFWERKING, Component Cross Section Area: 0.02954 m2; ALG - BINNENAFWERKING, Component Volume (Net): 0.02042 m3; ALG - BINNENAFWERKING, Component Volume (Gross): 0.02042 m3

# IfcWall: ALG - BINNENAFWERKING 5 (4)
In: Begane grond
Type - PredefinedType: ELEMENTEDWALL
Classification: Samengestelde wand (ARCHICAD Classification); 21 Buitenwanden (NL/SfB (4 cijfers)); Material: ALG - BINNENAFWERKING
CPset_Phasing - Renovation Phase: Bestaand
AC_Pset_RenovationAndPhasing - Renovation Status: Existing
Pset_WallCommon - LoadBearing: yes; IsExternal: yes
Material Properties - ALG - BINNENAFWERKING, ThermalConductivity: 0.27; ALG - BINNENAFWERKING, SpecificHeatCapacity: 840 J/kg/K; ALG - BINNENAFWERKING, MassDensity: 800 kg/m3; ALG - BINNENAFWERKING, Embodied Energy: 2 (MJ/kg); ALG - BINNENAFWERKING, Embodied Carbon: 0.13 (kgCO₂/kg); ALG - BINNENAFWERKING, Name: ALG - BINNENAFWERKING; ALG - BINNENAFWERKING, Participates in Collision Detection: yes
BaseQuantities - Height: 3800 mm; Width: 5 mm
Component Quantities - ALG - BINNENAFWERKING, Component Thickness: 5 mm; ALG - BINNENAFWERKING, Rectangular Component Height: 3800 mm; ALG - BINNENAFWERKING, Rectangular Component Width: 5 mm; ALG - BINNENAFWERKING, Component Cross Section Area: 0.019 m2
Name | Length (mm) | GrossFootprintArea (m2) = NetFootprintArea (m2) | GrossSideArea (m2) | NetSideArea (m2) = ALG - BINNENAFWERKING, Projected Component Area (Net) (m2) | GrossVolume (m3) | NetVolume (m3) = ALG - BINNENAFWERKING, Component Volume (Net) (m3) | ALG - BINNENAFWERKING, Mass (kg) | ALG - BINNENAFWERKING, Projected Component Area (Gross) (m2) | ALG - BINNENAFWERKING, Component Volume (Gross) (m3)
Wandtegelwerk | 5301.07 | 0.0265053 | 20.1441 | 18.7691 | 0.10072 | 0.0938453 | 75.0762 | 20.1441 | 0.10072
Wandtegelwerk | 9655 | 0.0272647 | 35.601 | 25.6128 | 0.178017 | 0.128073 | 102.458 | 36.689 | 0.183445
Wandtegelwerk | 1605.01 | 0.00802507 | 5.01105 | 5.01105 | 0.0250552 | 0.0250552 | 20.0442 | 6.09906 | 0.0304953
Wandtegelwerk | 7219 | 0.02687 | 27.4322 | 22.6363 | 0.137161 | 0.113182 | 90.5452 | 27.4322 | 0.137161

# IfcWall: Hout - gevel 18 (133)
In: Begane grond
Type - PredefinedType: ELEMENTEDWALL
Classification: Samengestelde wand (ARCHICAD Classification); 21 Buitenwanden (NL/SfB (4 cijfers)); Material: Hout - gevel
CPset_Phasing - Renovation Phase: Bestaand
AC_Pset_RenovationAndPhasing - Renovation Status: Existing
Pset_WallCommon - LoadBearing: yes; IsExternal: yes
Material Properties - Hout - gevel, ThermalConductivity: 0.14; Hout - gevel, SpecificHeatCapacity: 1880 J/kg/K; Hout - gevel, MassDensity: 550 kg/m3; Hout - gevel, Embodied Energy: 7.4 (MJ/kg); Hout - gevel, Embodied Carbon: 0.19 (kgCO₂/kg); Hout - gevel, Name: Hout - gevel; Hout - gevel, Participates in Collision Detection: yes
BaseQuantities - Width: 18 mm
Component Quantities - Hout - gevel, Component Thickness: 18 mm; Hout - gevel, Rectangular Component Width: 18 mm
Name | Length (mm) | Height (mm) = Hout - gevel, Rectangular Component Height (mm) | GrossFootprintArea (m2) = NetFootprintArea (m2) | GrossSideArea (m2) = NetSideArea (m2) = Hout - gevel, Projected Component Area (Net) (m2) = Hout - gevel, Projected Component Area (Gross) (m2) | GrossVolume (m3) = NetVolume (m3) = Hout - gevel, Component Volume (Net) (m3) = Hout - gevel, Component Volume (Gross) (m3) | Hout - gevel, Mass (kg) | Hout - gevel, Component Cross Section Area (m2)
Buitenwand | 1210.8 | 2800 | 0.0217944 | 3.39024 | 0.0610244 | 33.5634 | 0.0504
2 x Buitenwand | 944.619 | 2800 | 0.0170031 | 2.64493 | 0.0476088 | 26.1848 | 0.0504
2 x Buitenwand | 944.619 | 1361 | 0.0170031 | 1.28563 | 0.0231413 | 12.7277 | 0.024498
Buitenwand | 1096 | 1361 | 0.019728 | 1.49166 | 0.0268498 | 14.7674 | 0.024498
Buitenwand | 1093.49 | 1361 | 0.0196829 | 1.48824 | 0.0267884 | 14.7336 | 0.024498
Buitenwand | 1210.8 | 1361 | 0.0217944 | 1.6479 | 0.0296622 | 16.3142 | 0.024498
2 x Buitenwand | 1021 | 1361 | 0.018378 | 1.38958 | 0.0250124 | 13.7568 | 0.024498
Buitenwand | 1094.05 | 1361 | 0.0196929 | 1.489 | 0.026802 | 14.7411 | 0.024498
Buitenwand | 899.982 | 1361 | 0.0161997 | 1.22488 | 0.0220478 | 12.1263 | 0.024498
Buitenwand | 899.982 | 2800 | 0.0161997 | 2.51995 | 0.0453591 | 24.9475 | 0.0504
3 x Buitenwand | 998.503 | 1361 | 0.0179731 | 1.35896 | 0.0244613 | 13.4537 | 0.024498
3 x Buitenwand | 900 | 1361 | 0.0162 | 1.2249 | 0.0220482 | 12.1265 | 0.024498
3 x Buitenwand | 998.503 | 700 | 0.0179731 | 0.698952 | 0.0125811 | 6.91962 | 0.0126
Buitenwand | 850 | 2800 | 0.0153 | 2.38 | 0.04284 | 23.562 | 0.0504
Buitenwand | 850 | 1361 | 0.0153 | 1.15685 | 0.0208233 | 11.4528 | 0.024498
Buitenwand | 988.579 | 1361 | 0.0177944 | 1.34546 | 0.0242182 | 13.32 | 0.024498
Buitenwand | 986.777 | 700 | 0.017762 | 0.690744 | 0.0124334 | 6.83836 | 0.0126
Buitenwand | 1094.03 | 1361 | 0.0196926 | 1.48898 | 0.0268016 | 14.7409 | 0.024498
Buitenwand | 993.043 | 700 | 0.0178748 | 0.69513 | 0.0125123 | 6.88179 | 0.0126
Buitenwand | 993.043 | 1361 | 0.0178748 | 1.35153 | 0.0243276 | 13.3802 | 0.024498
Buitenwand | 990.668 | 700 | 0.017832 | 0.693468 | 0.0124824 | 6.86533 | 0.0126
Buitenwand | 990.668 | 1361 | 0.017832 | 1.3483 | 0.0242694 | 13.3482 | 0.024498
4 x Buitenwand | 892 | 2800 | 0.016056 | 2.4976 | 0.0449568 | 24.7262 | 0.0504
Buitenwand | 896 | 1361 | 0.016128 | 1.21946 | 0.0219502 | 12.0726 | 0.024498
3 x Buitenwand | 1130 | 1361 | 0.02034 | 1.53793 | 0.0276827 | 15.2255 | 0.024498
4 x Buitenwand | 1130 | 2800 | 0.02034 | 3.164 | 0.056952 | 31.3236 | 0.0504
Buitenwand | 1126 | 1361 | 0.020268 | 1.53249 | 0.0275847 | 15.1716 | 0.024498
Buitenwand | 323.972 | 1361 | 0.00583149 | 0.440926 | 0.00793666 | 4.36516 | 0.024498
Buitenwand | 1175 | 1361 | 0.02115 | 1.59918 | 0.0287851 | 15.8318 | 0.024498
Buitenwand | 1177 | 2800 | 0.021186 | 3.2956 | 0.0593208 | 32.6265 | 0.0504
Buitenwand | 948 | 2800 | 0.017064 | 2.6544 | 0.0477792 | 26.2786 | 0.0504
Buitenwand | 773.998 | 1361 | 0.013932 | 1.05341 | 0.0189614 | 10.4288 | 0.024498
Buitenwand | 773.998 | 2800 | 0.013932 | 2.1672 | 0.0390095 | 21.4552 | 0.0504
Buitenwand | 1094.55 | 1361 | 0.0197019 | 1.48969 | 0.0268143 | 14.7479 | 0.024498
Buitenwand | 954.615 | 1361 | 0.0171831 | 1.29923 | 0.0233862 | 12.8624 | 0.024498
Buitenwand | 1094.55 | 2800 | 0.0197019 | 3.06475 | 0.0551654 | 30.341 | 0.0504
Buitenwand | 954.615 | 2800 | 0.0171831 | 2.67292 | 0.0481126 | 26.4619 | 0.0504
Buitenwand | 769 | 2800 | 0.013842 | 2.1532 | 0.0387576 | 21.3167 | 0.0504
Buitenwand | 767.491 | 2800 | 0.0138148 | 2.14898 | 0.0386816 | 21.2749 | 0.0504
Buitenwand | 1068.25 | 2800 | 0.0192286 | 2.99111 | 0.05384 | 29.612 | 0.0504
2 x Buitenwand | 1010.07 | 700 | 0.0181813 | 0.70705 | 0.0127269 | 6.99979 | 0.0126
2 x Buitenwand | 1198 | 2800 | 0.021564 | 3.3544 | 0.0603792 | 33.2086 | 0.0504
2 x Buitenwand | 1196 | 2800 | 0.021528 | 3.3488 | 0.0602784 | 33.1531 | 0.0504
Buitenwand | 957.516 | 2800 | 0.0172353 | 2.68104 | 0.0482588 | 26.5423 | 0.0504
2 x Buitenwand | 1198 | 1361 | 0.021564 | 1.63048 | 0.0293486 | 16.1417 | 0.024498
2 x Buitenwand | 1196 | 1361 | 0.021528 | 1.62776 | 0.0292996 | 16.1148 | 0.024498
Buitenwand | 957.516 | 1361 | 0.0172353 | 1.30318 | 0.0234572 | 12.9015 | 0.024498
4 x Buitenwand | 999 | 1361 | 0.017982 | 1.35964 | 0.0244735 | 13.4604 | 0.024498
4 x Buitenwand | 999 | 700 | 0.017982 | 0.6993 | 0.0125874 | 6.92307 | 0.0126
Buitenwand | 1048.64 | 2630 | 0.0188756 | 2.75794 | 0.0496429 | 27.3036 | 0.04734
Buitenwand | 1038.65 | 1361 | 0.0186957 | 1.4136 | 0.0254448 | 13.9947 | 0.024498
Buitenwand | 1769 | 1361 | 0.0320039 | 2.41985 | 0.0435573 | 23.9565 | 0.024498
Buitenwand | 1216 | 1361 | 0.021726 | 1.64273 | 0.0295691 | 16.263 | 0.024498
2 x Buitenwand | 1247 | 2626.37 | 0.022446 | 3.27509 | 0.0589516 | 32.4234 | 0.0472747
Buitenwand | 1668.89 | 2630 | 0.03004 | 4.38918 | 0.0790052 | 43.4529 | 0.04734
2 x Buitenwand | 987.334 | 2800 | 0.017772 | 2.76453 | 0.0497616 | 27.3689 | 0.0504
Buitenwand | 1029.33 | 2800 | 0.018528 | 2.88213 | 0.0518784 | 28.5331 | 0.0504
Buitenwand | 989.334 | 1361 | 0.017808 | 1.34648 | 0.0242367 | 13.3302 | 0.024498
Buitenwand | 987.334 | 1361 | 0.017772 | 1.34376 | 0.0241877 | 13.3032 | 0.024498
Buitenwand | 1029.33 | 1361 | 0.018528 | 1.40092 | 0.0252166 | 13.8691 | 0.024498
4 x Buitenwand | 1036 | 2630 | 0.018648 | 2.72468 | 0.0490442 | 26.9743 | 0.04734
4 x Buitenwand | 1036 | 1361 | 0.018648 | 1.41 | 0.0253799 | 13.959 | 0.024498
Buitenwand | 1247 | 1361 | 0.022446 | 1.69717 | 0.030549 | 16.8019 | 0.024498
Buitenwand | 1224.62 | 1361 | 0.0220432 | 1.66671 | 0.0300008 | 16.5005 | 0.024498
Buitenwand | 1224.62 | 2626.37 | 0.0220432 | 3.21632 | 0.0578938 | 31.8416 | 0.0472747
5 x Buitenwand | 1196.5 | 2800 | 0.021537 | 3.35021 | 0.0603037 | 33.167 | 0.0504
Buitenwand | 984.506 | 2800 | 0.0177211 | 2.75662 | 0.0496191 | 27.2905 | 0.0504
3 x Buitenwand | 1106 | 2800 | 0.0199079 | 3.09679 | 0.0557422 | 30.6582 | 0.0504
3 x Buitenwand | 1106 | 1361 | 0.0199079 | 1.50526 | 0.0270947 | 14.9021 | 0.024498
Buitenwand | 1018.99 | 1361 | 0.0183417 | 1.38684 | 0.0249631 | 13.7297 | 0.024498
Buitenwand | 274.961 | 2800 | 0.0049493 | 0.769891 | 0.013858 | 7.62192 | 0.0504
Buitenwand | 328.972 | 2800 | 0.00592149 | 0.921121 | 0.0165802 | 9.1191 | 0.0504
Buitenwand | 274.961 | 1361 | 0.0049493 | 0.374222 | 0.00673599 | 3.7048 | 0.024498
7 x Buitenwand | 182 | 2800 | 0.003276 | 0.5096 | 0.0091728 | 5.04504 | 0.0504
Buitenwand | 183.645 | 2078.7 | 0.0033056 | 0.381742 | 0.00687136 | 3.77925 | 0.0374166
Buitenwand | 170.432 | 2078.7 | 0.00306777 | 0.354277 | 0.00637698 | 3.50734 | 0.0374166
3 x Buitenwand | 172 | 2078.7 | 0.003096 | 0.357536 | 0.00643566 | 3.53961 | 0.0374166
3 x Buitenwand | 172.06 | 2078.7 | 0.00309708 | 0.357661 | 0.0064379 | 3.54084 | 0.0374166
Buitenwand | 160 | 2800 | 0.00288 | 0.448 | 0.008064 | 4.4352 | 0.0504

# IfcWall: KZ 150 150 (2)
In: Begane grond
Type - PredefinedType: ELEMENTEDWALL
Classification: Samengestelde wand (ARCHICAD Classification); 21 Buitenwanden (NL/SfB (4 cijfers)); Material: Steen - Kalkzandsteen C
CPset_Phasing - Renovation Phase: Bestaand
AC_Pset_RenovationAndPhasing - Renovation Status: Existing
Pset_WallCommon - LoadBearing: yes; IsExternal: yes
Material Properties - Steen - Kalkzandsteen C, ThermalConductivity: 0.9; Steen - Kalkzandsteen C, SpecificHeatCapacity: 840 J/kg/K; Steen - Kalkzandsteen C, MassDensity: 1900 kg/m3; Steen - Kalkzandsteen C, Embodied Energy: 0.75 (MJ/kg); Steen - Kalkzandsteen C, Embodied Carbon: 0.1 (kgCO₂/kg); Steen - Kalkzandsteen C, Name: Steen - Kalkzandsteen C; Steen - Kalkzandsteen C, Participates in Collision Detection: yes
BaseQuantities - Length: 1800 mm; Height: 1420 mm; Width: 150 mm; GrossFootprintArea: 0.27 m2; NetFootprintArea: 0.27 m2; GrossSideArea: 2.556 m2; NetSideArea: 2.556 m2; GrossVolume: 0.3834 m3; NetVolume: 0.3834 m3
Component Quantities - Steen - Kalkzandsteen C, Mass: 728.46 kg; Steen - Kalkzandsteen C, Projected Component Area (Net): 2.556 m2; Steen - Kalkzandsteen C, Projected Component Area (Gross): 2.556 m2; Steen - Kalkzandsteen C, Component Thickness: 150 mm; Steen - Kalkzandsteen C, Rectangular Component Height: 1420 mm; Steen - Kalkzandsteen C, Rectangular Component Width: 150 mm; Steen - Kalkzandsteen C, Component Cross Section Area: 0.213 m2; Steen - Kalkzandsteen C, Component Volume (Net): 0.3834 m3; Steen - Kalkzandsteen C, Component Volume (Gross): 0.3834 m3

# IfcWall: KZ 214 214 (7)
In: Begane grond
Type - PredefinedType: ELEMENTEDWALL
Classification: Samengestelde wand (ARCHICAD Classification); 21 Buitenwanden (NL/SfB (4 cijfers)); Material: Steen - Kalkzandsteen C
CPset_Phasing - Renovation Phase: Bestaand
AC_Pset_RenovationAndPhasing - Renovation Status: Existing
Pset_WallCommon - LoadBearing: yes; IsExternal: yes
Material Properties - Steen - Kalkzandsteen C, ThermalConductivity: 0.9; Steen - Kalkzandsteen C, SpecificHeatCapacity: 840 J/kg/K; Steen - Kalkzandsteen C, MassDensity: 1900 kg/m3; Steen - Kalkzandsteen C, Embodied Energy: 0.75 (MJ/kg); Steen - Kalkzandsteen C, Embodied Carbon: 0.1 (kgCO₂/kg); Steen - Kalkzandsteen C, Name: Steen - Kalkzandsteen C; Steen - Kalkzandsteen C, Participates in Collision Detection: yes
BaseQuantities - Width: 214 mm
Component Quantities - Steen - Kalkzandsteen C, Component Thickness: 214 mm; Steen - Kalkzandsteen C, Rectangular Component Width: 214 mm
Name | Length (mm) | Height (mm) = Steen - Kalkzandsteen C, Rectangular Component Height (mm) | GrossFootprintArea (m2) = NetFootprintArea (m2) | GrossSideArea (m2) | NetSideArea (m2) = Steen - Kalkzandsteen C, Projected Component Area (Net) (m2) | GrossVolume (m3) = Steen - Kalkzandsteen C, Component Volume (Gross) (m3) | NetVolume (m3) = Steen - Kalkzandsteen C, Component Volume (Net) (m3) | Steen - Kalkzandsteen C, Mass (kg) | Steen - Kalkzandsteen C, Projected Component Area (Gross) (m2) | Steen - Kalkzandsteen C, Component Cross Section Area (m2)
KZS 214mm | 7599.99 | 3470 | 1.6478 | 26.719 | 26.719 | 5.71786 | 5.71786 | 10863.9 | 26.719 | 0.74258
KZS 214mm | 19077 | 3470 | 2.98958 | 65.8179 | 49.5811 | 14.085 | 10.6104 | 20159.7 | 65.8179 | 0.74258
KZS 214mm | 3786 | 3470 | 0.831604 | 13.4604 | 13.4604 | 2.88053 | 2.88053 | 5473 | 13.4604 | 0.74258
Binnenwand | 6060 | 1290 | 1.29684 | 7.8174 | 7.8174 | 1.67292 | 1.67292 | 3178.55 | 7.8174 | 0.27606
KZS 214mm | 6146 | 3470 | 0.763828 | 21.5664 | 15.0085 | 4.61405 | 3.21181 | 6102.44 | 21.6496 | 0.74258
KZS 214mm | 4776.98 | 3470 | 1.04517 | 16.9303 | 16.9303 | 3.62307 | 3.62307 | 6883.84 | 16.9303 | 0.74258
KZS 214mm | 6185 | 3470 | 1.32359 | 21.453 | 21.453 | 4.59094 | 4.59094 | 8722.79 | 21.453 | 0.74258

# IfcWall: Steen - Baksteen AFW 100 (50)
In: Begane grond
Type - PredefinedType: ELEMENTEDWALL
Classification: Samengestelde wand (ARCHICAD Classification); 21 Buitenwanden (NL/SfB (4 cijfers)); Material: Steen - Baksteen AFW
CPset_Phasing - Renovation Phase: Bestaand
AC_Pset_RenovationAndPhasing - Renovation Status: Existing
Pset_WallCommon - LoadBearing: yes; IsExternal: yes
Material Properties - Steen - Baksteen AFW, ThermalConductivity: 0.9; Steen - Baksteen AFW, SpecificHeatCapacity: 840 J/kg/K; Steen - Baksteen AFW, MassDensity: 1600 kg/m3; Steen - Baksteen AFW, Embodied Energy: 3 (MJ/kg); Steen - Baksteen AFW, Embodied Carbon: 0.23 (kgCO₂/kg); Steen - Baksteen AFW, Name: Steen - Baksteen AFW; Steen - Baksteen AFW, Participates in Collision Detection: yes
BaseQuantities - Width: 100 mm
Component Quantities - Steen - Baksteen AFW, Component Thickness: 100 mm; Steen - Baksteen AFW, Rectangular Component Width: 100 mm
Name | Length (mm) | Height (mm) | GrossFootprintArea (m2) = NetFootprintArea (m2) | GrossSideArea (m2) = NetSideArea (m2) | GrossVolume (m3) = NetVolume (m3) = Steen - Baksteen AFW, Component Volume (Net) (m3) | Steen - Baksteen AFW, Mass (kg) | Steen - Baksteen AFW, Projected Component Area (Net) (m2) = Steen - Baksteen AFW, Projected Component Area (Gross) (m2) | Steen - Baksteen AFW, Rectangular Component Height (mm) | Steen - Baksteen AFW, Component Cross Section Area (m2) | Steen - Baksteen AFW, Component Volume (Gross) (m3)
keermuur | 13880 | 1191 | 1.393 | 16.5906 | 1.65906 | 2654.5 | 16.5906 | 1191 | 0.1191 | 1.65906
keermuur | 22846 | 1191 | 2.2896 | 27.2692 | 2.72692 | 4363.06 | 27.2692 | 1191 | 0.1191 | 2.72692
keermuur | 170 | 1191 | 0.022 | 0.26202 | 0.026202 | 41.9232 | 0.26202 | 1191 | 0.1191 | 0.026202
Buitenwand | 210 | 2715 | 0.021 | 0.57015 | 0.057015 | 91.224 | 0.57015 | 2715 | 0.2715 | 0.057015
Buitenwand | 526 | 2870 | 0.0576 | 1.65312 | 0.165312 | 264.499 | 1.65312 | 2870 | 0.287 | 0.165312
keermuur | 19900 | 1191 | 1.99 | 23.7009 | 2.37009 | 3792.14 | 23.7009 | 1191 | 0.1191 | 2.37009
keermuur | 13034 | 1191 | 1.2984 | 15.4639 | 1.54639 | 2474.22 | 15.4639 | 1191 | 0.1191 | 1.54639
2 x Buitenwand | 210 | 2870 | 0.021 | 0.6027 | 0.06027 | 96.432 | 0.6027 | 2870 | 0.287 | 0.06027
Buitenwand | 577.003 | 2870 | 0.0517003 | 1.5125 | 0.14838 | 237.408 | 1.656 | 2870 | 0.287 | 0.1656
2 x Buitenwand | 436 | 2700 | 0.0436 | 1.1772 | 0.11772 | 188.352 | 1.1772 | 2700 | 0.27 | 0.11772
Buitenwand | 576 | 2870 | 0.0576 | 1.65312 | 0.165312 | 264.499 | 1.65312 | 2870 | 0.287 | 0.165312
Buitenwand | 236 | 2870 | 0.0186 | 0.53382 | 0.053382 | 85.4112 | 0.53382 | 2870 | 0.287 | 0.053382
4 x keermuur | 280 | 2073.79 | 0.038 | 0.788039 | 0.0788039 | 126.086 | 0.788039 | 2075 | 0.2075 | 0.0788039
5 x keermuur | 1150 | 2073.79 | 0.115 | 2.38486 | 0.238486 | 381.577 | 2.38486 | 2075 | 0.2075 | 0.238486
8 x keermuur | 280 | 2073.79 | 0.028 | 0.580661 | 0.0580661 | 92.9057 | 0.580661 | 2075 | 0.2075 | 0.0580661
2 x keermuur | 1150 | 2073.79 | 0.105 | 2.05182 | 0.205182 | 328.291 | 2.05182 | 2075 | 0.2075 | 0.205182
3 x keermuur | 330 | 2073.79 | 0.038 | 0.788039 | 0.0788039 | 126.086 | 0.788039 | 2075 | 0.2075 | 0.0788039
3 x keermuur | 1100 | 2073.79 | 0.115 | 2.38486 | 0.238486 | 381.577 | 2.38486 | 2075 | 0.2075 | 0.238486
5 x keermuur | 1150 | 2073.79 | 0.105 | 2.17748 | 0.217748 | 348.396 | 2.17748 | 2075 | 0.2075 | 0.217748
keermuur | 15860.8 | 1191 | 1.58108 | 18.8307 | 1.88307 | 3012.91 | 18.8307 | 1191 | 0.1191 | 1.88307
keermuur | 170 | 1191 | 0.012 | 0.14292 | 0.014292 | 22.8672 | 0.14292 | 1191 | 0.1191 | 0.014292
keermuur | 280 | 2073.79 | 0.038 | 0.549839 | 0.0549839 | 87.9743 | 0.549839 | 2075 | 0.2075 | 0.0549839
keermuur | 1150 | 2073.79 | 0.105 | 2.11465 | 0.217121 | 347.393 | 2.17748 | 2075 | 0.2075 | 0.217121
keermuur | 6220 | 1191 | 0.647 | 7.70577 | 0.770577 | 1232.92 | 7.70577 | 1191 | 0.1191 | 0.770577
keermuur | 2941.84 | 1191 | 0.289184 | 3.44418 | 0.344418 | 551.069 | 3.44418 | 1191 | 0.1191 | 0.344418

# IfcWall: Steen - Betonblok 100 (32)
In: Begane grond
Type - PredefinedType: ELEMENTEDWALL
Classification: Samengestelde wand (ARCHICAD Classification); 21 Buitenwanden (NL/SfB (4 cijfers)); Material: Steen - Betonblok
CPset_Phasing - Renovation Phase: Bestaand
AC_Pset_RenovationAndPhasing - Renovation Status: Existing
Pset_WallCommon - LoadBearing: yes; IsExternal: yes
Material Properties - Steen - Betonblok, ThermalConductivity: 0.4; Steen - Betonblok, SpecificHeatCapacity: 840 J/kg/K; Steen - Betonblok, MassDensity: 800 kg/m3; Steen - Betonblok, Embodied Energy: 0.59 (MJ/kg); Steen - Betonblok, Embodied Carbon: 0.059 (kgCO₂/kg); Steen - Betonblok, Name: Steen - Betonblok; Steen - Betonblok, Participates in Collision Detection: yes
BaseQuantities - Width: 100 mm
Component Quantities - Steen - Betonblok, Component Thickness: 100 mm; Steen - Betonblok, Rectangular Component Width: 100 mm
Name | Length (mm) | Height (mm) = Steen - Betonblok, Rectangular Component Height (mm) | GrossFootprintArea (m2) = NetFootprintArea (m2) | GrossSideArea (m2) = NetSideArea (m2) | GrossVolume (m3) = NetVolume (m3) = Steen - Betonblok, Component Volume (Net) (m3) = Steen - Betonblok, Component Volume (Gross) (m3) | Steen - Betonblok, Mass (kg) | Steen - Betonblok, Projected Component Area (Net) (m2) = Steen - Betonblok, Projected Component Area (Gross) (m2) | Steen - Betonblok, Component Cross Section Area (m2)
6 x keermuur | 380 | 214 | 0.038 | 0.08132 | 0.008132 | 6.5056 | 0.08132 | 0.0214
keermuur | 1250 | 184 | 0.0199946 | 0.1196 | 0.003679 | 2.9432 | 0.2116 | 0.0184
keermuur | 380 | 214 | 0.038 | 0.06292 | 0.006292 | 5.0336 | 0.06292 | 0.0214
3 x keermuur | 1250 | 214 | 0.105 | 0.223029 | 0.0223029 | 17.8423 | 0.223961 | 0.0214
keermuur | 1250 | 214 | 0.125 | 0.265807 | 0.0265806 | 21.2645 | 0.26674 | 0.0214
2 x keermuur | 380 | 214 | 0.028 | 0.0598576 | 0.00599095 | 4.79276 | 0.05992 | 0.0214
keermuur | 1250 | 214 | 0.0189253 | 0.115083 | 0.00403704 | 3.22963 | 0.198085 | 0.0214
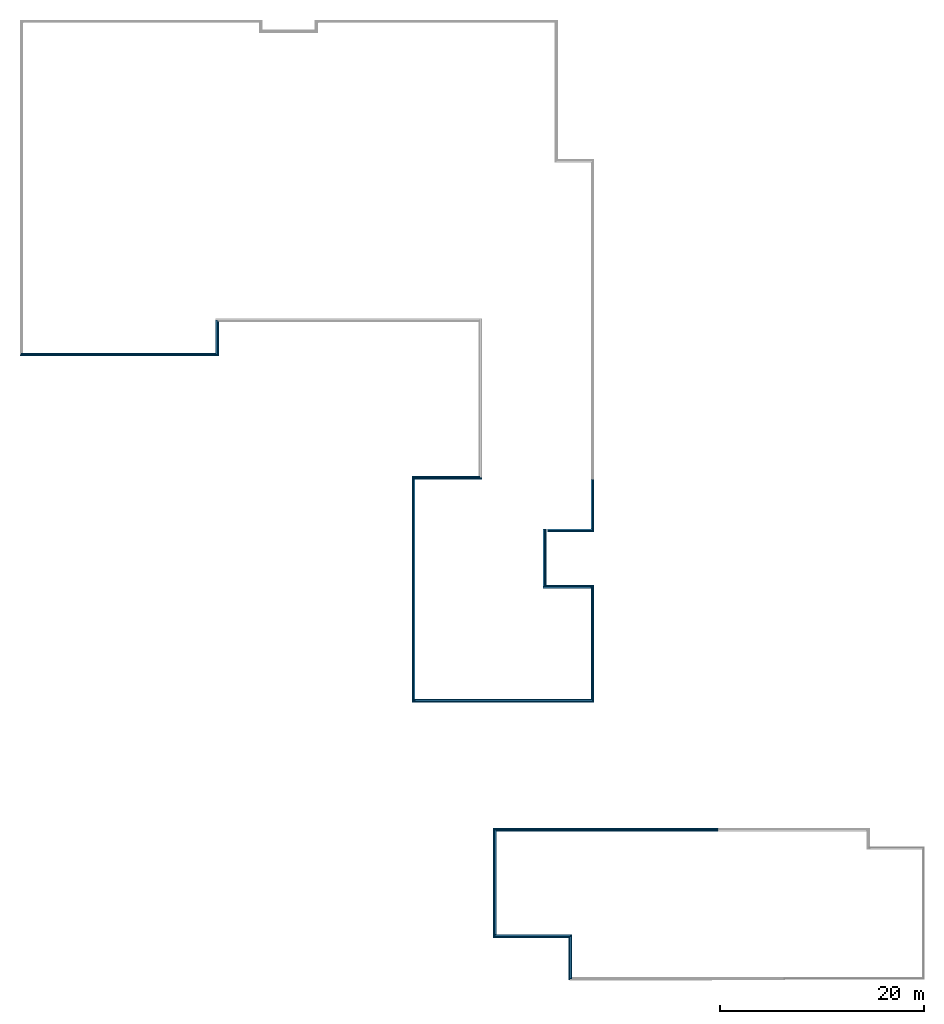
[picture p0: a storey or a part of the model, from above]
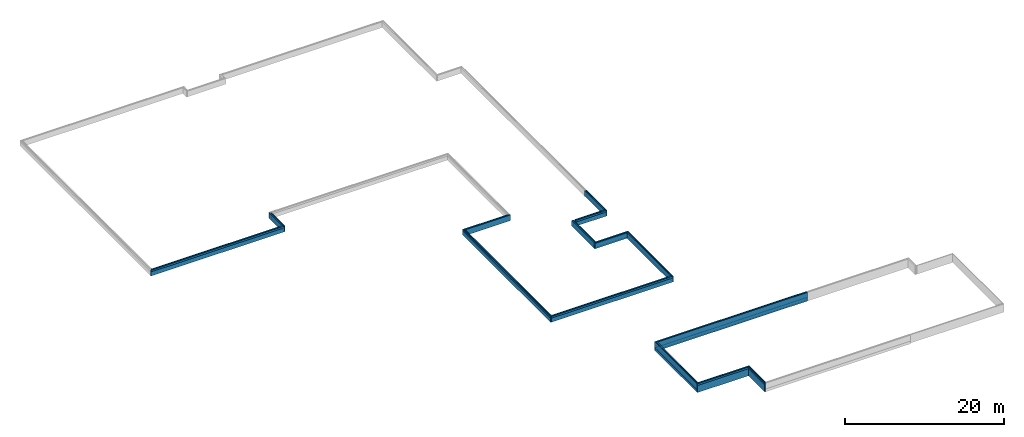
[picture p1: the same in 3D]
Properties of the parts of a building model (IFC2X3), part 19 of 19

# IfcWall: Steen - Betonblok 100 (32)
Name | Length (mm) | Height (mm) = Steen - Betonblok, Rectangular Component Height (mm) | GrossFootprintArea (m2) = NetFootprintArea (m2) | GrossSideArea (m2) = NetSideArea (m2) | GrossVolume (m3) = NetVolume (m3) = Steen - Betonblok, Component Volume (Net) (m3) = Steen - Betonblok, Component Volume (Gross) (m3) | Steen - Betonblok, Mass (kg) | Steen - Betonblok, Projected Component Area (Net) (m2) = Steen - Betonblok, Projected Component Area (Gross) (m2) | Steen - Betonblok, Component Cross Section Area (m2)
keermuur | 380 | 214 | 0.018 | 0.03852 | 0.003852 | 3.0816 | 0.03852 | 0.0214
keermuur | 1250 | 214 | 0.115 | 0.244407 | 0.0244406 | 19.5525 | 0.24534 | 0.0214
keermuur | 1250 | 214 | 0.00892537 | 0.0936826 | 0.00189705 | 1.51764 | 0.176685 | 0.0214
2 x keermuur | 1250 | 214 | 0.0199946 | 0.1391 | 0.00427884 | 3.42307 | 0.2461 | 0.0214
5 x keermuur | 380 | 214 | 0.028 | 0.05992 | 0.005992 | 4.7936 | 0.05992 | 0.0214
keermuur | 1250 | 214 | 0.015 | 0.0321 | 0.00321 | 2.568 | 0.0321 | 0.0214
keermuur | 1250 | 214 | 0.105 | 0.223122 | 0.0223122 | 17.8498 | 0.224054 | 0.0214
2 x keermuur | 1250 | 214 | 0.115 | 0.244429 | 0.0244429 | 19.5543 | 0.245361 | 0.0214
keermuur | 1250 | 214 | 0.00999457 | 0.1177 | 0.00213884 | 1.71107 | 0.2247 | 0.0214
keermuur | 380 | 214 | 0.0375009 | 0.080252 | 0.0080252 | 6.42016 | 0.080252 | 0.0214
keermuur | 1250 | 214 | 0.00942607 | 0.104391 | 0.00200589 | 1.60471 | 0.199146 | 0.0214

# IfcWall: Steen - Kalkzandsteen C 10 (4)
In: Begane grond
Type - PredefinedType: ELEMENTEDWALL
Classification: Samengestelde wand (ARCHICAD Classification); Material: Steen - Kalkzandsteen C
AC_Pset_RenovationAndPhasing - Renovation Status: Existing
Pset_WallCommon - LoadBearing: no; IsExternal: yes
Material Properties - Steen - Kalkzandsteen C, ThermalConductivity: 0.9; Steen - Kalkzandsteen C, SpecificHeatCapacity: 840 J/kg/K; Steen - Kalkzandsteen C, MassDensity: 1900 kg/m3; Steen - Kalkzandsteen C, Embodied Energy: 0.75 (MJ/kg); Steen - Kalkzandsteen C, Embodied Carbon: 0.1 (kgCO₂/kg); Steen - Kalkzandsteen C, Name: Steen - Kalkzandsteen C; Steen - Kalkzandsteen C, Participates in Collision Detection: yes
BaseQuantities - Length: 695.001 mm; Height: 1050 mm; Width: 10 mm; GrossFootprintArea: 0.00695001 m2; NetFootprintArea: 0.00695001 m2; GrossSideArea: 0.729751 m2; NetSideArea: 0.729751 m2; GrossVolume: 0.00729751 m3; NetVolume: 0.00729751 m3
Component Quantities - Steen - Kalkzandsteen C, Mass: 13.8653 kg; Steen - Kalkzandsteen C, Projected Component Area (Net): 0.729751 m2; Steen - Kalkzandsteen C, Projected Component Area (Gross): 0.729751 m2; Steen - Kalkzandsteen C, Component Thickness: 10 mm; Steen - Kalkzandsteen C, Rectangular Component Height: 1050 mm; Steen - Kalkzandsteen C, Rectangular Component Width: 10 mm; Steen - Kalkzandsteen C, Component Cross Section Area: 0.0105 m2; Steen - Kalkzandsteen C, Component Volume (Net): 0.00729751 m3; Steen - Kalkzandsteen C, Component Volume (Gross): 0.00729751 m3

# IfcWall: _Dichte arcering 18 (2)
In: Begane grond
Type - PredefinedType: ELEMENTEDWALL
Classification: Samengestelde wand (ARCHICAD Classification); 21 Buitenwanden (NL/SfB (4 cijfers)); Material: _Dichte arcering
CPset_Phasing - Renovation Phase: Bestaand
AC_Pset_RenovationAndPhasing - Renovation Status: Existing
Pset_WallCommon - LoadBearing: yes; IsExternal: yes
Material Properties - _Dichte arcering, ThermalConductivity: 0.5; _Dichte arcering, SpecificHeatCapacity: 840 J/kg/K; _Dichte arcering, MassDensity: 1300 kg/m3; _Dichte arcering, Embodied Energy: 0.75 (MJ/kg); _Dichte arcering, Embodied Carbon: 0.1 (kgCO₂/kg); _Dichte arcering, Name: _Dichte arcering; _Dichte arcering, Participates in Collision Detection: yes
BaseQuantities - Length: 1800 mm; Height: 1368.48 mm; Width: 18 mm; GrossFootprintArea: 0.0324 m2; NetFootprintArea: 0.0324 m2; GrossSideArea: 2.46327 m2; NetSideArea: 2.46327 m2; GrossVolume: 0.0443389 m3; NetVolume: 0.0443389 m3
Component Quantities - _Dichte arcering, Mass: 57.6405 kg; _Dichte arcering, Projected Component Area (Net): 2.46327 m2; _Dichte arcering, Projected Component Area (Gross): 2.46327 m2; _Dichte arcering, Component Thickness: 18 mm; _Dichte arcering, Rectangular Component Height: 1368.48 mm; _Dichte arcering, Rectangular Component Width: 18 mm; _Dichte arcering, Component Cross Section Area: 0.0246327 m2; _Dichte arcering, Component Volume (Net): 0.0443389 m3; _Dichte arcering, Component Volume (Gross): 0.0443389 m3

# IfcWall: _Dichte arcering 5 (17)
In: Begane grond
Type - PredefinedType: ELEMENTEDWALL
Classification: Samengestelde wand (ARCHICAD Classification); 21 Buitenwanden (NL/SfB (4 cijfers)); Material: _Dichte arcering
CPset_Phasing - Renovation Phase: Bestaand
AC_Pset_RenovationAndPhasing - Renovation Status: Existing
Pset_WallCommon - LoadBearing: yes; IsExternal: yes
Material Properties - _Dichte arcering, ThermalConductivity: 0.5; _Dichte arcering, SpecificHeatCapacity: 840 J/kg/K; _Dichte arcering, MassDensity: 1300 kg/m3; _Dichte arcering, Embodied Energy: 0.75 (MJ/kg); _Dichte arcering, Embodied Carbon: 0.1 (kgCO₂/kg); _Dichte arcering, Name: _Dichte arcering; _Dichte arcering, Participates in Collision Detection: yes
BaseQuantities - Width: 5 mm
Component Quantities - _Dichte arcering, Component Thickness: 5 mm; _Dichte arcering, Rectangular Component Width: 5 mm
Name | Length (mm) | Height (mm) = _Dichte arcering, Rectangular Component Height (mm) | GrossFootprintArea (m2) = NetFootprintArea (m2) | GrossSideArea (m2) = _Dichte arcering, Projected Component Area (Gross) (m2) | NetSideArea (m2) = _Dichte arcering, Projected Component Area (Net) (m2) | GrossVolume (m3) = _Dichte arcering, Component Volume (Gross) (m3) | NetVolume (m3) = _Dichte arcering, Component Volume (Net) (m3) | _Dichte arcering, Mass (kg) | _Dichte arcering, Component Cross Section Area (m2)
Accentkleur | 1699.99 | 2800 | 0.00849994 | 4.75997 | 4.75997 | 0.0237998 | 0.0237998 | 30.9398 | 0.014
Accentkleur | 1100 | 2800 | 0.00550001 | 3.08 | 3.08 | 0.0154 | 0.0154 | 20.02 | 0.014
Accentkleur | 4187.5 | 3090 | 0.0209375 | 12.9394 | 12.9394 | 0.0646968 | 0.0646968 | 84.1059 | 0.01545
2 x Accentkleur | 1980 | 2800 | 0.00473 | 5.544 | 3.09652 | 0.02772 | 0.0154826 | 20.1274 | 0.014
Accentkleur | 3302 | 424.512 | 0.01651 | 1.40174 | 1.40174 | 0.0070087 | 0.0070087 | 9.11131 | 0.00212256
Accentkleur | 4436 | 425.12 | 0.02218 | 1.88583 | 1.88583 | 0.00942916 | 0.00942916 | 12.2579 | 0.0021256
Accentkleur | 2589.5 | 2800 | 0.0129475 | 7.25059 | 7.25059 | 0.036253 | 0.036253 | 47.1288 | 0.014
Accentkleur | 2589.5 | 2800 | 0.0129475 | 7.25059 | 7.25059 | 0.036253 | 0.036253 | 47.1289 | 0.014
Accentkleur | 1752 | 2800 | 0.00876001 | 4.90561 | 4.90561 | 0.024528 | 0.024528 | 31.8864 | 0.014
Accentkleur | 8131.98 | 2800 | 0.0406599 | 22.7695 | 22.7695 | 0.113848 | 0.113848 | 148.002 | 0.014
Accentkleur | 8131.98 | 2800 | 0.0308316 | 22.7695 | 18.0973 | 0.113848 | 0.0904863 | 117.632 | 0.014
Accentkleur | 6046 | 3090 | 0.03023 | 18.6821 | 18.6821 | 0.0934107 | 0.0934107 | 121.434 | 0.01545
Accentkleur | 4893.23 | 3090 | 0.0244662 | 15.1201 | 15.1201 | 0.0756004 | 0.0756004 | 98.2806 | 0.01545
Accentkleur | 4425.01 | 3090 | 0.0221251 | 13.6733 | 13.6733 | 0.0683664 | 0.0683664 | 88.8764 | 0.01545
Accentkleur | 9794.33 | 3100 | 0.0399716 | 30.3624 | 26.0838 | 0.151812 | 0.130419 | 169.545 | 0.0155
Accentkleur | 8650.01 | 3100 | 0.0290799 | 26.815 | 20.0786 | 0.134075 | 0.100393 | 130.511 | 0.0155

# IfcWindow: R Uitstulping 25 (33)
In: Begane grond
Type - ParameterTakesPrecedence: no; Sizeable: no
OverallHeight: 900 mm; OverallWidth: 600 mm; Classification: Raam (ARCHICAD Classification); 31 Buitenwandopeningen (NL/SfB (4 cijfers)); Material: AFW - Wandtegelwerk
Material - Glas: Glas - algemeen
CPset_Phasing - Renovation Phase: Bestaand
AC_Pset_RenovationAndPhasing - Renovation Status: Existing
Pset_WindowCommon - IsExternal: yes
Material Properties - AFW - Wandtegelwerk, ThermalConductivity: 0.14; AFW - Wandtegelwerk, SpecificHeatCapacity: 1880 J/kg/K; AFW - Wandtegelwerk, MassDensity: 600 kg/m3; AFW - Wandtegelwerk, Embodied Energy: 14.5 (MJ/kg); AFW - Wandtegelwerk, Embodied Carbon: 0.52 (kgCO₂/kg); AFW - Wandtegelwerk, Name: AFW - Wandtegelwerk; AFW - Wandtegelwerk, Participates in Collision Detection: yes
BaseQuantities - GrossArea: 0 m2; Height: 0 mm; Width: 0 mm; Perimeter: 0 mm; Area: 0 m2; Volume: 0.0027 m3; Depth: 5 mm; NetVolume: 0.0027 m3
Component Quantities - AFW - Wandtegelwerk, Mass: 1.62 kg; AFW - Wandtegelwerk, Component Volume (Net): 0.0027 m3; AFW - Wandtegelwerk, Component Volume (Gross): 0.0027 m3

# IfcWindow: R1 25 (6)
In: Begane grond
Type - OperationType: SINGLE_PANEL; ParameterTakesPrecedence: no; Sizeable: no
Type - Window Lining Properties - LiningDepth: 114 mm; LiningThickness: 67 mm
Type - Window Panel Properties - Panel 1 - OperationType: FIXEDCASEMENT; PanelPosition: MIDDLE
Classification: 32 Binnenwandopeningen (NL/SfB (4 cijfers)); Raam (ARCHICAD Classification)
Pset_WindowCommon - IsExternal: no
Material - Afwerking dagkant binnen: arcering (01); Afwerking dagkant buiten: arcering (01); Draaiend deel: arcering (02); Frame: arcering (01); Onderdorpel: %; Rollaag / latei: arcering (01); Spouwlat: Naaldhout (01); Vensterbank: arcering (01); Ventilatierooster: %; Zonwering - behuizing: arcering (01); Zonwering - isolatie: Isolatie ruit; Glas: Glas - algemeen exterieur
CPset_Phasing - Renovation Phase: Bestaand
AC_Pset_RenovationAndPhasing - Renovation Status: Existing
Name | OverallHeight (mm) = Height (mm) | OverallWidth (mm) = Width (mm) | AcousticRating | GlazingAreaFraction | FireResistanceRating | GrossArea (m2) = Area (m2) | Perimeter (mm) | Volume (m3) = NetVolume (m3) = Component, Component Volume (Net) (m3) = Component, Component Volume (Gross) (m3) | Depth (mm)
2 x b0.03B | 1177 | 1700 | --- | 1.63334 | 30 minuten brandwerend | 2.0009 | 5754 | 0.0419021 | 214
2 x b0.01 | 1177 | 673.96 | --- | 0.563178 | --- | 0.793251 | 3701.92 | 0.0262283 | 100
2 x b0.05g | 2400 | 350 | glasbladen cf. advies Curvers | 0.489456 | --- | 0.84 | 5500 | 0.039962 | 255

# IfcWindow: R1 25, b0.04
In: Begane grond
Type - OperationType: SINGLE_PANEL; ParameterTakesPrecedence: no; Sizeable: no
Type - Window Lining Properties - LiningDepth: 114 mm; LiningThickness: 67 mm
Type - Window Panel Properties - Panel 1 - OperationType: SIDEHUNGRIGHTHAND; PanelPosition: MIDDLE; FrameDepth: 54 mm; FrameThickness: 67 mm
OverallHeight: 1577 mm; OverallWidth: 975 mm; Classification: 32 Binnenwandopeningen (NL/SfB (4 cijfers)); Raam (ARCHICAD Classification)
Pset_WindowCommon - AcousticRating: ---; GlazingAreaFraction: 0.995163; IsExternal: no
Material - Afwerking dagkant binnen: arcering (01); Afwerking dagkant buiten: arcering (01); Draaiend deel: arcering (02); Frame: arcering (01); Onderdorpel: %; Rollaag / latei: arcering (01); Spouwlat: Naaldhout (01); Vensterbank: arcering (01); Ventilatierooster: %; Zonwering - behuizing: arcering (01); Zonwering - isolatie: Isolatie ruit; Glas: Glas - algemeen exterieur
Pset_FireRatingProperties - FireResistanceRating: ---
CPset_Phasing - Renovation Phase: Bestaand
AC_Pset_RenovationAndPhasing - Renovation Status: Existing
BaseQuantities - GrossArea: 1.53481 m2; Height: 1577 mm; Width: 973.248 mm; Perimeter: 5100.5 mm; Area: 1.53481 m2; Volume: 0.048731 m3; Depth: 100 mm; NetVolume: 0.048731 m3
Component Quantities - Component, Component Volume (Net): 0.048731 m3; Component, Component Volume (Gross): 0.048731 m3

# IfcWindow: R1 25 (2)
In: Begane grond
Type - OperationType: SINGLE_PANEL; ParameterTakesPrecedence: no; Sizeable: no
Type - Window Lining Properties - LiningDepth: 67 mm; LiningThickness: 67 mm
Type - Window Panel Properties - Panel 1 - OperationType: FIXEDCASEMENT; PanelPosition: MIDDLE
OverallHeight: 2665 mm; OverallWidth: 1500 mm; Classification: 32 Binnenwandopeningen (NL/SfB (4 cijfers)); Raam (ARCHICAD Classification)
Pset_WindowCommon - GlazingAreaFraction: 3.45735; IsExternal: no
Material - Afwerking dagkant binnen: arcering (01); Afwerking dagkant buiten: arcering (01); Draaiend deel: arcering (02); Frame: arcering (01); Onderdorpel: %; Rollaag / latei: arcering (01); Spouwlat: Naaldhout (01); Vensterbank: arcering (01); Ventilatierooster: %; Zonwering - behuizing: arcering (01); Zonwering - isolatie: Isolatie ruit; Glas: Glas - algemeen exterieur
CPset_Phasing - Renovation Phase: Bestaand
AC_Pset_RenovationAndPhasing - Renovation Status: Existing
BaseQuantities - GrossArea: 3.9975 m2; Height: 2665 mm; Width: 1500 mm; Perimeter: 8330 mm; Area: 3.9975 m2; Volume: 0.0361903 m3; Depth: 205 mm; NetVolume: 0.0361903 m3
Component Quantities - Component, Component Volume (Net): 0.0361903 m3; Component, Component Volume (Gross): 0.0361903 m3

# IfcWindow: R1 25, Merk AI
In: Begane grond
Type - OperationType: SINGLE_PANEL; ParameterTakesPrecedence: no; Sizeable: no
Type - Window Lining Properties - LiningDepth: 67 mm; LiningThickness: 76 mm
Type - Window Panel Properties - Panel 1 - OperationType: FIXEDCASEMENT; PanelPosition: MIDDLE
OverallHeight: 2665 mm; OverallWidth: 899.971 mm; Classification: 32 Binnenwandopeningen (NL/SfB (4 cijfers)); Raam (ARCHICAD Classification)
Pset_WindowCommon - GlazingAreaFraction: 1.87965; IsExternal: no
Material - Afwerking dagkant binnen: arcering (01); Afwerking dagkant buiten: arcering (01); Draaiend deel: arcering (02); Frame: arcering (01); Onderdorpel: %; Rollaag / latei: arcering (01); Spouwlat: Naaldhout (01); Vensterbank: arcering (01); Ventilatierooster: %; Zonwering - behuizing: arcering (01); Zonwering - isolatie: Isolatie ruit; Glas: Glas - algemeen exterieur
CPset_Phasing - Renovation Phase: Bestaand
AC_Pset_RenovationAndPhasing - Renovation Status: Existing
BaseQuantities - GrossArea: 2.37502 m2; Height: 2665 mm; Width: 891.188 mm; Perimeter: 7112.38 mm; Area: 2.37502 m2; Volume: 0.0347577 m3; Depth: 205 mm; NetVolume: 0.0347577 m3
Component Quantities - Component, Component Volume (Net): 0.0347577 m3; Component, Component Volume (Gross): 0.0347577 m3

# IfcWindow: R2 bl ol 25 (23)
In: Begane grond
Type - OperationType: USERDEFINED; ParameterTakesPrecedence: no; Sizeable: no
OverallWidth: 2010 mm; Classification: Raam (ARCHICAD Classification); 31 Buitenwandopeningen (NL/SfB (4 cijfers))
Pset_WindowCommon - IsExternal: yes
Material - Afwerking dagkant binnen: arcering (01); Afwerking dagkant buiten: arcering (01); Draaiend deel: arcering (02); Frame: arcering (01); Onderdorpel: %; Rollaag / latei: arcering (01); Spouwlat: Naaldhout (01); Vensterbank: arcering (01); Ventilatierooster: %; Zonwering - behuizing: arcering (01); Zonwering - isolatie: Isolatie ruit; Glas: Glas - algemeen exterieur
CPset_Phasing - Renovation Phase: Bestaand
AC_Pset_RenovationAndPhasing - Renovation Status: Existing
BaseQuantities - Width: 2010 mm
Name | OverallHeight (mm) | GlazingAreaFraction | FireResistanceRating | GrossArea (m2) = Area (m2) | Height (mm) | Perimeter (mm) | Volume (m3) = NetVolume (m3) = Component, Component Volume (Net) (m3) = Component, Component Volume (Gross) (m3) | Depth (mm)
5 x Merk AA | 2815 | 3.96368 | -- | 5.5878 | 2780 | 9580 | 0.143672 | 436
7 x Merk AA-sp | 2815 | 3.96368 | -- | 5.5878 | 2780 | 9580 | 0.143672 | 436
3 x Merk AB | 2065 | 3.0455 |  | 4.0803 | 2030 | 8080 | 0.0778911 | 460
Merk AC | 2065 | 2.77913 |  | 4.0803 | 2030 | 8080 | 0.0983694 | 312
Merk AC-sp | 2065 | 2.77913 |  | 4.0803 | 2030 | 8080 | 0.0983534 | 396
3 x Merk AA | 2815 | 3.96368 | -- | 5.5878 | 2780 | 9580 | 0.143672 | 500
2 x Merk AA-sp | 2815 | 3.96368 | -- | 5.5878 | 2780 | 9580 | 0.143672 | 500
Merk AB-sp | 2065 | 3.0455 |  | 4.0803 | 2030 | 8080 | 0.0778911 | 460

# IfcWindow: Rmeerkeuze 25 (4)
In: Begane grond
Type - OperationType: TRIPLE_PANEL_LEFT; ParameterTakesPrecedence: no; Sizeable: no
Type - Window Lining Properties - LiningDepth: 67 mm; LiningThickness: 76 mm; TransomThickness: 76 mm; MullionThickness: 76 mm; FirstTransomOffset: 0.281426; FirstMullionOffset: 0.650944
Type - Window Panel Properties - Panel 1 - OperationType: TILTANDTURNLEFTHAND; PanelPosition: TOP; FrameDepth: 54 mm; FrameThickness: 67 mm
Type - Window Panel Properties - Panel 2 - OperationType: FIXEDCASEMENT; PanelPosition: BOTTOM
Type - Window Panel Properties - Panel 3 - OperationType: FIXEDCASEMENT; PanelPosition: LEFT
OverallHeight: 2665 mm; OverallWidth: 1976.67 mm; Classification: 32 Binnenwandopeningen (NL/SfB (4 cijfers)); Raam (ARCHICAD Classification)
Pset_WindowCommon - GlazingAreaFraction: 4.09141; IsExternal: no
Material - Afwerking dagkant binnen: arcering (01); Afwerking dagkant buiten: arcering (01); Draaiend deel: arcering (02); Frame: arcering (01); Onderdorpel: %; Rollaag / latei: arcering (01); Spouwlat: Naaldhout (01); Vensterbank: arcering (01); Ventilatierooster: %; Zonwering - behuizing: arcering (01); Zonwering - isolatie: Isolatie ruit; Glas: Glas - algemeen exterieur
CPset_Phasing - Renovation Phase: Bestaand
AC_Pset_RenovationAndPhasing - Renovation Status: Existing
BaseQuantities - GrossArea: 5.26782 m2; Height: 2665 mm; Width: 1976.67 mm; Perimeter: 9283.33 mm; Area: 5.26782 m2; Volume: 0.075868 m3; Depth: 205 mm; NetVolume: 0.075868 m3
Component Quantities - Component, Component Volume (Net): 0.075868 m3; Component, Component Volume (Gross): 0.075868 m3

# IfcWindow: Rmeerkeuze 25 (2)
In: Begane grond
Type - OperationType: TRIPLE_PANEL_LEFT; ParameterTakesPrecedence: no; Sizeable: no
Type - Window Lining Properties - LiningDepth: 67 mm; LiningThickness: 76 mm; TransomThickness: 76 mm; MullionThickness: 76 mm; FirstTransomOffset: 0.281426; FirstMullionOffset: 0.651814
Type - Window Panel Properties - Panel 1 - OperationType: TILTANDTURNLEFTHAND; PanelPosition: TOP; FrameDepth: 54 mm; FrameThickness: 67 mm
Type - Window Panel Properties - Panel 2 - OperationType: FIXEDCASEMENT; PanelPosition: BOTTOM
Type - Window Panel Properties - Panel 3 - OperationType: FIXEDCASEMENT; PanelPosition: LEFT
OverallHeight: 2665 mm; OverallWidth: 1981.7 mm; Classification: 32 Binnenwandopeningen (NL/SfB (4 cijfers)); Raam (ARCHICAD Classification)
Pset_WindowCommon - GlazingAreaFraction: 4.10405; IsExternal: no
Material - Afwerking dagkant binnen: arcering (01); Afwerking dagkant buiten: arcering (01); Draaiend deel: arcering (02); Frame: arcering (01); Onderdorpel: %; Rollaag / latei: arcering (01); Spouwlat: Naaldhout (01); Vensterbank: arcering (01); Ventilatierooster: %; Zonwering - behuizing: arcering (01); Zonwering - isolatie: Isolatie ruit; Glas: Glas - algemeen exterieur
CPset_Phasing - Renovation Phase: Bestaand
AC_Pset_RenovationAndPhasing - Renovation Status: Existing
BaseQuantities - GrossArea: 5.28123 m2; Height: 2665 mm; Width: 1981.7 mm; Perimeter: 9293.4 mm; Area: 5.28123 m2; Volume: 0.0759196 m3; Depth: 205 mm; NetVolume: 0.0759196 m3
Component Quantities - Component, Component Volume (Net): 0.0759196 m3; Component, Component Volume (Gross): 0.0759196 m3

# IfcWindow: Rmeerkeuze 25 (2)
In: Begane grond
Type - OperationType: TRIPLE_PANEL_RIGHT; ParameterTakesPrecedence: no; Sizeable: no
Type - Window Lining Properties - LiningDepth: 67 mm; LiningThickness: 76 mm; TransomThickness: 76 mm; MullionThickness: 76 mm; FirstTransomOffset: 0.281426; FirstMullionOffset: 0.261116
Type - Window Panel Properties - Panel 1 - OperationType: TILTANDTURNRIGHTHAND; PanelPosition: TOP; FrameDepth: 54 mm; FrameThickness: 67 mm
Type - Window Panel Properties - Panel 2 - OperationType: FIXEDCASEMENT; PanelPosition: BOTTOM
Type - Window Panel Properties - Panel 3 - OperationType: FIXEDCASEMENT; PanelPosition: RIGHT
OverallHeight: 2665 mm; OverallWidth: 2642.5 mm; Classification: 32 Binnenwandopeningen (NL/SfB (4 cijfers)); Raam (ARCHICAD Classification)
Pset_WindowCommon - GlazingAreaFraction: 5.76464; IsExternal: no
Material - Afwerking dagkant binnen: arcering (01); Afwerking dagkant buiten: arcering (01); Draaiend deel: arcering (02); Frame: arcering (01); Onderdorpel: %; Rollaag / latei: arcering (01); Spouwlat: Naaldhout (01); Vensterbank: arcering (01); Ventilatierooster: %; Zonwering - behuizing: arcering (01); Zonwering - isolatie: Isolatie ruit; Glas: Glas - algemeen exterieur
CPset_Phasing - Renovation Phase: Bestaand
AC_Pset_RenovationAndPhasing - Renovation Status: Existing
BaseQuantities - GrossArea: 7.04226 m2; Height: 2665 mm; Width: 2642.5 mm; Perimeter: 10615 mm; Area: 7.04226 m2; Volume: 0.0826492 m3; Depth: 205 mm; NetVolume: 0.0826492 m3
Component Quantities - Component, Component Volume (Net): 0.0826492 m3; Component, Component Volume (Gross): 0.0826492 m3

# IfcWindow: Rmeerkeuze 25 (2)
In: Begane grond
Type - OperationType: TRIPLE_PANEL_RIGHT; ParameterTakesPrecedence: no; Sizeable: no
Type - Window Lining Properties - LiningDepth: 67 mm; LiningThickness: 76 mm; TransomThickness: 76 mm; MullionThickness: 76 mm; FirstTransomOffset: 0.281426; FirstMullionOffset: 0.284536
Type - Window Panel Properties - Panel 1 - OperationType: TILTANDTURNRIGHTHAND; PanelPosition: TOP; FrameDepth: 54 mm; FrameThickness: 67 mm
Type - Window Panel Properties - Panel 2 - OperationType: FIXEDCASEMENT; PanelPosition: BOTTOM
Type - Window Panel Properties - Panel 3 - OperationType: FIXEDCASEMENT; PanelPosition: RIGHT
OverallHeight: 2665 mm; OverallWidth: 2425 mm; Classification: 32 Binnenwandopeningen (NL/SfB (4 cijfers)); Raam (ARCHICAD Classification)
Pset_WindowCommon - GlazingAreaFraction: 5.21806; IsExternal: no
Material - Afwerking dagkant binnen: arcering (01); Afwerking dagkant buiten: arcering (01); Draaiend deel: arcering (02); Frame: arcering (01); Onderdorpel: %; Rollaag / latei: arcering (01); Spouwlat: Naaldhout (01); Vensterbank: arcering (01); Ventilatierooster: %; Zonwering - behuizing: arcering (01); Zonwering - isolatie: Isolatie ruit; Glas: Glas - algemeen exterieur
CPset_Phasing - Renovation Phase: Bestaand
AC_Pset_RenovationAndPhasing - Renovation Status: Existing
BaseQuantities - GrossArea: 6.46263 m2; Height: 2665 mm; Width: 2425 mm; Perimeter: 10180 mm; Area: 6.46263 m2; Volume: 0.0804342 m3; Depth: 205 mm; NetVolume: 0.0804342 m3
Component Quantities - Component, Component Volume (Net): 0.0804342 m3; Component, Component Volume (Gross): 0.0804342 m3

# IfcWindow: Rnx horizontaal 25, b0.02g
In: Begane grond
Type - OperationType: TRIPLE_PANEL_VERTICAL; ParameterTakesPrecedence: no; Sizeable: no
Type - Window Lining Properties - LiningDepth: 114 mm; LiningThickness: 67 mm; MullionThickness: 67 mm; FirstMullionOffset: 0.334497; SecondMullionOffset: 0.665503
Type - Window Panel Properties - Panel 1 - OperationType: FIXEDCASEMENT; PanelPosition: LEFT
Type - Window Panel Properties - Panel 2 - OperationType: FIXEDCASEMENT; PanelPosition: MIDDLE
Type - Window Panel Properties - Panel 3 - OperationType: FIXEDCASEMENT; PanelPosition: RIGHT
OverallHeight: 1157 mm; OverallWidth: 6300 mm; Classification: Raam (ARCHICAD Classification); 31 Buitenwandopeningen (NL/SfB (4 cijfers))
Pset_WindowCommon - AcousticRating: ---; GlazingAreaFraction: 6.12368; IsExternal: yes
Material - Afwerking dagkant binnen: arcering (01); Afwerking dagkant buiten: arcering (01); Draaiend deel: arcering (02); Frame: arcering (01); Onderdorpel: %; Rollaag / latei: arcering (01); Spouwlat: Naaldhout (01); Vensterbank: arcering (01); Ventilatierooster: %; Zonwering - behuizing: arcering (01); Zonwering - isolatie: Isolatie ruit; Glas: Glas - algemeen exterieur
Pset_FireRatingProperties - FireResistanceRating: ---
CPset_Phasing - Renovation Phase: Bestaand
AC_Pset_RenovationAndPhasing - Renovation Status: Existing
BaseQuantities - GrossArea: 7.2891 m2; Height: 1157 mm; Width: 6300 mm; Perimeter: 14914 mm; Area: 7.2891 m2; Volume: 0.132858 m3; Depth: 200 mm; NetVolume: 0.132858 m3
Component Quantities - Component, Component Volume (Net): 0.132858 m3; Component, Component Volume (Gross): 0.132858 m3
